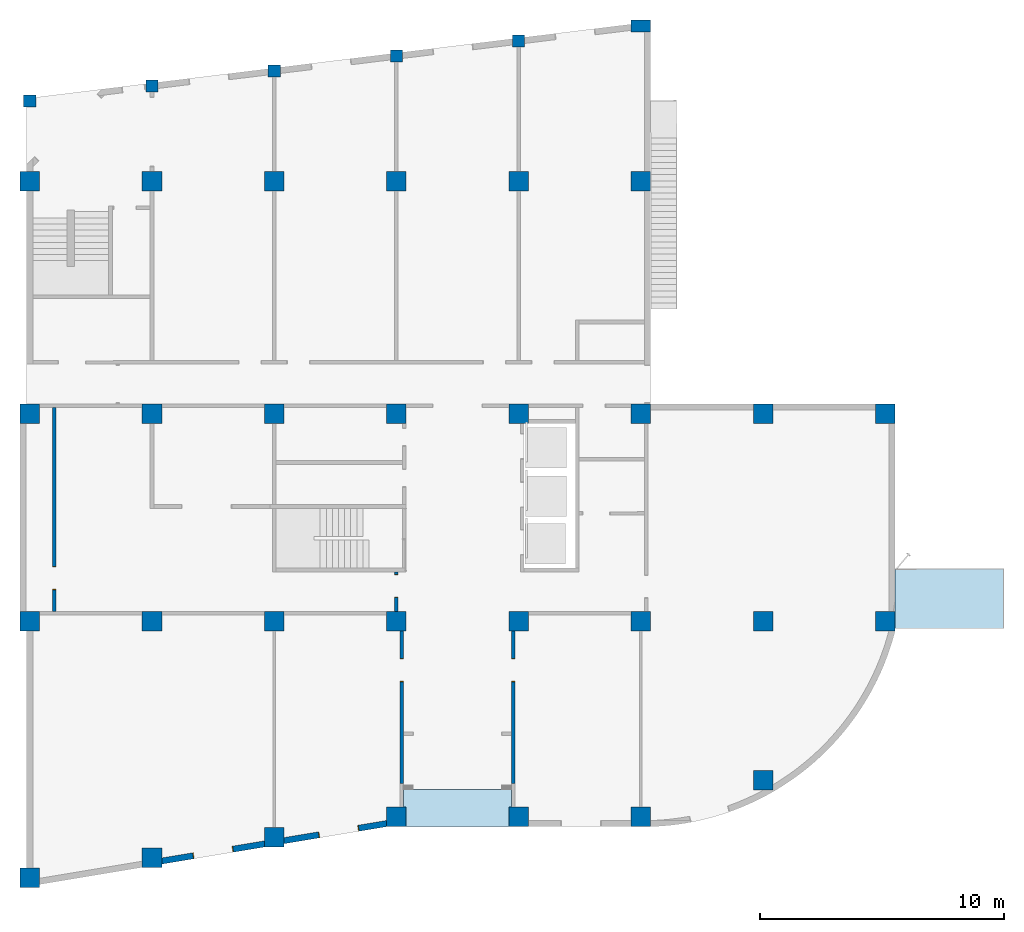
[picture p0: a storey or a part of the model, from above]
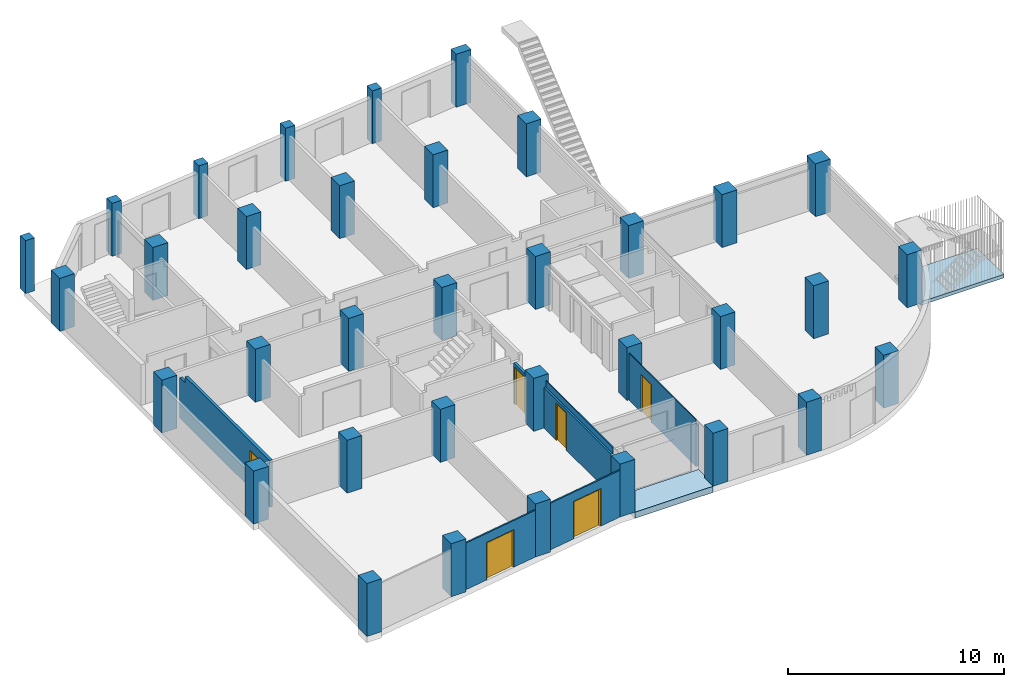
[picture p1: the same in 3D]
Properties of the parts of a building model (IFC2X3), part 1 of 10

# File
Description: ViewDefinition [CoordinationView_V2.0, SurfaceGeometryAddOnView, QuantityTakeOffAddOnView, SpaceBoundary2ndLevelAddOnView], Option [Drawing Scale: 100.000000], Option [Elements to export: Visible elements (on all stories)], Option [Partial Structure Display: Entire Model], Option [IFC Domain: All], Option [Structural Function: All Elements], Option [Convert Grid elements: On], Option [Convert IFC Annotations and ARCHICAD 2D elements: Off], Option [Convert 2D symbols of Doors and Windows: Off], Option [Export geometries that Participates in Collision Detection only: On], Option [Split complex elements: Off], Option [Material Preservation: Explode where necessary], Option [IFC Site Location: At Project Origin], Option [Curtain Wall export mode: Single Element], Option [Railing export mode: Single Element], Option [Stair export mode: Single Element], Option [Properties To Export: All properties], Option [Space containment: On], Option [IFC Domain For Space Containment: Custom], Option [Bounding Box: Off], Option [Geometry to type objects: Off], Option [Element Properties: All], Option [Building Material Properties: Off], Option [Element Parameters: All], Option [Component Parameters: Off], Option [IFC Base Quantities: On], Option [Door Window Parameters: On], Option [IFC Space boundaries: On], Option [ARCHICAD Zone Categories as IFC Space classification data: On], Option [Element Classifications: On]
File name: C:\Users\meije\OneDrive - Graphisoft SE\Desktop\From Home\Solibri Samples\Escape Route\Escape Route.ifc
Time: 2020-05-21T14:10:56
Author: Architect
Organization: Building Designer Office
Written by: The EXPRESS Data Manager Version 5.02.0100.09 : 26 Sep 2013
Made in: IFC file generated by GRAPHISOFT ARCHICAD 23.0.0 JPN FULL Windows version (IFC add-on version: 3003 JPN FULL).
Authorization: The authorising person

# IfcSite, サイト
RefLatitude: 35, 42, 0, 0; RefLongitude: 139, 46, 0, 0; RefElevation: 0 mm
BaseQuantities - GrossPerimeter: 0 mm; GrossArea: 0 m2

# IfcBuilding, 建築
BaseQuantities - GrossFloorArea: 8628.15 m2

# IfcBuildingStorey (10)
In: 建築
Name | Elevation (mm) | NetHeight (mm) = GrossHeight (mm) = Height (mm) | GrossFloorArea (m2)
1FL | 0 | 3000 | 956.464
2FL | 3000 | 3000 | 971.87
3FL | 6000 | 3000 | 957.103
4FL | 9000 | 3000 | 957.119
5FL | 12000 | 3000 | 957.119
6FL | 15000 | 3000 | 957.119
7FL | 18000 | 3000 | 957.119
8FL | 21000 | 3000 | 957.119
9FL | 24000 | 3000 | 957.119
RFL | 27000 | 700 | 0

# IfcSpace: その他-1 (10)
InteriorOrExteriorSpace: INTERNAL; Classification: スペース (ARCHICAD 分類); その他-1 その他-1
Pset_SpaceCommon - Category: その他-1
ArchiCADProperties - レイヤー: ゾーン; ライブラリ部品名: ゾーン_仕上用; 関連ゾーン番号: ＜ゾーン番号＞; 要素タイプ: ゾーン; 材質 (全て): ゾーン - 05; 表面塗りつぶし: 背景; リノベーションフィルタで表示: 全ての関連フィルタ; リノベーションステータス: 既存; 材質: ゾーン - 05; 同一材質: yes; ゾーン番号: ＜ゾーン番号＞; ゾーンカテゴリ: 0; ゾーンカテゴリコード: その他-1; ARCHICAD 分類 - v 2.0: スペース
AC_Pset_ゾーン_仕上用 - マーカーテキスト1サイズ(デフォルト): 2; マーカーテキスト1スタイル(デフォルト): 0; マーカーテキスト1 整列(デフォルト): 1; マーカーテキスト1 改行幅(デフォルト): 0; マーカーテキスト1 文字幅(デフォルト): 1; マーカーテキスト1 テキスト文字間隔(デフォルト): 1; テキストフォント1: Meiryo Japanese; ゾーン番号 (ROOM_NUMBER): ＜ゾーン番号＞; 全コーナー数: 4; 凹型コーナー数: 0; 抽出壁面積: 0; 抽出カーテンウォール面積: 0; 抽出柱面積: 0; 抽出塗りつぶし面積: 0; 抽出床面積: 0; 抽出総面積: 0; ゾーン面積係数: 1; 上部屋根表面積: 0; 下部屋根表面積: 0; 上部スラブ表面積: 0; 下部スラブ表面積: 0; 下部梁表面積: 0; 下部梁表面: 0; 上部壁インセット表面積: 0; 壁インセット背面: 0; 側面壁インセット表面積: 0; 詳細: 1; 固定スタンプ表示 (stChangebyScale): 1：50まで; 固定スタンプ表示 (iChangebyScale): 1; ゾーンスタンプタイプ: 1; 面積値表示: 1; 一行で表示するスケール: 400; 室名: yes; ソーン名文字揃え: 2; 枠線 (bFrameRoomName): no; ゾーン番号 (bZoneNum): no; ゾーン番号タイプ: 1; IDを表示...: 1; 枠線 (bFrameZoneNum): no; 床タイプ: no; 床タイプ名称: ＜フロア タイプ＞; 枠線 (bFrameFloor): no; 面積表示: yes; 平米丸め（小数点）: ２桁; 平米単位表示: 1; 坪表示: no; 坪小数点以下表示: なし; 坪単位表示: 1; 畳表示: no; 帖、Ｊ表示: 帖; 畳単位表示: 1; 帖数小数点: ２桁; 畳係数: 1.62; 枠線 (bFrameArea): no; 外周: no; 枠線 (bFramePeri): no; CH=表示: no; CH=: 2400; 枠線 (bFrameCeil): no; FL又はSL表示: no; FL/SL値: ＋50; FL/SL文字: SL; 枠線 (bFrameFloorlabel): no; スラブ厚: 160; コンクリート天端レベル: ±0; 排煙記号: no; 排煙種類: 未定; 枠線 (bFrameSmokesign): no; 内装制限記号: no; 内装制限種類: 未定; 枠線 (bFrameInterior): no; カテゴリとプロパティを表示: no; 枠線 (bFrameTnC): yes; 枠幅設定: 余白あり; 枠幅桁数: 14; 表示精度: 1; 坪、畳は丸めた平米値で計算する: yes; ------------------: -------------; 角度: 0 deg; 表面塗りつぶし: no; 背景塗つぶしタイプ: 50 %; 表面塗りつぶしペン背景: 透過; 空調タイプ: 日当り空調室; 編集する床の下地を選択: 1; 床＿仕上: 磁器タイル; 床＿下地: RC; 床＿下地2: RC; 床＿下地3: RC; 床＿下地4: RC; 床＿下地5: RC; 巾木: ソフト巾木; 壁仕上げ: 磁器タイル; 編集する壁の下地を選択: 4; 壁＿下地: RC; 壁＿下地2: RC; 壁＿下地3: RC; 壁＿下地4: RC; 壁＿下地5: RC; 天井＿仕上: クロス貼; 編集する天井の下地を選択: 1; 天井＿下地: 軽鉄野縁; 天井＿下地2: 軽鉄野縁; 天井＿下地3: 軽鉄野縁; 天井＿下地4: 軽鉄野縁; 天井＿下地5: 軽鉄野縁; 廻り縁: 廻縁 塩ビ; 面積区分: 1; 面積対象: 1; 換気タイプ: タイプ1; 給気量（A）m3/h: 300; 排気量（B）m3/h: 300; カテゴリ名称: その他-1; 天井高テキスト: 3,000; 床＿下地テキスト: RC/RC/RC/RC/RC; 壁＿下地テキスト: RC/RC/RC/RC/RC; 天井＿下地テキスト: 軽鉄野縁/軽鉄野縁/軽鉄野縁/軽鉄野縁/軽鉄野縁; 巾木高さ値（mm）: 75; パラメータを選択: 1; データを表示: 1; 1. 列 パラメータ名を次のように表示: 1; 2. 列 パラメータ名を次のように表示: 1; 3. 列 パラメータ名を次のように表示: 1; 4. 列 パラメータ名を次のように表示: 1; 5. 列 パラメータ名を次のように表示: 1; 6. 列 パラメータ名を次のように表示: 1; 7. 列 パラメータ名を次のように表示: 1; 8. 列 パラメータ名を次のように表示: 1; 9. 列 パラメータ名を次のように表示: 1; 10. 列 パラメータ名を次のように表示: 1; 11. 列 パラメータ名を次のように表示: 1; 12. 列 パラメータ名を次のように表示: 1; 13. 列 パラメータ名を次のように表示: 1; 14. 列 パラメータ名を次のように表示: 1; 15. 列 パラメータ名を次のように表示: 1; 16. 列 パラメータ名を次のように表示: 1; 17. 列 パラメータ名を次のように表示: 1; 18. 列 パラメータ名を次のように表示: 1; 19. 列 パラメータ名を次のように表示: 1; 20. 列 パラメータ名を次のように表示: 1
室情報 - 利用者数: 0; 一人あたりの必要面積: 0 m2
AC_Pset_RenovationAndPhasing - Renovation Status: Existing
BaseQuantities - Height: 3000 mm; FinishCeilingHeight: 3000 mm; FinishFloorHeight: 0 mm; ClearHeight: 3000 mm
ArchiCADQuantities - 高さ: 3000 mm; リンク/配置フロアまでの高度: 0 mm; 下部オフセット: 0 mm; 上部オフセット: 0 mm; 平面図穴外周: 0 mm; 上端高度から配置フロア: 3000 mm; 下端高度から配置フロア: 0 mm; 基準レベル: 0 mm; 柱数: 0; ランプ数: 0; オブジェクト数: 0; フロア厚さ: 0 mm; 面積縮小: 1 m2; 抜き取られる柱面積: 0 m2; 抜き取られる塗りつぶし面積: 0 m2; 抜き取られる底面積: 0 m2; 抜き取られる壁面積: 0 m2; 全てのへこみ角数: 0; 角数: 4; 抜き取られる総面積: 0 m2; 壁のインセット背面表面積: 0 m2; 壁インセット側面表面積: 0 m2; 壁インセット上部表面積: 0 m2
AC_Equantity_ゾーン_仕上用 - 穴外周: 0 mm; フロアレベル: 0 mm; サブフロア厚さ: 0 mm; 高さ: 3000 mm; 巾木高さ: 75 mm; 腰高: 1000 mm; 平均天井高: 3000 mm
Name | In | LongName = 関連ゾーン名 = ゾーン名 = ゾーン名 (ROOM_NAME) = ゾーン名 (stZoneName) | 要素ID = 親ID | ホットリンクおよび要素ID | ロック状態 | ホームフロア名 | ホームフロア数 | 絶対上部リンクフロア | 相対上部リンクフロア | 上部リンクフロア | 縮小された面積 = AC_Pset_ゾーン_仕上用, 測定正味面積 = 縮小面積 = 計算面積 (ROOM_CALC_AREA) = 上部表面積 = 下部材質面積 = NetFloorArea (m2) = SpaceNetFloorAreaBOMA (m2) = SpaceUsableFloorAreaBOMA (m2) = NetCeilingArea (m2) = 計算した面積 (m2) = ArchiCADQuantities, 測定正味面積 (m2) | AC_Pset_ゾーン_仕上用, 測定面積 = GrossFloorArea (m2) = GrossCeilingArea (m2) = 面積 (m2) = ArchiCADQuantities, 測定面積 (m2) | 外壁表面積 | AC_Pset_ゾーン_仕上用, ドア表面積 = ArchiCADQuantities, ドア表面積 (m2) | AC_Pset_ゾーン_仕上用, 窓表面積 = ArchiCADQuantities, 窓表面積 (m2) | 体積 = 気積 | 境界表面積 | 計算面積 (stAreaDisp) = 面積値 | 換気回数 | 坪 | 畳 | 面積テキスト | 坪テキスト | 畳テキスト | GrossWallArea (m2) | NetWallArea (m2) = 壁表面積 (m2) | GrossPerimeter (mm) = ゾーン総外周 (mm) = 外周 (mm) | NetPerimeter (mm) = ゾーン正味外周 (mm) = 正味外周 (mm) | GrossVolume (m3) | NetVolume (m3) = 正味体積 (m3) | GLからの高度 (mm) = 高度 1 (mm) = 高度 2 (mm) = 海抜までの高度 (mm) = 下端高度から第1基準レベル (mm) = 下端高度から基準レベル (mm) = 下端高度から海抜 (mm) = 下端高度から第2基準レベル (mm) | 上端高度から第1基準レベル (mm) = 上端高度から基準レベル (mm) = 上端高度から海抜 (mm) = 上端高度から第2基準レベル (mm) | 梁数 | ドア数 | 窓数 | 壁部品数 | ドア幅 (mm) = ドア組み合わせ幅 (mm) | 窓幅 (mm) = 窓組み合わせ幅 (mm) | 壁外周 (mm) = 外壁長さ (mm) | 居室に必要な採光面積 (m2) = 病院福祉施設等に必要な採光面積 (m2) | 教育施設に必要な採光面積 (m2) | その他に必要な採光面積 (m2) | 自然排煙必要面積(ゾーン) (m2) | 必要換気量（ゾーン） (m2) | ホットリンク マスタID
＜ゾーン番号＞ | 1FL | 階段室 | Z6 | Z6 | no | 1FL | 1 | 2FL | 配置フロア + 1 | 配置フロア + 1 (2FL) | 12.6788 | 13.845 | 36.371 | 2.52 | 0 | 38.0363 | 45.75 | 13.84 | 7.88721 | 4 | 8.54 | 13.84 ㎡ | 4 坪 | 8.54 帖 | 38.891 | 36.371 | 15850 | 15250 | 41.535 | 38.0363 | 0 | 3000 | 2 | 1 | 0 | 4 | 1200 | 0 | 15250 | 1.97786 | 2.769 | 1.3845 | 0.2769 | 0.69225
＜ゾーン番号＞ | 2FL | 階段室 | Z6 | Z6 | no | 2FL | 2 | 3FL | 配置フロア + 1 | 配置フロア + 1 (3FL) | 12.6788 | 13.845 | 36.6117 | 2.31 | 0 | 38.0363 | 45.75 | 13.84 | 7.88721 | 4 | 8.54 | 13.84 ㎡ | 4 坪 | 8.54 帖 | 38.9217 | 36.6117 | 15850 | 15250 | 41.535 | 38.0362 | 3000 | 6000 | 4 | 1 | 0 | 4 | 1100 | 0 | 15250 | 1.97786 | 2.769 | 1.3845 | 0.2769 | 0.69225
＜ゾーン番号＞ | 2FL | 吹き抜け | Z9 | Z9 | no | 2FL | 2 | 3FL | 配置フロア + 1 | 配置フロア + 1 (3FL) | 25.74 | 26.9588 | 33.809 | 0 | 8.496 | 77.22 | 61.5 | 26.95 | 3.885 | 8 | 16.63 | 26.95 ㎡ | 8 坪 | 16.63 帖 | 42.305 | 33.809 | 20950 | 20500 | 80.8763 | 77.22 | 3000 | 6000 | 0 | 0 | 1 | 3 | 0 | 3540 | 16100 | 3.85125 | 5.39175 | 2.69588 | 0.539175 | 1.34794
＜ゾーン番号＞ | 3FL | 階段室 | Z6 | Z6 | no | 3FL | 3 | 4FL | 配置フロア + 1 | 配置フロア + 1 (4FL) | 12.6788 | 13.845 | 40.6192 | 2.31 | 0 | 38.0363 | 45.75 | 13.84 | 7.88721 | 4 | 8.54 | 13.84 ㎡ | 4 坪 | 8.54 帖 | 38.9217 | 36.6117 | 15850 | 15250 | 41.535 | 38.0362 | 6000 | 9000 | 2 | 1 | 0 | 4 | 1100 | 0 | 15250 | 1.97786 | 2.769 | 1.3845 | 0.2769 | 0.69225
＜ゾーン番号＞ | 4FL | 階段室 | Z6 | 4FLZ6 | yes | 4FL | 4 | リンクなし | リンクなし | リンクなし | 12.6788 | 13.845 | 40.6192 | 2.31 | 0 | 38.0363 | 45.75 | 13.84 | 7.88721 | 4 | 8.54 | 13.84 ㎡ | 4 坪 | 8.54 帖 | 38.9217 | 36.6117 | 15850 | 15250 | 41.535 | 38.0362 | 9000 | 12000 | 2 | 1 | 0 | 4 | 1100 | 0 | 15250 | 1.97786 | 2.769 | 1.3845 | 0.2769 | 0.69225 | 4FL
＜ゾーン番号＞ | 5FL | 階段室 | Z6 | 5FLZ6 | yes | 5FL | 5 | リンクなし | リンクなし | リンクなし | 12.6788 | 13.845 | 40.6192 | 2.31 | 0 | 38.0363 | 45.75 | 13.84 | 7.88721 | 4 | 8.54 | 13.84 ㎡ | 4 坪 | 8.54 帖 | 38.9217 | 36.6117 | 15850 | 15250 | 41.535 | 38.0362 | 12000 | 15000 | 2 | 1 | 0 | 4 | 1100 | 0 | 15250 | 1.97786 | 2.769 | 1.3845 | 0.2769 | 0.69225 | 5FL
＜ゾーン番号＞ | 6FL | 階段室 | Z6 | 6FLZ6 | yes | 6FL | 6 | リンクなし | リンクなし | リンクなし | 12.6788 | 13.845 | 40.6192 | 2.31 | 0 | 38.0363 | 45.75 | 13.84 | 7.88721 | 4 | 8.54 | 13.84 ㎡ | 4 坪 | 8.54 帖 | 38.9217 | 36.6117 | 15850 | 15250 | 41.535 | 38.0362 | 15000 | 18000 | 2 | 1 | 0 | 4 | 1100 | 0 | 15250 | 1.97786 | 2.769 | 1.3845 | 0.2769 | 0.69225 | 6FL
＜ゾーン番号＞ | 7FL | 階段室 | Z6 | 7FLZ6 | yes | 7FL | 7 | リンクなし | リンクなし | リンクなし | 12.6788 | 13.845 | 40.6192 | 2.31 | 0 | 38.0363 | 45.75 | 13.84 | 7.88721 | 4 | 8.54 | 13.84 ㎡ | 4 坪 | 8.54 帖 | 38.9217 | 36.6117 | 15850 | 15250 | 41.535 | 38.0362 | 18000 | 21000 | 2 | 1 | 0 | 4 | 1100 | 0 | 15250 | 1.97786 | 2.769 | 1.3845 | 0.2769 | 0.69225 | 7FL
＜ゾーン番号＞ | 8FL | 階段室 | Z6 | 8FLZ6 | yes | 8FL | 8 | リンクなし | リンクなし | リンクなし | 12.6788 | 13.845 | 40.6192 | 2.31 | 0 | 38.0363 | 45.75 | 13.84 | 7.88721 | 4 | 8.54 | 13.84 ㎡ | 4 坪 | 8.54 帖 | 38.9217 | 36.6117 | 15850 | 15250 | 41.535 | 38.0362 | 21000 | 24000 | 2 | 1 | 0 | 4 | 1100 | 0 | 15250 | 1.97786 | 2.769 | 1.3845 | 0.2769 | 0.69225 | 8FL
＜ゾーン番号＞ | 9FL | 階段室 | Z6 | 9FLZ6 | yes | 9FL | 9 | リンクなし | リンクなし | リンクなし | 12.6788 | 13.845 | 40.6192 | 2.31 | 0 | 38.0363 | 45.75 | 13.84 | 7.88721 | 4 | 8.54 | 13.84 ㎡ | 4 坪 | 8.54 帖 | 38.9217 | 36.6117 | 15850 | 15250 | 41.535 | 38.0362 | 24000 | 27000 | 2 | 1 | 0 | 4 | 1100 | 0 | 15250 | 1.97786 | 2.769 | 1.3845 | 0.2769 | 0.69225 | 9FL

# IfcSpace: その他-2 (31)
InteriorOrExteriorSpace: INTERNAL; Classification: スペース (ARCHICAD 分類); その他-2 その他-2
Pset_SpaceCommon - Category: その他-2
ArchiCADProperties - レイヤー: ゾーン; ライブラリ部品名: ゾーン_仕上用; 関連ゾーン番号: ＜ゾーン番号＞; 要素タイプ: ゾーン; 材質 (全て): ゾーン - 05; 表面塗りつぶし: 背景; リノベーションフィルタで表示: 全ての関連フィルタ; リノベーションステータス: 既存; 材質: ゾーン - 05; 同一材質: yes; ゾーン番号: ＜ゾーン番号＞; ゾーンカテゴリ: 0; ゾーンカテゴリコード: その他-2; ARCHICAD 分類 - v 2.0: スペース
AC_Pset_ゾーン_仕上用 - マーカーテキスト1サイズ(デフォルト): 2; マーカーテキスト1スタイル(デフォルト): 0; マーカーテキスト1 整列(デフォルト): 1; マーカーテキスト1 改行幅(デフォルト): 0; マーカーテキスト1 文字幅(デフォルト): 1; マーカーテキスト1 テキスト文字間隔(デフォルト): 1; テキストフォント1: Meiryo Japanese; ゾーン番号 (ROOM_NUMBER): ＜ゾーン番号＞; 窓表面積: 0; 抽出壁面積: 0; 抽出カーテンウォール面積: 0; 抽出柱面積: 0; 抽出塗りつぶし面積: 0; 抽出床面積: 0; 抽出総面積: 0; ゾーン面積係数: 1; 上部屋根表面積: 0; 下部屋根表面積: 0; 上部スラブ表面積: 0; 下部スラブ表面積: 0; 下部梁表面積: 0; 下部梁表面: 0; 上部壁インセット表面積: 0; 壁インセット背面: 0; 側面壁インセット表面積: 0; 詳細: 1; 固定スタンプ表示 (stChangebyScale): 1：50まで; 固定スタンプ表示 (iChangebyScale): 1; ゾーンスタンプタイプ: 1; 面積値表示: 1; 一行で表示するスケール: 400; 室名: yes; ソーン名文字揃え: 2; 枠線 (bFrameRoomName): no; ゾーン番号 (bZoneNum): no; ゾーン番号タイプ: 1; IDを表示...: 1; 枠線 (bFrameZoneNum): no; 床タイプ: no; 床タイプ名称: ＜フロア タイプ＞; 枠線 (bFrameFloor): no; 面積表示: yes; 平米丸め（小数点）: ２桁; 平米単位表示: 1; 坪表示: no; 坪小数点以下表示: なし; 坪単位表示: 1; 畳表示: no; 帖、Ｊ表示: 帖; 畳単位表示: 1; 帖数小数点: ２桁; 畳係数: 1.62; 枠線 (bFrameArea): no; 外周: no; 枠線 (bFramePeri): no; CH=表示: no; CH=: 2400; 枠線 (bFrameCeil): no; FL又はSL表示: no; FL/SL値: ＋50; FL/SL文字: SL; 枠線 (bFrameFloorlabel): no; スラブ厚: 160; コンクリート天端レベル: ±0; 排煙記号: no; 排煙種類: 未定; 枠線 (bFrameSmokesign): no; 内装制限記号: no; 内装制限種類: 未定; 枠線 (bFrameInterior): no; カテゴリとプロパティを表示: no; 枠線 (bFrameTnC): yes; 枠幅設定: 余白あり; 枠幅桁数: 14; 表示精度: 1; 坪、畳は丸めた平米値で計算する: yes; ------------------: -------------; 角度: 0 deg; 表面塗りつぶし: no; 背景塗つぶしタイプ: 50 %; 表面塗りつぶしペン背景: 透過; 空調タイプ: 日当り空調室; 編集する床の下地を選択: 1; 床＿仕上: 磁器タイル; 床＿下地: RC; 床＿下地2: RC; 床＿下地3: RC; 床＿下地4: RC; 床＿下地5: RC; 巾木: ソフト巾木; 壁仕上げ: 磁器タイル; 編集する壁の下地を選択: 4; 壁＿下地: RC; 壁＿下地2: RC; 壁＿下地3: RC; 壁＿下地4: RC; 壁＿下地5: RC; 天井＿仕上: クロス貼; 編集する天井の下地を選択: 1; 天井＿下地: 軽鉄野縁; 天井＿下地2: 軽鉄野縁; 天井＿下地3: 軽鉄野縁; 天井＿下地4: 軽鉄野縁; 天井＿下地5: 軽鉄野縁; 廻り縁: 廻縁 塩ビ; 面積区分: 1; 面積対象: 1; 換気タイプ: タイプ1; 給気量（A）m3/h: 300; 排気量（B）m3/h: 300; 天井高テキスト: 3,000; 床＿下地テキスト: RC/RC/RC/RC/RC; 壁＿下地テキスト: RC/RC/RC/RC/RC; 天井＿下地テキスト: 軽鉄野縁/軽鉄野縁/軽鉄野縁/軽鉄野縁/軽鉄野縁; 巾木高さ値（mm）: 75; パラメータを選択: 1; データを表示: 1; 1. 列 パラメータ名を次のように表示: 1; 2. 列 パラメータ名を次のように表示: 1; 3. 列 パラメータ名を次のように表示: 1; 4. 列 パラメータ名を次のように表示: 1; 5. 列 パラメータ名を次のように表示: 1; 6. 列 パラメータ名を次のように表示: 1; 7. 列 パラメータ名を次のように表示: 1; 8. 列 パラメータ名を次のように表示: 1; 9. 列 パラメータ名を次のように表示: 1; 10. 列 パラメータ名を次のように表示: 1; 11. 列 パラメータ名を次のように表示: 1; 12. 列 パラメータ名を次のように表示: 1; 13. 列 パラメータ名を次のように表示: 1; 14. 列 パラメータ名を次のように表示: 1; 15. 列 パラメータ名を次のように表示: 1; 16. 列 パラメータ名を次のように表示: 1; 17. 列 パラメータ名を次のように表示: 1; 18. 列 パラメータ名を次のように表示: 1; 19. 列 パラメータ名を次のように表示: 1; 20. 列 パラメータ名を次のように表示: 1
室情報 - 利用者数: 0; 一人あたりの必要面積: 0 m2
AC_Pset_RenovationAndPhasing - Renovation Status: Existing
BaseQuantities - Height: 3000 mm; FinishCeilingHeight: 3000 mm; FinishFloorHeight: 0 mm; ClearHeight: 3000 mm
ArchiCADQuantities - 高さ: 3000 mm; リンク/配置フロアまでの高度: 0 mm; 下部オフセット: 0 mm; 上部オフセット: 0 mm; 平面図穴外周: 0 mm; 上端高度から配置フロア: 3000 mm; 下端高度から配置フロア: 0 mm; 基準レベル: 0 mm; ランプ数: 0; 窓数: 0; 窓表面積: 0 m2; 窓幅: 0 mm; フロア厚さ: 0 mm; 面積縮小: 1 m2; 抜き取られる柱面積: 0 m2; 抜き取られる塗りつぶし面積: 0 m2; 抜き取られる底面積: 0 m2; 抜き取られる壁面積: 0 m2; 抜き取られる総面積: 0 m2; 壁のインセット背面表面積: 0 m2; 壁インセット側面表面積: 0 m2; 壁インセット上部表面積: 0 m2
AC_Equantity_ゾーン_仕上用 - 穴外周: 0 mm; 窓組み合わせ幅: 0 mm; フロアレベル: 0 mm; サブフロア厚さ: 0 mm; 高さ: 3000 mm; 巾木高さ: 75 mm; 腰高: 1000 mm; 平均天井高: 3000 mm
Name | In | LongName = 関連ゾーン名 = ゾーン名 = ゾーン名 (ROOM_NAME) = ゾーン名 (stZoneName) | 要素ID = 親ID | ホットリンクおよび要素ID | ロック状態 | ホームフロア名 | ホームフロア数 | 絶対上部リンクフロア | 相対上部リンクフロア | 上部リンクフロア | 縮小された面積 = AC_Pset_ゾーン_仕上用, 測定正味面積 = 縮小面積 = 計算面積 (ROOM_CALC_AREA) = 上部表面積 = 下部材質面積 = NetFloorArea (m2) = SpaceNetFloorAreaBOMA (m2) = SpaceUsableFloorAreaBOMA (m2) = NetCeilingArea (m2) = 計算した面積 (m2) = ArchiCADQuantities, 測定正味面積 (m2) | AC_Pset_ゾーン_仕上用, 測定面積 = GrossFloorArea (m2) = GrossCeilingArea (m2) = 面積 (m2) = ArchiCADQuantities, 測定面積 (m2) | 全コーナー数 = 角数 | 凹型コーナー数 = 全てのへこみ角数 | 外壁表面積 | AC_Pset_ゾーン_仕上用, ドア表面積 | 体積 = 気積 = NetVolume (m3) = 正味体積 (m3) | 境界表面積 | 計算面積 (stAreaDisp) | 換気回数 | カテゴリ名称 | 面積値 | 坪 | 畳 | 面積テキスト | 坪テキスト | 畳テキスト | GrossWallArea (m2) | NetWallArea (m2) = 壁表面積 (m2) | GrossPerimeter (mm) = ゾーン総外周 (mm) = 外周 (mm) | NetPerimeter (mm) = ゾーン正味外周 (mm) = 正味外周 (mm) | GrossVolume (m3) | GLからの高度 (mm) = 高度 1 (mm) = 高度 2 (mm) = 海抜までの高度 (mm) = 下端高度から第1基準レベル (mm) = 下端高度から基準レベル (mm) = 下端高度から海抜 (mm) = 下端高度から第2基準レベル (mm) | 上端高度から第1基準レベル (mm) = 上端高度から基準レベル (mm) = 上端高度から海抜 (mm) = 上端高度から第2基準レベル (mm) | 梁数 | 柱数 | ドア数 | オブジェクト数 | 壁部品数 | ArchiCADQuantities, ドア表面積 (m2) | ドア幅 (mm) | 壁外周 (mm) = 外壁長さ (mm) | ドア組み合わせ幅 (mm) | 居室に必要な採光面積 (m2) = 病院福祉施設等に必要な採光面積 (m2) | 教育施設に必要な採光面積 (m2) | その他に必要な採光面積 (m2) | 自然排煙必要面積(ゾーン) (m2) | 必要換気量（ゾーン） (m2) | ホットリンク マスタID
＜ゾーン番号＞ | 1FL | PS | Z5 | Z5 | no | 1FL | 1 | 2FL | 配置フロア + 1 | 配置フロア + 1 (2FL) | 5.48375 | 6.215 | 4 | 0 | 21.0575 | 0 | 16.4513 | 28.35 | 6.21 | 18.2357 | その他-2 | 6.21 | 1 | 3.83 | 6.21 ㎡ | 1 坪 | 3.83 帖 | 20.9027 | 19.0127 | 10050 | 9450 | 18.645 | 0 | 3000 | 4 | 1 | 1 | 0 | 4 | 1.89 | 900 | 9450 | 0 | 0.887857 | 1.243 | 0.6215 | 0.1243 | 0.31075
＜ゾーン番号＞ | 1FL | 管理室 | Z5 | Z5 | no | 1FL | 1 | 2FL | 配置フロア + 1 | 配置フロア + 1 (2FL) | 18.8563 | 20.625 | 8 | 2 | 34.7672 | 4.2 | 56.5688 | 52.95 | 20.62 | 5.30328 | その他-2 | 20.62 | 6 | 12.72 | 20.62 ㎡ | 6 坪 | 12.72 帖 | 38.9672 | 34.7672 | 18250 | 17650 | 61.875 | 0 | 3000 | 3 | 2 | 1 | 0 | 4 | 4.2 | 2000 | 15700 | 2000 | 2.94643 | 4.125 | 2.0625 | 0.4125 | 1.03125
＜ゾーン番号＞ | 1FL | DS | Z5 | Z5 | no | 1FL | 1 | 2FL | 配置フロア + 1 | 配置フロア + 1 (2FL) | 1.05 | 1.4625 | 4 | 0 | 11.3525 | 0 | 3.15 | 15.6 | 1.46 | 95.2381 | その他-2 | 1.46 | 0 | 0.9 | 1.46 ㎡ | 0 坪 | 0.90 帖 | 11.3525 | 11.3525 | 5800 | 5200 | 4.3875 | 0 | 3000 | 3 | 0 | 0 | 0 | 4 | 0 | 0 | 5200 | 0 | 0.208929 | 0.2925 | 0.14625 | 0.02925 | 0.073125
＜ゾーン番号＞ | 1FL | PS | Z3 | Z3 | no | 1FL | 1 | 2FL | 配置フロア + 1 | 配置フロア + 1 (2FL) | 8.61875 | 10.8375 | 6 | 1 | 40.4002 | 1.89 | 25.8562 | 56.55 | 10.83 | 11.6026 | その他-2 | 10.83 | 3 | 6.68 | 10.83 ㎡ | 3 坪 | 6.68 帖 | 42.2902 | 40.4002 | 19550 | 18850 | 32.5125 | 0 | 3000 | 2 | 2 | 1 | 1 | 4 | 1.89 | 900 | 17650 | 900 | 1.54821 | 2.1675 | 1.08375 | 0.21675 | 0.541875
＜ゾーン番号＞ | 1FL | DS | Z5 | Z5 | no | 1FL | 1 | 2FL | 配置フロア + 1 | 配置フロア + 1 (2FL) | 4.0125 | 4.74375 | 4 | 0 | 21.3225 | 0 | 12.0375 | 25.05 | 4.74 | 24.9221 | その他-2 | 4.74 | 1 | 2.92 | 4.74 ㎡ | 1 坪 | 2.92 帖 | 21.3225 | 21.3225 | 9050 | 8350 | 14.2313 | 0 | 3000 | 1 | 0 | 0 | 0 | 4 | 0 | 0 | 8350 | 0 | 0.677679 | 0.94875 | 0.474375 | 0.094875 | 0.237188
＜ゾーン番号＞ | 1FL | ゴミ置き場 | Z3 | Z3 | no | 1FL | 1 | 2FL | 配置フロア + 1 | 配置フロア + 1 (2FL) | 12.1561 | 13.4126 | 4 | 0 | 32.0126 | 2.31 | 36.4683 | 43.9951 | 13.41 | 8.22631 | その他-2 | 13.41 | 4 | 8.27 | 13.41 ㎡ | 4 坪 | 8.27 帖 | 34.3226 | 32.0126 | 15365 | 14665 | 40.2379 | 0 | 3000 | 2 | 0 | 1 | 0 | 4 | 2.31 | 1100 | 14665 | 1100 | 1.91609 | 2.68252 | 1.34126 | 0.268252 | 0.670631
＜ゾーン番号＞ | 1FL | 収納 | Z5 | Z5 | no | 1FL | 1 | 2FL | 配置フロア + 1 | 配置フロア + 1 (2FL) | 5.41334 | 6.19221 | 4 | 0 | 23.3355 | 1.89 | 16.24 | 30.2549 | 6.19 | 18.4729 | その他-2 | 6.19 | 1 | 3.82 | 6.19 ㎡ | 1 坪 | 3.82 帖 | 25.2255 | 23.3355 | 10685 | 10085 | 18.5766 | 0 | 3000 | 1 | 0 | 1 | 0 | 4 | 1.89 | 900 | 10085 | 900 | 0.884601 | 1.23844 | 0.619221 | 0.123844 | 0.30961
＜ゾーン番号＞ | 2FL | DS | Z5 | Z5 | no | 2FL | 2 | 3FL | 配置フロア + 1 | 配置フロア + 1 (3FL) | 4.34687 | 5.10312 | 4 | 0 | 20.6237 | 0 | 13.0406 | 25.8 | 5.10 | 23.005 | その他-2 | 5.1 | 1 | 3.14 | 5.10 ㎡ | 1 坪 | 3.14 帖 | 20.6237 | 20.6237 | 9300 | 8600 | 15.3094 | 3000 | 6000 | 2 | 1 | 0 | 0 | 4 | 0 | 0 | 8600 | 0 | 0.729018 | 1.02062 | 0.510312 | 0.102062 | 0.255156
＜ゾーン番号＞ | 2FL | DS | Z5 | Z5 | no | 2FL | 2 | 3FL | 配置フロア + 1 | 配置フロア + 1 (3FL) | 1.05 | 1.4625 | 4 | 0 | 11.3525 | 0 | 3.15 | 15.6 | 1.46 | 95.2381 | その他-2 | 1.46 | 0 | 0.9 | 1.46 ㎡ | 0 坪 | 0.90 帖 | 11.3525 | 11.3525 | 5800 | 5200 | 4.3875 | 3000 | 6000 | 6 | 0 | 0 | 0 | 4 | 0 | 0 | 5200 | 0 | 0.208929 | 0.2925 | 0.14625 | 0.02925 | 0.073125
＜ゾーン番号＞ | 2FL | PS | Z5 | Z5 | no | 2FL | 2 | 3FL | 配置フロア + 1 | 配置フロア + 1 (3FL) | 5.12625 | 6.215 | 6 | 1 | 21.0575 | 0 | 15.3788 | 28.35 | 6.21 | 19.5074 |  | 6.21 | 1 | 3.83 | 6.21 ㎡ | 1 坪 | 3.83 帖 | 21.0575 | 21.0575 | 10050 | 9450 | 18.645 | 3000 | 6000 | 4 | 1 | 0 | 0 | 4 | 0 | 0 | 8250 | 0 | 0.887857 | 1.243 | 0.6215 | 0.1243 | 0.31075
＜ゾーン番号＞ | 3FL | DS | Z5 | Z5 | no | 3FL | 3 | 4FL | 配置フロア + 1 | 配置フロア + 1 (4FL) | 4.34687 | 5.10312 | 4 | 0 | 22.7325 | 0 | 13.0406 | 25.8 | 5.10 | 23.005 | その他-2 | 5.1 | 1 | 3.14 | 5.10 ㎡ | 1 坪 | 3.14 帖 | 20.6237 | 20.6237 | 9300 | 8600 | 15.3094 | 6000 | 9000 | 1 | 1 | 0 | 0 | 4 | 0 | 0 | 8600 | 0 | 0.729018 | 1.02062 | 0.510312 | 0.102062 | 0.255156
＜ゾーン番号＞ | 3FL | PS | Z5 | Z5 | no | 3FL | 3 | 4FL | 配置フロア + 1 | 配置フロア + 1 (4FL) | 5.12625 | 6.215 | 6 | 1 | 23.14 | 0 | 15.3788 | 28.35 | 6.21 | 19.5074 | その他-2 | 6.21 | 1 | 3.83 | 6.21 ㎡ | 1 坪 | 3.83 帖 | 21.0575 | 21.0575 | 10050 | 9450 | 18.645 | 6000 | 9000 | 2 | 1 | 0 | 0 | 4 | 0 | 0 | 8250 | 0 | 0.887857 | 1.243 | 0.6215 | 0.1243 | 0.31075
＜ゾーン番号＞ | 3FL | DS | Z5 | Z5 | no | 3FL | 3 | 4FL | 配置フロア + 1 | 配置フロア + 1 (4FL) | 0.9625 | 1.4625 | 4 | 0 | 12.7 | 0 | 2.8875 | 14.55 | 1.46 | 103.896 | その他-2 | 1.46 | 0 | 0.9 | 1.46 ㎡ | 0 坪 | 0.90 帖 | 11.3525 | 11.3525 | 5800 | 4850 | 4.3875 | 6000 | 9000 | 1 | 0 | 0 | 0 | 3 | 0 | 0 | 4350 | 0 | 0.208929 | 0.2925 | 0.14625 | 0.02925 | 0.073125
＜ゾーン番号＞ | 4FL | DS | Z5 | 4FLZ5 | yes | 4FL | 4 | リンクなし | リンクなし | リンクなし | 0.9625 | 1.4625 | 4 | 0 | 12.7 | 0 | 2.8875 | 14.55 | 1.46 | 103.896 | その他-2 | 1.46 | 0 | 0.9 | 1.46 ㎡ | 0 坪 | 0.90 帖 | 11.3525 | 11.3525 | 5800 | 4850 | 4.3875 | 9000 | 12000 | 1 | 0 | 0 | 0 | 3 | 0 | 0 | 4350 | 0 | 0.208929 | 0.2925 | 0.14625 | 0.02925 | 0.073125 | 4FL
＜ゾーン番号＞ | 4FL | PS | Z5 | 4FLZ5 | yes | 4FL | 4 | リンクなし | リンクなし | リンクなし | 5.12625 | 6.215 | 6 | 1 | 23.14 | 0 | 15.3788 | 28.35 | 6.21 | 19.5074 | その他-2 | 6.21 | 1 | 3.83 | 6.21 ㎡ | 1 坪 | 3.83 帖 | 21.0575 | 21.0575 | 10050 | 9450 | 18.645 | 9000 | 12000 | 2 | 1 | 0 | 0 | 4 | 0 | 0 | 8250 | 0 | 0.887857 | 1.243 | 0.6215 | 0.1243 | 0.31075 | 4FL
＜ゾーン番号＞ | 4FL | DS | Z5 | 4FLZ5 | yes | 4FL | 4 | リンクなし | リンクなし | リンクなし | 4.34687 | 5.10312 | 4 | 0 | 22.7325 | 0 | 13.0406 | 25.8 | 5.10 | 23.005 | その他-2 | 5.1 | 1 | 3.14 | 5.10 ㎡ | 1 坪 | 3.14 帖 | 20.6237 | 20.6237 | 9300 | 8600 | 15.3094 | 9000 | 12000 | 1 | 1 | 0 | 0 | 4 | 0 | 0 | 8600 | 0 | 0.729018 | 1.02062 | 0.510312 | 0.102062 | 0.255156 | 4FL
＜ゾーン番号＞ | 5FL | DS | Z5 | 5FLZ5 | yes | 5FL | 5 | リンクなし | リンクなし | リンクなし | 0.9625 | 1.4625 | 4 | 0 | 12.7 | 0 | 2.8875 | 14.55 | 1.46 | 103.896 | その他-2 | 1.46 | 0 | 0.9 | 1.46 ㎡ | 0 坪 | 0.90 帖 | 11.3525 | 11.3525 | 5800 | 4850 | 4.3875 | 12000 | 15000 | 1 | 0 | 0 | 0 | 3 | 0 | 0 | 4350 | 0 | 0.208929 | 0.2925 | 0.14625 | 0.02925 | 0.073125 | 5FL
＜ゾーン番号＞ | 5FL | PS | Z5 | 5FLZ5 | yes | 5FL | 5 | リンクなし | リンクなし | リンクなし | 5.12625 | 6.215 | 6 | 1 | 23.14 | 0 | 15.3788 | 28.35 | 6.21 | 19.5074 | その他-2 | 6.21 | 1 | 3.83 | 6.21 ㎡ | 1 坪 | 3.83 帖 | 21.0575 | 21.0575 | 10050 | 9450 | 18.645 | 12000 | 15000 | 2 | 1 | 0 | 0 | 4 | 0 | 0 | 8250 | 0 | 0.887857 | 1.243 | 0.6215 | 0.1243 | 0.31075 | 5FL
＜ゾーン番号＞ | 5FL | DS | Z5 | 5FLZ5 | yes | 5FL | 5 | リンクなし | リンクなし | リンクなし | 4.34687 | 5.10312 | 4 | 0 | 22.7325 | 0 | 13.0406 | 25.8 | 5.10 | 23.005 | その他-2 | 5.1 | 1 | 3.14 | 5.10 ㎡ | 1 坪 | 3.14 帖 | 20.6237 | 20.6237 | 9300 | 8600 | 15.3094 | 12000 | 15000 | 1 | 1 | 0 | 0 | 4 | 0 | 0 | 8600 | 0 | 0.729018 | 1.02062 | 0.510312 | 0.102062 | 0.255156 | 5FL
＜ゾーン番号＞ | 6FL | DS | Z5 | 6FLZ5 | yes | 6FL | 6 | リンクなし | リンクなし | リンクなし | 0.9625 | 1.4625 | 4 | 0 | 12.7 | 0 | 2.8875 | 14.55 | 1.46 | 103.896 | その他-2 | 1.46 | 0 | 0.9 | 1.46 ㎡ | 0 坪 | 0.90 帖 | 11.3525 | 11.3525 | 5800 | 4850 | 4.3875 | 15000 | 18000 | 1 | 0 | 0 | 0 | 3 | 0 | 0 | 4350 | 0 | 0.208929 | 0.2925 | 0.14625 | 0.02925 | 0.073125 | 6FL
＜ゾーン番号＞ | 6FL | PS | Z5 | 6FLZ5 | yes | 6FL | 6 | リンクなし | リンクなし | リンクなし | 5.12625 | 6.215 | 6 | 1 | 23.14 | 0 | 15.3788 | 28.35 | 6.21 | 19.5074 | その他-2 | 6.21 | 1 | 3.83 | 6.21 ㎡ | 1 坪 | 3.83 帖 | 21.0575 | 21.0575 | 10050 | 9450 | 18.645 | 15000 | 18000 | 2 | 1 | 0 | 0 | 4 | 0 | 0 | 8250 | 0 | 0.887857 | 1.243 | 0.6215 | 0.1243 | 0.31075 | 6FL
＜ゾーン番号＞ | 6FL | DS | Z5 | 6FLZ5 | yes | 6FL | 6 | リンクなし | リンクなし | リンクなし | 4.34687 | 5.10312 | 4 | 0 | 22.7325 | 0 | 13.0406 | 25.8 | 5.10 | 23.005 | その他-2 | 5.1 | 1 | 3.14 | 5.10 ㎡ | 1 坪 | 3.14 帖 | 20.6237 | 20.6237 | 9300 | 8600 | 15.3094 | 15000 | 18000 | 1 | 1 | 0 | 0 | 4 | 0 | 0 | 8600 | 0 | 0.729018 | 1.02062 | 0.510312 | 0.102062 | 0.255156 | 6FL
＜ゾーン番号＞ | 7FL | DS | Z5 | 7FLZ5 | yes | 7FL | 7 | リンクなし | リンクなし | リンクなし | 0.9625 | 1.4625 | 4 | 0 | 12.7 | 0 | 2.8875 | 14.55 | 1.46 | 103.896 | その他-2 | 1.46 | 0 | 0.9 | 1.46 ㎡ | 0 坪 | 0.90 帖 | 11.3525 | 11.3525 | 5800 | 4850 | 4.3875 | 18000 | 21000 | 1 | 0 | 0 | 0 | 3 | 0 | 0 | 4350 | 0 | 0.208929 | 0.2925 | 0.14625 | 0.02925 | 0.073125 | 7FL
＜ゾーン番号＞ | 7FL | PS | Z5 | 7FLZ5 | yes | 7FL | 7 | リンクなし | リンクなし | リンクなし | 5.12625 | 6.215 | 6 | 1 | 23.14 | 0 | 15.3788 | 28.35 | 6.21 | 19.5074 | その他-2 | 6.21 | 1 | 3.83 | 6.21 ㎡ | 1 坪 | 3.83 帖 | 21.0575 | 21.0575 | 10050 | 9450 | 18.645 | 18000 | 21000 | 2 | 1 | 0 | 0 | 4 | 0 | 0 | 8250 | 0 | 0.887857 | 1.243 | 0.6215 | 0.1243 | 0.31075 | 7FL
＜ゾーン番号＞ | 7FL | DS | Z5 | 7FLZ5 | yes | 7FL | 7 | リンクなし | リンクなし | リンクなし | 4.34687 | 5.10312 | 4 | 0 | 22.7325 | 0 | 13.0406 | 25.8 | 5.10 | 23.005 | その他-2 | 5.1 | 1 | 3.14 | 5.10 ㎡ | 1 坪 | 3.14 帖 | 20.6237 | 20.6237 | 9300 | 8600 | 15.3094 | 18000 | 21000 | 1 | 1 | 0 | 0 | 4 | 0 | 0 | 8600 | 0 | 0.729018 | 1.02062 | 0.510312 | 0.102062 | 0.255156 | 7FL
＜ゾーン番号＞ | 8FL | DS | Z5 | 8FLZ5 | yes | 8FL | 8 | リンクなし | リンクなし | リンクなし | 0.9625 | 1.4625 | 4 | 0 | 12.7 | 0 | 2.8875 | 14.55 | 1.46 | 103.896 | その他-2 | 1.46 | 0 | 0.9 | 1.46 ㎡ | 0 坪 | 0.90 帖 | 11.3525 | 11.3525 | 5800 | 4850 | 4.3875 | 21000 | 24000 | 1 | 0 | 0 | 0 | 3 | 0 | 0 | 4350 | 0 | 0.208929 | 0.2925 | 0.14625 | 0.02925 | 0.073125 | 8FL
＜ゾーン番号＞ | 8FL | PS | Z5 | 8FLZ5 | yes | 8FL | 8 | リンクなし | リンクなし | リンクなし | 5.12625 | 6.215 | 6 | 1 | 23.14 | 0 | 15.3788 | 28.35 | 6.21 | 19.5074 | その他-2 | 6.21 | 1 | 3.83 | 6.21 ㎡ | 1 坪 | 3.83 帖 | 21.0575 | 21.0575 | 10050 | 9450 | 18.645 | 21000 | 24000 | 2 | 1 | 0 | 0 | 4 | 0 | 0 | 8250 | 0 | 0.887857 | 1.243 | 0.6215 | 0.1243 | 0.31075 | 8FL
＜ゾーン番号＞ | 8FL | DS | Z5 | 8FLZ5 | yes | 8FL | 8 | リンクなし | リンクなし | リンクなし | 4.34687 | 5.10312 | 4 | 0 | 22.7325 | 0 | 13.0406 | 25.8 | 5.10 | 23.005 | その他-2 | 5.1 | 1 | 3.14 | 5.10 ㎡ | 1 坪 | 3.14 帖 | 20.6237 | 20.6237 | 9300 | 8600 | 15.3094 | 21000 | 24000 | 1 | 1 | 0 | 0 | 4 | 0 | 0 | 8600 | 0 | 0.729018 | 1.02062 | 0.510312 | 0.102062 | 0.255156 | 8FL
＜ゾーン番号＞ | 9FL | DS | Z5 | 9FLZ5 | yes | 9FL | 9 | リンクなし | リンクなし | リンクなし | 0.9625 | 1.4625 | 4 | 0 | 12.7 | 0 | 2.8875 | 14.55 | 1.46 | 103.896 | その他-2 | 1.46 | 0 | 0.9 | 1.46 ㎡ | 0 坪 | 0.90 帖 | 11.3525 | 11.3525 | 5800 | 4850 | 4.3875 | 24000 | 27000 | 1 | 0 | 0 | 0 | 3 | 0 | 0 | 4350 | 0 | 0.208929 | 0.2925 | 0.14625 | 0.02925 | 0.073125 | 9FL
＜ゾーン番号＞ | 9FL | PS | Z5 | 9FLZ5 | yes | 9FL | 9 | リンクなし | リンクなし | リンクなし | 5.12625 | 6.215 | 6 | 1 | 23.14 | 0 | 15.3788 | 28.35 | 6.21 | 19.5074 | その他-2 | 6.21 | 1 | 3.83 | 6.21 ㎡ | 1 坪 | 3.83 帖 | 21.0575 | 21.0575 | 10050 | 9450 | 18.645 | 24000 | 27000 | 2 | 1 | 0 | 0 | 4 | 0 | 0 | 8250 | 0 | 0.887857 | 1.243 | 0.6215 | 0.1243 | 0.31075 | 9FL
＜ゾーン番号＞ | 9FL | DS | Z5 | 9FLZ5 | yes | 9FL | 9 | リンクなし | リンクなし | リンクなし | 4.34687 | 5.10312 | 4 | 0 | 22.7325 | 0 | 13.0406 | 25.8 | 5.10 | 23.005 | その他-2 | 5.1 | 1 | 3.14 | 5.10 ㎡ | 1 坪 | 3.14 帖 | 20.6237 | 20.6237 | 9300 | 8600 | 15.3094 | 24000 | 27000 | 1 | 1 | 0 | 0 | 4 | 0 | 0 | 8600 | 0 | 0.729018 | 1.02062 | 0.510312 | 0.102062 | 0.255156 | 9FL

# IfcSpace: その他-3 (11)
InteriorOrExteriorSpace: INTERNAL; Classification: スペース (ARCHICAD 分類); その他-3 その他-3
Pset_SpaceCommon - Category: その他-3
ArchiCADProperties - レイヤー: ゾーン; ライブラリ部品名: ゾーン_仕上用; 関連ゾーン番号: ＜ゾーン番号＞; 要素タイプ: ゾーン; 材質 (全て): ゾーン - 05; 表面塗りつぶし: 背景; リノベーションフィルタで表示: 全ての関連フィルタ; リノベーションステータス: 既存; 材質: ゾーン - 05; 同一材質: yes; ゾーン番号: ＜ゾーン番号＞; ゾーンカテゴリ: 0; ゾーンカテゴリコード: その他-3; ARCHICAD 分類 - v 2.0: スペース
AC_Pset_ゾーン_仕上用 - マーカーテキスト1サイズ(デフォルト): 2; マーカーテキスト1スタイル(デフォルト): 0; マーカーテキスト1 整列(デフォルト): 1; マーカーテキスト1 改行幅(デフォルト): 0; マーカーテキスト1 文字幅(デフォルト): 1; マーカーテキスト1 テキスト文字間隔(デフォルト): 1; テキストフォント1: Meiryo Japanese; ゾーン番号 (ROOM_NUMBER): ＜ゾーン番号＞; 全コーナー数: 4; 凹型コーナー数: 0; 窓表面積: 0; 抽出壁面積: 0; 抽出カーテンウォール面積: 0; 抽出柱面積: 0; 抽出塗りつぶし面積: 0; 抽出床面積: 0; 抽出総面積: 0; ゾーン面積係数: 1; 上部屋根表面積: 0; 下部屋根表面積: 0; 上部スラブ表面積: 0; 下部スラブ表面積: 0; 下部梁表面積: 0; 下部梁表面: 0; 上部壁インセット表面積: 0; 壁インセット背面: 0; 側面壁インセット表面積: 0; 詳細: 1; 固定スタンプ表示 (stChangebyScale): 1：50まで; 固定スタンプ表示 (iChangebyScale): 1; ゾーンスタンプタイプ: 1; 面積値表示: 1; 一行で表示するスケール: 400; 室名: yes; ソーン名文字揃え: 2; 枠線 (bFrameRoomName): no; ゾーン番号 (bZoneNum): no; ゾーン番号タイプ: 1; IDを表示...: 1; 枠線 (bFrameZoneNum): no; 床タイプ: no; 床タイプ名称: ＜フロア タイプ＞; 枠線 (bFrameFloor): no; 面積表示: yes; 平米丸め（小数点）: ２桁; 平米単位表示: 1; 坪表示: no; 坪小数点以下表示: なし; 坪単位表示: 1; 畳表示: no; 帖、Ｊ表示: 帖; 畳単位表示: 1; 帖数小数点: ２桁; 畳係数: 1.62; 枠線 (bFrameArea): no; 外周: no; 枠線 (bFramePeri): no; CH=表示: no; CH=: 2400; 枠線 (bFrameCeil): no; FL又はSL表示: no; FL/SL値: ＋50; FL/SL文字: SL; 枠線 (bFrameFloorlabel): no; スラブ厚: 160; コンクリート天端レベル: ±0; 排煙記号: no; 排煙種類: 未定; 枠線 (bFrameSmokesign): no; 内装制限記号: no; 内装制限種類: 未定; 枠線 (bFrameInterior): no; カテゴリとプロパティを表示: no; 枠線 (bFrameTnC): yes; 枠幅設定: 余白あり; 枠幅桁数: 14; 表示精度: 1; 坪、畳は丸めた平米値で計算する: yes; ------------------: -------------; 角度: 0 deg; 表面塗りつぶし: no; 背景塗つぶしタイプ: 50 %; 表面塗りつぶしペン背景: 透過; 空調タイプ: 日当り空調室; 編集する床の下地を選択: 1; 床＿仕上: 磁器タイル; 床＿下地: RC; 床＿下地2: RC; 床＿下地3: RC; 床＿下地4: RC; 床＿下地5: RC; 巾木: ソフト巾木; 壁仕上げ: 磁器タイル; 編集する壁の下地を選択: 4; 壁＿下地: RC; 壁＿下地2: RC; 壁＿下地3: RC; 壁＿下地4: RC; 壁＿下地5: RC; 天井＿仕上: クロス貼; 編集する天井の下地を選択: 1; 天井＿下地: 軽鉄野縁; 天井＿下地2: 軽鉄野縁; 天井＿下地3: 軽鉄野縁; 天井＿下地4: 軽鉄野縁; 天井＿下地5: 軽鉄野縁; 廻り縁: 廻縁 塩ビ; 面積区分: 1; 面積対象: 1; 換気タイプ: タイプ1; 給気量（A）m3/h: 300; 排気量（B）m3/h: 300; カテゴリ名称: その他-3; 天井高テキスト: 3,000; 床＿下地テキスト: RC/RC/RC/RC/RC; 壁＿下地テキスト: RC/RC/RC/RC/RC; 天井＿下地テキスト: 軽鉄野縁/軽鉄野縁/軽鉄野縁/軽鉄野縁/軽鉄野縁; 巾木高さ値（mm）: 75; パラメータを選択: 1; データを表示: 1; 1. 列 パラメータ名を次のように表示: 1; 2. 列 パラメータ名を次のように表示: 1; 3. 列 パラメータ名を次のように表示: 1; 4. 列 パラメータ名を次のように表示: 1; 5. 列 パラメータ名を次のように表示: 1; 6. 列 パラメータ名を次のように表示: 1; 7. 列 パラメータ名を次のように表示: 1; 8. 列 パラメータ名を次のように表示: 1; 9. 列 パラメータ名を次のように表示: 1; 10. 列 パラメータ名を次のように表示: 1; 11. 列 パラメータ名を次のように表示: 1; 12. 列 パラメータ名を次のように表示: 1; 13. 列 パラメータ名を次のように表示: 1; 14. 列 パラメータ名を次のように表示: 1; 15. 列 パラメータ名を次のように表示: 1; 16. 列 パラメータ名を次のように表示: 1; 17. 列 パラメータ名を次のように表示: 1; 18. 列 パラメータ名を次のように表示: 1; 19. 列 パラメータ名を次のように表示: 1; 20. 列 パラメータ名を次のように表示: 1
室情報 - 利用者数: 0; 一人あたりの必要面積: 0 m2
AC_Pset_RenovationAndPhasing - Renovation Status: Existing
BaseQuantities - Height: 3000 mm; FinishCeilingHeight: 3000 mm; FinishFloorHeight: 0 mm; ClearHeight: 3000 mm
ArchiCADQuantities - 高さ: 3000 mm; リンク/配置フロアまでの高度: 0 mm; 下部オフセット: 0 mm; 上部オフセット: 0 mm; 平面図穴外周: 0 mm; 上端高度から配置フロア: 3000 mm; 下端高度から配置フロア: 0 mm; 基準レベル: 0 mm; ランプ数: 0; 窓数: 0; 壁部品数: 4; 窓表面積: 0 m2; 窓幅: 0 mm; フロア厚さ: 0 mm; 面積縮小: 1 m2; 抜き取られる柱面積: 0 m2; 抜き取られる塗りつぶし面積: 0 m2; 抜き取られる底面積: 0 m2; 抜き取られる壁面積: 0 m2; 全てのへこみ角数: 0; 角数: 4; 抜き取られる総面積: 0 m2; 壁のインセット背面表面積: 0 m2; 壁インセット側面表面積: 0 m2; 壁インセット上部表面積: 0 m2
AC_Equantity_ゾーン_仕上用 - 穴外周: 0 mm; 窓組み合わせ幅: 0 mm; フロアレベル: 0 mm; サブフロア厚さ: 0 mm; 高さ: 3000 mm; 巾木高さ: 75 mm; 腰高: 1000 mm; 平均天井高: 3000 mm
Name | In | LongName = 関連ゾーン名 = ゾーン名 = ゾーン名 (ROOM_NAME) = ゾーン名 (stZoneName) | 要素ID = 親ID | ホットリンクおよび要素ID | ロック状態 | ホームフロア名 | ホームフロア数 | 絶対上部リンクフロア | 相対上部リンクフロア | 上部リンクフロア | 縮小された面積 = AC_Pset_ゾーン_仕上用, 測定正味面積 = 縮小面積 = 計算面積 (ROOM_CALC_AREA) = 上部表面積 = 下部材質面積 = NetFloorArea (m2) = SpaceNetFloorAreaBOMA (m2) = SpaceUsableFloorAreaBOMA (m2) = NetCeilingArea (m2) = 計算した面積 (m2) = ArchiCADQuantities, 測定正味面積 (m2) | AC_Pset_ゾーン_仕上用, 測定面積 = GrossFloorArea (m2) = GrossCeilingArea (m2) = 面積 (m2) = ArchiCADQuantities, 測定面積 (m2) | 外壁表面積 | AC_Pset_ゾーン_仕上用, ドア表面積 = ArchiCADQuantities, ドア表面積 (m2) | 体積 = 気積 = NetVolume (m3) = 正味体積 (m3) | 境界表面積 | 計算面積 (stAreaDisp) | 換気回数 | 面積値 | 坪 | 畳 | 面積テキスト | 坪テキスト | 畳テキスト | GrossWallArea (m2) | NetWallArea (m2) = 壁表面積 (m2) | GrossPerimeter (mm) = ゾーン総外周 (mm) = 外周 (mm) | NetPerimeter (mm) = 壁外周 (mm) = ゾーン正味外周 (mm) = 外壁長さ (mm) = 正味外周 (mm) | GrossVolume (m3) | GLからの高度 (mm) = 高度 1 (mm) = 高度 2 (mm) = 海抜までの高度 (mm) = 下端高度から第1基準レベル (mm) = 下端高度から基準レベル (mm) = 下端高度から海抜 (mm) = 下端高度から第2基準レベル (mm) | 上端高度から第1基準レベル (mm) = 上端高度から基準レベル (mm) = 上端高度から海抜 (mm) = 上端高度から第2基準レベル (mm) | 梁数 | 柱数 | ドア数 | オブジェクト数 | ドア幅 (mm) = ドア組み合わせ幅 (mm) | 居室に必要な採光面積 (m2) = 病院福祉施設等に必要な採光面積 (m2) | 教育施設に必要な採光面積 (m2) | その他に必要な採光面積 (m2) | 自然排煙必要面積(ゾーン) (m2) | 必要換気量（ゾーン） (m2) | ホットリンク マスタID
＜ゾーン番号＞ | 1FL | EVシャフト | Z7 | Z7 | no | 1FL | 1 | 2FL | 配置フロア + 1 | 配置フロア + 1 (2FL) | 12.4425 | 13.6687 | 33.2128 | 6.3 | 37.3275 | 48.15 | 13.66 | 8.03697 | 13.66 | 4 | 8.43 | 13.66 ㎡ | 4 坪 | 8.43 帖 | 39.5128 | 33.2128 | 16650 | 16050 | 41.0062 | 0 | 3000 | 1 | 1 | 3 | 3 | 3000 | 1.95268 | 2.73375 | 1.36687 | 0.273375 | 0.683437
＜ゾーン番号＞ | 1FL | 風除室 | Z7 | Z7 | no | 1FL | 1 | 2FL | 配置フロア + 1 | 配置フロア + 1 (2FL) | 9.02 | 10.01 | 16.6902 | 17.28 | 27.06 | 38.7 | 10.01 | 11.0865 | 10.01 | 3 | 6.17 | 10.01 ㎡ | 3 坪 | 6.17 帖 | 33.9702 | 16.6902 | 13500 | 12900 | 30.03 | 0 | 3000 | 0 | 0 | 2 | 0 | 7200 | 1.43 | 2.002 | 1.001 | 0.2002 | 0.5005
＜ゾーン番号＞ | 2FL | 機械室 | Z4 | Z4 | no | 2FL | 2 | 3FL | 配置フロア + 1 | 配置フロア + 1 (3FL) | 13.3533 | 14.7098 | 33.8699 | 2.94 | 40.06 | 44.4451 | 14.70 | 7.48877 | 14.7 | 4 | 9.07 | 14.70 ㎡ | 4 坪 | 9.07 帖 | 36.8099 | 33.8699 | 15515 | 14815 | 44.1295 | 3000 | 6000 | 2 | 1 | 1 | 0 | 1400 | 2.1014 | 2.94197 | 1.47098 | 0.294197 | 0.735491
＜ゾーン番号＞ | 2FL | EVシャフト | Z7 | Z7 | no | 2FL | 2 | 3FL | 配置フロア + 1 | 配置フロア + 1 (3FL) | 12.4425 | 13.6687 | 33.2128 | 6.3 | 37.3275 | 48.15 | 13.66 | 8.03697 | 13.66 | 4 | 8.43 | 13.66 ㎡ | 4 坪 | 8.43 帖 | 39.5128 | 33.2128 | 16650 | 16050 | 41.0062 | 3000 | 6000 | 2 | 1 | 3 | 0 | 3000 | 1.95268 | 2.73375 | 1.36687 | 0.273375 | 0.683437
＜ゾーン番号＞ | 3FL | EVシャフト | Z7 | Z7 | no | 3FL | 3 | 4FL | 配置フロア + 1 | 配置フロア + 1 (4FL) | 12.4425 | 13.6687 | 36.6866 | 6.3 | 37.3275 | 48.15 | 13.66 | 8.03697 | 13.66 | 4 | 8.43 | 13.66 ㎡ | 4 坪 | 8.43 帖 | 39.5128 | 33.2128 | 16650 | 16050 | 41.0062 | 6000 | 9000 | 1 | 1 | 3 | 0 | 3000 | 1.95268 | 2.73375 | 1.36687 | 0.273375 | 0.683437
＜ゾーン番号＞ | 4FL | EVシャフト | Z7 | 4FLZ7 | yes | 4FL | 4 | リンクなし | リンクなし | リンクなし | 12.4425 | 13.6687 | 36.6866 | 6.3 | 37.3275 | 48.15 | 13.66 | 8.03697 | 13.66 | 4 | 8.43 | 13.66 ㎡ | 4 坪 | 8.43 帖 | 39.5128 | 33.2128 | 16650 | 16050 | 41.0062 | 9000 | 12000 | 1 | 1 | 3 | 0 | 3000 | 1.95268 | 2.73375 | 1.36687 | 0.273375 | 0.683437 | 4FL
＜ゾーン番号＞ | 5FL | EVシャフト | Z7 | 5FLZ7 | yes | 5FL | 5 | リンクなし | リンクなし | リンクなし | 12.4425 | 13.6687 | 36.6866 | 6.3 | 37.3275 | 48.15 | 13.66 | 8.03697 | 13.66 | 4 | 8.43 | 13.66 ㎡ | 4 坪 | 8.43 帖 | 39.5128 | 33.2128 | 16650 | 16050 | 41.0062 | 12000 | 15000 | 1 | 1 | 3 | 0 | 3000 | 1.95268 | 2.73375 | 1.36687 | 0.273375 | 0.683437 | 5FL
＜ゾーン番号＞ | 6FL | EVシャフト | Z7 | 6FLZ7 | yes | 6FL | 6 | リンクなし | リンクなし | リンクなし | 12.4425 | 13.6687 | 36.6866 | 6.3 | 37.3275 | 48.15 | 13.66 | 8.03697 | 13.66 | 4 | 8.43 | 13.66 ㎡ | 4 坪 | 8.43 帖 | 39.5128 | 33.2128 | 16650 | 16050 | 41.0062 | 15000 | 18000 | 1 | 1 | 3 | 0 | 3000 | 1.95268 | 2.73375 | 1.36687 | 0.273375 | 0.683437 | 6FL
＜ゾーン番号＞ | 7FL | EVシャフト | Z7 | 7FLZ7 | yes | 7FL | 7 | リンクなし | リンクなし | リンクなし | 12.4425 | 13.6687 | 36.6866 | 6.3 | 37.3275 | 48.15 | 13.66 | 8.03697 | 13.66 | 4 | 8.43 | 13.66 ㎡ | 4 坪 | 8.43 帖 | 39.5128 | 33.2128 | 16650 | 16050 | 41.0062 | 18000 | 21000 | 1 | 1 | 3 | 0 | 3000 | 1.95268 | 2.73375 | 1.36687 | 0.273375 | 0.683437 | 7FL
＜ゾーン番号＞ | 8FL | EVシャフト | Z7 | 8FLZ7 | yes | 8FL | 8 | リンクなし | リンクなし | リンクなし | 12.4425 | 13.6687 | 36.6866 | 6.3 | 37.3275 | 48.15 | 13.66 | 8.03697 | 13.66 | 4 | 8.43 | 13.66 ㎡ | 4 坪 | 8.43 帖 | 39.5128 | 33.2128 | 16650 | 16050 | 41.0062 | 21000 | 24000 | 1 | 1 | 3 | 0 | 3000 | 1.95268 | 2.73375 | 1.36687 | 0.273375 | 0.683437 | 8FL
＜ゾーン番号＞ | 9FL | EVシャフト | Z7 | 9FLZ7 | yes | 9FL | 9 | リンクなし | リンクなし | リンクなし | 12.4425 | 13.6687 | 36.6866 | 6.3 | 37.3275 | 48.15 | 13.66 | 8.03697 | 13.66 | 4 | 8.43 | 13.66 ㎡ | 4 坪 | 8.43 帖 | 39.5128 | 33.2128 | 16650 | 16050 | 41.0062 | 24000 | 27000 | 1 | 1 | 3 | 0 | 3000 | 1.95268 | 2.73375 | 1.36687 | 0.273375 | 0.683437 | 9FL

# IfcSpace: 事務所-1 (112)
LongName: 事務室; InteriorOrExteriorSpace: INTERNAL; Classification: スペース (ARCHICAD 分類); 事務所-1 事務所-1
Pset_SpaceCommon - Category: 事務所-1
ArchiCADProperties - レイヤー: ゾーン; ライブラリ部品名: ゾーン_仕上用; 関連ゾーン名: 事務室; 要素タイプ: ゾーン; 材質 (全て): ゾーン - 05; 表面塗りつぶし: 背景; リノベーションフィルタで表示: 全ての関連フィルタ; リノベーションステータス: 既存; 材質: ゾーン - 05; 同一材質: yes; ゾーン名: 事務室; ゾーンカテゴリ: 0; ゾーンカテゴリコード: 事務所-1; ARCHICAD 分類 - v 2.0: スペース
AC_Pset_ゾーン_仕上用 - マーカーテキスト1サイズ(デフォルト): 2; マーカーテキスト1スタイル(デフォルト): 0; マーカーテキスト1 整列(デフォルト): 1; マーカーテキスト1 改行幅(デフォルト): 0; マーカーテキスト1 文字幅(デフォルト): 1; マーカーテキスト1 テキスト文字間隔(デフォルト): 1; テキストフォント1: Meiryo Japanese; ゾーン名 (ROOM_NAME): 事務室; 窓表面積: 0; 抽出壁面積: 0; 抽出カーテンウォール面積: 0; 抽出柱面積: 0; 抽出塗りつぶし面積: 0; 抽出床面積: 0; 抽出総面積: 0; ゾーン面積係数: 1; 上部屋根表面積: 0; 下部屋根表面積: 0; 上部スラブ表面積: 0; 下部スラブ表面積: 0; 下部梁表面積: 0; 下部梁表面: 0; 上部壁インセット表面積: 0; 壁インセット背面: 0; 側面壁インセット表面積: 0; 詳細: 1; 固定スタンプ表示 (stChangebyScale): 1：50まで; 固定スタンプ表示 (iChangebyScale): 1; ゾーンスタンプタイプ: 1; 面積値表示: 1; 一行で表示するスケール: 400; 室名: yes; ソーン名文字揃え: 2; 枠線 (bFrameRoomName): no; ゾーン番号 (bZoneNum): no; ゾーン番号タイプ: 1; IDを表示...: 1; 枠線 (bFrameZoneNum): no; 床タイプ: no; 床タイプ名称: ＜フロア タイプ＞; 枠線 (bFrameFloor): no; 面積表示: yes; 平米丸め（小数点）: ２桁; 平米単位表示: 1; 坪表示: no; 坪小数点以下表示: なし; 坪単位表示: 1; 畳表示: no; 帖、Ｊ表示: 帖; 畳単位表示: 1; 帖数小数点: ２桁; 畳係数: 1.62; 枠線 (bFrameArea): no; 外周: no; 枠線 (bFramePeri): no; CH=表示: no; CH=: 2400; 枠線 (bFrameCeil): no; FL又はSL表示: no; FL/SL値: ＋50; FL/SL文字: SL; 枠線 (bFrameFloorlabel): no; スラブ厚: 160; コンクリート天端レベル: ±0; 排煙記号: no; 排煙種類: 未定; 枠線 (bFrameSmokesign): no; 内装制限記号: no; 内装制限種類: 未定; 枠線 (bFrameInterior): no; カテゴリとプロパティを表示: no; 枠線 (bFrameTnC): yes; 枠幅設定: 余白あり; 枠幅桁数: 14; 表示精度: 1; 坪、畳は丸めた平米値で計算する: yes; ------------------: -------------; 角度: 0 deg; 表面塗りつぶし: no; 背景塗つぶしタイプ: 50 %; 表面塗りつぶしペン背景: 透過; 空調タイプ: 日当り空調室; 編集する床の下地を選択: 1; 床＿仕上: 磁器タイル; 床＿下地: RC; 床＿下地2: RC; 床＿下地3: RC; 床＿下地4: RC; 床＿下地5: RC; 巾木: ソフト巾木; 壁仕上げ: 磁器タイル; 編集する壁の下地を選択: 4; 壁＿下地: RC; 壁＿下地2: RC; 壁＿下地3: RC; 壁＿下地4: RC; 壁＿下地5: RC; 天井＿仕上: クロス貼; 編集する天井の下地を選択: 1; 天井＿下地: 軽鉄野縁; 天井＿下地2: 軽鉄野縁; 天井＿下地3: 軽鉄野縁; 天井＿下地4: 軽鉄野縁; 天井＿下地5: 軽鉄野縁; 廻り縁: 廻縁 塩ビ; 面積区分: 1; 面積対象: 1; 換気タイプ: タイプ1; 給気量（A）m3/h: 300; 排気量（B）m3/h: 300; カテゴリ名称: 事務所-1; ゾーン名 (stZoneName): 事務室; 天井高テキスト: 3,000; 床＿下地テキスト: RC/RC/RC/RC/RC; 壁＿下地テキスト: RC/RC/RC/RC/RC; 天井＿下地テキスト: 軽鉄野縁/軽鉄野縁/軽鉄野縁/軽鉄野縁/軽鉄野縁; 巾木高さ値（mm）: 75; パラメータを選択: 1; データを表示: 1; 1. 列 パラメータ名を次のように表示: 1; 2. 列 パラメータ名を次のように表示: 1; 3. 列 パラメータ名を次のように表示: 1; 4. 列 パラメータ名を次のように表示: 1; 5. 列 パラメータ名を次のように表示: 1; 6. 列 パラメータ名を次のように表示: 1; 7. 列 パラメータ名を次のように表示: 1; 8. 列 パラメータ名を次のように表示: 1; 9. 列 パラメータ名を次のように表示: 1; 10. 列 パラメータ名を次のように表示: 1; 11. 列 パラメータ名を次のように表示: 1; 12. 列 パラメータ名を次のように表示: 1; 13. 列 パラメータ名を次のように表示: 1; 14. 列 パラメータ名を次のように表示: 1; 15. 列 パラメータ名を次のように表示: 1; 16. 列 パラメータ名を次のように表示: 1; 17. 列 パラメータ名を次のように表示: 1; 18. 列 パラメータ名を次のように表示: 1; 19. 列 パラメータ名を次のように表示: 1; 20. 列 パラメータ名を次のように表示: 1
室情報 - 利用者数: 0; 一人あたりの必要面積: 0 m2
AC_Pset_RenovationAndPhasing - Renovation Status: Existing
BaseQuantities - Height: 3000 mm; FinishCeilingHeight: 3000 mm; FinishFloorHeight: 0 mm; ClearHeight: 3000 mm
ArchiCADQuantities - 高さ: 3000 mm; リンク/配置フロアまでの高度: 0 mm; 下部オフセット: 0 mm; 上部オフセット: 0 mm; 上端高度から配置フロア: 3000 mm; 下端高度から配置フロア: 0 mm; 基準レベル: 0 mm; ドア数: 1; ランプ数: 0; オブジェクト数: 0; 窓数: 0; 窓表面積: 0 m2; 窓幅: 0 mm; フロア厚さ: 0 mm; 面積縮小: 1 m2; 抜き取られる柱面積: 0 m2; 抜き取られる塗りつぶし面積: 0 m2; 抜き取られる底面積: 0 m2; 抜き取られる壁面積: 0 m2; 抜き取られる総面積: 0 m2; 壁のインセット背面表面積: 0 m2; 壁インセット側面表面積: 0 m2; 壁インセット上部表面積: 0 m2
AC_Equantity_ゾーン_仕上用 - 窓組み合わせ幅: 0 mm; フロアレベル: 0 mm; サブフロア厚さ: 0 mm; 高さ: 3000 mm; 巾木高さ: 75 mm; 腰高: 1000 mm; 平均天井高: 3000 mm
Name | In | 要素ID = 親ID | ホットリンクおよび要素ID | 関連ゾーン番号 = ゾーン番号 = ゾーン番号 (ROOM_NUMBER) | ロック状態 | ホームフロア名 | ホームフロア数 | 絶対上部リンクフロア | 相対上部リンクフロア | 上部リンクフロア | 縮小された面積 = AC_Pset_ゾーン_仕上用, 測定正味面積 = 縮小面積 = 計算面積 (ROOM_CALC_AREA) = 上部表面積 = 下部材質面積 = NetFloorArea (m2) = SpaceNetFloorAreaBOMA (m2) = SpaceUsableFloorAreaBOMA (m2) = NetCeilingArea (m2) = 計算した面積 (m2) = ArchiCADQuantities, 測定正味面積 (m2) | AC_Pset_ゾーン_仕上用, 測定面積 = GrossFloorArea (m2) = GrossCeilingArea (m2) = 面積 (m2) = ArchiCADQuantities, 測定面積 (m2) | 全コーナー数 = 角数 | 凹型コーナー数 = 全てのへこみ角数 | 外壁表面積 | AC_Pset_ゾーン_仕上用, ドア表面積 = ArchiCADQuantities, ドア表面積 (m2) | 体積 = 気積 = NetVolume (m3) = 正味体積 (m3) | 境界表面積 | 計算面積 (stAreaDisp) | 換気回数 | 面積値 | 坪 | 畳 | 面積テキスト | 坪テキスト | 畳テキスト | GrossWallArea (m2) | NetWallArea (m2) = 壁表面積 (m2) | GrossPerimeter (mm) = ゾーン総外周 (mm) = 外周 (mm) | NetPerimeter (mm) = ゾーン正味外周 (mm) = 正味外周 (mm) | GrossVolume (m3) | GLからの高度 (mm) = 高度 1 (mm) = 高度 2 (mm) = 海抜までの高度 (mm) = 下端高度から第1基準レベル (mm) = 下端高度から基準レベル (mm) = 下端高度から海抜 (mm) = 下端高度から第2基準レベル (mm) | 平面図穴外周 (mm) = 穴外周 (mm) | 上端高度から第1基準レベル (mm) = 上端高度から基準レベル (mm) = 上端高度から海抜 (mm) = 上端高度から第2基準レベル (mm) | 梁数 | 柱数 | 壁部品数 | ドア幅 (mm) = ドア組み合わせ幅 (mm) | 壁外周 (mm) = 外壁長さ (mm) | 居室に必要な採光面積 (m2) = 病院福祉施設等に必要な採光面積 (m2) | 教育施設に必要な採光面積 (m2) | その他に必要な採光面積 (m2) | 自然排煙必要面積(ゾーン) (m2) | 必要換気量（ゾーン） (m2) | ホットリンク マスタID
301 | 3FL | Z7 | Z7 | 301 | no | 3FL | 3 | 4FL | 配置フロア + 1 | 配置フロア + 1 (4FL) | 72.8869 | 75.4638 | 21 | 9 | 35.8465 | 1.89 | 218.661 | 120.589 | 75.46 | 1.37199 | 75.46 | 22 | 46.58 | 75.46 ㎡ | 22 坪 | 46.58 帖 | 35.7126 | 33.8226 | 36446.5 | 40196.5 | 226.391 | 6000 | 3200 | 9000 | 4 | 4 | 6 | 900 | 14949.3 | 10.7805 | 15.0928 | 7.54638 | 1.50928 | 3.77319
302 | 3FL | Z8 | Z8 | 302 | no | 3FL | 3 | 4FL | 配置フロア + 1 | 配置フロア + 1 (4FL) | 55.0265 | 57.5599 | 17 | 7 | 58.7694 | 1.89 | 165.079 | 102.746 | 57.55 | 1.81731 | 57.55 | 17 | 35.52 | 57.55 ㎡ | 17 坪 | 35.52 帖 | 58.1167 | 56.2267 | 33108.8 | 34248.7 | 172.68 | 6000 | 0 | 9000 | 4 | 4 | 6 | 900 | 24214.7 | 8.22285 | 11.512 | 5.75599 | 1.1512 | 2.878
303 | 3FL | Z9 | Z9 | 303 | no | 3FL | 3 | 4FL | 配置フロア + 1 | 配置フロア + 1 (4FL) | 50.4956 | 52.9366 | 17 | 7 | 54.3881 | 1.89 | 151.487 | 97.198 | 52.93 | 1.98037 | 52.93 | 16 | 32.67 | 52.93 ㎡ | 16 坪 | 32.67 帖 | 53.7994 | 51.9094 | 31259.4 | 32399.3 | 158.81 | 6000 | 0 | 9000 | 4 | 4 | 6 | 900 | 22365.4 | 7.56238 | 10.5873 | 5.29366 | 1.05873 | 2.64683
304 | 3FL | Z0 | Z0 | 304 | no | 3FL | 3 | 4FL | 配置フロア + 1 | 配置フロア + 1 (4FL) | 48.23 | 50.625 | 16 | 6 | 52.0752 | 1.89 | 144.69 | 93.9 | 50.62 | 2.0734 | 50.62 | 15 | 31.24 | 50.62 ㎡ | 15 坪 | 31.24 帖 | 51.5152 | 49.6252 | 30250 | 31300 | 151.875 | 6000 | 0 | 9000 | 4 | 4 | 5 | 900 | 21400 | 7.23214 | 10.125 | 5.0625 | 1.0125 | 2.53125
305 | 3FL | Z1 | Z1 | 305 | no | 3FL | 3 | 4FL | 配置フロア + 1 | 配置フロア + 1 (4FL) | 48.23 | 50.625 | 16 | 6 | 52.0752 | 1.89 | 144.69 | 93.9 | 50.62 | 2.0734 | 50.62 | 15 | 31.24 | 50.62 ㎡ | 15 坪 | 31.24 帖 | 51.5152 | 49.6252 | 30249.9 | 31300 | 151.875 | 6000 | 0 | 9000 | 4 | 4 | 5 | 900 | 21400 | 7.23214 | 10.125 | 5.0625 | 1.0125 | 2.53125
306 | 3FL | Z2 | Z2 | 306 | no | 3FL | 3 | 4FL | 配置フロア + 1 | 配置フロア + 1 (4FL) | 46.5147 | 48.8562 | 22 | 7 | 49.9183 | 1.89 | 139.544 | 91.3613 | 48.85 | 2.14986 | 48.85 | 14 | 30.15 | 48.85 ㎡ | 14 坪 | 30.15 帖 | 49.2074 | 47.3174 | 29329 | 30453.8 | 146.569 | 6000 | 0 | 9000 | 4 | 4 | 6 | 900 | 20366.8 | 6.97946 | 9.77125 | 4.88562 | 0.977125 | 2.44281
307 | 3FL | Z3 | Z3 | 307 | no | 3FL | 3 | 4FL | 配置フロア + 1 | 配置フロア + 1 (4FL) | 39.5698 | 41.3599 | 26 | 5 | 29.0713 | 1.89 | 118.709 | 84.5199 | 41.35 | 2.52718 | 41.35 | 12 | 25.52 | 41.35 ㎡ | 12 坪 | 25.52 帖 | 28.8606 | 26.9706 | 27752.9 | 28173.3 | 124.08 | 6000 | 0 | 9000 | 2 | 3 | 5 | 900 | 11952 | 5.90855 | 8.27197 | 4.13599 | 0.827197 | 2.06799
308 | 3FL | Z4 | Z4 | 308 | no | 3FL | 3 | 4FL | 配置フロア + 1 | 配置フロア + 1 (4FL) | 32.5275 | 35.2106 | 8 | 2 | 49.7502 | 1.89 | 97.5825 | 69.45 | 35.21 | 3.07432 | 35.21 | 10 | 21.73 | 35.21 ㎡ | 10 坪 | 21.73 帖 | 50.0652 | 48.1752 | 23900 | 23150 | 105.632 | 6000 | 0 | 9000 | 3 | 2 | 4 | 900 | 21150 | 5.03009 | 7.04212 | 3.52106 | 0.704212 | 1.76053
309 | 3FL | Z5 | Z5 | 309 | no | 3FL | 3 | 4FL | 配置フロア + 1 | 配置フロア + 1 (4FL) | 29.8613 | 31.8756 | 8 | 2 | 52.8277 | 1.89 | 89.5838 | 66.75 | 31.87 | 3.34882 | 31.87 | 9 | 19.67 | 31.87 ㎡ | 9 坪 | 19.67 帖 | 51.0865 | 49.1965 | 23000 | 22250 | 95.6269 | 6000 | 0 | 9000 | 2 | 2 | 4 | 900 | 20700 | 4.55366 | 6.37513 | 3.18756 | 0.637513 | 1.59378
310 | 3FL | Z6 | Z6 | 310 | no | 3FL | 3 | 4FL | 配置フロア + 1 | 配置フロア + 1 (4FL) | 31.6144 | 33.625 | 9 | 2 | 52.1727 | 1.89 | 94.8431 | 68.7 | 33.62 | 3.16312 | 33.62 | 10 | 20.75 | 33.62 ㎡ | 10 坪 | 20.75 帖 | 51.0177 | 49.1277 | 23450 | 22900 | 100.875 | 6000 | 0 | 9000 | 3 | 2 | 5 | 900 | 20925 | 4.80357 | 6.725 | 3.3625 | 0.6725 | 1.68125
311 | 3FL | Z7 | Z7 | 311 | no | 3FL | 3 | 4FL | 配置フロア + 1 | 配置フロア + 1 (4FL) | 32.9475 | 35.4744 | 8 | 2 | 52.6902 | 1.89 | 98.8425 | 70.05 | 35.47 | 3.03513 | 35.47 | 10 | 21.89 | 35.47 ㎡ | 10 坪 | 21.89 帖 | 51.5352 | 49.6452 | 24000 | 23350 | 106.423 | 6000 | 0 | 9000 | 3 | 2 | 4 | 900 | 21150 | 5.06777 | 7.09488 | 3.54744 | 0.709488 | 1.77372
313 | 3FL | Z8 | Z8 | 313 | no | 3FL | 3 | 4FL | 配置フロア + 1 | 配置フロア + 1 (4FL) | 40.9675 | 42.75 | 12 | 4 | 48.7302 | 1.89 | 122.903 | 84.45 | 42.75 | 2.44096 | 42.75 | 12 | 26.38 | 42.75 ㎡ | 12 坪 | 26.38 帖 | 48.5202 | 46.6302 | 27100 | 28150 | 128.25 | 6000 | 0 | 9000 | 3 | 2 | 5 | 900 | 20250 | 6.10714 | 8.55 | 4.275 | 0.855 | 2.1375
314 | 3FL | Z9 | Z9 | 314 | no | 3FL | 3 | 4FL | 配置フロア + 1 | 配置フロア + 1 (4FL) | 40.9675 | 42.75 | 12 | 4 | 48.7302 | 1.89 | 122.903 | 84.45 | 42.75 | 2.44096 | 42.75 | 12 | 26.38 | 42.75 ㎡ | 12 坪 | 26.38 帖 | 48.5202 | 46.6302 | 27100 | 28150 | 128.25 | 6000 | 0 | 9000 | 3 | 2 | 5 | 900 | 20250 | 6.10714 | 8.55 | 4.275 | 0.855 | 2.1375
315 | 3FL | Z0 | Z0 | 315 | no | 3FL | 3 | 4FL | 配置フロア + 1 | 配置フロア + 1 (4FL) | 40.9675 | 42.75 | 12 | 4 | 48.7302 | 1.89 | 122.903 | 84.45 | 42.75 | 2.44096 | 42.75 | 12 | 26.38 | 42.75 ㎡ | 12 坪 | 26.38 帖 | 48.5202 | 46.6302 | 27100 | 28150 | 128.25 | 6000 | 0 | 9000 | 3 | 2 | 5 | 900 | 20250 | 6.10714 | 8.55 | 4.275 | 0.855 | 2.1375
316 | 3FL | Z1 | Z1 | 316 | no | 3FL | 3 | 4FL | 配置フロア + 1 | 配置フロア + 1 (4FL) | 42.5963 | 45.1013 | 13 | 4 | 47.3152 | 1.89 | 127.789 | 87.6 | 45.10 | 2.34762 | 45.1 | 13 | 27.83 | 45.10 ㎡ | 13 坪 | 27.83 帖 | 47.3239 | 45.4339 | 27650 | 29200 | 135.304 | 6000 | 0 | 9000 | 3 | 2 | 5 | 900 | 19825 | 6.44304 | 9.02025 | 4.51013 | 0.902025 | 2.25506
312 | 3FL | Z8 | Z8 | 312 | no | 3FL | 3 | 4FL | 配置フロア + 1 | 配置フロア + 1 (4FL) | 60.9556 | 62.8375 | 17 | 8 | 31.7622 | 3.15 | 182.867 | 108.229 | 62.83 | 1.64054 | 62.83 | 19 | 38.78 | 62.83 ㎡ | 19 坪 | 38.78 帖 | 33.1797 | 30.0297 | 32276.3 | 36076.3 | 188.512 | 6000 | 3200 | 9000 | 3 | 4 | 5 | 1500 | 14850 | 8.97679 | 12.5675 | 6.28375 | 1.25675 | 3.14187
312 | 4FL | Z8 | 4FLZ8 | 312 | yes | 4FL | 4 | リンクなし | リンクなし | リンクなし | 60.9556 | 62.8375 | 17 | 8 | 31.7622 | 3.15 | 182.867 | 108.229 | 62.83 | 1.64054 | 62.83 | 19 | 38.78 | 62.83 ㎡ | 19 坪 | 38.78 帖 | 33.1797 | 30.0297 | 32276.3 | 36076.3 | 188.512 | 9000 | 3200 | 12000 | 3 | 4 | 5 | 1500 | 14850 | 8.97679 | 12.5675 | 6.28375 | 1.25675 | 3.14187 | 4FL
316 | 4FL | Z1 | 4FLZ1 | 316 | yes | 4FL | 4 | リンクなし | リンクなし | リンクなし | 42.5963 | 45.1013 | 13 | 4 | 47.3152 | 1.89 | 127.789 | 87.6 | 45.10 | 2.34762 | 45.1 | 13 | 27.83 | 45.10 ㎡ | 13 坪 | 27.83 帖 | 47.3239 | 45.4339 | 27650 | 29200 | 135.304 | 9000 | 0 | 12000 | 3 | 2 | 5 | 900 | 19825 | 6.44304 | 9.02025 | 4.51013 | 0.902025 | 2.25506 | 4FL
315 | 4FL | Z0 | 4FLZ0 | 315 | yes | 4FL | 4 | リンクなし | リンクなし | リンクなし | 40.9675 | 42.75 | 12 | 4 | 48.7302 | 1.89 | 122.903 | 84.45 | 42.75 | 2.44096 | 42.75 | 12 | 26.38 | 42.75 ㎡ | 12 坪 | 26.38 帖 | 48.5202 | 46.6302 | 27100 | 28150 | 128.25 | 9000 | 0 | 12000 | 3 | 2 | 5 | 900 | 20250 | 6.10714 | 8.55 | 4.275 | 0.855 | 2.1375 | 4FL
310 | 4FL | Z6 | 4FLZ6 | 310 | yes | 4FL | 4 | リンクなし | リンクなし | リンクなし | 31.6144 | 33.625 | 9 | 2 | 52.1727 | 1.89 | 94.8431 | 68.7 | 33.62 | 3.16312 | 33.62 | 10 | 20.75 | 33.62 ㎡ | 10 坪 | 20.75 帖 | 51.0177 | 49.1277 | 23450 | 22900 | 100.875 | 9000 | 0 | 12000 | 3 | 2 | 5 | 900 | 20925 | 4.80357 | 6.725 | 3.3625 | 0.6725 | 1.68125 | 4FL
314 | 4FL | Z9 | 4FLZ9 | 314 | yes | 4FL | 4 | リンクなし | リンクなし | リンクなし | 40.9675 | 42.75 | 12 | 4 | 48.7302 | 1.89 | 122.903 | 84.45 | 42.75 | 2.44096 | 42.75 | 12 | 26.38 | 42.75 ㎡ | 12 坪 | 26.38 帖 | 48.5202 | 46.6302 | 27100 | 28150 | 128.25 | 9000 | 0 | 12000 | 3 | 2 | 5 | 900 | 20250 | 6.10714 | 8.55 | 4.275 | 0.855 | 2.1375 | 4FL
313 | 4FL | Z8 | 4FLZ8 | 313 | yes | 4FL | 4 | リンクなし | リンクなし | リンクなし | 40.9675 | 42.75 | 12 | 4 | 48.7302 | 1.89 | 122.903 | 84.45 | 42.75 | 2.44096 | 42.75 | 12 | 26.38 | 42.75 ㎡ | 12 坪 | 26.38 帖 | 48.5202 | 46.6302 | 27100 | 28150 | 128.25 | 9000 | 0 | 12000 | 3 | 2 | 5 | 900 | 20250 | 6.10714 | 8.55 | 4.275 | 0.855 | 2.1375 | 4FL
311 | 4FL | Z7 | 4FLZ7 | 311 | yes | 4FL | 4 | リンクなし | リンクなし | リンクなし | 32.9475 | 35.4744 | 8 | 2 | 52.6902 | 1.89 | 98.8425 | 70.05 | 35.47 | 3.03513 | 35.47 | 10 | 21.89 | 35.47 ㎡ | 10 坪 | 21.89 帖 | 51.5352 | 49.6452 | 24000 | 23350 | 106.423 | 9000 | 0 | 12000 | 3 | 2 | 4 | 900 | 21150 | 5.06777 | 7.09488 | 3.54744 | 0.709488 | 1.77372 | 4FL
308 | 4FL | Z4 | 4FLZ4 | 308 | yes | 4FL | 4 | リンクなし | リンクなし | リンクなし | 32.5275 | 35.2106 | 8 | 2 | 49.7502 | 1.89 | 97.5825 | 69.45 | 35.21 | 3.07432 | 35.21 | 10 | 21.73 | 35.21 ㎡ | 10 坪 | 21.73 帖 | 50.0652 | 48.1752 | 23900 | 23150 | 105.632 | 9000 | 0 | 12000 | 3 | 2 | 4 | 900 | 21150 | 5.03009 | 7.04212 | 3.52106 | 0.704212 | 1.76053 | 4FL
307 | 4FL | Z3 | 4FLZ3 | 307 | yes | 4FL | 4 | リンクなし | リンクなし | リンクなし | 39.5698 | 41.3599 | 26 | 5 | 29.0713 | 1.89 | 118.709 | 84.5199 | 41.35 | 2.52718 | 41.35 | 12 | 25.52 | 41.35 ㎡ | 12 坪 | 25.52 帖 | 28.8606 | 26.9706 | 27752.9 | 28173.3 | 124.08 | 9000 | 0 | 12000 | 2 | 3 | 5 | 900 | 11952 | 5.90855 | 8.27197 | 4.13599 | 0.827197 | 2.06799 | 4FL
306 | 4FL | Z2 | 4FLZ2 | 306 | yes | 4FL | 4 | リンクなし | リンクなし | リンクなし | 46.5147 | 48.8562 | 22 | 7 | 49.9183 | 1.89 | 139.544 | 91.3613 | 48.85 | 2.14986 | 48.85 | 14 | 30.15 | 48.85 ㎡ | 14 坪 | 30.15 帖 | 49.2074 | 47.3174 | 29329 | 30453.8 | 146.569 | 9000 | 0 | 12000 | 4 | 4 | 6 | 900 | 20366.8 | 6.97946 | 9.77125 | 4.88562 | 0.977125 | 2.44281 | 4FL
305 | 4FL | Z1 | 4FLZ1 | 305 | yes | 4FL | 4 | リンクなし | リンクなし | リンクなし | 48.23 | 50.625 | 16 | 6 | 52.0752 | 1.89 | 144.69 | 93.9 | 50.62 | 2.0734 | 50.62 | 15 | 31.24 | 50.62 ㎡ | 15 坪 | 31.24 帖 | 51.5152 | 49.6252 | 30249.9 | 31300 | 151.875 | 9000 | 0 | 12000 | 4 | 4 | 5 | 900 | 21400 | 7.23214 | 10.125 | 5.0625 | 1.0125 | 2.53125 | 4FL
304 | 4FL | Z0 | 4FLZ0 | 304 | yes | 4FL | 4 | リンクなし | リンクなし | リンクなし | 48.23 | 50.625 | 16 | 6 | 52.0752 | 1.89 | 144.69 | 93.9 | 50.62 | 2.0734 | 50.62 | 15 | 31.24 | 50.62 ㎡ | 15 坪 | 31.24 帖 | 51.5152 | 49.6252 | 30250 | 31300 | 151.875 | 9000 | 0 | 12000 | 4 | 4 | 5 | 900 | 21400 | 7.23214 | 10.125 | 5.0625 | 1.0125 | 2.53125 | 4FL
303 | 4FL | Z9 | 4FLZ9 | 303 | yes | 4FL | 4 | リンクなし | リンクなし | リンクなし | 50.4956 | 52.9366 | 17 | 7 | 54.3881 | 1.89 | 151.487 | 97.198 | 52.93 | 1.98037 | 52.93 | 16 | 32.67 | 52.93 ㎡ | 16 坪 | 32.67 帖 | 53.7994 | 51.9094 | 31259.4 | 32399.3 | 158.81 | 9000 | 0 | 12000 | 4 | 4 | 6 | 900 | 22365.4 | 7.56238 | 10.5873 | 5.29366 | 1.05873 | 2.64683 | 4FL
302 | 4FL | Z8 | 4FLZ8 | 302 | yes | 4FL | 4 | リンクなし | リンクなし | リンクなし | 55.0265 | 57.5599 | 17 | 7 | 58.7694 | 1.89 | 165.079 | 102.746 | 57.55 | 1.81731 | 57.55 | 17 | 35.52 | 57.55 ㎡ | 17 坪 | 35.52 帖 | 58.1167 | 56.2267 | 33108.8 | 34248.7 | 172.68 | 9000 | 0 | 12000 | 4 | 4 | 6 | 900 | 24214.7 | 8.22285 | 11.512 | 5.75599 | 1.1512 | 2.878 | 4FL
301 | 4FL | Z7 | 4FLZ7 | 301 | yes | 4FL | 4 | リンクなし | リンクなし | リンクなし | 72.8869 | 75.4638 | 21 | 9 | 35.8465 | 1.89 | 218.661 | 120.589 | 75.46 | 1.37199 | 75.46 | 22 | 46.58 | 75.46 ㎡ | 22 坪 | 46.58 帖 | 35.7126 | 33.8226 | 36446.5 | 40196.5 | 226.391 | 9000 | 3200 | 12000 | 4 | 4 | 6 | 900 | 14949.3 | 10.7805 | 15.0928 | 7.54638 | 1.50928 | 3.77319 | 4FL
309 | 4FL | Z5 | 4FLZ5 | 309 | yes | 4FL | 4 | リンクなし | リンクなし | リンクなし | 29.8613 | 31.8756 | 8 | 2 | 52.8277 | 1.89 | 89.5838 | 66.75 | 31.87 | 3.34882 | 31.87 | 9 | 19.67 | 31.87 ㎡ | 9 坪 | 19.67 帖 | 51.0865 | 49.1965 | 23000 | 22250 | 95.6269 | 9000 | 0 | 12000 | 2 | 2 | 4 | 900 | 20700 | 4.55366 | 6.37513 | 3.18756 | 0.637513 | 1.59378 | 4FL
312 | 5FL | Z8 | 5FLZ8 | 312 | yes | 5FL | 5 | リンクなし | リンクなし | リンクなし | 60.9556 | 62.8375 | 17 | 8 | 31.7622 | 3.15 | 182.867 | 108.229 | 62.83 | 1.64054 | 62.83 | 19 | 38.78 | 62.83 ㎡ | 19 坪 | 38.78 帖 | 33.1797 | 30.0297 | 32276.3 | 36076.3 | 188.512 | 12000 | 3200 | 15000 | 3 | 4 | 5 | 1500 | 14850 | 8.97679 | 12.5675 | 6.28375 | 1.25675 | 3.14187 | 5FL
316 | 5FL | Z1 | 5FLZ1 | 316 | yes | 5FL | 5 | リンクなし | リンクなし | リンクなし | 42.5963 | 45.1013 | 13 | 4 | 47.3152 | 1.89 | 127.789 | 87.6 | 45.10 | 2.34762 | 45.1 | 13 | 27.83 | 45.10 ㎡ | 13 坪 | 27.83 帖 | 47.3239 | 45.4339 | 27650 | 29200 | 135.304 | 12000 | 0 | 15000 | 3 | 2 | 5 | 900 | 19825 | 6.44304 | 9.02025 | 4.51013 | 0.902025 | 2.25506 | 5FL
315 | 5FL | Z0 | 5FLZ0 | 315 | yes | 5FL | 5 | リンクなし | リンクなし | リンクなし | 40.9675 | 42.75 | 12 | 4 | 48.7302 | 1.89 | 122.903 | 84.45 | 42.75 | 2.44096 | 42.75 | 12 | 26.38 | 42.75 ㎡ | 12 坪 | 26.38 帖 | 48.5202 | 46.6302 | 27100 | 28150 | 128.25 | 12000 | 0 | 15000 | 3 | 2 | 5 | 900 | 20250 | 6.10714 | 8.55 | 4.275 | 0.855 | 2.1375 | 5FL
310 | 5FL | Z6 | 5FLZ6 | 310 | yes | 5FL | 5 | リンクなし | リンクなし | リンクなし | 31.6144 | 33.625 | 9 | 2 | 52.1727 | 1.89 | 94.8431 | 68.7 | 33.62 | 3.16312 | 33.62 | 10 | 20.75 | 33.62 ㎡ | 10 坪 | 20.75 帖 | 51.0177 | 49.1277 | 23450 | 22900 | 100.875 | 12000 | 0 | 15000 | 3 | 2 | 5 | 900 | 20925 | 4.80357 | 6.725 | 3.3625 | 0.6725 | 1.68125 | 5FL
314 | 5FL | Z9 | 5FLZ9 | 314 | yes | 5FL | 5 | リンクなし | リンクなし | リンクなし | 40.9675 | 42.75 | 12 | 4 | 48.7302 | 1.89 | 122.903 | 84.45 | 42.75 | 2.44096 | 42.75 | 12 | 26.38 | 42.75 ㎡ | 12 坪 | 26.38 帖 | 48.5202 | 46.6302 | 27100 | 28150 | 128.25 | 12000 | 0 | 15000 | 3 | 2 | 5 | 900 | 20250 | 6.10714 | 8.55 | 4.275 | 0.855 | 2.1375 | 5FL
313 | 5FL | Z8 | 5FLZ8 | 313 | yes | 5FL | 5 | リンクなし | リンクなし | リンクなし | 40.9675 | 42.75 | 12 | 4 | 48.7302 | 1.89 | 122.903 | 84.45 | 42.75 | 2.44096 | 42.75 | 12 | 26.38 | 42.75 ㎡ | 12 坪 | 26.38 帖 | 48.5202 | 46.6302 | 27100 | 28150 | 128.25 | 12000 | 0 | 15000 | 3 | 2 | 5 | 900 | 20250 | 6.10714 | 8.55 | 4.275 | 0.855 | 2.1375 | 5FL
311 | 5FL | Z7 | 5FLZ7 | 311 | yes | 5FL | 5 | リンクなし | リンクなし | リンクなし | 32.9475 | 35.4744 | 8 | 2 | 52.6902 | 1.89 | 98.8425 | 70.05 | 35.47 | 3.03513 | 35.47 | 10 | 21.89 | 35.47 ㎡ | 10 坪 | 21.89 帖 | 51.5352 | 49.6452 | 24000 | 23350 | 106.423 | 12000 | 0 | 15000 | 3 | 2 | 4 | 900 | 21150 | 5.06777 | 7.09488 | 3.54744 | 0.709488 | 1.77372 | 5FL
308 | 5FL | Z4 | 5FLZ4 | 308 | yes | 5FL | 5 | リンクなし | リンクなし | リンクなし | 32.5275 | 35.2106 | 8 | 2 | 49.7502 | 1.89 | 97.5825 | 69.45 | 35.21 | 3.07432 | 35.21 | 10 | 21.73 | 35.21 ㎡ | 10 坪 | 21.73 帖 | 50.0652 | 48.1752 | 23900 | 23150 | 105.632 | 12000 | 0 | 15000 | 3 | 2 | 4 | 900 | 21150 | 5.03009 | 7.04212 | 3.52106 | 0.704212 | 1.76053 | 5FL
307 | 5FL | Z3 | 5FLZ3 | 307 | yes | 5FL | 5 | リンクなし | リンクなし | リンクなし | 39.5698 | 41.3599 | 26 | 5 | 29.0713 | 1.89 | 118.709 | 84.5199 | 41.35 | 2.52718 | 41.35 | 12 | 25.52 | 41.35 ㎡ | 12 坪 | 25.52 帖 | 28.8606 | 26.9706 | 27752.9 | 28173.3 | 124.08 | 12000 | 0 | 15000 | 2 | 3 | 5 | 900 | 11952 | 5.90855 | 8.27197 | 4.13599 | 0.827197 | 2.06799 | 5FL
306 | 5FL | Z2 | 5FLZ2 | 306 | yes | 5FL | 5 | リンクなし | リンクなし | リンクなし | 46.5147 | 48.8562 | 22 | 7 | 49.9183 | 1.89 | 139.544 | 91.3613 | 48.85 | 2.14986 | 48.85 | 14 | 30.15 | 48.85 ㎡ | 14 坪 | 30.15 帖 | 49.2074 | 47.3174 | 29329 | 30453.8 | 146.569 | 12000 | 0 | 15000 | 4 | 4 | 6 | 900 | 20366.8 | 6.97946 | 9.77125 | 4.88562 | 0.977125 | 2.44281 | 5FL
305 | 5FL | Z1 | 5FLZ1 | 305 | yes | 5FL | 5 | リンクなし | リンクなし | リンクなし | 48.23 | 50.625 | 16 | 6 | 52.0752 | 1.89 | 144.69 | 93.9 | 50.62 | 2.0734 | 50.62 | 15 | 31.24 | 50.62 ㎡ | 15 坪 | 31.24 帖 | 51.5152 | 49.6252 | 30249.9 | 31300 | 151.875 | 12000 | 0 | 15000 | 4 | 4 | 5 | 900 | 21400 | 7.23214 | 10.125 | 5.0625 | 1.0125 | 2.53125 | 5FL
304 | 5FL | Z0 | 5FLZ0 | 304 | yes | 5FL | 5 | リンクなし | リンクなし | リンクなし | 48.23 | 50.625 | 16 | 6 | 52.0752 | 1.89 | 144.69 | 93.9 | 50.62 | 2.0734 | 50.62 | 15 | 31.24 | 50.62 ㎡ | 15 坪 | 31.24 帖 | 51.5152 | 49.6252 | 30250 | 31300 | 151.875 | 12000 | 0 | 15000 | 4 | 4 | 5 | 900 | 21400 | 7.23214 | 10.125 | 5.0625 | 1.0125 | 2.53125 | 5FL
303 | 5FL | Z9 | 5FLZ9 | 303 | yes | 5FL | 5 | リンクなし | リンクなし | リンクなし | 50.4956 | 52.9366 | 17 | 7 | 54.3881 | 1.89 | 151.487 | 97.198 | 52.93 | 1.98037 | 52.93 | 16 | 32.67 | 52.93 ㎡ | 16 坪 | 32.67 帖 | 53.7994 | 51.9094 | 31259.4 | 32399.3 | 158.81 | 12000 | 0 | 15000 | 4 | 4 | 6 | 900 | 22365.4 | 7.56238 | 10.5873 | 5.29366 | 1.05873 | 2.64683 | 5FL
302 | 5FL | Z8 | 5FLZ8 | 302 | yes | 5FL | 5 | リンクなし | リンクなし | リンクなし | 55.0265 | 57.5599 | 17 | 7 | 58.7694 | 1.89 | 165.079 | 102.746 | 57.55 | 1.81731 | 57.55 | 17 | 35.52 | 57.55 ㎡ | 17 坪 | 35.52 帖 | 58.1167 | 56.2267 | 33108.8 | 34248.7 | 172.68 | 12000 | 0 | 15000 | 4 | 4 | 6 | 900 | 24214.7 | 8.22285 | 11.512 | 5.75599 | 1.1512 | 2.878 | 5FL
301 | 5FL | Z7 | 5FLZ7 | 301 | yes | 5FL | 5 | リンクなし | リンクなし | リンクなし | 72.8869 | 75.4638 | 21 | 9 | 35.8465 | 1.89 | 218.661 | 120.589 | 75.46 | 1.37199 | 75.46 | 22 | 46.58 | 75.46 ㎡ | 22 坪 | 46.58 帖 | 35.7126 | 33.8226 | 36446.5 | 40196.5 | 226.391 | 12000 | 3200 | 15000 | 4 | 4 | 6 | 900 | 14949.3 | 10.7805 | 15.0928 | 7.54638 | 1.50928 | 3.77319 | 5FL
309 | 5FL | Z5 | 5FLZ5 | 309 | yes | 5FL | 5 | リンクなし | リンクなし | リンクなし | 29.8613 | 31.8756 | 8 | 2 | 52.8277 | 1.89 | 89.5838 | 66.75 | 31.87 | 3.34882 | 31.87 | 9 | 19.67 | 31.87 ㎡ | 9 坪 | 19.67 帖 | 51.0865 | 49.1965 | 23000 | 22250 | 95.6269 | 12000 | 0 | 15000 | 2 | 2 | 4 | 900 | 20700 | 4.55366 | 6.37513 | 3.18756 | 0.637513 | 1.59378 | 5FL
312 | 6FL | Z8 | 6FLZ8 | 312 | yes | 6FL | 6 | リンクなし | リンクなし | リンクなし | 60.9556 | 62.8375 | 17 | 8 | 31.7622 | 3.15 | 182.867 | 108.229 | 62.83 | 1.64054 | 62.83 | 19 | 38.78 | 62.83 ㎡ | 19 坪 | 38.78 帖 | 33.1797 | 30.0297 | 32276.3 | 36076.3 | 188.512 | 15000 | 3200 | 18000 | 3 | 4 | 5 | 1500 | 14850 | 8.97679 | 12.5675 | 6.28375 | 1.25675 | 3.14187 | 6FL
316 | 6FL | Z1 | 6FLZ1 | 316 | yes | 6FL | 6 | リンクなし | リンクなし | リンクなし | 42.5963 | 45.1013 | 13 | 4 | 47.3152 | 1.89 | 127.789 | 87.6 | 45.10 | 2.34762 | 45.1 | 13 | 27.83 | 45.10 ㎡ | 13 坪 | 27.83 帖 | 47.3239 | 45.4339 | 27650 | 29200 | 135.304 | 15000 | 0 | 18000 | 3 | 2 | 5 | 900 | 19825 | 6.44304 | 9.02025 | 4.51013 | 0.902025 | 2.25506 | 6FL
315 | 6FL | Z0 | 6FLZ0 | 315 | yes | 6FL | 6 | リンクなし | リンクなし | リンクなし | 40.9675 | 42.75 | 12 | 4 | 48.7302 | 1.89 | 122.903 | 84.45 | 42.75 | 2.44096 | 42.75 | 12 | 26.38 | 42.75 ㎡ | 12 坪 | 26.38 帖 | 48.5202 | 46.6302 | 27100 | 28150 | 128.25 | 15000 | 0 | 18000 | 3 | 2 | 5 | 900 | 20250 | 6.10714 | 8.55 | 4.275 | 0.855 | 2.1375 | 6FL
310 | 6FL | Z6 | 6FLZ6 | 310 | yes | 6FL | 6 | リンクなし | リンクなし | リンクなし | 31.6144 | 33.625 | 9 | 2 | 52.1727 | 1.89 | 94.8431 | 68.7 | 33.62 | 3.16312 | 33.62 | 10 | 20.75 | 33.62 ㎡ | 10 坪 | 20.75 帖 | 51.0177 | 49.1277 | 23450 | 22900 | 100.875 | 15000 | 0 | 18000 | 3 | 2 | 5 | 900 | 20925 | 4.80357 | 6.725 | 3.3625 | 0.6725 | 1.68125 | 6FL
314 | 6FL | Z9 | 6FLZ9 | 314 | yes | 6FL | 6 | リンクなし | リンクなし | リンクなし | 40.9675 | 42.75 | 12 | 4 | 48.7302 | 1.89 | 122.903 | 84.45 | 42.75 | 2.44096 | 42.75 | 12 | 26.38 | 42.75 ㎡ | 12 坪 | 26.38 帖 | 48.5202 | 46.6302 | 27100 | 28150 | 128.25 | 15000 | 0 | 18000 | 3 | 2 | 5 | 900 | 20250 | 6.10714 | 8.55 | 4.275 | 0.855 | 2.1375 | 6FL
313 | 6FL | Z8 | 6FLZ8 | 313 | yes | 6FL | 6 | リンクなし | リンクなし | リンクなし | 40.9675 | 42.75 | 12 | 4 | 48.7302 | 1.89 | 122.903 | 84.45 | 42.75 | 2.44096 | 42.75 | 12 | 26.38 | 42.75 ㎡ | 12 坪 | 26.38 帖 | 48.5202 | 46.6302 | 27100 | 28150 | 128.25 | 15000 | 0 | 18000 | 3 | 2 | 5 | 900 | 20250 | 6.10714 | 8.55 | 4.275 | 0.855 | 2.1375 | 6FL
311 | 6FL | Z7 | 6FLZ7 | 311 | yes | 6FL | 6 | リンクなし | リンクなし | リンクなし | 32.9475 | 35.4744 | 8 | 2 | 52.6902 | 1.89 | 98.8425 | 70.05 | 35.47 | 3.03513 | 35.47 | 10 | 21.89 | 35.47 ㎡ | 10 坪 | 21.89 帖 | 51.5352 | 49.6452 | 24000 | 23350 | 106.423 | 15000 | 0 | 18000 | 3 | 2 | 4 | 900 | 21150 | 5.06777 | 7.09488 | 3.54744 | 0.709488 | 1.77372 | 6FL
308 | 6FL | Z4 | 6FLZ4 | 308 | yes | 6FL | 6 | リンクなし | リンクなし | リンクなし | 32.5275 | 35.2106 | 8 | 2 | 49.7502 | 1.89 | 97.5825 | 69.45 | 35.21 | 3.07432 | 35.21 | 10 | 21.73 | 35.21 ㎡ | 10 坪 | 21.73 帖 | 50.0652 | 48.1752 | 23900 | 23150 | 105.632 | 15000 | 0 | 18000 | 3 | 2 | 4 | 900 | 21150 | 5.03009 | 7.04212 | 3.52106 | 0.704212 | 1.76053 | 6FL
307 | 6FL | Z3 | 6FLZ3 | 307 | yes | 6FL | 6 | リンクなし | リンクなし | リンクなし | 39.5698 | 41.3599 | 26 | 5 | 29.0713 | 1.89 | 118.709 | 84.5199 | 41.35 | 2.52718 | 41.35 | 12 | 25.52 | 41.35 ㎡ | 12 坪 | 25.52 帖 | 28.8606 | 26.9706 | 27752.9 | 28173.3 | 124.08 | 15000 | 0 | 18000 | 2 | 3 | 5 | 900 | 11952 | 5.90855 | 8.27197 | 4.13599 | 0.827197 | 2.06799 | 6FL
306 | 6FL | Z2 | 6FLZ2 | 306 | yes | 6FL | 6 | リンクなし | リンクなし | リンクなし | 46.5147 | 48.8562 | 22 | 7 | 49.9183 | 1.89 | 139.544 | 91.3613 | 48.85 | 2.14986 | 48.85 | 14 | 30.15 | 48.85 ㎡ | 14 坪 | 30.15 帖 | 49.2074 | 47.3174 | 29329 | 30453.8 | 146.569 | 15000 | 0 | 18000 | 4 | 4 | 6 | 900 | 20366.8 | 6.97946 | 9.77125 | 4.88562 | 0.977125 | 2.44281 | 6FL
305 | 6FL | Z1 | 6FLZ1 | 305 | yes | 6FL | 6 | リンクなし | リンクなし | リンクなし | 48.23 | 50.625 | 16 | 6 | 52.0752 | 1.89 | 144.69 | 93.9 | 50.62 | 2.0734 | 50.62 | 15 | 31.24 | 50.62 ㎡ | 15 坪 | 31.24 帖 | 51.5152 | 49.6252 | 30249.9 | 31300 | 151.875 | 15000 | 0 | 18000 | 4 | 4 | 5 | 900 | 21400 | 7.23214 | 10.125 | 5.0625 | 1.0125 | 2.53125 | 6FL
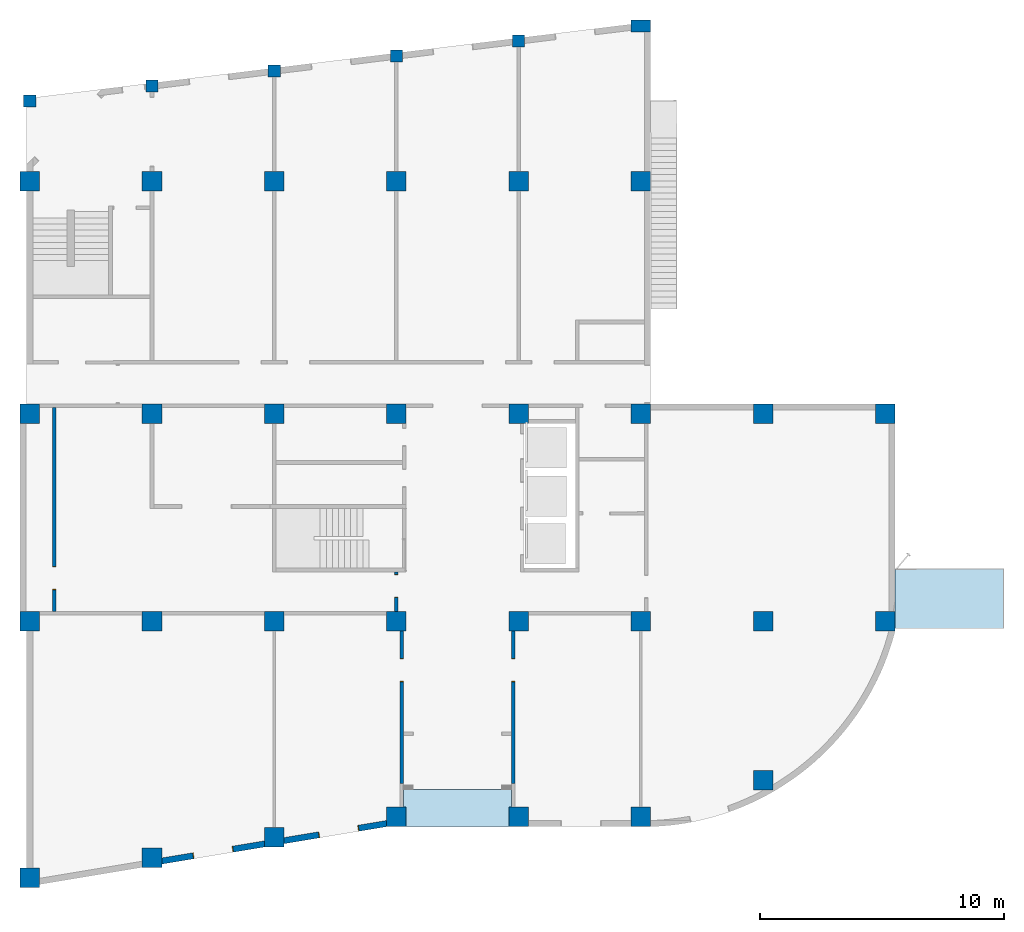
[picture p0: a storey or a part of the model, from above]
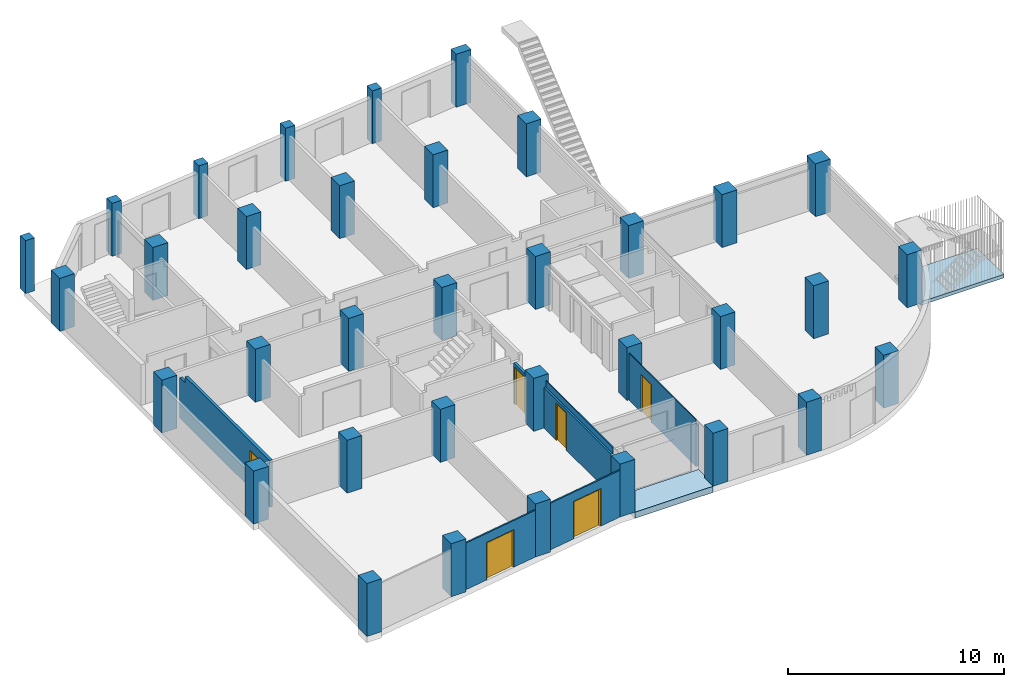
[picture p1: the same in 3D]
Properties of the parts of a building model (IFC2X3), part 2 of 10

# IfcSpace: 事務所-1 (112)
Name | In | 要素ID = 親ID | ホットリンクおよび要素ID | 関連ゾーン番号 = ゾーン番号 = ゾーン番号 (ROOM_NUMBER) | ロック状態 | ホームフロア名 | ホームフロア数 | 絶対上部リンクフロア | 相対上部リンクフロア | 上部リンクフロア | 縮小された面積 = AC_Pset_ゾーン_仕上用, 測定正味面積 = 縮小面積 = 計算面積 (ROOM_CALC_AREA) = 上部表面積 = 下部材質面積 = NetFloorArea (m2) = SpaceNetFloorAreaBOMA (m2) = SpaceUsableFloorAreaBOMA (m2) = NetCeilingArea (m2) = 計算した面積 (m2) = ArchiCADQuantities, 測定正味面積 (m2) | AC_Pset_ゾーン_仕上用, 測定面積 = GrossFloorArea (m2) = GrossCeilingArea (m2) = 面積 (m2) = ArchiCADQuantities, 測定面積 (m2) | 全コーナー数 = 角数 | 凹型コーナー数 = 全てのへこみ角数 | 外壁表面積 | AC_Pset_ゾーン_仕上用, ドア表面積 = ArchiCADQuantities, ドア表面積 (m2) | 体積 = 気積 = NetVolume (m3) = 正味体積 (m3) | 境界表面積 | 計算面積 (stAreaDisp) | 換気回数 | 面積値 | 坪 | 畳 | 面積テキスト | 坪テキスト | 畳テキスト | GrossWallArea (m2) | NetWallArea (m2) = 壁表面積 (m2) | GrossPerimeter (mm) = ゾーン総外周 (mm) = 外周 (mm) | NetPerimeter (mm) = ゾーン正味外周 (mm) = 正味外周 (mm) | GrossVolume (m3) | GLからの高度 (mm) = 高度 1 (mm) = 高度 2 (mm) = 海抜までの高度 (mm) = 下端高度から第1基準レベル (mm) = 下端高度から基準レベル (mm) = 下端高度から海抜 (mm) = 下端高度から第2基準レベル (mm) | 平面図穴外周 (mm) = 穴外周 (mm) | 上端高度から第1基準レベル (mm) = 上端高度から基準レベル (mm) = 上端高度から海抜 (mm) = 上端高度から第2基準レベル (mm) | 梁数 | 柱数 | 壁部品数 | ドア幅 (mm) = ドア組み合わせ幅 (mm) | 壁外周 (mm) = 外壁長さ (mm) | 居室に必要な採光面積 (m2) = 病院福祉施設等に必要な採光面積 (m2) | 教育施設に必要な採光面積 (m2) | その他に必要な採光面積 (m2) | 自然排煙必要面積(ゾーン) (m2) | 必要換気量（ゾーン） (m2) | ホットリンク マスタID
304 | 6FL | Z0 | 6FLZ0 | 304 | yes | 6FL | 6 | リンクなし | リンクなし | リンクなし | 48.23 | 50.625 | 16 | 6 | 52.0752 | 1.89 | 144.69 | 93.9 | 50.62 | 2.0734 | 50.62 | 15 | 31.24 | 50.62 ㎡ | 15 坪 | 31.24 帖 | 51.5152 | 49.6252 | 30250 | 31300 | 151.875 | 15000 | 0 | 18000 | 4 | 4 | 5 | 900 | 21400 | 7.23214 | 10.125 | 5.0625 | 1.0125 | 2.53125 | 6FL
303 | 6FL | Z9 | 6FLZ9 | 303 | yes | 6FL | 6 | リンクなし | リンクなし | リンクなし | 50.4956 | 52.9366 | 17 | 7 | 54.3881 | 1.89 | 151.487 | 97.198 | 52.93 | 1.98037 | 52.93 | 16 | 32.67 | 52.93 ㎡ | 16 坪 | 32.67 帖 | 53.7994 | 51.9094 | 31259.4 | 32399.3 | 158.81 | 15000 | 0 | 18000 | 4 | 4 | 6 | 900 | 22365.4 | 7.56238 | 10.5873 | 5.29366 | 1.05873 | 2.64683 | 6FL
302 | 6FL | Z8 | 6FLZ8 | 302 | yes | 6FL | 6 | リンクなし | リンクなし | リンクなし | 55.0265 | 57.5599 | 17 | 7 | 58.7694 | 1.89 | 165.079 | 102.746 | 57.55 | 1.81731 | 57.55 | 17 | 35.52 | 57.55 ㎡ | 17 坪 | 35.52 帖 | 58.1167 | 56.2267 | 33108.8 | 34248.7 | 172.68 | 15000 | 0 | 18000 | 4 | 4 | 6 | 900 | 24214.7 | 8.22285 | 11.512 | 5.75599 | 1.1512 | 2.878 | 6FL
301 | 6FL | Z7 | 6FLZ7 | 301 | yes | 6FL | 6 | リンクなし | リンクなし | リンクなし | 72.8869 | 75.4638 | 21 | 9 | 35.8465 | 1.89 | 218.661 | 120.589 | 75.46 | 1.37199 | 75.46 | 22 | 46.58 | 75.46 ㎡ | 22 坪 | 46.58 帖 | 35.7126 | 33.8226 | 36446.5 | 40196.5 | 226.391 | 15000 | 3200 | 18000 | 4 | 4 | 6 | 900 | 14949.3 | 10.7805 | 15.0928 | 7.54638 | 1.50928 | 3.77319 | 6FL
309 | 6FL | Z5 | 6FLZ5 | 309 | yes | 6FL | 6 | リンクなし | リンクなし | リンクなし | 29.8613 | 31.8756 | 8 | 2 | 52.8277 | 1.89 | 89.5838 | 66.75 | 31.87 | 3.34882 | 31.87 | 9 | 19.67 | 31.87 ㎡ | 9 坪 | 19.67 帖 | 51.0865 | 49.1965 | 23000 | 22250 | 95.6269 | 15000 | 0 | 18000 | 2 | 2 | 4 | 900 | 20700 | 4.55366 | 6.37513 | 3.18756 | 0.637513 | 1.59378 | 6FL
312 | 7FL | Z8 | 7FLZ8 | 312 | yes | 7FL | 7 | リンクなし | リンクなし | リンクなし | 60.9556 | 62.8375 | 17 | 8 | 31.7622 | 3.15 | 182.867 | 108.229 | 62.83 | 1.64054 | 62.83 | 19 | 38.78 | 62.83 ㎡ | 19 坪 | 38.78 帖 | 33.1797 | 30.0297 | 32276.3 | 36076.3 | 188.512 | 18000 | 3200 | 21000 | 3 | 4 | 5 | 1500 | 14850 | 8.97679 | 12.5675 | 6.28375 | 1.25675 | 3.14187 | 7FL
316 | 7FL | Z1 | 7FLZ1 | 316 | yes | 7FL | 7 | リンクなし | リンクなし | リンクなし | 42.5963 | 45.1013 | 13 | 4 | 47.3152 | 1.89 | 127.789 | 87.6 | 45.10 | 2.34762 | 45.1 | 13 | 27.83 | 45.10 ㎡ | 13 坪 | 27.83 帖 | 47.3239 | 45.4339 | 27650 | 29200 | 135.304 | 18000 | 0 | 21000 | 3 | 2 | 5 | 900 | 19825 | 6.44304 | 9.02025 | 4.51013 | 0.902025 | 2.25506 | 7FL
315 | 7FL | Z0 | 7FLZ0 | 315 | yes | 7FL | 7 | リンクなし | リンクなし | リンクなし | 40.9675 | 42.75 | 12 | 4 | 48.7302 | 1.89 | 122.903 | 84.45 | 42.75 | 2.44096 | 42.75 | 12 | 26.38 | 42.75 ㎡ | 12 坪 | 26.38 帖 | 48.5202 | 46.6302 | 27100 | 28150 | 128.25 | 18000 | 0 | 21000 | 3 | 2 | 5 | 900 | 20250 | 6.10714 | 8.55 | 4.275 | 0.855 | 2.1375 | 7FL
310 | 7FL | Z6 | 7FLZ6 | 310 | yes | 7FL | 7 | リンクなし | リンクなし | リンクなし | 31.6144 | 33.625 | 9 | 2 | 52.1727 | 1.89 | 94.8431 | 68.7 | 33.62 | 3.16312 | 33.62 | 10 | 20.75 | 33.62 ㎡ | 10 坪 | 20.75 帖 | 51.0177 | 49.1277 | 23450 | 22900 | 100.875 | 18000 | 0 | 21000 | 3 | 2 | 5 | 900 | 20925 | 4.80357 | 6.725 | 3.3625 | 0.6725 | 1.68125 | 7FL
314 | 7FL | Z9 | 7FLZ9 | 314 | yes | 7FL | 7 | リンクなし | リンクなし | リンクなし | 40.9675 | 42.75 | 12 | 4 | 48.7302 | 1.89 | 122.903 | 84.45 | 42.75 | 2.44096 | 42.75 | 12 | 26.38 | 42.75 ㎡ | 12 坪 | 26.38 帖 | 48.5202 | 46.6302 | 27100 | 28150 | 128.25 | 18000 | 0 | 21000 | 3 | 2 | 5 | 900 | 20250 | 6.10714 | 8.55 | 4.275 | 0.855 | 2.1375 | 7FL
313 | 7FL | Z8 | 7FLZ8 | 313 | yes | 7FL | 7 | リンクなし | リンクなし | リンクなし | 40.9675 | 42.75 | 12 | 4 | 48.7302 | 1.89 | 122.903 | 84.45 | 42.75 | 2.44096 | 42.75 | 12 | 26.38 | 42.75 ㎡ | 12 坪 | 26.38 帖 | 48.5202 | 46.6302 | 27100 | 28150 | 128.25 | 18000 | 0 | 21000 | 3 | 2 | 5 | 900 | 20250 | 6.10714 | 8.55 | 4.275 | 0.855 | 2.1375 | 7FL
311 | 7FL | Z7 | 7FLZ7 | 311 | yes | 7FL | 7 | リンクなし | リンクなし | リンクなし | 32.9475 | 35.4744 | 8 | 2 | 52.6902 | 1.89 | 98.8425 | 70.05 | 35.47 | 3.03513 | 35.47 | 10 | 21.89 | 35.47 ㎡ | 10 坪 | 21.89 帖 | 51.5352 | 49.6452 | 24000 | 23350 | 106.423 | 18000 | 0 | 21000 | 3 | 2 | 4 | 900 | 21150 | 5.06777 | 7.09488 | 3.54744 | 0.709488 | 1.77372 | 7FL
308 | 7FL | Z4 | 7FLZ4 | 308 | yes | 7FL | 7 | リンクなし | リンクなし | リンクなし | 32.5275 | 35.2106 | 8 | 2 | 49.7502 | 1.89 | 97.5825 | 69.45 | 35.21 | 3.07432 | 35.21 | 10 | 21.73 | 35.21 ㎡ | 10 坪 | 21.73 帖 | 50.0652 | 48.1752 | 23900 | 23150 | 105.632 | 18000 | 0 | 21000 | 3 | 2 | 4 | 900 | 21150 | 5.03009 | 7.04212 | 3.52106 | 0.704212 | 1.76053 | 7FL
307 | 7FL | Z3 | 7FLZ3 | 307 | yes | 7FL | 7 | リンクなし | リンクなし | リンクなし | 39.5698 | 41.3599 | 26 | 5 | 29.0713 | 1.89 | 118.709 | 84.5199 | 41.35 | 2.52718 | 41.35 | 12 | 25.52 | 41.35 ㎡ | 12 坪 | 25.52 帖 | 28.8606 | 26.9706 | 27752.9 | 28173.3 | 124.08 | 18000 | 0 | 21000 | 2 | 3 | 5 | 900 | 11952 | 5.90855 | 8.27197 | 4.13599 | 0.827197 | 2.06799 | 7FL
306 | 7FL | Z2 | 7FLZ2 | 306 | yes | 7FL | 7 | リンクなし | リンクなし | リンクなし | 46.5147 | 48.8562 | 22 | 7 | 49.9183 | 1.89 | 139.544 | 91.3613 | 48.85 | 2.14986 | 48.85 | 14 | 30.15 | 48.85 ㎡ | 14 坪 | 30.15 帖 | 49.2074 | 47.3174 | 29329 | 30453.8 | 146.569 | 18000 | 0 | 21000 | 4 | 4 | 6 | 900 | 20366.8 | 6.97946 | 9.77125 | 4.88562 | 0.977125 | 2.44281 | 7FL
305 | 7FL | Z1 | 7FLZ1 | 305 | yes | 7FL | 7 | リンクなし | リンクなし | リンクなし | 48.23 | 50.625 | 16 | 6 | 52.0752 | 1.89 | 144.69 | 93.9 | 50.62 | 2.0734 | 50.62 | 15 | 31.24 | 50.62 ㎡ | 15 坪 | 31.24 帖 | 51.5152 | 49.6252 | 30249.9 | 31300 | 151.875 | 18000 | 0 | 21000 | 4 | 4 | 5 | 900 | 21400 | 7.23214 | 10.125 | 5.0625 | 1.0125 | 2.53125 | 7FL
304 | 7FL | Z0 | 7FLZ0 | 304 | yes | 7FL | 7 | リンクなし | リンクなし | リンクなし | 48.23 | 50.625 | 16 | 6 | 52.0752 | 1.89 | 144.69 | 93.9 | 50.62 | 2.0734 | 50.62 | 15 | 31.24 | 50.62 ㎡ | 15 坪 | 31.24 帖 | 51.5152 | 49.6252 | 30250 | 31300 | 151.875 | 18000 | 0 | 21000 | 4 | 4 | 5 | 900 | 21400 | 7.23214 | 10.125 | 5.0625 | 1.0125 | 2.53125 | 7FL
303 | 7FL | Z9 | 7FLZ9 | 303 | yes | 7FL | 7 | リンクなし | リンクなし | リンクなし | 50.4956 | 52.9366 | 17 | 7 | 54.3881 | 1.89 | 151.487 | 97.198 | 52.93 | 1.98037 | 52.93 | 16 | 32.67 | 52.93 ㎡ | 16 坪 | 32.67 帖 | 53.7994 | 51.9094 | 31259.4 | 32399.3 | 158.81 | 18000 | 0 | 21000 | 4 | 4 | 6 | 900 | 22365.4 | 7.56238 | 10.5873 | 5.29366 | 1.05873 | 2.64683 | 7FL
302 | 7FL | Z8 | 7FLZ8 | 302 | yes | 7FL | 7 | リンクなし | リンクなし | リンクなし | 55.0265 | 57.5599 | 17 | 7 | 58.7694 | 1.89 | 165.079 | 102.746 | 57.55 | 1.81731 | 57.55 | 17 | 35.52 | 57.55 ㎡ | 17 坪 | 35.52 帖 | 58.1167 | 56.2267 | 33108.8 | 34248.7 | 172.68 | 18000 | 0 | 21000 | 4 | 4 | 6 | 900 | 24214.7 | 8.22285 | 11.512 | 5.75599 | 1.1512 | 2.878 | 7FL
301 | 7FL | Z7 | 7FLZ7 | 301 | yes | 7FL | 7 | リンクなし | リンクなし | リンクなし | 72.8869 | 75.4638 | 21 | 9 | 35.8465 | 1.89 | 218.661 | 120.589 | 75.46 | 1.37199 | 75.46 | 22 | 46.58 | 75.46 ㎡ | 22 坪 | 46.58 帖 | 35.7126 | 33.8226 | 36446.5 | 40196.5 | 226.391 | 18000 | 3200 | 21000 | 4 | 4 | 6 | 900 | 14949.3 | 10.7805 | 15.0928 | 7.54638 | 1.50928 | 3.77319 | 7FL
309 | 7FL | Z5 | 7FLZ5 | 309 | yes | 7FL | 7 | リンクなし | リンクなし | リンクなし | 29.8613 | 31.8756 | 8 | 2 | 52.8277 | 1.89 | 89.5838 | 66.75 | 31.87 | 3.34882 | 31.87 | 9 | 19.67 | 31.87 ㎡ | 9 坪 | 19.67 帖 | 51.0865 | 49.1965 | 23000 | 22250 | 95.6269 | 18000 | 0 | 21000 | 2 | 2 | 4 | 900 | 20700 | 4.55366 | 6.37513 | 3.18756 | 0.637513 | 1.59378 | 7FL
312 | 8FL | Z8 | 8FLZ8 | 312 | yes | 8FL | 8 | リンクなし | リンクなし | リンクなし | 60.9556 | 62.8375 | 17 | 8 | 31.7622 | 3.15 | 182.867 | 108.229 | 62.83 | 1.64054 | 62.83 | 19 | 38.78 | 62.83 ㎡ | 19 坪 | 38.78 帖 | 33.1797 | 30.0297 | 32276.3 | 36076.3 | 188.512 | 21000 | 3200 | 24000 | 3 | 4 | 5 | 1500 | 14850 | 8.97679 | 12.5675 | 6.28375 | 1.25675 | 3.14187 | 8FL
316 | 8FL | Z1 | 8FLZ1 | 316 | yes | 8FL | 8 | リンクなし | リンクなし | リンクなし | 42.5963 | 45.1013 | 13 | 4 | 47.3152 | 1.89 | 127.789 | 87.6 | 45.10 | 2.34762 | 45.1 | 13 | 27.83 | 45.10 ㎡ | 13 坪 | 27.83 帖 | 47.3239 | 45.4339 | 27650 | 29200 | 135.304 | 21000 | 0 | 24000 | 3 | 2 | 5 | 900 | 19825 | 6.44304 | 9.02025 | 4.51013 | 0.902025 | 2.25506 | 8FL
315 | 8FL | Z0 | 8FLZ0 | 315 | yes | 8FL | 8 | リンクなし | リンクなし | リンクなし | 40.9675 | 42.75 | 12 | 4 | 48.7302 | 1.89 | 122.903 | 84.45 | 42.75 | 2.44096 | 42.75 | 12 | 26.38 | 42.75 ㎡ | 12 坪 | 26.38 帖 | 48.5202 | 46.6302 | 27100 | 28150 | 128.25 | 21000 | 0 | 24000 | 3 | 2 | 5 | 900 | 20250 | 6.10714 | 8.55 | 4.275 | 0.855 | 2.1375 | 8FL
310 | 8FL | Z6 | 8FLZ6 | 310 | yes | 8FL | 8 | リンクなし | リンクなし | リンクなし | 31.6144 | 33.625 | 9 | 2 | 52.1727 | 1.89 | 94.8431 | 68.7 | 33.62 | 3.16312 | 33.62 | 10 | 20.75 | 33.62 ㎡ | 10 坪 | 20.75 帖 | 51.0177 | 49.1277 | 23450 | 22900 | 100.875 | 21000 | 0 | 24000 | 3 | 2 | 5 | 900 | 20925 | 4.80357 | 6.725 | 3.3625 | 0.6725 | 1.68125 | 8FL
314 | 8FL | Z9 | 8FLZ9 | 314 | yes | 8FL | 8 | リンクなし | リンクなし | リンクなし | 40.9675 | 42.75 | 12 | 4 | 48.7302 | 1.89 | 122.903 | 84.45 | 42.75 | 2.44096 | 42.75 | 12 | 26.38 | 42.75 ㎡ | 12 坪 | 26.38 帖 | 48.5202 | 46.6302 | 27100 | 28150 | 128.25 | 21000 | 0 | 24000 | 3 | 2 | 5 | 900 | 20250 | 6.10714 | 8.55 | 4.275 | 0.855 | 2.1375 | 8FL
313 | 8FL | Z8 | 8FLZ8 | 313 | yes | 8FL | 8 | リンクなし | リンクなし | リンクなし | 40.9675 | 42.75 | 12 | 4 | 48.7302 | 1.89 | 122.903 | 84.45 | 42.75 | 2.44096 | 42.75 | 12 | 26.38 | 42.75 ㎡ | 12 坪 | 26.38 帖 | 48.5202 | 46.6302 | 27100 | 28150 | 128.25 | 21000 | 0 | 24000 | 3 | 2 | 5 | 900 | 20250 | 6.10714 | 8.55 | 4.275 | 0.855 | 2.1375 | 8FL
311 | 8FL | Z7 | 8FLZ7 | 311 | yes | 8FL | 8 | リンクなし | リンクなし | リンクなし | 32.9475 | 35.4744 | 8 | 2 | 52.6902 | 1.89 | 98.8425 | 70.05 | 35.47 | 3.03513 | 35.47 | 10 | 21.89 | 35.47 ㎡ | 10 坪 | 21.89 帖 | 51.5352 | 49.6452 | 24000 | 23350 | 106.423 | 21000 | 0 | 24000 | 3 | 2 | 4 | 900 | 21150 | 5.06777 | 7.09488 | 3.54744 | 0.709488 | 1.77372 | 8FL
308 | 8FL | Z4 | 8FLZ4 | 308 | yes | 8FL | 8 | リンクなし | リンクなし | リンクなし | 32.5275 | 35.2106 | 8 | 2 | 49.7502 | 1.89 | 97.5825 | 69.45 | 35.21 | 3.07432 | 35.21 | 10 | 21.73 | 35.21 ㎡ | 10 坪 | 21.73 帖 | 50.0652 | 48.1752 | 23900 | 23150 | 105.632 | 21000 | 0 | 24000 | 3 | 2 | 4 | 900 | 21150 | 5.03009 | 7.04212 | 3.52106 | 0.704212 | 1.76053 | 8FL
307 | 8FL | Z3 | 8FLZ3 | 307 | yes | 8FL | 8 | リンクなし | リンクなし | リンクなし | 39.5698 | 41.3599 | 26 | 5 | 29.0713 | 1.89 | 118.709 | 84.5199 | 41.35 | 2.52718 | 41.35 | 12 | 25.52 | 41.35 ㎡ | 12 坪 | 25.52 帖 | 28.8606 | 26.9706 | 27752.9 | 28173.3 | 124.08 | 21000 | 0 | 24000 | 2 | 3 | 5 | 900 | 11952 | 5.90855 | 8.27197 | 4.13599 | 0.827197 | 2.06799 | 8FL
306 | 8FL | Z2 | 8FLZ2 | 306 | yes | 8FL | 8 | リンクなし | リンクなし | リンクなし | 46.5147 | 48.8562 | 22 | 7 | 49.9183 | 1.89 | 139.544 | 91.3613 | 48.85 | 2.14986 | 48.85 | 14 | 30.15 | 48.85 ㎡ | 14 坪 | 30.15 帖 | 49.2074 | 47.3174 | 29329 | 30453.8 | 146.569 | 21000 | 0 | 24000 | 4 | 4 | 6 | 900 | 20366.8 | 6.97946 | 9.77125 | 4.88562 | 0.977125 | 2.44281 | 8FL
305 | 8FL | Z1 | 8FLZ1 | 305 | yes | 8FL | 8 | リンクなし | リンクなし | リンクなし | 48.23 | 50.625 | 16 | 6 | 52.0752 | 1.89 | 144.69 | 93.9 | 50.62 | 2.0734 | 50.62 | 15 | 31.24 | 50.62 ㎡ | 15 坪 | 31.24 帖 | 51.5152 | 49.6252 | 30249.9 | 31300 | 151.875 | 21000 | 0 | 24000 | 4 | 4 | 5 | 900 | 21400 | 7.23214 | 10.125 | 5.0625 | 1.0125 | 2.53125 | 8FL
304 | 8FL | Z0 | 8FLZ0 | 304 | yes | 8FL | 8 | リンクなし | リンクなし | リンクなし | 48.23 | 50.625 | 16 | 6 | 52.0752 | 1.89 | 144.69 | 93.9 | 50.62 | 2.0734 | 50.62 | 15 | 31.24 | 50.62 ㎡ | 15 坪 | 31.24 帖 | 51.5152 | 49.6252 | 30250 | 31300 | 151.875 | 21000 | 0 | 24000 | 4 | 4 | 5 | 900 | 21400 | 7.23214 | 10.125 | 5.0625 | 1.0125 | 2.53125 | 8FL
303 | 8FL | Z9 | 8FLZ9 | 303 | yes | 8FL | 8 | リンクなし | リンクなし | リンクなし | 50.4956 | 52.9366 | 17 | 7 | 54.3881 | 1.89 | 151.487 | 97.198 | 52.93 | 1.98037 | 52.93 | 16 | 32.67 | 52.93 ㎡ | 16 坪 | 32.67 帖 | 53.7994 | 51.9094 | 31259.4 | 32399.3 | 158.81 | 21000 | 0 | 24000 | 4 | 4 | 6 | 900 | 22365.4 | 7.56238 | 10.5873 | 5.29366 | 1.05873 | 2.64683 | 8FL
302 | 8FL | Z8 | 8FLZ8 | 302 | yes | 8FL | 8 | リンクなし | リンクなし | リンクなし | 55.0265 | 57.5599 | 17 | 7 | 58.7694 | 1.89 | 165.079 | 102.746 | 57.55 | 1.81731 | 57.55 | 17 | 35.52 | 57.55 ㎡ | 17 坪 | 35.52 帖 | 58.1167 | 56.2267 | 33108.8 | 34248.7 | 172.68 | 21000 | 0 | 24000 | 4 | 4 | 6 | 900 | 24214.7 | 8.22285 | 11.512 | 5.75599 | 1.1512 | 2.878 | 8FL
301 | 8FL | Z7 | 8FLZ7 | 301 | yes | 8FL | 8 | リンクなし | リンクなし | リンクなし | 72.8869 | 75.4638 | 21 | 9 | 35.8465 | 1.89 | 218.661 | 120.589 | 75.46 | 1.37199 | 75.46 | 22 | 46.58 | 75.46 ㎡ | 22 坪 | 46.58 帖 | 35.7126 | 33.8226 | 36446.5 | 40196.5 | 226.391 | 21000 | 3200 | 24000 | 4 | 4 | 6 | 900 | 14949.3 | 10.7805 | 15.0928 | 7.54638 | 1.50928 | 3.77319 | 8FL
309 | 8FL | Z5 | 8FLZ5 | 309 | yes | 8FL | 8 | リンクなし | リンクなし | リンクなし | 29.8613 | 31.8756 | 8 | 2 | 52.8277 | 1.89 | 89.5838 | 66.75 | 31.87 | 3.34882 | 31.87 | 9 | 19.67 | 31.87 ㎡ | 9 坪 | 19.67 帖 | 51.0865 | 49.1965 | 23000 | 22250 | 95.6269 | 21000 | 0 | 24000 | 2 | 2 | 4 | 900 | 20700 | 4.55366 | 6.37513 | 3.18756 | 0.637513 | 1.59378 | 8FL
312 | 9FL | Z8 | 9FLZ8 | 312 | yes | 9FL | 9 | リンクなし | リンクなし | リンクなし | 60.9556 | 62.8375 | 17 | 8 | 31.7622 | 3.15 | 182.867 | 108.229 | 62.83 | 1.64054 | 62.83 | 19 | 38.78 | 62.83 ㎡ | 19 坪 | 38.78 帖 | 33.1797 | 30.0297 | 32276.3 | 36076.3 | 188.512 | 24000 | 3200 | 27000 | 3 | 4 | 5 | 1500 | 14850 | 8.97679 | 12.5675 | 6.28375 | 1.25675 | 3.14187 | 9FL
316 | 9FL | Z1 | 9FLZ1 | 316 | yes | 9FL | 9 | リンクなし | リンクなし | リンクなし | 42.5963 | 45.1013 | 13 | 4 | 47.3152 | 1.89 | 127.789 | 87.6 | 45.10 | 2.34762 | 45.1 | 13 | 27.83 | 45.10 ㎡ | 13 坪 | 27.83 帖 | 47.3239 | 45.4339 | 27650 | 29200 | 135.304 | 24000 | 0 | 27000 | 3 | 2 | 5 | 900 | 19825 | 6.44304 | 9.02025 | 4.51013 | 0.902025 | 2.25506 | 9FL
315 | 9FL | Z0 | 9FLZ0 | 315 | yes | 9FL | 9 | リンクなし | リンクなし | リンクなし | 40.9675 | 42.75 | 12 | 4 | 48.7302 | 1.89 | 122.903 | 84.45 | 42.75 | 2.44096 | 42.75 | 12 | 26.38 | 42.75 ㎡ | 12 坪 | 26.38 帖 | 48.5202 | 46.6302 | 27100 | 28150 | 128.25 | 24000 | 0 | 27000 | 3 | 2 | 5 | 900 | 20250 | 6.10714 | 8.55 | 4.275 | 0.855 | 2.1375 | 9FL
310 | 9FL | Z6 | 9FLZ6 | 310 | yes | 9FL | 9 | リンクなし | リンクなし | リンクなし | 31.6144 | 33.625 | 9 | 2 | 52.1727 | 1.89 | 94.8431 | 68.7 | 33.62 | 3.16312 | 33.62 | 10 | 20.75 | 33.62 ㎡ | 10 坪 | 20.75 帖 | 51.0177 | 49.1277 | 23450 | 22900 | 100.875 | 24000 | 0 | 27000 | 3 | 2 | 5 | 900 | 20925 | 4.80357 | 6.725 | 3.3625 | 0.6725 | 1.68125 | 9FL
314 | 9FL | Z9 | 9FLZ9 | 314 | yes | 9FL | 9 | リンクなし | リンクなし | リンクなし | 40.9675 | 42.75 | 12 | 4 | 48.7302 | 1.89 | 122.903 | 84.45 | 42.75 | 2.44096 | 42.75 | 12 | 26.38 | 42.75 ㎡ | 12 坪 | 26.38 帖 | 48.5202 | 46.6302 | 27100 | 28150 | 128.25 | 24000 | 0 | 27000 | 3 | 2 | 5 | 900 | 20250 | 6.10714 | 8.55 | 4.275 | 0.855 | 2.1375 | 9FL
313 | 9FL | Z8 | 9FLZ8 | 313 | yes | 9FL | 9 | リンクなし | リンクなし | リンクなし | 40.9675 | 42.75 | 12 | 4 | 48.7302 | 1.89 | 122.903 | 84.45 | 42.75 | 2.44096 | 42.75 | 12 | 26.38 | 42.75 ㎡ | 12 坪 | 26.38 帖 | 48.5202 | 46.6302 | 27100 | 28150 | 128.25 | 24000 | 0 | 27000 | 3 | 2 | 5 | 900 | 20250 | 6.10714 | 8.55 | 4.275 | 0.855 | 2.1375 | 9FL
311 | 9FL | Z7 | 9FLZ7 | 311 | yes | 9FL | 9 | リンクなし | リンクなし | リンクなし | 32.9475 | 35.4744 | 8 | 2 | 52.6902 | 1.89 | 98.8425 | 70.05 | 35.47 | 3.03513 | 35.47 | 10 | 21.89 | 35.47 ㎡ | 10 坪 | 21.89 帖 | 51.5352 | 49.6452 | 24000 | 23350 | 106.423 | 24000 | 0 | 27000 | 3 | 2 | 4 | 900 | 21150 | 5.06777 | 7.09488 | 3.54744 | 0.709488 | 1.77372 | 9FL
308 | 9FL | Z4 | 9FLZ4 | 308 | yes | 9FL | 9 | リンクなし | リンクなし | リンクなし | 32.5275 | 35.2106 | 8 | 2 | 49.7502 | 1.89 | 97.5825 | 69.45 | 35.21 | 3.07432 | 35.21 | 10 | 21.73 | 35.21 ㎡ | 10 坪 | 21.73 帖 | 50.0652 | 48.1752 | 23900 | 23150 | 105.632 | 24000 | 0 | 27000 | 3 | 2 | 4 | 900 | 21150 | 5.03009 | 7.04212 | 3.52106 | 0.704212 | 1.76053 | 9FL
307 | 9FL | Z3 | 9FLZ3 | 307 | yes | 9FL | 9 | リンクなし | リンクなし | リンクなし | 39.5698 | 41.3599 | 26 | 5 | 29.0713 | 1.89 | 118.709 | 84.5199 | 41.35 | 2.52718 | 41.35 | 12 | 25.52 | 41.35 ㎡ | 12 坪 | 25.52 帖 | 28.8606 | 26.9706 | 27752.9 | 28173.3 | 124.08 | 24000 | 0 | 27000 | 2 | 3 | 5 | 900 | 11952 | 5.90855 | 8.27197 | 4.13599 | 0.827197 | 2.06799 | 9FL
306 | 9FL | Z2 | 9FLZ2 | 306 | yes | 9FL | 9 | リンクなし | リンクなし | リンクなし | 46.5147 | 48.8562 | 22 | 7 | 49.9183 | 1.89 | 139.544 | 91.3613 | 48.85 | 2.14986 | 48.85 | 14 | 30.15 | 48.85 ㎡ | 14 坪 | 30.15 帖 | 49.2074 | 47.3174 | 29329 | 30453.8 | 146.569 | 24000 | 0 | 27000 | 4 | 4 | 6 | 900 | 20366.8 | 6.97946 | 9.77125 | 4.88562 | 0.977125 | 2.44281 | 9FL
305 | 9FL | Z1 | 9FLZ1 | 305 | yes | 9FL | 9 | リンクなし | リンクなし | リンクなし | 48.23 | 50.625 | 16 | 6 | 52.0752 | 1.89 | 144.69 | 93.9 | 50.62 | 2.0734 | 50.62 | 15 | 31.24 | 50.62 ㎡ | 15 坪 | 31.24 帖 | 51.5152 | 49.6252 | 30249.9 | 31300 | 151.875 | 24000 | 0 | 27000 | 4 | 4 | 5 | 900 | 21400 | 7.23214 | 10.125 | 5.0625 | 1.0125 | 2.53125 | 9FL
304 | 9FL | Z0 | 9FLZ0 | 304 | yes | 9FL | 9 | リンクなし | リンクなし | リンクなし | 48.23 | 50.625 | 16 | 6 | 52.0752 | 1.89 | 144.69 | 93.9 | 50.62 | 2.0734 | 50.62 | 15 | 31.24 | 50.62 ㎡ | 15 坪 | 31.24 帖 | 51.5152 | 49.6252 | 30250 | 31300 | 151.875 | 24000 | 0 | 27000 | 4 | 4 | 5 | 900 | 21400 | 7.23214 | 10.125 | 5.0625 | 1.0125 | 2.53125 | 9FL
303 | 9FL | Z9 | 9FLZ9 | 303 | yes | 9FL | 9 | リンクなし | リンクなし | リンクなし | 50.4956 | 52.9366 | 17 | 7 | 54.3881 | 1.89 | 151.487 | 97.198 | 52.93 | 1.98037 | 52.93 | 16 | 32.67 | 52.93 ㎡ | 16 坪 | 32.67 帖 | 53.7994 | 51.9094 | 31259.4 | 32399.3 | 158.81 | 24000 | 0 | 27000 | 4 | 4 | 6 | 900 | 22365.4 | 7.56238 | 10.5873 | 5.29366 | 1.05873 | 2.64683 | 9FL
302 | 9FL | Z8 | 9FLZ8 | 302 | yes | 9FL | 9 | リンクなし | リンクなし | リンクなし | 55.0265 | 57.5599 | 17 | 7 | 58.7694 | 1.89 | 165.079 | 102.746 | 57.55 | 1.81731 | 57.55 | 17 | 35.52 | 57.55 ㎡ | 17 坪 | 35.52 帖 | 58.1167 | 56.2267 | 33108.8 | 34248.7 | 172.68 | 24000 | 0 | 27000 | 4 | 4 | 6 | 900 | 24214.7 | 8.22285 | 11.512 | 5.75599 | 1.1512 | 2.878 | 9FL
301 | 9FL | Z7 | 9FLZ7 | 301 | yes | 9FL | 9 | リンクなし | リンクなし | リンクなし | 72.8869 | 75.4638 | 21 | 9 | 35.8465 | 1.89 | 218.661 | 120.589 | 75.46 | 1.37199 | 75.46 | 22 | 46.58 | 75.46 ㎡ | 22 坪 | 46.58 帖 | 35.7126 | 33.8226 | 36446.5 | 40196.5 | 226.391 | 24000 | 3200 | 27000 | 4 | 4 | 6 | 900 | 14949.3 | 10.7805 | 15.0928 | 7.54638 | 1.50928 | 3.77319 | 9FL
309 | 9FL | Z5 | 9FLZ5 | 309 | yes | 9FL | 9 | リンクなし | リンクなし | リンクなし | 29.8613 | 31.8756 | 8 | 2 | 52.8277 | 1.89 | 89.5838 | 66.75 | 31.87 | 3.34882 | 31.87 | 9 | 19.67 | 31.87 ㎡ | 9 坪 | 19.67 帖 | 51.0865 | 49.1965 | 23000 | 22250 | 95.6269 | 24000 | 0 | 27000 | 2 | 2 | 4 | 900 | 20700 | 4.55366 | 6.37513 | 3.18756 | 0.637513 | 1.59378 | 9FL

# IfcSpace: 共用-1 (52)
InteriorOrExteriorSpace: INTERNAL; Classification: スペース (ARCHICAD 分類); 共用-1 共用-1
Pset_SpaceCommon - Category: 共用-1
ArchiCADProperties - レイヤー: ゾーン; ライブラリ部品名: ゾーン_仕上用; 関連ゾーン番号: ＜ゾーン番号＞; 要素タイプ: ゾーン; 材質 (全て): ゾーン - 05; 表面塗りつぶし: 背景; リノベーションフィルタで表示: 全ての関連フィルタ; リノベーションステータス: 既存; 材質: ゾーン - 05; 同一材質: yes; ゾーン番号: ＜ゾーン番号＞; ゾーンカテゴリ: 0; ゾーンカテゴリコード: 共用-1; ARCHICAD 分類 - v 2.0: スペース
AC_Pset_ゾーン_仕上用 - マーカーテキスト1サイズ(デフォルト): 2; マーカーテキスト1スタイル(デフォルト): 0; マーカーテキスト1 整列(デフォルト): 1; マーカーテキスト1 改行幅(デフォルト): 0; マーカーテキスト1 文字幅(デフォルト): 1; マーカーテキスト1 テキスト文字間隔(デフォルト): 1; テキストフォント1: Meiryo Japanese; ゾーン番号 (ROOM_NUMBER): ＜ゾーン番号＞; 窓表面積: 0; 抽出壁面積: 0; 抽出カーテンウォール面積: 0; 抽出柱面積: 0; 抽出塗りつぶし面積: 0; 抽出床面積: 0; 抽出総面積: 0; ゾーン面積係数: 1; 上部屋根表面積: 0; 下部屋根表面積: 0; 上部スラブ表面積: 0; 下部スラブ表面積: 0; 下部梁表面積: 0; 下部梁表面: 0; 上部壁インセット表面積: 0; 壁インセット背面: 0; 側面壁インセット表面積: 0; 詳細: 1; 固定スタンプ表示 (stChangebyScale): 1：50まで; 固定スタンプ表示 (iChangebyScale): 1; ゾーンスタンプタイプ: 1; 面積値表示: 1; 一行で表示するスケール: 400; 室名: yes; ソーン名文字揃え: 2; 枠線 (bFrameRoomName): no; ゾーン番号 (bZoneNum): no; ゾーン番号タイプ: 1; IDを表示...: 1; 枠線 (bFrameZoneNum): no; 床タイプ: no; 床タイプ名称: ＜フロア タイプ＞; 枠線 (bFrameFloor): no; 面積表示: yes; 平米丸め（小数点）: ２桁; 平米単位表示: 1; 坪表示: no; 坪小数点以下表示: なし; 坪単位表示: 1; 畳表示: no; 帖、Ｊ表示: 帖; 畳単位表示: 1; 帖数小数点: ２桁; 畳係数: 1.62; 枠線 (bFrameArea): no; 外周: no; 枠線 (bFramePeri): no; CH=表示: no; CH=: 2400; 枠線 (bFrameCeil): no; FL又はSL表示: no; FL/SL値: ＋50; FL/SL文字: SL; 枠線 (bFrameFloorlabel): no; スラブ厚: 160; コンクリート天端レベル: ±0; 排煙記号: no; 排煙種類: 未定; 枠線 (bFrameSmokesign): no; 内装制限記号: no; 内装制限種類: 未定; 枠線 (bFrameInterior): no; カテゴリとプロパティを表示: no; 枠線 (bFrameTnC): yes; 枠幅設定: 余白あり; 枠幅桁数: 14; 表示精度: 1; 坪、畳は丸めた平米値で計算する: yes; ------------------: -------------; 角度: 0 deg; 表面塗りつぶし: no; 背景塗つぶしタイプ: 50 %; 表面塗りつぶしペン背景: 透過; 空調タイプ: 日当り空調室; 編集する床の下地を選択: 1; 床＿仕上: 磁器タイル; 床＿下地: RC; 床＿下地2: RC; 床＿下地3: RC; 床＿下地4: RC; 床＿下地5: RC; 巾木: ソフト巾木; 壁仕上げ: 磁器タイル; 編集する壁の下地を選択: 4; 壁＿下地: RC; 壁＿下地2: RC; 壁＿下地3: RC; 壁＿下地4: RC; 壁＿下地5: RC; 天井＿仕上: クロス貼; 編集する天井の下地を選択: 1; 天井＿下地: 軽鉄野縁; 天井＿下地2: 軽鉄野縁; 天井＿下地3: 軽鉄野縁; 天井＿下地4: 軽鉄野縁; 天井＿下地5: 軽鉄野縁; 廻り縁: 廻縁 塩ビ; 面積区分: 1; 面積対象: 1; 換気タイプ: タイプ1; 給気量（A）m3/h: 300; 排気量（B）m3/h: 300; 天井高テキスト: 3,000; 床＿下地テキスト: RC/RC/RC/RC/RC; 壁＿下地テキスト: RC/RC/RC/RC/RC; 天井＿下地テキスト: 軽鉄野縁/軽鉄野縁/軽鉄野縁/軽鉄野縁/軽鉄野縁; 巾木高さ値（mm）: 75; パラメータを選択: 1; データを表示: 1; 1. 列 パラメータ名を次のように表示: 1; 2. 列 パラメータ名を次のように表示: 1; 3. 列 パラメータ名を次のように表示: 1; 4. 列 パラメータ名を次のように表示: 1; 5. 列 パラメータ名を次のように表示: 1; 6. 列 パラメータ名を次のように表示: 1; 7. 列 パラメータ名を次のように表示: 1; 8. 列 パラメータ名を次のように表示: 1; 9. 列 パラメータ名を次のように表示: 1; 10. 列 パラメータ名を次のように表示: 1; 11. 列 パラメータ名を次のように表示: 1; 12. 列 パラメータ名を次のように表示: 1; 13. 列 パラメータ名を次のように表示: 1; 14. 列 パラメータ名を次のように表示: 1; 15. 列 パラメータ名を次のように表示: 1; 16. 列 パラメータ名を次のように表示: 1; 17. 列 パラメータ名を次のように表示: 1; 18. 列 パラメータ名を次のように表示: 1; 19. 列 パラメータ名を次のように表示: 1; 20. 列 パラメータ名を次のように表示: 1
室情報 - 利用者数: 0; 一人あたりの必要面積: 0 m2
AC_Pset_RenovationAndPhasing - Renovation Status: Existing
BaseQuantities - Height: 3000 mm; FinishCeilingHeight: 3000 mm; FinishFloorHeight: 0 mm; ClearHeight: 3000 mm
ArchiCADQuantities - 高さ: 3000 mm; リンク/配置フロアまでの高度: 0 mm; 下部オフセット: 0 mm; 上部オフセット: 0 mm; 上端高度から配置フロア: 3000 mm; 下端高度から配置フロア: 0 mm; 基準レベル: 0 mm; ランプ数: 0; 窓数: 0; 窓表面積: 0 m2; 窓幅: 0 mm; フロア厚さ: 0 mm; 面積縮小: 1 m2; 抜き取られる柱面積: 0 m2; 抜き取られる塗りつぶし面積: 0 m2; 抜き取られる底面積: 0 m2; 抜き取られる壁面積: 0 m2; 抜き取られる総面積: 0 m2; 壁のインセット背面表面積: 0 m2; 壁インセット側面表面積: 0 m2; 壁インセット上部表面積: 0 m2
AC_Equantity_ゾーン_仕上用 - 窓組み合わせ幅: 0 mm; フロアレベル: 0 mm; サブフロア厚さ: 0 mm; 高さ: 3000 mm; 巾木高さ: 75 mm; 腰高: 1000 mm; 平均天井高: 3000 mm
Name | In | LongName = 関連ゾーン名 = ゾーン名 = ゾーン名 (ROOM_NAME) = ゾーン名 (stZoneName) | 要素ID = 親ID | ホットリンクおよび要素ID | ロック状態 | ホームフロア名 | ホームフロア数 | 絶対上部リンクフロア | 相対上部リンクフロア | 上部リンクフロア | 縮小された面積 = AC_Pset_ゾーン_仕上用, 測定正味面積 = 縮小面積 = 計算面積 (ROOM_CALC_AREA) = 上部表面積 = 下部材質面積 = NetFloorArea (m2) = SpaceNetFloorAreaBOMA (m2) = SpaceUsableFloorAreaBOMA (m2) = NetCeilingArea (m2) = 計算した面積 (m2) = ArchiCADQuantities, 測定正味面積 (m2) | AC_Pset_ゾーン_仕上用, 測定面積 = GrossFloorArea (m2) = GrossCeilingArea (m2) = 面積 (m2) = ArchiCADQuantities, 測定面積 (m2) | 全コーナー数 = 角数 | 凹型コーナー数 = 全てのへこみ角数 | 外壁表面積 | AC_Pset_ゾーン_仕上用, ドア表面積 | 体積 = 気積 | 境界表面積 | 計算面積 (stAreaDisp) | 換気回数 | カテゴリ名称 | 面積値 | 坪 | 畳 | 面積テキスト | 坪テキスト | 畳テキスト | GrossWallArea (m2) | NetWallArea (m2) = 壁表面積 (m2) | GrossPerimeter (mm) = ゾーン総外周 (mm) = 外周 (mm) | NetPerimeter (mm) = ゾーン正味外周 (mm) = 正味外周 (mm) | GrossVolume (m3) | NetVolume (m3) = 正味体積 (m3) | GLからの高度 (mm) = 高度 1 (mm) = 高度 2 (mm) = 海抜までの高度 (mm) = 下端高度から第1基準レベル (mm) = 下端高度から基準レベル (mm) = 下端高度から海抜 (mm) = 下端高度から第2基準レベル (mm) | 平面図穴外周 (mm) = 穴外周 (mm) | 上端高度から第1基準レベル (mm) = 上端高度から基準レベル (mm) = 上端高度から海抜 (mm) = 上端高度から第2基準レベル (mm) | 梁数 | 柱数 | ドア数 | オブジェクト数 | 壁部品数 | ArchiCADQuantities, ドア表面積 (m2) | ドア幅 (mm) | 壁外周 (mm) = 外壁長さ (mm) | ドア組み合わせ幅 (mm) | 居室に必要な採光面積 (m2) = 病院福祉施設等に必要な採光面積 (m2) | 教育施設に必要な採光面積 (m2) | その他に必要な採光面積 (m2) | 自然排煙必要面積(ゾーン) (m2) | 必要換気量（ゾーン） (m2) | ホットリンク マスタID
＜ゾーン番号＞ | 1FL | 共用スペー | Z4 | Z4 | no | 1FL | 1 | 2FL | 配置フロア + 1 | 配置フロア + 1 (2FL) | 61.1862 | 64.75 | 10 | 3 | 98.2776 | 7.98 | 183.559 | 133.2 | 64.75 | 1.63435 | 共用-1 | 64.75 | 19 | 39.96 | 64.75 ㎡ | 19 坪 | 39.96 帖 | 106.258 | 98.2776 | 45000 | 44400 | 194.25 | 183.559 | 0 | 0 | 3000 | 4 | 4 | 3 | 0 | 8 | 7.98 | 3800 | 43425 | 3800 | 9.25 | 12.95 | 6.475 | 1.295 | 3.2375
＜ゾーン番号＞ | 1FL | 女性用トイレ | Z6 | Z6 | no | 1FL | 1 | 2FL | 配置フロア + 1 | 配置フロア + 1 (2FL) | 8.53875 | 9.585 | 4 | 0 | 33.5037 | 1.47 | 25.6163 | 40.95 | 9.58 | 11.7113 | 共用-1 | 9.58 | 2 | 5.91 | 9.58 ㎡ | 2 坪 | 5.91 帖 | 34.9737 | 33.5037 | 14250 | 13650 | 28.755 | 25.6163 | 0 | 0 | 3000 | 2 | 0 | 1 | 1 | 4 | 1.47 | 700 | 13650 | 700 | 1.36929 | 1.917 | 0.9585 | 0.1917 | 0.47925
＜ゾーン番号＞ | 1FL | 男性用トイレ | Z6 | Z6 | no | 1FL | 1 | 2FL | 配置フロア + 1 | 配置フロア + 1 (2FL) | 10.6219 | 12.3806 | 8 | 2 | 30.5375 | 1.47 | 31.8656 | 44.1 | 12.38 | 9.41453 | 共用-1 | 12.38 | 3 | 7.64 | 12.38 ㎡ | 3 坪 | 7.64 帖 | 32.0075 | 30.5375 | 15300 | 14700 | 37.1419 | 31.8656 | 0 | 0 | 3000 | 3 | 2 | 1 | 0 | 4 | 1.47 | 700 | 12425 | 700 | 1.76866 | 2.47613 | 1.23806 | 0.247613 | 0.619031
＜ゾーン番号＞ | 1FL | 多目的トイレ | Z6 | Z6 | no | 1FL | 1 | 2FL | 配置フロア + 1 | 配置フロア + 1 (2FL) | 5.48375 | 6.215 | 4 | 0 | 22.0002 | 1.89 | 16.4513 | 28.35 | 6.21 | 18.2357 | 共用-1 | 6.21 | 1 | 3.83 | 6.21 ㎡ | 1 坪 | 3.83 帖 | 21.488 | 19.178 | 10050 | 9450 | 18.645 | 16.4513 | 0 | 0 | 3000 | 1 | 0 | 1 | 1 | 4 | 2.31 | 1100 | 9450 | 900 | 0.887857 | 1.243 | 0.6215 | 0.1243 | 0.31075
＜ゾーン番号＞ | 1FL | EVホール | Z4 | Z4 | no | 1FL | 1 | 2FL | 配置フロア + 1 | 配置フロア + 1 (2FL) | 54.0369 | 57.1656 | 20 | 6 | 59.321 | 21.63 | 162.111 | 124.95 | 57.16 | 1.85059 | 共用-1 | 57.16 | 17 | 35.28 | 57.16 ㎡ | 17 坪 | 35.28 帖 | 80.945 | 58.895 | 42100 | 41650 | 171.497 | 162.111 | 0 | 0 | 3000 | 4 | 5 | 10 | 2 | 13 | 22.05 | 10500 | 35975 | 10300 | 8.16652 | 11.4331 | 5.71656 | 1.14331 | 2.85828
＜ゾーン番号＞ | 1FL | 玄関ホール | Z5 | Z5 | no | 1FL | 1 | 2FL | 配置フロア + 1 | 配置フロア + 1 (2FL) | 21.195 | 22.4088 | 8 | 2 | 21.6371 | 11.34 | 63.585 | 55.5 | 22.40 | 4.71809 | 共用-1 | 22.4 | 6 | 13.82 | 22.40 ㎡ | 6 坪 | 13.82 帖 | 32.9771 | 21.6371 | 18950 | 18500 | 67.2263 | 63.585 | 0 | 0 | 3000 | 1 | 2 | 3 | 1 | 3 | 11.34 | 5400 | 12650 | 5400 | 3.20125 | 4.48175 | 2.24088 | 0.448175 | 1.12044
＜ゾーン番号＞ | 1FL | 廊下 | Z4 | Z4 | no | 1FL | 1 | 2FL | 配置フロア + 1 | 配置フロア + 1 (2FL) | 34.8969 | 38.4731 | 8 | 1 | 89.8263 | 19.95 | 104.691 | 138.6 | 38.47 | 2.86559 | 共用-1 | 38.47 | 11 | 23.74 | 38.47 ㎡ | 11 坪 | 23.74 帖 | 109.776 | 89.8263 | 46900 | 46200 | 115.419 | 104.691 | 0 | 0 | 3000 | 5 | 5 | 8 | 0 | 8 | 19.95 | 9500 | 46200 | 9500 | 5.49616 | 7.69462 | 3.84731 | 0.769462 | 1.92366
＜ゾーン番号＞ | 1FL | ホール | Z4 | Z4 | no | 1FL | 1 | 2FL | 配置フロア + 1 | 配置フロア + 1 (2FL) | 27.7267 | 31.3583 | 21 | 10 | 54.8945 | 17.22 | 83.1801 | 92.6863 | 31.35 | 3.60663 | 共用-1 | 31.35 | 9 | 19.35 | 31.35 ㎡ | 9 坪 | 19.35 帖 | 72.1145 | 54.8945 | 25233.9 | 30895.4 | 94.075 | 83.1801 | 0 | 5250 | 3000 | 6 | 3 | 4 | 0 | 13 | 17.22 | 8200 | 27827.1 | 8200 | 4.47976 | 6.27167 | 3.13583 | 0.627167 | 1.56792
＜ゾーン番号＞ | 2FL | 廊下 | Z5 | Z5 | no | 2FL | 2 | 3FL | 配置フロア + 1 | 配置フロア + 1 (3FL) | 16.3719 | 18.2381 | 4 | 0 | 44.5555 | 10.71 | 49.1156 | 70.2 | 18.23 | 6.10804 | 共用-1 | 18.23 | 5 | 11.25 | 18.23 ㎡ | 5 坪 | 11.25 帖 | 55.2655 | 44.5555 | 24100 | 23400 | 54.7144 | 49.1156 | 3000 | 0 | 6000 | 6 | 3 | 5 | 0 | 4 | 10.71 | 5100 | 23400 | 5100 | 2.60545 | 3.64762 | 1.82381 | 0.364762 | 0.911906
＜ゾーン番号＞ | 2FL | ホール | Z4 | Z4 | no | 2FL | 2 | 3FL | 配置フロア + 1 | 配置フロア + 1 (3FL) | 26.0968 | 30.1327 | 20 | 8 | 89.2744 | 8.19 | 78.2904 | 123.3 | 30.13 | 3.83189 |  | 30.13 | 9 | 18.59 | 30.13 ㎡ | 9 坪 | 18.59 帖 | 97.4644 | 89.2744 | 26150 | 41100 | 90.398 | 78.2904 | 3000 | 0 | 6000 | 8 | 2 | 4 | 0 | 15 | 8.19 | 3900 | 38875 | 3900 | 4.30467 | 6.02653 | 3.01327 | 0.602653 | 1.50663
＜ゾーン番号＞ | 2FL | 廊下 | Z5 | Z5 | no | 2FL | 2 | 3FL | 配置フロア + 1 | 配置フロア + 1 (3FL) | 32.0337 | 35.2625 | 10 | 2 | 85.0409 | 17.64 | 96.1012 | 128.25 | 35.26 | 3.12171 | 共用-1 | 35.26 | 10 | 21.76 | 35.26 ㎡ | 10 坪 | 21.76 帖 | 102.681 | 85.0409 | 43350 | 42750 | 105.788 | 96.1012 | 3000 | 0 | 6000 | 8 | 4 | 7 | 0 | 10 | 17.64 | 8400 | 42750 | 8400 | 5.0375 | 7.0525 | 3.52625 | 0.70525 | 1.76313
＜ゾーン番号＞ | 2FL | EVホール | Z4 | Z4 | no | 2FL | 2 | 3FL | 配置フロア + 1 | 配置フロア + 1 (3FL) | 83.5469 | 89.3394 | 27 | 12 | 123.092 | 34.86 | 250.641 | 223.35 | 89.33 | 1.19693 |  | 89.33 | 27 | 55.14 | 89.33 ㎡ | 27 坪 | 55.14 帖 | 157.952 | 123.092 | 74600 | 74450 | 268.018 | 250.641 | 3000 | 0 | 6000 | 16 | 8 | 16 | 0 | 18 | 34.86 | 16600 | 66925 | 16600 | 12.7628 | 17.8679 | 8.93394 | 1.78679 | 4.46697
＜ゾーン番号＞ | 2FL | 男性用トイレ | Z6 | Z6 | no | 2FL | 2 | 3FL | 配置フロア + 1 | 配置フロア + 1 (3FL) | 11.2556 | 12.3806 | 5 | 0 | 30.5375 | 1.47 | 33.7669 | 44.1 | 12.38 | 8.88445 | 共用-1 | 12.38 | 3 | 7.64 | 12.38 ㎡ | 3 坪 | 7.64 帖 | 32.0075 | 30.5375 | 15300 | 14700 | 37.1419 | 33.7669 | 3000 | 0 | 6000 | 12 | 2 | 1 | 0 | 5 | 1.47 | 700 | 14700 | 700 | 1.76866 | 2.47613 | 1.23806 | 0.247613 | 0.619031
＜ゾーン番号＞ | 2FL | 女性用トイレ | Z6 | Z6 | no | 2FL | 2 | 3FL | 配置フロア + 1 | 配置フロア + 1 (3FL) | 8.53875 | 9.585 | 4 | 0 | 33.5037 | 1.47 | 25.6163 | 40.95 | 9.58 | 11.7113 | 共用-1 | 9.58 | 2 | 5.91 | 9.58 ㎡ | 2 坪 | 5.91 帖 | 34.9737 | 33.5037 | 14250 | 13650 | 28.755 | 25.6162 | 3000 | 0 | 6000 | 4 | 0 | 1 | 0 | 4 | 1.47 | 700 | 13650 | 700 | 1.36929 | 1.917 | 0.9585 | 0.1917 | 0.47925
＜ゾーン番号＞ | 2FL | 男性用トイレ | Z6 | Z6 | no | 2FL | 2 | 3FL | 配置フロア + 1 | 配置フロア + 1 (3FL) | 3.6487 | 4.46118 | 6 | 1 | 20.183 | 1.68 | 10.9461 | 26.5581 | 4.46 | 27.407 | 共用-1 | 4.46 | 1 | 2.75 | 4.46 ㎡ | 1 坪 | 2.75 帖 | 21.863 | 20.183 | 9555.72 | 8852.71 | 13.3835 | 10.9461 | 3000 | 0 | 6000 | 4 | 1 | 1 | 0 | 6 | 1.68 | 800 | 8852.71 | 800 | 0.637311 | 0.892236 | 0.446118 | 0.0892236 | 0.223059
＜ゾーン番号＞ | 2FL | 女性用トイレ | Z6 | Z6 | no | 2FL | 2 | 3FL | 配置フロア + 1 | 配置フロア + 1 (3FL) | 8.87138 | 10.1438 | 8 | 2 | 28.9881 | 1.68 | 26.6141 | 38.8337 | 10.14 | 11.2722 | 共用-1 | 10.14 | 3 | 6.25 | 10.14 ㎡ | 3 坪 | 6.25 帖 | 30.6681 | 28.9881 | 13741.8 | 12944.6 | 30.4313 | 26.6141 | 3000 | 0 | 6000 | 6 | 2 | 1 | 0 | 8 | 1.68 | 800 | 12944.6 | 800 | 1.44911 | 2.02876 | 1.01438 | 0.202876 | 0.507189
＜ゾーン番号＞ | 2FL | 多目的トイレ | Z6 | Z6 | no | 2FL | 2 | 3FL | 配置フロア + 1 | 配置フロア + 1 (3FL) | 5.48375 | 6.215 | 4 | 0 | 19.1779 | 2.31 | 16.4513 | 28.35 | 6.21 | 18.2357 | 共用-1 | 6.21 | 1 | 3.83 | 6.21 ㎡ | 1 坪 | 3.83 帖 | 21.4879 | 19.1779 | 10050 | 9450 | 18.645 | 16.4512 | 3000 | 0 | 6000 | 2 | 0 | 1 | 0 | 4 | 2.31 | 1100 | 9450 | 1100 | 0.887857 | 1.243 | 0.6215 | 0.1243 | 0.31075
＜ゾーン番号＞ | 3FL | 廊下 | Z5 | Z5 | no | 3FL | 3 | 4FL | 配置フロア + 1 | 配置フロア + 1 (4FL) | 16.3719 | 18.2381 | 4 | 0 | 50.6455 | 10.71 | 49.1156 | 70.2 | 18.23 | 6.10804 | 共用-1 | 18.23 | 5 | 11.25 | 18.23 ㎡ | 5 坪 | 11.25 帖 | 55.2655 | 44.5555 | 24100 | 23400 | 54.7144 | 49.1156 | 6000 | 0 | 9000 | 3 | 3 | 5 | 0 | 4 | 10.71 | 5100 | 23400 | 5100 | 2.60545 | 3.64762 | 1.82381 | 0.364762 | 0.911906
＜ゾーン番号＞ | 3FL | 多目的トイレ | Z6 | Z6 | no | 3FL | 3 | 4FL | 配置フロア + 1 | 配置フロア + 1 (4FL) | 5.48375 | 6.215 | 4 | 0 | 21.4879 | 2.31 | 16.4513 | 28.35 | 6.21 | 18.2357 | 共用-1 | 6.21 | 1 | 3.83 | 6.21 ㎡ | 1 坪 | 3.83 帖 | 21.4879 | 19.1779 | 10050 | 9450 | 18.645 | 16.4512 | 6000 | 0 | 9000 | 1 | 0 | 1 | 0 | 4 | 2.31 | 1100 | 9450 | 1100 | 0.887857 | 1.243 | 0.6215 | 0.1243 | 0.31075
＜ゾーン番号＞ | 3FL | EVホール | Z4 | Z4 | no | 3FL | 3 | 4FL | 配置フロア + 1 | 配置フロア + 1 (4FL) | 106.758 | 114.764 | 23 | 9 | 218.649 | 42.84 | 320.274 | 303.45 | 114.76 | 0.936697 | 共用-1 | 114.76 | 34 | 70.83 | 114.76 ㎡ | 34 坪 | 70.83 帖 | 235.207 | 191.947 | 100900 | 101150 | 344.293 | 320.274 | 6000 | 0 | 9000 | 11 | 10 | 21 | 0 | 20 | 43.26 | 20600 | 99400 | 20400 | 16.3949 | 22.9529 | 11.4764 | 2.29529 | 5.73822
＜ゾーン番号＞ | 3FL | 男性用トイレ | Z6 | Z6 | no | 3FL | 3 | 4FL | 配置フロア + 1 | 配置フロア + 1 (4FL) | 10.6219 | 12.3806 | 8 | 2 | 34.1162 | 1.47 | 31.8656 | 44.1 | 12.38 | 9.41453 | 共用-1 | 12.38 | 3 | 7.64 | 12.38 ㎡ | 3 坪 | 7.64 帖 | 32.0074 | 30.5374 | 15300 | 14700 | 37.1419 | 31.8656 | 6000 | 0 | 9000 | 3 | 2 | 1 | 0 | 4 | 1.47 | 700 | 12425 | 700 | 1.76866 | 2.47613 | 1.23806 | 0.247613 | 0.619031
＜ゾーン番号＞ | 3FL | 女性用トイレ | Z6 | Z6 | no | 3FL | 3 | 4FL | 配置フロア + 1 | 配置フロア + 1 (4FL) | 8.53875 | 9.585 | 4 | 0 | 37.2312 | 1.47 | 25.6163 | 40.95 | 9.58 | 11.7113 | 共用-1 | 9.58 | 2 | 5.91 | 9.58 ㎡ | 2 坪 | 5.91 帖 | 34.9737 | 33.5037 | 14250 | 13650 | 28.755 | 25.6162 | 6000 | 0 | 9000 | 2 | 0 | 1 | 0 | 4 | 1.47 | 700 | 13650 | 700 | 1.36929 | 1.917 | 0.9585 | 0.1917 | 0.47925
＜ゾーン番号＞ | 4FL | 女性用トイレ | Z6 | 4FLZ6 | yes | 4FL | 4 | リンクなし | リンクなし | リンクなし | 8.53875 | 9.585 | 4 | 0 | 37.2312 | 1.47 | 25.6163 | 40.95 | 9.58 | 11.7113 | 共用-1 | 9.58 | 2 | 5.91 | 9.58 ㎡ | 2 坪 | 5.91 帖 | 34.9737 | 33.5037 | 14250 | 13650 | 28.755 | 25.6162 | 9000 | 0 | 12000 | 2 | 0 | 1 | 0 | 4 | 1.47 | 700 | 13650 | 700 | 1.36929 | 1.917 | 0.9585 | 0.1917 | 0.47925 | 4FL
＜ゾーン番号＞ | 4FL | 男性用トイレ | Z6 | 4FLZ6 | yes | 4FL | 4 | リンクなし | リンクなし | リンクなし | 10.6219 | 12.3806 | 8 | 2 | 34.1162 | 1.47 | 31.8656 | 44.1 | 12.38 | 9.41453 | 共用-1 | 12.38 | 3 | 7.64 | 12.38 ㎡ | 3 坪 | 7.64 帖 | 32.0074 | 30.5374 | 15300 | 14700 | 37.1419 | 31.8656 | 9000 | 0 | 12000 | 3 | 2 | 1 | 0 | 4 | 1.47 | 700 | 12425 | 700 | 1.76866 | 2.47613 | 1.23806 | 0.247613 | 0.619031 | 4FL
＜ゾーン番号＞ | 4FL | EVホール | Z4 | 4FLZ4 | yes | 4FL | 4 | リンクなし | リンクなし | リンクなし | 106.758 | 114.764 | 23 | 9 | 218.649 | 42.84 | 320.274 | 303.45 | 114.76 | 0.936697 | 共用-1 | 114.76 | 34 | 70.83 | 114.76 ㎡ | 34 坪 | 70.83 帖 | 235.207 | 191.947 | 100900 | 101150 | 344.293 | 320.274 | 9000 | 0 | 12000 | 11 | 10 | 21 | 0 | 20 | 43.26 | 20600 | 99400 | 20400 | 16.3949 | 22.9529 | 11.4764 | 2.29529 | 5.73822 | 4FL
＜ゾーン番号＞ | 4FL | 廊下 | Z5 | 4FLZ5 | yes | 4FL | 4 | リンクなし | リンクなし | リンクなし | 16.3719 | 18.2381 | 4 | 0 | 50.6455 | 10.71 | 49.1156 | 70.2 | 18.23 | 6.10804 | 共用-1 | 18.23 | 5 | 11.25 | 18.23 ㎡ | 5 坪 | 11.25 帖 | 55.2655 | 44.5555 | 24100 | 23400 | 54.7144 | 49.1156 | 9000 | 0 | 12000 | 3 | 3 | 5 | 0 | 4 | 10.71 | 5100 | 23400 | 5100 | 2.60545 | 3.64762 | 1.82381 | 0.364762 | 0.911906 | 4FL
＜ゾーン番号＞ | 4FL | 多目的トイレ | Z6 | 4FLZ6 | yes | 4FL | 4 | リンクなし | リンクなし | リンクなし | 5.48375 | 6.215 | 4 | 0 | 21.4879 | 2.31 | 16.4513 | 28.35 | 6.21 | 18.2357 | 共用-1 | 6.21 | 1 | 3.83 | 6.21 ㎡ | 1 坪 | 3.83 帖 | 21.4879 | 19.1779 | 10050 | 9450 | 18.645 | 16.4512 | 9000 | 0 | 12000 | 1 | 0 | 1 | 0 | 4 | 2.31 | 1100 | 9450 | 1100 | 0.887857 | 1.243 | 0.6215 | 0.1243 | 0.31075 | 4FL
＜ゾーン番号＞ | 5FL | 女性用トイレ | Z6 | 5FLZ6 | yes | 5FL | 5 | リンクなし | リンクなし | リンクなし | 8.53875 | 9.585 | 4 | 0 | 37.2312 | 1.47 | 25.6163 | 40.95 | 9.58 | 11.7113 | 共用-1 | 9.58 | 2 | 5.91 | 9.58 ㎡ | 2 坪 | 5.91 帖 | 34.9737 | 33.5037 | 14250 | 13650 | 28.755 | 25.6162 | 12000 | 0 | 15000 | 2 | 0 | 1 | 0 | 4 | 1.47 | 700 | 13650 | 700 | 1.36929 | 1.917 | 0.9585 | 0.1917 | 0.47925 | 5FL
＜ゾーン番号＞ | 5FL | 男性用トイレ | Z6 | 5FLZ6 | yes | 5FL | 5 | リンクなし | リンクなし | リンクなし | 10.6219 | 12.3806 | 8 | 2 | 34.1162 | 1.47 | 31.8656 | 44.1 | 12.38 | 9.41453 | 共用-1 | 12.38 | 3 | 7.64 | 12.38 ㎡ | 3 坪 | 7.64 帖 | 32.0074 | 30.5374 | 15300 | 14700 | 37.1419 | 31.8656 | 12000 | 0 | 15000 | 3 | 2 | 1 | 0 | 4 | 1.47 | 700 | 12425 | 700 | 1.76866 | 2.47613 | 1.23806 | 0.247613 | 0.619031 | 5FL
＜ゾーン番号＞ | 5FL | EVホール | Z4 | 5FLZ4 | yes | 5FL | 5 | リンクなし | リンクなし | リンクなし | 106.758 | 114.764 | 23 | 9 | 218.649 | 42.84 | 320.274 | 303.45 | 114.76 | 0.936697 | 共用-1 | 114.76 | 34 | 70.83 | 114.76 ㎡ | 34 坪 | 70.83 帖 | 235.207 | 191.947 | 100900 | 101150 | 344.293 | 320.274 | 12000 | 0 | 15000 | 11 | 10 | 21 | 0 | 20 | 43.26 | 20600 | 99400 | 20400 | 16.3949 | 22.9529 | 11.4764 | 2.29529 | 5.73822 | 5FL
＜ゾーン番号＞ | 5FL | 廊下 | Z5 | 5FLZ5 | yes | 5FL | 5 | リンクなし | リンクなし | リンクなし | 16.3719 | 18.2381 | 4 | 0 | 50.6455 | 10.71 | 49.1156 | 70.2 | 18.23 | 6.10804 | 共用-1 | 18.23 | 5 | 11.25 | 18.23 ㎡ | 5 坪 | 11.25 帖 | 55.2655 | 44.5555 | 24100 | 23400 | 54.7144 | 49.1156 | 12000 | 0 | 15000 | 3 | 3 | 5 | 0 | 4 | 10.71 | 5100 | 23400 | 5100 | 2.60545 | 3.64762 | 1.82381 | 0.364762 | 0.911906 | 5FL
＜ゾーン番号＞ | 5FL | 多目的トイレ | Z6 | 5FLZ6 | yes | 5FL | 5 | リンクなし | リンクなし | リンクなし | 5.48375 | 6.215 | 4 | 0 | 21.4879 | 2.31 | 16.4513 | 28.35 | 6.21 | 18.2357 | 共用-1 | 6.21 | 1 | 3.83 | 6.21 ㎡ | 1 坪 | 3.83 帖 | 21.4879 | 19.1779 | 10050 | 9450 | 18.645 | 16.4512 | 12000 | 0 | 15000 | 1 | 0 | 1 | 0 | 4 | 2.31 | 1100 | 9450 | 1100 | 0.887857 | 1.243 | 0.6215 | 0.1243 | 0.31075 | 5FL
＜ゾーン番号＞ | 6FL | 女性用トイレ | Z6 | 6FLZ6 | yes | 6FL | 6 | リンクなし | リンクなし | リンクなし | 8.53875 | 9.585 | 4 | 0 | 37.2312 | 1.47 | 25.6163 | 40.95 | 9.58 | 11.7113 | 共用-1 | 9.58 | 2 | 5.91 | 9.58 ㎡ | 2 坪 | 5.91 帖 | 34.9737 | 33.5037 | 14250 | 13650 | 28.755 | 25.6162 | 15000 | 0 | 18000 | 2 | 0 | 1 | 0 | 4 | 1.47 | 700 | 13650 | 700 | 1.36929 | 1.917 | 0.9585 | 0.1917 | 0.47925 | 6FL
＜ゾーン番号＞ | 6FL | 男性用トイレ | Z6 | 6FLZ6 | yes | 6FL | 6 | リンクなし | リンクなし | リンクなし | 10.6219 | 12.3806 | 8 | 2 | 34.1162 | 1.47 | 31.8656 | 44.1 | 12.38 | 9.41453 | 共用-1 | 12.38 | 3 | 7.64 | 12.38 ㎡ | 3 坪 | 7.64 帖 | 32.0074 | 30.5374 | 15300 | 14700 | 37.1419 | 31.8656 | 15000 | 0 | 18000 | 3 | 2 | 1 | 0 | 4 | 1.47 | 700 | 12425 | 700 | 1.76866 | 2.47613 | 1.23806 | 0.247613 | 0.619031 | 6FL
＜ゾーン番号＞ | 6FL | EVホール | Z4 | 6FLZ4 | yes | 6FL | 6 | リンクなし | リンクなし | リンクなし | 106.758 | 114.764 | 23 | 9 | 218.649 | 42.84 | 320.274 | 303.45 | 114.76 | 0.936697 | 共用-1 | 114.76 | 34 | 70.83 | 114.76 ㎡ | 34 坪 | 70.83 帖 | 235.207 | 191.947 | 100900 | 101150 | 344.293 | 320.274 | 15000 | 0 | 18000 | 11 | 10 | 21 | 0 | 20 | 43.26 | 20600 | 99400 | 20400 | 16.3949 | 22.9529 | 11.4764 | 2.29529 | 5.73822 | 6FL
＜ゾーン番号＞ | 6FL | 廊下 | Z5 | 6FLZ5 | yes | 6FL | 6 | リンクなし | リンクなし | リンクなし | 16.3719 | 18.2381 | 4 | 0 | 50.6455 | 10.71 | 49.1156 | 70.2 | 18.23 | 6.10804 | 共用-1 | 18.23 | 5 | 11.25 | 18.23 ㎡ | 5 坪 | 11.25 帖 | 55.2655 | 44.5555 | 24100 | 23400 | 54.7144 | 49.1156 | 15000 | 0 | 18000 | 3 | 3 | 5 | 0 | 4 | 10.71 | 5100 | 23400 | 5100 | 2.60545 | 3.64762 | 1.82381 | 0.364762 | 0.911906 | 6FL
＜ゾーン番号＞ | 6FL | 多目的トイレ | Z6 | 6FLZ6 | yes | 6FL | 6 | リンクなし | リンクなし | リンクなし | 5.48375 | 6.215 | 4 | 0 | 21.4879 | 2.31 | 16.4513 | 28.35 | 6.21 | 18.2357 | 共用-1 | 6.21 | 1 | 3.83 | 6.21 ㎡ | 1 坪 | 3.83 帖 | 21.4879 | 19.1779 | 10050 | 9450 | 18.645 | 16.4512 | 15000 | 0 | 18000 | 1 | 0 | 1 | 0 | 4 | 2.31 | 1100 | 9450 | 1100 | 0.887857 | 1.243 | 0.6215 | 0.1243 | 0.31075 | 6FL
＜ゾーン番号＞ | 7FL | 女性用トイレ | Z6 | 7FLZ6 | yes | 7FL | 7 | リンクなし | リンクなし | リンクなし | 8.53875 | 9.585 | 4 | 0 | 37.2312 | 1.47 | 25.6163 | 40.95 | 9.58 | 11.7113 | 共用-1 | 9.58 | 2 | 5.91 | 9.58 ㎡ | 2 坪 | 5.91 帖 | 34.9737 | 33.5037 | 14250 | 13650 | 28.755 | 25.6162 | 18000 | 0 | 21000 | 2 | 0 | 1 | 0 | 4 | 1.47 | 700 | 13650 | 700 | 1.36929 | 1.917 | 0.9585 | 0.1917 | 0.47925 | 7FL
＜ゾーン番号＞ | 7FL | 男性用トイレ | Z6 | 7FLZ6 | yes | 7FL | 7 | リンクなし | リンクなし | リンクなし | 10.6219 | 12.3806 | 8 | 2 | 34.1162 | 1.47 | 31.8656 | 44.1 | 12.38 | 9.41453 | 共用-1 | 12.38 | 3 | 7.64 | 12.38 ㎡ | 3 坪 | 7.64 帖 | 32.0074 | 30.5374 | 15300 | 14700 | 37.1419 | 31.8656 | 18000 | 0 | 21000 | 3 | 2 | 1 | 0 | 4 | 1.47 | 700 | 12425 | 700 | 1.76866 | 2.47613 | 1.23806 | 0.247613 | 0.619031 | 7FL
＜ゾーン番号＞ | 7FL | EVホール | Z4 | 7FLZ4 | yes | 7FL | 7 | リンクなし | リンクなし | リンクなし | 106.758 | 114.764 | 23 | 9 | 218.649 | 42.84 | 320.274 | 303.45 | 114.76 | 0.936697 | 共用-1 | 114.76 | 34 | 70.83 | 114.76 ㎡ | 34 坪 | 70.83 帖 | 235.207 | 191.947 | 100900 | 101150 | 344.293 | 320.274 | 18000 | 0 | 21000 | 11 | 10 | 21 | 0 | 20 | 43.26 | 20600 | 99400 | 20400 | 16.3949 | 22.9529 | 11.4764 | 2.29529 | 5.73822 | 7FL
＜ゾーン番号＞ | 7FL | 廊下 | Z5 | 7FLZ5 | yes | 7FL | 7 | リンクなし | リンクなし | リンクなし | 16.3719 | 18.2381 | 4 | 0 | 50.6455 | 10.71 | 49.1156 | 70.2 | 18.23 | 6.10804 | 共用-1 | 18.23 | 5 | 11.25 | 18.23 ㎡ | 5 坪 | 11.25 帖 | 55.2655 | 44.5555 | 24100 | 23400 | 54.7144 | 49.1156 | 18000 | 0 | 21000 | 3 | 3 | 5 | 0 | 4 | 10.71 | 5100 | 23400 | 5100 | 2.60545 | 3.64762 | 1.82381 | 0.364762 | 0.911906 | 7FL
＜ゾーン番号＞ | 7FL | 多目的トイレ | Z6 | 7FLZ6 | yes | 7FL | 7 | リンクなし | リンクなし | リンクなし | 5.48375 | 6.215 | 4 | 0 | 21.4879 | 2.31 | 16.4513 | 28.35 | 6.21 | 18.2357 | 共用-1 | 6.21 | 1 | 3.83 | 6.21 ㎡ | 1 坪 | 3.83 帖 | 21.4879 | 19.1779 | 10050 | 9450 | 18.645 | 16.4512 | 18000 | 0 | 21000 | 1 | 0 | 1 | 0 | 4 | 2.31 | 1100 | 9450 | 1100 | 0.887857 | 1.243 | 0.6215 | 0.1243 | 0.31075 | 7FL
＜ゾーン番号＞ | 8FL | 女性用トイレ | Z6 | 8FLZ6 | yes | 8FL | 8 | リンクなし | リンクなし | リンクなし | 8.53875 | 9.585 | 4 | 0 | 37.2312 | 1.47 | 25.6163 | 40.95 | 9.58 | 11.7113 | 共用-1 | 9.58 | 2 | 5.91 | 9.58 ㎡ | 2 坪 | 5.91 帖 | 34.9737 | 33.5037 | 14250 | 13650 | 28.755 | 25.6162 | 21000 | 0 | 24000 | 2 | 0 | 1 | 0 | 4 | 1.47 | 700 | 13650 | 700 | 1.36929 | 1.917 | 0.9585 | 0.1917 | 0.47925 | 8FL
＜ゾーン番号＞ | 8FL | 男性用トイレ | Z6 | 8FLZ6 | yes | 8FL | 8 | リンクなし | リンクなし | リンクなし | 10.6219 | 12.3806 | 8 | 2 | 34.1162 | 1.47 | 31.8656 | 44.1 | 12.38 | 9.41453 | 共用-1 | 12.38 | 3 | 7.64 | 12.38 ㎡ | 3 坪 | 7.64 帖 | 32.0074 | 30.5374 | 15300 | 14700 | 37.1419 | 31.8656 | 21000 | 0 | 24000 | 3 | 2 | 1 | 0 | 4 | 1.47 | 700 | 12425 | 700 | 1.76866 | 2.47613 | 1.23806 | 0.247613 | 0.619031 | 8FL
＜ゾーン番号＞ | 8FL | EVホール | Z4 | 8FLZ4 | yes | 8FL | 8 | リンクなし | リンクなし | リンクなし | 106.758 | 114.764 | 23 | 9 | 218.649 | 42.84 | 320.274 | 303.45 | 114.76 | 0.936697 | 共用-1 | 114.76 | 34 | 70.83 | 114.76 ㎡ | 34 坪 | 70.83 帖 | 235.207 | 191.947 | 100900 | 101150 | 344.293 | 320.274 | 21000 | 0 | 24000 | 11 | 10 | 21 | 0 | 20 | 43.26 | 20600 | 99400 | 20400 | 16.3949 | 22.9529 | 11.4764 | 2.29529 | 5.73822 | 8FL
＜ゾーン番号＞ | 8FL | 廊下 | Z5 | 8FLZ5 | yes | 8FL | 8 | リンクなし | リンクなし | リンクなし | 16.3719 | 18.2381 | 4 | 0 | 50.6455 | 10.71 | 49.1156 | 70.2 | 18.23 | 6.10804 | 共用-1 | 18.23 | 5 | 11.25 | 18.23 ㎡ | 5 坪 | 11.25 帖 | 55.2655 | 44.5555 | 24100 | 23400 | 54.7144 | 49.1156 | 21000 | 0 | 24000 | 3 | 3 | 5 | 0 | 4 | 10.71 | 5100 | 23400 | 5100 | 2.60545 | 3.64762 | 1.82381 | 0.364762 | 0.911906 | 8FL
＜ゾーン番号＞ | 8FL | 多目的トイレ | Z6 | 8FLZ6 | yes | 8FL | 8 | リンクなし | リンクなし | リンクなし | 5.48375 | 6.215 | 4 | 0 | 21.4879 | 2.31 | 16.4513 | 28.35 | 6.21 | 18.2357 | 共用-1 | 6.21 | 1 | 3.83 | 6.21 ㎡ | 1 坪 | 3.83 帖 | 21.4879 | 19.1779 | 10050 | 9450 | 18.645 | 16.4512 | 21000 | 0 | 24000 | 1 | 0 | 1 | 0 | 4 | 2.31 | 1100 | 9450 | 1100 | 0.887857 | 1.243 | 0.6215 | 0.1243 | 0.31075 | 8FL
＜ゾーン番号＞ | 9FL | 女性用トイレ | Z6 | 9FLZ6 | yes | 9FL | 9 | リンクなし | リンクなし | リンクなし | 8.53875 | 9.585 | 4 | 0 | 37.2312 | 1.47 | 25.6163 | 40.95 | 9.58 | 11.7113 | 共用-1 | 9.58 | 2 | 5.91 | 9.58 ㎡ | 2 坪 | 5.91 帖 | 34.9737 | 33.5037 | 14250 | 13650 | 28.755 | 25.6162 | 24000 | 0 | 27000 | 2 | 0 | 1 | 0 | 4 | 1.47 | 700 | 13650 | 700 | 1.36929 | 1.917 | 0.9585 | 0.1917 | 0.47925 | 9FL
＜ゾーン番号＞ | 9FL | 男性用トイレ | Z6 | 9FLZ6 | yes | 9FL | 9 | リンクなし | リンクなし | リンクなし | 10.6219 | 12.3806 | 8 | 2 | 34.1162 | 1.47 | 31.8656 | 44.1 | 12.38 | 9.41453 | 共用-1 | 12.38 | 3 | 7.64 | 12.38 ㎡ | 3 坪 | 7.64 帖 | 32.0074 | 30.5374 | 15300 | 14700 | 37.1419 | 31.8656 | 24000 | 0 | 27000 | 3 | 2 | 1 | 0 | 4 | 1.47 | 700 | 12425 | 700 | 1.76866 | 2.47613 | 1.23806 | 0.247613 | 0.619031 | 9FL
＜ゾーン番号＞ | 9FL | EVホール | Z4 | 9FLZ4 | yes | 9FL | 9 | リンクなし | リンクなし | リンクなし | 106.758 | 114.764 | 23 | 9 | 218.649 | 42.84 | 320.274 | 303.45 | 114.76 | 0.936697 | 共用-1 | 114.76 | 34 | 70.83 | 114.76 ㎡ | 34 坪 | 70.83 帖 | 235.207 | 191.947 | 100900 | 101150 | 344.293 | 320.274 | 24000 | 0 | 27000 | 11 | 10 | 21 | 0 | 20 | 43.26 | 20600 | 99400 | 20400 | 16.3949 | 22.9529 | 11.4764 | 2.29529 | 5.73822 | 9FL
＜ゾーン番号＞ | 9FL | 廊下 | Z5 | 9FLZ5 | yes | 9FL | 9 | リンクなし | リンクなし | リンクなし | 16.3719 | 18.2381 | 4 | 0 | 50.6455 | 10.71 | 49.1156 | 70.2 | 18.23 | 6.10804 | 共用-1 | 18.23 | 5 | 11.25 | 18.23 ㎡ | 5 坪 | 11.25 帖 | 55.2655 | 44.5555 | 24100 | 23400 | 54.7144 | 49.1156 | 24000 | 0 | 27000 | 3 | 3 | 5 | 0 | 4 | 10.71 | 5100 | 23400 | 5100 | 2.60545 | 3.64762 | 1.82381 | 0.364762 | 0.911906 | 9FL
＜ゾーン番号＞ | 9FL | 多目的トイレ | Z6 | 9FLZ6 | yes | 9FL | 9 | リンクなし | リンクなし | リンクなし | 5.48375 | 6.215 | 4 | 0 | 21.4879 | 2.31 | 16.4513 | 28.35 | 6.21 | 18.2357 | 共用-1 | 6.21 | 1 | 3.83 | 6.21 ㎡ | 1 坪 | 3.83 帖 | 21.4879 | 19.1779 | 10050 | 9450 | 18.645 | 16.4512 | 24000 | 0 | 27000 | 1 | 0 | 1 | 0 | 4 | 2.31 | 1100 | 9450 | 1100 | 0.887857 | 1.243 | 0.6215 | 0.1243 | 0.31075 | 9FL

# IfcSpace: 共用-2 (9)
LongName: 避難階段; InteriorOrExteriorSpace: INTERNAL; Classification: スペース (ARCHICAD 分類); 共用-2 共用-2
Pset_SpaceCommon - Category: 共用-2
ArchiCADProperties - 要素ID: Z8; レイヤー: ゾーン; ライブラリ部品名: ゾーン_仕上用; 関連ゾーン名: 避難階段; 関連ゾーン番号: ＜ゾーン番号＞; 要素タイプ: ゾーン; 親ID: Z8; 材質 (全て): ゾーン - 05; 表面塗りつぶし: 背景; リノベーションフィルタで表示: 全ての関連フィルタ; リノベーションステータス: 既存; 材質: ゾーン - 05; 同一材質: yes; ゾーン名: 避難階段; ゾーン番号: ＜ゾーン番号＞; ゾーンカテゴリ: 0; ゾーンカテゴリコード: 共用-2; ARCHICAD 分類 - v 2.0: スペース
AC_Pset_ゾーン_仕上用 - マーカーテキスト1サイズ(デフォルト): 2; マーカーテキスト1スタイル(デフォルト): 0; マーカーテキスト1 整列(デフォルト): 1; マーカーテキスト1 改行幅(デフォルト): 0; マーカーテキスト1 文字幅(デフォルト): 1; マーカーテキスト1 テキスト文字間隔(デフォルト): 1; テキストフォント1: Meiryo Japanese; ゾーン名 (ROOM_NAME): 避難階段; ゾーン番号 (ROOM_NUMBER): ＜ゾーン番号＞; 窓表面積: 0; 抽出壁面積: 0; 抽出カーテンウォール面積: 0; 抽出柱面積: 0; 抽出塗りつぶし面積: 0; 抽出床面積: 0; 抽出総面積: 0; ゾーン面積係数: 1; 上部屋根表面積: 0; 下部屋根表面積: 0; 上部スラブ表面積: 0; 下部スラブ表面積: 0; 下部梁表面積: 0; 下部梁表面: 0; 上部壁インセット表面積: 0; 壁インセット背面: 0; 側面壁インセット表面積: 0; 詳細: 1; 固定スタンプ表示 (stChangebyScale): 1：50まで; 固定スタンプ表示 (iChangebyScale): 1; ゾーンスタンプタイプ: 1; 面積値表示: 1; 一行で表示するスケール: 400; 室名: yes; ソーン名文字揃え: 2; 枠線 (bFrameRoomName): no; ゾーン番号 (bZoneNum): no; ゾーン番号タイプ: 1; IDを表示...: 1; 枠線 (bFrameZoneNum): no; 床タイプ: no; 床タイプ名称: ＜フロア タイプ＞; 枠線 (bFrameFloor): no; 面積表示: yes; 平米丸め（小数点）: ２桁; 平米単位表示: 1; 坪表示: no; 坪小数点以下表示: なし; 坪単位表示: 1; 畳表示: no; 帖、Ｊ表示: 帖; 畳単位表示: 1; 帖数小数点: ２桁; 畳係数: 1.62; 枠線 (bFrameArea): no; 外周: no; 枠線 (bFramePeri): no; CH=表示: no; CH=: 2400; 枠線 (bFrameCeil): no; FL又はSL表示: no; FL/SL値: ＋50; FL/SL文字: SL; 枠線 (bFrameFloorlabel): no; スラブ厚: 160; コンクリート天端レベル: ±0; 排煙記号: no; 排煙種類: 未定; 枠線 (bFrameSmokesign): no; 内装制限記号: no; 内装制限種類: 未定; 枠線 (bFrameInterior): no; カテゴリとプロパティを表示: no; 枠線 (bFrameTnC): yes; 枠幅設定: 余白あり; 枠幅桁数: 14; 表示精度: 1; 坪、畳は丸めた平米値で計算する: yes; ------------------: -------------; 角度: 0 deg; 表面塗りつぶし: no; 背景塗つぶしタイプ: 50 %; 表面塗りつぶしペン背景: 透過; 空調タイプ: 日当り空調室; 編集する床の下地を選択: 1; 床＿仕上: 磁器タイル; 床＿下地: RC; 床＿下地2: RC; 床＿下地3: RC; 床＿下地4: RC; 床＿下地5: RC; 巾木: ソフト巾木; 壁仕上げ: 磁器タイル; 編集する壁の下地を選択: 4; 壁＿下地: RC; 壁＿下地2: RC; 壁＿下地3: RC; 壁＿下地4: RC; 壁＿下地5: RC; 天井＿仕上: クロス貼; 編集する天井の下地を選択: 1; 天井＿下地: 軽鉄野縁; 天井＿下地2: 軽鉄野縁; 天井＿下地3: 軽鉄野縁; 天井＿下地4: 軽鉄野縁; 天井＿下地5: 軽鉄野縁; 廻り縁: 廻縁 塩ビ; 面積区分: 1; 面積対象: 1; 換気タイプ: タイプ1; 給気量（A）m3/h: 300; 排気量（B）m3/h: 300; カテゴリ名称: 共用-2; ゾーン名 (stZoneName): 避難階段; 天井高テキスト: 3,000; 坪: 3; 坪テキスト: 3 坪; 床＿下地テキスト: RC/RC/RC/RC/RC; 壁＿下地テキスト: RC/RC/RC/RC/RC; 天井＿下地テキスト: 軽鉄野縁/軽鉄野縁/軽鉄野縁/軽鉄野縁/軽鉄野縁; 巾木高さ値（mm）: 75; パラメータを選択: 1; データを表示: 1; 1. 列 パラメータ名を次のように表示: 1; 2. 列 パラメータ名を次のように表示: 1; 3. 列 パラメータ名を次のように表示: 1; 4. 列 パラメータ名を次のように表示: 1; 5. 列 パラメータ名を次のように表示: 1; 6. 列 パラメータ名を次のように表示: 1; 7. 列 パラメータ名を次のように表示: 1; 8. 列 パラメータ名を次のように表示: 1; 9. 列 パラメータ名を次のように表示: 1; 10. 列 パラメータ名を次のように表示: 1; 11. 列 パラメータ名を次のように表示: 1; 12. 列 パラメータ名を次のように表示: 1; 13. 列 パラメータ名を次のように表示: 1; 14. 列 パラメータ名を次のように表示: 1; 15. 列 パラメータ名を次のように表示: 1; 16. 列 パラメータ名を次のように表示: 1; 17. 列 パラメータ名を次のように表示: 1; 18. 列 パラメータ名を次のように表示: 1; 19. 列 パラメータ名を次のように表示: 1; 20. 列 パラメータ名を次のように表示: 1
室情報 - 利用者数: 0; 一人あたりの必要面積: 0 m2
AC_Pset_RenovationAndPhasing - Renovation Status: Existing
BaseQuantities - Height: 3000 mm; FinishCeilingHeight: 3000 mm; FinishFloorHeight: 0 mm; ClearHeight: 3000 mm
ArchiCADQuantities - 高さ: 3000 mm; リンク/配置フロアまでの高度: 0 mm; 下部オフセット: 0 mm; 上部オフセット: 0 mm; 平面図穴外周: 0 mm; 上端高度から配置フロア: 3000 mm; 下端高度から配置フロア: 0 mm; 基準レベル: 0 mm; 梁数: 0; 柱数: 1; ランプ数: 0; オブジェクト数: 0; 窓数: 0; 壁部品数: 1; 窓表面積: 0 m2; 窓幅: 0 mm; 壁外周: 2453.67 mm; フロア厚さ: 0 mm; 面積縮小: 1 m2; 抜き取られる柱面積: 0 m2; 抜き取られる塗りつぶし面積: 0 m2; 抜き取られる底面積: 0 m2; 抜き取られる壁面積: 0 m2; 抜き取られる総面積: 0 m2; 壁のインセット背面表面積: 0 m2; 壁インセット側面表面積: 0 m2; 壁インセット上部表面積: 0 m2
AC_Equantity_ゾーン_仕上用 - 穴外周: 0 mm; 外壁長さ: 2453.67 mm; 窓組み合わせ幅: 0 mm; フロアレベル: 0 mm; サブフロア厚さ: 0 mm; 高さ: 3000 mm; 巾木高さ: 75 mm; 腰高: 1000 mm; 平均天井高: 3000 mm
Name | In | ホットリンクおよび要素ID | ロック状態 | ホームフロア名 | ホームフロア数 | 絶対上部リンクフロア | 相対上部リンクフロア | 上部リンクフロア | 縮小された面積 = AC_Pset_ゾーン_仕上用, 測定正味面積 = 縮小面積 = 計算面積 (ROOM_CALC_AREA) = 上部表面積 = 下部材質面積 = NetFloorArea (m2) = SpaceNetFloorAreaBOMA (m2) = SpaceUsableFloorAreaBOMA (m2) = NetCeilingArea (m2) = 計算した面積 (m2) = ArchiCADQuantities, 測定正味面積 (m2) | AC_Pset_ゾーン_仕上用, 測定面積 = GrossFloorArea (m2) = GrossCeilingArea (m2) = 面積 (m2) = ArchiCADQuantities, 測定面積 (m2) | 全コーナー数 = 角数 | 凹型コーナー数 = 全てのへこみ角数 | 外壁表面積 | AC_Pset_ゾーン_仕上用, ドア表面積 = ArchiCADQuantities, ドア表面積 (m2) | 体積 = 気積 = NetVolume (m3) = 正味体積 (m3) | 境界表面積 | 計算面積 (stAreaDisp) = 面積値 | 換気回数 | 畳 | 面積テキスト | 畳テキスト | GrossWallArea (m2) | NetWallArea (m2) = 壁表面積 (m2) | GrossPerimeter (mm) = ゾーン総外周 (mm) = 外周 (mm) | NetPerimeter (mm) = ゾーン正味外周 (mm) = 正味外周 (mm) | GrossVolume (m3) | GLからの高度 (mm) = 高度 1 (mm) = 高度 2 (mm) = 海抜までの高度 (mm) = 下端高度から第1基準レベル (mm) = 下端高度から基準レベル (mm) = 下端高度から海抜 (mm) = 下端高度から第2基準レベル (mm) | 上端高度から第1基準レベル (mm) = 上端高度から基準レベル (mm) = 上端高度から海抜 (mm) = 上端高度から第2基準レベル (mm) | ドア数 | ドア幅 (mm) = ドア組み合わせ幅 (mm) | 居室に必要な採光面積 (m2) = 病院福祉施設等に必要な採光面積 (m2) | 教育施設に必要な採光面積 (m2) | その他に必要な採光面積 (m2) | 自然排煙必要面積(ゾーン) (m2) | 必要換気量（ゾーン） (m2) | ホットリンク マスタID
＜ゾーン番号＞ | 1FL | Z8 | no | 1FL | 1 | 2FL | 配置フロア + 1 | 配置フロア + 1 (2FL) | 10.9188 | 11.2255 | 4 | 0 | 4.64722 | 12.1061 | 32.7565 | 41.422 | 11.22 | 9.15849 | 6.92 | 11.22 ㎡ | 6.92 帖 | 16.7533 | 4.64722 | 14057.3 | 13807.3 | 33.6766 | 0 | 3000 | 0 | 5340 | 1.60365 | 2.24511 | 1.12255 | 0.224511 | 0.561277
＜ゾーン番号＞ | 2FL | Z8 | no | 2FL | 2 | 3FL | 配置フロア + 1 | 配置フロア + 1 (3FL) | 10.9188 | 11.2255 | 4 | 0 | 2.17642 | 2.31 | 32.7565 | 41.422 | 11.22 | 9.15849 | 6.92 | 11.22 ㎡ | 6.92 帖 | 4.48642 | 2.17642 | 14057.3 | 13807.3 | 33.6766 | 3000 | 6000 | 1 | 1100 | 1.60365 | 2.24511 | 1.12255 | 0.224511 | 0.561277
＜ゾーン番号＞ | 3FL | Z8 | no | 3FL | 3 | 4FL | 配置フロア + 1 | 配置フロア + 1 (4FL) | 10.839 | 11.1457 | 11 | 4 | 2.79021 | 2.31 | 32.517 | 41.7743 | 11.14 | 9.22595 | 6.87 | 11.14 ㎡ | 6.87 帖 | 4.48642 | 2.17642 | 14174.8 | 13924.8 | 33.4371 | 6000 | 9000 | 1 | 1100 | 1.59224 | 2.22914 | 1.11457 | 0.222914 | 0.557285
＜ゾーン番号＞ | 4FL | 4FLZ8 | yes | 4FL | 4 | リンクなし | リンクなし | リンクなし | 10.839 | 11.1457 | 11 | 4 | 2.79021 | 2.31 | 32.517 | 41.7743 | 11.14 | 9.22595 | 6.87 | 11.14 ㎡ | 6.87 帖 | 4.48642 | 2.17642 | 14174.8 | 13924.8 | 33.4371 | 9000 | 12000 | 1 | 1100 | 1.59224 | 2.22914 | 1.11457 | 0.222914 | 0.557285 | 4FL
＜ゾーン番号＞ | 5FL | 5FLZ8 | yes | 5FL | 5 | リンクなし | リンクなし | リンクなし | 10.839 | 11.1457 | 11 | 4 | 2.79021 | 2.31 | 32.517 | 41.7743 | 11.14 | 9.22595 | 6.87 | 11.14 ㎡ | 6.87 帖 | 4.48642 | 2.17642 | 14174.8 | 13924.8 | 33.4371 | 12000 | 15000 | 1 | 1100 | 1.59224 | 2.22914 | 1.11457 | 0.222914 | 0.557285 | 5FL
＜ゾーン番号＞ | 6FL | 6FLZ8 | yes | 6FL | 6 | リンクなし | リンクなし | リンクなし | 10.839 | 11.1457 | 11 | 4 | 2.79021 | 2.31 | 32.517 | 41.7743 | 11.14 | 9.22595 | 6.87 | 11.14 ㎡ | 6.87 帖 | 4.48642 | 2.17642 | 14174.8 | 13924.8 | 33.4371 | 15000 | 18000 | 1 | 1100 | 1.59224 | 2.22914 | 1.11457 | 0.222914 | 0.557285 | 6FL
＜ゾーン番号＞ | 7FL | 7FLZ8 | yes | 7FL | 7 | リンクなし | リンクなし | リンクなし | 10.839 | 11.1457 | 11 | 4 | 2.79021 | 2.31 | 32.517 | 41.7743 | 11.14 | 9.22595 | 6.87 | 11.14 ㎡ | 6.87 帖 | 4.48642 | 2.17642 | 14174.8 | 13924.8 | 33.4371 | 18000 | 21000 | 1 | 1100 | 1.59224 | 2.22914 | 1.11457 | 0.222914 | 0.557285 | 7FL
＜ゾーン番号＞ | 8FL | 8FLZ8 | yes | 8FL | 8 | リンクなし | リンクなし | リンクなし | 10.839 | 11.1457 | 11 | 4 | 2.79021 | 2.31 | 32.517 | 41.7743 | 11.14 | 9.22595 | 6.87 | 11.14 ㎡ | 6.87 帖 | 4.48642 | 2.17642 | 14174.8 | 13924.8 | 33.4371 | 21000 | 24000 | 1 | 1100 | 1.59224 | 2.22914 | 1.11457 | 0.222914 | 0.557285 | 8FL
＜ゾーン番号＞ | 9FL | 9FLZ8 | yes | 9FL | 9 | リンクなし | リンクなし | リンクなし | 10.839 | 11.1457 | 11 | 4 | 2.79021 | 2.31 | 32.517 | 41.7743 | 11.14 | 9.22595 | 6.87 | 11.14 ㎡ | 6.87 帖 | 4.48642 | 2.17642 | 14174.8 | 13924.8 | 33.4371 | 24000 | 27000 | 1 | 1100 | 1.59224 | 2.22914 | 1.11457 | 0.222914 | 0.557285 | 9FL

# IfcSpace: 店舗 (22)
LongName: 店舗; InteriorOrExteriorSpace: INTERNAL; Classification: スペース (ARCHICAD 分類); 店舗 店舗
Pset_SpaceCommon - Category: 店舗
ArchiCADProperties - レイヤー: ゾーン; ライブラリ部品名: ゾーン_仕上用; 関連ゾーン名: 店舗; ロック状態: no; 要素タイプ: ゾーン; 相対上部リンクフロア: 配置フロア + 1; 材質 (全て): ゾーン - 05; 表面塗りつぶし: 背景; リノベーションフィルタで表示: 全ての関連フィルタ; リノベーションステータス: 既存; 材質: ゾーン - 05; 同一材質: yes; ゾーン名: 店舗; ゾーンカテゴリ: 0; ゾーンカテゴリコード: 店舗; ARCHICAD 分類 - v 2.0: スペース
AC_Pset_ゾーン_仕上用 - マーカーテキスト1サイズ(デフォルト): 2; マーカーテキスト1スタイル(デフォルト): 0; マーカーテキスト1 整列(デフォルト): 1; マーカーテキスト1 改行幅(デフォルト): 0; マーカーテキスト1 文字幅(デフォルト): 1; マーカーテキスト1 テキスト文字間隔(デフォルト): 1; テキストフォント1: Meiryo Japanese; ゾーン名 (ROOM_NAME): 店舗; 窓表面積: 0; 抽出壁面積: 0; 抽出カーテンウォール面積: 0; 抽出柱面積: 0; 抽出塗りつぶし面積: 0; 抽出床面積: 0; 抽出総面積: 0; ゾーン面積係数: 1; 上部屋根表面積: 0; 下部屋根表面積: 0; 上部スラブ表面積: 0; 下部スラブ表面積: 0; 下部梁表面積: 0; 下部梁表面: 0; 上部壁インセット表面積: 0; 壁インセット背面: 0; 側面壁インセット表面積: 0; 詳細: 1; 固定スタンプ表示 (stChangebyScale): 1：50まで; 固定スタンプ表示 (iChangebyScale): 1; ゾーンスタンプタイプ: 1; 面積値表示: 1; 一行で表示するスケール: 400; 室名: yes; ソーン名文字揃え: 2; 枠線 (bFrameRoomName): no; ゾーン番号 (bZoneNum): no; ゾーン番号タイプ: 1; IDを表示...: 1; 枠線 (bFrameZoneNum): no; 床タイプ: no; 床タイプ名称: ＜フロア タイプ＞; 枠線 (bFrameFloor): no; 面積表示: yes; 平米丸め（小数点）: ２桁; 平米単位表示: 1; 坪表示: no; 坪小数点以下表示: なし; 坪単位表示: 1; 畳表示: no; 帖、Ｊ表示: 帖; 畳単位表示: 1; 帖数小数点: ２桁; 畳係数: 1.62; 枠線 (bFrameArea): no; 外周: no; 枠線 (bFramePeri): no; CH=表示: no; CH=: 2400; 枠線 (bFrameCeil): no; FL又はSL表示: no; FL/SL値: ＋50; FL/SL文字: SL; 枠線 (bFrameFloorlabel): no; スラブ厚: 160; コンクリート天端レベル: ±0; 排煙記号: no; 排煙種類: 未定; 枠線 (bFrameSmokesign): no; 内装制限記号: no; 内装制限種類: 未定; 枠線 (bFrameInterior): no; カテゴリとプロパティを表示: no; 枠線 (bFrameTnC): yes; 枠幅設定: 余白あり; 枠幅桁数: 14; 表示精度: 1; 坪、畳は丸めた平米値で計算する: yes; ------------------: -------------; 角度: 0 deg; 表面塗りつぶし: no; 背景塗つぶしタイプ: 50 %; 表面塗りつぶしペン背景: 透過; 空調タイプ: 日当り空調室; 編集する床の下地を選択: 1; 床＿仕上: 磁器タイル; 床＿下地: RC; 床＿下地2: RC; 床＿下地3: RC; 床＿下地4: RC; 床＿下地5: RC; 巾木: ソフト巾木; 壁仕上げ: 磁器タイル; 編集する壁の下地を選択: 4; 壁＿下地: RC; 壁＿下地2: RC; 壁＿下地3: RC; 壁＿下地4: RC; 壁＿下地5: RC; 天井＿仕上: クロス貼; 編集する天井の下地を選択: 1; 天井＿下地: 軽鉄野縁; 天井＿下地2: 軽鉄野縁; 天井＿下地3: 軽鉄野縁; 天井＿下地4: 軽鉄野縁; 天井＿下地5: 軽鉄野縁; 廻り縁: 廻縁 塩ビ; 面積区分: 1; 面積対象: 1; 換気タイプ: タイプ1; 給気量（A）m3/h: 300; 排気量（B）m3/h: 300; ゾーン名 (stZoneName): 店舗; 天井高テキスト: 3,000; 床＿下地テキスト: RC/RC/RC/RC/RC; 壁＿下地テキスト: RC/RC/RC/RC/RC; 天井＿下地テキスト: 軽鉄野縁/軽鉄野縁/軽鉄野縁/軽鉄野縁/軽鉄野縁; 巾木高さ値（mm）: 75; パラメータを選択: 1; データを表示: 1; 1. 列 パラメータ名を次のように表示: 1; 2. 列 パラメータ名を次のように表示: 1; 3. 列 パラメータ名を次のように表示: 1; 4. 列 パラメータ名を次のように表示: 1; 5. 列 パラメータ名を次のように表示: 1; 6. 列 パラメータ名を次のように表示: 1; 7. 列 パラメータ名を次のように表示: 1; 8. 列 パラメータ名を次のように表示: 1; 9. 列 パラメータ名を次のように表示: 1; 10. 列 パラメータ名を次のように表示: 1; 11. 列 パラメータ名を次のように表示: 1; 12. 列 パラメータ名を次のように表示: 1; 13. 列 パラメータ名を次のように表示: 1; 14. 列 パラメータ名を次のように表示: 1; 15. 列 パラメータ名を次のように表示: 1; 16. 列 パラメータ名を次のように表示: 1; 17. 列 パラメータ名を次のように表示: 1; 18. 列 パラメータ名を次のように表示: 1; 19. 列 パラメータ名を次のように表示: 1; 20. 列 パラメータ名を次のように表示: 1
室情報 - 利用者数: 0; 一人あたりの必要面積: 0 m2
AC_Pset_RenovationAndPhasing - Renovation Status: Existing
BaseQuantities - Height: 3000 mm; FinishCeilingHeight: 3000 mm; FinishFloorHeight: 0 mm; ClearHeight: 3000 mm
ArchiCADQuantities - 高さ: 3000 mm; リンク/配置フロアまでの高度: 0 mm; 下部オフセット: 0 mm; 上部オフセット: 0 mm; 上端高度から配置フロア: 3000 mm; 下端高度から配置フロア: 0 mm; 基準レベル: 0 mm; ランプ数: 0; 窓数: 0; 窓表面積: 0 m2; 窓幅: 0 mm; フロア厚さ: 0 mm; 面積縮小: 1 m2; 抜き取られる柱面積: 0 m2; 抜き取られる塗りつぶし面積: 0 m2; 抜き取られる底面積: 0 m2; 抜き取られる壁面積: 0 m2; 抜き取られる総面積: 0 m2; 壁のインセット背面表面積: 0 m2; 壁インセット側面表面積: 0 m2; 壁インセット上部表面積: 0 m2
AC_Equantity_ゾーン_仕上用 - 窓組み合わせ幅: 0 mm; フロアレベル: 0 mm; サブフロア厚さ: 0 mm; 高さ: 3000 mm; 巾木高さ: 75 mm; 腰高: 1000 mm; 平均天井高: 3000 mm
Name | In | 要素ID = ホットリンクおよび要素ID = 親ID | 関連ゾーン番号 = ゾーン番号 = ゾーン番号 (ROOM_NUMBER) | ホームフロア名 | ホームフロア数 | 絶対上部リンクフロア | 上部リンクフロア | 縮小された面積 = AC_Pset_ゾーン_仕上用, 測定正味面積 = 縮小面積 = 計算面積 (ROOM_CALC_AREA) = 上部表面積 = 下部材質面積 = NetFloorArea (m2) = SpaceNetFloorAreaBOMA (m2) = SpaceUsableFloorAreaBOMA (m2) = NetCeilingArea (m2) = 計算した面積 (m2) = ArchiCADQuantities, 測定正味面積 (m2) | AC_Pset_ゾーン_仕上用, 測定面積 = GrossFloorArea (m2) = GrossCeilingArea (m2) = 面積 (m2) = ArchiCADQuantities, 測定面積 (m2) | 全コーナー数 = 角数 | 凹型コーナー数 = 全てのへこみ角数 | 外壁表面積 | AC_Pset_ゾーン_仕上用, ドア表面積 | 体積 = 気積 = NetVolume (m3) = 正味体積 (m3) | 境界表面積 | 計算面積 (stAreaDisp) | 換気回数 | カテゴリ名称 | 面積値 | 坪 | 畳 | 面積テキスト | 坪テキスト | 畳テキスト | GrossWallArea (m2) | NetWallArea (m2) = 壁表面積 (m2) | GrossPerimeter (mm) = ゾーン総外周 (mm) = 外周 (mm) | NetPerimeter (mm) = ゾーン正味外周 (mm) = 正味外周 (mm) | GrossVolume (m3) | GLからの高度 (mm) = 高度 1 (mm) = 高度 2 (mm) = 海抜までの高度 (mm) = 下端高度から第1基準レベル (mm) = 下端高度から基準レベル (mm) = 下端高度から海抜 (mm) = 下端高度から第2基準レベル (mm) | 平面図穴外周 (mm) = 穴外周 (mm) | 上端高度から第1基準レベル (mm) = 上端高度から基準レベル (mm) = 上端高度から海抜 (mm) = 上端高度から第2基準レベル (mm) | 梁数 | 柱数 | ドア数 | オブジェクト数 | 壁部品数 | ArchiCADQuantities, ドア表面積 (m2) | ドア幅 (mm) | 壁外周 (mm) = 外壁長さ (mm) | ドア組み合わせ幅 (mm) | 居室に必要な採光面積 (m2) = 病院福祉施設等に必要な採光面積 (m2) | 教育施設に必要な採光面積 (m2) | その他に必要な採光面積 (m2) | 自然排煙必要面積(ゾーン) (m2) | 必要換気量（ゾーン） (m2)
101 | 1FL | Z7 | 101 | 1FL | 1 | 2FL | 配置フロア + 1 (2FL) | 96.5435 | 101.983 | 20 | 8 | 79.0974 | 3.36 | 289.631 | 126.056 | 101.98 | 1.0358 | 店舗 | 101.98 | 30 | 62.95 | 101.98 ㎡ | 30 坪 | 62.95 帖 | 82.4574 | 79.0974 | 40534.5 | 42018.7 | 305.948 | 0 | 0 | 3000 | 7 | 6 | 1 | 0 | 6 | 3.36 | 1600 | 34649.2 | 1600 | 14.569 | 20.3966 | 10.1983 | 2.03966 | 5.09914
102 | 1FL | Z8 | 102 | 1FL | 1 | 2FL | 配置フロア + 1 (2FL) | 43.5072 | 46.6568 | 13 | 4 | 50.3793 | 5.25 | 130.522 | 83.2531 | 46.65 | 2.29847 | 店舗 | 46.65 | 14 | 28.79 | 46.65 ㎡ | 14 坪 | 28.79 帖 | 55.6293 | 50.3793 | 28381.1 | 27751 | 139.97 | 0 | 0 | 3000 | 4 | 4 | 2 | 0 | 5 | 5.25 | 2500 | 23691.3 | 2500 | 6.66525 | 9.33135 | 4.66568 | 0.933135 | 2.33284
103 | 1FL | Z8 | 103 | 1FL | 1 | 2FL | 配置フロア + 1 (2FL) | 41.76 | 44.935 | 13 | 4 | 48.3294 | 5.25 | 125.28 | 81 | 44.93 | 2.39464 | 店舗 | 44.93 | 13 | 27.73 | 44.93 ㎡ | 13 坪 | 27.73 帖 | 53.5794 | 48.3294 | 27650 | 27000 | 134.805 | 0 | 0 | 3000 | 4 | 4 | 2 | 0 | 5 | 5.25 | 2500 | 22800 | 2500 | 6.41929 | 8.987 | 4.4935 | 0.8987 | 2.24675
104 | 1FL | Z8 | 104 | 1FL | 1 | 2FL | 配置フロア + 1 (2FL) | 144.361 | 152.454 | 30 | 16 | 107.152 | 5.21021 | 433.084 | 172.268 | 152.45 | 0.692706 | 店舗 | 152.45 | 46 | 94.1 | 152.45 ㎡ | 46 坪 | 94.10 帖 | 112.362 | 107.152 | 50440.2 | 57422.7 | 457.362 | 0 | 3200 | 3000 | 9 | 8 | 2 | 2 | 7 | 5.21021 | 2481.05 | 43912.7 | 2481.05 | 21.7791 | 30.4908 | 15.2454 | 3.04908 | 7.6227
105 | 1FL | Z8 | 105 | 1FL | 1 | 2FL | 配置フロア + 1 (2FL) | 61.8409 | 66.2713 | 18 | 7 | 80.4298 | 1.89 | 185.523 | 115.211 | 66.27 | 1.61705 | 店舗 | 66.27 | 20 | 40.9 | 66.27 ㎡ | 20 坪 | 40.90 帖 | 82.144 | 76.894 | 37514.7 | 38403.7 | 198.814 | 0 | 0 | 3000 | 6 | 4 | 2 | 0 | 8 | 5.25 | 2500 | 34099 | 900 | 9.46733 | 13.2543 | 6.62713 | 1.32543 | 3.31356
106 | 1FL | Z9 | 106 | 1FL | 1 | 2FL | 配置フロア + 1 (2FL) | 60.6961 | 64.1588 | 16 | 6 | 77.7835 | 1.89 | 182.088 | 108.886 | 64.15 | 1.64755 | 店舗 | 64.15 | 19 | 39.59 | 64.15 ㎡ | 19 坪 | 39.59 帖 | 79.4977 | 74.2477 | 35701.1 | 36295.4 | 192.476 | 0 | 0 | 3000 | 6 | 4 | 2 | 1 | 6 | 5.25 | 2500 | 32797.3 | 900 | 9.16554 | 12.8318 | 6.41588 | 1.28318 | 3.20794
107 | 1FL | Z0 | 107 | 1FL | 1 | 2FL | 配置フロア + 1 (2FL) | 57.7185 | 61.0892 | 16 | 6 | 74.7139 | 1.89 | 173.156 | 105.203 | 61.08 | 1.73255 | 店舗 | 61.08 | 18 | 37.7 | 61.08 ㎡ | 18 坪 | 37.70 帖 | 76.4281 | 71.1781 | 34473.2 | 35067.6 | 183.268 | 0 | 0 | 3000 | 6 | 4 | 2 | 0 | 6 | 5.25 | 2500 | 31569.5 | 900 | 8.72703 | 12.2178 | 6.10892 | 1.22178 | 3.05446
108 | 1FL | Z1 | 108 | 1FL | 1 | 2FL | 配置フロア + 1 (2FL) | 54.741 | 58.0196 | 16 | 6 | 71.6443 | 1.89 | 164.223 | 101.519 | 58.01 | 1.82678 | 店舗 | 58.01 | 17 | 35.8 | 58.01 ㎡ | 17 坪 | 35.80 帖 | 73.1467 | 62.0167 | 33245.4 | 33839.7 | 174.059 | 0 | 0 | 3000 | 6 | 4 | 3 | 0 | 6 | 11.13 | 5300 | 30341.6 | 900 | 8.28851 | 11.6039 | 5.80196 | 1.16039 | 2.90098
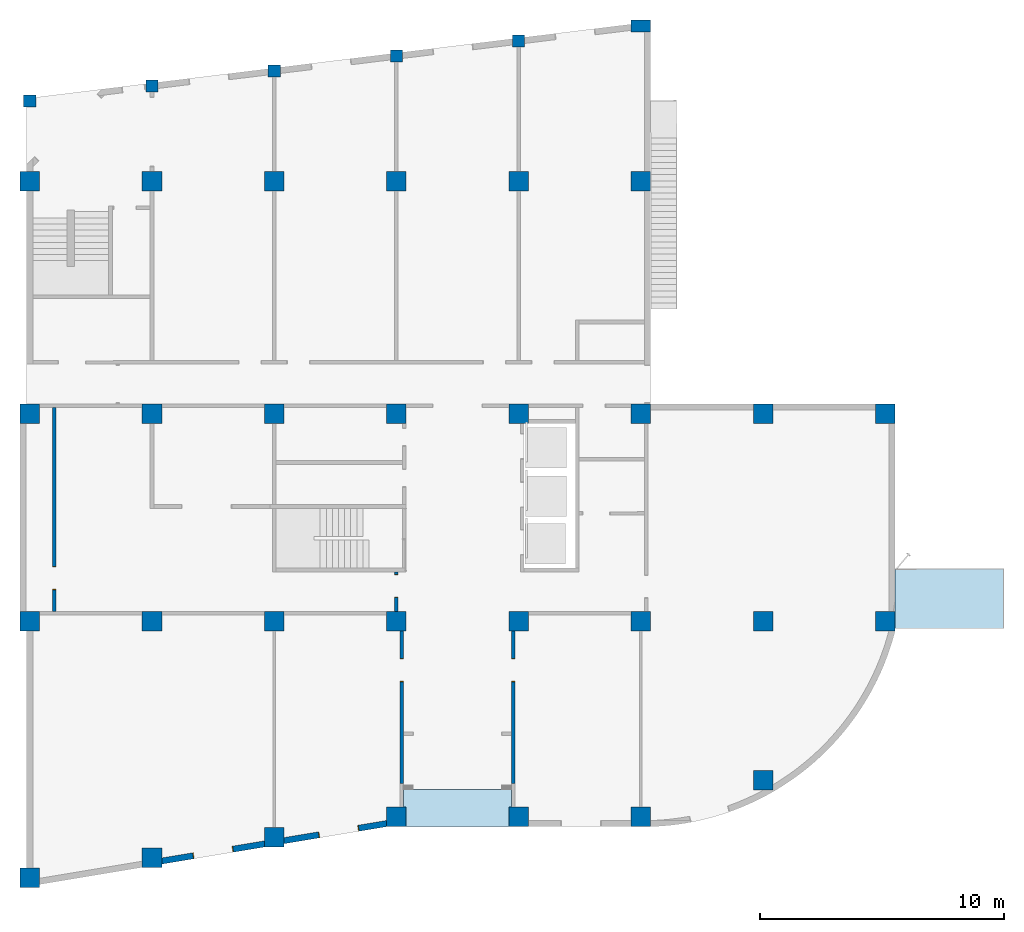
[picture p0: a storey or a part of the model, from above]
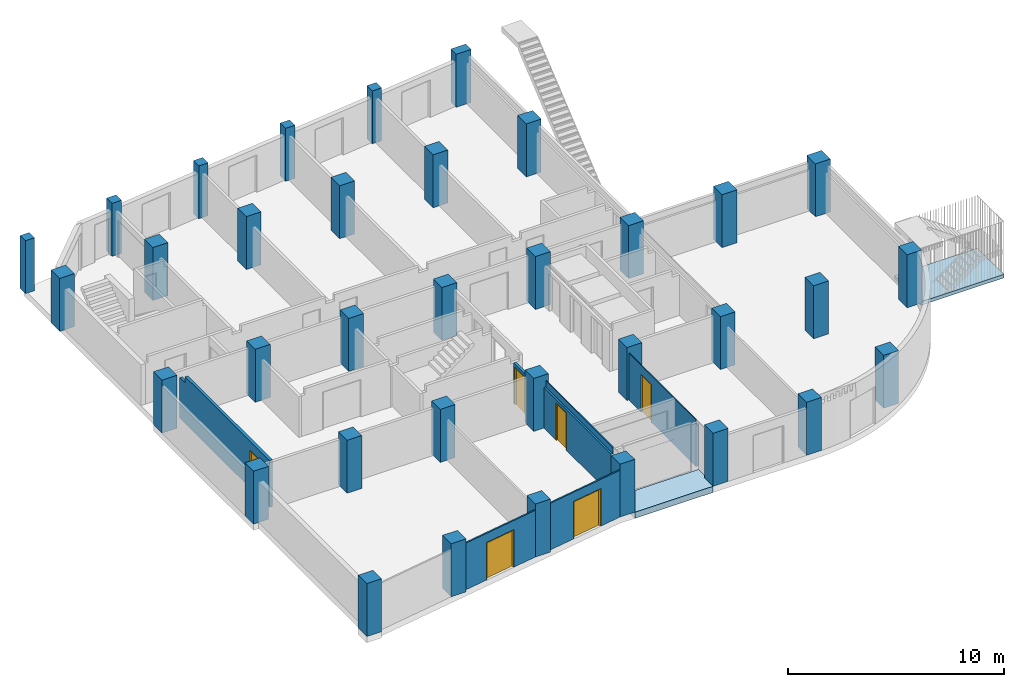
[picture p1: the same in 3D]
Properties of the parts of a building model (IFC2X3), part 3 of 10

# IfcSpace: 店舗 (22)
Name | In | 要素ID = ホットリンクおよび要素ID = 親ID | 関連ゾーン番号 = ゾーン番号 = ゾーン番号 (ROOM_NUMBER) | ホームフロア名 | ホームフロア数 | 絶対上部リンクフロア | 上部リンクフロア | 縮小された面積 = AC_Pset_ゾーン_仕上用, 測定正味面積 = 縮小面積 = 計算面積 (ROOM_CALC_AREA) = 上部表面積 = 下部材質面積 = NetFloorArea (m2) = SpaceNetFloorAreaBOMA (m2) = SpaceUsableFloorAreaBOMA (m2) = NetCeilingArea (m2) = 計算した面積 (m2) = ArchiCADQuantities, 測定正味面積 (m2) | AC_Pset_ゾーン_仕上用, 測定面積 = GrossFloorArea (m2) = GrossCeilingArea (m2) = 面積 (m2) = ArchiCADQuantities, 測定面積 (m2) | 全コーナー数 = 角数 | 凹型コーナー数 = 全てのへこみ角数 | 外壁表面積 | AC_Pset_ゾーン_仕上用, ドア表面積 | 体積 = 気積 = NetVolume (m3) = 正味体積 (m3) | 境界表面積 | 計算面積 (stAreaDisp) | 換気回数 | カテゴリ名称 | 面積値 | 坪 | 畳 | 面積テキスト | 坪テキスト | 畳テキスト | GrossWallArea (m2) | NetWallArea (m2) = 壁表面積 (m2) | GrossPerimeter (mm) = ゾーン総外周 (mm) = 外周 (mm) | NetPerimeter (mm) = ゾーン正味外周 (mm) = 正味外周 (mm) | GrossVolume (m3) | GLからの高度 (mm) = 高度 1 (mm) = 高度 2 (mm) = 海抜までの高度 (mm) = 下端高度から第1基準レベル (mm) = 下端高度から基準レベル (mm) = 下端高度から海抜 (mm) = 下端高度から第2基準レベル (mm) | 平面図穴外周 (mm) = 穴外周 (mm) | 上端高度から第1基準レベル (mm) = 上端高度から基準レベル (mm) = 上端高度から海抜 (mm) = 上端高度から第2基準レベル (mm) | 梁数 | 柱数 | ドア数 | オブジェクト数 | 壁部品数 | ArchiCADQuantities, ドア表面積 (m2) | ドア幅 (mm) | 壁外周 (mm) = 外壁長さ (mm) | ドア組み合わせ幅 (mm) | 居室に必要な採光面積 (m2) = 病院福祉施設等に必要な採光面積 (m2) | 教育施設に必要な採光面積 (m2) | その他に必要な採光面積 (m2) | 自然排煙必要面積(ゾーン) (m2) | 必要換気量（ゾーン） (m2)
201 | 2FL | Z7 | 201 | 2FL | 2 | 3FL | 配置フロア + 1 (3FL) | 49.5064 | 53.0747 | 12 | 4 | 61.5818 | 1.89 | 148.519 | 91.6031 | 53.07 | 2.01994 |  | 53.07 | 16 | 32.75 | 53.07 ㎡ | 16 坪 | 32.75 帖 | 63.4718 | 61.5818 | 31298.9 | 30534.4 | 159.224 | 3000 | 0 | 6000 | 8 | 4 | 1 | 0 | 4 | 1.89 | 900 | 27024.6 | 900 | 7.5821 | 10.6149 | 5.30747 | 1.06149 | 2.65374
202 | 2FL | Z8 | 202 | 2FL | 2 | 3FL | 配置フロア + 1 (3FL) | 46.9414 | 48.908 | 4 | 0 | 57.7484 | 1.89 | 140.824 | 87.0821 | 48.90 | 2.13031 | 店舗 | 48.9 | 14 | 30.18 | 48.90 ㎡ | 14 坪 | 30.18 帖 | 59.6384 | 57.7484 | 29632.2 | 29027.4 | 146.724 | 3000 | 0 | 6000 | 12 | 4 | 1 | 0 | 4 | 1.89 | 900 | 29027.4 | 900 | 6.98686 | 9.78161 | 4.8908 | 0.978161 | 2.4454
203 | 2FL | Z9 | 203 | 2FL | 2 | 3FL | 配置フロア + 1 (3FL) | 44.5224 | 46.6568 | 6 | 0 | 53.9151 | 1.89 | 133.567 | 83.1904 | 46.65 | 2.24606 | 店舗 | 46.65 | 14 | 28.79 | 46.65 ㎡ | 14 坪 | 28.79 帖 | 55.8051 | 53.9151 | 28381.1 | 27730.1 | 139.97 | 3000 | 0 | 6000 | 14 | 4 | 1 | 0 | 5 | 1.89 | 900 | 27705.1 | 900 | 6.66525 | 9.33135 | 4.66568 | 0.933135 | 2.33284
204 | 2FL | Z0 | 204 | 2FL | 2 | 3FL | 配置フロア + 1 (3FL) | 33.5325 | 35.4744 | 4 | 0 | 49.6452 | 1.89 | 100.598 | 70.05 | 35.47 | 2.98218 | 店舗 | 35.47 | 10 | 21.89 | 35.47 ㎡ | 10 坪 | 21.89 帖 | 51.5352 | 49.6452 | 24000 | 23350 | 106.423 | 3000 | 0 | 6000 | 10 | 2 | 1 | 0 | 4 | 1.89 | 900 | 23350 | 900 | 5.06777 | 7.09488 | 3.54744 | 0.709488 | 1.77372
205 | 2FL | Z1 | 205 | 2FL | 2 | 3FL | 配置フロア + 1 (3FL) | 32.0531 | 33.625 | 5 | 0 | 49.1277 | 1.89 | 96.1594 | 68.7 | 33.62 | 3.11982 | 店舗 | 33.62 | 10 | 20.75 | 33.62 ㎡ | 10 坪 | 20.75 帖 | 51.0177 | 49.1277 | 23450 | 22900 | 100.875 | 3000 | 0 | 6000 | 10 | 2 | 1 | 0 | 5 | 1.89 | 900 | 22900 | 900 | 4.80357 | 6.725 | 3.3625 | 0.6725 | 1.68125
206 | 2FL | Z2 | 206 | 2FL | 2 | 3FL | 配置フロア + 1 (3FL) | 42.84 | 44.935 | 5 | 0 | 51.8652 | 1.89 | 128.52 | 81 | 44.93 | 2.33427 | 店舗 | 44.93 | 13 | 27.73 | 44.93 ㎡ | 13 坪 | 27.73 帖 | 53.7552 | 51.8652 | 27650 | 27000 | 134.805 | 3000 | 0 | 6000 | 15 | 4 | 1 | 0 | 5 | 1.89 | 900 | 27000 | 900 | 6.41929 | 8.987 | 4.4935 | 0.8987 | 2.24675
207 | 2FL | Z3 | 207 | 2FL | 2 | 3FL | 配置フロア + 1 (3FL) | 39.2573 | 41.0595 | 5 | 0 | 51.4483 | 1.89 | 117.772 | 76.7696 | 41.05 | 2.5473 | 店舗 | 41.05 | 12 | 25.33 | 41.05 ㎡ | 12 坪 | 25.33 帖 | 53.3383 | 51.4483 | 26180.7 | 25589.9 | 123.179 | 3000 | 0 | 6000 | 9 | 4 | 1 | 0 | 5 | 1.89 | 900 | 25589.5 | 900 | 5.86564 | 8.2119 | 4.10595 | 0.82119 | 2.05298
208 | 2FL | Z4 | 208 | 2FL | 2 | 3FL | 配置フロア + 1 (3FL) | 24.5612 | 26.4719 | 4 | 0 | 43.6052 | 1.89 | 73.6836 | 64.1063 | 26.47 | 4.07146 | 店舗 | 26.47 | 8 | 16.33 | 26.47 ㎡ | 8 坪 | 16.33 帖 | 45.4952 | 43.6052 | 22337.2 | 21368.8 | 79.4158 | 3000 | 0 | 6000 | 8 | 3 | 1 | 0 | 4 | 1.89 | 900 | 21368.1 | 900 | 3.78171 | 5.29439 | 2.64719 | 0.529439 | 1.3236
209 | 2FL | Z5 | 209 | 2FL | 2 | 3FL | 配置フロア + 1 (3FL) | 30.1088 | 31.8756 | 4 | 0 | 49.1965 | 1.89 | 90.3263 | 66.75 | 31.87 | 3.32129 | 店舗 | 31.87 | 9 | 19.67 | 31.87 ㎡ | 9 坪 | 19.67 帖 | 51.0865 | 49.1965 | 23000 | 22250 | 95.6269 | 3000 | 0 | 6000 | 4 | 2 | 1 | 0 | 4 | 1.89 | 900 | 22250 | 900 | 4.55366 | 6.37513 | 3.18756 | 0.637513 | 1.59378
210 | 2FL | Z6 | 210 | 2FL | 2 | 3FL | 配置フロア + 1 (3FL) | 33.0225 | 35.2106 | 4 | 0 | 48.1752 | 1.89 | 99.0675 | 69.45 | 35.21 | 3.02824 | 店舗 | 35.21 | 10 | 21.73 | 35.21 ㎡ | 10 坪 | 21.73 帖 | 50.0652 | 48.1752 | 23900 | 23150 | 105.632 | 3000 | 0 | 6000 | 6 | 2 | 1 | 0 | 4 | 1.89 | 900 | 23150 | 900 | 5.03009 | 7.04212 | 3.52106 | 0.704212 | 1.76053
211 | 2FL | Z7 | 211 | 2FL | 2 | 3FL | 配置フロア + 1 (3FL) | 55.597 | 58.0196 | 6 | 0 | 69.657 | 3.78 | 166.791 | 97.7869 | 58.01 | 1.79866 | 店舗 | 58.01 | 17 | 35.8 | 58.01 ㎡ | 17 坪 | 35.80 帖 | 73.437 | 69.657 | 33245.4 | 32595.6 | 174.059 | 3000 | 0 | 6000 | 12 | 4 | 2 | 0 | 6 | 3.78 | 1800 | 32595.6 | 1800 | 8.28851 | 11.6039 | 5.80196 | 1.16039 | 2.90098
212 | 2FL | Z8 | 212 | 2FL | 2 | 3FL | 配置フロア + 1 (3FL) | 58.8828 | 61.0892 | 6 | 0 | 74.8289 | 1.89 | 176.648 | 101.612 | 61.08 | 1.69829 | 店舗 | 61.08 | 18 | 37.7 | 61.08 ㎡ | 18 坪 | 37.70 帖 | 76.7189 | 74.8289 | 34473.2 | 33870.6 | 183.268 | 3000 | 0 | 6000 | 12 | 4 | 1 | 0 | 6 | 1.89 | 900 | 33870.6 | 900 | 8.72703 | 12.2178 | 6.10892 | 1.22178 | 3.05446
214 | 2FL | Z0 | 214 | 2FL | 2 | 3FL | 配置フロア + 1 (3FL) | 66.8025 | 71.015 | 16 | 6 | 79.9098 | 1.89 | 200.408 | 115.511 | 71.01 | 1.49695 | 店舗 | 71.01 | 21 | 43.83 | 71.01 ㎡ | 21 坪 | 43.83 帖 | 81.7998 | 79.9098 | 37514.7 | 38503.7 | 213.045 | 3000 | 0 | 6000 | 12 | 4 | 1 | 0 | 6 | 1.89 | 900 | 34124 | 900 | 10.145 | 14.203 | 7.1015 | 1.4203 | 3.55075
214 | 2FL | Z0 | 214 | 2FL | 2 | 3FL | 配置フロア + 1 (3FL) | 61.2814 | 64.1588 | 16 | 6 | 77.8985 | 1.89 | 183.844 | 109.486 | 64.15 | 1.63182 | 店舗 | 64.15 | 19 | 39.59 | 64.15 ㎡ | 19 坪 | 39.59 帖 | 79.7885 | 77.8985 | 35701.1 | 36495.4 | 192.476 | 3000 | 0 | 6000 | 12 | 4 | 1 | 0 | 6 | 1.89 | 900 | 32847.3 | 900 | 9.16554 | 12.8318 | 6.41588 | 1.28318 | 3.20794

# IfcBeam: コンクリート 400 x 500 (20)
Classification: 梁 (ARCHICAD 分類); Material: コンクリート
ArchiCADProperties - レイヤー: 梁; ビルディングマテリアル/複合構造/断面形状/塗りつぶし: コンクリート; ビルディングマテリアル: コンクリート; ロック状態: no; 要素タイプ: 梁; 構造タイプ: 基本; ビルディングマテリアル (全て): コンクリート; 材質 (全て): コンクリート - 04; 表面塗りつぶし: 背景; 傾斜角度: 0 deg; 開口部の数: 0; リノベーションフィルタで表示: 全ての関連フィルタ; 構造機能: 構造耐力要素; 位置: インテリア; リノベーションステータス: 既存; 下面材質: コンクリート - 04; 梁断面: 矩形; 終端材質: コンクリート - 04; 左側材質: コンクリート - 04; 右側材質: コンクリート - 04; 梁傾斜角度: 0 deg; 上面材質: コンクリート - 04; 押し出し表面: コンクリート - 04; ARCHICAD 分類 - v 2.0: 梁
仕上情報 - WEBサイト: www.graphisoft.co.jp
AC_Pset_RenovationAndPhasing - Renovation Status: Existing
Pset_BeamCommon - LoadBearing: yes; IsExternal: no; Reference: コンクリート 400 x 500
BaseQuantities - Width: 400 mm; Depth: 500 mm; CrossSectionArea: 0.2 m2
ArchiCADQuantities - 高さ: 500 mm; 幅: 400 mm; リンク/配置フロアまでの高度: 0 mm; 下部オフセット: 0 mm; 上端高度から配置フロア: 0 mm; 下端高度から配置フロア: -500 mm; 上部/終了の断面高さ(垂直): 500 mm; 下部/開始の断面高さ(垂直): 500 mm; 上部/終了の断面幅(垂直): 400 mm; 下部/開始の断面幅(垂直): 400 mm; 上部/終了の断面高さ(切断): 500 mm; 下部/開始の断面高さ(切断): 500 mm; 上部/終了の断面幅(切断): 400 mm; 下部/開始の断面幅(切断): 400 mm; 下部/開始の断面の面積: 0 m2; 上部/終了の断面の面積: 0 m2; セグメント数: 1; 終端表面積: 0 m2; 穴番号: 0; 穴の辺の表面積: 0 m2; 穴表面積: 0 m2; 穴体積: 0 m3; オフセット: 0 mm
Name | In | 要素ID = ホットリンクおよび要素ID = 親ID | 関連ゾーン名 | 関連ゾーン番号 | ホームフロア名 | ホームフロア数 | NetSurfaceAreaExtrudedSides (m2) = OuterSurfaceArea (m2) | Length (mm) = 3D長さ (mm) | TotalSurfaceArea (m2) = GrossSurfaceArea (m2) = NetSurfaceArea (m2) | GrossVolume (m3) = NetVolume (m3) = 正味体積 (m3) = 条件付き体積 (m3) | 面積 (m2) = 下部表面積 (m2) = 上部表面積 (m2) | GLからの高度 (mm) = 高度 1 (mm) = 高度 2 (mm) = 海抜までの高度 (mm) = 上端高度から第1基準レベル (mm) = 上端高度から基準レベル (mm) = 上端高度から海抜 (mm) = 上端高度から第2基準レベル (mm) | 表面積 (m2) | 下端高度から第1基準レベル (mm) = 下端高度から基準レベル (mm) = 下端高度から海抜 (mm) = 下端高度から第2基準レベル (mm) | 左側表面積 (m2) | 左長さ (mm) | 右長さ (mm) | 右側表面積 (m2)
G7 | 2FL | G7 | ホール | ＜ゾーン番号＞ | 2FL | 2 | 4.73945 | 2633.03 | 5.13945 | 0.526606 | 1.05321 | 3000 | 5.13945 | 2500 | 1.31651 | 2856.08 | 3209.97 | 1.31651
G3 | 2FL | G3 | 店舗 | 105 | 2FL | 2 | 9.1597 | 5088.72 | 9.5597 | 1.01774 | 2.03549 | 3000 | 9.5597 | 2500 | 2.54436 | 5665.67 | 5311.78 | 2.54436
G4 | 2FL | G4 | 店舗 | 106 | 2FL | 2 | 8.05464 | 4474.8 | 8.45464 | 0.89496 | 1.78992 | 3000 | 8.45464 | 2500 | 2.2374 | 4697.85 | 5051.74 | 2.2374
G5 | 2FL | G5 | 店舗 | 107 | 2FL | 2 | 6.94958 | 3860.88 | 7.34958 | 0.772175 | 1.54435 | 3000 | 7.34958 | 2500 | 1.93044 | 4083.93 | 4437.82 | 1.93044
G6 | 2FL | G6 | 店舗 | 108 | 2FL | 2 | 5.84451 | 3246.95 | 6.24451 | 0.64939 | 1.29878 | 3000 | 6.24451 | 2500 | 1.62348 | 3470.01 | 3823.9 | 1.62348
G3 | 2FL | G3 | 店舗 | 105 | 2FL | 2 | 7.89133 | 4431.78 | 8.29133 | 0.876534 | 1.75307 | 3000 | 8.29654 | 2500 | 2.19133 | 5490.93 | 4584.17 | 2.19386
G4 | 2FL | G4 | 店舗 | 106 | 2FL | 2 | 8.16083 | 4582.91 | 8.56083 | 0.906759 | 1.81352 | 3000 | 8.56383 | 2500 | 2.2669 | 4634.55 | 5037.55 | 2.2669
G5 | 2FL | G5 | 店舗 | 107 | 2FL | 2 | 8.16083 | 4582.91 | 8.56083 | 0.906759 | 1.81352 | 3000 | 8.56383 | 2500 | 2.2669 | 4634.55 | 5037.55 | 2.2669
G6 | 2FL | G6 | 店舗 | 108 | 2FL | 2 | 8.16083 | 4582.91 | 8.56083 | 0.906759 | 1.81352 | 3000 | 8.56383 | 2500 | 2.2669 | 4634.55 | 5037.55 | 2.2669
G7 | 2FL | G7 | ホール | ＜ゾーン番号＞ | 2FL | 2 | 8.16083 | 4582.91 | 8.56083 | 0.906759 | 1.81352 | 3000 | 8.56383 | 2500 | 2.2669 | 4634.55 | 5037.55 | 2.2669
G7 | 3FL | G7 | 女性用トイレ | ＜ゾーン番号＞ | 3FL | 3 | 4.73945 | 2633.03 | 5.13945 | 0.526606 | 1.05321 | 6000 | 5.13945 | 5500 | 1.31651 | 3033.03 | 3033.03 | 1.31651
G3 | 3FL | G3 | 店舗 | 214 | 3FL | 3 | 9.1597 | 5088.72 | 9.5597 | 1.01774 | 2.03549 | 6000 | 9.5597 | 5500 | 2.54436 | 5488.72 | 5488.72 | 2.54436
G4 | 3FL | G4 | 店舗 | 212 | 3FL | 3 | 8.05464 | 4474.8 | 8.45464 | 0.89496 | 1.78992 | 6000 | 8.45464 | 5500 | 2.2374 | 4874.8 | 4874.8 | 2.2374
G5 | 3FL | G5 | 店舗 | 211 | 3FL | 3 | 6.94958 | 3860.88 | 7.34958 | 0.772175 | 1.54435 | 6000 | 7.34958 | 5500 | 1.93044 | 4260.88 | 4260.88 | 1.93044
G6 | 3FL | G6 | ホール | ＜ゾーン番号＞ | 3FL | 3 | 5.84451 | 3246.95 | 6.24451 | 0.64939 | 1.29878 | 6000 | 6.24451 | 5500 | 1.62348 | 3646.95 | 3646.95 | 1.62348
G3 | 3FL | G3 | 店舗 | 214 | 3FL | 3 | 7.89133 | 4431.78 | 8.29133 | 0.876534 | 1.75307 | 6000 | 8.29654 | 5500 | 2.19133 | 4810.23 | 4761.11 | 2.19386
G4 | 3FL | G4 | 店舗 | 214 | 3FL | 3 | 8.16083 | 4582.91 | 8.56083 | 0.906759 | 1.81352 | 6000 | 8.56383 | 5500 | 2.2669 | 4811.49 | 4860.6 | 2.2669
G5 | 3FL | G5 | 店舗 | 212 | 3FL | 3 | 8.16083 | 4582.91 | 8.56083 | 0.906759 | 1.81352 | 6000 | 8.56383 | 5500 | 2.2669 | 4811.49 | 4860.6 | 2.2669
G6 | 3FL | G6 | 店舗 | 211 | 3FL | 3 | 8.16083 | 4582.91 | 8.56083 | 0.906759 | 1.81352 | 6000 | 8.56383 | 5500 | 2.2669 | 4811.49 | 4860.6 | 2.2669
G7 | 3FL | G7 | 男性用トイレ | ＜ゾーン番号＞ | 3FL | 3 | 8.16083 | 4582.91 | 8.56083 | 0.906759 | 1.81352 | 6000 | 8.56383 | 5500 | 2.2669 | 4811.49 | 4860.6 | 2.2669

# IfcBeam: コンクリート 500 x 700 (414)
Classification: 梁 (ARCHICAD 分類); Material: コンクリート
ArchiCADProperties - レイヤー: 梁; ビルディングマテリアル/複合構造/断面形状/塗りつぶし: コンクリート; ビルディングマテリアル: コンクリート; 要素タイプ: 梁; 構造タイプ: 基本; ビルディングマテリアル (全て): コンクリート; 材質 (全て): コンクリート - 04; 表面塗りつぶし: 背景; 傾斜角度: 0 deg; 開口部の数: 0; リノベーションフィルタで表示: 全ての関連フィルタ; 構造機能: 構造耐力要素; 位置: インテリア; リノベーションステータス: 既存; 下面材質: コンクリート - 04; 梁断面: 矩形; 終端材質: コンクリート - 04; 左側材質: コンクリート - 04; 右側材質: コンクリート - 04; 梁傾斜角度: 0 deg; 上面材質: コンクリート - 04; 押し出し表面: コンクリート - 04; ARCHICAD 分類 - v 2.0: 梁
仕上情報 - WEBサイト: www.graphisoft.co.jp
AC_Pset_RenovationAndPhasing - Renovation Status: Existing
Pset_BeamCommon - LoadBearing: yes; IsExternal: no; Reference: コンクリート 500 x 700
BaseQuantities - Width: 500 mm; Depth: 700 mm; CrossSectionArea: 0.35 m2
ArchiCADQuantities - 高さ: 700 mm; 幅: 500 mm; 上部/終了の断面高さ(垂直): 700 mm; 下部/開始の断面高さ(垂直): 700 mm; 上部/終了の断面幅(垂直): 500 mm; 下部/開始の断面幅(垂直): 500 mm; 上部/終了の断面高さ(切断): 700 mm; 下部/開始の断面高さ(切断): 700 mm; 上部/終了の断面幅(切断): 500 mm; 下部/開始の断面幅(切断): 500 mm; 下部/開始の断面の面積: 0 m2; 上部/終了の断面の面積: 0 m2; セグメント数: 1; 終端表面積: 0 m2; 穴番号: 0; 穴の辺の表面積: 0 m2; 穴表面積: 0 m2; 穴体積: 0 m3; オフセット: 0 mm
Name | In | 要素ID = 親ID | ホットリンクおよび要素ID | 関連ゾーン名 | 関連ゾーン番号 | ロック状態 | ホームフロア名 | ホームフロア数 | NetSurfaceAreaExtrudedSides (m2) = OuterSurfaceArea (m2) | Length (mm) = 3D長さ (mm) | TotalSurfaceArea (m2) = GrossSurfaceArea (m2) = NetSurfaceArea (m2) | GrossVolume (m3) = NetVolume (m3) = 正味体積 (m3) = 条件付き体積 (m3) | 面積 (m2) = 下部表面積 (m2) = 上部表面積 (m2) | GLからの高度 (mm) = 高度 1 (mm) = 高度 2 (mm) = 海抜までの高度 (mm) = 上端高度から第1基準レベル (mm) = 上端高度から基準レベル (mm) = 上端高度から海抜 (mm) = 上端高度から第2基準レベル (mm) | リンク/配置フロアまでの高度 (mm) = 下部オフセット (mm) = 上端高度から配置フロア (mm) | 表面積 (m2) | 下端高度から第1基準レベル (mm) = 下端高度から基準レベル (mm) = 下端高度から海抜 (mm) = 下端高度から第2基準レベル (mm) | 下端高度から配置フロア (mm) | 左側表面積 (m2) = 右側表面積 (m2) | 左長さ (mm) | 右長さ (mm) | ホットリンク マスタID
G1 | 2FL | G1 | G1 | 店舗 | 104 | no | 2FL | 2 | 13.68 | 5700 | 14.38 | 1.995 | 2.85 | 3000 | 0 | 14.38 | 2300 | -700 | 3.99 | 6436.01 | 6063.99
G2 | 2FL | G2 | G2 | 店舗 | 104 | no | 2FL | 2 | 10.5238 | 4534.93 | 11.2238 | 1.53473 | 2.19246 | 3000 | 0 | 11.2547 | 2300 | -700 | 3.06945 | 5220.15 | 4698.14
G1 | 2FL | G1 | G1 | 店舗 | 101 | no | 2FL | 2 | 10.08 | 4200 | 10.78 | 1.47 | 2.1 | 3000 | 0 | 10.78 | 2300 | -700 | 2.94 | 4750 | 5250
G1 | 2FL | G1 | G1 | 店舗 | 101 | no | 2FL | 2 | 10.08 | 4200 | 10.78 | 1.47 | 2.1 | 3000 | 0 | 10.78 | 2300 | -700 | 2.94 | 5000 | 5000
G1 | 2FL | G1 | G1 | 店舗 | 102 | no | 2FL | 2 | 10.08 | 4200 | 10.78 | 1.47 | 2.1 | 3000 | 0 | 10.78 | 2300 | -700 | 2.94 | 5000 | 5000
G1 | 2FL | G1 | G1 | 玄関ホール | ＜ゾーン番号＞ | no | 2FL | 2 | 10.08 | 4200 | 10.78 | 1.47 | 2.1 | 3000 | 0 | 10.78 | 2300 | -700 | 2.94 | 5000 | 5000
G1 | 2FL | G1 | G1 | 店舗 | 103 | no | 2FL | 2 | 10.08 | 4200 | 10.78 | 1.47 | 2.1 | 3000 | 0 | 10.78 | 2300 | -700 | 2.94 | 5000 | 5000
G1 | 2FL | G1 | G1 | 店舗 | 104 | no | 2FL | 2 | 10.08 | 4200 | 10.78 | 1.47 | 2.1 | 3000 | 0 | 10.78 | 2300 | -700 | 2.94 | 5000 | 5000
G1 | 2FL | G1 | G1 | 店舗 | 104 | no | 2FL | 2 | 10.08 | 4200 | 10.78 | 1.47 | 2.1 | 3000 | 0 | 10.78 | 2300 | -700 | 2.94 | 4750 | 5250
G1 | 2FL | G1 | G1 | 共用スペー | ＜ゾーン番号＞ | no | 2FL | 2 | 10.08 | 4200 | 10.78 | 1.47 | 2.1 | 3000 | 0 | 10.78 | 2300 | -700 | 2.94 | 5250 | 4750
G1 | 2FL | G1 | G1 | 管理室 | ＜ゾーン番号＞ | no | 2FL | 2 | 10.08 | 4200 | 10.78 | 1.47 | 2.1 | 3000 | 0 | 10.78 | 2300 | -700 | 2.94 | 5000 | 5000
G1 | 2FL | G1 | G1 | 男性用トイレ | ＜ゾーン番号＞ | no | 2FL | 2 | 10.08 | 4200 | 10.78 | 1.47 | 2.1 | 3000 | 0 | 10.78 | 2300 | -700 | 2.94 | 5000 | 5000
G1 | 2FL | G1 | G1 | EVホール | ＜ゾーン番号＞ | no | 2FL | 2 | 10.08 | 4200 | 10.78 | 1.47 | 2.1 | 3000 | 0 | 10.78 | 2300 | -700 | 2.94 | 5000 | 5000
2 x G1 | 2FL | G1 | G1 | PS | ＜ゾーン番号＞ | no | 2FL | 2 | 10.08 | 4200 | 10.78 | 1.47 | 2.1 | 3000 | 0 | 10.78 | 2300 | -700 | 2.94 | 5000 | 5000
G1 | 2FL | G1 | G1 | 店舗 | 104 | no | 2FL | 2 | 10.08 | 4200 | 10.78 | 1.47 | 2.1 | 3000 | 0 | 10.78 | 2300 | -700 | 2.94 | 5250 | 4750
G1 | 2FL | G1 | G1 | 店舗 | 104 | no | 2FL | 2 | 18.48 | 7700 | 19.18 | 2.695 | 3.85 | 3000 | 0 | 19.18 | 2300 | -700 | 5.39 | 9000 | 8000
G1 | 2FL | G1 | G1 | PS | ＜ゾーン番号＞ | no | 2FL | 2 | 18.48 | 7700 | 19.18 | 2.695 | 3.85 | 3000 | 0 | 19.18 | 2300 | -700 | 5.39 | 9000 | 8000
G1 | 2FL | G1 | G1 | ゴミ置き場 | ＜ゾーン番号＞ | no | 2FL | 2 | 20.88 | 8700 | 21.58 | 3.045 | 4.35 | 3000 | 0 | 21.58 | 2300 | -700 | 6.09 | 9000 | 9500
G1 | 2FL | G1 | G1 | ホール | ＜ゾーン番号＞ | no | 2FL | 2 | 10.08 | 4200 | 10.78 | 1.47 | 2.1 | 3000 | 0 | 10.78 | 2300 | -700 | 2.94 | 5250 | 4750
G1 | 2FL | G1 | G1 | 店舗 | 108 | no | 2FL | 2 | 10.08 | 4200 | 10.78 | 1.47 | 2.1 | 3000 | 0 | 10.78 | 2300 | -700 | 2.94 | 5000 | 5000
G1 | 2FL | G1 | G1 | 店舗 | 107 | no | 2FL | 2 | 10.08 | 4200 | 10.78 | 1.47 | 2.1 | 3000 | 0 | 10.78 | 2300 | -700 | 2.94 | 5000 | 5000
G1 | 2FL | G1 | G1 | 店舗 | 106 | no | 2FL | 2 | 10.08 | 4200 | 10.78 | 1.47 | 2.1 | 3000 | 0 | 10.78 | 2300 | -700 | 2.94 | 5000 | 5000
G1 | 2FL | G1 | G1 | 店舗 | 105 | no | 2FL | 2 | 10.08 | 4200 | 10.78 | 1.47 | 2.1 | 3000 | 0 | 10.78 | 2300 | -700 | 2.94 | 5250 | 4750
G1 | 2FL | G1 | G1 | PS | ＜ゾーン番号＞ | no | 2FL | 2 | 20.88 | 8700 | 21.58 | 3.045 | 4.35 | 3000 | 0 | 21.58 | 2300 | -700 | 6.09 | 9500 | 9000
3 x G1 | 2FL | G1 | G1 | 共用スペー | ＜ゾーン番号＞ | no | 2FL | 2 | 18.48 | 7700 | 19.18 | 2.695 | 3.85 | 3000 | 0 | 19.18 | 2300 | -700 | 5.39 | 8000 | 8000
G1 | 2FL | G1 | G1 | DS | ＜ゾーン番号＞ | no | 2FL | 2 | 18.48 | 7700 | 19.18 | 2.695 | 3.85 | 3000 | 0 | 19.18 | 2300 | -700 | 5.39 | 8000 | 8000
G1 | 2FL | G1 | G1 | PS | ＜ゾーン番号＞ | no | 2FL | 2 | 18.48 | 7700 | 19.18 | 2.695 | 3.85 | 3000 | 0 | 19.18 | 2300 | -700 | 5.39 | 8000 | 8000
G1 | 2FL | G1 | G1 | 店舗 | 104 | no | 2FL | 2 | 18.48 | 7700 | 19.18 | 2.695 | 3.85 | 3000 | 0 | 19.18 | 2300 | -700 | 5.39 | 8000 | 8000
G1 | 2FL | G1 | G1 | 店舗 | 104 | no | 2FL | 2 | 17.28 | 7200 | 17.98 | 2.52 | 3.6 | 3000 | 0 | 17.98 | 2300 | -700 | 5.04 | 8000 | 7500
G1 | 2FL | G1 | G1 | 店舗 | 103 | no | 2FL | 2 | 10.08 | 4200 | 10.78 | 1.47 | 2.1 | 3000 | 0 | 10.78 | 2300 | -700 | 2.94 | 5500 | 4500
G1 | 2FL | G1 | G1 | 店舗 | 103 | no | 2FL | 2 | 17.28 | 7200 | 17.98 | 2.52 | 3.6 | 3000 | 0 | 17.98 | 2300 | -700 | 5.04 | 8000 | 7500
G1 | 2FL | G1 | G1 | 店舗 | 102 | no | 2FL | 2 | 17.28 | 7200 | 17.98 | 2.52 | 3.6 | 3000 | 0 | 17.98 | 2300 | -700 | 5.04 | 7961.78 | 7538.22
G1 | 2FL | G1 | G1 | 店舗 | 102 | no | 2FL | 2 | 10.219 | 4341.27 | 10.919 | 1.49028 | 2.12897 | 3000 | 0 | 10.9287 | 2300 | -700 | 2.98055 | 5280.75 | 4857.19
G1 | 2FL | G1 | G1 | 店舗 | 101 | no | 2FL | 2 | 10.219 | 4341.27 | 10.919 | 1.49028 | 2.12897 | 3000 | 0 | 10.9287 | 2300 | -700 | 2.98055 | 5068.97 | 5068.97
G1 | 2FL | G1 | G1 | 店舗 | 101 | no | 2FL | 2 | 10.219 | 4341.27 | 10.919 | 1.49028 | 2.12897 | 3000 | 0 | 10.9287 | 2300 | -700 | 2.98055 | 5364.08 | 4773.85
G1 | 2FL | G1 | G1 | 店舗 | 101 | no | 2FL | 2 | 23.28 | 9700 | 23.98 | 3.395 | 4.85 | 3000 | 0 | 23.98 | 2300 | -700 | 6.79 | 10545.1 | 9954.88
G1 | 2FL | G1 | G1 | 店舗 | 101 | no | 2FL | 2 | 21.28 | 8866.67 | 21.98 | 3.10333 | 4.43333 | 3000 | 0 | 21.98 | 2300 | -700 | 6.20667 | 9121.55 | 9204.88
G1 | 2FL | G1 | G1 | 店舗 | 102 | no | 2FL | 2 | 19.28 | 8033.33 | 19.98 | 2.81167 | 4.01667 | 3000 | 0 | 19.98 | 2300 | -700 | 5.62333 | 8288.22 | 8371.55
3 x G1 | 2FL | G1 | G1 | 廊下 | ＜ゾーン番号＞ | no | 2FL | 2 | 20.88 | 8700 | 21.58 | 3.045 | 4.35 | 3000 | 0 | 21.58 | 2300 | -700 | 6.09 | 9000 | 9000
G1 | 2FL | G1 | G1 | DS | ＜ゾーン番号＞ | no | 2FL | 2 | 20.88 | 8700 | 21.58 | 3.045 | 4.35 | 3000 | 0 | 21.58 | 2300 | -700 | 6.09 | 9000 | 9000
G1 | 2FL | G1 | G1 | 店舗 | 105 | no | 2FL | 2 | 13.6863 | 5702.64 | 14.3863 | 1.99593 | 2.85132 | 3000 | 0 | 14.3863 | 2300 | -700 | 3.99185 | 5870.45 | 6334.84
G1 | 3FL | G1 | G1 | 事務室 | 305 | no | 3FL | 3 | 17.28 | 7200 | 17.98 | 2.52 | 3.6 | 9000 | 3000 | 17.98 | 8300 | 2300 | 5.04 | 8000 | 7500
G1 | 3FL | G1 | G1 | 事務室 | 313 | no | 3FL | 3 | 10.08 | 4200 | 10.78 | 1.47 | 2.1 | 9000 | 3000 | 10.78 | 8300 | 2300 | 2.94 | 5000 | 5000
G1 | 3FL | G1 | G1 | 事務室 | 314 | no | 3FL | 3 | 10.08 | 4200 | 10.78 | 1.47 | 2.1 | 9000 | 3000 | 10.78 | 8300 | 2300 | 2.94 | 5000 | 5000
G1 | 3FL | G1 | G1 | 事務室 | 312 | no | 3FL | 3 | 20.88 | 8700 | 21.58 | 3.045 | 4.35 | 9000 | 3000 | 21.58 | 8300 | 2300 | 6.09 | 9000 | 9500
G1 | 3FL | G1 | G1 | 事務室 | 309 | no | 3FL | 3 | 10.08 | 4200 | 10.78 | 1.47 | 2.1 | 9000 | 3000 | 10.78 | 8300 | 2300 | 2.94 | 5000 | 5000
G1 | 3FL | G1 | G1 | 事務室 | 312 | no | 3FL | 3 | 10.08 | 4200 | 10.78 | 1.47 | 2.1 | 9000 | 3000 | 10.78 | 8300 | 2300 | 2.94 | 5250 | 4750
G1 | 3FL | G1 | G1 | 事務室 | 308 | no | 3FL | 3 | 18.48 | 7700 | 19.18 | 2.695 | 3.85 | 9000 | 3000 | 19.18 | 8300 | 2300 | 5.39 | 8000 | 8000
G1 | 3FL | G1 | G1 | 事務室 | 316 | no | 3FL | 3 | 20.88 | 8700 | 21.58 | 3.045 | 4.35 | 9000 | 3000 | 21.58 | 8300 | 2300 | 6.09 | 9500 | 9000
G1 | 3FL | G1 | G1 | 事務室 | 308 | no | 3FL | 3 | 18.48 | 7700 | 19.18 | 2.695 | 3.85 | 9000 | 3000 | 19.18 | 8300 | 2300 | 5.39 | 9000 | 8000
G1 | 3FL | G1 | G1 | 事務室 | 311 | no | 3FL | 3 | 18.48 | 7700 | 19.18 | 2.695 | 3.85 | 9000 | 3000 | 19.18 | 8300 | 2300 | 5.39 | 9000 | 8000
G1 | 3FL | G1 | G1 | 事務室 | 301 | no | 3FL | 3 | 23.28 | 9700 | 23.98 | 3.395 | 4.85 | 9000 | 3000 | 23.98 | 8300 | 2300 | 6.79 | 10545.1 | 9954.88
G1 | 3FL | G1 | G1 | 事務室 | 315 | no | 3FL | 3 | 20.88 | 8700 | 21.58 | 3.045 | 4.35 | 9000 | 3000 | 21.58 | 8300 | 2300 | 6.09 | 9000 | 9000
G1 | 3FL | G1 | G1 | 事務室 | 314 | no | 3FL | 3 | 20.88 | 8700 | 21.58 | 3.045 | 4.35 | 9000 | 3000 | 21.58 | 8300 | 2300 | 6.09 | 9000 | 9000
2 x G1 | 3FL | G1 | G1 | 事務室 | 313 | no | 3FL | 3 | 20.88 | 8700 | 21.58 | 3.045 | 4.35 | 9000 | 3000 | 21.58 | 8300 | 2300 | 6.09 | 9000 | 9000
G1 | 3FL | G1 | G1 | 事務室 | 302 | no | 3FL | 3 | 19.28 | 8033.33 | 19.98 | 2.81167 | 4.01667 | 9000 | 3000 | 19.98 | 8300 | 2300 | 5.62333 | 8288.22 | 8371.55
G1 | 3FL | G1 | G1 | EVホール | ＜ゾーン番号＞ | no | 3FL | 3 | 18.48 | 7700 | 19.18 | 2.695 | 3.85 | 9000 | 3000 | 19.18 | 8300 | 2300 | 5.39 | 8000 | 8000
2 x G1 | 3FL | G1 | G1 | 事務室 | 310 | no | 3FL | 3 | 18.48 | 7700 | 19.18 | 2.695 | 3.85 | 9000 | 3000 | 19.18 | 8300 | 2300 | 5.39 | 8000 | 8000
G1 | 3FL | G1 | G1 | 事務室 | 316 | no | 3FL | 3 | 10.08 | 4200 | 10.78 | 1.47 | 2.1 | 9000 | 3000 | 10.78 | 8300 | 2300 | 2.94 | 5250 | 4750
G1 | 3FL | G1 | G1 | 事務室 | 315 | no | 3FL | 3 | 10.08 | 4200 | 10.78 | 1.47 | 2.1 | 9000 | 3000 | 10.78 | 8300 | 2300 | 2.94 | 5000 | 5000
G1 | 3FL | G1 | G1 | PS | ＜ゾーン番号＞ | no | 3FL | 3 | 18.48 | 7700 | 19.18 | 2.695 | 3.85 | 9000 | 3000 | 19.18 | 8300 | 2300 | 5.39 | 8000 | 8000
G1 | 3FL | G1 | G1 | 事務室 | 305 | no | 3FL | 3 | 10.08 | 4200 | 10.78 | 1.47 | 2.1 | 9000 | 3000 | 10.78 | 8300 | 2300 | 2.94 | 5500 | 4500
G1 | 3FL | G1 | G1 | 事務室 | 303 | no | 3FL | 3 | 17.28 | 7200 | 17.98 | 2.52 | 3.6 | 9000 | 3000 | 17.98 | 8300 | 2300 | 5.04 | 7961.78 | 7538.22
G1 | 3FL | G1 | G1 | 事務室 | 301 | no | 3FL | 3 | 10.219 | 4341.27 | 10.919 | 1.49028 | 2.12897 | 9000 | 3000 | 10.9287 | 8300 | 2300 | 2.98055 | 5364.08 | 4773.85
G1 | 3FL | G1 | G1 | EVシャフト | ＜ゾーン番号＞ | no | 3FL | 3 | 18.48 | 7700 | 19.18 | 2.695 | 3.85 | 9000 | 3000 | 19.18 | 8300 | 2300 | 5.39 | 8000 | 8000
G1 | 3FL | G1 | G1 | 事務室 | 301 | no | 3FL | 3 | 21.28 | 8866.67 | 21.98 | 3.10333 | 4.43333 | 9000 | 3000 | 21.98 | 8300 | 2300 | 6.20667 | 9121.55 | 9204.88
G1 | 3FL | G1 | G1 | 事務室 | 302 | no | 3FL | 3 | 10.219 | 4341.27 | 10.919 | 1.49028 | 2.12897 | 9000 | 3000 | 10.9287 | 8300 | 2300 | 2.98055 | 5068.97 | 5068.97
G1 | 3FL | G1 | G1 | 事務室 | 308 | no | 3FL | 3 | 10.08 | 4200 | 10.78 | 1.47 | 2.1 | 9000 | 3000 | 10.78 | 8300 | 2300 | 2.94 | 5250 | 4750
G1 | 3FL | G1 | G1 | 事務室 | 304 | no | 3FL | 3 | 17.28 | 7200 | 17.98 | 2.52 | 3.6 | 9000 | 3000 | 17.98 | 8300 | 2300 | 5.04 | 8000 | 7500
G1 | 3FL | G1 | G1 | 事務室 | 303 | no | 3FL | 3 | 10.219 | 4341.27 | 10.919 | 1.49028 | 2.12897 | 9000 | 3000 | 10.9287 | 8300 | 2300 | 2.98055 | 5280.75 | 4857.19
G1 | 3FL | G1 | G1 | 店舗 | 201 | no | 3FL | 3 | 10.08 | 4200 | 10.78 | 1.47 | 2.1 | 6000 | 0 | 10.78 | 5300 | -700 | 2.94 | 5000 | 5000
G1 | 3FL | G1 | G1 | 店舗 | 202 | no | 3FL | 3 | 10.08 | 4200 | 10.78 | 1.47 | 2.1 | 6000 | 0 | 10.78 | 5300 | -700 | 2.94 | 5000 | 5000
G1 | 3FL | G1 | G1 | 店舗 | 203 | no | 3FL | 3 | 10.08 | 4200 | 10.78 | 1.47 | 2.1 | 6000 | 0 | 10.78 | 5300 | -700 | 2.94 | 5000 | 5000
2 x G1 | 3FL | G1 | G1 | EVホール | ＜ゾーン番号＞ | no | 3FL | 3 | 10.08 | 4200 | 10.78 | 1.47 | 2.1 | 6000 | 0 | 10.78 | 5300 | -700 | 2.94 | 5000 | 5000
2 x G1 | 3FL | G1 | G1 | 店舗 | 206 | no | 3FL | 3 | 10.08 | 4200 | 10.78 | 1.47 | 2.1 | 6000 | 0 | 10.78 | 5300 | -700 | 2.94 | 5000 | 5000
G1 | 3FL | G1 | G1 | 店舗 | 207 | no | 3FL | 3 | 10.08 | 4200 | 10.78 | 1.47 | 2.1 | 6000 | 0 | 10.78 | 5300 | -700 | 2.94 | 5000 | 5000
G1 | 3FL | G1 | G1 | 店舗 | 208 | no | 3FL | 3 | 10.08 | 4200 | 10.78 | 1.47 | 2.1 | 6000 | 0 | 10.78 | 5300 | -700 | 2.94 | 5000 | 5000
G1 | 3FL | G1 | G1 | 店舗 | 204 | no | 3FL | 3 | 10.08 | 4200 | 10.78 | 1.47 | 2.1 | 6000 | 0 | 10.78 | 5300 | -700 | 2.94 | 5000 | 5000
G1 | 3FL | G1 | G1 | 店舗 | 205 | no | 3FL | 3 | 10.08 | 4200 | 10.78 | 1.47 | 2.1 | 6000 | 0 | 10.78 | 5300 | -700 | 2.94 | 5000 | 5000
G1 | 3FL | G1 | G1 | 男性用トイレ | ＜ゾーン番号＞ | no | 3FL | 3 | 10.08 | 4200 | 10.78 | 1.47 | 2.1 | 6000 | 0 | 10.78 | 5300 | -700 | 2.94 | 5000 | 5000
G1 | 3FL | G1 | G1 | DS | ＜ゾーン番号＞ | no | 3FL | 3 | 10.08 | 4200 | 10.78 | 1.47 | 2.1 | 6000 | 0 | 10.78 | 5300 | -700 | 2.94 | 5000 | 5000
G1 | 3FL | G1 | G1 | 店舗 | 209 | no | 3FL | 3 | 10.08 | 4200 | 10.78 | 1.47 | 2.1 | 6000 | 0 | 10.78 | 5300 | -700 | 2.94 | 5000 | 5000
G1 | 3FL | G1 | G1 | 店舗 | 210 | no | 3FL | 3 | 10.08 | 4200 | 10.78 | 1.47 | 2.1 | 6000 | 0 | 10.78 | 5300 | -700 | 2.94 | 5000 | 5000
G1 | 3FL | G1 | G1 | EVホール | ＜ゾーン番号＞ | no | 3FL | 3 | 18.48 | 7700 | 19.18 | 2.695 | 3.85 | 6000 | 0 | 19.18 | 5300 | -700 | 5.39 | 8500 | 8500
G1 | 3FL | G1 | G1 | 廊下 | ＜ゾーン番号＞ | no | 3FL | 3 | 18.48 | 7700 | 19.18 | 2.695 | 3.85 | 6000 | 0 | 19.18 | 5300 | -700 | 5.39 | 8500 | 8500
G1 | 3FL | G1 | G1 | 機械室 | ＜ゾーン番号＞ | no | 3FL | 3 | 20.88 | 8700 | 21.58 | 3.045 | 4.35 | 6000 | 0 | 21.58 | 5300 | -700 | 6.09 | 9250 | 9250
G1 | 3FL | G1 | G1 | ホール | ＜ゾーン番号＞ | no | 3FL | 3 | 10.08 | 4200 | 10.78 | 1.47 | 2.1 | 6000 | 0 | 10.78 | 5300 | -700 | 2.94 | 5000 | 5000
G1 | 3FL | G1 | G1 | 店舗 | 211 | no | 3FL | 3 | 10.08 | 4200 | 10.78 | 1.47 | 2.1 | 6000 | 0 | 10.78 | 5300 | -700 | 2.94 | 5000 | 5000
G1 | 3FL | G1 | G1 | 店舗 | 212 | no | 3FL | 3 | 10.08 | 4200 | 10.78 | 1.47 | 2.1 | 6000 | 0 | 10.78 | 5300 | -700 | 2.94 | 5000 | 5000
2 x G1 | 3FL | G1 | G1 | 店舗 | 214 | no | 3FL | 3 | 10.08 | 4200 | 10.78 | 1.47 | 2.1 | 6000 | 0 | 10.78 | 5300 | -700 | 2.94 | 5000 | 5000
G1 | 3FL | G1 | G1 | DS | ＜ゾーン番号＞ | no | 3FL | 3 | 20.88 | 8700 | 21.58 | 3.045 | 4.35 | 6000 | 0 | 21.58 | 5300 | -700 | 6.09 | 9250 | 9250
G1 | 3FL | G1 | G1 | 廊下 | ＜ゾーン番号＞ | no | 3FL | 3 | 18.48 | 7700 | 19.18 | 2.695 | 3.85 | 6000 | 0 | 19.18 | 5300 | -700 | 5.39 | 8000 | 8000
5 x G1 | 3FL | G1 | G1 | EVホール | ＜ゾーン番号＞ | no | 3FL | 3 | 18.48 | 7700 | 19.18 | 2.695 | 3.85 | 6000 | 0 | 19.18 | 5300 | -700 | 5.39 | 8000 | 8000
2 x G1 | 3FL | G1 | G1 | 店舗 | 206 | no | 3FL | 3 | 17.28 | 7200 | 17.98 | 2.52 | 3.6 | 6000 | 0 | 17.98 | 5300 | -700 | 5.04 | 7750 | 7750
G1 | 3FL | G1 | G1 | 店舗 | 203 | no | 3FL | 3 | 17.28 | 7200 | 17.98 | 2.52 | 3.6 | 6000 | 0 | 17.98 | 5300 | -700 | 5.04 | 7750 | 7750
G1 | 3FL | G1 | G1 | 店舗 | 203 | no | 3FL | 3 | 10.219 | 4341.27 | 10.919 | 1.49028 | 2.12897 | 6000 | 0 | 10.9287 | 5300 | -700 | 2.98055 | 5068.97 | 5068.97
G1 | 3FL | G1 | G1 | 店舗 | 202 | no | 3FL | 3 | 10.219 | 4341.27 | 10.919 | 1.49028 | 2.12897 | 6000 | 0 | 10.9287 | 5300 | -700 | 2.98055 | 5068.97 | 5068.97
G1 | 3FL | G1 | G1 | 店舗 | 201 | no | 3FL | 3 | 10.219 | 4341.27 | 10.919 | 1.49028 | 2.12897 | 6000 | 0 | 10.9287 | 5300 | -700 | 2.98055 | 5068.97 | 5068.97
G1 | 3FL | G1 | G1 | 店舗 | 201 | no | 3FL | 3 | 23.28 | 9700 | 23.98 | 3.395 | 4.85 | 6000 | 0 | 23.98 | 5300 | -700 | 6.79 | 10250 | 10250
G1 | 3FL | G1 | G1 | 店舗 | 201 | no | 3FL | 3 | 21.28 | 8866.67 | 21.98 | 3.10333 | 4.43333 | 6000 | 0 | 21.98 | 5300 | -700 | 6.20667 | 9121.55 | 9204.88
G1 | 3FL | G1 | G1 | 店舗 | 202 | no | 3FL | 3 | 19.28 | 8033.33 | 19.98 | 2.81167 | 4.01667 | 6000 | 0 | 19.98 | 5300 | -700 | 5.62333 | 8288.22 | 8371.55
G1 | 3FL | G1 | G1 | ホール | ＜ゾーン番号＞ | no | 3FL | 3 | 20.88 | 8700 | 21.58 | 3.045 | 4.35 | 6000 | 0 | 21.58 | 5300 | -700 | 6.09 | 9000 | 9000
3 x G1 | 3FL | G1 | G1 | 廊下 | ＜ゾーン番号＞ | no | 3FL | 3 | 20.88 | 8700 | 21.58 | 3.045 | 4.35 | 6000 | 0 | 21.58 | 5300 | -700 | 6.09 | 9000 | 9000
G1 | 3FL | G1 | G1 | 店舗 | 214 | no | 3FL | 3 | 13.6863 | 5702.64 | 14.3863 | 1.99593 | 2.85132 | 6000 | 0 | 14.3863 | 5300 | -700 | 3.99185 | 6102.64 | 6102.64
G1 | 3FL | G1 | G1 | 事務室 | 301 | no | 3FL | 3 | 10.08 | 4200 | 10.78 | 1.47 | 2.1 | 9000 | 3000 | 10.78 | 8300 | 2300 | 2.94 | 4750 | 5250
G1 | 3FL | G1 | G1 | 事務室 | 302 | no | 3FL | 3 | 10.08 | 4200 | 10.78 | 1.47 | 2.1 | 9000 | 3000 | 10.78 | 8300 | 2300 | 2.94 | 5000 | 5000
G1 | 3FL | G1 | G1 | 事務室 | 303 | no | 3FL | 3 | 10.08 | 4200 | 10.78 | 1.47 | 2.1 | 9000 | 3000 | 10.78 | 8300 | 2300 | 2.94 | 5000 | 5000
G1 | 3FL | G1 | G1 | 事務室 | 304 | no | 3FL | 3 | 10.08 | 4200 | 10.78 | 1.47 | 2.1 | 9000 | 3000 | 10.78 | 8300 | 2300 | 2.94 | 5000 | 5000
G1 | 3FL | G1 | G1 | 事務室 | 305 | no | 3FL | 3 | 10.08 | 4200 | 10.78 | 1.47 | 2.1 | 9000 | 3000 | 10.78 | 8300 | 2300 | 2.94 | 5000 | 5000
G1 | 3FL | G1 | G1 | 事務室 | 306 | no | 3FL | 3 | 10.08 | 4200 | 10.78 | 1.47 | 2.1 | 9000 | 3000 | 10.78 | 8300 | 2300 | 2.94 | 5000 | 5000
G1 | 3FL | G1 | G1 | 事務室 | 307 | no | 3FL | 3 | 10.08 | 4200 | 10.78 | 1.47 | 2.1 | 9000 | 3000 | 10.78 | 8300 | 2300 | 2.94 | 4750 | 5250
G1 | 3FL | G1 | G1 | 事務室 | 311 | no | 3FL | 3 | 10.08 | 4200 | 10.78 | 1.47 | 2.1 | 9000 | 3000 | 10.78 | 8300 | 2300 | 2.94 | 5250 | 4750
G1 | 3FL | G1 | G1 | 事務室 | 310 | no | 3FL | 3 | 10.08 | 4200 | 10.78 | 1.47 | 2.1 | 9000 | 3000 | 10.78 | 8300 | 2300 | 2.94 | 5000 | 5000
G1 | 3FL | G1 | G1 | 男性用トイレ | ＜ゾーン番号＞ | no | 3FL | 3 | 10.08 | 4200 | 10.78 | 1.47 | 2.1 | 9000 | 3000 | 10.78 | 8300 | 2300 | 2.94 | 5000 | 5000
G1 | 3FL | G1 | G1 | EVホール | ＜ゾーン番号＞ | no | 3FL | 3 | 10.08 | 4200 | 10.78 | 1.47 | 2.1 | 9000 | 3000 | 10.78 | 8300 | 2300 | 2.94 | 5000 | 5000
G1 | 3FL | G1 | G1 | PS | ＜ゾーン番号＞ | no | 3FL | 3 | 10.08 | 4200 | 10.78 | 1.47 | 2.1 | 9000 | 3000 | 10.78 | 8300 | 2300 | 2.94 | 5000 | 5000
G1 | 3FL | G1 | G1 | 事務室 | 304 | no | 3FL | 3 | 10.08 | 4200 | 10.78 | 1.47 | 2.1 | 9000 | 3000 | 10.78 | 8300 | 2300 | 2.94 | 4729.31 | 4500
G1 | 3FL | G1 | G1 | 事務室 | 306 | no | 3FL | 3 | 13.68 | 5700 | 14.38 | 1.995 | 2.85 | 9000 | 3000 | 14.38 | 8300 | 2300 | 3.99 | 6436.01 | 6063.99
G2 | 3FL | G2 | G2 | 事務室 | 306 | no | 3FL | 3 | 10.5238 | 4534.93 | 11.2238 | 1.53473 | 2.19246 | 9000 | 3000 | 11.2547 | 8300 | 2300 | 3.06945 | 5220.15 | 4698.14
G1 | 3FL | G1 | G1 | 店舗 | 207 | no | 3FL | 3 | 13.68 | 5700 | 14.38 | 1.995 | 2.85 | 6000 | 0 | 14.38 | 5300 | -700 | 3.99 | 6436.01 | 6063.99
G2 | 3FL | G2 | G2 | 店舗 | 206 | no | 3FL | 3 | 10.5238 | 4534.93 | 11.2238 | 1.53473 | 2.19246 | 6000 | 0 | 11.2547 | 5300 | -700 | 3.06945 | 5220.15 | 4698.14
4FLG1 | 4FL | G1 | 4FLG1 | 事務室 | 304 | yes | 4FL | 4 | 10.08 | 4200 | 10.78 | 1.47 | 2.1 | 12000 | 3000 | 10.78 | 11300 | 2300 | 2.94 | 4729.31 | 4500 | 4FL
4FLG1 | 4FL | G1 | 4FLG1 | 事務室 | 305 | yes | 4FL | 4 | 17.28 | 7200 | 17.98 | 2.52 | 3.6 | 12000 | 3000 | 17.98 | 11300 | 2300 | 5.04 | 8000 | 7500 | 4FL
4FLG1 | 4FL | G1 | 4FLG1 | PS | ＜ゾーン番号＞ | yes | 4FL | 4 | 10.08 | 4200 | 10.78 | 1.47 | 2.1 | 12000 | 3000 | 10.78 | 11300 | 2300 | 2.94 | 5000 | 5000 | 4FL
4FLG1 | 4FL | G1 | 4FLG1 | EVホール | ＜ゾーン番号＞ | yes | 4FL | 4 | 10.08 | 4200 | 10.78 | 1.47 | 2.1 | 12000 | 3000 | 10.78 | 11300 | 2300 | 2.94 | 5000 | 5000 | 4FL
4FLG1 | 4FL | G1 | 4FLG1 | 男性用トイレ | ＜ゾーン番号＞ | yes | 4FL | 4 | 10.08 | 4200 | 10.78 | 1.47 | 2.1 | 12000 | 3000 | 10.78 | 11300 | 2300 | 2.94 | 5000 | 5000 | 4FL
4FLG1 | 4FL | G1 | 4FLG1 | 事務室 | 310 | yes | 4FL | 4 | 10.08 | 4200 | 10.78 | 1.47 | 2.1 | 12000 | 3000 | 10.78 | 11300 | 2300 | 2.94 | 5000 | 5000 | 4FL
4FLG1 | 4FL | G1 | 4FLG1 | 事務室 | 313 | yes | 4FL | 4 | 10.08 | 4200 | 10.78 | 1.47 | 2.1 | 12000 | 3000 | 10.78 | 11300 | 2300 | 2.94 | 5000 | 5000 | 4FL
4FLG1 | 4FL | G1 | 4FLG1 | 事務室 | 305 | yes | 4FL | 4 | 10.08 | 4200 | 10.78 | 1.47 | 2.1 | 12000 | 3000 | 10.78 | 11300 | 2300 | 2.94 | 5000 | 5000 | 4FL
4FLG1 | 4FL | G1 | 4FLG1 | 事務室 | 304 | yes | 4FL | 4 | 10.08 | 4200 | 10.78 | 1.47 | 2.1 | 12000 | 3000 | 10.78 | 11300 | 2300 | 2.94 | 5000 | 5000 | 4FL
4FLG1 | 4FL | G1 | 4FLG1 | 事務室 | 303 | yes | 4FL | 4 | 10.08 | 4200 | 10.78 | 1.47 | 2.1 | 12000 | 3000 | 10.78 | 11300 | 2300 | 2.94 | 5000 | 5000 | 4FL
4FLG1 | 4FL | G1 | 4FLG1 | 事務室 | 314 | yes | 4FL | 4 | 10.08 | 4200 | 10.78 | 1.47 | 2.1 | 12000 | 3000 | 10.78 | 11300 | 2300 | 2.94 | 5000 | 5000 | 4FL
4FLG1 | 4FL | G1 | 4FLG1 | 事務室 | 311 | yes | 4FL | 4 | 10.08 | 4200 | 10.78 | 1.47 | 2.1 | 12000 | 3000 | 10.78 | 11300 | 2300 | 2.94 | 5250 | 4750 | 4FL
4FLG1 | 4FL | G1 | 4FLG1 | 事務室 | 307 | yes | 4FL | 4 | 10.08 | 4200 | 10.78 | 1.47 | 2.1 | 12000 | 3000 | 10.78 | 11300 | 2300 | 2.94 | 4750 | 5250 | 4FL
4FLG1 | 4FL | G1 | 4FLG1 | 事務室 | 312 | yes | 4FL | 4 | 20.88 | 8700 | 21.58 | 3.045 | 4.35 | 12000 | 3000 | 21.58 | 11300 | 2300 | 6.09 | 9000 | 9500 | 4FL
4FLG1 | 4FL | G1 | 4FLG1 | 事務室 | 309 | yes | 4FL | 4 | 10.08 | 4200 | 10.78 | 1.47 | 2.1 | 12000 | 3000 | 10.78 | 11300 | 2300 | 2.94 | 5000 | 5000 | 4FL
4FLG1 | 4FL | G1 | 4FLG1 | 事務室 | 312 | yes | 4FL | 4 | 10.08 | 4200 | 10.78 | 1.47 | 2.1 | 12000 | 3000 | 10.78 | 11300 | 2300 | 2.94 | 5250 | 4750 | 4FL
4FLG1 | 4FL | G1 | 4FLG1 | 事務室 | 308 | yes | 4FL | 4 | 18.48 | 7700 | 19.18 | 2.695 | 3.85 | 12000 | 3000 | 19.18 | 11300 | 2300 | 5.39 | 8000 | 8000 | 4FL
4FLG1 | 4FL | G1 | 4FLG1 | 事務室 | 316 | yes | 4FL | 4 | 20.88 | 8700 | 21.58 | 3.045 | 4.35 | 12000 | 3000 | 21.58 | 11300 | 2300 | 6.09 | 9500 | 9000 | 4FL
4FLG1 | 4FL | G1 | 4FLG1 | 事務室 | 308 | yes | 4FL | 4 | 18.48 | 7700 | 19.18 | 2.695 | 3.85 | 12000 | 3000 | 19.18 | 11300 | 2300 | 5.39 | 9000 | 8000 | 4FL
4FLG1 | 4FL | G1 | 4FLG1 | 事務室 | 302 | yes | 4FL | 4 | 10.08 | 4200 | 10.78 | 1.47 | 2.1 | 12000 | 3000 | 10.78 | 11300 | 2300 | 2.94 | 5000 | 5000 | 4FL
4FLG1 | 4FL | G1 | 4FLG1 | 事務室 | 301 | yes | 4FL | 4 | 10.08 | 4200 | 10.78 | 1.47 | 2.1 | 12000 | 3000 | 10.78 | 11300 | 2300 | 2.94 | 4750 | 5250 | 4FL
4FLG1 | 4FL | G1 | 4FLG1 | 事務室 | 311 | yes | 4FL | 4 | 18.48 | 7700 | 19.18 | 2.695 | 3.85 | 12000 | 3000 | 19.18 | 11300 | 2300 | 5.39 | 9000 | 8000 | 4FL
4FLG1 | 4FL | G1 | 4FLG1 | 事務室 | 303 | yes | 4FL | 4 | 10.219 | 4341.27 | 10.919 | 1.49028 | 2.12897 | 12000 | 3000 | 10.9287 | 11300 | 2300 | 2.98055 | 5280.75 | 4857.19 | 4FL
4FLG1 | 4FL | G1 | 4FLG1 | 事務室 | 301 | yes | 4FL | 4 | 23.28 | 9700 | 23.98 | 3.395 | 4.85 | 12000 | 3000 | 23.98 | 11300 | 2300 | 6.79 | 10545.1 | 9954.88 | 4FL
4FLG1 | 4FL | G1 | 4FLG1 | 事務室 | 315 | yes | 4FL | 4 | 20.88 | 8700 | 21.58 | 3.045 | 4.35 | 12000 | 3000 | 21.58 | 11300 | 2300 | 6.09 | 9000 | 9000 | 4FL
4FLG1 | 4FL | G1 | 4FLG1 | 事務室 | 314 | yes | 4FL | 4 | 20.88 | 8700 | 21.58 | 3.045 | 4.35 | 12000 | 3000 | 21.58 | 11300 | 2300 | 6.09 | 9000 | 9000 | 4FL
2 x 4FLG1 | 4FL | G1 | 4FLG1 | 事務室 | 313 | yes | 4FL | 4 | 20.88 | 8700 | 21.58 | 3.045 | 4.35 | 12000 | 3000 | 21.58 | 11300 | 2300 | 6.09 | 9000 | 9000 | 4FL
4FLG1 | 4FL | G1 | 4FLG1 | 事務室 | 302 | yes | 4FL | 4 | 19.28 | 8033.33 | 19.98 | 2.81167 | 4.01667 | 12000 | 3000 | 19.98 | 11300 | 2300 | 5.62333 | 8288.22 | 8371.55 | 4FL
4FLG1 | 4FL | G1 | 4FLG1 | EVホール | ＜ゾーン番号＞ | yes | 4FL | 4 | 18.48 | 7700 | 19.18 | 2.695 | 3.85 | 12000 | 3000 | 19.18 | 11300 | 2300 | 5.39 | 8000 | 8000 | 4FL
2 x 4FLG1 | 4FL | G1 | 4FLG1 | 事務室 | 310 | yes | 4FL | 4 | 18.48 | 7700 | 19.18 | 2.695 | 3.85 | 12000 | 3000 | 19.18 | 11300 | 2300 | 5.39 | 8000 | 8000 | 4FL
4FLG1 | 4FL | G1 | 4FLG1 | 事務室 | 316 | yes | 4FL | 4 | 10.08 | 4200 | 10.78 | 1.47 | 2.1 | 12000 | 3000 | 10.78 | 11300 | 2300 | 2.94 | 5250 | 4750 | 4FL
4FLG1 | 4FL | G1 | 4FLG1 | 事務室 | 315 | yes | 4FL | 4 | 10.08 | 4200 | 10.78 | 1.47 | 2.1 | 12000 | 3000 | 10.78 | 11300 | 2300 | 2.94 | 5000 | 5000 | 4FL
4FLG1 | 4FL | G1 | 4FLG1 | PS | ＜ゾーン番号＞ | yes | 4FL | 4 | 18.48 | 7700 | 19.18 | 2.695 | 3.85 | 12000 | 3000 | 19.18 | 11300 | 2300 | 5.39 | 8000 | 8000 | 4FL
4FLG1 | 4FL | G1 | 4FLG1 | 事務室 | 306 | yes | 4FL | 4 | 10.08 | 4200 | 10.78 | 1.47 | 2.1 | 12000 | 3000 | 10.78 | 11300 | 2300 | 2.94 | 5000 | 5000 | 4FL
4FLG1 | 4FL | G1 | 4FLG1 | 事務室 | 305 | yes | 4FL | 4 | 10.08 | 4200 | 10.78 | 1.47 | 2.1 | 12000 | 3000 | 10.78 | 11300 | 2300 | 2.94 | 5500 | 4500 | 4FL
4FLG1 | 4FL | G1 | 4FLG1 | 事務室 | 303 | yes | 4FL | 4 | 17.28 | 7200 | 17.98 | 2.52 | 3.6 | 12000 | 3000 | 17.98 | 11300 | 2300 | 5.04 | 7961.78 | 7538.22 | 4FL
4FLG1 | 4FL | G1 | 4FLG1 | 事務室 | 301 | yes | 4FL | 4 | 10.219 | 4341.27 | 10.919 | 1.49028 | 2.12897 | 12000 | 3000 | 10.9287 | 11300 | 2300 | 2.98055 | 5364.08 | 4773.85 | 4FL
4FLG1 | 4FL | G1 | 4FLG1 | EVシャフト | ＜ゾーン番号＞ | yes | 4FL | 4 | 18.48 | 7700 | 19.18 | 2.695 | 3.85 | 12000 | 3000 | 19.18 | 11300 | 2300 | 5.39 | 8000 | 8000 | 4FL
4FLG1 | 4FL | G1 | 4FLG1 | 事務室 | 301 | yes | 4FL | 4 | 21.28 | 8866.67 | 21.98 | 3.10333 | 4.43333 | 12000 | 3000 | 21.98 | 11300 | 2300 | 6.20667 | 9121.55 | 9204.88 | 4FL
4FLG1 | 4FL | G1 | 4FLG1 | 事務室 | 304 | yes | 4FL | 4 | 17.28 | 7200 | 17.98 | 2.52 | 3.6 | 12000 | 3000 | 17.98 | 11300 | 2300 | 5.04 | 8000 | 7500 | 4FL
4FLG1 | 4FL | G1 | 4FLG1 | 事務室 | 302 | yes | 4FL | 4 | 10.219 | 4341.27 | 10.919 | 1.49028 | 2.12897 | 12000 | 3000 | 10.9287 | 11300 | 2300 | 2.98055 | 5068.97 | 5068.97 | 4FL
4FLG1 | 4FL | G1 | 4FLG1 | 事務室 | 308 | yes | 4FL | 4 | 10.08 | 4200 | 10.78 | 1.47 | 2.1 | 12000 | 3000 | 10.78 | 11300 | 2300 | 2.94 | 5250 | 4750 | 4FL
4FLG2 | 4FL | G2 | 4FLG2 | 事務室 | 306 | yes | 4FL | 4 | 10.5238 | 4534.93 | 11.2238 | 1.53473 | 2.19246 | 12000 | 3000 | 11.2547 | 11300 | 2300 | 3.06945 | 5220.15 | 4698.14 | 4FL
4FLG1 | 4FL | G1 | 4FLG1 | 事務室 | 306 | yes | 4FL | 4 | 13.68 | 5700 | 14.38 | 1.995 | 2.85 | 12000 | 3000 | 14.38 | 11300 | 2300 | 3.99 | 6436.01 | 6063.99 | 4FL
5FLG1 | 5FL | G1 | 5FLG1 | 事務室 | 304 | yes | 5FL | 5 | 10.08 | 4200 | 10.78 | 1.47 | 2.1 | 15000 | 3000 | 10.78 | 14300 | 2300 | 2.94 | 4729.31 | 4500 | 5FL
5FLG1 | 5FL | G1 | 5FLG1 | 事務室 | 305 | yes | 5FL | 5 | 17.28 | 7200 | 17.98 | 2.52 | 3.6 | 15000 | 3000 | 17.98 | 14300 | 2300 | 5.04 | 8000 | 7500 | 5FL
5FLG1 | 5FL | G1 | 5FLG1 | PS | ＜ゾーン番号＞ | yes | 5FL | 5 | 10.08 | 4200 | 10.78 | 1.47 | 2.1 | 15000 | 3000 | 10.78 | 14300 | 2300 | 2.94 | 5000 | 5000 | 5FL
5FLG1 | 5FL | G1 | 5FLG1 | EVホール | ＜ゾーン番号＞ | yes | 5FL | 5 | 10.08 | 4200 | 10.78 | 1.47 | 2.1 | 15000 | 3000 | 10.78 | 14300 | 2300 | 2.94 | 5000 | 5000 | 5FL
5FLG1 | 5FL | G1 | 5FLG1 | 男性用トイレ | ＜ゾーン番号＞ | yes | 5FL | 5 | 10.08 | 4200 | 10.78 | 1.47 | 2.1 | 15000 | 3000 | 10.78 | 14300 | 2300 | 2.94 | 5000 | 5000 | 5FL
5FLG1 | 5FL | G1 | 5FLG1 | 事務室 | 310 | yes | 5FL | 5 | 10.08 | 4200 | 10.78 | 1.47 | 2.1 | 15000 | 3000 | 10.78 | 14300 | 2300 | 2.94 | 5000 | 5000 | 5FL
5FLG1 | 5FL | G1 | 5FLG1 | 事務室 | 313 | yes | 5FL | 5 | 10.08 | 4200 | 10.78 | 1.47 | 2.1 | 15000 | 3000 | 10.78 | 14300 | 2300 | 2.94 | 5000 | 5000 | 5FL
5FLG1 | 5FL | G1 | 5FLG1 | 事務室 | 305 | yes | 5FL | 5 | 10.08 | 4200 | 10.78 | 1.47 | 2.1 | 15000 | 3000 | 10.78 | 14300 | 2300 | 2.94 | 5000 | 5000 | 5FL
5FLG1 | 5FL | G1 | 5FLG1 | 事務室 | 304 | yes | 5FL | 5 | 10.08 | 4200 | 10.78 | 1.47 | 2.1 | 15000 | 3000 | 10.78 | 14300 | 2300 | 2.94 | 5000 | 5000 | 5FL
5FLG1 | 5FL | G1 | 5FLG1 | 事務室 | 303 | yes | 5FL | 5 | 10.08 | 4200 | 10.78 | 1.47 | 2.1 | 15000 | 3000 | 10.78 | 14300 | 2300 | 2.94 | 5000 | 5000 | 5FL
5FLG1 | 5FL | G1 | 5FLG1 | 事務室 | 314 | yes | 5FL | 5 | 10.08 | 4200 | 10.78 | 1.47 | 2.1 | 15000 | 3000 | 10.78 | 14300 | 2300 | 2.94 | 5000 | 5000 | 5FL
5FLG1 | 5FL | G1 | 5FLG1 | 事務室 | 311 | yes | 5FL | 5 | 10.08 | 4200 | 10.78 | 1.47 | 2.1 | 15000 | 3000 | 10.78 | 14300 | 2300 | 2.94 | 5250 | 4750 | 5FL
5FLG1 | 5FL | G1 | 5FLG1 | 事務室 | 307 | yes | 5FL | 5 | 10.08 | 4200 | 10.78 | 1.47 | 2.1 | 15000 | 3000 | 10.78 | 14300 | 2300 | 2.94 | 4750 | 5250 | 5FL
5FLG1 | 5FL | G1 | 5FLG1 | 事務室 | 312 | yes | 5FL | 5 | 20.88 | 8700 | 21.58 | 3.045 | 4.35 | 15000 | 3000 | 21.58 | 14300 | 2300 | 6.09 | 9000 | 9500 | 5FL
5FLG1 | 5FL | G1 | 5FLG1 | 事務室 | 309 | yes | 5FL | 5 | 10.08 | 4200 | 10.78 | 1.47 | 2.1 | 15000 | 3000 | 10.78 | 14300 | 2300 | 2.94 | 5000 | 5000 | 5FL
5FLG1 | 5FL | G1 | 5FLG1 | 事務室 | 312 | yes | 5FL | 5 | 10.08 | 4200 | 10.78 | 1.47 | 2.1 | 15000 | 3000 | 10.78 | 14300 | 2300 | 2.94 | 5250 | 4750 | 5FL
5FLG1 | 5FL | G1 | 5FLG1 | 事務室 | 308 | yes | 5FL | 5 | 18.48 | 7700 | 19.18 | 2.695 | 3.85 | 15000 | 3000 | 19.18 | 14300 | 2300 | 5.39 | 8000 | 8000 | 5FL
5FLG1 | 5FL | G1 | 5FLG1 | 事務室 | 316 | yes | 5FL | 5 | 20.88 | 8700 | 21.58 | 3.045 | 4.35 | 15000 | 3000 | 21.58 | 14300 | 2300 | 6.09 | 9500 | 9000 | 5FL
5FLG1 | 5FL | G1 | 5FLG1 | 事務室 | 308 | yes | 5FL | 5 | 18.48 | 7700 | 19.18 | 2.695 | 3.85 | 15000 | 3000 | 19.18 | 14300 | 2300 | 5.39 | 9000 | 8000 | 5FL
5FLG1 | 5FL | G1 | 5FLG1 | 事務室 | 302 | yes | 5FL | 5 | 10.08 | 4200 | 10.78 | 1.47 | 2.1 | 15000 | 3000 | 10.78 | 14300 | 2300 | 2.94 | 5000 | 5000 | 5FL
5FLG1 | 5FL | G1 | 5FLG1 | 事務室 | 301 | yes | 5FL | 5 | 10.08 | 4200 | 10.78 | 1.47 | 2.1 | 15000 | 3000 | 10.78 | 14300 | 2300 | 2.94 | 4750 | 5250 | 5FL
5FLG1 | 5FL | G1 | 5FLG1 | 事務室 | 311 | yes | 5FL | 5 | 18.48 | 7700 | 19.18 | 2.695 | 3.85 | 15000 | 3000 | 19.18 | 14300 | 2300 | 5.39 | 9000 | 8000 | 5FL
5FLG1 | 5FL | G1 | 5FLG1 | 事務室 | 303 | yes | 5FL | 5 | 10.219 | 4341.27 | 10.919 | 1.49028 | 2.12897 | 15000 | 3000 | 10.9287 | 14300 | 2300 | 2.98055 | 5280.75 | 4857.19 | 5FL
5FLG1 | 5FL | G1 | 5FLG1 | 事務室 | 301 | yes | 5FL | 5 | 23.28 | 9700 | 23.98 | 3.395 | 4.85 | 15000 | 3000 | 23.98 | 14300 | 2300 | 6.79 | 10545.1 | 9954.88 | 5FL
5FLG1 | 5FL | G1 | 5FLG1 | 事務室 | 315 | yes | 5FL | 5 | 20.88 | 8700 | 21.58 | 3.045 | 4.35 | 15000 | 3000 | 21.58 | 14300 | 2300 | 6.09 | 9000 | 9000 | 5FL
5FLG1 | 5FL | G1 | 5FLG1 | 事務室 | 314 | yes | 5FL | 5 | 20.88 | 8700 | 21.58 | 3.045 | 4.35 | 15000 | 3000 | 21.58 | 14300 | 2300 | 6.09 | 9000 | 9000 | 5FL
2 x 5FLG1 | 5FL | G1 | 5FLG1 | 事務室 | 313 | yes | 5FL | 5 | 20.88 | 8700 | 21.58 | 3.045 | 4.35 | 15000 | 3000 | 21.58 | 14300 | 2300 | 6.09 | 9000 | 9000 | 5FL
5FLG1 | 5FL | G1 | 5FLG1 | 事務室 | 302 | yes | 5FL | 5 | 19.28 | 8033.33 | 19.98 | 2.81167 | 4.01667 | 15000 | 3000 | 19.98 | 14300 | 2300 | 5.62333 | 8288.22 | 8371.55 | 5FL
5FLG1 | 5FL | G1 | 5FLG1 | EVホール | ＜ゾーン番号＞ | yes | 5FL | 5 | 18.48 | 7700 | 19.18 | 2.695 | 3.85 | 15000 | 3000 | 19.18 | 14300 | 2300 | 5.39 | 8000 | 8000 | 5FL
2 x 5FLG1 | 5FL | G1 | 5FLG1 | 事務室 | 310 | yes | 5FL | 5 | 18.48 | 7700 | 19.18 | 2.695 | 3.85 | 15000 | 3000 | 19.18 | 14300 | 2300 | 5.39 | 8000 | 8000 | 5FL
5FLG1 | 5FL | G1 | 5FLG1 | 事務室 | 316 | yes | 5FL | 5 | 10.08 | 4200 | 10.78 | 1.47 | 2.1 | 15000 | 3000 | 10.78 | 14300 | 2300 | 2.94 | 5250 | 4750 | 5FL
5FLG1 | 5FL | G1 | 5FLG1 | 事務室 | 315 | yes | 5FL | 5 | 10.08 | 4200 | 10.78 | 1.47 | 2.1 | 15000 | 3000 | 10.78 | 14300 | 2300 | 2.94 | 5000 | 5000 | 5FL
5FLG1 | 5FL | G1 | 5FLG1 | PS | ＜ゾーン番号＞ | yes | 5FL | 5 | 18.48 | 7700 | 19.18 | 2.695 | 3.85 | 15000 | 3000 | 19.18 | 14300 | 2300 | 5.39 | 8000 | 8000 | 5FL
5FLG1 | 5FL | G1 | 5FLG1 | 事務室 | 306 | yes | 5FL | 5 | 10.08 | 4200 | 10.78 | 1.47 | 2.1 | 15000 | 3000 | 10.78 | 14300 | 2300 | 2.94 | 5000 | 5000 | 5FL
5FLG1 | 5FL | G1 | 5FLG1 | 事務室 | 305 | yes | 5FL | 5 | 10.08 | 4200 | 10.78 | 1.47 | 2.1 | 15000 | 3000 | 10.78 | 14300 | 2300 | 2.94 | 5500 | 4500 | 5FL
5FLG1 | 5FL | G1 | 5FLG1 | 事務室 | 303 | yes | 5FL | 5 | 17.28 | 7200 | 17.98 | 2.52 | 3.6 | 15000 | 3000 | 17.98 | 14300 | 2300 | 5.04 | 7961.78 | 7538.22 | 5FL
5FLG1 | 5FL | G1 | 5FLG1 | 事務室 | 301 | yes | 5FL | 5 | 10.219 | 4341.27 | 10.919 | 1.49028 | 2.12897 | 15000 | 3000 | 10.9287 | 14300 | 2300 | 2.98055 | 5364.08 | 4773.85 | 5FL
5FLG1 | 5FL | G1 | 5FLG1 | EVシャフト | ＜ゾーン番号＞ | yes | 5FL | 5 | 18.48 | 7700 | 19.18 | 2.695 | 3.85 | 15000 | 3000 | 19.18 | 14300 | 2300 | 5.39 | 8000 | 8000 | 5FL
5FLG1 | 5FL | G1 | 5FLG1 | 事務室 | 301 | yes | 5FL | 5 | 21.28 | 8866.67 | 21.98 | 3.10333 | 4.43333 | 15000 | 3000 | 21.98 | 14300 | 2300 | 6.20667 | 9121.55 | 9204.88 | 5FL
5FLG1 | 5FL | G1 | 5FLG1 | 事務室 | 304 | yes | 5FL | 5 | 17.28 | 7200 | 17.98 | 2.52 | 3.6 | 15000 | 3000 | 17.98 | 14300 | 2300 | 5.04 | 8000 | 7500 | 5FL
5FLG1 | 5FL | G1 | 5FLG1 | 事務室 | 302 | yes | 5FL | 5 | 10.219 | 4341.27 | 10.919 | 1.49028 | 2.12897 | 15000 | 3000 | 10.9287 | 14300 | 2300 | 2.98055 | 5068.97 | 5068.97 | 5FL
5FLG1 | 5FL | G1 | 5FLG1 | 事務室 | 308 | yes | 5FL | 5 | 10.08 | 4200 | 10.78 | 1.47 | 2.1 | 15000 | 3000 | 10.78 | 14300 | 2300 | 2.94 | 5250 | 4750 | 5FL
5FLG2 | 5FL | G2 | 5FLG2 | 事務室 | 306 | yes | 5FL | 5 | 10.5238 | 4534.93 | 11.2238 | 1.53473 | 2.19246 | 15000 | 3000 | 11.2547 | 14300 | 2300 | 3.06945 | 5220.15 | 4698.14 | 5FL
5FLG1 | 5FL | G1 | 5FLG1 | 事務室 | 306 | yes | 5FL | 5 | 13.68 | 5700 | 14.38 | 1.995 | 2.85 | 15000 | 3000 | 14.38 | 14300 | 2300 | 3.99 | 6436.01 | 6063.99 | 5FL
6FLG1 | 6FL | G1 | 6FLG1 | 事務室 | 304 | yes | 6FL | 6 | 10.08 | 4200 | 10.78 | 1.47 | 2.1 | 18000 | 3000 | 10.78 | 17300 | 2300 | 2.94 | 4729.31 | 4500 | 6FL
6FLG1 | 6FL | G1 | 6FLG1 | 事務室 | 305 | yes | 6FL | 6 | 17.28 | 7200 | 17.98 | 2.52 | 3.6 | 18000 | 3000 | 17.98 | 17300 | 2300 | 5.04 | 8000 | 7500 | 6FL
6FLG1 | 6FL | G1 | 6FLG1 | PS | ＜ゾーン番号＞ | yes | 6FL | 6 | 10.08 | 4200 | 10.78 | 1.47 | 2.1 | 18000 | 3000 | 10.78 | 17300 | 2300 | 2.94 | 5000 | 5000 | 6FL
6FLG1 | 6FL | G1 | 6FLG1 | EVホール | ＜ゾーン番号＞ | yes | 6FL | 6 | 10.08 | 4200 | 10.78 | 1.47 | 2.1 | 18000 | 3000 | 10.78 | 17300 | 2300 | 2.94 | 5000 | 5000 | 6FL
6FLG1 | 6FL | G1 | 6FLG1 | 男性用トイレ | ＜ゾーン番号＞ | yes | 6FL | 6 | 10.08 | 4200 | 10.78 | 1.47 | 2.1 | 18000 | 3000 | 10.78 | 17300 | 2300 | 2.94 | 5000 | 5000 | 6FL
6FLG1 | 6FL | G1 | 6FLG1 | 事務室 | 310 | yes | 6FL | 6 | 10.08 | 4200 | 10.78 | 1.47 | 2.1 | 18000 | 3000 | 10.78 | 17300 | 2300 | 2.94 | 5000 | 5000 | 6FL
6FLG1 | 6FL | G1 | 6FLG1 | 事務室 | 313 | yes | 6FL | 6 | 10.08 | 4200 | 10.78 | 1.47 | 2.1 | 18000 | 3000 | 10.78 | 17300 | 2300 | 2.94 | 5000 | 5000 | 6FL
6FLG1 | 6FL | G1 | 6FLG1 | 事務室 | 305 | yes | 6FL | 6 | 10.08 | 4200 | 10.78 | 1.47 | 2.1 | 18000 | 3000 | 10.78 | 17300 | 2300 | 2.94 | 5000 | 5000 | 6FL
6FLG1 | 6FL | G1 | 6FLG1 | 事務室 | 304 | yes | 6FL | 6 | 10.08 | 4200 | 10.78 | 1.47 | 2.1 | 18000 | 3000 | 10.78 | 17300 | 2300 | 2.94 | 5000 | 5000 | 6FL
6FLG1 | 6FL | G1 | 6FLG1 | 事務室 | 303 | yes | 6FL | 6 | 10.08 | 4200 | 10.78 | 1.47 | 2.1 | 18000 | 3000 | 10.78 | 17300 | 2300 | 2.94 | 5000 | 5000 | 6FL
6FLG1 | 6FL | G1 | 6FLG1 | 事務室 | 314 | yes | 6FL | 6 | 10.08 | 4200 | 10.78 | 1.47 | 2.1 | 18000 | 3000 | 10.78 | 17300 | 2300 | 2.94 | 5000 | 5000 | 6FL
6FLG1 | 6FL | G1 | 6FLG1 | 事務室 | 311 | yes | 6FL | 6 | 10.08 | 4200 | 10.78 | 1.47 | 2.1 | 18000 | 3000 | 10.78 | 17300 | 2300 | 2.94 | 5250 | 4750 | 6FL
6FLG1 | 6FL | G1 | 6FLG1 | 事務室 | 307 | yes | 6FL | 6 | 10.08 | 4200 | 10.78 | 1.47 | 2.1 | 18000 | 3000 | 10.78 | 17300 | 2300 | 2.94 | 4750 | 5250 | 6FL
6FLG1 | 6FL | G1 | 6FLG1 | 事務室 | 312 | yes | 6FL | 6 | 20.88 | 8700 | 21.58 | 3.045 | 4.35 | 18000 | 3000 | 21.58 | 17300 | 2300 | 6.09 | 9000 | 9500 | 6FL
6FLG1 | 6FL | G1 | 6FLG1 | 事務室 | 309 | yes | 6FL | 6 | 10.08 | 4200 | 10.78 | 1.47 | 2.1 | 18000 | 3000 | 10.78 | 17300 | 2300 | 2.94 | 5000 | 5000 | 6FL
6FLG1 | 6FL | G1 | 6FLG1 | 事務室 | 312 | yes | 6FL | 6 | 10.08 | 4200 | 10.78 | 1.47 | 2.1 | 18000 | 3000 | 10.78 | 17300 | 2300 | 2.94 | 5250 | 4750 | 6FL
6FLG1 | 6FL | G1 | 6FLG1 | 事務室 | 308 | yes | 6FL | 6 | 18.48 | 7700 | 19.18 | 2.695 | 3.85 | 18000 | 3000 | 19.18 | 17300 | 2300 | 5.39 | 8000 | 8000 | 6FL
6FLG1 | 6FL | G1 | 6FLG1 | 事務室 | 316 | yes | 6FL | 6 | 20.88 | 8700 | 21.58 | 3.045 | 4.35 | 18000 | 3000 | 21.58 | 17300 | 2300 | 6.09 | 9500 | 9000 | 6FL
6FLG1 | 6FL | G1 | 6FLG1 | 事務室 | 308 | yes | 6FL | 6 | 18.48 | 7700 | 19.18 | 2.695 | 3.85 | 18000 | 3000 | 19.18 | 17300 | 2300 | 5.39 | 9000 | 8000 | 6FL
6FLG1 | 6FL | G1 | 6FLG1 | 事務室 | 302 | yes | 6FL | 6 | 10.08 | 4200 | 10.78 | 1.47 | 2.1 | 18000 | 3000 | 10.78 | 17300 | 2300 | 2.94 | 5000 | 5000 | 6FL
6FLG1 | 6FL | G1 | 6FLG1 | 事務室 | 301 | yes | 6FL | 6 | 10.08 | 4200 | 10.78 | 1.47 | 2.1 | 18000 | 3000 | 10.78 | 17300 | 2300 | 2.94 | 4750 | 5250 | 6FL
6FLG1 | 6FL | G1 | 6FLG1 | 事務室 | 311 | yes | 6FL | 6 | 18.48 | 7700 | 19.18 | 2.695 | 3.85 | 18000 | 3000 | 19.18 | 17300 | 2300 | 5.39 | 9000 | 8000 | 6FL
6FLG1 | 6FL | G1 | 6FLG1 | 事務室 | 303 | yes | 6FL | 6 | 10.219 | 4341.27 | 10.919 | 1.49028 | 2.12897 | 18000 | 3000 | 10.9287 | 17300 | 2300 | 2.98055 | 5280.75 | 4857.19 | 6FL
6FLG1 | 6FL | G1 | 6FLG1 | 事務室 | 301 | yes | 6FL | 6 | 23.28 | 9700 | 23.98 | 3.395 | 4.85 | 18000 | 3000 | 23.98 | 17300 | 2300 | 6.79 | 10545.1 | 9954.88 | 6FL
6FLG1 | 6FL | G1 | 6FLG1 | 事務室 | 315 | yes | 6FL | 6 | 20.88 | 8700 | 21.58 | 3.045 | 4.35 | 18000 | 3000 | 21.58 | 17300 | 2300 | 6.09 | 9000 | 9000 | 6FL
6FLG1 | 6FL | G1 | 6FLG1 | 事務室 | 314 | yes | 6FL | 6 | 20.88 | 8700 | 21.58 | 3.045 | 4.35 | 18000 | 3000 | 21.58 | 17300 | 2300 | 6.09 | 9000 | 9000 | 6FL
2 x 6FLG1 | 6FL | G1 | 6FLG1 | 事務室 | 313 | yes | 6FL | 6 | 20.88 | 8700 | 21.58 | 3.045 | 4.35 | 18000 | 3000 | 21.58 | 17300 | 2300 | 6.09 | 9000 | 9000 | 6FL
6FLG1 | 6FL | G1 | 6FLG1 | 事務室 | 302 | yes | 6FL | 6 | 19.28 | 8033.33 | 19.98 | 2.81167 | 4.01667 | 18000 | 3000 | 19.98 | 17300 | 2300 | 5.62333 | 8288.22 | 8371.55 | 6FL
6FLG1 | 6FL | G1 | 6FLG1 | EVホール | ＜ゾーン番号＞ | yes | 6FL | 6 | 18.48 | 7700 | 19.18 | 2.695 | 3.85 | 18000 | 3000 | 19.18 | 17300 | 2300 | 5.39 | 8000 | 8000 | 6FL
2 x 6FLG1 | 6FL | G1 | 6FLG1 | 事務室 | 310 | yes | 6FL | 6 | 18.48 | 7700 | 19.18 | 2.695 | 3.85 | 18000 | 3000 | 19.18 | 17300 | 2300 | 5.39 | 8000 | 8000 | 6FL
6FLG1 | 6FL | G1 | 6FLG1 | 事務室 | 316 | yes | 6FL | 6 | 10.08 | 4200 | 10.78 | 1.47 | 2.1 | 18000 | 3000 | 10.78 | 17300 | 2300 | 2.94 | 5250 | 4750 | 6FL
6FLG1 | 6FL | G1 | 6FLG1 | 事務室 | 315 | yes | 6FL | 6 | 10.08 | 4200 | 10.78 | 1.47 | 2.1 | 18000 | 3000 | 10.78 | 17300 | 2300 | 2.94 | 5000 | 5000 | 6FL
6FLG1 | 6FL | G1 | 6FLG1 | PS | ＜ゾーン番号＞ | yes | 6FL | 6 | 18.48 | 7700 | 19.18 | 2.695 | 3.85 | 18000 | 3000 | 19.18 | 17300 | 2300 | 5.39 | 8000 | 8000 | 6FL
6FLG1 | 6FL | G1 | 6FLG1 | 事務室 | 306 | yes | 6FL | 6 | 10.08 | 4200 | 10.78 | 1.47 | 2.1 | 18000 | 3000 | 10.78 | 17300 | 2300 | 2.94 | 5000 | 5000 | 6FL
6FLG1 | 6FL | G1 | 6FLG1 | 事務室 | 305 | yes | 6FL | 6 | 10.08 | 4200 | 10.78 | 1.47 | 2.1 | 18000 | 3000 | 10.78 | 17300 | 2300 | 2.94 | 5500 | 4500 | 6FL
6FLG1 | 6FL | G1 | 6FLG1 | 事務室 | 303 | yes | 6FL | 6 | 17.28 | 7200 | 17.98 | 2.52 | 3.6 | 18000 | 3000 | 17.98 | 17300 | 2300 | 5.04 | 7961.78 | 7538.22 | 6FL
6FLG1 | 6FL | G1 | 6FLG1 | 事務室 | 301 | yes | 6FL | 6 | 10.219 | 4341.27 | 10.919 | 1.49028 | 2.12897 | 18000 | 3000 | 10.9287 | 17300 | 2300 | 2.98055 | 5364.08 | 4773.85 | 6FL
6FLG1 | 6FL | G1 | 6FLG1 | EVシャフト | ＜ゾーン番号＞ | yes | 6FL | 6 | 18.48 | 7700 | 19.18 | 2.695 | 3.85 | 18000 | 3000 | 19.18 | 17300 | 2300 | 5.39 | 8000 | 8000 | 6FL
6FLG1 | 6FL | G1 | 6FLG1 | 事務室 | 301 | yes | 6FL | 6 | 21.28 | 8866.67 | 21.98 | 3.10333 | 4.43333 | 18000 | 3000 | 21.98 | 17300 | 2300 | 6.20667 | 9121.55 | 9204.88 | 6FL
6FLG1 | 6FL | G1 | 6FLG1 | 事務室 | 304 | yes | 6FL | 6 | 17.28 | 7200 | 17.98 | 2.52 | 3.6 | 18000 | 3000 | 17.98 | 17300 | 2300 | 5.04 | 8000 | 7500 | 6FL
6FLG1 | 6FL | G1 | 6FLG1 | 事務室 | 302 | yes | 6FL | 6 | 10.219 | 4341.27 | 10.919 | 1.49028 | 2.12897 | 18000 | 3000 | 10.9287 | 17300 | 2300 | 2.98055 | 5068.97 | 5068.97 | 6FL
6FLG1 | 6FL | G1 | 6FLG1 | 事務室 | 308 | yes | 6FL | 6 | 10.08 | 4200 | 10.78 | 1.47 | 2.1 | 18000 | 3000 | 10.78 | 17300 | 2300 | 2.94 | 5250 | 4750 | 6FL
6FLG2 | 6FL | G2 | 6FLG2 | 事務室 | 306 | yes | 6FL | 6 | 10.5238 | 4534.93 | 11.2238 | 1.53473 | 2.19246 | 18000 | 3000 | 11.2547 | 17300 | 2300 | 3.06945 | 5220.15 | 4698.14 | 6FL
6FLG1 | 6FL | G1 | 6FLG1 | 事務室 | 306 | yes | 6FL | 6 | 13.68 | 5700 | 14.38 | 1.995 | 2.85 | 18000 | 3000 | 14.38 | 17300 | 2300 | 3.99 | 6436.01 | 6063.99 | 6FL
7FLG1 | 7FL | G1 | 7FLG1 | 事務室 | 304 | yes | 7FL | 7 | 10.08 | 4200 | 10.78 | 1.47 | 2.1 | 21000 | 3000 | 10.78 | 20300 | 2300 | 2.94 | 4729.31 | 4500 | 7FL
7FLG1 | 7FL | G1 | 7FLG1 | 事務室 | 305 | yes | 7FL | 7 | 17.28 | 7200 | 17.98 | 2.52 | 3.6 | 21000 | 3000 | 17.98 | 20300 | 2300 | 5.04 | 8000 | 7500 | 7FL
7FLG1 | 7FL | G1 | 7FLG1 | PS | ＜ゾーン番号＞ | yes | 7FL | 7 | 10.08 | 4200 | 10.78 | 1.47 | 2.1 | 21000 | 3000 | 10.78 | 20300 | 2300 | 2.94 | 5000 | 5000 | 7FL
7FLG1 | 7FL | G1 | 7FLG1 | EVホール | ＜ゾーン番号＞ | yes | 7FL | 7 | 10.08 | 4200 | 10.78 | 1.47 | 2.1 | 21000 | 3000 | 10.78 | 20300 | 2300 | 2.94 | 5000 | 5000 | 7FL
7FLG1 | 7FL | G1 | 7FLG1 | 男性用トイレ | ＜ゾーン番号＞ | yes | 7FL | 7 | 10.08 | 4200 | 10.78 | 1.47 | 2.1 | 21000 | 3000 | 10.78 | 20300 | 2300 | 2.94 | 5000 | 5000 | 7FL
7FLG1 | 7FL | G1 | 7FLG1 | 事務室 | 310 | yes | 7FL | 7 | 10.08 | 4200 | 10.78 | 1.47 | 2.1 | 21000 | 3000 | 10.78 | 20300 | 2300 | 2.94 | 5000 | 5000 | 7FL
7FLG1 | 7FL | G1 | 7FLG1 | 事務室 | 313 | yes | 7FL | 7 | 10.08 | 4200 | 10.78 | 1.47 | 2.1 | 21000 | 3000 | 10.78 | 20300 | 2300 | 2.94 | 5000 | 5000 | 7FL
7FLG1 | 7FL | G1 | 7FLG1 | 事務室 | 305 | yes | 7FL | 7 | 10.08 | 4200 | 10.78 | 1.47 | 2.1 | 21000 | 3000 | 10.78 | 20300 | 2300 | 2.94 | 5000 | 5000 | 7FL
7FLG1 | 7FL | G1 | 7FLG1 | 事務室 | 304 | yes | 7FL | 7 | 10.08 | 4200 | 10.78 | 1.47 | 2.1 | 21000 | 3000 | 10.78 | 20300 | 2300 | 2.94 | 5000 | 5000 | 7FL
7FLG1 | 7FL | G1 | 7FLG1 | 事務室 | 303 | yes | 7FL | 7 | 10.08 | 4200 | 10.78 | 1.47 | 2.1 | 21000 | 3000 | 10.78 | 20300 | 2300 | 2.94 | 5000 | 5000 | 7FL
7FLG1 | 7FL | G1 | 7FLG1 | 事務室 | 314 | yes | 7FL | 7 | 10.08 | 4200 | 10.78 | 1.47 | 2.1 | 21000 | 3000 | 10.78 | 20300 | 2300 | 2.94 | 5000 | 5000 | 7FL
7FLG1 | 7FL | G1 | 7FLG1 | 事務室 | 311 | yes | 7FL | 7 | 10.08 | 4200 | 10.78 | 1.47 | 2.1 | 21000 | 3000 | 10.78 | 20300 | 2300 | 2.94 | 5250 | 4750 | 7FL
7FLG1 | 7FL | G1 | 7FLG1 | 事務室 | 307 | yes | 7FL | 7 | 10.08 | 4200 | 10.78 | 1.47 | 2.1 | 21000 | 3000 | 10.78 | 20300 | 2300 | 2.94 | 4750 | 5250 | 7FL
7FLG1 | 7FL | G1 | 7FLG1 | 事務室 | 312 | yes | 7FL | 7 | 20.88 | 8700 | 21.58 | 3.045 | 4.35 | 21000 | 3000 | 21.58 | 20300 | 2300 | 6.09 | 9000 | 9500 | 7FL
7FLG1 | 7FL | G1 | 7FLG1 | 事務室 | 309 | yes | 7FL | 7 | 10.08 | 4200 | 10.78 | 1.47 | 2.1 | 21000 | 3000 | 10.78 | 20300 | 2300 | 2.94 | 5000 | 5000 | 7FL
7FLG1 | 7FL | G1 | 7FLG1 | 事務室 | 312 | yes | 7FL | 7 | 10.08 | 4200 | 10.78 | 1.47 | 2.1 | 21000 | 3000 | 10.78 | 20300 | 2300 | 2.94 | 5250 | 4750 | 7FL
7FLG1 | 7FL | G1 | 7FLG1 | 事務室 | 308 | yes | 7FL | 7 | 18.48 | 7700 | 19.18 | 2.695 | 3.85 | 21000 | 3000 | 19.18 | 20300 | 2300 | 5.39 | 8000 | 8000 | 7FL
7FLG1 | 7FL | G1 | 7FLG1 | 事務室 | 316 | yes | 7FL | 7 | 20.88 | 8700 | 21.58 | 3.045 | 4.35 | 21000 | 3000 | 21.58 | 20300 | 2300 | 6.09 | 9500 | 9000 | 7FL
7FLG1 | 7FL | G1 | 7FLG1 | 事務室 | 308 | yes | 7FL | 7 | 18.48 | 7700 | 19.18 | 2.695 | 3.85 | 21000 | 3000 | 19.18 | 20300 | 2300 | 5.39 | 9000 | 8000 | 7FL
7FLG1 | 7FL | G1 | 7FLG1 | 事務室 | 302 | yes | 7FL | 7 | 10.08 | 4200 | 10.78 | 1.47 | 2.1 | 21000 | 3000 | 10.78 | 20300 | 2300 | 2.94 | 5000 | 5000 | 7FL
7FLG1 | 7FL | G1 | 7FLG1 | 事務室 | 301 | yes | 7FL | 7 | 10.08 | 4200 | 10.78 | 1.47 | 2.1 | 21000 | 3000 | 10.78 | 20300 | 2300 | 2.94 | 4750 | 5250 | 7FL
7FLG1 | 7FL | G1 | 7FLG1 | 事務室 | 311 | yes | 7FL | 7 | 18.48 | 7700 | 19.18 | 2.695 | 3.85 | 21000 | 3000 | 19.18 | 20300 | 2300 | 5.39 | 9000 | 8000 | 7FL
7FLG1 | 7FL | G1 | 7FLG1 | 事務室 | 303 | yes | 7FL | 7 | 10.219 | 4341.27 | 10.919 | 1.49028 | 2.12897 | 21000 | 3000 | 10.9287 | 20300 | 2300 | 2.98055 | 5280.75 | 4857.19 | 7FL
7FLG1 | 7FL | G1 | 7FLG1 | 事務室 | 301 | yes | 7FL | 7 | 23.28 | 9700 | 23.98 | 3.395 | 4.85 | 21000 | 3000 | 23.98 | 20300 | 2300 | 6.79 | 10545.1 | 9954.88 | 7FL
7FLG1 | 7FL | G1 | 7FLG1 | 事務室 | 315 | yes | 7FL | 7 | 20.88 | 8700 | 21.58 | 3.045 | 4.35 | 21000 | 3000 | 21.58 | 20300 | 2300 | 6.09 | 9000 | 9000 | 7FL
7FLG1 | 7FL | G1 | 7FLG1 | 事務室 | 314 | yes | 7FL | 7 | 20.88 | 8700 | 21.58 | 3.045 | 4.35 | 21000 | 3000 | 21.58 | 20300 | 2300 | 6.09 | 9000 | 9000 | 7FL
2 x 7FLG1 | 7FL | G1 | 7FLG1 | 事務室 | 313 | yes | 7FL | 7 | 20.88 | 8700 | 21.58 | 3.045 | 4.35 | 21000 | 3000 | 21.58 | 20300 | 2300 | 6.09 | 9000 | 9000 | 7FL
7FLG1 | 7FL | G1 | 7FLG1 | 事務室 | 302 | yes | 7FL | 7 | 19.28 | 8033.33 | 19.98 | 2.81167 | 4.01667 | 21000 | 3000 | 19.98 | 20300 | 2300 | 5.62333 | 8288.22 | 8371.55 | 7FL
7FLG1 | 7FL | G1 | 7FLG1 | EVホール | ＜ゾーン番号＞ | yes | 7FL | 7 | 18.48 | 7700 | 19.18 | 2.695 | 3.85 | 21000 | 3000 | 19.18 | 20300 | 2300 | 5.39 | 8000 | 8000 | 7FL
2 x 7FLG1 | 7FL | G1 | 7FLG1 | 事務室 | 310 | yes | 7FL | 7 | 18.48 | 7700 | 19.18 | 2.695 | 3.85 | 21000 | 3000 | 19.18 | 20300 | 2300 | 5.39 | 8000 | 8000 | 7FL
7FLG1 | 7FL | G1 | 7FLG1 | 事務室 | 316 | yes | 7FL | 7 | 10.08 | 4200 | 10.78 | 1.47 | 2.1 | 21000 | 3000 | 10.78 | 20300 | 2300 | 2.94 | 5250 | 4750 | 7FL
7FLG1 | 7FL | G1 | 7FLG1 | 事務室 | 315 | yes | 7FL | 7 | 10.08 | 4200 | 10.78 | 1.47 | 2.1 | 21000 | 3000 | 10.78 | 20300 | 2300 | 2.94 | 5000 | 5000 | 7FL
7FLG1 | 7FL | G1 | 7FLG1 | PS | ＜ゾーン番号＞ | yes | 7FL | 7 | 18.48 | 7700 | 19.18 | 2.695 | 3.85 | 21000 | 3000 | 19.18 | 20300 | 2300 | 5.39 | 8000 | 8000 | 7FL
7FLG1 | 7FL | G1 | 7FLG1 | 事務室 | 306 | yes | 7FL | 7 | 10.08 | 4200 | 10.78 | 1.47 | 2.1 | 21000 | 3000 | 10.78 | 20300 | 2300 | 2.94 | 5000 | 5000 | 7FL
7FLG1 | 7FL | G1 | 7FLG1 | 事務室 | 305 | yes | 7FL | 7 | 10.08 | 4200 | 10.78 | 1.47 | 2.1 | 21000 | 3000 | 10.78 | 20300 | 2300 | 2.94 | 5500 | 4500 | 7FL
7FLG1 | 7FL | G1 | 7FLG1 | 事務室 | 303 | yes | 7FL | 7 | 17.28 | 7200 | 17.98 | 2.52 | 3.6 | 21000 | 3000 | 17.98 | 20300 | 2300 | 5.04 | 7961.78 | 7538.22 | 7FL
7FLG1 | 7FL | G1 | 7FLG1 | 事務室 | 301 | yes | 7FL | 7 | 10.219 | 4341.27 | 10.919 | 1.49028 | 2.12897 | 21000 | 3000 | 10.9287 | 20300 | 2300 | 2.98055 | 5364.08 | 4773.85 | 7FL
7FLG1 | 7FL | G1 | 7FLG1 | EVシャフト | ＜ゾーン番号＞ | yes | 7FL | 7 | 18.48 | 7700 | 19.18 | 2.695 | 3.85 | 21000 | 3000 | 19.18 | 20300 | 2300 | 5.39 | 8000 | 8000 | 7FL
7FLG1 | 7FL | G1 | 7FLG1 | 事務室 | 301 | yes | 7FL | 7 | 21.28 | 8866.67 | 21.98 | 3.10333 | 4.43333 | 21000 | 3000 | 21.98 | 20300 | 2300 | 6.20667 | 9121.55 | 9204.88 | 7FL
7FLG1 | 7FL | G1 | 7FLG1 | 事務室 | 304 | yes | 7FL | 7 | 17.28 | 7200 | 17.98 | 2.52 | 3.6 | 21000 | 3000 | 17.98 | 20300 | 2300 | 5.04 | 8000 | 7500 | 7FL
7FLG1 | 7FL | G1 | 7FLG1 | 事務室 | 302 | yes | 7FL | 7 | 10.219 | 4341.27 | 10.919 | 1.49028 | 2.12897 | 21000 | 3000 | 10.9287 | 20300 | 2300 | 2.98055 | 5068.97 | 5068.97 | 7FL
7FLG1 | 7FL | G1 | 7FLG1 | 事務室 | 308 | yes | 7FL | 7 | 10.08 | 4200 | 10.78 | 1.47 | 2.1 | 21000 | 3000 | 10.78 | 20300 | 2300 | 2.94 | 5250 | 4750 | 7FL
7FLG2 | 7FL | G2 | 7FLG2 | 事務室 | 306 | yes | 7FL | 7 | 10.5238 | 4534.93 | 11.2238 | 1.53473 | 2.19246 | 21000 | 3000 | 11.2547 | 20300 | 2300 | 3.06945 | 5220.15 | 4698.14 | 7FL
7FLG1 | 7FL | G1 | 7FLG1 | 事務室 | 306 | yes | 7FL | 7 | 13.68 | 5700 | 14.38 | 1.995 | 2.85 | 21000 | 3000 | 14.38 | 20300 | 2300 | 3.99 | 6436.01 | 6063.99 | 7FL
8FLG1 | 8FL | G1 | 8FLG1 | 事務室 | 304 | yes | 8FL | 8 | 10.08 | 4200 | 10.78 | 1.47 | 2.1 | 24000 | 3000 | 10.78 | 23300 | 2300 | 2.94 | 4729.31 | 4500 | 8FL
8FLG1 | 8FL | G1 | 8FLG1 | 事務室 | 305 | yes | 8FL | 8 | 17.28 | 7200 | 17.98 | 2.52 | 3.6 | 24000 | 3000 | 17.98 | 23300 | 2300 | 5.04 | 8000 | 7500 | 8FL
8FLG1 | 8FL | G1 | 8FLG1 | PS | ＜ゾーン番号＞ | yes | 8FL | 8 | 10.08 | 4200 | 10.78 | 1.47 | 2.1 | 24000 | 3000 | 10.78 | 23300 | 2300 | 2.94 | 5000 | 5000 | 8FL
8FLG1 | 8FL | G1 | 8FLG1 | EVホール | ＜ゾーン番号＞ | yes | 8FL | 8 | 10.08 | 4200 | 10.78 | 1.47 | 2.1 | 24000 | 3000 | 10.78 | 23300 | 2300 | 2.94 | 5000 | 5000 | 8FL
8FLG1 | 8FL | G1 | 8FLG1 | 男性用トイレ | ＜ゾーン番号＞ | yes | 8FL | 8 | 10.08 | 4200 | 10.78 | 1.47 | 2.1 | 24000 | 3000 | 10.78 | 23300 | 2300 | 2.94 | 5000 | 5000 | 8FL
8FLG1 | 8FL | G1 | 8FLG1 | 事務室 | 310 | yes | 8FL | 8 | 10.08 | 4200 | 10.78 | 1.47 | 2.1 | 24000 | 3000 | 10.78 | 23300 | 2300 | 2.94 | 5000 | 5000 | 8FL
8FLG1 | 8FL | G1 | 8FLG1 | 事務室 | 313 | yes | 8FL | 8 | 10.08 | 4200 | 10.78 | 1.47 | 2.1 | 24000 | 3000 | 10.78 | 23300 | 2300 | 2.94 | 5000 | 5000 | 8FL
8FLG1 | 8FL | G1 | 8FLG1 | 事務室 | 305 | yes | 8FL | 8 | 10.08 | 4200 | 10.78 | 1.47 | 2.1 | 24000 | 3000 | 10.78 | 23300 | 2300 | 2.94 | 5000 | 5000 | 8FL
8FLG1 | 8FL | G1 | 8FLG1 | 事務室 | 304 | yes | 8FL | 8 | 10.08 | 4200 | 10.78 | 1.47 | 2.1 | 24000 | 3000 | 10.78 | 23300 | 2300 | 2.94 | 5000 | 5000 | 8FL
8FLG1 | 8FL | G1 | 8FLG1 | 事務室 | 303 | yes | 8FL | 8 | 10.08 | 4200 | 10.78 | 1.47 | 2.1 | 24000 | 3000 | 10.78 | 23300 | 2300 | 2.94 | 5000 | 5000 | 8FL
8FLG1 | 8FL | G1 | 8FLG1 | 事務室 | 314 | yes | 8FL | 8 | 10.08 | 4200 | 10.78 | 1.47 | 2.1 | 24000 | 3000 | 10.78 | 23300 | 2300 | 2.94 | 5000 | 5000 | 8FL
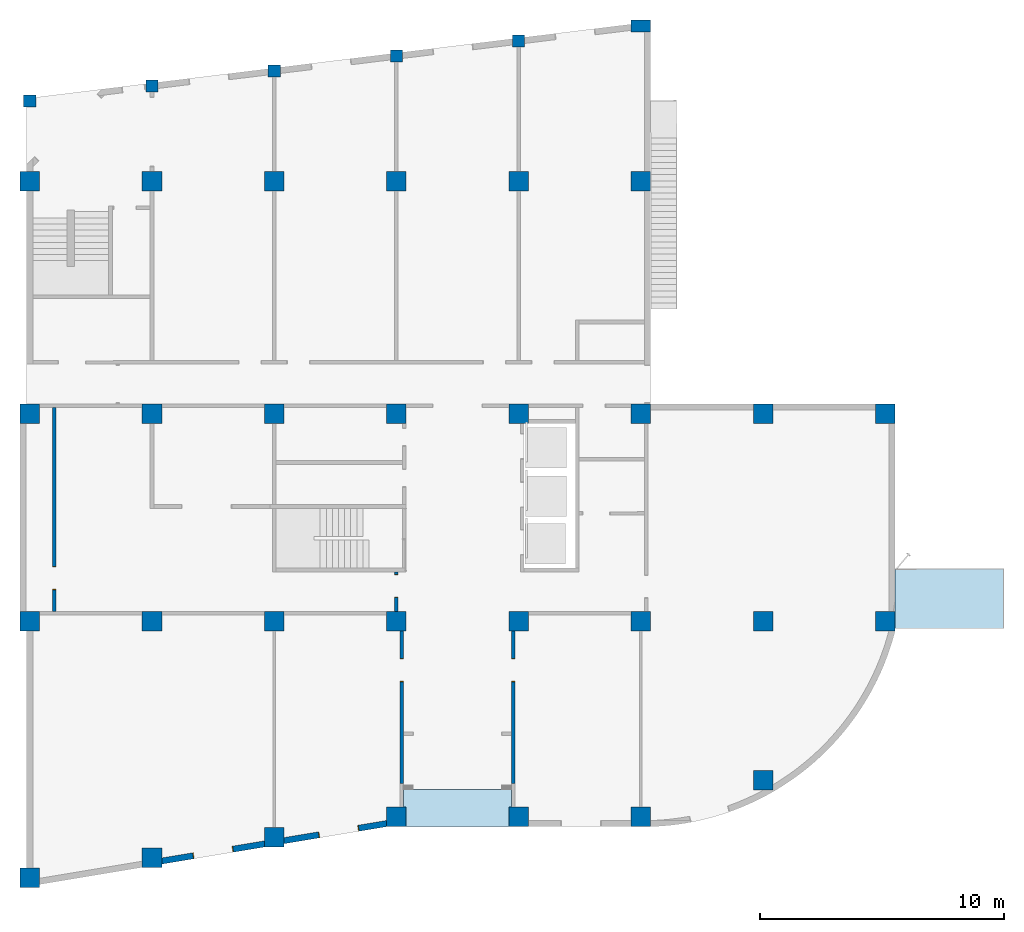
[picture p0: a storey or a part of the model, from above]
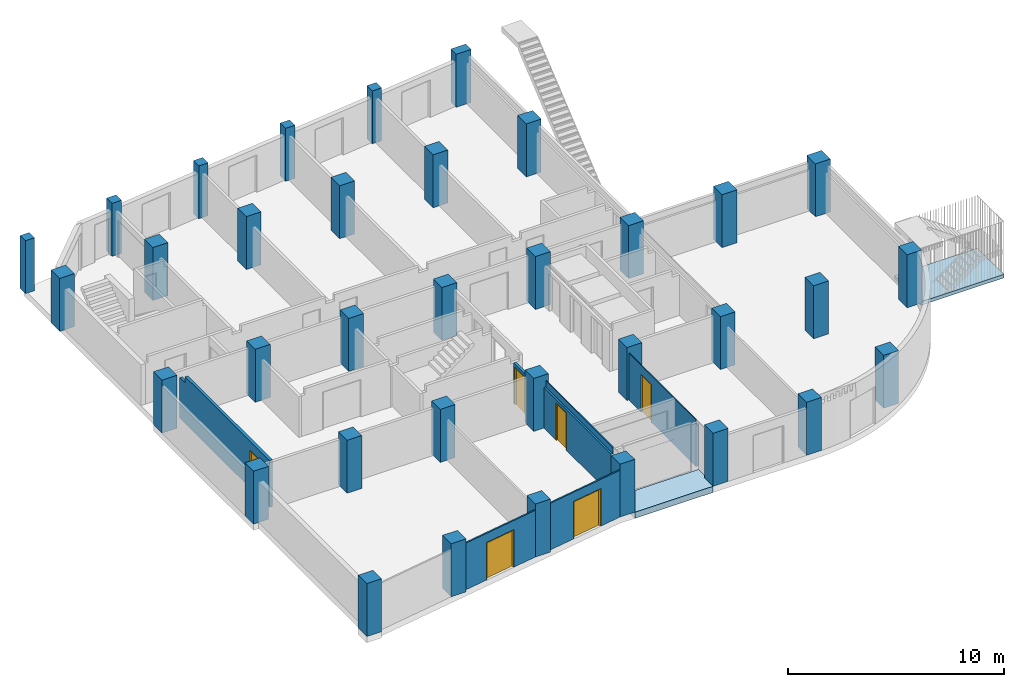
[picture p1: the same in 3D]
Properties of the parts of a building model (IFC2X3), part 4 of 10

# IfcBeam: コンクリート 500 x 700 (414)
Name | In | 要素ID = 親ID | ホットリンクおよび要素ID | 関連ゾーン名 | 関連ゾーン番号 | ロック状態 | ホームフロア名 | ホームフロア数 | NetSurfaceAreaExtrudedSides (m2) = OuterSurfaceArea (m2) | Length (mm) = 3D長さ (mm) | TotalSurfaceArea (m2) = GrossSurfaceArea (m2) = NetSurfaceArea (m2) | GrossVolume (m3) = NetVolume (m3) = 正味体積 (m3) = 条件付き体積 (m3) | 面積 (m2) = 下部表面積 (m2) = 上部表面積 (m2) | GLからの高度 (mm) = 高度 1 (mm) = 高度 2 (mm) = 海抜までの高度 (mm) = 上端高度から第1基準レベル (mm) = 上端高度から基準レベル (mm) = 上端高度から海抜 (mm) = 上端高度から第2基準レベル (mm) | リンク/配置フロアまでの高度 (mm) = 下部オフセット (mm) = 上端高度から配置フロア (mm) | 表面積 (m2) | 下端高度から第1基準レベル (mm) = 下端高度から基準レベル (mm) = 下端高度から海抜 (mm) = 下端高度から第2基準レベル (mm) | 下端高度から配置フロア (mm) | 左側表面積 (m2) = 右側表面積 (m2) | 左長さ (mm) | 右長さ (mm) | ホットリンク マスタID
8FLG1 | 8FL | G1 | 8FLG1 | 事務室 | 311 | yes | 8FL | 8 | 10.08 | 4200 | 10.78 | 1.47 | 2.1 | 24000 | 3000 | 10.78 | 23300 | 2300 | 2.94 | 5250 | 4750 | 8FL
8FLG1 | 8FL | G1 | 8FLG1 | 事務室 | 307 | yes | 8FL | 8 | 10.08 | 4200 | 10.78 | 1.47 | 2.1 | 24000 | 3000 | 10.78 | 23300 | 2300 | 2.94 | 4750 | 5250 | 8FL
8FLG1 | 8FL | G1 | 8FLG1 | 事務室 | 312 | yes | 8FL | 8 | 20.88 | 8700 | 21.58 | 3.045 | 4.35 | 24000 | 3000 | 21.58 | 23300 | 2300 | 6.09 | 9000 | 9500 | 8FL
8FLG1 | 8FL | G1 | 8FLG1 | 事務室 | 309 | yes | 8FL | 8 | 10.08 | 4200 | 10.78 | 1.47 | 2.1 | 24000 | 3000 | 10.78 | 23300 | 2300 | 2.94 | 5000 | 5000 | 8FL
8FLG1 | 8FL | G1 | 8FLG1 | 事務室 | 312 | yes | 8FL | 8 | 10.08 | 4200 | 10.78 | 1.47 | 2.1 | 24000 | 3000 | 10.78 | 23300 | 2300 | 2.94 | 5250 | 4750 | 8FL
8FLG1 | 8FL | G1 | 8FLG1 | 事務室 | 308 | yes | 8FL | 8 | 18.48 | 7700 | 19.18 | 2.695 | 3.85 | 24000 | 3000 | 19.18 | 23300 | 2300 | 5.39 | 8000 | 8000 | 8FL
8FLG1 | 8FL | G1 | 8FLG1 | 事務室 | 316 | yes | 8FL | 8 | 20.88 | 8700 | 21.58 | 3.045 | 4.35 | 24000 | 3000 | 21.58 | 23300 | 2300 | 6.09 | 9500 | 9000 | 8FL
8FLG1 | 8FL | G1 | 8FLG1 | 事務室 | 308 | yes | 8FL | 8 | 18.48 | 7700 | 19.18 | 2.695 | 3.85 | 24000 | 3000 | 19.18 | 23300 | 2300 | 5.39 | 9000 | 8000 | 8FL
8FLG1 | 8FL | G1 | 8FLG1 | 事務室 | 302 | yes | 8FL | 8 | 10.08 | 4200 | 10.78 | 1.47 | 2.1 | 24000 | 3000 | 10.78 | 23300 | 2300 | 2.94 | 5000 | 5000 | 8FL
8FLG1 | 8FL | G1 | 8FLG1 | 事務室 | 301 | yes | 8FL | 8 | 10.08 | 4200 | 10.78 | 1.47 | 2.1 | 24000 | 3000 | 10.78 | 23300 | 2300 | 2.94 | 4750 | 5250 | 8FL
8FLG1 | 8FL | G1 | 8FLG1 | 事務室 | 311 | yes | 8FL | 8 | 18.48 | 7700 | 19.18 | 2.695 | 3.85 | 24000 | 3000 | 19.18 | 23300 | 2300 | 5.39 | 9000 | 8000 | 8FL
8FLG1 | 8FL | G1 | 8FLG1 | 事務室 | 303 | yes | 8FL | 8 | 10.219 | 4341.27 | 10.919 | 1.49028 | 2.12897 | 24000 | 3000 | 10.9287 | 23300 | 2300 | 2.98055 | 5280.75 | 4857.19 | 8FL
8FLG1 | 8FL | G1 | 8FLG1 | 事務室 | 301 | yes | 8FL | 8 | 23.28 | 9700 | 23.98 | 3.395 | 4.85 | 24000 | 3000 | 23.98 | 23300 | 2300 | 6.79 | 10545.1 | 9954.88 | 8FL
8FLG1 | 8FL | G1 | 8FLG1 | 事務室 | 315 | yes | 8FL | 8 | 20.88 | 8700 | 21.58 | 3.045 | 4.35 | 24000 | 3000 | 21.58 | 23300 | 2300 | 6.09 | 9000 | 9000 | 8FL
8FLG1 | 8FL | G1 | 8FLG1 | 事務室 | 314 | yes | 8FL | 8 | 20.88 | 8700 | 21.58 | 3.045 | 4.35 | 24000 | 3000 | 21.58 | 23300 | 2300 | 6.09 | 9000 | 9000 | 8FL
2 x 8FLG1 | 8FL | G1 | 8FLG1 | 事務室 | 313 | yes | 8FL | 8 | 20.88 | 8700 | 21.58 | 3.045 | 4.35 | 24000 | 3000 | 21.58 | 23300 | 2300 | 6.09 | 9000 | 9000 | 8FL
8FLG1 | 8FL | G1 | 8FLG1 | 事務室 | 302 | yes | 8FL | 8 | 19.28 | 8033.33 | 19.98 | 2.81167 | 4.01667 | 24000 | 3000 | 19.98 | 23300 | 2300 | 5.62333 | 8288.22 | 8371.55 | 8FL
8FLG1 | 8FL | G1 | 8FLG1 | EVホール | ＜ゾーン番号＞ | yes | 8FL | 8 | 18.48 | 7700 | 19.18 | 2.695 | 3.85 | 24000 | 3000 | 19.18 | 23300 | 2300 | 5.39 | 8000 | 8000 | 8FL
2 x 8FLG1 | 8FL | G1 | 8FLG1 | 事務室 | 310 | yes | 8FL | 8 | 18.48 | 7700 | 19.18 | 2.695 | 3.85 | 24000 | 3000 | 19.18 | 23300 | 2300 | 5.39 | 8000 | 8000 | 8FL
8FLG1 | 8FL | G1 | 8FLG1 | 事務室 | 316 | yes | 8FL | 8 | 10.08 | 4200 | 10.78 | 1.47 | 2.1 | 24000 | 3000 | 10.78 | 23300 | 2300 | 2.94 | 5250 | 4750 | 8FL
8FLG1 | 8FL | G1 | 8FLG1 | 事務室 | 315 | yes | 8FL | 8 | 10.08 | 4200 | 10.78 | 1.47 | 2.1 | 24000 | 3000 | 10.78 | 23300 | 2300 | 2.94 | 5000 | 5000 | 8FL
8FLG1 | 8FL | G1 | 8FLG1 | PS | ＜ゾーン番号＞ | yes | 8FL | 8 | 18.48 | 7700 | 19.18 | 2.695 | 3.85 | 24000 | 3000 | 19.18 | 23300 | 2300 | 5.39 | 8000 | 8000 | 8FL
8FLG1 | 8FL | G1 | 8FLG1 | 事務室 | 306 | yes | 8FL | 8 | 10.08 | 4200 | 10.78 | 1.47 | 2.1 | 24000 | 3000 | 10.78 | 23300 | 2300 | 2.94 | 5000 | 5000 | 8FL
8FLG1 | 8FL | G1 | 8FLG1 | 事務室 | 305 | yes | 8FL | 8 | 10.08 | 4200 | 10.78 | 1.47 | 2.1 | 24000 | 3000 | 10.78 | 23300 | 2300 | 2.94 | 5500 | 4500 | 8FL
8FLG1 | 8FL | G1 | 8FLG1 | 事務室 | 303 | yes | 8FL | 8 | 17.28 | 7200 | 17.98 | 2.52 | 3.6 | 24000 | 3000 | 17.98 | 23300 | 2300 | 5.04 | 7961.78 | 7538.22 | 8FL
8FLG1 | 8FL | G1 | 8FLG1 | 事務室 | 301 | yes | 8FL | 8 | 10.219 | 4341.27 | 10.919 | 1.49028 | 2.12897 | 24000 | 3000 | 10.9287 | 23300 | 2300 | 2.98055 | 5364.08 | 4773.85 | 8FL
8FLG1 | 8FL | G1 | 8FLG1 | EVシャフト | ＜ゾーン番号＞ | yes | 8FL | 8 | 18.48 | 7700 | 19.18 | 2.695 | 3.85 | 24000 | 3000 | 19.18 | 23300 | 2300 | 5.39 | 8000 | 8000 | 8FL
8FLG1 | 8FL | G1 | 8FLG1 | 事務室 | 301 | yes | 8FL | 8 | 21.28 | 8866.67 | 21.98 | 3.10333 | 4.43333 | 24000 | 3000 | 21.98 | 23300 | 2300 | 6.20667 | 9121.55 | 9204.88 | 8FL
8FLG1 | 8FL | G1 | 8FLG1 | 事務室 | 304 | yes | 8FL | 8 | 17.28 | 7200 | 17.98 | 2.52 | 3.6 | 24000 | 3000 | 17.98 | 23300 | 2300 | 5.04 | 8000 | 7500 | 8FL
8FLG1 | 8FL | G1 | 8FLG1 | 事務室 | 302 | yes | 8FL | 8 | 10.219 | 4341.27 | 10.919 | 1.49028 | 2.12897 | 24000 | 3000 | 10.9287 | 23300 | 2300 | 2.98055 | 5068.97 | 5068.97 | 8FL
8FLG1 | 8FL | G1 | 8FLG1 | 事務室 | 308 | yes | 8FL | 8 | 10.08 | 4200 | 10.78 | 1.47 | 2.1 | 24000 | 3000 | 10.78 | 23300 | 2300 | 2.94 | 5250 | 4750 | 8FL
8FLG2 | 8FL | G2 | 8FLG2 | 事務室 | 306 | yes | 8FL | 8 | 10.5238 | 4534.93 | 11.2238 | 1.53473 | 2.19246 | 24000 | 3000 | 11.2547 | 23300 | 2300 | 3.06945 | 5220.15 | 4698.14 | 8FL
8FLG1 | 8FL | G1 | 8FLG1 | 事務室 | 306 | yes | 8FL | 8 | 13.68 | 5700 | 14.38 | 1.995 | 2.85 | 24000 | 3000 | 14.38 | 23300 | 2300 | 3.99 | 6436.01 | 6063.99 | 8FL
9FLG1 | 9FL | G1 | 9FLG1 | 事務室 | 304 | yes | 9FL | 9 | 10.08 | 4200 | 10.78 | 1.47 | 2.1 | 27000 | 3000 | 10.78 | 26300 | 2300 | 2.94 | 4729.31 | 4500 | 9FL
9FLG1 | 9FL | G1 | 9FLG1 | 事務室 | 305 | yes | 9FL | 9 | 17.28 | 7200 | 17.98 | 2.52 | 3.6 | 27000 | 3000 | 17.98 | 26300 | 2300 | 5.04 | 8000 | 7500 | 9FL
9FLG1 | 9FL | G1 | 9FLG1 | PS | ＜ゾーン番号＞ | yes | 9FL | 9 | 10.08 | 4200 | 10.78 | 1.47 | 2.1 | 27000 | 3000 | 10.78 | 26300 | 2300 | 2.94 | 5000 | 5000 | 9FL
9FLG1 | 9FL | G1 | 9FLG1 | EVホール | ＜ゾーン番号＞ | yes | 9FL | 9 | 10.08 | 4200 | 10.78 | 1.47 | 2.1 | 27000 | 3000 | 10.78 | 26300 | 2300 | 2.94 | 5000 | 5000 | 9FL
9FLG1 | 9FL | G1 | 9FLG1 | 男性用トイレ | ＜ゾーン番号＞ | yes | 9FL | 9 | 10.08 | 4200 | 10.78 | 1.47 | 2.1 | 27000 | 3000 | 10.78 | 26300 | 2300 | 2.94 | 5000 | 5000 | 9FL
9FLG1 | 9FL | G1 | 9FLG1 | 事務室 | 310 | yes | 9FL | 9 | 10.08 | 4200 | 10.78 | 1.47 | 2.1 | 27000 | 3000 | 10.78 | 26300 | 2300 | 2.94 | 5000 | 5000 | 9FL
9FLG1 | 9FL | G1 | 9FLG1 | 事務室 | 313 | yes | 9FL | 9 | 10.08 | 4200 | 10.78 | 1.47 | 2.1 | 27000 | 3000 | 10.78 | 26300 | 2300 | 2.94 | 5000 | 5000 | 9FL
9FLG1 | 9FL | G1 | 9FLG1 | 事務室 | 305 | yes | 9FL | 9 | 10.08 | 4200 | 10.78 | 1.47 | 2.1 | 27000 | 3000 | 10.78 | 26300 | 2300 | 2.94 | 5000 | 5000 | 9FL
9FLG1 | 9FL | G1 | 9FLG1 | 事務室 | 304 | yes | 9FL | 9 | 10.08 | 4200 | 10.78 | 1.47 | 2.1 | 27000 | 3000 | 10.78 | 26300 | 2300 | 2.94 | 5000 | 5000 | 9FL
9FLG1 | 9FL | G1 | 9FLG1 | 事務室 | 303 | yes | 9FL | 9 | 10.08 | 4200 | 10.78 | 1.47 | 2.1 | 27000 | 3000 | 10.78 | 26300 | 2300 | 2.94 | 5000 | 5000 | 9FL
9FLG1 | 9FL | G1 | 9FLG1 | 事務室 | 314 | yes | 9FL | 9 | 10.08 | 4200 | 10.78 | 1.47 | 2.1 | 27000 | 3000 | 10.78 | 26300 | 2300 | 2.94 | 5000 | 5000 | 9FL
9FLG1 | 9FL | G1 | 9FLG1 | 事務室 | 311 | yes | 9FL | 9 | 10.08 | 4200 | 10.78 | 1.47 | 2.1 | 27000 | 3000 | 10.78 | 26300 | 2300 | 2.94 | 5250 | 4750 | 9FL
9FLG1 | 9FL | G1 | 9FLG1 | 事務室 | 307 | yes | 9FL | 9 | 10.08 | 4200 | 10.78 | 1.47 | 2.1 | 27000 | 3000 | 10.78 | 26300 | 2300 | 2.94 | 4750 | 5250 | 9FL
9FLG1 | 9FL | G1 | 9FLG1 | 事務室 | 312 | yes | 9FL | 9 | 20.88 | 8700 | 21.58 | 3.045 | 4.35 | 27000 | 3000 | 21.58 | 26300 | 2300 | 6.09 | 9000 | 9500 | 9FL
9FLG1 | 9FL | G1 | 9FLG1 | 事務室 | 309 | yes | 9FL | 9 | 10.08 | 4200 | 10.78 | 1.47 | 2.1 | 27000 | 3000 | 10.78 | 26300 | 2300 | 2.94 | 5000 | 5000 | 9FL
9FLG1 | 9FL | G1 | 9FLG1 | 事務室 | 312 | yes | 9FL | 9 | 10.08 | 4200 | 10.78 | 1.47 | 2.1 | 27000 | 3000 | 10.78 | 26300 | 2300 | 2.94 | 5250 | 4750 | 9FL
9FLG1 | 9FL | G1 | 9FLG1 | 事務室 | 308 | yes | 9FL | 9 | 18.48 | 7700 | 19.18 | 2.695 | 3.85 | 27000 | 3000 | 19.18 | 26300 | 2300 | 5.39 | 8000 | 8000 | 9FL
9FLG1 | 9FL | G1 | 9FLG1 | 事務室 | 316 | yes | 9FL | 9 | 20.88 | 8700 | 21.58 | 3.045 | 4.35 | 27000 | 3000 | 21.58 | 26300 | 2300 | 6.09 | 9500 | 9000 | 9FL
9FLG1 | 9FL | G1 | 9FLG1 | 事務室 | 308 | yes | 9FL | 9 | 18.48 | 7700 | 19.18 | 2.695 | 3.85 | 27000 | 3000 | 19.18 | 26300 | 2300 | 5.39 | 9000 | 8000 | 9FL
9FLG1 | 9FL | G1 | 9FLG1 | 事務室 | 302 | yes | 9FL | 9 | 10.08 | 4200 | 10.78 | 1.47 | 2.1 | 27000 | 3000 | 10.78 | 26300 | 2300 | 2.94 | 5000 | 5000 | 9FL
9FLG1 | 9FL | G1 | 9FLG1 | 事務室 | 301 | yes | 9FL | 9 | 10.08 | 4200 | 10.78 | 1.47 | 2.1 | 27000 | 3000 | 10.78 | 26300 | 2300 | 2.94 | 4750 | 5250 | 9FL
9FLG1 | 9FL | G1 | 9FLG1 | 事務室 | 311 | yes | 9FL | 9 | 18.48 | 7700 | 19.18 | 2.695 | 3.85 | 27000 | 3000 | 19.18 | 26300 | 2300 | 5.39 | 9000 | 8000 | 9FL
9FLG1 | 9FL | G1 | 9FLG1 | 事務室 | 303 | yes | 9FL | 9 | 10.219 | 4341.27 | 10.919 | 1.49028 | 2.12897 | 27000 | 3000 | 10.9287 | 26300 | 2300 | 2.98055 | 5280.75 | 4857.19 | 9FL
9FLG1 | 9FL | G1 | 9FLG1 | 事務室 | 301 | yes | 9FL | 9 | 23.28 | 9700 | 23.98 | 3.395 | 4.85 | 27000 | 3000 | 23.98 | 26300 | 2300 | 6.79 | 10545.1 | 9954.88 | 9FL
9FLG1 | 9FL | G1 | 9FLG1 | 事務室 | 315 | yes | 9FL | 9 | 20.88 | 8700 | 21.58 | 3.045 | 4.35 | 27000 | 3000 | 21.58 | 26300 | 2300 | 6.09 | 9000 | 9000 | 9FL
9FLG1 | 9FL | G1 | 9FLG1 | 事務室 | 314 | yes | 9FL | 9 | 20.88 | 8700 | 21.58 | 3.045 | 4.35 | 27000 | 3000 | 21.58 | 26300 | 2300 | 6.09 | 9000 | 9000 | 9FL
2 x 9FLG1 | 9FL | G1 | 9FLG1 | 事務室 | 313 | yes | 9FL | 9 | 20.88 | 8700 | 21.58 | 3.045 | 4.35 | 27000 | 3000 | 21.58 | 26300 | 2300 | 6.09 | 9000 | 9000 | 9FL
9FLG1 | 9FL | G1 | 9FLG1 | 事務室 | 302 | yes | 9FL | 9 | 19.28 | 8033.33 | 19.98 | 2.81167 | 4.01667 | 27000 | 3000 | 19.98 | 26300 | 2300 | 5.62333 | 8288.22 | 8371.55 | 9FL
9FLG1 | 9FL | G1 | 9FLG1 | EVホール | ＜ゾーン番号＞ | yes | 9FL | 9 | 18.48 | 7700 | 19.18 | 2.695 | 3.85 | 27000 | 3000 | 19.18 | 26300 | 2300 | 5.39 | 8000 | 8000 | 9FL
2 x 9FLG1 | 9FL | G1 | 9FLG1 | 事務室 | 310 | yes | 9FL | 9 | 18.48 | 7700 | 19.18 | 2.695 | 3.85 | 27000 | 3000 | 19.18 | 26300 | 2300 | 5.39 | 8000 | 8000 | 9FL
9FLG1 | 9FL | G1 | 9FLG1 | 事務室 | 316 | yes | 9FL | 9 | 10.08 | 4200 | 10.78 | 1.47 | 2.1 | 27000 | 3000 | 10.78 | 26300 | 2300 | 2.94 | 5250 | 4750 | 9FL
9FLG1 | 9FL | G1 | 9FLG1 | 事務室 | 315 | yes | 9FL | 9 | 10.08 | 4200 | 10.78 | 1.47 | 2.1 | 27000 | 3000 | 10.78 | 26300 | 2300 | 2.94 | 5000 | 5000 | 9FL
9FLG1 | 9FL | G1 | 9FLG1 | PS | ＜ゾーン番号＞ | yes | 9FL | 9 | 18.48 | 7700 | 19.18 | 2.695 | 3.85 | 27000 | 3000 | 19.18 | 26300 | 2300 | 5.39 | 8000 | 8000 | 9FL
9FLG1 | 9FL | G1 | 9FLG1 | 事務室 | 306 | yes | 9FL | 9 | 10.08 | 4200 | 10.78 | 1.47 | 2.1 | 27000 | 3000 | 10.78 | 26300 | 2300 | 2.94 | 5000 | 5000 | 9FL
9FLG1 | 9FL | G1 | 9FLG1 | 事務室 | 305 | yes | 9FL | 9 | 10.08 | 4200 | 10.78 | 1.47 | 2.1 | 27000 | 3000 | 10.78 | 26300 | 2300 | 2.94 | 5500 | 4500 | 9FL
9FLG1 | 9FL | G1 | 9FLG1 | 事務室 | 303 | yes | 9FL | 9 | 17.28 | 7200 | 17.98 | 2.52 | 3.6 | 27000 | 3000 | 17.98 | 26300 | 2300 | 5.04 | 7961.78 | 7538.22 | 9FL
9FLG1 | 9FL | G1 | 9FLG1 | 事務室 | 301 | yes | 9FL | 9 | 10.219 | 4341.27 | 10.919 | 1.49028 | 2.12897 | 27000 | 3000 | 10.9287 | 26300 | 2300 | 2.98055 | 5364.08 | 4773.85 | 9FL
9FLG1 | 9FL | G1 | 9FLG1 | EVシャフト | ＜ゾーン番号＞ | yes | 9FL | 9 | 18.48 | 7700 | 19.18 | 2.695 | 3.85 | 27000 | 3000 | 19.18 | 26300 | 2300 | 5.39 | 8000 | 8000 | 9FL
9FLG1 | 9FL | G1 | 9FLG1 | 事務室 | 301 | yes | 9FL | 9 | 21.28 | 8866.67 | 21.98 | 3.10333 | 4.43333 | 27000 | 3000 | 21.98 | 26300 | 2300 | 6.20667 | 9121.55 | 9204.88 | 9FL
9FLG1 | 9FL | G1 | 9FLG1 | 事務室 | 304 | yes | 9FL | 9 | 17.28 | 7200 | 17.98 | 2.52 | 3.6 | 27000 | 3000 | 17.98 | 26300 | 2300 | 5.04 | 8000 | 7500 | 9FL
9FLG1 | 9FL | G1 | 9FLG1 | 事務室 | 302 | yes | 9FL | 9 | 10.219 | 4341.27 | 10.919 | 1.49028 | 2.12897 | 27000 | 3000 | 10.9287 | 26300 | 2300 | 2.98055 | 5068.97 | 5068.97 | 9FL
9FLG1 | 9FL | G1 | 9FLG1 | 事務室 | 308 | yes | 9FL | 9 | 10.08 | 4200 | 10.78 | 1.47 | 2.1 | 27000 | 3000 | 10.78 | 26300 | 2300 | 2.94 | 5250 | 4750 | 9FL
9FLG2 | 9FL | G2 | 9FLG2 | 事務室 | 306 | yes | 9FL | 9 | 10.5238 | 4534.93 | 11.2238 | 1.53473 | 2.19246 | 27000 | 3000 | 11.2547 | 26300 | 2300 | 3.06945 | 5220.15 | 4698.14 | 9FL
9FLG1 | 9FL | G1 | 9FLG1 | 事務室 | 306 | yes | 9FL | 9 | 13.68 | 5700 | 14.38 | 1.995 | 2.85 | 27000 | 3000 | 14.38 | 26300 | 2300 | 3.99 | 6436.01 | 6063.99 | 9FL

# IfcColumn: コンクリート 500 x 500 (10)
Classification: 柱 (ARCHICAD 分類); Material: コンクリート
ArchiCADProperties - 要素ID: C2; ホットリンクおよび要素ID: C2; レイヤー: 柱; ビルディングマテリアル/複合構造/断面形状/塗りつぶし: コンクリート; ビルディングマテリアル: コンクリート; ロック状態: no; 要素タイプ: 柱; 相対上部リンクフロア: 配置フロア + 1; 構造タイプ: 基本; 親ID: C2; ビルディングマテリアル (全て): コンクリート; 材質 (全て): コンクリート - 04; 表面塗りつぶし: 背景; 傾斜角度: 90 deg; リノベーションフィルタで表示: 全ての関連フィルタ; 構造機能: 構造耐力要素; 位置: エクステリア; リノベーションステータス: 既存; 柱横断面: 矩形; 柱傾斜角度: 90 deg; 押し出し表面: コンクリート - 04; 終端材質: コンクリート - 04; ARCHICAD 分類 - v 2.0: 柱
仕上情報 - WEBサイト: www.graphisoft.co.jp
AC_Pset_RenovationAndPhasing - Renovation Status: Existing
Pset_ColumnCommon - LoadBearing: yes; IsExternal: yes; Reference: コンクリート 500 x 500
BaseQuantities - Length: 3000 mm; Width: 500 mm; Depth: 500 mm; CrossSectionArea: 0.25 m2; OuterSurfaceArea: 6 m2; TotalSurfaceArea: 6.5 m2; GrossSurfaceArea: 6.5 m2; GrossVolume: 0.75 m3; NetVolume: 0.75 m3
ArchiCADQuantities - 面積: 0.25 m2; 高さ: 3000 mm; 正味体積: 0.75 m3; 幅: 500 mm; リンク/配置フロアまでの高度: 0 mm; 下部オフセット: 0 mm; 上部オフセット: 0 mm; 表面積: 6 m2; 3D長さ: 3000 mm; 総体積: 0.75 m3; 上端高度から配置フロア: 3000 mm; 下端高度から配置フロア: 0 mm; 上部/終了の断面高さ(垂直): 500 mm; 下部/開始の断面高さ(垂直): 500 mm; 上部/終了の断面幅(垂直): 500 mm; 下部/開始の断面幅(垂直): 500 mm; 上部/終了の断面高さ(切断): 500 mm; 下部/開始の断面高さ(切断): 500 mm; 上部/終了の断面幅(切断): 500 mm; 下部/開始の断面幅(切断): 500 mm; 下部/開始の断面の面積: 0.25 m2; 上部/終了の断面の面積: 0.25 m2; セグメント数: 1; 躯体高さ / 直径: 500 mm; 躯体の正味体積: 0.75 m3; 躯体幅: 500 mm; 躯体総表面積(上部/下部以外): 6 m2; 躯体上部の総表面積: 0.25 m2; 躯体下部の総表面積: 0.25 m2; 躯体総体積: 0.75 m3; 仕上げ総表面積(上部/下部以外): 0 m2; 仕上げ上部の総表面積: 0 m2; 仕上げ下部の総表面積: 0 m2; 仕上げ総体積: 0 m3; 柱最大高さ: 3000 mm; 柱最小高さ: 3000 mm; 躯体下部正味表面積: 0.25 m2; 躯体の正味表面積 (上部/下部以外): 6 m2; 躯体上部正味表面積: 0.25 m2; 仕上げ下部正味表面積: 0 m2; 仕上げ表面積: 0 m2; 仕上げ上部正味表面積: 0 m2; 柱断面形状の外周(下部): 2000 mm; 仕上げの正味体積: 0 m3
Name | In | 関連ゾーン名 | 関連ゾーン番号 | ホームフロア名 | ホームフロア数 | 絶対上部リンクフロア | 上部リンクフロア | GLからの高度 (mm) = 高度 1 (mm) = 高度 2 (mm) = 海抜までの高度 (mm) = 下端高度から第1基準レベル (mm) = 下端高度から基準レベル (mm) = 下端高度から海抜 (mm) = 下端高度から第2基準レベル (mm) | 上端高度から第1基準レベル (mm) = 上端高度から基準レベル (mm) = 上端高度から海抜 (mm) = 上端高度から第2基準レベル (mm)
C2 | 1FL | 店舗 | 105 | 1FL | 1 | 2FL | 配置フロア + 1 (2FL) | 0 | 3000
C2 | 1FL | 店舗 | 106 | 1FL | 1 | 2FL | 配置フロア + 1 (2FL) | 0 | 3000
C2 | 1FL | 店舗 | 107 | 1FL | 1 | 2FL | 配置フロア + 1 (2FL) | 0 | 3000
C2 | 1FL | 店舗 | 108 | 1FL | 1 | 2FL | 配置フロア + 1 (2FL) | 0 | 3000
C2 | 1FL |  |  | 1FL | 1 | 2FL | 配置フロア + 1 (2FL) | 0 | 3000
C2 | 2FL | 店舗 | 214 | 2FL | 2 | 3FL | 配置フロア + 1 (3FL) | 3000 | 6000
C2 | 2FL | 店舗 | 212 | 2FL | 2 | 3FL | 配置フロア + 1 (3FL) | 3000 | 6000
2 x C2 | 2FL | 店舗 | 211 | 2FL | 2 | 3FL | 配置フロア + 1 (3FL) | 3000 | 6000
C2 | 2FL | 女性用トイレ | ＜ゾーン番号＞ | 2FL | 2 | 3FL | 配置フロア + 1 (3FL) | 3000 | 6000

# IfcColumn: コンクリート 800 x 500 (2)
Classification: 柱 (ARCHICAD 分類); Material: コンクリート
ArchiCADProperties - 要素ID: C3; ホットリンクおよび要素ID: C3; レイヤー: 柱; ビルディングマテリアル/複合構造/断面形状/塗りつぶし: コンクリート; ビルディングマテリアル: コンクリート; 関連ゾーン名: 店舗; ロック状態: no; 要素タイプ: 柱; 相対上部リンクフロア: 配置フロア + 1; 構造タイプ: 基本; 親ID: C3; ビルディングマテリアル (全て): コンクリート; 材質 (全て): コンクリート - 04; 表面塗りつぶし: 背景; 傾斜角度: 90 deg; リノベーションフィルタで表示: 全ての関連フィルタ; 構造機能: 構造耐力要素; 位置: エクステリア; リノベーションステータス: 既存; 柱横断面: 矩形; 柱傾斜角度: 90 deg; 押し出し表面: コンクリート - 04; 終端材質: コンクリート - 04; ARCHICAD 分類 - v 2.0: 柱
仕上情報 - WEBサイト: www.graphisoft.co.jp
AC_Pset_RenovationAndPhasing - Renovation Status: Existing
Pset_ColumnCommon - LoadBearing: yes; IsExternal: yes; Reference: コンクリート 800 x 500
BaseQuantities - Length: 3000 mm; Width: 800 mm; Depth: 500 mm; CrossSectionArea: 0.4 m2; OuterSurfaceArea: 7.8 m2; TotalSurfaceArea: 8.6 m2; GrossSurfaceArea: 8.6 m2; GrossVolume: 1.2 m3; NetVolume: 1.2 m3
ArchiCADQuantities - 面積: 0.4 m2; 高さ: 3000 mm; 正味体積: 1.2 m3; 幅: 800 mm; リンク/配置フロアまでの高度: 0 mm; 下部オフセット: 0 mm; 上部オフセット: 0 mm; 表面積: 7.8 m2; 3D長さ: 3000 mm; 総体積: 1.2 m3; 上端高度から配置フロア: 3000 mm; 下端高度から配置フロア: 0 mm; 上部/終了の断面高さ(垂直): 500 mm; 下部/開始の断面高さ(垂直): 500 mm; 上部/終了の断面幅(垂直): 800 mm; 下部/開始の断面幅(垂直): 800 mm; 上部/終了の断面高さ(切断): 500 mm; 下部/開始の断面高さ(切断): 500 mm; 上部/終了の断面幅(切断): 800 mm; 下部/開始の断面幅(切断): 800 mm; 下部/開始の断面の面積: 0.4 m2; 上部/終了の断面の面積: 0.4 m2; セグメント数: 1; 躯体高さ / 直径: 500 mm; 躯体の正味体積: 1.2 m3; 躯体幅: 800 mm; 躯体総表面積(上部/下部以外): 7.8 m2; 躯体上部の総表面積: 0.4 m2; 躯体下部の総表面積: 0.4 m2; 躯体総体積: 1.2 m3; 仕上げ総表面積(上部/下部以外): 0 m2; 仕上げ上部の総表面積: 0 m2; 仕上げ下部の総表面積: 0 m2; 仕上げ総体積: 0 m3; 柱最大高さ: 3000 mm; 柱最小高さ: 3000 mm; 躯体下部正味表面積: 0.4 m2; 躯体の正味表面積 (上部/下部以外): 7.8 m2; 躯体上部正味表面積: 0.4 m2; 仕上げ下部正味表面積: 0 m2; 仕上げ表面積: 0 m2; 仕上げ上部正味表面積: 0 m2; 柱断面形状の外周(下部): 2600 mm; 仕上げの正味体積: 0 m3
Name | In | 関連ゾーン番号 | ホームフロア名 | ホームフロア数 | 絶対上部リンクフロア | 上部リンクフロア | GLからの高度 (mm) = 高度 1 (mm) = 高度 2 (mm) = 海抜までの高度 (mm) = 下端高度から第1基準レベル (mm) = 下端高度から基準レベル (mm) = 下端高度から海抜 (mm) = 下端高度から第2基準レベル (mm) | 上端高度から第1基準レベル (mm) = 上端高度から基準レベル (mm) = 上端高度から海抜 (mm) = 上端高度から第2基準レベル (mm)
C3 | 1FL | 105 | 1FL | 1 | 2FL | 配置フロア + 1 (2FL) | 0 | 3000
C3 | 2FL | 214 | 2FL | 2 | 3FL | 配置フロア + 1 (3FL) | 3000 | 6000

# IfcColumn: コンクリート 800 x 800 (261)
Classification: 柱 (ARCHICAD 分類); Material: コンクリート
ArchiCADProperties - 要素ID: C1; レイヤー: 柱; ビルディングマテリアル/複合構造/断面形状/塗りつぶし: コンクリート; ビルディングマテリアル: コンクリート; 要素タイプ: 柱; 構造タイプ: 基本; 親ID: C1; ビルディングマテリアル (全て): コンクリート; 材質 (全て): コンクリート - 04; 表面塗りつぶし: 背景; 傾斜角度: 90 deg; リノベーションフィルタで表示: 全ての関連フィルタ; 構造機能: 構造耐力要素; リノベーションステータス: 既存; 柱横断面: 矩形; 柱傾斜角度: 90 deg; 押し出し表面: コンクリート - 04; 終端材質: コンクリート - 04; ARCHICAD 分類 - v 2.0: 柱
仕上情報 - WEBサイト: www.graphisoft.co.jp
AC_Pset_RenovationAndPhasing - Renovation Status: Existing
Pset_ColumnCommon - LoadBearing: yes; Reference: コンクリート 800 x 800
BaseQuantities - Length: 3000 mm; Width: 800 mm; Depth: 800 mm; CrossSectionArea: 0.64 m2; OuterSurfaceArea: 9.6 m2; TotalSurfaceArea: 10.88 m2; GrossSurfaceArea: 10.88 m2; GrossVolume: 1.92 m3; NetVolume: 1.92 m3
ArchiCADQuantities - 面積: 0.64 m2; 高さ: 3000 mm; 正味体積: 1.92 m3; 幅: 800 mm; リンク/配置フロアまでの高度: 0 mm; 下部オフセット: 0 mm; 上部オフセット: 0 mm; 表面積: 9.6 m2; 3D長さ: 3000 mm; 総体積: 1.92 m3; 上端高度から配置フロア: 3000 mm; 下端高度から配置フロア: 0 mm; 上部/終了の断面高さ(垂直): 800 mm; 下部/開始の断面高さ(垂直): 800 mm; 上部/終了の断面幅(垂直): 800 mm; 下部/開始の断面幅(垂直): 800 mm; 上部/終了の断面高さ(切断): 800 mm; 下部/開始の断面高さ(切断): 800 mm; 上部/終了の断面幅(切断): 800 mm; 下部/開始の断面幅(切断): 800 mm; 下部/開始の断面の面積: 0.64 m2; 上部/終了の断面の面積: 0.64 m2; セグメント数: 1; 躯体高さ / 直径: 800 mm; 躯体の正味体積: 1.92 m3; 躯体幅: 800 mm; 躯体総表面積(上部/下部以外): 9.6 m2; 躯体上部の総表面積: 0.64 m2; 躯体下部の総表面積: 0.64 m2; 躯体総体積: 1.92 m3; 仕上げ総表面積(上部/下部以外): 0 m2; 仕上げ上部の総表面積: 0 m2; 仕上げ下部の総表面積: 0 m2; 仕上げ総体積: 0 m3; 柱最大高さ: 3000 mm; 柱最小高さ: 3000 mm; 躯体下部正味表面積: 0.64 m2; 躯体の正味表面積 (上部/下部以外): 9.6 m2; 躯体上部正味表面積: 0.64 m2; 仕上げ下部正味表面積: 0 m2; 仕上げ表面積: 0 m2; 仕上げ上部正味表面積: 0 m2; 柱断面形状の外周(下部): 3200 mm; 仕上げの正味体積: 0 m3
Name | In | ホットリンクおよび要素ID | 関連ゾーン名 | 関連ゾーン番号 | ロック状態 | ホームフロア名 | ホームフロア数 | 絶対上部リンクフロア | 相対上部リンクフロア | 上部リンクフロア | 位置 | IsExternal | GLからの高度 (mm) = 高度 1 (mm) = 高度 2 (mm) = 海抜までの高度 (mm) = 下端高度から第1基準レベル (mm) = 下端高度から基準レベル (mm) = 下端高度から海抜 (mm) = 下端高度から第2基準レベル (mm) | 上端高度から第1基準レベル (mm) = 上端高度から基準レベル (mm) = 上端高度から海抜 (mm) = 上端高度から第2基準レベル (mm) | ホットリンク マスタID
3 x C1 | 1FL | C1 | 店舗 | 101 | no | 1FL | 1 | 2FL | 配置フロア + 1 | 配置フロア + 1 (2FL) | エクステリア | yes | 0 | 3000
C1 | 1FL | C1 | 店舗 | 101 | no | 1FL | 1 | 2FL | 配置フロア + 1 | 配置フロア + 1 (2FL) | インテリア | no | 0 | 3000
2 x C1 | 1FL | C1 | 店舗 | 102 | no | 1FL | 1 | 2FL | 配置フロア + 1 | 配置フロア + 1 (2FL) | インテリア | no | 0 | 3000
C1 | 1FL | C1 | 店舗 | 103 | no | 1FL | 1 | 2FL | 配置フロア + 1 | 配置フロア + 1 (2FL) | インテリア | no | 0 | 3000
3 x C1 | 1FL | C1 | 店舗 | 104 | no | 1FL | 1 | 2FL | 配置フロア + 1 | 配置フロア + 1 (2FL) | インテリア | no | 0 | 3000
4 x C1 | 1FL | C1 | 店舗 | 104 | no | 1FL | 1 | 2FL | 配置フロア + 1 | 配置フロア + 1 (2FL) | エクステリア | yes | 0 | 3000
C1 | 1FL | C1 | PS | ＜ゾーン番号＞ | no | 1FL | 1 | 2FL | 配置フロア + 1 | 配置フロア + 1 (2FL) | インテリア | no | 0 | 3000
C1 | 1FL | C1 | EVシャフト | ＜ゾーン番号＞ | no | 1FL | 1 | 2FL | 配置フロア + 1 | 配置フロア + 1 (2FL) | インテリア | no | 0 | 3000
C1 | 1FL | C1 | 男性用トイレ | ＜ゾーン番号＞ | no | 1FL | 1 | 2FL | 配置フロア + 1 | 配置フロア + 1 (2FL) | インテリア | no | 0 | 3000
C1 | 1FL | C1 | 管理室 | ＜ゾーン番号＞ | no | 1FL | 1 | 2FL | 配置フロア + 1 | 配置フロア + 1 (2FL) | インテリア | no | 0 | 3000
C1 | 1FL | C1 | 共用スペー | ＜ゾーン番号＞ | no | 1FL | 1 | 2FL | 配置フロア + 1 | 配置フロア + 1 (2FL) | インテリア | no | 0 | 3000
C1 | 1FL | C1 | PS | ＜ゾーン番号＞ | no | 1FL | 1 | 2FL | 配置フロア + 1 | 配置フロア + 1 (2FL) | エクステリア | yes | 0 | 3000
2 x C1 | 1FL | C1 | 店舗 | 102 | no | 1FL | 1 | 2FL | 配置フロア + 1 | 配置フロア + 1 (2FL) | エクステリア | yes | 0 | 3000
C1 | 1FL | C1 | 店舗 | 103 | no | 1FL | 1 | 2FL | 配置フロア + 1 | 配置フロア + 1 (2FL) | エクステリア | yes | 0 | 3000
2 x C1 | 1FL | C1 | 店舗 | 105 | no | 1FL | 1 | 2FL | 配置フロア + 1 | 配置フロア + 1 (2FL) | インテリア | no | 0 | 3000
C1 | 1FL | C1 | 店舗 | 106 | no | 1FL | 1 | 2FL | 配置フロア + 1 | 配置フロア + 1 (2FL) | インテリア | no | 0 | 3000
C1 | 1FL | C1 | 店舗 | 107 | no | 1FL | 1 | 2FL | 配置フロア + 1 | 配置フロア + 1 (2FL) | インテリア | no | 0 | 3000
C1 | 1FL | C1 | 店舗 | 108 | no | 1FL | 1 | 2FL | 配置フロア + 1 | 配置フロア + 1 (2FL) | インテリア | no | 0 | 3000
C1 | 1FL | C1 | ホール | ＜ゾーン番号＞ | no | 1FL | 1 | 2FL | 配置フロア + 1 | 配置フロア + 1 (2FL) | エクステリア | yes | 0 | 3000
C1 | 2FL | C1 | 廊下 | ＜ゾーン番号＞ | no | 2FL | 2 | 3FL | 配置フロア + 1 | 配置フロア + 1 (3FL) | エクステリア | yes | 3000 | 6000
5 x C1 | 2FL | C1 | 廊下 | ＜ゾーン番号＞ | no | 2FL | 2 | 3FL | 配置フロア + 1 | 配置フロア + 1 (3FL) | インテリア | no | 3000 | 6000
5 x C1 | 2FL | C1 | EVホール | ＜ゾーン番号＞ | no | 2FL | 2 | 3FL | 配置フロア + 1 | 配置フロア + 1 (3FL) | インテリア | no | 3000 | 6000
C1 | 2FL | C1 | EVホール | ＜ゾーン番号＞ | no | 2FL | 2 | 3FL | 配置フロア + 1 | 配置フロア + 1 (3FL) | エクステリア | yes | 3000 | 6000
C1 | 2FL | C1 | 店舗 | 210 | no | 2FL | 2 | 3FL | 配置フロア + 1 | 配置フロア + 1 (3FL) | エクステリア | yes | 3000 | 6000
2 x C1 | 2FL | C1 | 店舗 | 209 | no | 2FL | 2 | 3FL | 配置フロア + 1 | 配置フロア + 1 (3FL) | インテリア | no | 3000 | 6000
C1 | 2FL | C1 | 機械室 | ＜ゾーン番号＞ | no | 2FL | 2 | 3FL | 配置フロア + 1 | 配置フロア + 1 (3FL) | エクステリア | yes | 3000 | 6000
2 x C1 | 2FL | C1 | 店舗 | 201 | no | 2FL | 2 | 3FL | 配置フロア + 1 | 配置フロア + 1 (3FL) | エクステリア | yes | 3000 | 6000
C1 | 2FL | C1 | 店舗 | 202 | no | 2FL | 2 | 3FL | 配置フロア + 1 | 配置フロア + 1 (3FL) | エクステリア | yes | 3000 | 6000
C1 | 2FL | C1 | 店舗 | 203 | no | 2FL | 2 | 3FL | 配置フロア + 1 | 配置フロア + 1 (3FL) | エクステリア | yes | 3000 | 6000
2 x C1 | 2FL | C1 | 店舗 | 206 | no | 2FL | 2 | 3FL | 配置フロア + 1 | 配置フロア + 1 (3FL) | エクステリア | yes | 3000 | 6000
2 x C1 | 2FL | C1 | 店舗 | 214 | no | 2FL | 2 | 3FL | 配置フロア + 1 | 配置フロア + 1 (3FL) | インテリア | no | 3000 | 6000
C1 | 2FL | C1 | 店舗 | 212 | no | 2FL | 2 | 3FL | 配置フロア + 1 | 配置フロア + 1 (3FL) | インテリア | no | 3000 | 6000
C1 | 2FL | C1 | 店舗 | 211 | no | 2FL | 2 | 3FL | 配置フロア + 1 | 配置フロア + 1 (3FL) | インテリア | no | 3000 | 6000
C1 | 2FL | C1 | ホール | ＜ゾーン番号＞ | no | 2FL | 2 | 3FL | 配置フロア + 1 | 配置フロア + 1 (3FL) | インテリア | no | 3000 | 6000
C1 | 2FL | C1 | ホール | ＜ゾーン番号＞ | no | 2FL | 2 | 3FL | 配置フロア + 1 | 配置フロア + 1 (3FL) | エクステリア | yes | 3000 | 6000
C1 | 2FL | C1 | 店舗 | 207 | no | 2FL | 2 | 3FL | 配置フロア + 1 | 配置フロア + 1 (3FL) | エクステリア | yes | 3000 | 6000
3 x C1 | 3FL | C1 | 事務室 | 301 | no | 3FL | 3 | 4FL | 配置フロア + 1 | 配置フロア + 1 (4FL) | エクステリア | yes | 6000 | 9000
C1 | 3FL | C1 | 事務室 | 301 | no | 3FL | 3 | 4FL | 配置フロア + 1 | 配置フロア + 1 (4FL) | インテリア | no | 6000 | 9000
C1 | 3FL | C1 | 事務室 | 302 | no | 3FL | 3 | 4FL | 配置フロア + 1 | 配置フロア + 1 (4FL) | インテリア | no | 6000 | 9000
C1 | 3FL | C1 | 事務室 | 303 | no | 3FL | 3 | 4FL | 配置フロア + 1 | 配置フロア + 1 (4FL) | インテリア | no | 6000 | 9000
C1 | 3FL | C1 | 事務室 | 304 | no | 3FL | 3 | 4FL | 配置フロア + 1 | 配置フロア + 1 (4FL) | インテリア | no | 6000 | 9000
C1 | 3FL | C1 | 事務室 | 305 | no | 3FL | 3 | 4FL | 配置フロア + 1 | 配置フロア + 1 (4FL) | インテリア | no | 6000 | 9000
C1 | 3FL | C1 | 事務室 | 306 | no | 3FL | 3 | 4FL | 配置フロア + 1 | 配置フロア + 1 (4FL) | インテリア | no | 6000 | 9000
C1 | 3FL | C1 | 事務室 | 307 | no | 3FL | 3 | 4FL | 配置フロア + 1 | 配置フロア + 1 (4FL) | エクステリア | yes | 6000 | 9000
C1 | 3FL | C1 | 事務室 | 308 | no | 3FL | 3 | 4FL | 配置フロア + 1 | 配置フロア + 1 (4FL) | エクステリア | yes | 6000 | 9000
C1 | 3FL | C1 | 事務室 | 308 | no | 3FL | 3 | 4FL | 配置フロア + 1 | 配置フロア + 1 (4FL) | インテリア | no | 6000 | 9000
C1 | 3FL | C1 | 事務室 | 309 | no | 3FL | 3 | 4FL | 配置フロア + 1 | 配置フロア + 1 (4FL) | インテリア | no | 6000 | 9000
C1 | 3FL | C1 | EVシャフト | ＜ゾーン番号＞ | no | 3FL | 3 | 4FL | 配置フロア + 1 | 配置フロア + 1 (4FL) | インテリア | no | 6000 | 9000
C1 | 3FL | C1 | EVホール | ＜ゾーン番号＞ | no | 3FL | 3 | 4FL | 配置フロア + 1 | 配置フロア + 1 (4FL) | インテリア | no | 6000 | 9000
2 x C1 | 3FL | C1 | 事務室 | 310 | no | 3FL | 3 | 4FL | 配置フロア + 1 | 配置フロア + 1 (4FL) | インテリア | no | 6000 | 9000
C1 | 3FL | C1 | 事務室 | 311 | no | 3FL | 3 | 4FL | 配置フロア + 1 | 配置フロア + 1 (4FL) | インテリア | no | 6000 | 9000
C1 | 3FL | C1 | 事務室 | 302 | no | 3FL | 3 | 4FL | 配置フロア + 1 | 配置フロア + 1 (4FL) | エクステリア | yes | 6000 | 9000
C1 | 3FL | C1 | 事務室 | 303 | no | 3FL | 3 | 4FL | 配置フロア + 1 | 配置フロア + 1 (4FL) | エクステリア | yes | 6000 | 9000
C1 | 3FL | C1 | 事務室 | 304 | no | 3FL | 3 | 4FL | 配置フロア + 1 | 配置フロア + 1 (4FL) | エクステリア | yes | 6000 | 9000
C1 | 3FL | C1 | 事務室 | 305 | no | 3FL | 3 | 4FL | 配置フロア + 1 | 配置フロア + 1 (4FL) | エクステリア | yes | 6000 | 9000
C1 | 3FL | C1 | 事務室 | 316 | no | 3FL | 3 | 4FL | 配置フロア + 1 | 配置フロア + 1 (4FL) | インテリア | no | 6000 | 9000
C1 | 3FL | C1 | 事務室 | 315 | no | 3FL | 3 | 4FL | 配置フロア + 1 | 配置フロア + 1 (4FL) | インテリア | no | 6000 | 9000
C1 | 3FL | C1 | 事務室 | 314 | no | 3FL | 3 | 4FL | 配置フロア + 1 | 配置フロア + 1 (4FL) | インテリア | no | 6000 | 9000
2 x C1 | 3FL | C1 | 事務室 | 313 | no | 3FL | 3 | 4FL | 配置フロア + 1 | 配置フロア + 1 (4FL) | インテリア | no | 6000 | 9000
C1 | 3FL | C1 | 事務室 | 312 | no | 3FL | 3 | 4FL | 配置フロア + 1 | 配置フロア + 1 (4FL) | エクステリア | yes | 6000 | 9000
C1 | 3FL | C1 | 事務室 | 306 | no | 3FL | 3 | 4FL | 配置フロア + 1 | 配置フロア + 1 (4FL) | エクステリア | yes | 6000 | 9000
3 x 4FLC1 | 4FL | 4FLC1 | 事務室 | 301 | yes | 4FL | 4 | リンクなし | リンクなし | リンクなし | エクステリア | yes | 9000 | 12000 | 4FL
4FLC1 | 4FL | 4FLC1 | 事務室 | 301 | yes | 4FL | 4 | リンクなし | リンクなし | リンクなし | インテリア | no | 9000 | 12000 | 4FL
4FLC1 | 4FL | 4FLC1 | 事務室 | 302 | yes | 4FL | 4 | リンクなし | リンクなし | リンクなし | インテリア | no | 9000 | 12000 | 4FL
4FLC1 | 4FL | 4FLC1 | 事務室 | 303 | yes | 4FL | 4 | リンクなし | リンクなし | リンクなし | インテリア | no | 9000 | 12000 | 4FL
4FLC1 | 4FL | 4FLC1 | 事務室 | 304 | yes | 4FL | 4 | リンクなし | リンクなし | リンクなし | インテリア | no | 9000 | 12000 | 4FL
4FLC1 | 4FL | 4FLC1 | 事務室 | 305 | yes | 4FL | 4 | リンクなし | リンクなし | リンクなし | インテリア | no | 9000 | 12000 | 4FL
4FLC1 | 4FL | 4FLC1 | 事務室 | 306 | yes | 4FL | 4 | リンクなし | リンクなし | リンクなし | インテリア | no | 9000 | 12000 | 4FL
4FLC1 | 4FL | 4FLC1 | 事務室 | 307 | yes | 4FL | 4 | リンクなし | リンクなし | リンクなし | エクステリア | yes | 9000 | 12000 | 4FL
4FLC1 | 4FL | 4FLC1 | 事務室 | 308 | yes | 4FL | 4 | リンクなし | リンクなし | リンクなし | エクステリア | yes | 9000 | 12000 | 4FL
4FLC1 | 4FL | 4FLC1 | 事務室 | 308 | yes | 4FL | 4 | リンクなし | リンクなし | リンクなし | インテリア | no | 9000 | 12000 | 4FL
4FLC1 | 4FL | 4FLC1 | 事務室 | 309 | yes | 4FL | 4 | リンクなし | リンクなし | リンクなし | インテリア | no | 9000 | 12000 | 4FL
4FLC1 | 4FL | 4FLC1 | EVシャフト | ＜ゾーン番号＞ | yes | 4FL | 4 | リンクなし | リンクなし | リンクなし | インテリア | no | 9000 | 12000 | 4FL
4FLC1 | 4FL | 4FLC1 | EVホール | ＜ゾーン番号＞ | yes | 4FL | 4 | リンクなし | リンクなし | リンクなし | インテリア | no | 9000 | 12000 | 4FL
2 x 4FLC1 | 4FL | 4FLC1 | 事務室 | 310 | yes | 4FL | 4 | リンクなし | リンクなし | リンクなし | インテリア | no | 9000 | 12000 | 4FL
4FLC1 | 4FL | 4FLC1 | 事務室 | 302 | yes | 4FL | 4 | リンクなし | リンクなし | リンクなし | エクステリア | yes | 9000 | 12000 | 4FL
4FLC1 | 4FL | 4FLC1 | 事務室 | 303 | yes | 4FL | 4 | リンクなし | リンクなし | リンクなし | エクステリア | yes | 9000 | 12000 | 4FL
4FLC1 | 4FL | 4FLC1 | 事務室 | 304 | yes | 4FL | 4 | リンクなし | リンクなし | リンクなし | エクステリア | yes | 9000 | 12000 | 4FL
4FLC1 | 4FL | 4FLC1 | 事務室 | 305 | yes | 4FL | 4 | リンクなし | リンクなし | リンクなし | エクステリア | yes | 9000 | 12000 | 4FL
4FLC1 | 4FL | 4FLC1 | 事務室 | 316 | yes | 4FL | 4 | リンクなし | リンクなし | リンクなし | インテリア | no | 9000 | 12000 | 4FL
4FLC1 | 4FL | 4FLC1 | 事務室 | 315 | yes | 4FL | 4 | リンクなし | リンクなし | リンクなし | インテリア | no | 9000 | 12000 | 4FL
4FLC1 | 4FL | 4FLC1 | 事務室 | 314 | yes | 4FL | 4 | リンクなし | リンクなし | リンクなし | インテリア | no | 9000 | 12000 | 4FL
2 x 4FLC1 | 4FL | 4FLC1 | 事務室 | 313 | yes | 4FL | 4 | リンクなし | リンクなし | リンクなし | インテリア | no | 9000 | 12000 | 4FL
4FLC1 | 4FL | 4FLC1 | 事務室 | 312 | yes | 4FL | 4 | リンクなし | リンクなし | リンクなし | エクステリア | yes | 9000 | 12000 | 4FL
4FLC1 | 4FL | 4FLC1 | 事務室 | 311 | yes | 4FL | 4 | リンクなし | リンクなし | リンクなし | インテリア | no | 9000 | 12000 | 4FL
4FLC1 | 4FL | 4FLC1 | 事務室 | 306 | yes | 4FL | 4 | リンクなし | リンクなし | リンクなし | エクステリア | yes | 9000 | 12000 | 4FL
3 x 5FLC1 | 5FL | 5FLC1 | 事務室 | 301 | yes | 5FL | 5 | リンクなし | リンクなし | リンクなし | エクステリア | yes | 12000 | 15000 | 5FL
5FLC1 | 5FL | 5FLC1 | 事務室 | 301 | yes | 5FL | 5 | リンクなし | リンクなし | リンクなし | インテリア | no | 12000 | 15000 | 5FL
5FLC1 | 5FL | 5FLC1 | 事務室 | 302 | yes | 5FL | 5 | リンクなし | リンクなし | リンクなし | インテリア | no | 12000 | 15000 | 5FL
5FLC1 | 5FL | 5FLC1 | 事務室 | 303 | yes | 5FL | 5 | リンクなし | リンクなし | リンクなし | インテリア | no | 12000 | 15000 | 5FL
5FLC1 | 5FL | 5FLC1 | 事務室 | 304 | yes | 5FL | 5 | リンクなし | リンクなし | リンクなし | インテリア | no | 12000 | 15000 | 5FL
5FLC1 | 5FL | 5FLC1 | 事務室 | 305 | yes | 5FL | 5 | リンクなし | リンクなし | リンクなし | インテリア | no | 12000 | 15000 | 5FL
5FLC1 | 5FL | 5FLC1 | 事務室 | 306 | yes | 5FL | 5 | リンクなし | リンクなし | リンクなし | インテリア | no | 12000 | 15000 | 5FL
5FLC1 | 5FL | 5FLC1 | 事務室 | 307 | yes | 5FL | 5 | リンクなし | リンクなし | リンクなし | エクステリア | yes | 12000 | 15000 | 5FL
5FLC1 | 5FL | 5FLC1 | 事務室 | 308 | yes | 5FL | 5 | リンクなし | リンクなし | リンクなし | エクステリア | yes | 12000 | 15000 | 5FL
5FLC1 | 5FL | 5FLC1 | 事務室 | 308 | yes | 5FL | 5 | リンクなし | リンクなし | リンクなし | インテリア | no | 12000 | 15000 | 5FL
5FLC1 | 5FL | 5FLC1 | 事務室 | 309 | yes | 5FL | 5 | リンクなし | リンクなし | リンクなし | インテリア | no | 12000 | 15000 | 5FL
5FLC1 | 5FL | 5FLC1 | EVシャフト | ＜ゾーン番号＞ | yes | 5FL | 5 | リンクなし | リンクなし | リンクなし | インテリア | no | 12000 | 15000 | 5FL
5FLC1 | 5FL | 5FLC1 | EVホール | ＜ゾーン番号＞ | yes | 5FL | 5 | リンクなし | リンクなし | リンクなし | インテリア | no | 12000 | 15000 | 5FL
2 x 5FLC1 | 5FL | 5FLC1 | 事務室 | 310 | yes | 5FL | 5 | リンクなし | リンクなし | リンクなし | インテリア | no | 12000 | 15000 | 5FL
5FLC1 | 5FL | 5FLC1 | 事務室 | 302 | yes | 5FL | 5 | リンクなし | リンクなし | リンクなし | エクステリア | yes | 12000 | 15000 | 5FL
5FLC1 | 5FL | 5FLC1 | 事務室 | 303 | yes | 5FL | 5 | リンクなし | リンクなし | リンクなし | エクステリア | yes | 12000 | 15000 | 5FL
5FLC1 | 5FL | 5FLC1 | 事務室 | 304 | yes | 5FL | 5 | リンクなし | リンクなし | リンクなし | エクステリア | yes | 12000 | 15000 | 5FL
5FLC1 | 5FL | 5FLC1 | 事務室 | 305 | yes | 5FL | 5 | リンクなし | リンクなし | リンクなし | エクステリア | yes | 12000 | 15000 | 5FL
5FLC1 | 5FL | 5FLC1 | 事務室 | 316 | yes | 5FL | 5 | リンクなし | リンクなし | リンクなし | インテリア | no | 12000 | 15000 | 5FL
5FLC1 | 5FL | 5FLC1 | 事務室 | 315 | yes | 5FL | 5 | リンクなし | リンクなし | リンクなし | インテリア | no | 12000 | 15000 | 5FL
5FLC1 | 5FL | 5FLC1 | 事務室 | 314 | yes | 5FL | 5 | リンクなし | リンクなし | リンクなし | インテリア | no | 12000 | 15000 | 5FL
2 x 5FLC1 | 5FL | 5FLC1 | 事務室 | 313 | yes | 5FL | 5 | リンクなし | リンクなし | リンクなし | インテリア | no | 12000 | 15000 | 5FL
5FLC1 | 5FL | 5FLC1 | 事務室 | 312 | yes | 5FL | 5 | リンクなし | リンクなし | リンクなし | エクステリア | yes | 12000 | 15000 | 5FL
5FLC1 | 5FL | 5FLC1 | 事務室 | 311 | yes | 5FL | 5 | リンクなし | リンクなし | リンクなし | インテリア | no | 12000 | 15000 | 5FL
5FLC1 | 5FL | 5FLC1 | 事務室 | 306 | yes | 5FL | 5 | リンクなし | リンクなし | リンクなし | エクステリア | yes | 12000 | 15000 | 5FL
3 x 6FLC1 | 6FL | 6FLC1 | 事務室 | 301 | yes | 6FL | 6 | リンクなし | リンクなし | リンクなし | エクステリア | yes | 15000 | 18000 | 6FL
6FLC1 | 6FL | 6FLC1 | 事務室 | 301 | yes | 6FL | 6 | リンクなし | リンクなし | リンクなし | インテリア | no | 15000 | 18000 | 6FL
6FLC1 | 6FL | 6FLC1 | 事務室 | 302 | yes | 6FL | 6 | リンクなし | リンクなし | リンクなし | インテリア | no | 15000 | 18000 | 6FL
6FLC1 | 6FL | 6FLC1 | 事務室 | 303 | yes | 6FL | 6 | リンクなし | リンクなし | リンクなし | インテリア | no | 15000 | 18000 | 6FL
6FLC1 | 6FL | 6FLC1 | 事務室 | 304 | yes | 6FL | 6 | リンクなし | リンクなし | リンクなし | インテリア | no | 15000 | 18000 | 6FL
6FLC1 | 6FL | 6FLC1 | 事務室 | 305 | yes | 6FL | 6 | リンクなし | リンクなし | リンクなし | インテリア | no | 15000 | 18000 | 6FL
6FLC1 | 6FL | 6FLC1 | 事務室 | 306 | yes | 6FL | 6 | リンクなし | リンクなし | リンクなし | インテリア | no | 15000 | 18000 | 6FL
6FLC1 | 6FL | 6FLC1 | 事務室 | 307 | yes | 6FL | 6 | リンクなし | リンクなし | リンクなし | エクステリア | yes | 15000 | 18000 | 6FL
6FLC1 | 6FL | 6FLC1 | 事務室 | 308 | yes | 6FL | 6 | リンクなし | リンクなし | リンクなし | エクステリア | yes | 15000 | 18000 | 6FL
6FLC1 | 6FL | 6FLC1 | 事務室 | 308 | yes | 6FL | 6 | リンクなし | リンクなし | リンクなし | インテリア | no | 15000 | 18000 | 6FL
6FLC1 | 6FL | 6FLC1 | 事務室 | 309 | yes | 6FL | 6 | リンクなし | リンクなし | リンクなし | インテリア | no | 15000 | 18000 | 6FL
6FLC1 | 6FL | 6FLC1 | EVシャフト | ＜ゾーン番号＞ | yes | 6FL | 6 | リンクなし | リンクなし | リンクなし | インテリア | no | 15000 | 18000 | 6FL
6FLC1 | 6FL | 6FLC1 | EVホール | ＜ゾーン番号＞ | yes | 6FL | 6 | リンクなし | リンクなし | リンクなし | インテリア | no | 15000 | 18000 | 6FL
2 x 6FLC1 | 6FL | 6FLC1 | 事務室 | 310 | yes | 6FL | 6 | リンクなし | リンクなし | リンクなし | インテリア | no | 15000 | 18000 | 6FL
6FLC1 | 6FL | 6FLC1 | 事務室 | 302 | yes | 6FL | 6 | リンクなし | リンクなし | リンクなし | エクステリア | yes | 15000 | 18000 | 6FL
6FLC1 | 6FL | 6FLC1 | 事務室 | 303 | yes | 6FL | 6 | リンクなし | リンクなし | リンクなし | エクステリア | yes | 15000 | 18000 | 6FL
6FLC1 | 6FL | 6FLC1 | 事務室 | 304 | yes | 6FL | 6 | リンクなし | リンクなし | リンクなし | エクステリア | yes | 15000 | 18000 | 6FL
6FLC1 | 6FL | 6FLC1 | 事務室 | 305 | yes | 6FL | 6 | リンクなし | リンクなし | リンクなし | エクステリア | yes | 15000 | 18000 | 6FL
6FLC1 | 6FL | 6FLC1 | 事務室 | 316 | yes | 6FL | 6 | リンクなし | リンクなし | リンクなし | インテリア | no | 15000 | 18000 | 6FL
6FLC1 | 6FL | 6FLC1 | 事務室 | 315 | yes | 6FL | 6 | リンクなし | リンクなし | リンクなし | インテリア | no | 15000 | 18000 | 6FL
6FLC1 | 6FL | 6FLC1 | 事務室 | 314 | yes | 6FL | 6 | リンクなし | リンクなし | リンクなし | インテリア | no | 15000 | 18000 | 6FL
2 x 6FLC1 | 6FL | 6FLC1 | 事務室 | 313 | yes | 6FL | 6 | リンクなし | リンクなし | リンクなし | インテリア | no | 15000 | 18000 | 6FL
6FLC1 | 6FL | 6FLC1 | 事務室 | 312 | yes | 6FL | 6 | リンクなし | リンクなし | リンクなし | エクステリア | yes | 15000 | 18000 | 6FL
6FLC1 | 6FL | 6FLC1 | 事務室 | 311 | yes | 6FL | 6 | リンクなし | リンクなし | リンクなし | インテリア | no | 15000 | 18000 | 6FL
6FLC1 | 6FL | 6FLC1 | 事務室 | 306 | yes | 6FL | 6 | リンクなし | リンクなし | リンクなし | エクステリア | yes | 15000 | 18000 | 6FL
3 x 7FLC1 | 7FL | 7FLC1 | 事務室 | 301 | yes | 7FL | 7 | リンクなし | リンクなし | リンクなし | エクステリア | yes | 18000 | 21000 | 7FL
7FLC1 | 7FL | 7FLC1 | 事務室 | 301 | yes | 7FL | 7 | リンクなし | リンクなし | リンクなし | インテリア | no | 18000 | 21000 | 7FL
7FLC1 | 7FL | 7FLC1 | 事務室 | 302 | yes | 7FL | 7 | リンクなし | リンクなし | リンクなし | インテリア | no | 18000 | 21000 | 7FL
7FLC1 | 7FL | 7FLC1 | 事務室 | 303 | yes | 7FL | 7 | リンクなし | リンクなし | リンクなし | インテリア | no | 18000 | 21000 | 7FL
7FLC1 | 7FL | 7FLC1 | 事務室 | 304 | yes | 7FL | 7 | リンクなし | リンクなし | リンクなし | インテリア | no | 18000 | 21000 | 7FL
7FLC1 | 7FL | 7FLC1 | 事務室 | 305 | yes | 7FL | 7 | リンクなし | リンクなし | リンクなし | インテリア | no | 18000 | 21000 | 7FL
7FLC1 | 7FL | 7FLC1 | 事務室 | 306 | yes | 7FL | 7 | リンクなし | リンクなし | リンクなし | インテリア | no | 18000 | 21000 | 7FL
7FLC1 | 7FL | 7FLC1 | 事務室 | 307 | yes | 7FL | 7 | リンクなし | リンクなし | リンクなし | エクステリア | yes | 18000 | 21000 | 7FL
7FLC1 | 7FL | 7FLC1 | 事務室 | 308 | yes | 7FL | 7 | リンクなし | リンクなし | リンクなし | エクステリア | yes | 18000 | 21000 | 7FL
7FLC1 | 7FL | 7FLC1 | 事務室 | 308 | yes | 7FL | 7 | リンクなし | リンクなし | リンクなし | インテリア | no | 18000 | 21000 | 7FL
7FLC1 | 7FL | 7FLC1 | 事務室 | 309 | yes | 7FL | 7 | リンクなし | リンクなし | リンクなし | インテリア | no | 18000 | 21000 | 7FL
7FLC1 | 7FL | 7FLC1 | EVシャフト | ＜ゾーン番号＞ | yes | 7FL | 7 | リンクなし | リンクなし | リンクなし | インテリア | no | 18000 | 21000 | 7FL
7FLC1 | 7FL | 7FLC1 | EVホール | ＜ゾーン番号＞ | yes | 7FL | 7 | リンクなし | リンクなし | リンクなし | インテリア | no | 18000 | 21000 | 7FL
2 x 7FLC1 | 7FL | 7FLC1 | 事務室 | 310 | yes | 7FL | 7 | リンクなし | リンクなし | リンクなし | インテリア | no | 18000 | 21000 | 7FL
7FLC1 | 7FL | 7FLC1 | 事務室 | 302 | yes | 7FL | 7 | リンクなし | リンクなし | リンクなし | エクステリア | yes | 18000 | 21000 | 7FL
7FLC1 | 7FL | 7FLC1 | 事務室 | 303 | yes | 7FL | 7 | リンクなし | リンクなし | リンクなし | エクステリア | yes | 18000 | 21000 | 7FL
7FLC1 | 7FL | 7FLC1 | 事務室 | 304 | yes | 7FL | 7 | リンクなし | リンクなし | リンクなし | エクステリア | yes | 18000 | 21000 | 7FL
7FLC1 | 7FL | 7FLC1 | 事務室 | 305 | yes | 7FL | 7 | リンクなし | リンクなし | リンクなし | エクステリア | yes | 18000 | 21000 | 7FL
7FLC1 | 7FL | 7FLC1 | 事務室 | 316 | yes | 7FL | 7 | リンクなし | リンクなし | リンクなし | インテリア | no | 18000 | 21000 | 7FL
7FLC1 | 7FL | 7FLC1 | 事務室 | 315 | yes | 7FL | 7 | リンクなし | リンクなし | リンクなし | インテリア | no | 18000 | 21000 | 7FL
7FLC1 | 7FL | 7FLC1 | 事務室 | 314 | yes | 7FL | 7 | リンクなし | リンクなし | リンクなし | インテリア | no | 18000 | 21000 | 7FL
2 x 7FLC1 | 7FL | 7FLC1 | 事務室 | 313 | yes | 7FL | 7 | リンクなし | リンクなし | リンクなし | インテリア | no | 18000 | 21000 | 7FL
7FLC1 | 7FL | 7FLC1 | 事務室 | 312 | yes | 7FL | 7 | リンクなし | リンクなし | リンクなし | エクステリア | yes | 18000 | 21000 | 7FL
7FLC1 | 7FL | 7FLC1 | 事務室 | 311 | yes | 7FL | 7 | リンクなし | リンクなし | リンクなし | インテリア | no | 18000 | 21000 | 7FL
7FLC1 | 7FL | 7FLC1 | 事務室 | 306 | yes | 7FL | 7 | リンクなし | リンクなし | リンクなし | エクステリア | yes | 18000 | 21000 | 7FL
3 x 8FLC1 | 8FL | 8FLC1 | 事務室 | 301 | yes | 8FL | 8 | リンクなし | リンクなし | リンクなし | エクステリア | yes | 21000 | 24000 | 8FL
8FLC1 | 8FL | 8FLC1 | 事務室 | 301 | yes | 8FL | 8 | リンクなし | リンクなし | リンクなし | インテリア | no | 21000 | 24000 | 8FL
8FLC1 | 8FL | 8FLC1 | 事務室 | 302 | yes | 8FL | 8 | リンクなし | リンクなし | リンクなし | インテリア | no | 21000 | 24000 | 8FL
8FLC1 | 8FL | 8FLC1 | 事務室 | 303 | yes | 8FL | 8 | リンクなし | リンクなし | リンクなし | インテリア | no | 21000 | 24000 | 8FL
8FLC1 | 8FL | 8FLC1 | 事務室 | 304 | yes | 8FL | 8 | リンクなし | リンクなし | リンクなし | インテリア | no | 21000 | 24000 | 8FL
8FLC1 | 8FL | 8FLC1 | 事務室 | 305 | yes | 8FL | 8 | リンクなし | リンクなし | リンクなし | インテリア | no | 21000 | 24000 | 8FL
8FLC1 | 8FL | 8FLC1 | 事務室 | 306 | yes | 8FL | 8 | リンクなし | リンクなし | リンクなし | インテリア | no | 21000 | 24000 | 8FL
8FLC1 | 8FL | 8FLC1 | 事務室 | 307 | yes | 8FL | 8 | リンクなし | リンクなし | リンクなし | エクステリア | yes | 21000 | 24000 | 8FL
8FLC1 | 8FL | 8FLC1 | 事務室 | 308 | yes | 8FL | 8 | リンクなし | リンクなし | リンクなし | エクステリア | yes | 21000 | 24000 | 8FL
8FLC1 | 8FL | 8FLC1 | 事務室 | 308 | yes | 8FL | 8 | リンクなし | リンクなし | リンクなし | インテリア | no | 21000 | 24000 | 8FL
8FLC1 | 8FL | 8FLC1 | 事務室 | 309 | yes | 8FL | 8 | リンクなし | リンクなし | リンクなし | インテリア | no | 21000 | 24000 | 8FL
8FLC1 | 8FL | 8FLC1 | EVシャフト | ＜ゾーン番号＞ | yes | 8FL | 8 | リンクなし | リンクなし | リンクなし | インテリア | no | 21000 | 24000 | 8FL
8FLC1 | 8FL | 8FLC1 | EVホール | ＜ゾーン番号＞ | yes | 8FL | 8 | リンクなし | リンクなし | リンクなし | インテリア | no | 21000 | 24000 | 8FL
2 x 8FLC1 | 8FL | 8FLC1 | 事務室 | 310 | yes | 8FL | 8 | リンクなし | リンクなし | リンクなし | インテリア | no | 21000 | 24000 | 8FL
8FLC1 | 8FL | 8FLC1 | 事務室 | 302 | yes | 8FL | 8 | リンクなし | リンクなし | リンクなし | エクステリア | yes | 21000 | 24000 | 8FL
8FLC1 | 8FL | 8FLC1 | 事務室 | 303 | yes | 8FL | 8 | リンクなし | リンクなし | リンクなし | エクステリア | yes | 21000 | 24000 | 8FL
8FLC1 | 8FL | 8FLC1 | 事務室 | 304 | yes | 8FL | 8 | リンクなし | リンクなし | リンクなし | エクステリア | yes | 21000 | 24000 | 8FL
8FLC1 | 8FL | 8FLC1 | 事務室 | 305 | yes | 8FL | 8 | リンクなし | リンクなし | リンクなし | エクステリア | yes | 21000 | 24000 | 8FL
8FLC1 | 8FL | 8FLC1 | 事務室 | 316 | yes | 8FL | 8 | リンクなし | リンクなし | リンクなし | インテリア | no | 21000 | 24000 | 8FL
8FLC1 | 8FL | 8FLC1 | 事務室 | 315 | yes | 8FL | 8 | リンクなし | リンクなし | リンクなし | インテリア | no | 21000 | 24000 | 8FL
8FLC1 | 8FL | 8FLC1 | 事務室 | 314 | yes | 8FL | 8 | リンクなし | リンクなし | リンクなし | インテリア | no | 21000 | 24000 | 8FL
2 x 8FLC1 | 8FL | 8FLC1 | 事務室 | 313 | yes | 8FL | 8 | リンクなし | リンクなし | リンクなし | インテリア | no | 21000 | 24000 | 8FL
8FLC1 | 8FL | 8FLC1 | 事務室 | 312 | yes | 8FL | 8 | リンクなし | リンクなし | リンクなし | エクステリア | yes | 21000 | 24000 | 8FL
8FLC1 | 8FL | 8FLC1 | 事務室 | 311 | yes | 8FL | 8 | リンクなし | リンクなし | リンクなし | インテリア | no | 21000 | 24000 | 8FL
8FLC1 | 8FL | 8FLC1 | 事務室 | 306 | yes | 8FL | 8 | リンクなし | リンクなし | リンクなし | エクステリア | yes | 21000 | 24000 | 8FL
3 x 9FLC1 | 9FL | 9FLC1 | 事務室 | 301 | yes | 9FL | 9 | リンクなし | リンクなし | リンクなし | エクステリア | yes | 24000 | 27000 | 9FL
9FLC1 | 9FL | 9FLC1 | 事務室 | 301 | yes | 9FL | 9 | リンクなし | リンクなし | リンクなし | インテリア | no | 24000 | 27000 | 9FL
9FLC1 | 9FL | 9FLC1 | 事務室 | 302 | yes | 9FL | 9 | リンクなし | リンクなし | リンクなし | インテリア | no | 24000 | 27000 | 9FL
9FLC1 | 9FL | 9FLC1 | 事務室 | 303 | yes | 9FL | 9 | リンクなし | リンクなし | リンクなし | インテリア | no | 24000 | 27000 | 9FL
9FLC1 | 9FL | 9FLC1 | 事務室 | 304 | yes | 9FL | 9 | リンクなし | リンクなし | リンクなし | インテリア | no | 24000 | 27000 | 9FL
9FLC1 | 9FL | 9FLC1 | 事務室 | 305 | yes | 9FL | 9 | リンクなし | リンクなし | リンクなし | インテリア | no | 24000 | 27000 | 9FL
9FLC1 | 9FL | 9FLC1 | 事務室 | 306 | yes | 9FL | 9 | リンクなし | リンクなし | リンクなし | インテリア | no | 24000 | 27000 | 9FL
9FLC1 | 9FL | 9FLC1 | 事務室 | 307 | yes | 9FL | 9 | リンクなし | リンクなし | リンクなし | エクステリア | yes | 24000 | 27000 | 9FL
9FLC1 | 9FL | 9FLC1 | 事務室 | 308 | yes | 9FL | 9 | リンクなし | リンクなし | リンクなし | エクステリア | yes | 24000 | 27000 | 9FL
9FLC1 | 9FL | 9FLC1 | 事務室 | 308 | yes | 9FL | 9 | リンクなし | リンクなし | リンクなし | インテリア | no | 24000 | 27000 | 9FL
9FLC1 | 9FL | 9FLC1 | 事務室 | 309 | yes | 9FL | 9 | リンクなし | リンクなし | リンクなし | インテリア | no | 24000 | 27000 | 9FL
9FLC1 | 9FL | 9FLC1 | EVシャフト | ＜ゾーン番号＞ | yes | 9FL | 9 | リンクなし | リンクなし | リンクなし | インテリア | no | 24000 | 27000 | 9FL
9FLC1 | 9FL | 9FLC1 | EVホール | ＜ゾーン番号＞ | yes | 9FL | 9 | リンクなし | リンクなし | リンクなし | インテリア | no | 24000 | 27000 | 9FL
2 x 9FLC1 | 9FL | 9FLC1 | 事務室 | 310 | yes | 9FL | 9 | リンクなし | リンクなし | リンクなし | インテリア | no | 24000 | 27000 | 9FL
9FLC1 | 9FL | 9FLC1 | 事務室 | 302 | yes | 9FL | 9 | リンクなし | リンクなし | リンクなし | エクステリア | yes | 24000 | 27000 | 9FL
9FLC1 | 9FL | 9FLC1 | 事務室 | 303 | yes | 9FL | 9 | リンクなし | リンクなし | リンクなし | エクステリア | yes | 24000 | 27000 | 9FL
9FLC1 | 9FL | 9FLC1 | 事務室 | 304 | yes | 9FL | 9 | リンクなし | リンクなし | リンクなし | エクステリア | yes | 24000 | 27000 | 9FL
9FLC1 | 9FL | 9FLC1 | 事務室 | 305 | yes | 9FL | 9 | リンクなし | リンクなし | リンクなし | エクステリア | yes | 24000 | 27000 | 9FL
9FLC1 | 9FL | 9FLC1 | 事務室 | 316 | yes | 9FL | 9 | リンクなし | リンクなし | リンクなし | インテリア | no | 24000 | 27000 | 9FL
9FLC1 | 9FL | 9FLC1 | 事務室 | 315 | yes | 9FL | 9 | リンクなし | リンクなし | リンクなし | インテリア | no | 24000 | 27000 | 9FL
9FLC1 | 9FL | 9FLC1 | 事務室 | 314 | yes | 9FL | 9 | リンクなし | リンクなし | リンクなし | インテリア | no | 24000 | 27000 | 9FL
2 x 9FLC1 | 9FL | 9FLC1 | 事務室 | 313 | yes | 9FL | 9 | リンクなし | リンクなし | リンクなし | インテリア | no | 24000 | 27000 | 9FL
9FLC1 | 9FL | 9FLC1 | 事務室 | 312 | yes | 9FL | 9 | リンクなし | リンクなし | リンクなし | エクステリア | yes | 24000 | 27000 | 9FL
9FLC1 | 9FL | 9FLC1 | 事務室 | 311 | yes | 9FL | 9 | リンクなし | リンクなし | リンクなし | インテリア | no | 24000 | 27000 | 9FL
9FLC1 | 9FL | 9FLC1 | 事務室 | 306 | yes | 9FL | 9 | リンクなし | リンクなし | リンクなし | エクステリア | yes | 24000 | 27000 | 9FL

# IfcCurtainWall: カーテンウォールタイプ (23)
Classification: カーテンウォール (ARCHICAD 分類)
ArchiCADProperties - レイヤー: カーテンウォール; 要素タイプ: カーテンウォール; 傾斜角度: 90 deg; リノベーションフィルタで表示: 全ての関連フィルタ; 位置: エクステリア; リノベーションステータス: 既存; パターン角度: 90 deg; カーテンウォール傾斜角度: 90 deg; ARCHICAD 分類 - v 2.0: カーテンウォール
AC_Pset_RenovationAndPhasing - Renovation Status: Existing
Pset_CurtainWallCommon - IsExternal: yes
BaseQuantities - Height: 3000 mm
ArchiCADQuantities - 高さ: 3000 mm; 上端高度から配置フロア: 3000 mm; 副軸に属するフレーム全長: 0 mm; 北東向きパネルの全表面積: 0 m2
Name | In | Material | 関連ゾーン名 | 関連ゾーン番号 | ロック状態 | ホームフロア名 | ホームフロア数 | ビルディングマテリアル (全て) | 材質 (全て) | 構造機能 | Width (mm) = 厚さ (mm) | Length (mm) = 長さ (mm) | GrossSideArea (m2) = NetSideArea (m2) = 表面積 (m2) = 境界を含んだ表面積 (m2) | GLからの高度 (mm) = 高度 1 (mm) = 高度 2 (mm) = 海抜までの高度 (mm) = 下端高度から第1基準レベル (mm) = 下端高度から基準レベル (mm) = 下端高度から海抜 (mm) = 下端高度から第2基準レベル (mm) | リンク/配置フロアまでの高度 (mm) = 下部オフセット (mm) = 下端高度から配置フロア (mm) | 上端高度から第1基準レベル (mm) = 上端高度から基準レベル (mm) = 上端高度から海抜 (mm) = 上端高度から第2基準レベル (mm) | パネル数 | フレーム合計長さ (mm) | 合計パネル表面積 (m2) | 輪郭フレーム全長 (mm) | 主軸に属するフレーム全長 (mm) | カスタムフレーム全長 (mm) | 北向きパネルの全表面積 (m2) | 南向きパネルの全表面積 (m2) | 東向きパネルの全表面積 (m2) | 西向きパネルの全表面積 (m2) | 北西向きパネルの全表面積 (m2) | 南東向きパネルの全表面積 (m2) | 南西向きパネルの全表面積 (m2) | 要素ID = 親ID | ホットリンクおよび要素ID | ホットリンク マスタID
 | 1FL | 金属-アルミニウム (201), ガラス-青, 金属-ステンレス | 避難階段 | ＜ゾーン番号＞ | no | 1FL | 1 | 金属-アルミニウム | 金属 - ステンレス; ガラス - シンプル 青 ライト; 金属 - アルミニウム | 非構造耐力要素 | 0 | 11353.7 | 34.061 | -0.0000219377 | -0.0000219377 | 3000 | 2 | 229203 | 2.51488 | 30091.7 | 198225 | 885.833 | 2.51488 | 0 | 0 | 0 | 0 | 0 | 0
 | 2FL | 金属-アルミニウム (228) | 避難階段 | ＜ゾーン番号＞ | no | 2FL | 2 | 金属-アルミニウム | 金属 - アルミニウム | 非構造耐力要素 | 0 | 11353.7 | 34.061 | 3000 | -0.0000106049 | 6000 | 0 | 246907 | 0 | 34507.3 | 212400 | 0 | 0 | 0 | 0 | 0 | 0 | 0 | 0
CW1 | 3FL | ガラス-青 (59), 金属-アルミニウム (178) | 事務室 | 301 | no | 3FL | 3 | 金属-アルミニウム; ガラス-青 | ガラス - シンプル 青 ライト; 金属 - アルミニウム | 未定義 | 150 | 56852.3 | 170.557 | 6000 | 0 | 9000 | 59 | 287705 | 155.989 | 136905 | 150800 | 0 | 6.1687 | 82.2535 | 6.81907 | 30.6003 | 0 | 24.7939 | 5.35313 | CW1 | CW1
 | 3FL | 金属-アルミニウム (228) | 避難階段 | ＜ゾーン番号＞ | no | 3FL | 3 | 金属-アルミニウム | 金属 - アルミニウム | 非構造耐力要素 | 0 | 11353.7 | 34.061 | 6000 | -0.0000106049 | 9000 | 0 | 246907 | 0 | 34507.3 | 212400 | 0 | 0 | 0 | 0 | 0 | 0 | 0 | 0
CW1 | 3FL | ガラス-青 (41), 金属-アルミニウム (124) | 事務室 | 313 | no | 3FL | 3 | 金属-アルミニウム; ガラス-青 | ガラス - シンプル 青 ライト; 金属 - アルミニウム | 未定義 | 150 | 38153.9 | 114.462 | 6000 | 0 | 9000 | 41 | 198108 | 104.412 | 93707.8 | 104400 | 0 | 70.0371 | 2.01447 | 2.15947 | 25.5946 | 4.60665 | 0 | 0 | CW1 | CW1
4FLCW1 | 4FL | ガラス-青 (59), 金属-アルミニウム (178) | 事務室 | 301 | yes | 4FL | 4 | 金属-アルミニウム; ガラス-青 | ガラス - シンプル 青 ライト; 金属 - アルミニウム | 未定義 | 150 | 56852.3 | 170.557 | 9000 | 0 | 12000 | 59 | 287705 | 155.989 | 136905 | 150800 | 0 | 6.1687 | 82.2535 | 6.81907 | 30.6003 | 0 | 24.7939 | 5.35313 | CW1 | 4FLCW1 | 4FL
4FL | 4FL | 金属-アルミニウム (228) | 避難階段 | ＜ゾーン番号＞ | yes | 4FL | 4 | 金属-アルミニウム | 金属 - アルミニウム | 非構造耐力要素 | 0 | 11353.7 | 34.061 | 9000 | -0.0000106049 | 12000 | 0 | 246907 | 0 | 34507.3 | 212400 | 0 | 0 | 0 | 0 | 0 | 0 | 0 | 0 |  | 4FL | 4FL
4FLCW1 | 4FL | ガラス-青 (41), 金属-アルミニウム (124) | 事務室 | 313 | yes | 4FL | 4 | 金属-アルミニウム; ガラス-青 | ガラス - シンプル 青 ライト; 金属 - アルミニウム | 未定義 | 150 | 38153.9 | 114.462 | 9000 | 0 | 12000 | 41 | 198108 | 104.412 | 93707.8 | 104400 | 0 | 70.0371 | 2.01447 | 2.15947 | 25.5946 | 4.60665 | 0 | 0 | CW1 | 4FLCW1 | 4FL
5FLCW1 | 5FL | ガラス-青 (59), 金属-アルミニウム (178) | 事務室 | 301 | yes | 5FL | 5 | 金属-アルミニウム; ガラス-青 | ガラス - シンプル 青 ライト; 金属 - アルミニウム | 未定義 | 150 | 56852.3 | 170.557 | 12000 | 0 | 15000 | 59 | 287705 | 155.989 | 136905 | 150800 | 0 | 6.1687 | 82.2535 | 6.81907 | 30.6003 | 0 | 24.7939 | 5.35313 | CW1 | 5FLCW1 | 5FL
5FL | 5FL | 金属-アルミニウム (228) | 避難階段 | ＜ゾーン番号＞ | yes | 5FL | 5 | 金属-アルミニウム | 金属 - アルミニウム | 非構造耐力要素 | 0 | 11353.7 | 34.061 | 12000 | -0.0000106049 | 15000 | 0 | 246907 | 0 | 34507.3 | 212400 | 0 | 0 | 0 | 0 | 0 | 0 | 0 | 0 |  | 5FL | 5FL
5FLCW1 | 5FL | ガラス-青 (41), 金属-アルミニウム (124) | 事務室 | 313 | yes | 5FL | 5 | 金属-アルミニウム; ガラス-青 | ガラス - シンプル 青 ライト; 金属 - アルミニウム | 未定義 | 150 | 38153.9 | 114.462 | 12000 | 0 | 15000 | 41 | 198108 | 104.412 | 93707.8 | 104400 | 0 | 70.0371 | 2.01447 | 2.15947 | 25.5946 | 4.60665 | 0 | 0 | CW1 | 5FLCW1 | 5FL
6FLCW1 | 6FL | ガラス-青 (59), 金属-アルミニウム (178) | 事務室 | 301 | yes | 6FL | 6 | 金属-アルミニウム; ガラス-青 | ガラス - シンプル 青 ライト; 金属 - アルミニウム | 未定義 | 150 | 56852.3 | 170.557 | 15000 | 0 | 18000 | 59 | 287705 | 155.989 | 136905 | 150800 | 0 | 6.1687 | 82.2535 | 6.81907 | 30.6003 | 0 | 24.7939 | 5.35313 | CW1 | 6FLCW1 | 6FL
6FL | 6FL | 金属-アルミニウム (228) | 避難階段 | ＜ゾーン番号＞ | yes | 6FL | 6 | 金属-アルミニウム | 金属 - アルミニウム | 非構造耐力要素 | 0 | 11353.7 | 34.061 | 15000 | -0.0000106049 | 18000 | 0 | 246907 | 0 | 34507.3 | 212400 | 0 | 0 | 0 | 0 | 0 | 0 | 0 | 0 |  | 6FL | 6FL
6FLCW1 | 6FL | ガラス-青 (41), 金属-アルミニウム (124) | 事務室 | 313 | yes | 6FL | 6 | 金属-アルミニウム; ガラス-青 | ガラス - シンプル 青 ライト; 金属 - アルミニウム | 未定義 | 150 | 38153.9 | 114.462 | 15000 | 0 | 18000 | 41 | 198108 | 104.412 | 93707.8 | 104400 | 0 | 70.0371 | 2.01447 | 2.15947 | 25.5946 | 4.60665 | 0 | 0 | CW1 | 6FLCW1 | 6FL
7FLCW1 | 7FL | ガラス-青 (59), 金属-アルミニウム (178) | 事務室 | 301 | yes | 7FL | 7 | 金属-アルミニウム; ガラス-青 | ガラス - シンプル 青 ライト; 金属 - アルミニウム | 未定義 | 150 | 56852.3 | 170.557 | 18000 | 0 | 21000 | 59 | 287705 | 155.989 | 136905 | 150800 | 0 | 6.1687 | 82.2535 | 6.81907 | 30.6003 | 0 | 24.7939 | 5.35313 | CW1 | 7FLCW1 | 7FL
7FL | 7FL | 金属-アルミニウム (228) | 避難階段 | ＜ゾーン番号＞ | yes | 7FL | 7 | 金属-アルミニウム | 金属 - アルミニウム | 非構造耐力要素 | 0 | 11353.7 | 34.061 | 18000 | -0.0000106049 | 21000 | 0 | 246907 | 0 | 34507.3 | 212400 | 0 | 0 | 0 | 0 | 0 | 0 | 0 | 0 |  | 7FL | 7FL
7FLCW1 | 7FL | ガラス-青 (41), 金属-アルミニウム (124) | 事務室 | 313 | yes | 7FL | 7 | 金属-アルミニウム; ガラス-青 | ガラス - シンプル 青 ライト; 金属 - アルミニウム | 未定義 | 150 | 38153.9 | 114.462 | 18000 | 0 | 21000 | 41 | 198108 | 104.412 | 93707.8 | 104400 | 0 | 70.0371 | 2.01447 | 2.15947 | 25.5946 | 4.60665 | 0 | 0 | CW1 | 7FLCW1 | 7FL
8FLCW1 | 8FL | ガラス-青 (59), 金属-アルミニウム (178) | 事務室 | 301 | yes | 8FL | 8 | 金属-アルミニウム; ガラス-青 | ガラス - シンプル 青 ライト; 金属 - アルミニウム | 未定義 | 150 | 56852.3 | 170.557 | 21000 | 0 | 24000 | 59 | 287705 | 155.989 | 136905 | 150800 | 0 | 6.1687 | 82.2535 | 6.81907 | 30.6003 | 0 | 24.7939 | 5.35313 | CW1 | 8FLCW1 | 8FL
8FL | 8FL | 金属-アルミニウム (228) | 避難階段 | ＜ゾーン番号＞ | yes | 8FL | 8 | 金属-アルミニウム | 金属 - アルミニウム | 非構造耐力要素 | 0 | 11353.7 | 34.061 | 21000 | -0.0000106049 | 24000 | 0 | 246907 | 0 | 34507.3 | 212400 | 0 | 0 | 0 | 0 | 0 | 0 | 0 | 0 |  | 8FL | 8FL
8FLCW1 | 8FL | ガラス-青 (41), 金属-アルミニウム (124) | 事務室 | 313 | yes | 8FL | 8 | 金属-アルミニウム; ガラス-青 | ガラス - シンプル 青 ライト; 金属 - アルミニウム | 未定義 | 150 | 38153.9 | 114.462 | 21000 | 0 | 24000 | 41 | 198108 | 104.412 | 93707.8 | 104400 | 0 | 70.0371 | 2.01447 | 2.15947 | 25.5946 | 4.60665 | 0 | 0 | CW1 | 8FLCW1 | 8FL
9FLCW1 | 9FL | ガラス-青 (59), 金属-アルミニウム (178) | 事務室 | 301 | yes | 9FL | 9 | 金属-アルミニウム; ガラス-青 | ガラス - シンプル 青 ライト; 金属 - アルミニウム | 未定義 | 150 | 56852.3 | 170.557 | 24000 | 0 | 27000 | 59 | 287705 | 155.989 | 136905 | 150800 | 0 | 6.1687 | 82.2535 | 6.81907 | 30.6003 | 0 | 24.7939 | 5.35313 | CW1 | 9FLCW1 | 9FL
9FL | 9FL | 金属-アルミニウム (228) | 避難階段 | ＜ゾーン番号＞ | yes | 9FL | 9 | 金属-アルミニウム | 金属 - アルミニウム | 非構造耐力要素 | 0 | 11353.7 | 34.061 | 24000 | -0.0000106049 | 27000 | 0 | 246907 | 0 | 34507.3 | 212400 | 0 | 0 | 0 | 0 | 0 | 0 | 0 | 0 |  | 9FL | 9FL
9FLCW1 | 9FL | ガラス-青 (41), 金属-アルミニウム (124) | 事務室 | 313 | yes | 9FL | 9 | 金属-アルミニウム; ガラス-青 | ガラス - シンプル 青 ライト; 金属 - アルミニウム | 未定義 | 150 | 38153.9 | 114.462 | 24000 | 0 | 27000 | 41 | 198108 | 104.412 | 93707.8 | 104400 | 0 | 70.0371 | 2.01447 | 2.15947 | 25.5946 | 4.60665 | 0 | 0 | CW1 | 9FLCW1 | 9FL

# IfcDoor: EVドア_小枠タイプ (27)
Type - ParameterTakesPrecedence: no; Sizeable: no
OverallHeight: 2225 mm; OverallWidth: 1340 mm; Classification: ドア (ARCHICAD 分類)
ArchiCADProperties - 要素ID: SD5; レイヤー: 壁-躯体; ライブラリ部品名: EVドア_小枠タイプ; ビルディングマテリアル/複合構造/断面形状/塗りつぶし: 背景; 塗りつぶし種類: 背景; 関連ゾーン名: EVホール; 関連ゾーン番号: ＜ゾーン番号＞; 要素タイプ: ドア; 親ID: W6; 材質 (全て): 金属 - ステンレス; ガラス - シンプル; ゾーンから: EVシャフト; ゾーン番号から: ＜ゾーン番号＞; ゾーンへ: EVホール; ゾーン番号へ: ＜ゾーン番号＞; リノベーションフィルタで表示: 全ての関連フィルタ; 構造機能: 非構造耐力要素; 位置: インテリア; リノベーションステータス: 既存; 抱き寸法: 1,000.0×2,100.0; 壁開口寸法: 1,340.0×2,225.0; ユニット寸法: 1,000.0×2,100.0; 間口寸法: 1,000.0×2,100.0; 扉寸法: 1,000.0×2,100.0; 公称幅x高さ: 1,000.0×2,100.0; 公称幅x高さx厚さ: 1,000.0×2,100.0×150.0; 壁構造: コンクリート; 方向: 左; 開口部 ライブラリ部品名: EVドア_小枠タイプ; 開口部 側面塗りつぶし索引: 背景; ARCHICAD 分類 - v 2.0: ドア
AC_Pset_EVドア_小枠タイプ - 壁輪郭(0-なし,1-全て,2-側面,3-長さ): 0; ホットスポット(0-なし,1-2D,2-3D,3-全て): 3; 2Dホットスポットを3Dで表示: yes; 開口に壁側の材質を使用: no; 開口の側面を曲線壁に沿う: no; 抱き配置位置: 1; 下枠非表示オプション: 2; 開口角度2D: 90 deg; 開口角度3D: 0 deg; 窓枠材質: 木材 - マツ 木目 横; パネル材質: 木材 - マツ 木目 横; 公称サイズ: 2; 内寸を公称サイズに設定: yes; 壁開口を公称サイズに設定: no; 現在の公称サイズを選択に切り替え: no; 詳細レベル: 1; 詳細: 1; 詳細表現スケールn (1/1 - 1/n): 50; 中間表現スケールm （1/n～1/m): 100; 2D 表示 (iViewtype_2D): 1; 断面表示: 1; 2D建具背面の無地塗つぶし: no; 額縁表現: 1; 2D額縁塗りつぶし: 砂利; 曲線壁の開口部でホットスポットを表示: no; 建具種類: ED; 建具番号: 1; 法規制: 未定; 内外区分: 外; 形式: EVドア_小枠タイプ; 建具識別コード（0=窓,1=ドア,2=シャッター,3=エレベーター): 3; 壁ID: W6; 接続されたゾーンを値として使用: no; IFC操作 (ifc_optypestr): 未定義; IFC操作 (ifc_optype): 0; キープラン表示: yes; マーカータイプをスケールに連動: yes; マーカータイプ: タイプ1; 枝番(0=なし): 0; 建具サイズ表示: no; 建具符号方向: 任意角度; 建具符号任意角度: 0 deg; 用紙スケール: no; マーカーサイズ (用紙) (k_dia_paper): 4.2; マーカーサイズ (用紙) (k_dia_M): 0.0042; 引き出し線角度: 0 deg; 建具下端レベルは壁を基準とする: yes; 離れX (用紙) (k_lenb_paper): 0; 離れX (用紙) (k_lenb_M): 0; 離れY (用紙) (k_lena_paper): 10; 離れY (用紙) (k_lena_M): 0.01; 離れオフセット (用紙) (k_lenc_paper): 0; 離れオフセット (用紙) (k_lenc_M): 0; 引出し線: no; ID表示: no; 線種: 1; 建具記号で塗りつぶしを使用: no; 建具記号塗りつぶし種類: 背景; フォント: Meiryo UI 日本語; 字サイズユーザー設定: no; 字サイズ: 1.4; 追記文字サイズ (mm): 1.43; 建具文字サイズ (mm): 1.43; 建具番号-枝番: 1; 追記位置X1 (用紙) (n_offx1_paper): -11; 追記位置X1 (用紙) (n_offx1_M): -0.011; 追記位置Y1 (用紙) (n_offy1_paper): 2.5; 追記位置Y1 (用紙) (n_offy1_M): 0.0025; 追記位置X2 (用紙) (n_offx2_paper): -11; 追記位置X2 (用紙) (n_offx2_M): -0.011; 追記位置Y2 (用紙) (n_offy2_paper): -2.5; 追記位置Y2 (用紙) (n_offy2_M): -0.0025; 追記位置X3 (用紙) (n_offx3_paper): 11; 追記位置X3 (用紙) (n_offx3_M): 0.011; 追記位置Y3 (用紙) (n_offy3_paper): 2.5; 追記位置Y3 (用紙) (n_offy3_M): 0.0025; 追記位置X4 (用紙) (n_offx4_paper): 11; 追記位置X4 (用紙) (n_offx4_M): 0.011; 追記位置Y4 (用紙) (n_offy4_paper): -2.5; 追記位置Y4 (用紙) (n_offy4_M): -0.0025; サイズ表示位置X (用紙) (size_anno_x_paper): 5; サイズ表示位置X (用紙) (size_anno_x_M): 0.005; サイズ表示位置Y (用紙) (size_anno_y_paper): 0; サイズ表示位置Y (用紙) (size_anno_y_M): 0; 法規制マーカー: yes; マーカーサイズ (用紙) (r_dia_paper): 2; マーカーサイズ (用紙) (r_dia_M): 0.002; マーカー塗りつぶしあり/なし: no; マーカー塗りつぶし背景ペン: 透過; マーカー塗りつぶし: 25 %; 建具表平面表示: no; 離れX (用紙) (r_lenb_paper): 0; 離れX (用紙) (r_lenb_M): 0; 離れY (用紙) (r_lena_paper): -5; 離れX (用紙) (r_lena_M): -0.005; 壁断面形状: 1; 傾斜壁角度１: 90 deg; 傾斜壁角度２: 90 deg; ドアタイプ (stDp_Style): 窓付き; ガラス表現: yes; 平面図開口線: no; 平面図中心線: no; 枠材質: 金属 - ステンレス; ドア材質: 金属 - ステンレス; ガラス材質: ガラス - シンプル; 気密: 未定; 遮音: 未定; 枠 材質: 未定; 枠 仕上: 未定; 沓摺 材質: 未定; 沓摺 仕上: 未定; ドアタイプ (stPanel_Type): 未定; 扉 材質: 未定; 扉 仕上: 未定; 無目 種類: スチールパネル; ガラス 種類: 未定; ガラス 厚: 未定; ガラリ 形状: 未定; ガラリ 機構: 未定; ガラリ 材質: 未定; ガラリ 仕上: 未定; ロックセット: 未定; 握り玉/取手: 未定; ヒンジ: 未定; クローザー: 未定; 戸当り: 未定; フランス落し: 未定; 順位調整器: 未定; チェーンロック: 未定; ドアアイ: 未定; ポスト: 未定; 価格: 0; 2Dシンボル表示のMVOを上書き: no; ドア3D投影のMVOを上書き: no; 平面図中心線種: 1; 並べ替え用通し番号: 0
採光計算 - 窓から隣地境界線までの距離: 4
排煙・換気計算 - 天井面の高さ: 0; 有効開口幅: 0; 開き角度: 0; 天井面より80cm以内の距離: 0.8; 窓の上端高さから天井面までの距離: -1.975; 排煙有効開口面積(引違い・片引き等): 0; 有効排煙開口率: 0; 排煙有効開口面積(横軸・外倒し・内倒し等): 0
AC_Pset_RenovationAndPhasing - Renovation Status: Existing
Pset_DoorCommon - IsExternal: no
BaseQuantities - Height: 2130 mm; Width: 1060 mm; Perimeter: 6380 mm; Area: 2.2578 m2; Volume: 0.02961 m3; Depth: 150 mm; NetVolume: 0.02961 m3
ArchiCADQuantities - 高さ: 2100 mm; 正味体積: 0.02961 m3; 幅: 1000 mm; リンク/配置フロアまでの高度: 0 mm; 下部オフセット: 0 mm; 表面積: 5.4148 m2; 上端高度から配置フロア: 2300 mm; 下端高度から配置フロア: -50 mm; 窓/ドア開口 開口部体積: 0.33867 m3; 窓/ドア開口部公称体積: 0.315 m3; 窓/ドア開口 表面積: 5.4148 m2; 窓/ドア開口面積: 2.1 m2; 窓/ドア外壁側開口部幅: 1060 mm; 窓/ドア外壁側開口部高さ: 2130 mm; 窓/ドア外壁反対側開口部幅: 1060 mm; 窓/ドア外壁反対側開口部高さ: 2130 mm; 窓/ドア外壁側開口部面積: 2.2578 m2; 窓/ドア外壁反対側開口部面積: 2.2578 m2; 窓/ドア外壁側公称開口部幅: 1340 mm; 窓/ドア外壁側公称開口部高さ: 2225 mm; 窓/ドア外壁反対側公称開口部幅: 1340 mm; 窓/ドア外壁反対側公称開口部高さ: 2225 mm; 窓/ドア抱き側開口面積: 2.9815 m2; 窓/ドア抱き反対側開口面積: 2.9815 m2; 下端/上端値: 0 mm; 窓/ドア公称下端高さ: 0 mm; 窓/ドア外壁側下端高さ: 0 mm; 窓/ドア外壁反対側下端高さ: 0 mm; 窓/ドア公称上端高さ: 2100 mm; 窓/ドア外壁側上端高さ: 1975 mm; 窓/ドア外壁反対側上端高さ: 1975 mm; 壁厚さ: 150 mm; 枠厚さ: 100 mm
AC_Equantity_EVドア_小枠タイプ - 下部レベル: 1000 mm; 上部レベル: 0 mm; 壁躯体に抱き: 0 mm; 窓枠の厚さ: 100 mm; 窓枠の幅: 50 mm; パネルの厚さ: 40 mm; AC 左開口部オーバーサイズ: 230 mm; AC 右開口部オーバーサイズ: 110 mm; AC 上開口部オーバーサイズ: 125 mm; AC 下開口部オーバーサイズ: 0 mm; 壁開口幅: 1340 mm; 壁開口高さ: 2225 mm; 抱き幅: 1000 mm; 抱き高さ: 2100 mm; ユニット幅: 1000 mm; ユニット高さ: 2100 mm; 有効開口幅: 1000 mm; 有効開口高さ: 2100 mm; 開口幅 (gs_opening_width): 1000 mm; 開口部高さ: 2100 mm; 枠内幅: 1000 mm; 枠内高さ: 2100 mm; 開口幅 (ac_egress_width): 1000 mm; 開口高さ: 2100 mm; 可動部の幅: 1000 mm; パネル高さ: 2100 mm; マーカーサイズ (k_dia): 420 mm; 壁下端レベル: 0 mm; 離れX (k_lenb): 0 mm; 離れY (k_lena): 1000 mm; 離れオフセット: 0 mm; 追記位置X1: -700 mm; 追記位置Y1: 250 mm; 追記位置X2: -700 mm; 追記位置Y2: -250 mm; 追記位置X3: 700 mm; 追記位置Y3: 250 mm; 追記位置X4: 700 mm; 追記位置Y4: -250 mm; サイズ表示位置X: 500 mm; サイズ表示位置Y: 0 mm; マーカーサイズ (r_dia): 200 mm; 床とFLのレベル差: 0 mm; 離れX (r_lenb): 0 mm; 離れY (r_lena): -500 mm; フロアレベルから建具下端までの高さ: 0 mm; 欠込深さ: 150 mm; 欠込傾斜幅: 40 mm; 枠-見付(左): 10 mm; 枠-見付(右): 130 mm; 枠-見付(上): 25 mm; 枠見付（中間表示）: 30 mm; 枠-傾斜幅(左): 0 mm; 枠-傾斜幅(右): 0 mm; 枠-見込: 50 mm; 枠-ちり(内側): 10 mm; 枠-ちり(カゴ側): 20 mm; 逃げ-左: 100 mm; 逃げ-右: 100 mm; 逃げ-上: 100 mm; ドア厚: 40 mm; 窓幅: 200 mm; 窓高さ: 700 mm; 窓下端位置: 1100 mm; 幕板高さ(0=なし): 0 mm; 膳板段鼻: 10 mm; ドアレール幅: 90 mm; ドアレール厚さ-上: 150 mm; ドアレール厚さ-下: 50 mm; ドアレール長さ-右: 1000 mm; ドアレール長さ-左: 1000 mm; 開口側面幅1: 100 mm; 開口側面幅2: 0 mm; 開口側面奥行き: 1200 mm; 反対側側面幅1: 100 mm; 反対側側面幅2: 0 mm; 反対側側面奥行き: 50 mm; 反対側側面幅: 1100 mm; 外側仕上げ厚 (ex_finish_thickness): 0 mm; 外側仕上げ厚 (ex_cover_thickness): 0 mm; 内側仕上げ厚: 0 mm; 錠位置X: -500 mm; 錠位置Y: 0 mm; 中心からの距離: 100 mm; 抱き奥行き: 0 mm
Name | In | ホットリンクおよび要素ID | ロック状態 | ホームフロア名 | ホームフロア数 | GLからの高度 (mm) = 高度 1 (mm) = 高度 2 (mm) = 海抜までの高度 (mm) | 上端高度から第1基準レベル (mm) = 上端高度から基準レベル (mm) = 上端高度から海抜 (mm) = 上端高度から第2基準レベル (mm) | 下端高度から第1基準レベル (mm) = 下端高度から基準レベル (mm) = 下端高度から海抜 (mm) = 下端高度から第2基準レベル (mm) | 窓の中心高さ (mm) | ホットリンク マスタID
3 x SD5 | 1FL | SD5 | no | 1FL | 1 | 0 | 2300 | -50 | 1.05
3 x SD5 | 2FL | SD5 | no | 2FL | 2 | 3000 | 5300 | 2950 | 4.05
3 x SD5 | 3FL | SD5 | no | 3FL | 3 | 6000 | 8300 | 5950 | 7.05
3 x 4FLSD5 | 4FL | 4FLSD5 | yes | 4FL | 4 | 9000 | 11300 | 8950 | 10.05 | 4FL
3 x 5FLSD5 | 5FL | 5FLSD5 | yes | 5FL | 5 | 12000 | 14300 | 11950 | 13.05 | 5FL
3 x 6FLSD5 | 6FL | 6FLSD5 | yes | 6FL | 6 | 15000 | 17300 | 14950 | 16.05 | 6FL
3 x 7FLSD5 | 7FL | 7FLSD5 | yes | 7FL | 7 | 18000 | 20300 | 17950 | 19.05 | 7FL
3 x 8FLSD5 | 8FL | 8FLSD5 | yes | 8FL | 8 | 21000 | 23300 | 20950 | 22.05 | 8FL
3 x 9FLSD5 | 9FL | 9FLSD5 | yes | 9FL | 9 | 24000 | 26300 | 23950 | 25.05 | 9FL

# IfcDoor: 両引き分戸2 (4)
In: 1FL
Type - ParameterTakesPrecedence: no; Sizeable: no
Classification: ドア (ARCHICAD 分類)
ArchiCADProperties - レイヤー: 壁-躯体; ライブラリ部品名: 両引き分戸2; ビルディングマテリアル/複合構造/断面形状/塗りつぶし: 背景; 塗りつぶし種類: 背景; 関連ゾーン番号: ＜ゾーン番号＞; ロック状態: no; ホームフロア名: 1FL; ホームフロア数: 1; 要素タイプ: ドア; 材質 (全て): ガラス - シンプル; ペイント - サンドベージュ; リノベーションフィルタで表示: 全ての関連フィルタ; 構造機能: 非構造耐力要素; リノベーションステータス: 既存; 壁構造: コンクリート; 開口部 ライブラリ部品名: 両引き分戸2; 開口部 側面塗りつぶし索引: 背景; ARCHICAD 分類 - v 2.0: ドア
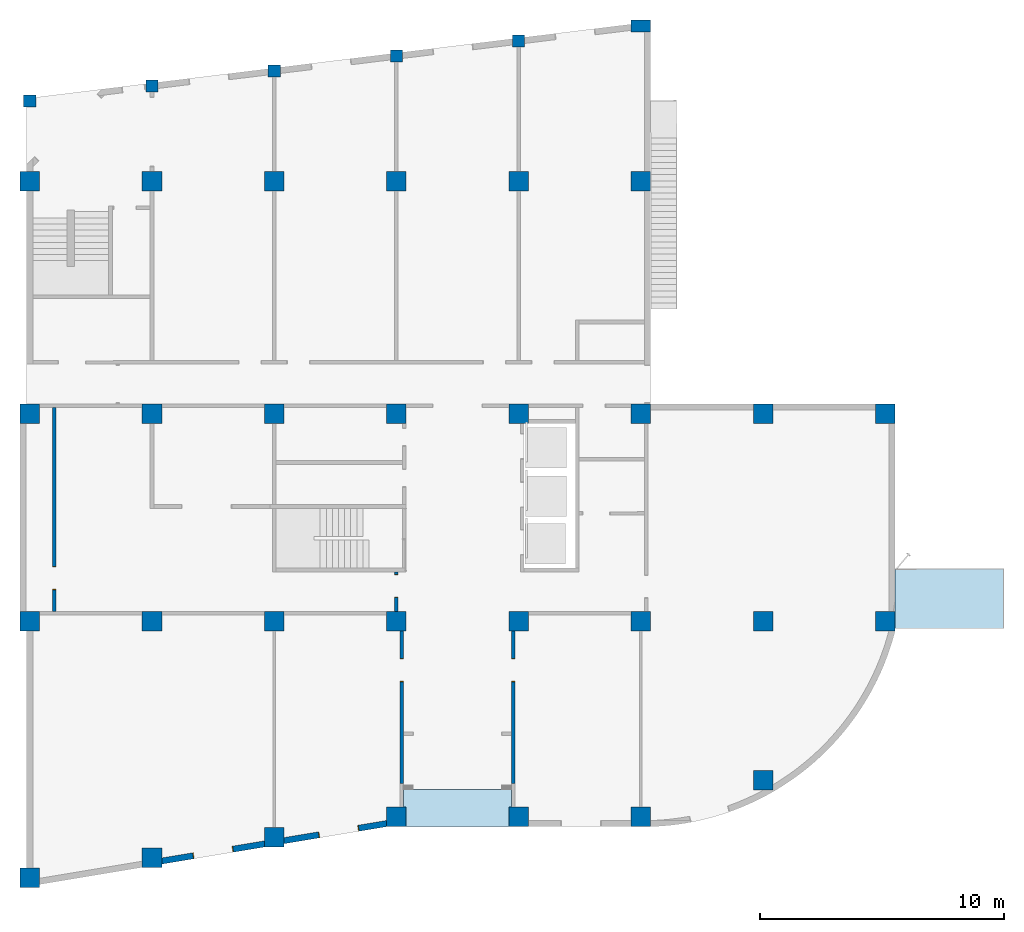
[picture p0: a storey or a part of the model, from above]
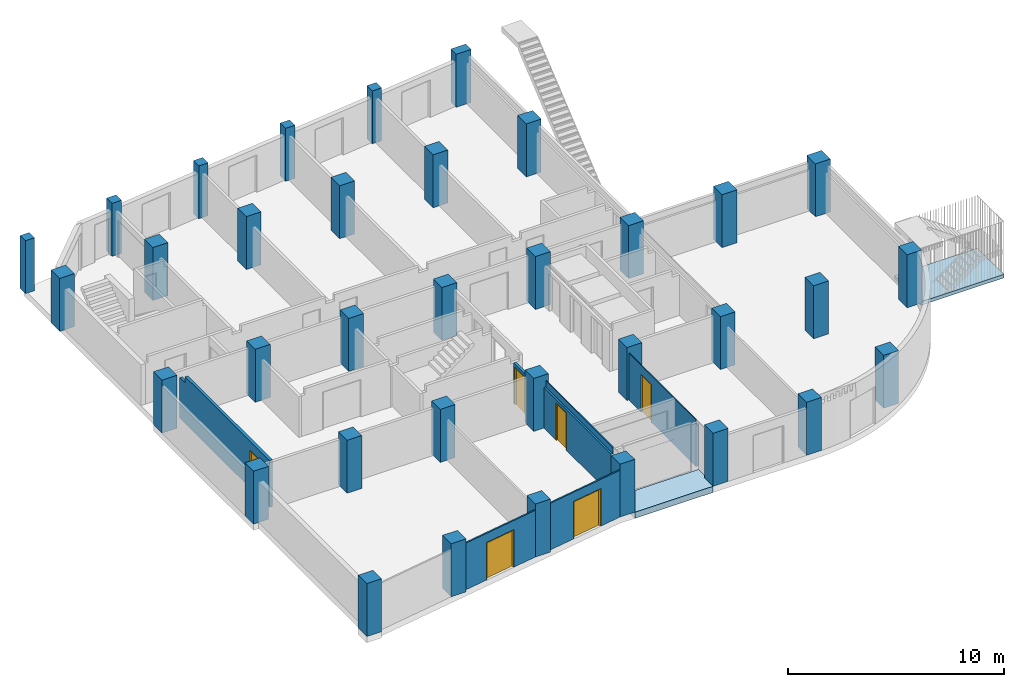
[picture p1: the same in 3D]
Properties of the parts of a building model (IFC2X3), part 5 of 10

# IfcDoor: 両引き分戸2 (4)
AC_Pset_両引き分戸2 - 壁輪郭(0-なし,1-全て,2-側面,3-長さ): 0; ホットスポット(0-なし,1-2D,2-3D,3-全て): 3; 2Dホットスポットを3Dで表示: yes; 開口部は壁側面の材質: no; 開口の側面を曲線壁に沿う: no; 抱き配置位置: 1; 開口角度2D: 90 deg; 開口角度3D: 0 deg; 枠材質 (gs_frame_mat): 木材 - マツ 木目 横; パネル材質: 木材 - マツ 木目 横; 公称サイズ: 2; 有効開口を公称サイズに設定: no; 枠内を公称サイズに設定: no; 壁開口を公称サイズに設定: no; 内寸を公称サイズに設定: yes; 現在の公称サイズを選択に切り替え: no; 詳細レベル: 1; 詳細: 1; 詳細表現スケールn (1/1 - 1/n): 50; 中間表現スケールm （1/n～1/m): 100; 2D 表示 (iViewtype_2D): 1; 断面表示: 1; 2D建具背面の無地塗つぶし: no; 額縁表現: 2; 2D額縁塗りつぶし: 木材1; 曲線壁の開口部でホットスポットを表示: no; ドア沓摺線 2D: no; 建具種類: SD; 建具番号: 1; 法規制: 未定; 内外区分: 内; 形式: 引分け戸; 建具識別コード（0=窓,1=ドア,2=シャッター,3=エレベーター): 1; 接続されたゾーンを値として使用: no; IFC操作 (ifc_optypestr): 未定義; IFC操作 (ifc_optype): 0; キープラン表示: yes; マーカータイプをスケールに連動: yes; マーカータイプ: タイプ1; 枝番(0=なし): 0; 建具サイズ表示: no; 建具符号方向: 任意角度; 建具符号任意角度: 0 deg; 用紙スケール: no; マーカーサイズ (用紙) (k_dia_paper): 4.2; マーカーサイズ (用紙) (k_dia_M): 0.0042; 離れX (用紙) (k_lenb_paper): 0; 離れX (用紙) (k_lenb_M): 0; 離れY (用紙) (k_lena_paper): 10; 離れY (用紙) (k_lena_M): 0.01; 離れオフセット (用紙) (k_lenc_paper): 0; 離れオフセット (用紙) (k_lenc_M): 0; 引き出し線角度: 0 deg; 引き出し線: no; ID表示: no; 線種: 1; 建具記号で塗りつぶしを使用: no; 建具記号塗りつぶし種類: 背景; フォント: Meiryo UI 日本語; 字サイズユーザー設定: no; 字サイズ: 1.4; 追記文字サイズ (mm): 1.43; 建具文字サイズ (mm): 1.43; 建具番号-枝番: 1; 追記位置X1 (用紙) (n_offx1_paper): -11; 追記位置X1 (用紙) (n_offx1_M): -0.011; 追記位置Y1 (用紙) (n_offy1_paper): 2.5; 追記位置Y1 (用紙) (n_offy1_M): 0.0025; 追記位置X2 (用紙) (n_offx2_paper): -11; 追記位置X2 (用紙) (n_offx2_M): -0.011; 追記位置Y2 (用紙) (n_offy2_paper): -2.5; 追記位置Y2 (用紙) (n_offy2_M): -0.0025; 追記位置X3 (用紙) (n_offx3_paper): 11; 追記位置X3 (用紙) (n_offx3_M): 0.011; 追記位置Y3 (用紙) (n_offy3_paper): 2.5; 追記位置Y3 (用紙) (n_offy3_M): 0.0025; 追記位置X4 (用紙) (n_offx4_paper): 11; 追記位置X4 (用紙) (n_offx4_M): 0.011; 追記位置Y4 (用紙) (n_offy4_paper): -2.5; 追記位置Y4 (用紙) (n_offy4_M): -0.0025; サイズ表示位置X (用紙) (size_anno_x_paper): 5; サイズ表示位置X (用紙) (size_anno_x_M): 0.005; サイズ表示位置Y (用紙) (size_anno_y_paper): 0; サイズ表示位置Y (用紙) (size_anno_y_M): 0; 法規制マーカー: yes; マーカーサイズ (用紙) (r_dia_paper): 2; マーカーサイズ (用紙) (r_dia_M): 0.002; マーカー塗りつぶしあり/なし: no; マーカー塗りつぶし背景ペン: 透過; マーカー塗りつぶし: 25 %; 建具下端レベルは壁を基準とする: no; 建具表平面表示: no; 離れX (用紙) (r_lenb_paper): 0; 離れX (用紙) (r_lenb_M): 0; 離れY (用紙) (r_lena_paper): -5; 離れY (用紙) (r_lena_M): -0.005; MO API ドアコード: 5; 抱き形状: 1; 横枠形状 (ui_shape2D): 3; 下枠非表示オプション: 2; 横枠形状 (d_s_s): 3; 上枠形状: 3; 壁断面形状: 1; 傾斜壁角度１: 90 deg; 傾斜壁角度２: 90 deg; 扉スタイル (stPanel_Style): 強化ガラスＡ; 扉スタイル (iPanel_Style): 14; ハンドル表記: なし; ガラスの水平分割数: 7; ガラスの垂直分割数: 4; 欄間ガラスの水平分割数: 3; FIX幅設定: no; 自動ドアエンジン: no; 欄間スタイル1: サイドパネル; 欄間スタイル2: サイドパネル; 欄間スタイル3: サイドパネル; 欄間スタイル4: サイドパネル; 無目 種類 (middle_bar_type): 3; 沓摺 形状: 4; 3Dでの扉の開口率(%): 0; 3Dでの開口線: no; 3D開口テキスト: no; 平面図開口線: no; 3Dでのガラス表現: no; 2Dでの開口線の線種: 28; 平面図中心線: no; 枠材質 (matframe): ペイント - サンドベージュ; 沓摺材質: ペイント - サンドベージュ; ドア材質: ペイント - サンドベージュ; ドア内部材質にリンク: yes; 内部ドア材質: ペイント - サンドベージュ; ルーバー材質: 金属 - アルミニウム; ガラス材質: ガラス - シンプル; 取っ手材質: 金属 - ステンレス; 紙材質: 木材 - マツ 木目 横; 幕板材質: ペイント - サンドベージュ; 気密: 未定; 遮音: 未定; 枠 材質: 未定; 枠 仕上: 未定; 沓摺 材質: 未定; 沓摺 仕上: 未定; ドアタイプ: 未定; 扉 材質: 未定; 扉 仕上: 未定; 無目 種類 (stTransom_Glasstype): 未定; ガラス 種類: 未定; ガラス 厚: 未定; ガラリ 形状: 未定; ガラリ 機構: 未定; ガラリ 材質: 未定; ガラリ 仕上: 未定; ロックセット: 未定; 握玉: 未定; ヒンジ: 未定; クローザー: 未定; 戸当り: 未定; フランス落し: 未定; 順位調整器: 未定; チェーンロック: 未定; ドアアイ: 未定; ポスト: 未定; 価格: 0; 平面図中心線種: 1; 外側層の延長: no; 内側層の延長: no; 延長線種: 1; 延長する内側層の数: 0; 延長する外側層の数: 0; 2Dシンボル表示のMVOを上書き: no; ドア3D投影のMVOを上書き: no; 3D開口線 側面: 3; 3Dガラスシンボル 側面: 3; 並べ替え用通し番号: 0
採光計算 - 窓から隣地境界線までの距離: 4
排煙・換気計算 - 天井面の高さ: 0; 有効開口幅: 0; 開き角度: 0; 天井面より80cm以内の距離: 0.8; 排煙有効開口面積(引違い・片引き等): 0; 有効排煙開口率: 0; 排煙有効開口面積(横軸・外倒し・内倒し等): 0
AC_Pset_RenovationAndPhasing - Renovation Status: Existing
ArchiCADQuantities - GLからの高度: 0 mm; 高度 1: 0 mm; 高度 2: 0 mm; 海抜までの高度: 0 mm; リンク/配置フロアまでの高度: 0 mm; 下部オフセット: 0 mm; 下端/上端値: 0 mm; 窓/ドア公称下端高さ: 0 mm; 窓/ドア外壁側下端高さ: 0 mm; 窓/ドア外壁反対側下端高さ: 0 mm; 枠厚さ: 100 mm
AC_Equantity_両引き分戸2 - 下部レベル: 1000 mm; 上部レベル: 0 mm; 壁躯体に抱き: -10 mm; 枠見込 (gs_frame_thk): 100 mm; 枠見付: 50 mm; 扉厚さ (gs_leaf_thk): 40 mm; AC左開口部拡張サイズ: 50 mm; AC右開口部拡張サイズ: 50 mm; AC上開口部拡張サイズ: 50 mm; 有効開口高さ: 2100 mm; 下部オフセット: 0 mm; AC下開口部拡張サイズ: 0 mm; マーカーサイズ (k_dia): 420 mm; 離れX (k_lenb): 0 mm; 離れY (k_lena): 1000 mm; 離れオフセット: 0 mm; 追記位置X1: -700 mm; 追記位置Y1: 250 mm; 追記位置X2: -700 mm; 追記位置Y2: -250 mm; 追記位置X3: 700 mm; 追記位置Y3: 250 mm; 追記位置X4: 700 mm; 追記位置Y4: -250 mm; サイズ表示位置X: 500 mm; サイズ表示位置Y: 0 mm; マーカーサイズ (r_dia): 200 mm; 床とFLのレベル差: 0 mm; 壁下端レベル: 0 mm; 離れX (r_lenb): 0 mm; 離れY (r_lena): -500 mm; フロアレベルから建具下端までの高さ: 0 mm; 中間壁までの距離: 0 mm; 外壁までの距離: 0 mm; 開口側面奥行き: 800 mm; 反対側側面奥行き: 800 mm; 反対側側面幅: 3800 mm; 枠見付（縦）: 25 mm; 上枠見付: 25 mm; 枠見付（中間表示）: 30 mm; 扉厚さ (p2): 20 mm; ちり１: 10 mm; ちり２: 10 mm; 逃げ（横）: 50 mm; 逃げ-上: 50 mm; ハンドル取付位置（端から）: 70 mm; ハンドル取付位置（高さ）: 1000 mm; パネル内開口幅: 150 mm; パネル内開口高さ（上）: 800 mm; パネル内開口高さ（下）: 500 mm; パネル端との距離: 150 mm; パネル下端との距離: 150 mm; パネル上端との距離: 150 mm; スリット窓ガラリ間隔: 200 mm; 枠幅(左右): 50 mm; 枠見付（上）: 50 mm; 枠見付（下）: 150 mm; 枠見込 (fix_dt): 20 mm; エンジンボックス高さ: 300 mm; エンジンボックス奥行き: 220 mm; 欄間方立見付: 50 mm; 欄間方立見込: 100 mm; 外側仕上げ厚: 0 mm; 内側仕上げ厚: 0 mm; 内部１層目仕上げ厚: 0 mm; 錠位置X: -500 mm; 錠位置Y: 0 mm; 中心からの距離: 100 mm; 抱き奥行き: -10 mm; 扉カバー幅: 50 mm; 引き残し: 0 mm
Name | OverallHeight (mm) = 窓/ドア外壁側公称開口部高さ (mm) = 窓/ドア外壁反対側公称開口部高さ (mm) = 壁開口高さ (mm) | OverallWidth (mm) = 窓/ドア外壁側公称開口部幅 (mm) = 窓/ドア外壁反対側公称開口部幅 (mm) = 壁開口幅 (mm) | 要素ID = ホットリンクおよび要素ID | 関連ゾーン名 | 親ID = 壁ID | ゾーンから | ゾーン番号から | ゾーンへ | ゾーン番号へ | 位置 | 抱き寸法 = ユニット寸法 = 間口寸法 = 扉寸法 = 公称幅x高さ | 壁開口寸法 | 公称幅x高さx厚さ | 方向 | 欄間分割数 | 窓の上端高さから天井面までの距離 | IsExternal | Height (mm) = 上端高度から第1基準レベル (mm) = 上端高度から配置フロア (mm) = 上端高度から基準レベル (mm) = 上端高度から海抜 (mm) = 上端高度から第2基準レベル (mm) = 窓/ドア外壁側開口部高さ (mm) = 窓/ドア外壁反対側開口部高さ (mm) | Width (mm) = 窓/ドア外壁側開口部幅 (mm) = 窓/ドア外壁反対側開口部幅 (mm) | Perimeter (mm) | Area (m2) = 窓/ドア外壁側開口部面積 (m2) = 窓/ドア外壁反対側開口部面積 (m2) | Volume (m3) = NetVolume (m3) = 正味体積 (m3) | Depth (mm) = 壁厚さ (mm) | 高さ (mm) = 窓/ドア公称上端高さ (mm) = 枠内高さ (mm) = 抱き高さ (mm) = ユニット高さ (mm) = 開口高さ (ac_egress_height) (mm) = 開口高さ (gs_opening_height) (mm) = パネル高さ (mm) | 幅 (mm) = 枠内幅 (mm) = 抱き幅 (mm) = ユニット幅 (mm) = 開口幅 (ac_egress_width) (mm) = 開口幅 (gs_opening_width) (mm) = 可動部の幅 (mm) | 表面積 (m2) = 窓/ドア開口 表面積 (m2) | 下端高度から第1基準レベル (mm) = 下端高度から配置フロア (mm) = 下端高度から基準レベル (mm) = 下端高度から海抜 (mm) = 下端高度から第2基準レベル (mm) | 窓/ドア開口 開口部体積 (m3) | 窓/ドア開口部公称体積 (m3) | 窓/ドア開口面積 (m2) | 窓/ドア抱き側開口面積 (m2) = 窓/ドア抱き反対側開口面積 (m2) | 窓/ドア外壁側上端高さ (mm) = 窓/ドア外壁反対側上端高さ (mm) | 有効開口幅 (mm) | 開口側面幅1 (mm) = 開口側面幅2 (mm) = 反対側側面幅1 (mm) = 反対側側面幅2 (mm) | 枠見込 (p3) (mm) | FIX部左幅 (mm) = FIX部右幅 (mm) | 無目見付（0＝欄間なし） (mm) | 欄間幅1 (mm) | 欄間幅2 (mm) | 欄間幅3 (mm) | 欄間幅4 (mm) | 無目見込 (mm) | 無目見付 (mm) | 窓の中心高さ (mm)
SD2 | 2150 | 3700 | SD2 | 玄関ホール | W6 | 風除室 | ＜ゾーン番号＞ | 玄関ホール | ＜ゾーン番号＞ | インテリア | 3,600.0×2,100.0 | 3,700.0×2,150.0 | 3,600.0×2,100.0×150.0 | 右 | 1 | -2.05 | no | 2130 | 3660 | 11580 | 7.7958 | 0 | 150 | 2100 | 3600 | 10.6086 | -9.18485e-15 | 1.16937 | 1.134 | 7.56 | 7.955 | 2050 | 1750 | 100 | 170 | 925 | 0 | 992.5 | 732.5 | 732.5 | 992.5 | 0 | 0 | 1.05
SD1 | 2750 | 3700 | SD1 | 風除室 | W6 |  |  | 風除室 | ＜ゾーン番号＞ | エクステリア | 3,600.0×2,700.0 | 3,700.0×2,750.0 | 3,600.0×2,700.0×150.0 | 右 | 2 | -2.65 | yes | 2730 | 3660 | 12780 | 9.9918 | 0.0000025 | 150 | 2700 | 3600 | 13.2257 | -9.18485e-15 | 1.49877 | 1.458 | 9.72 | 10.175 | 2650 | 1750 | 100 | 170 | 925 | 500 | 1775 | 1775 | 0 | 0 | 170 | 100 | 1.35
SD1 | 2150 | 3700 | SD1 | ホール | W8 | ホール | ＜ゾーン番号＞ |  |  | エクステリア | 3,600.0×2,100.0 | 3,700.0×2,150.0 | 3,600.0×2,100.0×250.0 | 右 | 2 | -2.05 | yes | 2130 | 3660 | 11580 | 7.7958 | 0 | 250 | 2100 | 3600 | 12.1866 | -1.53081e-14 | 1.94895 | 1.89 | 7.56 | 7.955 | 2050 | 1750 | 100 | 270 | 925 | 0 | 1775 | 1775 | 0 | 0 | 170 | 100 | 1.05
SD2 | 2150 | 2900 | SD2 | ホール | W1 | 店舗 | 108 | ホール | ＜ゾーン番号＞ | インテリア | 2,800.0×2,100.0 | 2,900.0×2,150.0 | 2,800.0×2,100.0×150.0 | 左 | 1 | -2.05 | no | 2130 | 2860 | 9980 | 6.0918 | 0 | 150 | 2100 | 2800 | 8.6406 | -9.18485e-15 | 0.91377 | 0.882 | 5.88 | 6.235 | 2050 | 1350 | 500 | 170 | 725 | 0 | 2800 | 0 | 0 | 0 | 0 | 0 | 1.05

# IfcDoor: 両開き戸 (3)
Type - ParameterTakesPrecedence: no; Sizeable: no
OverallHeight: 2165 mm; Classification: ドア (ARCHICAD 分類)
ArchiCADProperties - 要素ID: SD4; ホットリンクおよび要素ID: SD4; レイヤー: 壁-躯体; ライブラリ部品名: 両開き戸; ビルディングマテリアル/複合構造/断面形状/塗りつぶし: 背景; 塗りつぶし種類: 背景; 関連ゾーン番号: ＜ゾーン番号＞; ロック状態: no; 要素タイプ: ドア; 材質 (全て): ペイント - サンドベージュ; ゾーンから: 廊下; ゾーン番号から: ＜ゾーン番号＞; ゾーン番号へ: ＜ゾーン番号＞; リノベーションフィルタで表示: 全ての関連フィルタ; 構造機能: 非構造耐力要素; 位置: インテリア; リノベーションステータス: 既存; 壁構造: コンクリート; 方向: 左; 開口部 ライブラリ部品名: 両開き戸; 開口部 側面塗りつぶし索引: 背景; ARCHICAD 分類 - v 2.0: ドア
AC_Pset_両開き戸 - 壁輪郭(0-なし,1-全て,2-側面,3-長さ): 0; ホットスポット(0-なし,1-2D,2-3D,3-全て): 3; 2Dホットスポットを3Dで表示: yes; 開口部は壁側面の材質: no; 開口の側面を曲線壁に沿う: no; 抱き配置位置: 1; 開口角度2D: 90 deg; 開口角度3D: 0 deg; 枠材質 (gs_frame_mat): 木材 - マツ 木目 横; パネル材質: 木材 - マツ 木目 横; 公称サイズ: 2; 有効開口を公称サイズに設定: no; 枠内を公称サイズに設定: no; 壁開口を公称サイズに設定: no; 内寸を公称サイズに設定: yes; 現在の公称サイズを選択に切り替え: no; 詳細レベル: 1; 詳細: 1; 詳細表現スケールn (1/1 - 1/n): 50; 中間表現スケールm （1/n～1/m): 100; 2D 表示 (iViewtype_2D): 1; 断面表示: 1; 2D建具背面の無地塗つぶし: no; 額縁表現: 2; 2D額縁塗りつぶし: 木材1; 曲線壁の開口部でホットスポットを表示: no; ドア沓摺線 2D: no; 建具種類: SD; 建具番号: 12; 法規制: 未定; 内外区分: 内; 形式: 両開き戸; 建具識別コード（0=窓,1=ドア,2=シャッター,3=エレベーター): 1; 接続されたゾーンを値として使用: no; IFC操作 (ifc_optypestr): 未定義; IFC操作 (ifc_optype): 0; キープラン表示: yes; マーカータイプをスケールに連動: yes; マーカータイプ: タイプ1; 枝番(0=なし): 0; 建具サイズ表示: no; 建具符号方向: 任意角度; 建具符号任意角度: 0 deg; 用紙スケール: no; マーカーサイズ (用紙) (k_dia_paper): 4.2; マーカーサイズ (用紙) (k_dia_M): 0.0042; 離れX (用紙) (k_lenb_paper): 0; 離れX (用紙) (k_lenb_M): 0; 離れY (用紙) (k_lena_paper): 10; 離れY (用紙) (k_lena_M): 0.01; 離れオフセット (用紙) (k_lenc_paper): 0; 離れオフセット (用紙) (k_lenc_M): 0; 引き出し線角度: 0 deg; 引き出し線: no; ID表示: no; 線種: 1; 建具記号で塗りつぶしを使用: no; 建具記号塗りつぶし種類: 背景; フォント: Meiryo UI 日本語; 字サイズユーザー設定: no; 字サイズ: 1.4; 追記文字サイズ (mm): 1.43; 建具文字サイズ (mm): 1.43; 建具番号-枝番: 12; 追記位置X1 (用紙) (n_offx1_paper): -11; 追記位置X1 (用紙) (n_offx1_M): -0.011; 追記位置Y1 (用紙) (n_offy1_paper): 2.5; 追記位置Y1 (用紙) (n_offy1_M): 0.0025; 追記位置X2 (用紙) (n_offx2_paper): -11; 追記位置X2 (用紙) (n_offx2_M): -0.011; 追記位置Y2 (用紙) (n_offy2_paper): -2.5; 追記位置Y2 (用紙) (n_offy2_M): -0.0025; 追記位置X3 (用紙) (n_offx3_paper): 11; 追記位置X3 (用紙) (n_offx3_M): 0.011; 追記位置Y3 (用紙) (n_offy3_paper): 2.5; 追記位置Y3 (用紙) (n_offy3_M): 0.0025; 追記位置X4 (用紙) (n_offx4_paper): 11; 追記位置X4 (用紙) (n_offx4_M): 0.011; 追記位置Y4 (用紙) (n_offy4_paper): -2.5; 追記位置Y4 (用紙) (n_offy4_M): -0.0025; サイズ表示位置X (用紙) (size_anno_x_paper): 5; サイズ表示位置X (用紙) (size_anno_x_M): 0.005; サイズ表示位置Y (用紙) (size_anno_y_paper): 0; サイズ表示位置Y (用紙) (size_anno_y_M): 0; 法規制マーカー: yes; マーカーサイズ (用紙) (r_dia_paper): 2; マーカーサイズ (用紙) (r_dia_M): 0.002; マーカー塗りつぶしあり/なし: no; マーカー塗りつぶし背景ペン: 透過; マーカー塗りつぶし: 25 %; 建具下端レベルは壁を基準とする: no; 建具表平面表示: no; 離れX (用紙) (r_lenb_paper): 0; 離れX (用紙) (r_lenb_M): 0; 離れY (用紙) (r_lena_paper): -5; 離れY (用紙) (r_lena_M): -0.005; MO API ドアコード: 17; 抱き形状: 1; 横枠形状 (ui_shape2D): 1; 下枠非表示オプション: 2; 横枠形状 (d_s_s): 1; 上枠形状: 1; 壁断面形状: 1; 傾斜壁角度１: 90 deg; 傾斜壁角度２: 90 deg; 飾り袖: yes; ネームプレート ((詳細時): yes; 連続個数: 1; 扉スタイル (stPanel_Style): フラッシュ; 扉スタイル (iPanel_Style): 4; サブ扉スタイル: フラッシュ; ハンドル表記: なし; ガラスの水平分割数: 4; ガラスの垂直分割数: 2; 欄間スタイル (stTransom_Style): サイドパネル; 欄間スタイル (iTransom_Style): 2; 無目 種類 (middle_bar_type): 1; 沓摺 形状: 1; 水切り有無: no; 開き角度: 0 deg; 3Dでの開口線: no; 平面図開口線: no; 3Dでのガラス表現: no; 2Dでの開口線の線種: 1; 平面図中心線: no; 2D開き角度-左: 90 deg; 2D開き角度-右: 90 deg; 枠材質 (matframe): ペイント - サンドベージュ; 沓摺材質: ペイント - サンドベージュ; ドア材質: ペイント - サンドベージュ; ドア内部材質にリンク: yes; 内部ドア材質: ペイント - サンドベージュ; 枠カバー材質: 木材 - 木01; ルーバー材質: 金属 - アルミニウム; ガラス材質: ガラス - シンプル; 取っ手材質: 金属 - ステンレス; 紙材質: プラスチック - 光沢 白; 幕板材質: ペイント - サンドベージュ; ネームプレートユニット材質: ペイント - サンドベージュ; 新聞ポスト材質: 金属 - ステンレス; ネームプレート材質: 金属 - ステンレス; インターコムパネル材質: ペイント - アントラシート; 気密: 未定; 遮音: 未定; 枠 材質: 未定; 枠 仕上: 未定; 沓摺 材質: 未定; 沓摺 仕上: 未定; ドアタイプ: 未定; 扉 材質: 未定; 扉 仕上: 未定; 無目 種類 (stTransom_Glasstype): スチールパネル; ガラス 種類: 未定; ガラス 厚: 未定; ガラリ 形状: 未定; ガラリ 機構: 未定; ガラリ 材質: 未定; ガラリ 仕上: 未定; ロックセット: 未定; 握玉: 未定; ヒンジ: 未定; クローザー: 未定; 戸当り: 未定; フランス落し: 未定; 順位調整器: 未定; チェーンロック: 未定; ドアアイ: 未定; ポスト: 未定; 価格: 0; 自動マーカーのドア名: ドア16; 平面図中心線種: 1; 壁開口寸法タイプ: 1; 外側層の延長: no; 内側層の延長: no; 延長線種: 1; 延長する内側層の数: 0; 延長する外側層の数: 0; 2Dシンボル表示のMVOを上書き: no; ドア3D投影のMVOを上書き: no; 簡易開いた扉線: no; ドア扉線の表示: no; 3D開口線 側面: 3; 3Dガラスシンボル 側面: 3; 並べ替え用通し番号: 0
採光計算 - 窓から隣地境界線までの距離: 4
排煙・換気計算 - 天井面の高さ: 0; 有効開口幅: 0; 開き角度: 0; 天井面より80cm以内の距離: 0.8; 窓の上端高さから天井面までの距離: -2.035; 排煙有効開口面積(引違い・片引き等): 0; 有効排煙開口率: 0; 排煙有効開口面積(横軸・外倒し・内倒し等): 0
AC_Pset_RenovationAndPhasing - Renovation Status: Existing
Pset_DoorCommon - IsExternal: no
BaseQuantities - Height: 2130 mm; Volume: 0 m3; Depth: 150 mm; NetVolume: 0 m3
ArchiCADQuantities - 高さ: 2100 mm; 正味体積: 0 m3; リンク/配置フロアまでの高度: 0 mm; 下部オフセット: 0 mm; 上端高度から配置フロア: 2130 mm; 窓/ドア外壁側開口部高さ: 2130 mm; 窓/ドア外壁反対側開口部高さ: 2130 mm; 窓/ドア外壁側公称開口部高さ: 2165 mm; 窓/ドア外壁反対側公称開口部高さ: 2165 mm; 下端/上端値: 0 mm; 窓/ドア公称下端高さ: 0 mm; 窓/ドア外壁側下端高さ: 0 mm; 窓/ドア外壁反対側下端高さ: 0 mm; 窓/ドア公称上端高さ: 2100 mm; 窓/ドア外壁側上端高さ: 2035 mm; 窓/ドア外壁反対側上端高さ: 2035 mm; 壁厚さ: 150 mm; 枠厚さ: 100 mm
AC_Equantity_両開き戸 - 下部レベル: 1000 mm; 上部レベル: 0 mm; 壁躯体に抱き: -10 mm; 枠見込 (gs_frame_thk): 100 mm; 枠見付: 50 mm; 扉厚さ (gs_leaf_thk): 40 mm; AC左開口部拡張サイズ: 65 mm; AC右開口部拡張サイズ: 65 mm; AC上開口部拡張サイズ: 65 mm; AC下開口部拡張サイズ: 0 mm; 有効開口高さ: 2100 mm; 枠内高さ: 2115 mm; 下部オフセット: 0 mm; 壁開口高さ: 2165 mm; 抱き高さ: 2100 mm; ユニット高さ: 2100 mm; 開口高さ (ac_egress_height): 2100 mm; 開口高さ (gs_opening_height): 2100 mm; パネル高さ: 2115 mm; マーカーサイズ (k_dia): 420 mm; 離れX (k_lenb): 0 mm; 離れY (k_lena): 1300 mm; 離れオフセット: 0 mm; 追記位置X1: -700 mm; 追記位置Y1: 250 mm; 追記位置X2: -700 mm; 追記位置Y2: -250 mm; 追記位置X3: 700 mm; 追記位置Y3: 250 mm; 追記位置X4: 700 mm; 追記位置Y4: -250 mm; サイズ表示位置X: 500 mm; サイズ表示位置Y: 0 mm; マーカーサイズ (r_dia): 200 mm; 床とFLのレベル差: 0 mm; 壁下端レベル: 0 mm; 離れX (r_lenb): 0 mm; 離れY (r_lena): -500 mm; フロアレベルから建具下端までの高さ: 0 mm; 中間壁までの距離: 0 mm; 外壁までの距離: 0 mm; 開口側面幅1: 300 mm; 開口側面幅2: 100 mm; 開口側面奥行き: 1800 mm; 反対側側面幅1: 300 mm; 反対側側面幅2: 100 mm; 反対側側面奥行き: 1200 mm; 反対側側面幅: 1100 mm; 枠見付（縦）: 25 mm; 上枠見付: 25 mm; 枠見付（中間表示）: 30 mm; 枠見込 (p3): 170 mm; 扉厚さ (p2): 45 mm; 枠見付２（縦）: 40 mm; 上枠見付２: 40 mm; 戸当たり見付: 15 mm; 戸当たり見込: 50 mm; ちり１: 10 mm; ちり２: 10 mm; 抱き寸法: 65 mm; 逃げ（横）: 65 mm; 逃げ-上: 65 mm; 抱き逃げ: 15 mm; 床レベル差（沓摺）: 100 mm; 飾り袖幅: 300 mm; ハンドル取付位置（端から）: 70 mm; ハンドル取付位置（高さ）: 1000 mm; パネル内開口幅: 150 mm; パネル内開口高さ（上）: 800 mm; パネル内開口高さ（下）: 500 mm; パネル端との距離: 150 mm; パネル下端との距離: 150 mm; パネル上端との距離: 150 mm; スリット窓ガラリ間隔: 200 mm; 無目見付（0＝欄間なし）: 0 mm; 無目見付: 100 mm; 無目見込: 95 mm; 水切りの出: 60 mm; 外側仕上げ厚: 0 mm; 内側仕上げ厚: 0 mm; 内部１層目仕上げ厚: 0 mm; 錠位置X: -500 mm; 錠位置Y: 0 mm; 中心からの距離: 100 mm; 抱き奥行き: -10 mm; 扉出幅: 30 mm; 戸当り 上部: 15 mm; 額縁幅: 10 mm; 抱き仕上厚: 0 mm; 転び: 0 mm; 欠込寸法 （横）: 25 mm; 欠込寸法 （上）: 25 mm
Name | In | OverallWidth (mm) = 窓/ドア外壁側公称開口部幅 (mm) = 窓/ドア外壁反対側公称開口部幅 (mm) = 壁開口幅 (mm) | 関連ゾーン名 = ゾーンへ | ホームフロア名 | ホームフロア数 | 親ID = 壁ID | 抱き寸法 = ユニット寸法 = 間口寸法 = 公称幅x高さ | 壁開口寸法 | 扉寸法 | 公称幅x高さx厚さ | Width (mm) = 窓/ドア外壁側開口部幅 (mm) = 窓/ドア外壁反対側開口部幅 (mm) | Perimeter (mm) | Area (m2) = 窓/ドア外壁側開口部面積 (m2) = 窓/ドア外壁反対側開口部面積 (m2) | 幅 (mm) = 抱き幅 (mm) = ユニット幅 (mm) = 開口幅 (ac_egress_width) (mm) = 開口幅 (gs_opening_width) (mm) | GLからの高度 (mm) = 高度 1 (mm) = 高度 2 (mm) = 海抜までの高度 (mm) | 表面積 (m2) = 窓/ドア開口 表面積 (m2) | 上端高度から第1基準レベル (mm) = 上端高度から基準レベル (mm) = 上端高度から海抜 (mm) = 上端高度から第2基準レベル (mm) | 下端高度から第1基準レベル (mm) = 下端高度から基準レベル (mm) = 下端高度から海抜 (mm) = 下端高度から第2基準レベル (mm) | 下端高度から配置フロア (mm) | 窓/ドア開口 開口部体積 (m3) | 窓/ドア開口部公称体積 (m3) | 窓/ドア開口面積 (m2) | 窓/ドア抱き側開口面積 (m2) = 窓/ドア抱き反対側開口面積 (m2) | 有効開口幅 (mm) | 枠内幅 (mm) = 可動部の幅 (mm) | 窓の中心高さ (mm)
SD4 | 1FL | 2130 | EVホール | 1FL | 1 | W7 | 2,000.0×2,100.0 | 2,130.0×2,165.0 | 2,030.0×2,115.0 | 2,000.0×2,100.0×150.0 | 2060 | 8380 | 4.3878 | 2000 | 0 | 6.4626 | 2130 | -9.18485e-15 | -9.18485e-15 | 0.65817 | 0.63 | 4.2 | 4.61145 | 1940 | 2030 | 1.05
SD4 | 2FL | 1530 | 機械室 | 2FL | 2 | W9 | 1,400.0×2,100.0 | 1,530.0×2,165.0 | 1,430.0×2,115.0 | 1,400.0×2,100.0×150.0 | 1460 | 7180 | 3.1098 | 1400 | 3000 | 4.9866 | 5130 | 3000 | 0 | 0.46647 | 0.441 | 2.94 | 3.31245 | 1340 | 1430 | 4.05
SD4 | 2FL | 2130 | EVホール | 2FL | 2 | W7 | 2,000.0×2,100.0 | 2,130.0×2,165.0 | 2,030.0×2,115.0 | 2,000.0×2,100.0×150.0 | 2060 | 8380 | 4.3878 | 2000 | 3000 | 6.4626 | 5130 | 3000 | 0 | 0.65817 | 0.63 | 4.2 | 4.61145 | 1940 | 2030 | 4.05

# IfcDoor: 片引き戸 (10)
Type - ParameterTakesPrecedence: no; Sizeable: no
OverallHeight: 2150 mm; OverallWidth: 1200 mm; Classification: ドア (ARCHICAD 分類)
ArchiCADProperties - 要素ID: SD4; レイヤー: 壁-躯体; ライブラリ部品名: 片引き戸; ビルディングマテリアル/複合構造/断面形状/塗りつぶし: 背景; 塗りつぶし種類: 背景; 関連ゾーン番号: ＜ゾーン番号＞; 要素タイプ: ドア; 材質 (全て): ペイント - サンドベージュ; ゾーン番号へ: ＜ゾーン番号＞; リノベーションフィルタで表示: 全ての関連フィルタ; 構造機能: 非構造耐力要素; リノベーションステータス: 既存; 抱き寸法: 1,100.0×2,100.0; 壁開口寸法: 1,200.0×2,150.0; ユニット寸法: 1,100.0×2,100.0; 間口寸法: 1,100.0×2,100.0; 扉寸法: 1,100.0×2,100.0; 公称幅x高さ: 1,100.0×2,100.0; 公称幅x高さx厚さ: 1,100.0×2,100.0×150.0; 壁構造: コンクリート; 方向: 左; 開口部 ライブラリ部品名: 片引き戸; 開口部 側面塗りつぶし索引: 背景; ARCHICAD 分類 - v 2.0: ドア
AC_Pset_片引き戸 - 壁輪郭(0-なし,1-全て,2-側面,3-長さ): 0; ホットスポット(0-なし,1-2D,2-3D,3-全て): 3; 2Dホットスポットを3Dで表示: yes; 開口部は壁側面の材質: no; 開口の側面を曲線壁に沿う: no; 抱き配置位置: 1; 開口角度2D: 90 deg; 開口角度3D: 0 deg; 枠材質 (gs_frame_mat): 木材 - マツ 木目 横; パネル材質: 木材 - マツ 木目 横; 公称サイズ: 2; 有効開口を公称サイズに設定: no; 枠内を公称サイズに設定: no; 壁開口を公称サイズに設定: no; 内寸を公称サイズに設定: yes; 現在の公称サイズを選択に切り替え: no; 詳細レベル: 1; 詳細: 1; 詳細表現スケールn (1/1 - 1/n): 50; 中間表現スケールm （1/n～1/m): 100; 2D 表示 (iViewtype_2D): 1; 断面表示: 1; 2D建具背面の無地塗つぶし: no; 額縁表現: 2; 2D額縁塗りつぶし: 木材1; 曲線壁の開口部でホットスポットを表示: no; ドア沓摺線 2D: no; 建具種類: SD; 建具番号: 9; 法規制: 未定; 内外区分: 内; 形式: 片引き戸; 建具識別コード（0=窓,1=ドア,2=シャッター,3=エレベーター): 1; 接続されたゾーンを値として使用: no; IFC操作 (ifc_optypestr): 未定義; IFC操作 (ifc_optype): 0; キープラン表示: yes; マーカータイプをスケールに連動: yes; マーカータイプ: タイプ1; 枝番(0=なし): 0; 建具サイズ表示: no; 建具符号方向: 任意角度; 建具符号任意角度: 0 deg; 用紙スケール: no; マーカーサイズ (用紙) (k_dia_paper): 4.2; マーカーサイズ (用紙) (k_dia_M): 0.0042; 離れX (用紙) (k_lenb_paper): 0; 離れX (用紙) (k_lenb_M): 0; 離れY (用紙) (k_lena_paper): 10; 離れY (用紙) (k_lena_M): 0.01; 離れオフセット (用紙) (k_lenc_paper): 0; 離れオフセット (用紙) (k_lenc_M): 0; 引き出し線角度: 0 deg; 引き出し線: no; ID表示: no; 線種: 1; 建具記号で塗りつぶしを使用: no; 建具記号塗りつぶし種類: 背景; フォント: Meiryo UI 日本語; 字サイズユーザー設定: no; 字サイズ: 1.4; 追記文字サイズ (mm): 1.43; 建具文字サイズ (mm): 1.43; 建具番号-枝番: 9; 追記位置X1 (用紙) (n_offx1_paper): -11; 追記位置X1 (用紙) (n_offx1_M): -0.011; 追記位置Y1 (用紙) (n_offy1_paper): 2.5; 追記位置Y1 (用紙) (n_offy1_M): 0.0025; 追記位置X2 (用紙) (n_offx2_paper): -11; 追記位置X2 (用紙) (n_offx2_M): -0.011; 追記位置Y2 (用紙) (n_offy2_paper): -2.5; 追記位置Y2 (用紙) (n_offy2_M): -0.0025; 追記位置X3 (用紙) (n_offx3_paper): 11; 追記位置X3 (用紙) (n_offx3_M): 0.011; 追記位置Y3 (用紙) (n_offy3_paper): 2.5; 追記位置Y3 (用紙) (n_offy3_M): 0.0025; 追記位置X4 (用紙) (n_offx4_paper): 11; 追記位置X4 (用紙) (n_offx4_M): 0.011; 追記位置Y4 (用紙) (n_offy4_paper): -2.5; 追記位置Y4 (用紙) (n_offy4_M): -0.0025; サイズ表示位置X (用紙) (size_anno_x_paper): 5; サイズ表示位置X (用紙) (size_anno_x_M): 0.005; サイズ表示位置Y (用紙) (size_anno_y_paper): 0; サイズ表示位置Y (用紙) (size_anno_y_M): 0; 法規制マーカー: yes; マーカーサイズ (用紙) (r_dia_paper): 2; マーカーサイズ (用紙) (r_dia_M): 0.002; マーカー塗りつぶしあり/なし: no; マーカー塗りつぶし背景ペン: 透過; マーカー塗りつぶし: 25 %; 建具下端レベルは壁を基準とする: no; 建具表平面表示: no; 離れX (用紙) (r_lenb_paper): 0; 離れX (用紙) (r_lenb_M): 0; 離れY (用紙) (r_lena_paper): -5; 離れY (用紙) (r_lena_M): -0.005; MO API ドアコード: 23; 抱き形状: 1; 横枠形状 (ui_shape2D): 3; 下枠非表示オプション: 2; 横枠形状 (d_s_s): 3; 上枠形状: 3; 壁断面形状: 1; 傾斜壁角度１: 90 deg; 傾斜壁角度２: 90 deg; 枚数: 1; 扉スタイル (stPanel_Style): フラッシュ; 扉スタイル (iPanel_Style): 4; ハンドル表記: なし; ガラスの水平分割数: 7; ガラスの垂直分割数: 4; 欄間ガラスの水平分割数: 3; 欄間スタイル (stTransom_Style): サイドパネル; 欄間スタイル (iTransom_Style): 2; 無目 種類 (middle_bar_type): 3; 沓摺 形状: 4; 3Dでの扉の開口率(%): 0; 3Dでの開口線: no; 平面図開口線: no; 3Dでのガラス表現: no; 2Dでの開口線の線種: 28; 平面図中心線: no; 枠材質 (matframe): ペイント - サンドベージュ; 沓摺材質: ペイント - サンドベージュ; ドア材質: ペイント - サンドベージュ; ドア内部材質にリンク: yes; 内部ドア材質: ペイント - サンドベージュ; ルーバー材質: 金属 - アルミニウム; ガラス材質: ガラス - シンプル; 取っ手材質: 金属 - ステンレス; 紙材質: 木材 - マツ 木目 横; 幕板材質: ペイント - サンドベージュ; 気密: 未定; 遮音: 未定; 枠 材質: 未定; 枠 仕上: 未定; 沓摺 材質: 未定; 沓摺 仕上: 未定; ドアタイプ: 未定; 扉 材質: 未定; 扉 仕上: 未定; 無目 種類 (stTransom_Glasstype): 未定; ガラス 種類: 未定; ガラス 厚: 未定; ガラリ 形状: 未定; ガラリ 機構: 未定; ガラリ 材質: 未定; ガラリ 仕上: 未定; ロックセット: 未定; 握玉: 未定; ヒンジ: 未定; クローザー: 未定; 戸当り: 未定; フランス落し: 未定; 順位調整器: 未定; チェーンロック: 未定; ドアアイ: 未定; ポスト: 未定; 価格: 0; 自動マーカーのドア名: ドア13; 平面図中心線種: 1; 延長する内側層の数: 0; 延長する外側層の数: 0; 外側層の延長: no; 内側層の延長: no; 延長線種: 1; 2Dシンボル表示のMVOを上書き: no; ドア3D投影のMVOを上書き: no; 3D開口線 側面: 3; 3Dガラスシンボル 側面: 3; 並べ替え用通し番号: 0
採光計算 - 窓から隣地境界線までの距離: 4
排煙・換気計算 - 天井面の高さ: 0; 有効開口幅: 0; 開き角度: 0; 天井面より80cm以内の距離: 0.8; 窓の上端高さから天井面までの距離: -2.05; 排煙有効開口面積(引違い・片引き等): 0; 有効排煙開口率: 0; 排煙有効開口面積(横軸・外倒し・内倒し等): 0
AC_Pset_RenovationAndPhasing - Renovation Status: Existing
BaseQuantities - Height: 2130 mm; Width: 2285 mm; Perimeter: 8830 mm; Area: 4.86705 m2; Volume: 0 m3; Depth: 150 mm; NetVolume: 0 m3
ArchiCADQuantities - 高さ: 2100 mm; 正味体積: 0 m3; 幅: 1100 mm; リンク/配置フロアまでの高度: 0 mm; 下部オフセット: 0 mm; 表面積: 4.5849 m2; 上端高度から配置フロア: 2130 mm; 窓/ドア開口 開口部体積: 0.418545 m3; 窓/ドア開口部公称体積: 0.3465 m3; 窓/ドア開口 表面積: 4.5849 m2; 窓/ドア開口面積: 2.31 m2; 窓/ドア外壁側開口部幅: 2285 mm; 窓/ドア外壁側開口部高さ: 2130 mm; 窓/ドア外壁反対側開口部幅: 1160 mm; 窓/ドア外壁反対側開口部高さ: 2130 mm; 窓/ドア外壁側開口部面積: 4.86705 m2; 窓/ドア外壁反対側開口部面積: 2.4708 m2; 窓/ドア外壁側公称開口部幅: 1200 mm; 窓/ドア外壁側公称開口部高さ: 2150 mm; 窓/ドア外壁反対側公称開口部幅: 1200 mm; 窓/ドア外壁反対側公称開口部高さ: 2150 mm; 窓/ドア抱き側開口面積: 2.58 m2; 窓/ドア抱き反対側開口面積: 2.58 m2; 下端/上端値: 0 mm; 窓/ドア公称下端高さ: 0 mm; 窓/ドア外壁側下端高さ: 0 mm; 窓/ドア外壁反対側下端高さ: 0 mm; 窓/ドア公称上端高さ: 2100 mm; 窓/ドア外壁側上端高さ: 2050 mm; 窓/ドア外壁反対側上端高さ: 2050 mm; 壁厚さ: 150 mm; 枠厚さ: 100 mm
AC_Equantity_片引き戸 - 下部レベル: 1000 mm; 上部レベル: 0 mm; 壁躯体に抱き: -10 mm; 枠見込 (gs_frame_thk): 100 mm; 枠見付: 50 mm; 扉厚さ (gs_leaf_thk): 40 mm; AC左開口部拡張サイズ: 50 mm; AC右開口部拡張サイズ: 50 mm; AC上開口部拡張サイズ: 50 mm; AC下開口部拡張サイズ: 0 mm; 有効開口幅: 1100 mm; 有効開口高さ: 2100 mm; 枠内幅: 1100 mm; 枠内高さ: 2100 mm; 下部オフセット: 0 mm; 壁開口幅: 1200 mm; 壁開口高さ: 2150 mm; 抱き幅: 1100 mm; 抱き高さ: 2100 mm; ユニット幅: 1100 mm; ユニット高さ: 2100 mm; 開口幅 (ac_egress_width): 1100 mm; 開口高さ (ac_egress_height): 2100 mm; 開口幅 (gs_opening_width): 1100 mm; 開口高さ (gs_opening_height): 2100 mm; 可動部の幅: 1100 mm; パネル高さ: 2100 mm; マーカーサイズ (k_dia): 420 mm; 離れX (k_lenb): 0 mm; 離れY (k_lena): 1000 mm; 離れオフセット: 0 mm; 追記位置X1: -700 mm; 追記位置Y1: 250 mm; 追記位置X2: -700 mm; 追記位置Y2: -250 mm; 追記位置X3: 700 mm; 追記位置Y3: 250 mm; 追記位置X4: 700 mm; 追記位置Y4: -250 mm; サイズ表示位置X: 500 mm; サイズ表示位置Y: 0 mm; マーカーサイズ (r_dia): 200 mm; 床とFLのレベル差: 0 mm; 壁下端レベル: 0 mm; 離れX (r_lenb): 0 mm; 離れY (r_lena): -500 mm; フロアレベルから建具下端までの高さ: 0 mm; 中間壁までの距離: 0 mm; 外壁までの距離: 0 mm; 開口側面幅1: 300 mm; 開口側面幅2: -100 mm; 開口側面奥行き: 800 mm; 反対側側面幅1: 300 mm; 反対側側面幅2: -100 mm; 反対側側面奥行き: 800 mm; 反対側側面幅: 1300 mm; 枠見付（縦）: 25 mm; 上枠見付: 25 mm; 枠見付（中間表示）: 30 mm; 枠見込 (p3): 170 mm; 扉厚さ (p2): 45 mm; ちり１: 10 mm; ちり２: 10 mm; 引き部分の隙間: 14 mm; 逃げ（横）: 50 mm; 逃げ-上: 50 mm; 引き残し: 0 mm; オフセット: 25 mm; パネルかぶり幅: 50 mm; ハンドル取付位置（端から）: 70 mm; ハンドル取付位置（高さ）: 1000 mm; パネル内開口幅: 150 mm; パネル内開口高さ（上）: 800 mm; パネル内開口高さ（下）: 500 mm; パネル端との距離: 150 mm; パネル下端との距離: 150 mm; パネル上端との距離: 150 mm; スリット窓ガラリ間隔: 200 mm; 無目見付（0＝欄間なし）: 0 mm; 無目見付: 100 mm; 無目見込: 0 mm; 外側仕上げ厚: 0 mm; 内側仕上げ厚: 0 mm; 内部１層目仕上げ厚: 0 mm; 錠位置X: -500 mm; 錠位置Y: 0 mm; 中心からの距離: 100 mm; 抱き奥行き: -10 mm
Name | In | ホットリンクおよび要素ID | 関連ゾーン名 = ゾーンへ | ロック状態 | ホームフロア名 | ホームフロア数 | 親ID = 壁ID | 位置 | IsExternal | GLからの高度 (mm) = 高度 1 (mm) = 高度 2 (mm) = 海抜までの高度 (mm) | 上端高度から第1基準レベル (mm) = 上端高度から基準レベル (mm) = 上端高度から海抜 (mm) = 上端高度から第2基準レベル (mm) | 下端高度から第1基準レベル (mm) = 下端高度から基準レベル (mm) = 下端高度から海抜 (mm) = 下端高度から第2基準レベル (mm) | 下端高度から配置フロア (mm) | 窓の中心高さ (mm) | ゾーンから | ゾーン番号から | ホットリンク マスタID
SD4 | 1FL | SD4 | ゴミ置き場 | no | 1FL | 1 | W9 | エクステリア | yes | 0 | 2130 | -9.18485e-15 | -9.18485e-15 | 1.05
SD4 | 1FL | SD4 | 多目的トイレ | no | 1FL | 1 | W8 | インテリア | no | 0 | 2130 | -9.18485e-15 | -9.18485e-15 | 1.05 | EVホール | ＜ゾーン番号＞
SD4 | 2FL | SD4 | 多目的トイレ | no | 2FL | 2 | W8 | インテリア | no | 3000 | 5130 | 3000 | 0 | 4.05 | EVホール | ＜ゾーン番号＞
SD4 | 3FL | SD4 | 多目的トイレ | no | 3FL | 3 | W8 | インテリア | no | 6000 | 8130 | 6000 | 0 | 7.05 | EVホール | ＜ゾーン番号＞
4FLSD4 | 4FL | 4FLSD4 | 多目的トイレ | yes | 4FL | 4 | W8 | インテリア | no | 9000 | 11130 | 9000 | 0 | 10.05 | EVホール | ＜ゾーン番号＞ | 4FL
5FLSD4 | 5FL | 5FLSD4 | 多目的トイレ | yes | 5FL | 5 | W8 | インテリア | no | 12000 | 14130 | 12000 | 0 | 13.05 | EVホール | ＜ゾーン番号＞ | 5FL
6FLSD4 | 6FL | 6FLSD4 | 多目的トイレ | yes | 6FL | 6 | W8 | インテリア | no | 15000 | 17130 | 15000 | 0 | 16.05 | EVホール | ＜ゾーン番号＞ | 6FL
7FLSD4 | 7FL | 7FLSD4 | 多目的トイレ | yes | 7FL | 7 | W8 | インテリア | no | 18000 | 20130 | 18000 | 0 | 19.05 | EVホール | ＜ゾーン番号＞ | 7FL
8FLSD4 | 8FL | 8FLSD4 | 多目的トイレ | yes | 8FL | 8 | W8 | インテリア | no | 21000 | 23130 | 21000 | 0 | 22.05 | EVホール | ＜ゾーン番号＞ | 8FL
9FLSD4 | 9FL | 9FLSD4 | 多目的トイレ | yes | 9FL | 9 | W8 | インテリア | no | 24000 | 26130 | 24000 | 0 | 25.05 | EVホール | ＜ゾーン番号＞ | 9FL

# IfcDoor: 片開き戸 (169)
Type - ParameterTakesPrecedence: no; Sizeable: no
OverallHeight: 2165 mm; Classification: ドア (ARCHICAD 分類)
ArchiCADProperties - レイヤー: 壁-躯体; ライブラリ部品名: 片開き戸; ビルディングマテリアル/複合構造/断面形状/塗りつぶし: 背景; 塗りつぶし種類: 背景; 要素タイプ: ドア; 材質 (全て): ペイント - サンドベージュ; リノベーションフィルタで表示: 全ての関連フィルタ; 構造機能: 非構造耐力要素; リノベーションステータス: 既存; 壁構造: コンクリート; 開口部 ライブラリ部品名: 片開き戸; 開口部 側面塗りつぶし索引: 背景; ARCHICAD 分類 - v 2.0: ドア
AC_Pset_片開き戸 - 壁輪郭(0-なし,1-全て,2-側面,3-長さ): 0; ホットスポット(0-なし,1-2D,2-3D,3-全て): 3; 2Dホットスポットを3Dで表示: yes; 開口部は壁側面の材質: no; 開口の側面を曲線壁に沿う: no; 抱き配置位置: 1; 開口角度2D (gs_open_2D): 90 deg; 開口角度3D: 0 deg; 枠材質 (gs_frame_mat): 木材 - マツ 木目 横; パネル材質: 木材 - マツ 木目 横; 公称サイズ: 2; 有効開口を公称サイズに設定: no; 枠内を公称サイズに設定: no; 壁開口を公称サイズに設定: no; 内寸を公称サイズに設定: yes; 現在の公称サイズを選択に切り替え: no; 詳細レベル: 1; 詳細: 1; 詳細表現スケールn (1/1 - 1/n): 50; 中間表現スケールm （1/n～1/m): 100; 2D 表示 (iViewtype_2D): 1; 断面表示: 1; 2D建具背面の無地塗つぶし: no; 額縁表現: 2; 2D額縁塗りつぶし: 木材1; 曲線壁の開口部でホットスポットを表示: no; ドア沓摺線 2D: no; 建具種類: SD; 建具番号: 10; 法規制: 未定; 内外区分: 内; 形式: 片開き戸; 建具識別コード（0=窓,1=ドア,2=シャッター,3=エレベーター): 1; 接続されたゾーンを値として使用: no; IFC操作 (ifc_optypestr): 未定義; IFC操作 (ifc_optype): 0; キープラン表示: yes; マーカータイプをスケールに連動: yes; マーカータイプ: タイプ1; 枝番(0=なし): 0; 建具サイズ表示: no; 建具符号方向: 任意角度; 建具符号任意角度: 0 deg; 用紙スケール: no; マーカーサイズ (用紙) (k_dia_paper): 4.2; マーカーサイズ (用紙) (k_dia_M): 0.0042; 離れX (用紙) (k_lenb_paper): 0; 離れX (用紙) (k_lenb_M): 0; 離れY (用紙) (k_lena_paper): 10; 離れY (用紙) (k_lena_M): 0.01; 離れオフセット (用紙) (k_lenc_paper): 0; 離れオフセット (用紙) (k_lenc_M): 0; 引き出し線角度: 0 deg; 引き出し線: no; ID表示: no; 線種: 1; 建具記号で塗りつぶしを使用: no; 建具記号塗りつぶし種類: 背景; フォント: Meiryo UI 日本語; 字サイズユーザー設定: no; 字サイズ: 1.4; 追記文字サイズ (mm): 1.43; 建具文字サイズ (mm): 1.43; 建具番号-枝番: 10; 追記位置X1 (用紙) (n_offx1_paper): -11; 追記位置X1 (用紙) (n_offx1_M): -0.011; 追記位置Y1 (用紙) (n_offy1_paper): 2.5; 追記位置Y1 (用紙) (n_offy1_M): 0.0025; 追記位置X2 (用紙) (n_offx2_paper): -11; 追記位置X2 (用紙) (n_offx2_M): -0.011; 追記位置Y2 (用紙) (n_offy2_paper): -2.5; 追記位置Y2 (用紙) (n_offy2_M): -0.0025; 追記位置X3 (用紙) (n_offx3_paper): 11; 追記位置X3 (用紙) (n_offx3_M): 0.011; 追記位置Y3 (用紙) (n_offy3_paper): 2.5; 追記位置Y3 (用紙) (n_offy3_M): 0.0025; 追記位置X4 (用紙) (n_offx4_paper): 11; 追記位置X4 (用紙) (n_offx4_M): 0.011; 追記位置Y4 (用紙) (n_offy4_paper): -2.5; 追記位置Y4 (用紙) (n_offy4_M): -0.0025; サイズ表示位置X (用紙) (size_anno_x_paper): 5; サイズ表示位置X (用紙) (size_anno_x_M): 0.005; サイズ表示位置Y (用紙) (size_anno_y_paper): 0; サイズ表示位置Y (用紙) (size_anno_y_M): 0; 法規制マーカー: yes; マーカーサイズ (用紙) (r_dia_paper): 2; マーカーサイズ (用紙) (r_dia_M): 0.002; マーカー塗りつぶしあり/なし: no; マーカー塗りつぶし背景ペン: 透過; マーカー塗りつぶし: 25 %; 建具下端レベルは壁を基準とする: no; 建具表平面表示: no; 離れX (用紙) (r_lenb_paper): 0; 離れX (用紙) (r_lenb_M): 0; 離れY (用紙) (r_lena_paper): -5; 離れY (用紙) (r_lena_M): -0.005; MO API ドアコード: 8; 抱き形状: 1; 横枠形状 (ui_shape2D): 1; 下枠非表示オプション: 2; 横枠形状 (d_s_s): 1; 上枠形状: 1; 枠 材質2: 未定; 壁断面形状: 1; 傾斜壁角度１: 90 deg; 傾斜壁角度２: 90 deg; 飾り袖: yes; ネームプレート ((詳細時): yes; 連続個数: 1; 扉スタイル (stPanel_Style): フラッシュ; 扉スタイル (iPanel_Style): 4; ハンドル表記: なし; ガラスの水平分割数: 4; ガラスの垂直分割数: 2; 欄間スタイル (stTransom_Style): サイドパネル; 欄間スタイル (iTransom_Style): 2; 無目 種類 (middle_bar_type): 1; 沓摺 形状: 1; 水切り有無: no; 開き角度: 0 deg; 3Dでの開口線: no; 平面図開口線: no; 3Dでのガラス表現: no; 2Dでの開口線の線種: 1; 開口角度2D (opening_angle_2d): 90 deg; 平面図中心線: no; 枠材質 (matframe): ペイント - サンドベージュ; 沓摺材質: ペイント - サンドベージュ; ドア材質: ペイント - サンドベージュ; ドア内部材質にリンク: yes; 内部ドア材質: ペイント - サンドベージュ; 枠カバー材質: 木材 - 木01; ルーバー材質: 金属 - アルミニウム; ガラス材質: ガラス - シンプル; 取っ手材質: 金属 - ステンレス; 紙材質: プラスチック - 光沢 白; 幕板材質: ペイント - サンドベージュ; ネームプレートユニット材質: ペイント - サンドベージュ; 新聞ポスト材質: 金属 - ステンレス; ネームプレート材質: 金属 - ステンレス; インターコムパネル材質: ペイント - アントラシート; 気密: 未定; 遮音: 未定; 枠 材質: 未定; 枠 仕上: 未定; 沓摺 材質: 未定; 沓摺 仕上: 未定; 水切り 材質: スチール; ドアタイプ: 未定; 扉 材質: 未定; 扉 仕上: 未定; 無目 種類 (stTransom_Glasstype): 未定; ガラス 種類: 未定; ガラス 厚: 未定; ガラリ 形状: 未定; ガラリ 機構: 未定; ガラリ 材質: 未定; ガラリ 仕上: 未定; ロックセット: 未定; 握玉: 未定; ヒンジ: 未定; クローザー: 未定; 戸当り: 未定; フランス落し: 未定; 順位調整器: 未定; チェーンロック: 未定; ドアアイ: 未定; ポスト: 未定; 価格: 0; 自動マーカーのドア名: ドア14; 平面図中心線種: 1; 壁開口寸法タイプ: 1; 外側層の延長: no; 内側層の延長: no; 延長線種: 1; 延長する内側層の数: 0; 延長する外側層の数: 0; 2Dシンボル表示のMVOを上書き: no; ドア3D投影のMVOを上書き: no; 簡易開いた扉線: no; ドア扉線の表示: no; 3D開口線 側面: 3; 3Dガラスシンボル 側面: 3; 並べ替え用通し番号: 0
採光計算 - 窓から隣地境界線までの距離: 4
排煙・換気計算 - 天井面の高さ: 0; 有効開口幅: 0; 開き角度: 0; 天井面より80cm以内の距離: 0.8; 窓の上端高さから天井面までの距離: -2.035; 排煙有効開口面積(引違い・片引き等): 0; 有効排煙開口率: 0; 排煙有効開口面積(横軸・外倒し・内倒し等): 0
AC_Pset_RenovationAndPhasing - Renovation Status: Existing
BaseQuantities - Height: 2130 mm; Volume: 0 m3; NetVolume: 0 m3
ArchiCADQuantities - 高さ: 2100 mm; 正味体積: 0 m3; リンク/配置フロアまでの高度: 0 mm; 下部オフセット: 0 mm; 上端高度から配置フロア: 2130 mm; 窓/ドア外壁側開口部高さ: 2130 mm; 窓/ドア外壁反対側開口部高さ: 2130 mm; 窓/ドア外壁側公称開口部高さ: 2165 mm; 窓/ドア外壁反対側公称開口部高さ: 2165 mm; 下端/上端値: 0 mm; 窓/ドア公称下端高さ: 0 mm; 窓/ドア外壁側下端高さ: 0 mm; 窓/ドア外壁反対側下端高さ: 0 mm; 窓/ドア公称上端高さ: 2100 mm; 窓/ドア外壁側上端高さ: 2035 mm; 窓/ドア外壁反対側上端高さ: 2035 mm; 枠厚さ: 100 mm
AC_Equantity_片開き戸 - 下部レベル: 1000 mm; 上部レベル: 0 mm; 壁躯体に抱き: -10 mm; 枠見込 (gs_frame_thk): 100 mm; 枠見付: 50 mm; 扉厚さ (gs_leaf_thk): 40 mm; AC左開口部拡張サイズ: 65 mm; AC右開口部拡張サイズ: 65 mm; AC上開口部拡張サイズ: 65 mm; AC下開口部拡張サイズ: 0 mm; 有効開口高さ: 2100 mm; 枠内高さ: 2115 mm; 壁開口高さ: 2165 mm; 抱き高さ: 2100 mm; ユニット高さ: 2100 mm; 開口高さ (ac_egress_height): 2100 mm; 開口高さ (gs_opening_height): 2100 mm; パネル高さ: 2115 mm; マーカーサイズ (k_dia): 420 mm; 離れX (k_lenb): 0 mm; 離れY (k_lena): 1500 mm; 離れオフセット: 0 mm; 追記位置X1: -700 mm; 追記位置Y1: 250 mm; 追記位置X2: -700 mm; 追記位置Y2: -250 mm; 追記位置X3: 700 mm; 追記位置Y3: 250 mm; 追記位置X4: 700 mm; 追記位置Y4: -250 mm; サイズ表示位置X: 250 mm; サイズ表示位置Y: 0 mm; マーカーサイズ (r_dia): 200 mm; 床とFLのレベル差: 0 mm; 壁下端レベル: 0 mm; 離れX (r_lenb): 0 mm; 離れY (r_lena): -500 mm; フロアレベルから建具下端までの高さ: 0 mm; 中間壁までの距離: 0 mm; 外壁までの距離: 0 mm; 開口側面幅1: 300 mm; 開口側面幅2: 100 mm; 開口側面奥行き: 1200 mm; 反対側側面幅1: 300 mm; 反対側側面幅2: 100 mm; 反対側側面奥行き: 1200 mm; 反対側側面幅: 1100 mm; 枠見付（縦）: 25 mm; 上枠見付: 25 mm; 枠見付（中間表示）: 30 mm; 扉厚さ (p2): 45 mm; 枠見付２（縦）: 40 mm; 上枠見付２: 40 mm; 戸当たり見付: 15 mm; 戸当たり見込: 50 mm; ちり１: 10 mm; ちり２: 10 mm; 抱き寸法: 65 mm; 逃げ（横）: 65 mm; 逃げ-上: 65 mm; 抱き逃げ: 15 mm; 床レベル差（沓摺）: 100 mm; 飾り袖幅: 300 mm; ハンドル取付位置（端から）: 70 mm; ハンドル取付位置（高さ）: 1000 mm; パネル内開口幅: 150 mm; パネル内開口高さ（上）: 800 mm; パネル内開口高さ（下）: 500 mm; パネル端との距離: 150 mm; パネル下端との距離: 150 mm; パネル上端との距離: 150 mm; スリット窓ガラリ間隔: 200 mm; 無目見付（0＝欄間なし）: 0 mm; 無目見付: 100 mm; 無目見込: 95 mm; 水切りの出: 60 mm; 外側仕上げ厚: 0 mm; 内側仕上げ厚: 0 mm; 内部１層目仕上げ厚: 0 mm; 錠位置X: -500 mm; 錠位置Y: 0 mm; 中心からの距離: 100 mm; 抱き奥行き: -10 mm; 扉出幅: 30 mm; 戸当り 上部: 15 mm; 額縁幅: 10 mm; 抱き仕上厚: 0 mm; 転び: 0 mm; 欠込寸法 （横）: 25 mm; 欠込寸法 （上）: 25 mm
Name | In | OverallWidth (mm) = 窓/ドア外壁側公称開口部幅 (mm) = 窓/ドア外壁反対側公称開口部幅 (mm) = 壁開口幅 (mm) | 要素ID | ホットリンクおよび要素ID | 関連ゾーン名 | 関連ゾーン番号 | ロック状態 | ホームフロア名 | ホームフロア数 | 親ID = 壁ID | ゾーンから | ゾーン番号から | 位置 | 抱き寸法 = ユニット寸法 = 間口寸法 = 公称幅x高さ | 壁開口寸法 | 扉寸法 | 公称幅x高さx厚さ | 方向 | IsExternal | Width (mm) = 窓/ドア外壁側開口部幅 (mm) = 窓/ドア外壁反対側開口部幅 (mm) | Perimeter (mm) | Area (m2) = 窓/ドア外壁側開口部面積 (m2) = 窓/ドア外壁反対側開口部面積 (m2) | Depth (mm) = 壁厚さ (mm) | 幅 (mm) = 抱き幅 (mm) = ユニット幅 (mm) = 開口幅 (ac_egress_width) (mm) = 開口幅 (gs_opening_width) (mm) | GLからの高度 (mm) = 高度 1 (mm) = 高度 2 (mm) = 海抜までの高度 (mm) | 表面積 (m2) = 窓/ドア開口 表面積 (m2) | 上端高度から第1基準レベル (mm) = 上端高度から基準レベル (mm) = 上端高度から海抜 (mm) = 上端高度から第2基準レベル (mm) | 下端高度から第1基準レベル (mm) = 下端高度から基準レベル (mm) = 下端高度から海抜 (mm) = 下端高度から第2基準レベル (mm) | 下端高度から配置フロア (mm) | 窓/ドア開口 開口部体積 (m3) | 窓/ドア開口部公称体積 (m3) | 窓/ドア開口面積 (m2) | 窓/ドア抱き側開口面積 (m2) = 窓/ドア抱き反対側開口面積 (m2) | 有効開口幅 (mm) | 枠内幅 (mm) = 可動部の幅 (mm) | 枠見込 (p3) (mm) | 窓の中心高さ (mm) | ゾーンへ | ゾーン番号へ | ホットリンク マスタID
SD3 | 1FL | 1030 | SD3 | SD3 | ホール | ＜ゾーン番号＞ | no | 1FL | 1 | W8 | ホール | ＜ゾーン番号＞ | インテリア | 900.0×2,100.0 | 1,030.0×2,165.0 | 930.0×2,115.0 | 900.0×2,100.0×250.0 | 左 | no | 960 | 6180 | 2.0448 | 250 | 900 | 0 | 4.7946 | 2130 | -1.53081e-14 | -1.53081e-14 | 0.5112 | 0.4725 | 1.89 | 2.22995 | 870 | 930 | 270 | 1.05
SD3 | 1FL | 1030 | SD3 | SD3 | PS | ＜ゾーン番号＞ | no | 1FL | 1 | W6 | 廊下 | ＜ゾーン番号＞ | インテリア | 900.0×2,100.0 | 1,030.0×2,165.0 | 930.0×2,115.0 | 900.0×2,100.0×150.0 | 左 | no | 960 | 6180 | 2.0448 | 150 | 900 | 0 | 3.7566 | 2130 | -9.18485e-15 | -9.18485e-15 | 0.30672 | 0.2835 | 1.89 | 2.22995 | 870 | 930 | 170 | 1.05 | PS | ＜ゾーン番号＞
SD3 | 1FL | 1030 | SD3 | SD3 | 店舗 | 108 | no | 1FL | 1 | W9 | 廊下 | ＜ゾーン番号＞ | インテリア | 900.0×2,100.0 | 1,030.0×2,165.0 | 930.0×2,115.0 | 900.0×2,100.0×150.0 | 左 | no | 960 | 6180 | 2.0448 | 150 | 900 | 0 | 3.7566 | 2130 | -9.18485e-15 | -9.18485e-15 | 0.30672 | 0.2835 | 1.89 | 2.22995 | 870 | 930 | 170 | 1.05 | 店舗 | 108
SD3 | 1FL | 1030 | SD3 | SD3 | 店舗 | 107 | no | 1FL | 1 | W9 | 廊下 | ＜ゾーン番号＞ | インテリア | 900.0×2,100.0 | 1,030.0×2,165.0 | 930.0×2,115.0 | 900.0×2,100.0×150.0 | 右 | no | 960 | 6180 | 2.0448 | 150 | 900 | 0 | 3.7566 | 2130 | -9.18485e-15 | -9.18485e-15 | 0.30672 | 0.2835 | 1.89 | 2.22995 | 870 | 930 | 170 | 1.05 | 店舗 | 107
SD3 | 1FL | 1030 | SD3 | SD3 | 店舗 | 105 | no | 1FL | 1 | W9 | 廊下 | ＜ゾーン番号＞ | インテリア | 900.0×2,100.0 | 1,030.0×2,165.0 | 930.0×2,115.0 | 900.0×2,100.0×150.0 | 右 | no | 960 | 6180 | 2.0448 | 150 | 900 | 0 | 3.7566 | 2130 | -9.18485e-15 | -9.18485e-15 | 0.30672 | 0.2835 | 1.89 | 2.22995 | 870 | 930 | 170 | 1.05 | 店舗 | 105
SD3 | 1FL | 1030 | SD3 | SD3 | 店舗 | 106 | no | 1FL | 1 | W9 | 廊下 | ＜ゾーン番号＞ | インテリア | 900.0×2,100.0 | 1,030.0×2,165.0 | 930.0×2,115.0 | 900.0×2,100.0×150.0 | 左 | no | 960 | 6180 | 2.0448 | 150 | 900 | 0 | 3.7566 | 2130 | -9.18485e-15 | -9.18485e-15 | 0.30672 | 0.2835 | 1.89 | 2.22995 | 870 | 930 | 170 | 1.05 | 店舗 | 106
SD3 | 1FL | 1030 | SD3 | SD3 | 玄関ホール | ＜ゾーン番号＞ | no | 1FL | 1 | W4 | 店舗 | 102 | インテリア | 900.0×2,100.0 | 1,030.0×2,165.0 | 930.0×2,115.0 | 900.0×2,100.0×150.0 | 右 | no | 960 | 6180 | 2.0448 | 150 | 900 | 0 | 3.7566 | 2130 | -9.18485e-15 | -9.18485e-15 | 0.30672 | 0.2835 | 1.89 | 2.22995 | 870 | 930 | 170 | 1.05 | 玄関ホール | ＜ゾーン番号＞
SD3 | 1FL | 1030 | SD3 | SD3 | 玄関ホール | ＜ゾーン番号＞ | no | 1FL | 1 | W5 | 店舗 | 103 | インテリア | 900.0×2,100.0 | 1,030.0×2,165.0 | 930.0×2,115.0 | 900.0×2,100.0×150.0 | 左 | no | 960 | 6180 | 2.0448 | 150 | 900 | 0 | 3.7566 | 2130 | -9.18485e-15 | -9.18485e-15 | 0.30672 | 0.2835 | 1.89 | 2.22995 | 870 | 930 | 170 | 1.05 | 玄関ホール | ＜ゾーン番号＞
SD3 | 1FL | 1030 | SD3 | SD3 | 共用スペー | ＜ゾーン番号＞ | no | 1FL | 1 | W4 | EVホール | ＜ゾーン番号＞ | インテリア | 900.0×2,100.0 | 1,030.0×2,165.0 | 930.0×2,115.0 | 900.0×2,100.0×150.0 | 左 | no | 960 | 6180 | 2.0448 | 150 | 900 | 0 | 3.7566 | 2130 | -9.18485e-15 | -9.18485e-15 | 0.30672 | 0.2835 | 1.89 | 2.22995 | 870 | 930 | 170 | 1.05 | 共用スペー | ＜ゾーン番号＞
SD3 | 1FL | 1030 | SD3 | SD3 | 店舗 | 104 | no | 1FL | 1 | W5 | EVホール | ＜ゾーン番号＞ | インテリア | 900.0×2,100.0 | 1,030.0×2,165.0 | 930.0×2,115.0 | 900.0×2,100.0×150.0 | 左 | no | 960 | 6180 | 2.0448 | 150 | 900 | 0 | 3.7566 | 2130 | -9.18485e-15 | -9.18485e-15 | 0.30672 | 0.2835 | 1.89 | 2.22995 | 870 | 930 | 170 | 1.05 | 店舗 | 104
SD3 | 1FL | 1030 | SD3 | SD3 | 共用スペー | ＜ゾーン番号＞ | no | 1FL | 1 | W0 | PS | ＜ゾーン番号＞ | インテリア | 900.0×2,100.0 | 1,030.0×2,165.0 | 930.0×2,115.0 | 900.0×2,100.0×150.0 | 左 | no | 960 | 6180 | 2.0448 | 150 | 900 | 0 | 3.7566 | 2130 | -9.18485e-15 | -9.18485e-15 | 0.30672 | 0.2835 | 1.89 | 2.22995 | 870 | 930 | 170 | 1.05 | 共用スペー | ＜ゾーン番号＞
SD3 | 1FL | 830 | SD3 | SD3 | 女性用トイレ | ＜ゾーン番号＞ | no | 1FL | 1 | W4 | EVホール | ＜ゾーン番号＞ | インテリア | 700.0×2,100.0 | 830.0×2,165.0 | 730.0×2,115.0 | 700.0×2,100.0×150.0 | 左 | no | 760 | 5780 | 1.6188 | 150 | 700 | 0 | 3.2646 | 2130 | -9.18485e-15 | -9.18485e-15 | 0.24282 | 0.2205 | 1.47 | 1.79695 | 670 | 730 | 170 | 1.05 | 女性用トイレ | ＜ゾーン番号＞
SD3 | 1FL | 830 | SD3 | SD3 | 男性用トイレ | ＜ゾーン番号＞ | no | 1FL | 1 | W4 | EVホール | ＜ゾーン番号＞ | インテリア | 700.0×2,100.0 | 830.0×2,165.0 | 730.0×2,115.0 | 700.0×2,100.0×150.0 | 左 | no | 760 | 5780 | 1.6188 | 150 | 700 | 0 | 3.2646 | 2130 | -9.18485e-15 | -9.18485e-15 | 0.24282 | 0.2205 | 1.47 | 1.79695 | 670 | 730 | 170 | 1.05 | 男性用トイレ | ＜ゾーン番号＞
SD3 | 1FL | 1030 | SD3 | SD3 | ホール | ＜ゾーン番号＞ | no | 1FL | 1 | W9 | 収納 | ＜ゾーン番号＞ | インテリア | 900.0×2,100.0 | 1,030.0×2,165.0 | 930.0×2,115.0 | 900.0×2,100.0×150.0 | 左 | no | 960 | 6180 | 2.0448 | 150 | 900 | 0 | 3.7566 | 2130 | -9.18485e-15 | -9.18485e-15 | 0.30672 | 0.2835 | 1.89 | 2.22995 | 870 | 930 | 170 | 1.05 | ホール | ＜ゾーン番号＞
FSD2 | 2FL | 1230 | FSD2 | FSD2 | 階段室 | ＜ゾーン番号＞ | no | 2FL | 2 | W4 | EVホール | ＜ゾーン番号＞ | インテリア | 1,100.0×2,100.0 | 1,230.0×2,165.0 | 1,130.0×2,115.0 | 1,100.0×2,100.0×150.0 | 左 | no | 1160 | 6580 | 2.4708 | 150 | 1100 | 3000 | 4.2486 | 5130 | 3000 | 0 | 0.37062 | 0.3465 | 2.31 | 2.66295 | 1070 | 1130 | 170 | 4.05 | 階段室 | ＜ゾーン番号＞
SD3 | 2FL | 1030 | SD3 | SD3 | 廊下 | ＜ゾーン番号＞ | no | 2FL | 2 | W9 | 店舗 | 211 | インテリア | 900.0×2,100.0 | 1,030.0×2,165.0 | 930.0×2,115.0 | 900.0×2,100.0×150.0 | 右 | no | 960 | 6180 | 2.0448 | 150 | 900 | 3000 | 3.7566 | 5130 | 3000 | 0 | 0.30672 | 0.2835 | 1.89 | 2.22995 | 870 | 930 | 170 | 4.05 | 廊下 | ＜ゾーン番号＞
SD3 | 2FL | 1030 | SD3 | SD3 | 廊下 | ＜ゾーン番号＞ | no | 2FL | 2 | W9 | 店舗 | 212 | インテリア | 900.0×2,100.0 | 1,030.0×2,165.0 | 930.0×2,115.0 | 900.0×2,100.0×150.0 | 右 | no | 960 | 6180 | 2.0448 | 150 | 900 | 3000 | 3.7566 | 5130 | 3000 | 0 | 0.30672 | 0.2835 | 1.89 | 2.22995 | 870 | 930 | 170 | 4.05 | 廊下 | ＜ゾーン番号＞
SD3 | 2FL | 1030 | SD3 | SD3 | 廊下 | ＜ゾーン番号＞ | no | 2FL | 2 | W9 | 店舗 | 214 | インテリア | 900.0×2,100.0 | 1,030.0×2,165.0 | 930.0×2,115.0 | 900.0×2,100.0×150.0 | 右 | no | 960 | 6180 | 2.0448 | 150 | 900 | 3000 | 3.7566 | 5130 | 3000 | 0 | 0.30672 | 0.2835 | 1.89 | 2.22995 | 870 | 930 | 170 | 4.05 | 廊下 | ＜ゾーン番号＞
SD4 | 2FL | 1030 | SD4 | SD4 | 廊下 | ＜ゾーン番号＞ | no | 2FL | 2 | W9 | 店舗 | 214 | インテリア | 900.0×2,100.0 | 1,030.0×2,165.0 | 930.0×2,115.0 | 900.0×2,100.0×150.0 | 右 | no | 960 | 6180 | 2.0448 | 150 | 900 | 3000 | 3.7566 | 5130 | 3000 | 0 | 0.30672 | 0.2835 | 1.89 | 2.22995 | 870 | 930 | 170 | 4.05 | 廊下 | ＜ゾーン番号＞
SD4 | 2FL | 1030 | SD4 | SD4 | 店舗 | 202 | no | 2FL | 2 | W4 | 廊下 | ＜ゾーン番号＞ | インテリア | 900.0×2,100.0 | 1,030.0×2,165.0 | 930.0×2,115.0 | 900.0×2,100.0×150.0 | 左 | no | 960 | 6180 | 2.0448 | 150 | 900 | 3000 | 3.7566 | 5130 | 3000 | 0 | 0.30672 | 0.2835 | 1.89 | 2.22995 | 870 | 930 | 170 | 4.05 | 店舗 | 202
SD5 | 2FL | 1030 | SD5 | SD5 | 店舗 | 201 | no | 2FL | 2 | W4 | 廊下 | ＜ゾーン番号＞ | インテリア | 900.0×2,100.0 | 1,030.0×2,165.0 | 930.0×2,115.0 | 900.0×2,100.0×150.0 | 右 | no | 960 | 6180 | 2.0448 | 150 | 900 | 3000 | 3.7566 | 5130 | 3000 | 0 | 0.30672 | 0.2835 | 1.89 | 2.22995 | 870 | 930 | 170 | 4.05 | 店舗 | 201
SD3 | 2FL | 1530 | SD3 | SD3 | ホール | ＜ゾーン番号＞ | no | 2FL | 2 | W9 | 廊下 | ＜ゾーン番号＞ | インテリア | 1,400.0×2,100.0 | 1,530.0×2,165.0 | 1,430.0×2,115.0 | 1,400.0×2,100.0×150.0 | 右 | no | 1460 | 7180 | 3.1098 | 150 | 1400 | 3000 | 4.9866 | 5130 | 3000 | 0 | 0.46647 | 0.441 | 2.94 | 3.31245 | 1370 | 1430 | 170 | 4.05 | ホール | ＜ゾーン番号＞
SD3 | 2FL | 830 | SD3 | SD3 | 女性用トイレ | ＜ゾーン番号＞ | no | 2FL | 2 | W4 | EVホール | ＜ゾーン番号＞ | インテリア | 700.0×2,100.0 | 830.0×2,165.0 | 730.0×2,115.0 | 700.0×2,100.0×150.0 | 左 | no | 760 | 5780 | 1.6188 | 150 | 700 | 3000 | 3.2646 | 5130 | 3000 | 0 | 0.24282 | 0.2205 | 1.47 | 1.79695 | 670 | 730 | 170 | 4.05 | 女性用トイレ | ＜ゾーン番号＞
SD3 | 2FL | 830 | SD3 | SD3 | 男性用トイレ | ＜ゾーン番号＞ | no | 2FL | 2 | W4 | EVホール | ＜ゾーン番号＞ | インテリア | 700.0×2,100.0 | 830.0×2,165.0 | 730.0×2,115.0 | 700.0×2,100.0×150.0 | 左 | no | 760 | 5780 | 1.6188 | 150 | 700 | 3000 | 3.2646 | 5130 | 3000 | 0 | 0.24282 | 0.2205 | 1.47 | 1.79695 | 670 | 730 | 170 | 4.05 | 男性用トイレ | ＜ゾーン番号＞
SD4 | 2FL | 1030 | SD4 | SD4 | 店舗 | 209 | no | 2FL | 2 | W7 | EVホール | ＜ゾーン番号＞ | インテリア | 900.0×2,100.0 | 1,030.0×2,165.0 | 930.0×2,115.0 | 900.0×2,100.0×150.0 | 左 | no | 960 | 6180 | 2.0448 | 150 | 900 | 3000 | 3.7566 | 5130 | 3000 | 0 | 0.30672 | 0.2835 | 1.89 | 2.22995 | 870 | 930 | 170 | 4.05 | 店舗 | 209
SD5 | 2FL | 1030 | SD5 | SD5 | 店舗 | 210 | no | 2FL | 2 | W7 | EVホール | ＜ゾーン番号＞ | インテリア | 900.0×2,100.0 | 1,030.0×2,165.0 | 930.0×2,115.0 | 900.0×2,100.0×150.0 | 右 | no | 960 | 6180 | 2.0448 | 150 | 900 | 3000 | 3.7566 | 5130 | 3000 | 0 | 0.30672 | 0.2835 | 1.89 | 2.22995 | 870 | 930 | 170 | 4.05 | 店舗 | 210
SD4 | 2FL | 1030 | SD4 | SD4 | 店舗 | 205 | no | 2FL | 2 | W3 | 廊下 | ＜ゾーン番号＞ | インテリア | 900.0×2,100.0 | 1,030.0×2,165.0 | 930.0×2,115.0 | 900.0×2,100.0×150.0 | 右 | no | 960 | 6180 | 2.0448 | 150 | 900 | 3000 | 3.7566 | 5130 | 3000 | 0 | 0.30672 | 0.2835 | 1.89 | 2.22995 | 870 | 930 | 170 | 4.05 | 店舗 | 205
SD5 | 2FL | 1030 | SD5 | SD5 | 店舗 | 204 | no | 2FL | 2 | W3 | 廊下 | ＜ゾーン番号＞ | インテリア | 900.0×2,100.0 | 1,030.0×2,165.0 | 930.0×2,115.0 | 900.0×2,100.0×150.0 | 左 | no | 960 | 6180 | 2.0448 | 150 | 900 | 3000 | 3.7566 | 5130 | 3000 | 0 | 0.30672 | 0.2835 | 1.89 | 2.22995 | 870 | 930 | 170 | 4.05 | 店舗 | 204
FSD2 | 2FL | 1230 | FSD2 | FSD2 | 避難階段 | ＜ゾーン番号＞ | no | 2FL | 2 | W0 | EVホール | ＜ゾーン番号＞ | エクステリア | 1,100.0×2,100.0 | 1,230.0×2,165.0 | 1,130.0×2,115.0 | 1,100.0×2,100.0×250.0 | 右 | yes | 1160 | 6580 | 2.4708 | 250 | 1100 | 3000 | 5.3266 | 5130 | 3000 | 0 | 0.6177 | 0.5775 | 2.31 | 2.66295 | 1070 | 1130 | 270 | 4.05 | 避難階段 | ＜ゾーン番号＞
SD4 | 2FL | 1030 | SD4 | SD4 | 店舗 | 203 | no | 2FL | 2 | W4 | EVホール | ＜ゾーン番号＞ | インテリア | 900.0×2,100.0 | 1,030.0×2,165.0 | 930.0×2,115.0 | 900.0×2,100.0×150.0 | 左 | no | 960 | 6180 | 2.0448 | 150 | 900 | 3000 | 3.7566 | 5130 | 3000 | 0 | 0.30672 | 0.2835 | 1.89 | 2.22995 | 870 | 930 | 170 | 4.05 | 店舗 | 203
SD5 | 2FL | 1030 | SD5 | SD5 | 店舗 | 208 | no | 2FL | 2 | W5 | EVホール | ＜ゾーン番号＞ | インテリア | 900.0×2,100.0 | 1,030.0×2,165.0 | 930.0×2,115.0 | 900.0×2,100.0×150.0 | 左 | no | 960 | 6180 | 2.0448 | 150 | 900 | 3000 | 3.7566 | 5130 | 3000 | 0 | 0.30672 | 0.2835 | 1.89 | 2.22995 | 870 | 930 | 170 | 4.05 | 店舗 | 208
SD4 | 2FL | 1030 | SD4 | SD4 | 店舗 | 207 | no | 2FL | 2 | W5 | EVホール | ＜ゾーン番号＞ | インテリア | 900.0×2,100.0 | 1,030.0×2,165.0 | 930.0×2,115.0 | 900.0×2,100.0×150.0 | 右 | no | 960 | 6180 | 2.0448 | 150 | 900 | 3000 | 3.7566 | 5130 | 3000 | 0 | 0.30672 | 0.2835 | 1.89 | 2.22995 | 870 | 930 | 170 | 4.05 | 店舗 | 207
SD4 | 2FL | 1030 | SD4 | SD4 | 店舗 | 206 | no | 2FL | 2 | W5 | EVホール | ＜ゾーン番号＞ | インテリア | 900.0×2,100.0 | 1,030.0×2,165.0 | 930.0×2,115.0 | 900.0×2,100.0×150.0 | 右 | no | 960 | 6180 | 2.0448 | 150 | 900 | 3000 | 3.7566 | 5130 | 3000 | 0 | 0.30672 | 0.2835 | 1.89 | 2.22995 | 870 | 930 | 170 | 4.05 | 店舗 | 206
SD3 | 2FL | 1030 | SD3 | SD3 | ホール | ＜ゾーン番号＞ | no | 2FL | 2 | W2 | 店舗 | 211 | インテリア | 900.0×2,100.0 | 1,030.0×2,165.0 | 930.0×2,115.0 | 900.0×2,100.0×150.0 | 左 | no | 960 | 6180 | 2.0448 | 150 | 900 | 3000 | 3.7566 | 5130 | 3000 | 0 | 0.30672 | 0.2835 | 1.89 | 2.22995 | 870 | 930 | 170 | 4.05 | ホール | ＜ゾーン番号＞
SD4 | 2FL | 930 | SD4 | SD4 | 女性用トイレ | ＜ゾーン番号＞ | no | 2FL | 2 | W1 | ホール | ＜ゾーン番号＞ | インテリア | 800.0×2,100.0 | 930.0×2,165.0 | 830.0×2,115.0 | 800.0×2,100.0×150.0 | 左 | no | 860 | 5980 | 1.8318 | 150 | 800 | 3000 | 3.5106 | 5130 | 3000 | 0 | 0.27477 | 0.252 | 1.68 | 2.01345 | 770 | 830 | 170 | 4.05 | 女性用トイレ | ＜ゾーン番号＞
SD3 | 2FL | 930 | SD3 | SD3 | 男性用トイレ | ＜ゾーン番号＞ | no | 2FL | 2 | W2 | ホール | ＜ゾーン番号＞ | インテリア | 800.0×2,100.0 | 930.0×2,165.0 | 830.0×2,115.0 | 800.0×2,100.0×150.0 | 右 | no | 860 | 5980 | 1.8318 | 150 | 800 | 3000 | 3.5106 | 5130 | 3000 | 0 | 0.27477 | 0.252 | 1.68 | 2.01345 | 770 | 830 | 170 | 4.05 | 男性用トイレ | ＜ゾーン番号＞
FSD2 | 3FL | 1230 | FSD2 | FSD2 | 階段室 | ＜ゾーン番号＞ | no | 3FL | 3 | W4 | EVホール | ＜ゾーン番号＞ | インテリア | 1,100.0×2,100.0 | 1,230.0×2,165.0 | 1,130.0×2,115.0 | 1,100.0×2,100.0×150.0 | 左 | no | 1160 | 6580 | 2.4708 | 150 | 1100 | 6000 | 4.2486 | 8130 | 6000 | 0 | 0.37062 | 0.3465 | 2.31 | 2.66295 | 1070 | 1130 | 170 | 7.05 | 階段室 | ＜ゾーン番号＞
SD7 | 3FL | 1030 | SD7 | SD7 | 事務室 | 303 | no | 3FL | 3 | W4 | EVホール | ＜ゾーン番号＞ | インテリア | 900.0×2,100.0 | 1,030.0×2,165.0 | 930.0×2,115.0 | 900.0×2,100.0×150.0 | 左 | no | 960 | 6180 | 2.0448 | 150 | 900 | 6000 | 3.7566 | 8130 | 6000 | 0 | 0.30672 | 0.2835 | 1.89 | 2.22995 | 870 | 930 | 170 | 7.05 | 事務室 | 303
SD8 | 3FL | 1030 | SD8 | SD8 | 事務室 | 308 | no | 3FL | 3 | W7 | EVホール | ＜ゾーン番号＞ | インテリア | 900.0×2,100.0 | 1,030.0×2,165.0 | 930.0×2,115.0 | 900.0×2,100.0×150.0 | 右 | no | 960 | 6180 | 2.0448 | 150 | 900 | 6000 | 3.7566 | 8130 | 6000 | 0 | 0.30672 | 0.2835 | 1.89 | 2.22995 | 870 | 930 | 170 | 7.05 | 事務室 | 308
SD9 | 3FL | 1030 | SD9 | SD9 | 事務室 | 309 | no | 3FL | 3 | W7 | EVホール | ＜ゾーン番号＞ | インテリア | 900.0×2,100.0 | 1,030.0×2,165.0 | 930.0×2,115.0 | 900.0×2,100.0×150.0 | 左 | no | 960 | 6180 | 2.0448 | 150 | 900 | 6000 | 3.7566 | 8130 | 6000 | 0 | 0.30672 | 0.2835 | 1.89 | 2.22995 | 870 | 930 | 170 | 7.05 | 事務室 | 309
SD0 | 3FL | 1030 | SD0 | SD0 | 事務室 | 311 | no | 3FL | 3 | W3 | 廊下 | ＜ゾーン番号＞ | インテリア | 900.0×2,100.0 | 1,030.0×2,165.0 | 930.0×2,115.0 | 900.0×2,100.0×150.0 | 左 | no | 960 | 6180 | 2.0448 | 150 | 900 | 6000 | 3.7566 | 8130 | 6000 | 0 | 0.30672 | 0.2835 | 1.89 | 2.22995 | 870 | 930 | 170 | 7.05 | 事務室 | 311
SD1 | 3FL | 1030 | SD1 | SD1 | 事務室 | 310 | no | 3FL | 3 | W3 | 廊下 | ＜ゾーン番号＞ | インテリア | 900.0×2,100.0 | 1,030.0×2,165.0 | 930.0×2,115.0 | 900.0×2,100.0×150.0 | 右 | no | 960 | 6180 | 2.0448 | 150 | 900 | 6000 | 3.7566 | 8130 | 6000 | 0 | 0.30672 | 0.2835 | 1.89 | 2.22995 | 870 | 930 | 170 | 7.05 | 事務室 | 310
FSD2 | 3FL | 1230 | FSD2 | FSD2 | 避難階段 | ＜ゾーン番号＞ | no | 3FL | 3 | W0 | EVホール | ＜ゾーン番号＞ | エクステリア | 1,100.0×2,100.0 | 1,230.0×2,165.0 | 1,130.0×2,115.0 | 1,100.0×2,100.0×250.0 | 右 | yes | 1160 | 6580 | 2.4708 | 250 | 1100 | 6000 | 5.3266 | 8130 | 6000 | 0 | 0.6177 | 0.5775 | 2.31 | 2.66295 | 1070 | 1130 | 270 | 7.05 | 避難階段 | ＜ゾーン番号＞
SD9 | 3FL | 1030 | SD9 | SD9 | 事務室 | 301 | no | 3FL | 3 | W4 | 廊下 | ＜ゾーン番号＞ | インテリア | 900.0×2,100.0 | 1,030.0×2,165.0 | 930.0×2,115.0 | 900.0×2,100.0×150.0 | 右 | no | 960 | 6180 | 2.0448 | 150 | 900 | 6000 | 3.7566 | 8130 | 6000 | 0 | 0.30672 | 0.2835 | 1.89 | 2.22995 | 870 | 930 | 170 | 7.05 | 事務室 | 301
SD9 | 3FL | 1030 | SD9 | SD9 | 事務室 | 302 | no | 3FL | 3 | W4 | 廊下 | ＜ゾーン番号＞ | インテリア | 900.0×2,100.0 | 1,030.0×2,165.0 | 930.0×2,115.0 | 900.0×2,100.0×150.0 | 左 | no | 960 | 6180 | 2.0448 | 150 | 900 | 6000 | 3.7566 | 8130 | 6000 | 0 | 0.30672 | 0.2835 | 1.89 | 2.22995 | 870 | 930 | 170 | 7.05 | 事務室 | 302
SD5 | 3FL | 1030 | SD5 | SD5 | 事務室 | 304 | no | 3FL | 3 | W5 | EVホール | ＜ゾーン番号＞ | インテリア | 900.0×2,100.0 | 1,030.0×2,165.0 | 930.0×2,115.0 | 900.0×2,100.0×150.0 | 右 | no | 960 | 6180 | 2.0448 | 150 | 900 | 6000 | 3.7566 | 8130 | 6000 | 0 | 0.30672 | 0.2835 | 1.89 | 2.22995 | 870 | 930 | 170 | 7.05 | 事務室 | 304
SD6 | 3FL | 1030 | SD6 | SD6 | 事務室 | 305 | no | 3FL | 3 | W5 | EVホール | ＜ゾーン番号＞ | インテリア | 900.0×2,100.0 | 1,030.0×2,165.0 | 930.0×2,115.0 | 900.0×2,100.0×150.0 | 右 | no | 960 | 6180 | 2.0448 | 150 | 900 | 6000 | 3.7566 | 8130 | 6000 | 0 | 0.30672 | 0.2835 | 1.89 | 2.22995 | 870 | 930 | 170 | 7.05 | 事務室 | 305
SD6 | 3FL | 1030 | SD6 | SD6 | 事務室 | 306 | no | 3FL | 3 | W5 | EVホール | ＜ゾーン番号＞ | インテリア | 900.0×2,100.0 | 1,030.0×2,165.0 | 930.0×2,115.0 | 900.0×2,100.0×150.0 | 右 | no | 960 | 6180 | 2.0448 | 150 | 900 | 6000 | 3.7566 | 8130 | 6000 | 0 | 0.30672 | 0.2835 | 1.89 | 2.22995 | 870 | 930 | 170 | 7.05 | 事務室 | 306
SD7 | 3FL | 1030 | SD7 | SD7 | 事務室 | 307 | no | 3FL | 3 | W5 | EVホール | ＜ゾーン番号＞ | インテリア | 900.0×2,100.0 | 1,030.0×2,165.0 | 930.0×2,115.0 | 900.0×2,100.0×150.0 | 左 | no | 960 | 6180 | 2.0448 | 150 | 900 | 6000 | 3.7566 | 8130 | 6000 | 0 | 0.30672 | 0.2835 | 1.89 | 2.22995 | 870 | 930 | 170 | 7.05 | 事務室 | 307
SD3 | 3FL | 1030 | SD3 | SD3 | 事務室 | 315 | no | 3FL | 3 | W9 | EVホール | ＜ゾーン番号＞ | インテリア | 900.0×2,100.0 | 1,030.0×2,165.0 | 930.0×2,115.0 | 900.0×2,100.0×150.0 | 左 | no | 960 | 6180 | 2.0448 | 150 | 900 | 6000 | 3.7566 | 8130 | 6000 | 0 | 0.30672 | 0.2835 | 1.89 | 2.22995 | 870 | 930 | 170 | 7.05 | 事務室 | 315
SD4 | 3FL | 1030 | SD4 | SD4 | 事務室 | 316 | no | 3FL | 3 | W9 | EVホール | ＜ゾーン番号＞ | インテリア | 900.0×2,100.0 | 1,030.0×2,165.0 | 930.0×2,115.0 | 900.0×2,100.0×150.0 | 右 | no | 960 | 6180 | 2.0448 | 150 | 900 | 6000 | 3.7566 | 8130 | 6000 | 0 | 0.30672 | 0.2835 | 1.89 | 2.22995 | 870 | 930 | 170 | 7.05 | 事務室 | 316
SD5 | 3FL | 1030 | SD5 | SD5 | 事務室 | 314 | no | 3FL | 3 | W9 | EVホール | ＜ゾーン番号＞ | インテリア | 900.0×2,100.0 | 1,030.0×2,165.0 | 930.0×2,115.0 | 900.0×2,100.0×150.0 | 右 | no | 960 | 6180 | 2.0448 | 150 | 900 | 6000 | 3.7566 | 8130 | 6000 | 0 | 0.30672 | 0.2835 | 1.89 | 2.22995 | 870 | 930 | 170 | 7.05 | 事務室 | 314
SD6 | 3FL | 1030 | SD6 | SD6 | 事務室 | 313 | no | 3FL | 3 | W9 | EVホール | ＜ゾーン番号＞ | インテリア | 900.0×2,100.0 | 1,030.0×2,165.0 | 930.0×2,115.0 | 900.0×2,100.0×150.0 | 左 | no | 960 | 6180 | 2.0448 | 150 | 900 | 6000 | 3.7566 | 8130 | 6000 | 0 | 0.30672 | 0.2835 | 1.89 | 2.22995 | 870 | 930 | 170 | 7.05 | 事務室 | 313
SD3 | 3FL | 830 | SD3 | SD3 | 女性用トイレ | ＜ゾーン番号＞ | no | 3FL | 3 | W4 | EVホール | ＜ゾーン番号＞ | インテリア | 700.0×2,100.0 | 830.0×2,165.0 | 730.0×2,115.0 | 700.0×2,100.0×150.0 | 左 | no | 760 | 5780 | 1.6188 | 150 | 700 | 6000 | 3.2646 | 8130 | 6000 | 0 | 0.24282 | 0.2205 | 1.47 | 1.79695 | 670 | 730 | 170 | 7.05 | 女性用トイレ | ＜ゾーン番号＞
SD3 | 3FL | 830 | SD3 | SD3 | 男性用トイレ | ＜ゾーン番号＞ | no | 3FL | 3 | W4 | EVホール | ＜ゾーン番号＞ | インテリア | 700.0×2,100.0 | 830.0×2,165.0 | 730.0×2,115.0 | 700.0×2,100.0×150.0 | 左 | no | 760 | 5780 | 1.6188 | 150 | 700 | 6000 | 3.2646 | 8130 | 6000 | 0 | 0.24282 | 0.2205 | 1.47 | 1.79695 | 670 | 730 | 170 | 7.05 | 男性用トイレ | ＜ゾーン番号＞
4FLSD3 | 4FL | 1030 | SD3 | 4FLSD3 | 事務室 | 315 | yes | 4FL | 4 | W9 | EVホール | ＜ゾーン番号＞ | インテリア | 900.0×2,100.0 | 1,030.0×2,165.0 | 930.0×2,115.0 | 900.0×2,100.0×150.0 | 左 | no | 960 | 6180 | 2.0448 | 150 | 900 | 9000 | 3.7566 | 11130 | 9000 | 0 | 0.30672 | 0.2835 | 1.89 | 2.22995 | 870 | 930 | 170 | 10.05 | 事務室 | 315 | 4FL
4FLSD4 | 4FL | 1030 | SD4 | 4FLSD4 | 事務室 | 316 | yes | 4FL | 4 | W9 | EVホール | ＜ゾーン番号＞ | インテリア | 900.0×2,100.0 | 1,030.0×2,165.0 | 930.0×2,115.0 | 900.0×2,100.0×150.0 | 右 | no | 960 | 6180 | 2.0448 | 150 | 900 | 9000 | 3.7566 | 11130 | 9000 | 0 | 0.30672 | 0.2835 | 1.89 | 2.22995 | 870 | 930 | 170 | 10.05 | 事務室 | 316 | 4FL
4FLSD5 | 4FL | 1030 | SD5 | 4FLSD5 | 事務室 | 314 | yes | 4FL | 4 | W9 | EVホール | ＜ゾーン番号＞ | インテリア | 900.0×2,100.0 | 1,030.0×2,165.0 | 930.0×2,115.0 | 900.0×2,100.0×150.0 | 右 | no | 960 | 6180 | 2.0448 | 150 | 900 | 9000 | 3.7566 | 11130 | 9000 | 0 | 0.30672 | 0.2835 | 1.89 | 2.22995 | 870 | 930 | 170 | 10.05 | 事務室 | 314 | 4FL
4FLSD6 | 4FL | 1030 | SD6 | 4FLSD6 | 事務室 | 313 | yes | 4FL | 4 | W9 | EVホール | ＜ゾーン番号＞ | インテリア | 900.0×2,100.0 | 1,030.0×2,165.0 | 930.0×2,115.0 | 900.0×2,100.0×150.0 | 左 | no | 960 | 6180 | 2.0448 | 150 | 900 | 9000 | 3.7566 | 11130 | 9000 | 0 | 0.30672 | 0.2835 | 1.89 | 2.22995 | 870 | 930 | 170 | 10.05 | 事務室 | 313 | 4FL
4FLFSD2 | 4FL | 1230 | FSD2 | 4FLFSD2 | 階段室 | ＜ゾーン番号＞ | yes | 4FL | 4 | W4 | EVホール | ＜ゾーン番号＞ | インテリア | 1,100.0×2,100.0 | 1,230.0×2,165.0 | 1,130.0×2,115.0 | 1,100.0×2,100.0×150.0 | 左 | no | 1160 | 6580 | 2.4708 | 150 | 1100 | 9000 | 4.2486 | 11130 | 9000 | 0 | 0.37062 | 0.3465 | 2.31 | 2.66295 | 1070 | 1130 | 170 | 10.05 | 階段室 | ＜ゾーン番号＞ | 4FL
4FLSD7 | 4FL | 1030 | SD7 | 4FLSD7 | 事務室 | 303 | yes | 4FL | 4 | W4 | EVホール | ＜ゾーン番号＞ | インテリア | 900.0×2,100.0 | 1,030.0×2,165.0 | 930.0×2,115.0 | 900.0×2,100.0×150.0 | 左 | no | 960 | 6180 | 2.0448 | 150 | 900 | 9000 | 3.7566 | 11130 | 9000 | 0 | 0.30672 | 0.2835 | 1.89 | 2.22995 | 870 | 930 | 170 | 10.05 | 事務室 | 303 | 4FL
4FLSD8 | 4FL | 1030 | SD8 | 4FLSD8 | 事務室 | 308 | yes | 4FL | 4 | W7 | EVホール | ＜ゾーン番号＞ | インテリア | 900.0×2,100.0 | 1,030.0×2,165.0 | 930.0×2,115.0 | 900.0×2,100.0×150.0 | 右 | no | 960 | 6180 | 2.0448 | 150 | 900 | 9000 | 3.7566 | 11130 | 9000 | 0 | 0.30672 | 0.2835 | 1.89 | 2.22995 | 870 | 930 | 170 | 10.05 | 事務室 | 308 | 4FL
4FLSD9 | 4FL | 1030 | SD9 | 4FLSD9 | 事務室 | 309 | yes | 4FL | 4 | W7 | EVホール | ＜ゾーン番号＞ | インテリア | 900.0×2,100.0 | 1,030.0×2,165.0 | 930.0×2,115.0 | 900.0×2,100.0×150.0 | 左 | no | 960 | 6180 | 2.0448 | 150 | 900 | 9000 | 3.7566 | 11130 | 9000 | 0 | 0.30672 | 0.2835 | 1.89 | 2.22995 | 870 | 930 | 170 | 10.05 | 事務室 | 309 | 4FL
4FLSD0 | 4FL | 1030 | SD0 | 4FLSD0 | 事務室 | 311 | yes | 4FL | 4 | W3 | 廊下 | ＜ゾーン番号＞ | インテリア | 900.0×2,100.0 | 1,030.0×2,165.0 | 930.0×2,115.0 | 900.0×2,100.0×150.0 | 左 | no | 960 | 6180 | 2.0448 | 150 | 900 | 9000 | 3.7566 | 11130 | 9000 | 0 | 0.30672 | 0.2835 | 1.89 | 2.22995 | 870 | 930 | 170 | 10.05 | 事務室 | 311 | 4FL
4FLSD1 | 4FL | 1030 | SD1 | 4FLSD1 | 事務室 | 310 | yes | 4FL | 4 | W3 | 廊下 | ＜ゾーン番号＞ | インテリア | 900.0×2,100.0 | 1,030.0×2,165.0 | 930.0×2,115.0 | 900.0×2,100.0×150.0 | 右 | no | 960 | 6180 | 2.0448 | 150 | 900 | 9000 | 3.7566 | 11130 | 9000 | 0 | 0.30672 | 0.2835 | 1.89 | 2.22995 | 870 | 930 | 170 | 10.05 | 事務室 | 310 | 4FL
4FLFSD2 | 4FL | 1230 | FSD2 | 4FLFSD2 | 避難階段 | ＜ゾーン番号＞ | yes | 4FL | 4 | W0 | EVホール | ＜ゾーン番号＞ | エクステリア | 1,100.0×2,100.0 | 1,230.0×2,165.0 | 1,130.0×2,115.0 | 1,100.0×2,100.0×250.0 | 右 | yes | 1160 | 6580 | 2.4708 | 250 | 1100 | 9000 | 5.3266 | 11130 | 9000 | 0 | 0.6177 | 0.5775 | 2.31 | 2.66295 | 1070 | 1130 | 270 | 10.05 | 避難階段 | ＜ゾーン番号＞ | 4FL
4FLSD9 | 4FL | 1030 | SD9 | 4FLSD9 | 事務室 | 301 | yes | 4FL | 4 | W4 | 廊下 | ＜ゾーン番号＞ | インテリア | 900.0×2,100.0 | 1,030.0×2,165.0 | 930.0×2,115.0 | 900.0×2,100.0×150.0 | 右 | no | 960 | 6180 | 2.0448 | 150 | 900 | 9000 | 3.7566 | 11130 | 9000 | 0 | 0.30672 | 0.2835 | 1.89 | 2.22995 | 870 | 930 | 170 | 10.05 | 事務室 | 301 | 4FL
4FLSD9 | 4FL | 1030 | SD9 | 4FLSD9 | 事務室 | 302 | yes | 4FL | 4 | W4 | 廊下 | ＜ゾーン番号＞ | インテリア | 900.0×2,100.0 | 1,030.0×2,165.0 | 930.0×2,115.0 | 900.0×2,100.0×150.0 | 左 | no | 960 | 6180 | 2.0448 | 150 | 900 | 9000 | 3.7566 | 11130 | 9000 | 0 | 0.30672 | 0.2835 | 1.89 | 2.22995 | 870 | 930 | 170 | 10.05 | 事務室 | 302 | 4FL
4FLSD5 | 4FL | 1030 | SD5 | 4FLSD5 | 事務室 | 304 | yes | 4FL | 4 | W5 | EVホール | ＜ゾーン番号＞ | インテリア | 900.0×2,100.0 | 1,030.0×2,165.0 | 930.0×2,115.0 | 900.0×2,100.0×150.0 | 右 | no | 960 | 6180 | 2.0448 | 150 | 900 | 9000 | 3.7566 | 11130 | 9000 | 0 | 0.30672 | 0.2835 | 1.89 | 2.22995 | 870 | 930 | 170 | 10.05 | 事務室 | 304 | 4FL
4FLSD6 | 4FL | 1030 | SD6 | 4FLSD6 | 事務室 | 305 | yes | 4FL | 4 | W5 | EVホール | ＜ゾーン番号＞ | インテリア | 900.0×2,100.0 | 1,030.0×2,165.0 | 930.0×2,115.0 | 900.0×2,100.0×150.0 | 右 | no | 960 | 6180 | 2.0448 | 150 | 900 | 9000 | 3.7566 | 11130 | 9000 | 0 | 0.30672 | 0.2835 | 1.89 | 2.22995 | 870 | 930 | 170 | 10.05 | 事務室 | 305 | 4FL
4FLSD6 | 4FL | 1030 | SD6 | 4FLSD6 | 事務室 | 306 | yes | 4FL | 4 | W5 | EVホール | ＜ゾーン番号＞ | インテリア | 900.0×2,100.0 | 1,030.0×2,165.0 | 930.0×2,115.0 | 900.0×2,100.0×150.0 | 右 | no | 960 | 6180 | 2.0448 | 150 | 900 | 9000 | 3.7566 | 11130 | 9000 | 0 | 0.30672 | 0.2835 | 1.89 | 2.22995 | 870 | 930 | 170 | 10.05 | 事務室 | 306 | 4FL
4FLSD7 | 4FL | 1030 | SD7 | 4FLSD7 | 事務室 | 307 | yes | 4FL | 4 | W5 | EVホール | ＜ゾーン番号＞ | インテリア | 900.0×2,100.0 | 1,030.0×2,165.0 | 930.0×2,115.0 | 900.0×2,100.0×150.0 | 左 | no | 960 | 6180 | 2.0448 | 150 | 900 | 9000 | 3.7566 | 11130 | 9000 | 0 | 0.30672 | 0.2835 | 1.89 | 2.22995 | 870 | 930 | 170 | 10.05 | 事務室 | 307 | 4FL
4FLSD3 | 4FL | 830 | SD3 | 4FLSD3 | 女性用トイレ | ＜ゾーン番号＞ | yes | 4FL | 4 | W4 | EVホール | ＜ゾーン番号＞ | インテリア | 700.0×2,100.0 | 830.0×2,165.0 | 730.0×2,115.0 | 700.0×2,100.0×150.0 | 左 | no | 760 | 5780 | 1.6188 | 150 | 700 | 9000 | 3.2646 | 11130 | 9000 | 0 | 0.24282 | 0.2205 | 1.47 | 1.79695 | 670 | 730 | 170 | 10.05 | 女性用トイレ | ＜ゾーン番号＞ | 4FL
4FLSD3 | 4FL | 830 | SD3 | 4FLSD3 | 男性用トイレ | ＜ゾーン番号＞ | yes | 4FL | 4 | W4 | EVホール | ＜ゾーン番号＞ | インテリア | 700.0×2,100.0 | 830.0×2,165.0 | 730.0×2,115.0 | 700.0×2,100.0×150.0 | 左 | no | 760 | 5780 | 1.6188 | 150 | 700 | 9000 | 3.2646 | 11130 | 9000 | 0 | 0.24282 | 0.2205 | 1.47 | 1.79695 | 670 | 730 | 170 | 10.05 | 男性用トイレ | ＜ゾーン番号＞ | 4FL
5FLSD3 | 5FL | 1030 | SD3 | 5FLSD3 | 事務室 | 315 | yes | 5FL | 5 | W9 | EVホール | ＜ゾーン番号＞ | インテリア | 900.0×2,100.0 | 1,030.0×2,165.0 | 930.0×2,115.0 | 900.0×2,100.0×150.0 | 左 | no | 960 | 6180 | 2.0448 | 150 | 900 | 12000 | 3.7566 | 14130 | 12000 | 0 | 0.30672 | 0.2835 | 1.89 | 2.22995 | 870 | 930 | 170 | 13.05 | 事務室 | 315 | 5FL
5FLSD4 | 5FL | 1030 | SD4 | 5FLSD4 | 事務室 | 316 | yes | 5FL | 5 | W9 | EVホール | ＜ゾーン番号＞ | インテリア | 900.0×2,100.0 | 1,030.0×2,165.0 | 930.0×2,115.0 | 900.0×2,100.0×150.0 | 右 | no | 960 | 6180 | 2.0448 | 150 | 900 | 12000 | 3.7566 | 14130 | 12000 | 0 | 0.30672 | 0.2835 | 1.89 | 2.22995 | 870 | 930 | 170 | 13.05 | 事務室 | 316 | 5FL
5FLSD5 | 5FL | 1030 | SD5 | 5FLSD5 | 事務室 | 314 | yes | 5FL | 5 | W9 | EVホール | ＜ゾーン番号＞ | インテリア | 900.0×2,100.0 | 1,030.0×2,165.0 | 930.0×2,115.0 | 900.0×2,100.0×150.0 | 右 | no | 960 | 6180 | 2.0448 | 150 | 900 | 12000 | 3.7566 | 14130 | 12000 | 0 | 0.30672 | 0.2835 | 1.89 | 2.22995 | 870 | 930 | 170 | 13.05 | 事務室 | 314 | 5FL
5FLSD6 | 5FL | 1030 | SD6 | 5FLSD6 | 事務室 | 313 | yes | 5FL | 5 | W9 | EVホール | ＜ゾーン番号＞ | インテリア | 900.0×2,100.0 | 1,030.0×2,165.0 | 930.0×2,115.0 | 900.0×2,100.0×150.0 | 左 | no | 960 | 6180 | 2.0448 | 150 | 900 | 12000 | 3.7566 | 14130 | 12000 | 0 | 0.30672 | 0.2835 | 1.89 | 2.22995 | 870 | 930 | 170 | 13.05 | 事務室 | 313 | 5FL
5FLFSD2 | 5FL | 1230 | FSD2 | 5FLFSD2 | 階段室 | ＜ゾーン番号＞ | yes | 5FL | 5 | W4 | EVホール | ＜ゾーン番号＞ | インテリア | 1,100.0×2,100.0 | 1,230.0×2,165.0 | 1,130.0×2,115.0 | 1,100.0×2,100.0×150.0 | 左 | no | 1160 | 6580 | 2.4708 | 150 | 1100 | 12000 | 4.2486 | 14130 | 12000 | 0 | 0.37062 | 0.3465 | 2.31 | 2.66295 | 1070 | 1130 | 170 | 13.05 | 階段室 | ＜ゾーン番号＞ | 5FL
5FLSD7 | 5FL | 1030 | SD7 | 5FLSD7 | 事務室 | 303 | yes | 5FL | 5 | W4 | EVホール | ＜ゾーン番号＞ | インテリア | 900.0×2,100.0 | 1,030.0×2,165.0 | 930.0×2,115.0 | 900.0×2,100.0×150.0 | 左 | no | 960 | 6180 | 2.0448 | 150 | 900 | 12000 | 3.7566 | 14130 | 12000 | 0 | 0.30672 | 0.2835 | 1.89 | 2.22995 | 870 | 930 | 170 | 13.05 | 事務室 | 303 | 5FL
5FLSD8 | 5FL | 1030 | SD8 | 5FLSD8 | 事務室 | 308 | yes | 5FL | 5 | W7 | EVホール | ＜ゾーン番号＞ | インテリア | 900.0×2,100.0 | 1,030.0×2,165.0 | 930.0×2,115.0 | 900.0×2,100.0×150.0 | 右 | no | 960 | 6180 | 2.0448 | 150 | 900 | 12000 | 3.7566 | 14130 | 12000 | 0 | 0.30672 | 0.2835 | 1.89 | 2.22995 | 870 | 930 | 170 | 13.05 | 事務室 | 308 | 5FL
5FLSD9 | 5FL | 1030 | SD9 | 5FLSD9 | 事務室 | 309 | yes | 5FL | 5 | W7 | EVホール | ＜ゾーン番号＞ | インテリア | 900.0×2,100.0 | 1,030.0×2,165.0 | 930.0×2,115.0 | 900.0×2,100.0×150.0 | 左 | no | 960 | 6180 | 2.0448 | 150 | 900 | 12000 | 3.7566 | 14130 | 12000 | 0 | 0.30672 | 0.2835 | 1.89 | 2.22995 | 870 | 930 | 170 | 13.05 | 事務室 | 309 | 5FL
5FLSD0 | 5FL | 1030 | SD0 | 5FLSD0 | 事務室 | 311 | yes | 5FL | 5 | W3 | 廊下 | ＜ゾーン番号＞ | インテリア | 900.0×2,100.0 | 1,030.0×2,165.0 | 930.0×2,115.0 | 900.0×2,100.0×150.0 | 左 | no | 960 | 6180 | 2.0448 | 150 | 900 | 12000 | 3.7566 | 14130 | 12000 | 0 | 0.30672 | 0.2835 | 1.89 | 2.22995 | 870 | 930 | 170 | 13.05 | 事務室 | 311 | 5FL
5FLSD1 | 5FL | 1030 | SD1 | 5FLSD1 | 事務室 | 310 | yes | 5FL | 5 | W3 | 廊下 | ＜ゾーン番号＞ | インテリア | 900.0×2,100.0 | 1,030.0×2,165.0 | 930.0×2,115.0 | 900.0×2,100.0×150.0 | 右 | no | 960 | 6180 | 2.0448 | 150 | 900 | 12000 | 3.7566 | 14130 | 12000 | 0 | 0.30672 | 0.2835 | 1.89 | 2.22995 | 870 | 930 | 170 | 13.05 | 事務室 | 310 | 5FL
5FLFSD2 | 5FL | 1230 | FSD2 | 5FLFSD2 | 避難階段 | ＜ゾーン番号＞ | yes | 5FL | 5 | W0 | EVホール | ＜ゾーン番号＞ | エクステリア | 1,100.0×2,100.0 | 1,230.0×2,165.0 | 1,130.0×2,115.0 | 1,100.0×2,100.0×250.0 | 右 | yes | 1160 | 6580 | 2.4708 | 250 | 1100 | 12000 | 5.3266 | 14130 | 12000 | 0 | 0.6177 | 0.5775 | 2.31 | 2.66295 | 1070 | 1130 | 270 | 13.05 | 避難階段 | ＜ゾーン番号＞ | 5FL
5FLSD9 | 5FL | 1030 | SD9 | 5FLSD9 | 事務室 | 301 | yes | 5FL | 5 | W4 | 廊下 | ＜ゾーン番号＞ | インテリア | 900.0×2,100.0 | 1,030.0×2,165.0 | 930.0×2,115.0 | 900.0×2,100.0×150.0 | 右 | no | 960 | 6180 | 2.0448 | 150 | 900 | 12000 | 3.7566 | 14130 | 12000 | 0 | 0.30672 | 0.2835 | 1.89 | 2.22995 | 870 | 930 | 170 | 13.05 | 事務室 | 301 | 5FL
5FLSD9 | 5FL | 1030 | SD9 | 5FLSD9 | 事務室 | 302 | yes | 5FL | 5 | W4 | 廊下 | ＜ゾーン番号＞ | インテリア | 900.0×2,100.0 | 1,030.0×2,165.0 | 930.0×2,115.0 | 900.0×2,100.0×150.0 | 左 | no | 960 | 6180 | 2.0448 | 150 | 900 | 12000 | 3.7566 | 14130 | 12000 | 0 | 0.30672 | 0.2835 | 1.89 | 2.22995 | 870 | 930 | 170 | 13.05 | 事務室 | 302 | 5FL
5FLSD5 | 5FL | 1030 | SD5 | 5FLSD5 | 事務室 | 304 | yes | 5FL | 5 | W5 | EVホール | ＜ゾーン番号＞ | インテリア | 900.0×2,100.0 | 1,030.0×2,165.0 | 930.0×2,115.0 | 900.0×2,100.0×150.0 | 右 | no | 960 | 6180 | 2.0448 | 150 | 900 | 12000 | 3.7566 | 14130 | 12000 | 0 | 0.30672 | 0.2835 | 1.89 | 2.22995 | 870 | 930 | 170 | 13.05 | 事務室 | 304 | 5FL
5FLSD6 | 5FL | 1030 | SD6 | 5FLSD6 | 事務室 | 305 | yes | 5FL | 5 | W5 | EVホール | ＜ゾーン番号＞ | インテリア | 900.0×2,100.0 | 1,030.0×2,165.0 | 930.0×2,115.0 | 900.0×2,100.0×150.0 | 右 | no | 960 | 6180 | 2.0448 | 150 | 900 | 12000 | 3.7566 | 14130 | 12000 | 0 | 0.30672 | 0.2835 | 1.89 | 2.22995 | 870 | 930 | 170 | 13.05 | 事務室 | 305 | 5FL
5FLSD6 | 5FL | 1030 | SD6 | 5FLSD6 | 事務室 | 306 | yes | 5FL | 5 | W5 | EVホール | ＜ゾーン番号＞ | インテリア | 900.0×2,100.0 | 1,030.0×2,165.0 | 930.0×2,115.0 | 900.0×2,100.0×150.0 | 右 | no | 960 | 6180 | 2.0448 | 150 | 900 | 12000 | 3.7566 | 14130 | 12000 | 0 | 0.30672 | 0.2835 | 1.89 | 2.22995 | 870 | 930 | 170 | 13.05 | 事務室 | 306 | 5FL
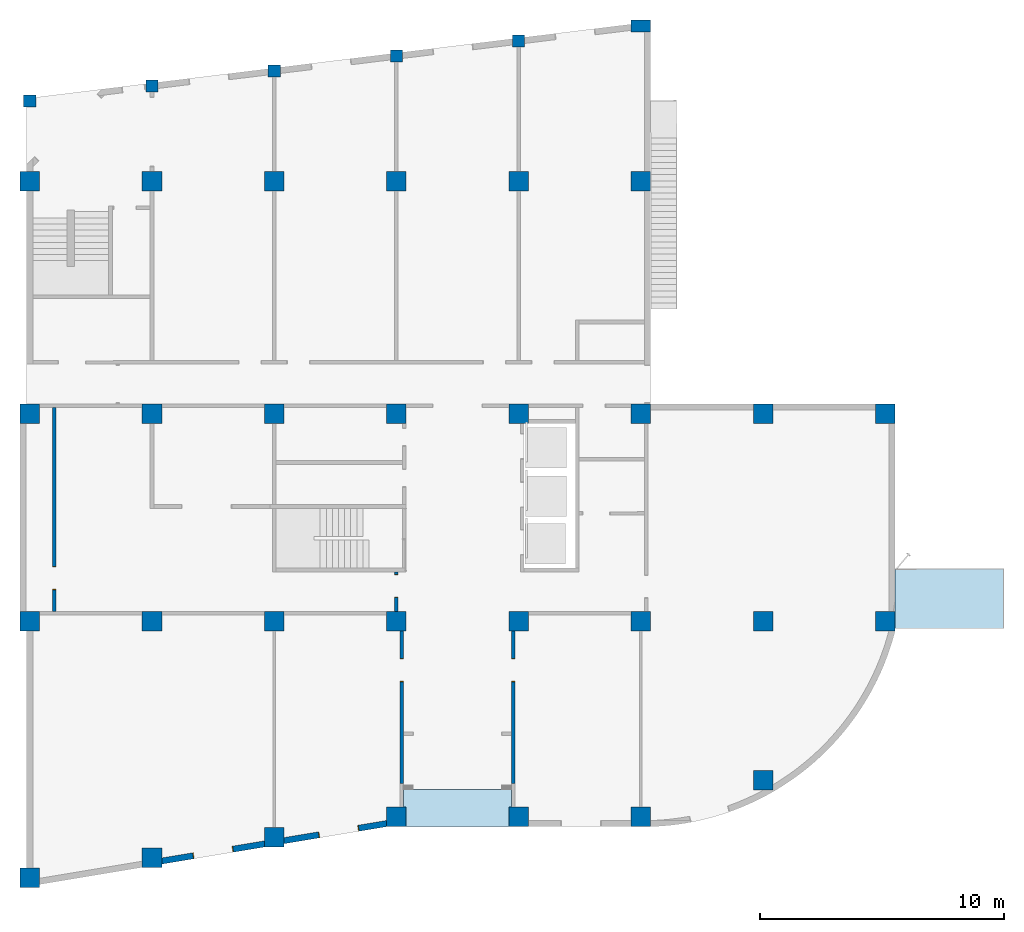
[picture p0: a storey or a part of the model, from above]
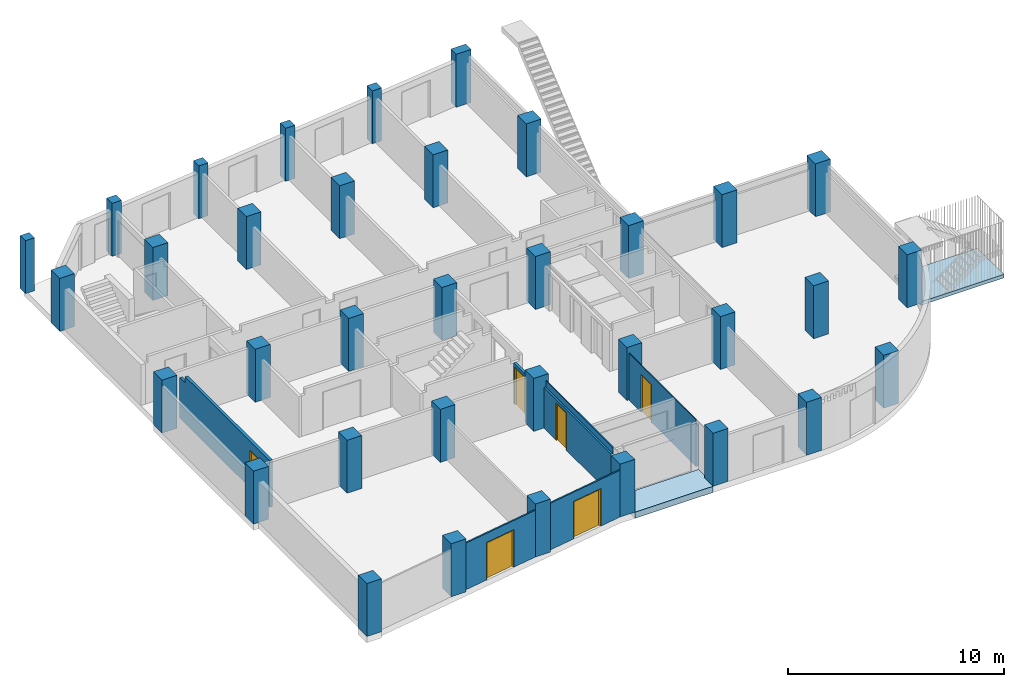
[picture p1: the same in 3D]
Properties of the parts of a building model (IFC2X3), part 6 of 10

# IfcDoor: 片開き戸 (169)
Name | In | OverallWidth (mm) = 窓/ドア外壁側公称開口部幅 (mm) = 窓/ドア外壁反対側公称開口部幅 (mm) = 壁開口幅 (mm) | 要素ID | ホットリンクおよび要素ID | 関連ゾーン名 | 関連ゾーン番号 | ロック状態 | ホームフロア名 | ホームフロア数 | 親ID = 壁ID | ゾーンから | ゾーン番号から | 位置 | 抱き寸法 = ユニット寸法 = 間口寸法 = 公称幅x高さ | 壁開口寸法 | 扉寸法 | 公称幅x高さx厚さ | 方向 | IsExternal | Width (mm) = 窓/ドア外壁側開口部幅 (mm) = 窓/ドア外壁反対側開口部幅 (mm) | Perimeter (mm) | Area (m2) = 窓/ドア外壁側開口部面積 (m2) = 窓/ドア外壁反対側開口部面積 (m2) | Depth (mm) = 壁厚さ (mm) | 幅 (mm) = 抱き幅 (mm) = ユニット幅 (mm) = 開口幅 (ac_egress_width) (mm) = 開口幅 (gs_opening_width) (mm) | GLからの高度 (mm) = 高度 1 (mm) = 高度 2 (mm) = 海抜までの高度 (mm) | 表面積 (m2) = 窓/ドア開口 表面積 (m2) | 上端高度から第1基準レベル (mm) = 上端高度から基準レベル (mm) = 上端高度から海抜 (mm) = 上端高度から第2基準レベル (mm) | 下端高度から第1基準レベル (mm) = 下端高度から基準レベル (mm) = 下端高度から海抜 (mm) = 下端高度から第2基準レベル (mm) | 下端高度から配置フロア (mm) | 窓/ドア開口 開口部体積 (m3) | 窓/ドア開口部公称体積 (m3) | 窓/ドア開口面積 (m2) | 窓/ドア抱き側開口面積 (m2) = 窓/ドア抱き反対側開口面積 (m2) | 有効開口幅 (mm) | 枠内幅 (mm) = 可動部の幅 (mm) | 枠見込 (p3) (mm) | 窓の中心高さ (mm) | ゾーンへ | ゾーン番号へ | ホットリンク マスタID
5FLSD7 | 5FL | 1030 | SD7 | 5FLSD7 | 事務室 | 307 | yes | 5FL | 5 | W5 | EVホール | ＜ゾーン番号＞ | インテリア | 900.0×2,100.0 | 1,030.0×2,165.0 | 930.0×2,115.0 | 900.0×2,100.0×150.0 | 左 | no | 960 | 6180 | 2.0448 | 150 | 900 | 12000 | 3.7566 | 14130 | 12000 | 0 | 0.30672 | 0.2835 | 1.89 | 2.22995 | 870 | 930 | 170 | 13.05 | 事務室 | 307 | 5FL
5FLSD3 | 5FL | 830 | SD3 | 5FLSD3 | 女性用トイレ | ＜ゾーン番号＞ | yes | 5FL | 5 | W4 | EVホール | ＜ゾーン番号＞ | インテリア | 700.0×2,100.0 | 830.0×2,165.0 | 730.0×2,115.0 | 700.0×2,100.0×150.0 | 左 | no | 760 | 5780 | 1.6188 | 150 | 700 | 12000 | 3.2646 | 14130 | 12000 | 0 | 0.24282 | 0.2205 | 1.47 | 1.79695 | 670 | 730 | 170 | 13.05 | 女性用トイレ | ＜ゾーン番号＞ | 5FL
5FLSD3 | 5FL | 830 | SD3 | 5FLSD3 | 男性用トイレ | ＜ゾーン番号＞ | yes | 5FL | 5 | W4 | EVホール | ＜ゾーン番号＞ | インテリア | 700.0×2,100.0 | 830.0×2,165.0 | 730.0×2,115.0 | 700.0×2,100.0×150.0 | 左 | no | 760 | 5780 | 1.6188 | 150 | 700 | 12000 | 3.2646 | 14130 | 12000 | 0 | 0.24282 | 0.2205 | 1.47 | 1.79695 | 670 | 730 | 170 | 13.05 | 男性用トイレ | ＜ゾーン番号＞ | 5FL
6FLSD3 | 6FL | 1030 | SD3 | 6FLSD3 | 事務室 | 315 | yes | 6FL | 6 | W9 | EVホール | ＜ゾーン番号＞ | インテリア | 900.0×2,100.0 | 1,030.0×2,165.0 | 930.0×2,115.0 | 900.0×2,100.0×150.0 | 左 | no | 960 | 6180 | 2.0448 | 150 | 900 | 15000 | 3.7566 | 17130 | 15000 | 0 | 0.30672 | 0.2835 | 1.89 | 2.22995 | 870 | 930 | 170 | 16.05 | 事務室 | 315 | 6FL
6FLSD4 | 6FL | 1030 | SD4 | 6FLSD4 | 事務室 | 316 | yes | 6FL | 6 | W9 | EVホール | ＜ゾーン番号＞ | インテリア | 900.0×2,100.0 | 1,030.0×2,165.0 | 930.0×2,115.0 | 900.0×2,100.0×150.0 | 右 | no | 960 | 6180 | 2.0448 | 150 | 900 | 15000 | 3.7566 | 17130 | 15000 | 0 | 0.30672 | 0.2835 | 1.89 | 2.22995 | 870 | 930 | 170 | 16.05 | 事務室 | 316 | 6FL
6FLSD5 | 6FL | 1030 | SD5 | 6FLSD5 | 事務室 | 314 | yes | 6FL | 6 | W9 | EVホール | ＜ゾーン番号＞ | インテリア | 900.0×2,100.0 | 1,030.0×2,165.0 | 930.0×2,115.0 | 900.0×2,100.0×150.0 | 右 | no | 960 | 6180 | 2.0448 | 150 | 900 | 15000 | 3.7566 | 17130 | 15000 | 0 | 0.30672 | 0.2835 | 1.89 | 2.22995 | 870 | 930 | 170 | 16.05 | 事務室 | 314 | 6FL
6FLSD6 | 6FL | 1030 | SD6 | 6FLSD6 | 事務室 | 313 | yes | 6FL | 6 | W9 | EVホール | ＜ゾーン番号＞ | インテリア | 900.0×2,100.0 | 1,030.0×2,165.0 | 930.0×2,115.0 | 900.0×2,100.0×150.0 | 左 | no | 960 | 6180 | 2.0448 | 150 | 900 | 15000 | 3.7566 | 17130 | 15000 | 0 | 0.30672 | 0.2835 | 1.89 | 2.22995 | 870 | 930 | 170 | 16.05 | 事務室 | 313 | 6FL
6FLFSD2 | 6FL | 1230 | FSD2 | 6FLFSD2 | 階段室 | ＜ゾーン番号＞ | yes | 6FL | 6 | W4 | EVホール | ＜ゾーン番号＞ | インテリア | 1,100.0×2,100.0 | 1,230.0×2,165.0 | 1,130.0×2,115.0 | 1,100.0×2,100.0×150.0 | 左 | no | 1160 | 6580 | 2.4708 | 150 | 1100 | 15000 | 4.2486 | 17130 | 15000 | 0 | 0.37062 | 0.3465 | 2.31 | 2.66295 | 1070 | 1130 | 170 | 16.05 | 階段室 | ＜ゾーン番号＞ | 6FL
6FLSD7 | 6FL | 1030 | SD7 | 6FLSD7 | 事務室 | 303 | yes | 6FL | 6 | W4 | EVホール | ＜ゾーン番号＞ | インテリア | 900.0×2,100.0 | 1,030.0×2,165.0 | 930.0×2,115.0 | 900.0×2,100.0×150.0 | 左 | no | 960 | 6180 | 2.0448 | 150 | 900 | 15000 | 3.7566 | 17130 | 15000 | 0 | 0.30672 | 0.2835 | 1.89 | 2.22995 | 870 | 930 | 170 | 16.05 | 事務室 | 303 | 6FL
6FLSD8 | 6FL | 1030 | SD8 | 6FLSD8 | 事務室 | 308 | yes | 6FL | 6 | W7 | EVホール | ＜ゾーン番号＞ | インテリア | 900.0×2,100.0 | 1,030.0×2,165.0 | 930.0×2,115.0 | 900.0×2,100.0×150.0 | 右 | no | 960 | 6180 | 2.0448 | 150 | 900 | 15000 | 3.7566 | 17130 | 15000 | 0 | 0.30672 | 0.2835 | 1.89 | 2.22995 | 870 | 930 | 170 | 16.05 | 事務室 | 308 | 6FL
6FLSD9 | 6FL | 1030 | SD9 | 6FLSD9 | 事務室 | 309 | yes | 6FL | 6 | W7 | EVホール | ＜ゾーン番号＞ | インテリア | 900.0×2,100.0 | 1,030.0×2,165.0 | 930.0×2,115.0 | 900.0×2,100.0×150.0 | 左 | no | 960 | 6180 | 2.0448 | 150 | 900 | 15000 | 3.7566 | 17130 | 15000 | 0 | 0.30672 | 0.2835 | 1.89 | 2.22995 | 870 | 930 | 170 | 16.05 | 事務室 | 309 | 6FL
6FLSD0 | 6FL | 1030 | SD0 | 6FLSD0 | 事務室 | 311 | yes | 6FL | 6 | W3 | 廊下 | ＜ゾーン番号＞ | インテリア | 900.0×2,100.0 | 1,030.0×2,165.0 | 930.0×2,115.0 | 900.0×2,100.0×150.0 | 左 | no | 960 | 6180 | 2.0448 | 150 | 900 | 15000 | 3.7566 | 17130 | 15000 | 0 | 0.30672 | 0.2835 | 1.89 | 2.22995 | 870 | 930 | 170 | 16.05 | 事務室 | 311 | 6FL
6FLSD1 | 6FL | 1030 | SD1 | 6FLSD1 | 事務室 | 310 | yes | 6FL | 6 | W3 | 廊下 | ＜ゾーン番号＞ | インテリア | 900.0×2,100.0 | 1,030.0×2,165.0 | 930.0×2,115.0 | 900.0×2,100.0×150.0 | 右 | no | 960 | 6180 | 2.0448 | 150 | 900 | 15000 | 3.7566 | 17130 | 15000 | 0 | 0.30672 | 0.2835 | 1.89 | 2.22995 | 870 | 930 | 170 | 16.05 | 事務室 | 310 | 6FL
6FLFSD2 | 6FL | 1230 | FSD2 | 6FLFSD2 | 避難階段 | ＜ゾーン番号＞ | yes | 6FL | 6 | W0 | EVホール | ＜ゾーン番号＞ | エクステリア | 1,100.0×2,100.0 | 1,230.0×2,165.0 | 1,130.0×2,115.0 | 1,100.0×2,100.0×250.0 | 右 | yes | 1160 | 6580 | 2.4708 | 250 | 1100 | 15000 | 5.3266 | 17130 | 15000 | 0 | 0.6177 | 0.5775 | 2.31 | 2.66295 | 1070 | 1130 | 270 | 16.05 | 避難階段 | ＜ゾーン番号＞ | 6FL
6FLSD9 | 6FL | 1030 | SD9 | 6FLSD9 | 事務室 | 301 | yes | 6FL | 6 | W4 | 廊下 | ＜ゾーン番号＞ | インテリア | 900.0×2,100.0 | 1,030.0×2,165.0 | 930.0×2,115.0 | 900.0×2,100.0×150.0 | 右 | no | 960 | 6180 | 2.0448 | 150 | 900 | 15000 | 3.7566 | 17130 | 15000 | 0 | 0.30672 | 0.2835 | 1.89 | 2.22995 | 870 | 930 | 170 | 16.05 | 事務室 | 301 | 6FL
6FLSD9 | 6FL | 1030 | SD9 | 6FLSD9 | 事務室 | 302 | yes | 6FL | 6 | W4 | 廊下 | ＜ゾーン番号＞ | インテリア | 900.0×2,100.0 | 1,030.0×2,165.0 | 930.0×2,115.0 | 900.0×2,100.0×150.0 | 左 | no | 960 | 6180 | 2.0448 | 150 | 900 | 15000 | 3.7566 | 17130 | 15000 | 0 | 0.30672 | 0.2835 | 1.89 | 2.22995 | 870 | 930 | 170 | 16.05 | 事務室 | 302 | 6FL
6FLSD5 | 6FL | 1030 | SD5 | 6FLSD5 | 事務室 | 304 | yes | 6FL | 6 | W5 | EVホール | ＜ゾーン番号＞ | インテリア | 900.0×2,100.0 | 1,030.0×2,165.0 | 930.0×2,115.0 | 900.0×2,100.0×150.0 | 右 | no | 960 | 6180 | 2.0448 | 150 | 900 | 15000 | 3.7566 | 17130 | 15000 | 0 | 0.30672 | 0.2835 | 1.89 | 2.22995 | 870 | 930 | 170 | 16.05 | 事務室 | 304 | 6FL
6FLSD6 | 6FL | 1030 | SD6 | 6FLSD6 | 事務室 | 305 | yes | 6FL | 6 | W5 | EVホール | ＜ゾーン番号＞ | インテリア | 900.0×2,100.0 | 1,030.0×2,165.0 | 930.0×2,115.0 | 900.0×2,100.0×150.0 | 右 | no | 960 | 6180 | 2.0448 | 150 | 900 | 15000 | 3.7566 | 17130 | 15000 | 0 | 0.30672 | 0.2835 | 1.89 | 2.22995 | 870 | 930 | 170 | 16.05 | 事務室 | 305 | 6FL
6FLSD6 | 6FL | 1030 | SD6 | 6FLSD6 | 事務室 | 306 | yes | 6FL | 6 | W5 | EVホール | ＜ゾーン番号＞ | インテリア | 900.0×2,100.0 | 1,030.0×2,165.0 | 930.0×2,115.0 | 900.0×2,100.0×150.0 | 右 | no | 960 | 6180 | 2.0448 | 150 | 900 | 15000 | 3.7566 | 17130 | 15000 | 0 | 0.30672 | 0.2835 | 1.89 | 2.22995 | 870 | 930 | 170 | 16.05 | 事務室 | 306 | 6FL
6FLSD7 | 6FL | 1030 | SD7 | 6FLSD7 | 事務室 | 307 | yes | 6FL | 6 | W5 | EVホール | ＜ゾーン番号＞ | インテリア | 900.0×2,100.0 | 1,030.0×2,165.0 | 930.0×2,115.0 | 900.0×2,100.0×150.0 | 左 | no | 960 | 6180 | 2.0448 | 150 | 900 | 15000 | 3.7566 | 17130 | 15000 | 0 | 0.30672 | 0.2835 | 1.89 | 2.22995 | 870 | 930 | 170 | 16.05 | 事務室 | 307 | 6FL
6FLSD3 | 6FL | 830 | SD3 | 6FLSD3 | 女性用トイレ | ＜ゾーン番号＞ | yes | 6FL | 6 | W4 | EVホール | ＜ゾーン番号＞ | インテリア | 700.0×2,100.0 | 830.0×2,165.0 | 730.0×2,115.0 | 700.0×2,100.0×150.0 | 左 | no | 760 | 5780 | 1.6188 | 150 | 700 | 15000 | 3.2646 | 17130 | 15000 | 0 | 0.24282 | 0.2205 | 1.47 | 1.79695 | 670 | 730 | 170 | 16.05 | 女性用トイレ | ＜ゾーン番号＞ | 6FL
6FLSD3 | 6FL | 830 | SD3 | 6FLSD3 | 男性用トイレ | ＜ゾーン番号＞ | yes | 6FL | 6 | W4 | EVホール | ＜ゾーン番号＞ | インテリア | 700.0×2,100.0 | 830.0×2,165.0 | 730.0×2,115.0 | 700.0×2,100.0×150.0 | 左 | no | 760 | 5780 | 1.6188 | 150 | 700 | 15000 | 3.2646 | 17130 | 15000 | 0 | 0.24282 | 0.2205 | 1.47 | 1.79695 | 670 | 730 | 170 | 16.05 | 男性用トイレ | ＜ゾーン番号＞ | 6FL
7FLSD3 | 7FL | 1030 | SD3 | 7FLSD3 | 事務室 | 315 | yes | 7FL | 7 | W9 | EVホール | ＜ゾーン番号＞ | インテリア | 900.0×2,100.0 | 1,030.0×2,165.0 | 930.0×2,115.0 | 900.0×2,100.0×150.0 | 左 | no | 960 | 6180 | 2.0448 | 150 | 900 | 18000 | 3.7566 | 20130 | 18000 | 0 | 0.30672 | 0.2835 | 1.89 | 2.22995 | 870 | 930 | 170 | 19.05 | 事務室 | 315 | 7FL
7FLSD4 | 7FL | 1030 | SD4 | 7FLSD4 | 事務室 | 316 | yes | 7FL | 7 | W9 | EVホール | ＜ゾーン番号＞ | インテリア | 900.0×2,100.0 | 1,030.0×2,165.0 | 930.0×2,115.0 | 900.0×2,100.0×150.0 | 右 | no | 960 | 6180 | 2.0448 | 150 | 900 | 18000 | 3.7566 | 20130 | 18000 | 0 | 0.30672 | 0.2835 | 1.89 | 2.22995 | 870 | 930 | 170 | 19.05 | 事務室 | 316 | 7FL
7FLSD5 | 7FL | 1030 | SD5 | 7FLSD5 | 事務室 | 314 | yes | 7FL | 7 | W9 | EVホール | ＜ゾーン番号＞ | インテリア | 900.0×2,100.0 | 1,030.0×2,165.0 | 930.0×2,115.0 | 900.0×2,100.0×150.0 | 右 | no | 960 | 6180 | 2.0448 | 150 | 900 | 18000 | 3.7566 | 20130 | 18000 | 0 | 0.30672 | 0.2835 | 1.89 | 2.22995 | 870 | 930 | 170 | 19.05 | 事務室 | 314 | 7FL
7FLSD6 | 7FL | 1030 | SD6 | 7FLSD6 | 事務室 | 313 | yes | 7FL | 7 | W9 | EVホール | ＜ゾーン番号＞ | インテリア | 900.0×2,100.0 | 1,030.0×2,165.0 | 930.0×2,115.0 | 900.0×2,100.0×150.0 | 左 | no | 960 | 6180 | 2.0448 | 150 | 900 | 18000 | 3.7566 | 20130 | 18000 | 0 | 0.30672 | 0.2835 | 1.89 | 2.22995 | 870 | 930 | 170 | 19.05 | 事務室 | 313 | 7FL
7FLFSD2 | 7FL | 1230 | FSD2 | 7FLFSD2 | 階段室 | ＜ゾーン番号＞ | yes | 7FL | 7 | W4 | EVホール | ＜ゾーン番号＞ | インテリア | 1,100.0×2,100.0 | 1,230.0×2,165.0 | 1,130.0×2,115.0 | 1,100.0×2,100.0×150.0 | 左 | no | 1160 | 6580 | 2.4708 | 150 | 1100 | 18000 | 4.2486 | 20130 | 18000 | 0 | 0.37062 | 0.3465 | 2.31 | 2.66295 | 1070 | 1130 | 170 | 19.05 | 階段室 | ＜ゾーン番号＞ | 7FL
7FLSD7 | 7FL | 1030 | SD7 | 7FLSD7 | 事務室 | 303 | yes | 7FL | 7 | W4 | EVホール | ＜ゾーン番号＞ | インテリア | 900.0×2,100.0 | 1,030.0×2,165.0 | 930.0×2,115.0 | 900.0×2,100.0×150.0 | 左 | no | 960 | 6180 | 2.0448 | 150 | 900 | 18000 | 3.7566 | 20130 | 18000 | 0 | 0.30672 | 0.2835 | 1.89 | 2.22995 | 870 | 930 | 170 | 19.05 | 事務室 | 303 | 7FL
7FLSD8 | 7FL | 1030 | SD8 | 7FLSD8 | 事務室 | 308 | yes | 7FL | 7 | W7 | EVホール | ＜ゾーン番号＞ | インテリア | 900.0×2,100.0 | 1,030.0×2,165.0 | 930.0×2,115.0 | 900.0×2,100.0×150.0 | 右 | no | 960 | 6180 | 2.0448 | 150 | 900 | 18000 | 3.7566 | 20130 | 18000 | 0 | 0.30672 | 0.2835 | 1.89 | 2.22995 | 870 | 930 | 170 | 19.05 | 事務室 | 308 | 7FL
7FLSD9 | 7FL | 1030 | SD9 | 7FLSD9 | 事務室 | 309 | yes | 7FL | 7 | W7 | EVホール | ＜ゾーン番号＞ | インテリア | 900.0×2,100.0 | 1,030.0×2,165.0 | 930.0×2,115.0 | 900.0×2,100.0×150.0 | 左 | no | 960 | 6180 | 2.0448 | 150 | 900 | 18000 | 3.7566 | 20130 | 18000 | 0 | 0.30672 | 0.2835 | 1.89 | 2.22995 | 870 | 930 | 170 | 19.05 | 事務室 | 309 | 7FL
7FLSD0 | 7FL | 1030 | SD0 | 7FLSD0 | 事務室 | 311 | yes | 7FL | 7 | W3 | 廊下 | ＜ゾーン番号＞ | インテリア | 900.0×2,100.0 | 1,030.0×2,165.0 | 930.0×2,115.0 | 900.0×2,100.0×150.0 | 左 | no | 960 | 6180 | 2.0448 | 150 | 900 | 18000 | 3.7566 | 20130 | 18000 | 0 | 0.30672 | 0.2835 | 1.89 | 2.22995 | 870 | 930 | 170 | 19.05 | 事務室 | 311 | 7FL
7FLSD1 | 7FL | 1030 | SD1 | 7FLSD1 | 事務室 | 310 | yes | 7FL | 7 | W3 | 廊下 | ＜ゾーン番号＞ | インテリア | 900.0×2,100.0 | 1,030.0×2,165.0 | 930.0×2,115.0 | 900.0×2,100.0×150.0 | 右 | no | 960 | 6180 | 2.0448 | 150 | 900 | 18000 | 3.7566 | 20130 | 18000 | 0 | 0.30672 | 0.2835 | 1.89 | 2.22995 | 870 | 930 | 170 | 19.05 | 事務室 | 310 | 7FL
7FLFSD2 | 7FL | 1230 | FSD2 | 7FLFSD2 | 避難階段 | ＜ゾーン番号＞ | yes | 7FL | 7 | W0 | EVホール | ＜ゾーン番号＞ | エクステリア | 1,100.0×2,100.0 | 1,230.0×2,165.0 | 1,130.0×2,115.0 | 1,100.0×2,100.0×250.0 | 右 | yes | 1160 | 6580 | 2.4708 | 250 | 1100 | 18000 | 5.3266 | 20130 | 18000 | 0 | 0.6177 | 0.5775 | 2.31 | 2.66295 | 1070 | 1130 | 270 | 19.05 | 避難階段 | ＜ゾーン番号＞ | 7FL
7FLSD9 | 7FL | 1030 | SD9 | 7FLSD9 | 事務室 | 301 | yes | 7FL | 7 | W4 | 廊下 | ＜ゾーン番号＞ | インテリア | 900.0×2,100.0 | 1,030.0×2,165.0 | 930.0×2,115.0 | 900.0×2,100.0×150.0 | 右 | no | 960 | 6180 | 2.0448 | 150 | 900 | 18000 | 3.7566 | 20130 | 18000 | 0 | 0.30672 | 0.2835 | 1.89 | 2.22995 | 870 | 930 | 170 | 19.05 | 事務室 | 301 | 7FL
7FLSD9 | 7FL | 1030 | SD9 | 7FLSD9 | 事務室 | 302 | yes | 7FL | 7 | W4 | 廊下 | ＜ゾーン番号＞ | インテリア | 900.0×2,100.0 | 1,030.0×2,165.0 | 930.0×2,115.0 | 900.0×2,100.0×150.0 | 左 | no | 960 | 6180 | 2.0448 | 150 | 900 | 18000 | 3.7566 | 20130 | 18000 | 0 | 0.30672 | 0.2835 | 1.89 | 2.22995 | 870 | 930 | 170 | 19.05 | 事務室 | 302 | 7FL
7FLSD5 | 7FL | 1030 | SD5 | 7FLSD5 | 事務室 | 304 | yes | 7FL | 7 | W5 | EVホール | ＜ゾーン番号＞ | インテリア | 900.0×2,100.0 | 1,030.0×2,165.0 | 930.0×2,115.0 | 900.0×2,100.0×150.0 | 右 | no | 960 | 6180 | 2.0448 | 150 | 900 | 18000 | 3.7566 | 20130 | 18000 | 0 | 0.30672 | 0.2835 | 1.89 | 2.22995 | 870 | 930 | 170 | 19.05 | 事務室 | 304 | 7FL
7FLSD6 | 7FL | 1030 | SD6 | 7FLSD6 | 事務室 | 305 | yes | 7FL | 7 | W5 | EVホール | ＜ゾーン番号＞ | インテリア | 900.0×2,100.0 | 1,030.0×2,165.0 | 930.0×2,115.0 | 900.0×2,100.0×150.0 | 右 | no | 960 | 6180 | 2.0448 | 150 | 900 | 18000 | 3.7566 | 20130 | 18000 | 0 | 0.30672 | 0.2835 | 1.89 | 2.22995 | 870 | 930 | 170 | 19.05 | 事務室 | 305 | 7FL
7FLSD6 | 7FL | 1030 | SD6 | 7FLSD6 | 事務室 | 306 | yes | 7FL | 7 | W5 | EVホール | ＜ゾーン番号＞ | インテリア | 900.0×2,100.0 | 1,030.0×2,165.0 | 930.0×2,115.0 | 900.0×2,100.0×150.0 | 右 | no | 960 | 6180 | 2.0448 | 150 | 900 | 18000 | 3.7566 | 20130 | 18000 | 0 | 0.30672 | 0.2835 | 1.89 | 2.22995 | 870 | 930 | 170 | 19.05 | 事務室 | 306 | 7FL
7FLSD7 | 7FL | 1030 | SD7 | 7FLSD7 | 事務室 | 307 | yes | 7FL | 7 | W5 | EVホール | ＜ゾーン番号＞ | インテリア | 900.0×2,100.0 | 1,030.0×2,165.0 | 930.0×2,115.0 | 900.0×2,100.0×150.0 | 左 | no | 960 | 6180 | 2.0448 | 150 | 900 | 18000 | 3.7566 | 20130 | 18000 | 0 | 0.30672 | 0.2835 | 1.89 | 2.22995 | 870 | 930 | 170 | 19.05 | 事務室 | 307 | 7FL
7FLSD3 | 7FL | 830 | SD3 | 7FLSD3 | 女性用トイレ | ＜ゾーン番号＞ | yes | 7FL | 7 | W4 | EVホール | ＜ゾーン番号＞ | インテリア | 700.0×2,100.0 | 830.0×2,165.0 | 730.0×2,115.0 | 700.0×2,100.0×150.0 | 左 | no | 760 | 5780 | 1.6188 | 150 | 700 | 18000 | 3.2646 | 20130 | 18000 | 0 | 0.24282 | 0.2205 | 1.47 | 1.79695 | 670 | 730 | 170 | 19.05 | 女性用トイレ | ＜ゾーン番号＞ | 7FL
7FLSD3 | 7FL | 830 | SD3 | 7FLSD3 | 男性用トイレ | ＜ゾーン番号＞ | yes | 7FL | 7 | W4 | EVホール | ＜ゾーン番号＞ | インテリア | 700.0×2,100.0 | 830.0×2,165.0 | 730.0×2,115.0 | 700.0×2,100.0×150.0 | 左 | no | 760 | 5780 | 1.6188 | 150 | 700 | 18000 | 3.2646 | 20130 | 18000 | 0 | 0.24282 | 0.2205 | 1.47 | 1.79695 | 670 | 730 | 170 | 19.05 | 男性用トイレ | ＜ゾーン番号＞ | 7FL
8FLSD3 | 8FL | 1030 | SD3 | 8FLSD3 | 事務室 | 315 | yes | 8FL | 8 | W9 | EVホール | ＜ゾーン番号＞ | インテリア | 900.0×2,100.0 | 1,030.0×2,165.0 | 930.0×2,115.0 | 900.0×2,100.0×150.0 | 左 | no | 960 | 6180 | 2.0448 | 150 | 900 | 21000 | 3.7566 | 23130 | 21000 | 0 | 0.30672 | 0.2835 | 1.89 | 2.22995 | 870 | 930 | 170 | 22.05 | 事務室 | 315 | 8FL
8FLSD4 | 8FL | 1030 | SD4 | 8FLSD4 | 事務室 | 316 | yes | 8FL | 8 | W9 | EVホール | ＜ゾーン番号＞ | インテリア | 900.0×2,100.0 | 1,030.0×2,165.0 | 930.0×2,115.0 | 900.0×2,100.0×150.0 | 右 | no | 960 | 6180 | 2.0448 | 150 | 900 | 21000 | 3.7566 | 23130 | 21000 | 0 | 0.30672 | 0.2835 | 1.89 | 2.22995 | 870 | 930 | 170 | 22.05 | 事務室 | 316 | 8FL
8FLSD5 | 8FL | 1030 | SD5 | 8FLSD5 | 事務室 | 314 | yes | 8FL | 8 | W9 | EVホール | ＜ゾーン番号＞ | インテリア | 900.0×2,100.0 | 1,030.0×2,165.0 | 930.0×2,115.0 | 900.0×2,100.0×150.0 | 右 | no | 960 | 6180 | 2.0448 | 150 | 900 | 21000 | 3.7566 | 23130 | 21000 | 0 | 0.30672 | 0.2835 | 1.89 | 2.22995 | 870 | 930 | 170 | 22.05 | 事務室 | 314 | 8FL
8FLSD6 | 8FL | 1030 | SD6 | 8FLSD6 | 事務室 | 313 | yes | 8FL | 8 | W9 | EVホール | ＜ゾーン番号＞ | インテリア | 900.0×2,100.0 | 1,030.0×2,165.0 | 930.0×2,115.0 | 900.0×2,100.0×150.0 | 左 | no | 960 | 6180 | 2.0448 | 150 | 900 | 21000 | 3.7566 | 23130 | 21000 | 0 | 0.30672 | 0.2835 | 1.89 | 2.22995 | 870 | 930 | 170 | 22.05 | 事務室 | 313 | 8FL
8FLFSD2 | 8FL | 1230 | FSD2 | 8FLFSD2 | 階段室 | ＜ゾーン番号＞ | yes | 8FL | 8 | W4 | EVホール | ＜ゾーン番号＞ | インテリア | 1,100.0×2,100.0 | 1,230.0×2,165.0 | 1,130.0×2,115.0 | 1,100.0×2,100.0×150.0 | 左 | no | 1160 | 6580 | 2.4708 | 150 | 1100 | 21000 | 4.2486 | 23130 | 21000 | 0 | 0.37062 | 0.3465 | 2.31 | 2.66295 | 1070 | 1130 | 170 | 22.05 | 階段室 | ＜ゾーン番号＞ | 8FL
8FLSD7 | 8FL | 1030 | SD7 | 8FLSD7 | 事務室 | 303 | yes | 8FL | 8 | W4 | EVホール | ＜ゾーン番号＞ | インテリア | 900.0×2,100.0 | 1,030.0×2,165.0 | 930.0×2,115.0 | 900.0×2,100.0×150.0 | 左 | no | 960 | 6180 | 2.0448 | 150 | 900 | 21000 | 3.7566 | 23130 | 21000 | 0 | 0.30672 | 0.2835 | 1.89 | 2.22995 | 870 | 930 | 170 | 22.05 | 事務室 | 303 | 8FL
8FLSD8 | 8FL | 1030 | SD8 | 8FLSD8 | 事務室 | 308 | yes | 8FL | 8 | W7 | EVホール | ＜ゾーン番号＞ | インテリア | 900.0×2,100.0 | 1,030.0×2,165.0 | 930.0×2,115.0 | 900.0×2,100.0×150.0 | 右 | no | 960 | 6180 | 2.0448 | 150 | 900 | 21000 | 3.7566 | 23130 | 21000 | 0 | 0.30672 | 0.2835 | 1.89 | 2.22995 | 870 | 930 | 170 | 22.05 | 事務室 | 308 | 8FL
8FLSD9 | 8FL | 1030 | SD9 | 8FLSD9 | 事務室 | 309 | yes | 8FL | 8 | W7 | EVホール | ＜ゾーン番号＞ | インテリア | 900.0×2,100.0 | 1,030.0×2,165.0 | 930.0×2,115.0 | 900.0×2,100.0×150.0 | 左 | no | 960 | 6180 | 2.0448 | 150 | 900 | 21000 | 3.7566 | 23130 | 21000 | 0 | 0.30672 | 0.2835 | 1.89 | 2.22995 | 870 | 930 | 170 | 22.05 | 事務室 | 309 | 8FL
8FLSD0 | 8FL | 1030 | SD0 | 8FLSD0 | 事務室 | 311 | yes | 8FL | 8 | W3 | 廊下 | ＜ゾーン番号＞ | インテリア | 900.0×2,100.0 | 1,030.0×2,165.0 | 930.0×2,115.0 | 900.0×2,100.0×150.0 | 左 | no | 960 | 6180 | 2.0448 | 150 | 900 | 21000 | 3.7566 | 23130 | 21000 | 0 | 0.30672 | 0.2835 | 1.89 | 2.22995 | 870 | 930 | 170 | 22.05 | 事務室 | 311 | 8FL
8FLSD1 | 8FL | 1030 | SD1 | 8FLSD1 | 事務室 | 310 | yes | 8FL | 8 | W3 | 廊下 | ＜ゾーン番号＞ | インテリア | 900.0×2,100.0 | 1,030.0×2,165.0 | 930.0×2,115.0 | 900.0×2,100.0×150.0 | 右 | no | 960 | 6180 | 2.0448 | 150 | 900 | 21000 | 3.7566 | 23130 | 21000 | 0 | 0.30672 | 0.2835 | 1.89 | 2.22995 | 870 | 930 | 170 | 22.05 | 事務室 | 310 | 8FL
8FLFSD2 | 8FL | 1230 | FSD2 | 8FLFSD2 | 避難階段 | ＜ゾーン番号＞ | yes | 8FL | 8 | W0 | EVホール | ＜ゾーン番号＞ | エクステリア | 1,100.0×2,100.0 | 1,230.0×2,165.0 | 1,130.0×2,115.0 | 1,100.0×2,100.0×250.0 | 右 | yes | 1160 | 6580 | 2.4708 | 250 | 1100 | 21000 | 5.3266 | 23130 | 21000 | 0 | 0.6177 | 0.5775 | 2.31 | 2.66295 | 1070 | 1130 | 270 | 22.05 | 避難階段 | ＜ゾーン番号＞ | 8FL
8FLSD9 | 8FL | 1030 | SD9 | 8FLSD9 | 事務室 | 301 | yes | 8FL | 8 | W4 | 廊下 | ＜ゾーン番号＞ | インテリア | 900.0×2,100.0 | 1,030.0×2,165.0 | 930.0×2,115.0 | 900.0×2,100.0×150.0 | 右 | no | 960 | 6180 | 2.0448 | 150 | 900 | 21000 | 3.7566 | 23130 | 21000 | 0 | 0.30672 | 0.2835 | 1.89 | 2.22995 | 870 | 930 | 170 | 22.05 | 事務室 | 301 | 8FL
8FLSD9 | 8FL | 1030 | SD9 | 8FLSD9 | 事務室 | 302 | yes | 8FL | 8 | W4 | 廊下 | ＜ゾーン番号＞ | インテリア | 900.0×2,100.0 | 1,030.0×2,165.0 | 930.0×2,115.0 | 900.0×2,100.0×150.0 | 左 | no | 960 | 6180 | 2.0448 | 150 | 900 | 21000 | 3.7566 | 23130 | 21000 | 0 | 0.30672 | 0.2835 | 1.89 | 2.22995 | 870 | 930 | 170 | 22.05 | 事務室 | 302 | 8FL
8FLSD5 | 8FL | 1030 | SD5 | 8FLSD5 | 事務室 | 304 | yes | 8FL | 8 | W5 | EVホール | ＜ゾーン番号＞ | インテリア | 900.0×2,100.0 | 1,030.0×2,165.0 | 930.0×2,115.0 | 900.0×2,100.0×150.0 | 右 | no | 960 | 6180 | 2.0448 | 150 | 900 | 21000 | 3.7566 | 23130 | 21000 | 0 | 0.30672 | 0.2835 | 1.89 | 2.22995 | 870 | 930 | 170 | 22.05 | 事務室 | 304 | 8FL
8FLSD6 | 8FL | 1030 | SD6 | 8FLSD6 | 事務室 | 305 | yes | 8FL | 8 | W5 | EVホール | ＜ゾーン番号＞ | インテリア | 900.0×2,100.0 | 1,030.0×2,165.0 | 930.0×2,115.0 | 900.0×2,100.0×150.0 | 右 | no | 960 | 6180 | 2.0448 | 150 | 900 | 21000 | 3.7566 | 23130 | 21000 | 0 | 0.30672 | 0.2835 | 1.89 | 2.22995 | 870 | 930 | 170 | 22.05 | 事務室 | 305 | 8FL
8FLSD6 | 8FL | 1030 | SD6 | 8FLSD6 | 事務室 | 306 | yes | 8FL | 8 | W5 | EVホール | ＜ゾーン番号＞ | インテリア | 900.0×2,100.0 | 1,030.0×2,165.0 | 930.0×2,115.0 | 900.0×2,100.0×150.0 | 右 | no | 960 | 6180 | 2.0448 | 150 | 900 | 21000 | 3.7566 | 23130 | 21000 | 0 | 0.30672 | 0.2835 | 1.89 | 2.22995 | 870 | 930 | 170 | 22.05 | 事務室 | 306 | 8FL
8FLSD7 | 8FL | 1030 | SD7 | 8FLSD7 | 事務室 | 307 | yes | 8FL | 8 | W5 | EVホール | ＜ゾーン番号＞ | インテリア | 900.0×2,100.0 | 1,030.0×2,165.0 | 930.0×2,115.0 | 900.0×2,100.0×150.0 | 左 | no | 960 | 6180 | 2.0448 | 150 | 900 | 21000 | 3.7566 | 23130 | 21000 | 0 | 0.30672 | 0.2835 | 1.89 | 2.22995 | 870 | 930 | 170 | 22.05 | 事務室 | 307 | 8FL
8FLSD3 | 8FL | 830 | SD3 | 8FLSD3 | 女性用トイレ | ＜ゾーン番号＞ | yes | 8FL | 8 | W4 | EVホール | ＜ゾーン番号＞ | インテリア | 700.0×2,100.0 | 830.0×2,165.0 | 730.0×2,115.0 | 700.0×2,100.0×150.0 | 左 | no | 760 | 5780 | 1.6188 | 150 | 700 | 21000 | 3.2646 | 23130 | 21000 | 0 | 0.24282 | 0.2205 | 1.47 | 1.79695 | 670 | 730 | 170 | 22.05 | 女性用トイレ | ＜ゾーン番号＞ | 8FL
8FLSD3 | 8FL | 830 | SD3 | 8FLSD3 | 男性用トイレ | ＜ゾーン番号＞ | yes | 8FL | 8 | W4 | EVホール | ＜ゾーン番号＞ | インテリア | 700.0×2,100.0 | 830.0×2,165.0 | 730.0×2,115.0 | 700.0×2,100.0×150.0 | 左 | no | 760 | 5780 | 1.6188 | 150 | 700 | 21000 | 3.2646 | 23130 | 21000 | 0 | 0.24282 | 0.2205 | 1.47 | 1.79695 | 670 | 730 | 170 | 22.05 | 男性用トイレ | ＜ゾーン番号＞ | 8FL
9FLSD3 | 9FL | 1030 | SD3 | 9FLSD3 | 事務室 | 315 | yes | 9FL | 9 | W9 | EVホール | ＜ゾーン番号＞ | インテリア | 900.0×2,100.0 | 1,030.0×2,165.0 | 930.0×2,115.0 | 900.0×2,100.0×150.0 | 左 | no | 960 | 6180 | 2.0448 | 150 | 900 | 24000 | 3.7566 | 26130 | 24000 | 0 | 0.30672 | 0.2835 | 1.89 | 2.22995 | 870 | 930 | 170 | 25.05 | 事務室 | 315 | 9FL
9FLSD4 | 9FL | 1030 | SD4 | 9FLSD4 | 事務室 | 316 | yes | 9FL | 9 | W9 | EVホール | ＜ゾーン番号＞ | インテリア | 900.0×2,100.0 | 1,030.0×2,165.0 | 930.0×2,115.0 | 900.0×2,100.0×150.0 | 右 | no | 960 | 6180 | 2.0448 | 150 | 900 | 24000 | 3.7566 | 26130 | 24000 | 0 | 0.30672 | 0.2835 | 1.89 | 2.22995 | 870 | 930 | 170 | 25.05 | 事務室 | 316 | 9FL
9FLSD5 | 9FL | 1030 | SD5 | 9FLSD5 | 事務室 | 314 | yes | 9FL | 9 | W9 | EVホール | ＜ゾーン番号＞ | インテリア | 900.0×2,100.0 | 1,030.0×2,165.0 | 930.0×2,115.0 | 900.0×2,100.0×150.0 | 右 | no | 960 | 6180 | 2.0448 | 150 | 900 | 24000 | 3.7566 | 26130 | 24000 | 0 | 0.30672 | 0.2835 | 1.89 | 2.22995 | 870 | 930 | 170 | 25.05 | 事務室 | 314 | 9FL
9FLSD6 | 9FL | 1030 | SD6 | 9FLSD6 | 事務室 | 313 | yes | 9FL | 9 | W9 | EVホール | ＜ゾーン番号＞ | インテリア | 900.0×2,100.0 | 1,030.0×2,165.0 | 930.0×2,115.0 | 900.0×2,100.0×150.0 | 左 | no | 960 | 6180 | 2.0448 | 150 | 900 | 24000 | 3.7566 | 26130 | 24000 | 0 | 0.30672 | 0.2835 | 1.89 | 2.22995 | 870 | 930 | 170 | 25.05 | 事務室 | 313 | 9FL
9FLFSD2 | 9FL | 1230 | FSD2 | 9FLFSD2 | 階段室 | ＜ゾーン番号＞ | yes | 9FL | 9 | W4 | EVホール | ＜ゾーン番号＞ | インテリア | 1,100.0×2,100.0 | 1,230.0×2,165.0 | 1,130.0×2,115.0 | 1,100.0×2,100.0×150.0 | 左 | no | 1160 | 6580 | 2.4708 | 150 | 1100 | 24000 | 4.2486 | 26130 | 24000 | 0 | 0.37062 | 0.3465 | 2.31 | 2.66295 | 1070 | 1130 | 170 | 25.05 | 階段室 | ＜ゾーン番号＞ | 9FL
9FLSD7 | 9FL | 1030 | SD7 | 9FLSD7 | 事務室 | 303 | yes | 9FL | 9 | W4 | EVホール | ＜ゾーン番号＞ | インテリア | 900.0×2,100.0 | 1,030.0×2,165.0 | 930.0×2,115.0 | 900.0×2,100.0×150.0 | 左 | no | 960 | 6180 | 2.0448 | 150 | 900 | 24000 | 3.7566 | 26130 | 24000 | 0 | 0.30672 | 0.2835 | 1.89 | 2.22995 | 870 | 930 | 170 | 25.05 | 事務室 | 303 | 9FL
9FLSD8 | 9FL | 1030 | SD8 | 9FLSD8 | 事務室 | 308 | yes | 9FL | 9 | W7 | EVホール | ＜ゾーン番号＞ | インテリア | 900.0×2,100.0 | 1,030.0×2,165.0 | 930.0×2,115.0 | 900.0×2,100.0×150.0 | 右 | no | 960 | 6180 | 2.0448 | 150 | 900 | 24000 | 3.7566 | 26130 | 24000 | 0 | 0.30672 | 0.2835 | 1.89 | 2.22995 | 870 | 930 | 170 | 25.05 | 事務室 | 308 | 9FL
9FLSD9 | 9FL | 1030 | SD9 | 9FLSD9 | 事務室 | 309 | yes | 9FL | 9 | W7 | EVホール | ＜ゾーン番号＞ | インテリア | 900.0×2,100.0 | 1,030.0×2,165.0 | 930.0×2,115.0 | 900.0×2,100.0×150.0 | 左 | no | 960 | 6180 | 2.0448 | 150 | 900 | 24000 | 3.7566 | 26130 | 24000 | 0 | 0.30672 | 0.2835 | 1.89 | 2.22995 | 870 | 930 | 170 | 25.05 | 事務室 | 309 | 9FL
9FLSD0 | 9FL | 1030 | SD0 | 9FLSD0 | 事務室 | 311 | yes | 9FL | 9 | W3 | 廊下 | ＜ゾーン番号＞ | インテリア | 900.0×2,100.0 | 1,030.0×2,165.0 | 930.0×2,115.0 | 900.0×2,100.0×150.0 | 左 | no | 960 | 6180 | 2.0448 | 150 | 900 | 24000 | 3.7566 | 26130 | 24000 | 0 | 0.30672 | 0.2835 | 1.89 | 2.22995 | 870 | 930 | 170 | 25.05 | 事務室 | 311 | 9FL
9FLSD1 | 9FL | 1030 | SD1 | 9FLSD1 | 事務室 | 310 | yes | 9FL | 9 | W3 | 廊下 | ＜ゾーン番号＞ | インテリア | 900.0×2,100.0 | 1,030.0×2,165.0 | 930.0×2,115.0 | 900.0×2,100.0×150.0 | 右 | no | 960 | 6180 | 2.0448 | 150 | 900 | 24000 | 3.7566 | 26130 | 24000 | 0 | 0.30672 | 0.2835 | 1.89 | 2.22995 | 870 | 930 | 170 | 25.05 | 事務室 | 310 | 9FL
9FLFSD2 | 9FL | 1230 | FSD2 | 9FLFSD2 | 避難階段 | ＜ゾーン番号＞ | yes | 9FL | 9 | W0 | EVホール | ＜ゾーン番号＞ | エクステリア | 1,100.0×2,100.0 | 1,230.0×2,165.0 | 1,130.0×2,115.0 | 1,100.0×2,100.0×250.0 | 右 | yes | 1160 | 6580 | 2.4708 | 250 | 1100 | 24000 | 5.3266 | 26130 | 24000 | 0 | 0.6177 | 0.5775 | 2.31 | 2.66295 | 1070 | 1130 | 270 | 25.05 | 避難階段 | ＜ゾーン番号＞ | 9FL
9FLSD9 | 9FL | 1030 | SD9 | 9FLSD9 | 事務室 | 301 | yes | 9FL | 9 | W4 | 廊下 | ＜ゾーン番号＞ | インテリア | 900.0×2,100.0 | 1,030.0×2,165.0 | 930.0×2,115.0 | 900.0×2,100.0×150.0 | 右 | no | 960 | 6180 | 2.0448 | 150 | 900 | 24000 | 3.7566 | 26130 | 24000 | 0 | 0.30672 | 0.2835 | 1.89 | 2.22995 | 870 | 930 | 170 | 25.05 | 事務室 | 301 | 9FL
9FLSD9 | 9FL | 1030 | SD9 | 9FLSD9 | 事務室 | 302 | yes | 9FL | 9 | W4 | 廊下 | ＜ゾーン番号＞ | インテリア | 900.0×2,100.0 | 1,030.0×2,165.0 | 930.0×2,115.0 | 900.0×2,100.0×150.0 | 左 | no | 960 | 6180 | 2.0448 | 150 | 900 | 24000 | 3.7566 | 26130 | 24000 | 0 | 0.30672 | 0.2835 | 1.89 | 2.22995 | 870 | 930 | 170 | 25.05 | 事務室 | 302 | 9FL
9FLSD5 | 9FL | 1030 | SD5 | 9FLSD5 | 事務室 | 304 | yes | 9FL | 9 | W5 | EVホール | ＜ゾーン番号＞ | インテリア | 900.0×2,100.0 | 1,030.0×2,165.0 | 930.0×2,115.0 | 900.0×2,100.0×150.0 | 右 | no | 960 | 6180 | 2.0448 | 150 | 900 | 24000 | 3.7566 | 26130 | 24000 | 0 | 0.30672 | 0.2835 | 1.89 | 2.22995 | 870 | 930 | 170 | 25.05 | 事務室 | 304 | 9FL
9FLSD6 | 9FL | 1030 | SD6 | 9FLSD6 | 事務室 | 305 | yes | 9FL | 9 | W5 | EVホール | ＜ゾーン番号＞ | インテリア | 900.0×2,100.0 | 1,030.0×2,165.0 | 930.0×2,115.0 | 900.0×2,100.0×150.0 | 右 | no | 960 | 6180 | 2.0448 | 150 | 900 | 24000 | 3.7566 | 26130 | 24000 | 0 | 0.30672 | 0.2835 | 1.89 | 2.22995 | 870 | 930 | 170 | 25.05 | 事務室 | 305 | 9FL
9FLSD6 | 9FL | 1030 | SD6 | 9FLSD6 | 事務室 | 306 | yes | 9FL | 9 | W5 | EVホール | ＜ゾーン番号＞ | インテリア | 900.0×2,100.0 | 1,030.0×2,165.0 | 930.0×2,115.0 | 900.0×2,100.0×150.0 | 右 | no | 960 | 6180 | 2.0448 | 150 | 900 | 24000 | 3.7566 | 26130 | 24000 | 0 | 0.30672 | 0.2835 | 1.89 | 2.22995 | 870 | 930 | 170 | 25.05 | 事務室 | 306 | 9FL
9FLSD7 | 9FL | 1030 | SD7 | 9FLSD7 | 事務室 | 307 | yes | 9FL | 9 | W5 | EVホール | ＜ゾーン番号＞ | インテリア | 900.0×2,100.0 | 1,030.0×2,165.0 | 930.0×2,115.0 | 900.0×2,100.0×150.0 | 左 | no | 960 | 6180 | 2.0448 | 150 | 900 | 24000 | 3.7566 | 26130 | 24000 | 0 | 0.30672 | 0.2835 | 1.89 | 2.22995 | 870 | 930 | 170 | 25.05 | 事務室 | 307 | 9FL
9FLSD3 | 9FL | 830 | SD3 | 9FLSD3 | 女性用トイレ | ＜ゾーン番号＞ | yes | 9FL | 9 | W4 | EVホール | ＜ゾーン番号＞ | インテリア | 700.0×2,100.0 | 830.0×2,165.0 | 730.0×2,115.0 | 700.0×2,100.0×150.0 | 左 | no | 760 | 5780 | 1.6188 | 150 | 700 | 24000 | 3.2646 | 26130 | 24000 | 0 | 0.24282 | 0.2205 | 1.47 | 1.79695 | 670 | 730 | 170 | 25.05 | 女性用トイレ | ＜ゾーン番号＞ | 9FL
9FLSD3 | 9FL | 830 | SD3 | 9FLSD3 | 男性用トイレ | ＜ゾーン番号＞ | yes | 9FL | 9 | W4 | EVホール | ＜ゾーン番号＞ | インテリア | 700.0×2,100.0 | 830.0×2,165.0 | 730.0×2,115.0 | 700.0×2,100.0×150.0 | 左 | no | 760 | 5780 | 1.6188 | 150 | 700 | 24000 | 3.2646 | 26130 | 24000 | 0 | 0.24282 | 0.2205 | 1.47 | 1.79695 | 670 | 730 | 170 | 25.05 | 男性用トイレ | ＜ゾーン番号＞ | 9FL

# IfcDoor: 自由開き戸 (10)
In: 1FL
Type - ParameterTakesPrecedence: no; Sizeable: no
OverallHeight: 2150 mm; Classification: ドア (ARCHICAD 分類)
ArchiCADProperties - レイヤー: 壁-躯体; ライブラリ部品名: 自由開き戸; ビルディングマテリアル/複合構造/断面形状/塗りつぶし: 背景; 塗りつぶし種類: 背景; ロック状態: no; ホームフロア名: 1FL; ホームフロア数: 1; 要素タイプ: ドア; 材質 (全て): ペイント - サンドベージュ; リノベーションフィルタで表示: 全ての関連フィルタ; 構造機能: 非構造耐力要素; 位置: エクステリア; リノベーションステータス: 既存; 壁構造: コンクリート; 開口部 ライブラリ部品名: 自由開き戸; 開口部 側面塗りつぶし索引: 背景; ARCHICAD 分類 - v 2.0: ドア
AC_Pset_自由開き戸 - 壁輪郭(0-なし,1-全て,2-側面,3-長さ): 0; 2Dホットスポットを3Dで表示: yes; 開口部は壁側面の材質: no; 開口の側面を曲線壁に沿う: no; 抱き配置位置: 1; 開口角度2D (gs_open_2D): 90 deg; 開口角度3D: 0 deg; 枠材質 (gs_frame_mat): 木材 - マツ 木目 横; パネル材質: 木材 - マツ 木目 横; 公称サイズ: 2; 有効開口を公称サイズに設定: no; 枠内を公称サイズに設定: no; 壁開口を公称サイズに設定: no; 内寸を公称サイズに設定: yes; 現在の公称サイズを選択に切り替え: no; 詳細レベル: 1; 詳細: 1; 詳細表現スケールn (1/1 - 1/n): 50; 中間表現スケールm （1/n～1/m): 100; 2D 表示 (iViewtype_2D): 1; 断面表示: 1; 2D建具背面の無地塗つぶし: no; 額縁表現: 2; 2D額縁塗りつぶし: 木材1; 曲線壁の開口部でホットスポットを表示: no; ドア沓摺線 2D: no; 開口角度2D (opening_angle_2d): 90 deg; 建具種類: SD; 建具番号: 6; 法規制: 未定; 内外区分: 内; 形式: 自由開き戸; 建具識別コード（0=窓,1=ドア,2=シャッター,3=エレベーター): 1; 接続されたゾーンを値として使用: no; IFC操作 (ifc_optypestr): 未定義; IFC操作 (ifc_optype): 0; キープラン表示: yes; マーカータイプをスケールに連動: yes; マーカータイプ: タイプ1; 枝番(0=なし): 0; 建具サイズ表示: no; 建具符号方向: 任意角度; 建具符号任意角度: 0 deg; 用紙スケール: no; マーカーサイズ (用紙) (k_dia_paper): 4.2; マーカーサイズ (用紙) (k_dia_M): 0.0042; 離れX (用紙) (k_lenb_paper): 0; 離れX (用紙) (k_lenb_M): 0; 離れY (用紙) (k_lena_paper): 10; 離れY (用紙) (k_lena_M): 0.01; 離れオフセット (用紙) (k_lenc_paper): 0; 離れオフセット (用紙) (k_lenc_M): 0; 引き出し線角度: 0 deg; 引き出し線: no; ID表示: no; 線種: 1; 建具記号で塗りつぶしを使用: no; 建具記号塗りつぶし種類: 背景; フォント: Meiryo UI 日本語; 字サイズユーザー設定: no; 字サイズ: 1.4; 追記文字サイズ (mm): 1.43; 建具文字サイズ (mm): 1.43; 建具番号-枝番: 6; 追記位置X1 (用紙) (n_offx1_paper): -11; 追記位置X1 (用紙) (n_offx1_M): -0.011; 追記位置Y1 (用紙) (n_offy1_paper): 2.5; 追記位置Y1 (用紙) (n_offy1_M): 0.0025; 追記位置X2 (用紙) (n_offx2_paper): -11; 追記位置X2 (用紙) (n_offx2_M): -0.011; 追記位置Y2 (用紙) (n_offy2_paper): -2.5; 追記位置Y2 (用紙) (n_offy2_M): -0.0025; 追記位置X3 (用紙) (n_offx3_paper): 11; 追記位置X3 (用紙) (n_offx3_M): 0.011; 追記位置Y3 (用紙) (n_offy3_paper): 2.5; 追記位置Y3 (用紙) (n_offy3_M): 0.0025; 追記位置X4 (用紙) (n_offx4_paper): 11; 追記位置X4 (用紙) (n_offx4_M): 0.011; 追記位置Y4 (用紙) (n_offy4_paper): -2.5; 追記位置Y4 (用紙) (n_offy4_M): -0.0025; サイズ表示位置X (用紙) (size_anno_x_paper): 5; サイズ表示位置X (用紙) (size_anno_x_M): 0.005; サイズ表示位置Y (用紙) (size_anno_y_paper): 0; サイズ表示位置Y (用紙) (size_anno_y_M): 0; 法規制マーカー: yes; マーカーサイズ (用紙) (r_dia_paper): 2; マーカーサイズ (用紙) (r_dia_M): 0.002; マーカー塗りつぶしあり/なし: no; マーカー塗りつぶし背景ペン: 透過; マーカー塗りつぶし: 25 %; 建具下端レベルは壁を基準とする: no; 建具表平面表示: no; 離れX (用紙) (r_lenb_paper): 0; 離れX (用紙) (r_lenb_M): 0; 離れY (用紙) (r_lena_paper): -5; 離れY (用紙) (r_lena_M): -0.005; MO API ドアコード: 15; 抱き形状: 1; 横枠形状 (ui_shape2D): 3; 下枠非表示オプション: 2; 横枠形状 (d_s_s): 3; 上枠形状: 3; 壁断面形状: 1; 傾斜壁角度１: 90 deg; 傾斜壁角度２: 90 deg; 連続個数: 1; 扉スタイル (stPanel_Style): フラッシュ; 扉スタイル (iPanel_Style): 4; サブ扉スタイル: フラッシュ; ハンドル表記: なし; ガラスの水平分割数: 4; ガラスの垂直分割数: 2; 欄間スタイル (stTransom_Style): サイドパネル; 欄間スタイル (iTransom_Style): 2; 無目 種類 (middle_bar_type): 3; 沓摺 形状: 1; 開き角度: 0 deg; 3Dでの開口線: no; 平面図開口線: no; 3Dでのガラス表現: no; 2Dでの開口線の線種: 1; 平面図中心線: no; 枠材質 (matframe): ペイント - サンドベージュ; 沓摺材質: ペイント - サンドベージュ; ドア材質: ペイント - サンドベージュ; ドア内部材質にリンク: yes; 内部ドア材質: ペイント - サンドベージュ; ルーバー材質: 金属 - アルミニウム; ガラス材質: ガラス - シンプル; 取っ手材質: 金属 - ステンレス; 紙材質: プラスチック - 光沢 白; 幕板材質: ペイント - サンドベージュ; 気密: 未定; 遮音: 未定; 枠 材質: 未定; 枠 仕上: 未定; 沓摺 材質: 未定; 沓摺 仕上: 未定; ドアタイプ: 未定; 扉 材質: 未定; 扉 仕上: 未定; 無目 種類 (stTransom_Glasstype): スチールパネル; ガラス 種類: 未定; ガラス 厚: 未定; ガラリ 形状: 未定; ガラリ 機構: 未定; ガラリ 材質: 未定; ガラリ 仕上: 未定; ロックセット: 未定; 握玉: 未定; ヒンジ: 未定; クローザー: 未定; 戸当り: 未定; フランス落し: 未定; 順位調整器: 未定; チェーンロック: 未定; ドアアイ: 未定; ポスト: 未定; 価格: 0; 自動マーカーのドア名: ドア10; 平面図中心線種: 1; 外側層の延長: no; 内側層の延長: no; 延長線種: 1; 延長する内側層の数: 0; 延長する外側層の数: 0; 2Dシンボル表示のMVOを上書き: no; ドア3D投影のMVOを上書き: no; 簡易開いた扉線: no; ドア扉線の表示: no; 3D開口線 側面: 3; 3Dガラスシンボル 側面: 3; 並べ替え用通し番号: 0
採光計算 - 窓から隣地境界線までの距離: 4; 窓の中心高さ: 1.05 mm
排煙・換気計算 - 天井面の高さ: 0; 有効開口幅: 0; 開き角度: 0; 天井面より80cm以内の距離: 0.8; 窓の上端高さから天井面までの距離: -2.05; 排煙有効開口面積(引違い・片引き等): 0; 有効排煙開口率: 0; 排煙有効開口面積(横軸・外倒し・内倒し等): 0
AC_Pset_RenovationAndPhasing - Renovation Status: Existing
Pset_DoorCommon - IsExternal: yes
BaseQuantities - Height: 2130 mm; Volume: 0 m3; NetVolume: 0 m3
ArchiCADQuantities - 高さ: 2100 mm; 正味体積: 0 m3; GLからの高度: 0 mm; 高度 1: 0 mm; 高度 2: 0 mm; 海抜までの高度: 0 mm; リンク/配置フロアまでの高度: 0 mm; 下部オフセット: 0 mm; 上端高度から第1基準レベル: 2130 mm; 上端高度から配置フロア: 2130 mm; 上端高度から基準レベル: 2130 mm; 上端高度から海抜: 2130 mm; 上端高度から第2基準レベル: 2130 mm; 窓/ドア外壁側開口部高さ: 2130 mm; 窓/ドア外壁反対側開口部高さ: 2130 mm; 窓/ドア外壁側公称開口部高さ: 2150 mm; 窓/ドア外壁反対側公称開口部高さ: 2150 mm; 下端/上端値: 0 mm; 窓/ドア公称下端高さ: 0 mm; 窓/ドア外壁側下端高さ: 0 mm; 窓/ドア外壁反対側下端高さ: 0 mm; 窓/ドア公称上端高さ: 2100 mm; 窓/ドア外壁側上端高さ: 2050 mm; 窓/ドア外壁反対側上端高さ: 2050 mm; 枠厚さ: 100 mm
AC_Equantity_自由開き戸 - 下部レベル: 1000 mm; 上部レベル: 0 mm; 壁躯体に抱き: -10 mm; 枠見込 (gs_frame_thk): 100 mm; 枠見付: 50 mm; 扉厚さ (gs_leaf_thk): 40 mm; AC左開口部拡張サイズ: 50 mm; AC右開口部拡張サイズ: 50 mm; AC上開口部拡張サイズ: 50 mm; AC下開口部拡張サイズ: 0 mm; 有効開口高さ: 2100 mm; 枠内高さ: 2100 mm; 下部オフセット: 0 mm; 壁開口高さ: 2150 mm; 抱き高さ: 2100 mm; ユニット高さ: 2100 mm; 開口高さ (ac_egress_height): 2100 mm; 開口高さ (gs_opening_height): 2100 mm; パネル高さ: 2100 mm; マーカーサイズ (k_dia): 420 mm; 離れX (k_lenb): 0 mm; 離れY (k_lena): 1300 mm; 離れオフセット: 0 mm; 追記位置X1: -700 mm; 追記位置Y1: 250 mm; 追記位置X2: -700 mm; 追記位置Y2: -250 mm; 追記位置X3: 700 mm; 追記位置Y3: 250 mm; 追記位置X4: 700 mm; 追記位置Y4: -250 mm; サイズ表示位置X: 500 mm; サイズ表示位置Y: 0 mm; マーカーサイズ (r_dia): 200 mm; 床とFLのレベル差: 0 mm; 壁下端レベル: 0 mm; 離れX (r_lenb): 0 mm; 離れY (r_lena): -500 mm; フロアレベルから建具下端までの高さ: 0 mm; 中間壁までの距離: 0 mm; 外壁までの距離: 0 mm; 開口側面幅1: 100 mm; 開口側面幅2: 100 mm; 開口側面奥行き: 1800 mm; 反対側側面幅1: 100 mm; 反対側側面幅2: 100 mm; 反対側側面奥行き: 1800 mm; 反対側側面幅: 1100 mm; 枠見付（縦）: 25 mm; 上枠見付: 25 mm; 枠見付（中間表示）: 30 mm; 扉厚さ (p2): 45 mm; ちり１: 10 mm; ちり２: 10 mm; 逃げ（横）: 50 mm; 逃げ-上: 50 mm; ハンドル取付位置（端から）: 70 mm; ハンドル取付位置（高さ）: 1000 mm; パネル内開口幅: 150 mm; パネル内開口高さ（上）: 800 mm; パネル内開口高さ（下）: 500 mm; パネル端との距離: 150 mm; パネル下端との距離: 150 mm; パネル上端との距離: 150 mm; スリット窓ガラリ間隔: 200 mm; 無目見付（0＝欄間なし）: 0 mm; 無目見付: 100 mm; 無目見込: 0 mm; 外側仕上げ厚: 0 mm; 内側仕上げ厚: 0 mm; 内部１層目仕上げ厚: 0 mm; 錠位置X: -500 mm; 錠位置Y: 0 mm; 中心からの距離: 100 mm; 抱き奥行き: -10 mm; 扉出幅: 30 mm
Name | OverallWidth (mm) = 窓/ドア外壁側公称開口部幅 (mm) = 窓/ドア外壁反対側公称開口部幅 (mm) = 壁開口幅 (mm) | 要素ID = ホットリンクおよび要素ID | 関連ゾーン名 | 関連ゾーン番号 | 親ID = 壁ID | ゾーンから | ゾーン番号から | 抱き寸法 = ユニット寸法 = 間口寸法 = 扉寸法 = 公称幅x高さ | 壁開口寸法 | 公称幅x高さx厚さ | 方向 | ホットスポット(0-なし,1-2D,2-3D,3-全て) | Width (mm) = 窓/ドア外壁側開口部幅 (mm) = 窓/ドア外壁反対側開口部幅 (mm) | Perimeter (mm) | Area (m2) = 窓/ドア外壁側開口部面積 (m2) | Depth (mm) = 壁厚さ (mm) | 幅 (mm) = 枠内幅 (mm) = 抱き幅 (mm) = ユニット幅 (mm) = 開口幅 (ac_egress_width) (mm) = 開口幅 (gs_opening_width) (mm) = 可動部の幅 (mm) | 表面積 (m2) = 窓/ドア開口 表面積 (m2) | 下端高度から第1基準レベル (mm) = 下端高度から配置フロア (mm) = 下端高度から基準レベル (mm) = 下端高度から海抜 (mm) = 下端高度から第2基準レベル (mm) | 窓/ドア開口 開口部体積 (m3) | 窓/ドア開口部公称体積 (m3) | 窓/ドア開口面積 (m2) | 窓/ドア外壁反対側開口部面積 (m2) | 窓/ドア抱き側開口面積 (m2) = 窓/ドア抱き反対側開口面積 (m2) | 有効開口幅 (mm) | 枠見込 (p3) (mm)
SD4 | 1700 | SD4 | 店舗 | 101 | W2 | 店舗 | 101 | 1,600.0×2,100.0 | 1,700.0×2,150.0 | 1,600.0×2,100.0×250.0 | 左 | 3 | 1660 | 7580 | 3.5358 | 250 | 1600 | 6.6566 | -1.53081e-14 | 0.88395 | 0.84 | 3.36 | 3.5358 | 3.655 | 1540 | 270
SD4 | 1700 | SD4 | 店舗 | 102 | W3 |  |  | 1,600.0×2,100.0 | 1,700.0×2,150.0 | 1,600.0×2,100.0×250.0 | 右 | 3 | 1660 | 7580 | 3.5358 | 250 | 1600 | 6.6566 | -1.53081e-14 | 0.88395 | 0.84 | 3.36 | 3.5358 | 3.655 | 1540 | 270 | ArchiCADProperties - ゾーンへ: 店舗; ゾーン番号へ: 102
SD5 | 1700 | SD5 | 店舗 | 103 | W4 |  |  | 1,600.0×2,100.0 | 1,700.0×2,150.0 | 1,600.0×2,100.0×250.0 | 右 | 3 | 1660 | 7580 | 3.5358 | 250 | 1600 | 6.6566 | -1.53081e-14 | 0.88395 | 0.84 | 3.36 | 3.5358 | 3.655 | 1540 | 270 | ArchiCADProperties - ゾーンへ: 店舗; ゾーン番号へ: 103
SD5 | 1600 | SD5 | 廊下 | ＜ゾーン番号＞ | W2 | 廊下 | ＜ゾーン番号＞ | 1,500.0×2,100.0 | 1,600.0×2,150.0 | 1,500.0×2,100.0×250.0 | 右 | 3 | 1560 | 7380 | 3.3228 | 250 | 1500 | 6.3906 | -1.18768e-13 | 0.8307 | 0.7875 | 3.15 | 3.3228 | 3.44 | 1440 | 270
SD4 | 1700 | SD4 | 店舗 | 105 | W4 | 店舗 | 105 | 1,600.0×2,100.0 | 1,700.0×2,150.0 | 1,600.0×2,100.0×250.0 | 左 | 3 | 1660 | 7580 | 3.5358 | 250 | 1600 | 6.6566 | -1.53081e-14 | 0.88395 | 0.84 | 3.36 | 3.5358 | 3.655 | 1540 | 270
SD5 | 1700 | SD5 | 店舗 | 106 | W5 | 店舗 | 106 | 1,600.0×2,100.0 | 1,700.0×2,150.0 | 1,600.0×2,100.0×250.0 | 左 | 3 | 1660 | 7580 | 3.5358 | 250 | 1600 | 6.6566 | -1.53081e-14 | 0.88395 | 0.84 | 3.36 | 3.5358 | 3.655 | 1540 | 270
SD6 | 1700 | SD6 | 店舗 | 107 | W6 | 店舗 | 107 | 1,600.0×2,100.0 | 1,700.0×2,150.0 | 1,600.0×2,100.0×250.0 | 左 | 3 | 1660 | 7580 | 3.5358 | 250 | 1600 | 6.6566 | -1.53081e-14 | 0.88395 | 0.84 | 3.36 | 3.5358 | 3.655 | 1540 | 270
SD7 | 1700 | SD7 | 店舗 | 108 | W7 | 店舗 | 108 | 1,600.0×2,100.0 | 1,700.0×2,150.0 | 1,600.0×2,100.0×250.0 | 左 | 3 | 1660 | 7580 | 3.5358 | 250 | 1600 | 6.6566 | -1.53081e-14 | 0.88395 | 0.84 | 3.36 | 3.5358 | 3.655 | 1540 | 270
SD6 | 1700 | SD6 | 店舗 | 104 | W8 | 店舗 | 104 | 1,600.0×2,100.0 | 1,700.0×2,150.0 | 1,600.0×2,100.0×250.0 | 左 | 2 | 1660 | 7580 | 3.53964 | 250 | 1600 | 6.6566 | -4.58113e-14 | 0.884931 | 0.84 | 3.36 | 3.5398 | 3.655 | 1540 | 270
SD5 | 1600 | SD5 | 廊下 | ＜ゾーン番号＞ | W9 | 廊下 | ＜ゾーン番号＞ | 1,500.0×2,100.0 | 1,600.0×2,150.0 | 1,500.0×2,100.0×150.0 | 左 | 3 | 1560 | 7380 | 3.3228 | 150 | 1500 | 5.2326 | -1.15707e-13 | 0.49842 | 0.4725 | 3.15 | 3.3228 | 3.44 | 1440 | 170

# IfcDoor: 親子開き戸 (16)
Type - ParameterTakesPrecedence: no; Sizeable: no
OverallHeight: 2165 mm; Classification: ドア (ARCHICAD 分類)
ArchiCADProperties - 要素ID: SD3; レイヤー: 壁-躯体; ライブラリ部品名: 親子開き戸; ビルディングマテリアル/複合構造/断面形状/塗りつぶし: 背景; 塗りつぶし種類: 背景; 関連ゾーン番号: ＜ゾーン番号＞; 要素タイプ: ドア; 材質 (全て): ペイント - サンドベージュ; ゾーン番号へ: ＜ゾーン番号＞; リノベーションフィルタで表示: 全ての関連フィルタ; 構造機能: 非構造耐力要素; 位置: インテリア; リノベーションステータス: 既存; 壁構造: コンクリート; 開口部 ライブラリ部品名: 親子開き戸; 開口部 側面塗りつぶし索引: 背景; ARCHICAD 分類 - v 2.0: ドア
AC_Pset_親子開き戸 - 壁輪郭(0-なし,1-全て,2-側面,3-長さ): 0; ホットスポット(0-なし,1-2D,2-3D,3-全て): 3; 2Dホットスポットを3Dで表示: yes; 開口部は壁側面の材質: no; 開口の側面を曲線壁に沿う: no; 抱き配置位置: 1; 開口角度2D: 90 deg; 開口角度3D: 0 deg; 枠材質 (gs_frame_mat): 木材 - マツ 木目 横; パネル材質: 木材 - マツ 木目 横; 公称サイズ: 2; 有効開口を公称サイズに設定: no; 枠内を公称サイズに設定: no; 壁開口を公称サイズに設定: no; 内寸を公称サイズに設定: yes; 現在の公称サイズを選択に切り替え: no; 詳細レベル: 1; 詳細表現をスケールに連動 (iDetLevel): 1; 詳細表現をスケールに連動 (scale_link): yes; 詳細表現スケールn (1/1 - 1/n): 50; 中間表現スケールm （1/n～1/m): 100; 2D 表示 (iViewtype_2D): 1; 断面表示: 1; 2D建具背面の無地塗つぶし: no; 額縁表現: 2; 2D額縁塗りつぶし: 木材1; 曲線壁の開口部でホットスポットを表示: no; ドア沓摺線 2D: no; 建具種類: SD; 建具番号: 7; 法規制: 未定; 内外区分: 内; 形式: 親子開き戸; 建具識別コード（0=窓,1=ドア,2=シャッター,3=エレベーター): 1; 接続されたゾーンを値として使用: no; IFC操作 (ifc_optypestr): 未定義; IFC操作 (ifc_optype): 0; キープラン表示: yes; マーカータイプをスケールに連動: yes; マーカータイプ: タイプ1; 枝番(0=なし): 0; 建具サイズ表示: no; 建具符号方向: 任意角度; 建具符号任意角度: 0 deg; 用紙スケール: no; マーカーサイズ (用紙) (k_dia_paper): 4.2; マーカーサイズ (用紙) (k_dia_M): 0.0042; 離れX (用紙) (k_lenb_paper): 0; 離れX (用紙) (k_lenb_M): 0; 離れY (用紙) (k_lena_paper): 10; 離れY (用紙) (k_lena_M): 0.01; 離れオフセット (用紙) (k_lenc_paper): 0; 離れオフセット (用紙) (k_lenc_M): 0; 引き出し線角度: 0 deg; 引き出し線: no; ID表示: no; 線種: 1; 建具記号で塗りつぶしを使用: no; 建具記号塗りつぶし種類: 背景; フォント: Meiryo UI 日本語; 字サイズユーザー設定: no; 字サイズ: 1.4; 追記文字サイズ (mm): 1.43; 建具文字サイズ (mm): 1.43; 建具番号-枝番: 7; 追記位置X1 (用紙) (n_offx1_paper): -11; 追記位置X1 (用紙) (n_offx1_M): -0.011; 追記位置Y1 (用紙) (n_offy1_paper): 2.5; 追記位置Y1 (用紙) (n_offy1_M): 0.0025; 追記位置X2 (用紙) (n_offx2_paper): -11; 追記位置X2 (用紙) (n_offx2_M): -0.011; 追記位置Y2 (用紙) (n_offy2_paper): -2.5; 追記位置Y2 (用紙) (n_offy2_M): -0.0025; 追記位置X3 (用紙) (n_offx3_paper): 11; 追記位置X3 (用紙) (n_offx3_M): 0.011; 追記位置Y3 (用紙) (n_offy3_paper): 2.5; 追記位置Y3 (用紙) (n_offy3_M): 0.0025; 追記位置X4 (用紙) (n_offx4_paper): 11; 追記位置X4 (用紙) (n_offx4_M): 0.011; 追記位置Y4 (用紙) (n_offy4_paper): -2.5; 追記位置Y4 (用紙) (n_offy4_M): -0.0025; サイズ表示位置X (用紙) (size_anno_x_paper): 5; サイズ表示位置X (用紙) (size_anno_x_M): 0.005; サイズ表示位置Y (用紙) (size_anno_y_paper): 0; サイズ表示位置Y (用紙) (size_anno_y_M): 0; 法規制マーカー: yes; マーカーサイズ (用紙) (r_dia_paper): 2; マーカーサイズ (用紙) (r_dia_M): 0.002; マーカー塗りつぶしあり/なし: no; マーカー塗りつぶし背景ペン: 透過; マーカー塗りつぶし: 25 %; 建具下端レベルは壁を基準とする: no; 建具表平面表示: no; 離れX (用紙) (r_lenb_paper): 0; 離れX (用紙) (r_lenb_M): 0; 離れY (用紙) (r_lena_paper): -5; 離れY (用紙) (r_lena_M): -0.005; MO API ドアコード: 16; 抱き形状: 1; 横枠形状 (ui_shape2D): 1; 下枠非表示オプション: 2; 横枠形状 (d_s_s): 1; 上枠形状: 1; 枠 材質2: 未定; 壁断面形状: 1; 傾斜壁角度１: 90 deg; 傾斜壁角度２: 90 deg; 飾り袖: yes; ネームプレート (詳細時): yes; 連続個数: 0; 扉スタイル (stPanel_Style): フラッシュ; 扉スタイル (iPanel_Style): 4; 子扉スタイル: フラッシュ; ハンドル表記: なし; ガラスの水平分割数: 4; ガラスの垂直分割数: 2; 欄間スタイル (stTransom_Style): サイドパネル; 欄間スタイル (iTransom_Style): 2; 無目 種類 (middle_bar_type): 1; 沓摺 形状: 1; 水切り有無: no; 開き角度: 0 deg; 3Dでの開口線: no; 平面図開口線: no; 3Dでのガラス表現: no; 2Dでの開口線の線種: 1; 2D開き角度-親: 90 deg; 2D開き角度-子: 90 deg; 平面図中心線: no; 枠材質 (matframe): ペイント - サンドベージュ; 沓摺材質: ペイント - サンドベージュ; ドア材質: ペイント - サンドベージュ; ドア内部材質にリンク: yes; 内部ドア材質: ペイント - サンドベージュ; 枠カバー材質: 木材 - 木01; ルーバー材質: 金属 - アルミニウム; ガラス材質: ガラス - シンプル; 取っ手材質: 金属 - ステンレス; 紙材質: プラスチック - 光沢 白; 幕板材質: ペイント - サンドベージュ; ネームプレートユニット材質: ペイント - サンドベージュ; 新聞ポスト材質: 金属 - ステンレス; ネームプレート材質: 金属 - ステンレス; インターコムパネル材質: ペイント - アントラシート; 気密: 未定; 遮音: 未定; 枠 材質: 未定; 枠 仕上: 未定; 沓摺 材質: 未定; 沓摺 仕上: 未定; 水切り 材質: スチール; ドアタイプ: 未定; 扉 材質: 未定; 扉 仕上: 未定; 無目 種類 (stTransom_Glasstype): スチールパネル; ガラス 種類: 未定; ガラス 厚: 未定; ガラリ 形状: 未定; ガラリ 機構: 未定; ガラリ 材質: 未定; ガラリ 仕上: 未定; ロックセット: 未定; 握玉: 未定; ヒンジ: 未定; クローザー: 未定; 戸当り: 未定; フランス落し: 未定; 順位調整器: 未定; チェーンロック: 未定; ドアアイ: 未定; ポスト: 未定; 価格: 0; 自動マーカーのドア名: ドア11; 平面図中心線種: 1; 壁開口寸法タイプ: 1; 外側層の延長: no; 内側層の延長: no; 延長線種: 1; 延長する内側層の数: 0; 延長する外側層の数: 0; 2Dシンボル表示のMVOを上書き: no; ドア3D投影のMVOを上書き: no; 簡易開いた扉線: no; ドア扉線の表示: no; 3D開口線 側面: 3; 3Dガラスシンボル 側面: 3; 並べ替え用通し番号: 0
採光計算 - 窓から隣地境界線までの距離: 4
排煙・換気計算 - 天井面の高さ: 0; 有効開口幅: 0; 開き角度: 0; 天井面より80cm以内の距離: 0.8; 窓の上端高さから天井面までの距離: -2.035; 排煙有効開口面積(引違い・片引き等): 0; 有効排煙開口率: 0; 排煙有効開口面積(横軸・外倒し・内倒し等): 0
AC_Pset_RenovationAndPhasing - Renovation Status: Existing
Pset_DoorCommon - IsExternal: no
BaseQuantities - Height: 2130 mm; Volume: 0 m3; Depth: 150 mm; NetVolume: 0 m3
ArchiCADQuantities - 高さ: 2100 mm; 正味体積: 0 m3; リンク/配置フロアまでの高度: 0 mm; 下部オフセット: 0 mm; 上端高度から配置フロア: 2130 mm; 窓/ドア外壁側開口部高さ: 2130 mm; 窓/ドア外壁反対側開口部高さ: 2130 mm; 窓/ドア外壁側公称開口部高さ: 2165 mm; 窓/ドア外壁反対側公称開口部高さ: 2165 mm; 下端/上端値: 0 mm; 窓/ドア公称下端高さ: 0 mm; 窓/ドア外壁側下端高さ: 0 mm; 窓/ドア外壁反対側下端高さ: 0 mm; 窓/ドア公称上端高さ: 2100 mm; 窓/ドア外壁側上端高さ: 2035 mm; 窓/ドア外壁反対側上端高さ: 2035 mm; 壁厚さ: 150 mm; 枠厚さ: 100 mm
AC_Equantity_親子開き戸 - 下部レベル: 1000 mm; 上部レベル: 0 mm; 壁躯体に抱き: -10 mm; 枠見込 (gs_frame_thk): 100 mm; 枠見付: 50 mm; 扉厚さ (gs_leaf_thk): 40 mm; AC左開口部拡張サイズ: 65 mm; AC右開口部拡張サイズ: 65 mm; AC上開口部拡張サイズ: 65 mm; AC下開口部拡張サイズ: 0 mm; 有効開口高さ: 2100 mm; 枠内高さ: 2115 mm; 下部オフセット: 0 mm; 壁開口高さ: 2165 mm; 抱き高さ: 2100 mm; ユニット高さ: 2100 mm; 開口高さ (ac_egress_height): 2100 mm; 開口高さ (gs_opening_height): 2100 mm; パネル高さ: 2115 mm; マーカーサイズ (k_dia): 420 mm; 離れX (k_lenb): 0 mm; 離れY (k_lena): 1500 mm; 離れオフセット: 0 mm; 追記位置X1: -700 mm; 追記位置Y1: 250 mm; 追記位置X2: -700 mm; 追記位置Y2: -250 mm; 追記位置X3: 700 mm; 追記位置Y3: 250 mm; 追記位置X4: 700 mm; 追記位置Y4: -250 mm; サイズ表示位置X: 500 mm; サイズ表示位置Y: 0 mm; マーカーサイズ (r_dia): 200 mm; 床とFLのレベル差: 0 mm; 壁下端レベル: 0 mm; 離れX (r_lenb): 0 mm; 離れY (r_lena): -500 mm; フロアレベルから建具下端までの高さ: 0 mm; 中間壁までの距離: 0 mm; 外壁までの距離: 0 mm; 開口側面幅1: 300 mm; 開口側面幅2: 100 mm; 開口側面奥行き: 1200 mm; 反対側側面幅1: 300 mm; 反対側側面幅2: 100 mm; 反対側側面奥行き: 1200 mm; 反対側側面幅: 1100 mm; 枠見付（縦）: 25 mm; 上枠見付: 25 mm; 枠見付（中間表示）: 30 mm; 枠見込 (p3): 170 mm; 扉厚さ (p2): 45 mm; 枠見付２（縦）: 40 mm; 上枠見付２: 40 mm; 戸当たり見付: 15 mm; 戸当たり見込: 50 mm; ちり１: 10 mm; ちり２: 10 mm; 抱き寸法: 65 mm; 逃げ（横）: 65 mm; 逃げ-上: 65 mm; 抱き逃げ: 15 mm; 床レベル差（沓摺）: 100 mm; 飾り袖幅: 300 mm; ハンドル取付位置（端から）: 70 mm; ハンドル取付位置（高さ）: 1000 mm; パネル内開口幅: 150 mm; パネル内開口高さ（上）: 800 mm; パネル内開口高さ（下）: 500 mm; パネル端との距離: 150 mm; パネル下端との距離: 150 mm; パネル上端との距離: 150 mm; スリット窓ガラリ間隔: 200 mm; 子扉内開口幅: 150 mm; 子扉内開口高さ（上）: 800 mm; 子扉内開口高さ（下）: 500 mm; 子扉内開口とパネル横端との距離: 150 mm; 子扉内開口とパネル下端との距離: 150 mm; 子扉内開口とパネル上端との距離: 150 mm; 子扉内開口とスリット窓ガラリ間隔: 200 mm; 無目見付（0＝欄間なし）: 0 mm; 無目見付: 100 mm; 無目見込: 95 mm; 水切りの出: 60 mm; 外側仕上げ厚: 0 mm; 内側仕上げ厚: 0 mm; 内部１層目仕上げ厚: 0 mm; 錠位置X: -500 mm; 錠位置Y: 0 mm; 中心からの距離: 100 mm; 抱き奥行き: -10 mm; 扉出幅: 30 mm; 戸当り 上部: 15 mm; 額縁幅: 10 mm; 抱き仕上厚: 0 mm; 転び: 0 mm; 欠込寸法 （横）: 25 mm; 欠込寸法 （上）: 25 mm
Name | In | OverallWidth (mm) = 窓/ドア外壁側公称開口部幅 (mm) = 窓/ドア外壁反対側公称開口部幅 (mm) = 壁開口幅 (mm) | ホットリンクおよび要素ID | 関連ゾーン名 = ゾーンへ | ロック状態 | ホームフロア名 | ホームフロア数 | 親ID = 壁ID | ゾーンから | ゾーン番号から | 抱き寸法 = ユニット寸法 = 間口寸法 = 公称幅x高さ | 壁開口寸法 | 扉寸法 | 公称幅x高さx厚さ | 方向 | Width (mm) = 窓/ドア外壁側開口部幅 (mm) = 窓/ドア外壁反対側開口部幅 (mm) | Perimeter (mm) | Area (m2) = 窓/ドア外壁側開口部面積 (m2) = 窓/ドア外壁反対側開口部面積 (m2) | 幅 (mm) = 抱き幅 (mm) = ユニット幅 (mm) = 開口幅 (ac_egress_width) (mm) = 開口幅 (gs_opening_width) (mm) | GLからの高度 (mm) = 高度 1 (mm) = 高度 2 (mm) = 海抜までの高度 (mm) | 表面積 (m2) = 窓/ドア開口 表面積 (m2) | 上端高度から第1基準レベル (mm) = 上端高度から基準レベル (mm) = 上端高度から海抜 (mm) = 上端高度から第2基準レベル (mm) | 下端高度から第1基準レベル (mm) = 下端高度から基準レベル (mm) = 下端高度から海抜 (mm) = 下端高度から第2基準レベル (mm) | 下端高度から配置フロア (mm) | 窓/ドア開口 開口部体積 (m3) | 窓/ドア開口部公称体積 (m3) | 窓/ドア開口面積 (m2) | 窓/ドア抱き側開口面積 (m2) = 窓/ドア抱き反対側開口面積 (m2) | 有効開口幅 (mm) | 枠内幅 (mm) = 可動部の幅 (mm) | 親扉の幅 (mm) | 窓の中心高さ (mm) | ホットリンク マスタID
SD3 | 1FL | 2130 | SD3 | 共用スペー | no | 1FL | 1 | W0 | 管理室 | ＜ゾーン番号＞ | 2,000.0×2,100.0 | 2,130.0×2,165.0 | 2,030.0×2,115.0 | 2,000.0×2,100.0×150.0 | 右 | 2060 | 8380 | 4.3878 | 2000 | 0 | 6.4626 | 2130 | -1.71218e-13 | -1.71218e-13 | 0.65817 | 0.63 | 4.2 | 4.61145 | 1940 | 2030 | 1300 | 1.05
SD3 | 2FL | 1630 | SD3 | EVホール | no | 2FL | 2 | W4 | 廊下 | ＜ゾーン番号＞ | 1,500.0×2,100.0 | 1,630.0×2,165.0 | 1,530.0×2,115.0 | 1,500.0×2,100.0×150.0 | 右 | 1560 | 7380 | 3.3228 | 1500 | 3000 | 5.2326 | 5130 | 3000 | 0 | 0.49842 | 0.4725 | 3.15 | 3.52895 | 1440 | 1530 | 900 | 4.05
SD3 | 3FL | 1630 | SD3 | EVホール | no | 3FL | 3 | W9 | 事務室 | 312 | 1,500.0×2,100.0 | 1,630.0×2,165.0 | 1,530.0×2,115.0 | 1,500.0×2,100.0×150.0 | 左 | 1560 | 7380 | 3.3228 | 1500 | 6000 | 5.2326 | 8130 | 6000 | 0 | 0.49842 | 0.4725 | 3.15 | 3.52895 | 1440 | 1530 | 900 | 7.05
SD3 | 3FL | 1630 | SD3 | EVホール | no | 3FL | 3 | W4 | 廊下 | ＜ゾーン番号＞ | 1,500.0×2,100.0 | 1,630.0×2,165.0 | 1,530.0×2,115.0 | 1,500.0×2,100.0×150.0 | 右 | 1560 | 7380 | 3.3228 | 1500 | 6000 | 5.2326 | 8130 | 6000 | 0 | 0.49842 | 0.4725 | 3.15 | 3.52895 | 1440 | 1530 | 900 | 7.05
4FLSD3 | 4FL | 1630 | 4FLSD3 | EVホール | yes | 4FL | 4 | W9 | 事務室 | 312 | 1,500.0×2,100.0 | 1,630.0×2,165.0 | 1,530.0×2,115.0 | 1,500.0×2,100.0×150.0 | 左 | 1560 | 7380 | 3.3228 | 1500 | 9000 | 5.2326 | 11130 | 9000 | 0 | 0.49842 | 0.4725 | 3.15 | 3.52895 | 1440 | 1530 | 900 | 10.05 | 4FL
4FLSD3 | 4FL | 1630 | 4FLSD3 | EVホール | yes | 4FL | 4 | W4 | 廊下 | ＜ゾーン番号＞ | 1,500.0×2,100.0 | 1,630.0×2,165.0 | 1,530.0×2,115.0 | 1,500.0×2,100.0×150.0 | 右 | 1560 | 7380 | 3.3228 | 1500 | 9000 | 5.2326 | 11130 | 9000 | 0 | 0.49842 | 0.4725 | 3.15 | 3.52895 | 1440 | 1530 | 900 | 10.05 | 4FL
5FLSD3 | 5FL | 1630 | 5FLSD3 | EVホール | yes | 5FL | 5 | W9 | 事務室 | 312 | 1,500.0×2,100.0 | 1,630.0×2,165.0 | 1,530.0×2,115.0 | 1,500.0×2,100.0×150.0 | 左 | 1560 | 7380 | 3.3228 | 1500 | 12000 | 5.2326 | 14130 | 12000 | 0 | 0.49842 | 0.4725 | 3.15 | 3.52895 | 1440 | 1530 | 900 | 13.05 | 5FL
5FLSD3 | 5FL | 1630 | 5FLSD3 | EVホール | yes | 5FL | 5 | W4 | 廊下 | ＜ゾーン番号＞ | 1,500.0×2,100.0 | 1,630.0×2,165.0 | 1,530.0×2,115.0 | 1,500.0×2,100.0×150.0 | 右 | 1560 | 7380 | 3.3228 | 1500 | 12000 | 5.2326 | 14130 | 12000 | 0 | 0.49842 | 0.4725 | 3.15 | 3.52895 | 1440 | 1530 | 900 | 13.05 | 5FL
6FLSD3 | 6FL | 1630 | 6FLSD3 | EVホール | yes | 6FL | 6 | W9 | 事務室 | 312 | 1,500.0×2,100.0 | 1,630.0×2,165.0 | 1,530.0×2,115.0 | 1,500.0×2,100.0×150.0 | 左 | 1560 | 7380 | 3.3228 | 1500 | 15000 | 5.2326 | 17130 | 15000 | 0 | 0.49842 | 0.4725 | 3.15 | 3.52895 | 1440 | 1530 | 900 | 16.05 | 6FL
6FLSD3 | 6FL | 1630 | 6FLSD3 | EVホール | yes | 6FL | 6 | W4 | 廊下 | ＜ゾーン番号＞ | 1,500.0×2,100.0 | 1,630.0×2,165.0 | 1,530.0×2,115.0 | 1,500.0×2,100.0×150.0 | 右 | 1560 | 7380 | 3.3228 | 1500 | 15000 | 5.2326 | 17130 | 15000 | 0 | 0.49842 | 0.4725 | 3.15 | 3.52895 | 1440 | 1530 | 900 | 16.05 | 6FL
7FLSD3 | 7FL | 1630 | 7FLSD3 | EVホール | yes | 7FL | 7 | W9 | 事務室 | 312 | 1,500.0×2,100.0 | 1,630.0×2,165.0 | 1,530.0×2,115.0 | 1,500.0×2,100.0×150.0 | 左 | 1560 | 7380 | 3.3228 | 1500 | 18000 | 5.2326 | 20130 | 18000 | 0 | 0.49842 | 0.4725 | 3.15 | 3.52895 | 1440 | 1530 | 900 | 19.05 | 7FL
7FLSD3 | 7FL | 1630 | 7FLSD3 | EVホール | yes | 7FL | 7 | W4 | 廊下 | ＜ゾーン番号＞ | 1,500.0×2,100.0 | 1,630.0×2,165.0 | 1,530.0×2,115.0 | 1,500.0×2,100.0×150.0 | 右 | 1560 | 7380 | 3.3228 | 1500 | 18000 | 5.2326 | 20130 | 18000 | 0 | 0.49842 | 0.4725 | 3.15 | 3.52895 | 1440 | 1530 | 900 | 19.05 | 7FL
8FLSD3 | 8FL | 1630 | 8FLSD3 | EVホール | yes | 8FL | 8 | W9 | 事務室 | 312 | 1,500.0×2,100.0 | 1,630.0×2,165.0 | 1,530.0×2,115.0 | 1,500.0×2,100.0×150.0 | 左 | 1560 | 7380 | 3.3228 | 1500 | 21000 | 5.2326 | 23130 | 21000 | 0 | 0.49842 | 0.4725 | 3.15 | 3.52895 | 1440 | 1530 | 900 | 22.05 | 8FL
8FLSD3 | 8FL | 1630 | 8FLSD3 | EVホール | yes | 8FL | 8 | W4 | 廊下 | ＜ゾーン番号＞ | 1,500.0×2,100.0 | 1,630.0×2,165.0 | 1,530.0×2,115.0 | 1,500.0×2,100.0×150.0 | 右 | 1560 | 7380 | 3.3228 | 1500 | 21000 | 5.2326 | 23130 | 21000 | 0 | 0.49842 | 0.4725 | 3.15 | 3.52895 | 1440 | 1530 | 900 | 22.05 | 8FL
9FLSD3 | 9FL | 1630 | 9FLSD3 | EVホール | yes | 9FL | 9 | W9 | 事務室 | 312 | 1,500.0×2,100.0 | 1,630.0×2,165.0 | 1,530.0×2,115.0 | 1,500.0×2,100.0×150.0 | 左 | 1560 | 7380 | 3.3228 | 1500 | 24000 | 5.2326 | 26130 | 24000 | 0 | 0.49842 | 0.4725 | 3.15 | 3.52895 | 1440 | 1530 | 900 | 25.05 | 9FL
9FLSD3 | 9FL | 1630 | 9FLSD3 | EVホール | yes | 9FL | 9 | W4 | 廊下 | ＜ゾーン番号＞ | 1,500.0×2,100.0 | 1,630.0×2,165.0 | 1,530.0×2,115.0 | 1,500.0×2,100.0×150.0 | 右 | 1560 | 7380 | 3.3228 | 1500 | 24000 | 5.2326 | 26130 | 24000 | 0 | 0.49842 | 0.4725 | 3.15 | 3.52895 | 1440 | 1530 | 900 | 25.05 | 9FL

# IfcDoor: 防火戸2, FSD1
In: 1FL
Type - ParameterTakesPrecedence: no; Sizeable: no
OverallHeight: 2165 mm; OverallWidth: 1330 mm; Classification: ドア (ARCHICAD 分類)
ArchiCADProperties - 要素ID: FSD1; ホットリンクおよび要素ID: FSD1; レイヤー: 壁-躯体; ライブラリ部品名: 防火戸2; ビルディングマテリアル/複合構造/断面形状/塗りつぶし: 背景; 塗りつぶし種類: 背景; 関連ゾーン名: EVホール; 関連ゾーン番号: ＜ゾーン番号＞; ロック状態: no; ホームフロア名: 1FL; ホームフロア数: 1; 要素タイプ: ドア; 親ID: W4; 材質 (全て): ペイント - サンドベージュ; ゾーンから: 階段室; ゾーン番号から: ＜ゾーン番号＞; ゾーンへ: EVホール; ゾーン番号へ: ＜ゾーン番号＞; リノベーションフィルタで表示: 全ての関連フィルタ; 構造機能: 非構造耐力要素; 位置: インテリア; リノベーションステータス: 既存; 抱き寸法: 1,200.0×2,100.0; 壁開口寸法: 1,330.0×2,165.0; ユニット寸法: 1,200.0×2,100.0; 間口寸法: 1,200.0×2,100.0; 扉寸法: 1,230.0×2,110.0; 公称幅x高さ: 1,200.0×2,100.0; 公称幅x高さx厚さ: 1,200.0×2,100.0×150.0; 壁構造: コンクリート; 方向: 左; 開口部 ライブラリ部品名: 防火戸2; 開口部 側面塗りつぶし索引: 背景; ARCHICAD 分類 - v 2.0: ドア
AC_Pset_防火戸2 - 壁輪郭(0-なし,1-全て,2-側面,3-長さ): 0; ホットスポット(0-なし,1-2D,2-3D,3-全て): 3; 2Dホットスポットを3Dで表示: yes; 開口部は壁側面の材質: no; 開口の側面を曲線壁に沿う: no; 抱き配置位置: 1; 開口角度2D (gs_open_2D): 90 deg; 開口角度3D: 0 deg; 枠材質 (gs_frame_mat): 木材 - マツ 木目 横; パネル材質: 木材 - マツ 木目 横; 公称サイズ: 2; 有効開口を公称サイズに設定: no; 枠内を公称サイズに設定: no; 壁開口を公称サイズに設定: no; 内寸を公称サイズに設定: yes; 現在の公称サイズを選択に切り替え: no; 詳細: 1; 詳細表現スケールn (1/1 - 1/n): 50; 中間表現スケールm （1/n～1/m): 100; 2D建具背面の無地塗つぶし: no; 2D額縁塗りつぶし: 屋根板1; 曲線壁の開口部でホットスポットを表示: no; ドア沓摺線 2D: no; 建具種類: SD; 建具番号: 10; 法規制: 未定; 内外区分: 内; 形式: 防火戸; 建具識別コード（0=窓,1=ドア,2=シャッター,3=エレベーター): 1; 壁ID: W4; 接続されたゾーンを値として使用: no; IFC操作 (ifc_optypestr): 未定義; IFC操作 (ifc_optype): 0; キープラン表示: yes; マーカータイプをスケールに連動: yes; マーカータイプ: タイプ1; 枝番(0=なし): 0; 建具サイズ表示: no; 建具符号方向: 任意角度; 建具符号任意角度: 0 deg; 用紙スケール: no; マーカーサイズ (用紙) (k_dia_paper): 4.2; マーカーサイズ (用紙) (k_dia_M): 0.0042; 離れX (用紙) (k_lenb_paper): 0; 離れX (用紙) (k_lenb_M): 0; 離れY (用紙) (k_lena_paper): 10; 離れY (用紙) (k_lena_M): 0.01; 離れオフセット (用紙) (k_lenc_paper): 0; 離れオフセット (用紙) (k_lenc_M): 0; 引き出し線角度: 0 deg; 引き出し線: no; ID表示: no; 線種: 1; 建具記号で塗りつぶしを使用: no; 建具記号塗りつぶし種類: 背景; フォント: Meiryo UI 日本語; 字サイズユーザー設定: no; 字サイズ: 1.4; 追記文字サイズ (mm): 1.43; 建具文字サイズ (mm): 1.43; 建具番号-枝番: 10; 追記位置X1 (用紙) (n_offx1_paper): -11; 追記位置X1 (用紙) (n_offx1_M): -0.011; 追記位置Y1 (用紙) (n_offy1_paper): 2.5; 追記位置Y1 (用紙) (n_offy1_M): 0.0025; 追記位置X2 (用紙) (n_offx2_paper): -11; 追記位置X2 (用紙) (n_offx2_M): -0.011; 追記位置Y2 (用紙) (n_offy2_paper): -2.5; 追記位置Y2 (用紙) (n_offy2_M): -0.0025; 追記位置X3 (用紙) (n_offx3_paper): 11; 追記位置X3 (用紙) (n_offx3_M): 0.011; 追記位置Y3 (用紙) (n_offy3_paper): 2.5; 追記位置Y3 (用紙) (n_offy3_M): 0.0025; 追記位置X4 (用紙) (n_offx4_paper): 11; 追記位置X4 (用紙) (n_offx4_M): 0.011; 追記位置Y4 (用紙) (n_offy4_paper): -2.5; 追記位置Y4 (用紙) (n_offy4_M): -0.0025; サイズ表示位置X (用紙) (size_anno_x_paper): 5; サイズ表示位置X (用紙) (size_anno_x_M): 0.005; サイズ表示位置Y (用紙) (size_anno_y_paper): 0; サイズ表示位置Y (用紙) (size_anno_y_M): 0; 法規制マーカー: yes; マーカーサイズ (用紙) (r_dia_paper): 2; マーカーサイズ (用紙) (r_dia_M): 0.002; マーカー塗りつぶしあり/なし: no; マーカー塗りつぶし背景ペン: 透過; マーカー塗りつぶし: 25 %; 建具下端レベルは壁を基準とする: no; 建具表平面表示: no; 離れX (用紙) (r_lenb_paper): 0; 離れX (用紙) (r_lenb_M): 0; 離れY (用紙) (r_lena_paper): -5; 離れY (用紙) (r_lena_M): -0.005; 抱き形状: 1; 横枠形状 (ui_shape2D): 1; 下枠非表示オプション: 2; 横枠形状 (d_s_s): 1; 上枠形状: 1; 枠 材質2: 未定; 壁断面形状: 1; 傾斜壁角度１: 90 deg; 傾斜壁角度２: 90 deg; 連続個数: 1; 扉スタイル: フラッシュ; くぐり戸開きタイプ: 1; 開き方向変更: no; ホース口: no; ハンドル表記: なし; ガラスの水平分割数: 4; ガラスの垂直分割数: 2; 沓摺 形状: 1; 水切り有無: no; 開き角度: 0 deg; 3Dで閉じる: no; 3Dでの開口線: no; 平面図開口線: no; 3Dでのガラス表現: no; 2Dでの開口線の線種: 1; 2Dでのくぐり戸開口線: 28; 開口角度2D (opening_angle_2d): 90 deg; 平面図中心線: no; 枠材質 (matframe): ペイント - サンドベージュ; 沓摺材質: ペイント - サンドベージュ; ドア材質: ペイント - サンドベージュ; ルーバー材質: 金属 - アルミニウム; ガラス材質: ガラス - シンプル; 取っ手材質: 金属 - ステンレス; 紙材質: 木材 - マツ 木目 横; 気密: 未定; 遮音: 未定; 枠 材質: 未定; 枠 仕上: 未定; 沓摺 材質: 未定; 沓摺 仕上: 未定; 水切り 材質: スチール; ドアタイプ: 未定; 扉 材質: 未定; 扉 仕上: 未定; 無目 種類: 未定; ガラス 種類: 未定; ガラス 厚: 未定; ガラリ 形状: 未定; ガラリ 機構: 未定; ガラリ 材質: 未定; ガラリ 仕上: 未定; ロックセット: 未定; 握玉: 未定; ヒンジ: 未定; クローザー: 未定; 戸当り: 未定; フランス落し: 未定; 順位調整器: 未定; チェーンロック: 未定; ドアアイ: 未定; ポスト: 未定; 価格: 0; 自動マーカーのドア名: ドア14; 平面図中心線種: 1; 外側層の延長: no; 内側層の延長: no; 延長線種: 1; 延長する内側層の数: 0; 延長する外側層の数: 0; 2Dシンボル表示のMVOを上書き: no; ドア3D投影のMVOを上書き: no; ドア扉線の表示: no; 3D開口線 側面: 3; 3Dガラスシンボル 側面: 3; 並べ替え用通し番号: 0
採光計算 - 窓から隣地境界線までの距離: 4; 窓の中心高さ: 1.05 mm
排煙・換気計算 - 天井面の高さ: 0; 有効開口幅: 0; 開き角度: 0; 天井面より80cm以内の距離: 0.8; 窓の上端高さから天井面までの距離: -2.035; 排煙有効開口面積(引違い・片引き等): 0; 有効排煙開口率: 0; 排煙有効開口面積(横軸・外倒し・内倒し等): 0
AC_Pset_RenovationAndPhasing - Renovation Status: Existing
Pset_DoorCommon - IsExternal: no
BaseQuantities - Height: 2135 mm; Width: 2580 mm; Perimeter: 9430 mm; Area: 5.5083 m2; Volume: 0 m3; Depth: 150 mm; NetVolume: 0 m3
ArchiCADQuantities - 高さ: 2100 mm; 正味体積: 0 m3; 幅: 1200 mm; GLからの高度: 0 mm; 高度 1: 0 mm; 高度 2: 0 mm; 海抜までの高度: 0 mm; リンク/配置フロアまでの高度: 0 mm; 下部オフセット: 0 mm; 表面積: 4.61355 m2; 上端高度から第1基準レベル: 2135 mm; 上端高度から配置フロア: 2135 mm; 上端高度から基準レベル: 2135 mm; 上端高度から海抜: 2135 mm; 上端高度から第2基準レベル: 2135 mm; 下端高度から第1基準レベル: -9.79717e-15 mm; 下端高度から配置フロア: -9.79717e-15 mm; 下端高度から基準レベル: -9.79717e-15 mm; 下端高度から海抜: -9.79717e-15 mm; 下端高度から第2基準レベル: -9.79717e-15 mm; 窓/ドア開口 開口部体積: 0.5837 m3; 窓/ドア開口部公称体積: 0.378 m3; 窓/ドア開口 表面積: 4.61355 m2; 窓/ドア開口面積: 2.52 m2; 窓/ドア外壁側開口部幅: 2580 mm; 窓/ドア外壁側開口部高さ: 2135 mm; 窓/ドア外壁反対側開口部幅: 1280 mm; 窓/ドア外壁反対側開口部高さ: 2135 mm; 窓/ドア外壁側開口部面積: 5.5083 m2; 窓/ドア外壁反対側開口部面積: 2.7328 m2; 窓/ドア外壁側公称開口部幅: 1330 mm; 窓/ドア外壁側公称開口部高さ: 2165 mm; 窓/ドア外壁反対側公称開口部幅: 1330 mm; 窓/ドア外壁反対側公称開口部高さ: 2165 mm; 窓/ドア抱き側開口面積: 2.87945 m2; 窓/ドア抱き反対側開口面積: 2.87945 m2; 下端/上端値: 0 mm; 窓/ドア公称下端高さ: 0 mm; 窓/ドア外壁側下端高さ: 0 mm; 窓/ドア外壁反対側下端高さ: 0 mm; 窓/ドア公称上端高さ: 2100 mm; 窓/ドア外壁側上端高さ: 2035 mm; 窓/ドア外壁反対側上端高さ: 2035 mm; 壁厚さ: 150 mm; 枠厚さ: 100 mm
AC_Equantity_防火戸2 - 下部レベル: 1000 mm; 上部レベル: 0 mm; 壁躯体に抱き: -10 mm; 枠見込 (gs_frame_thk): 100 mm; 枠見付: 50 mm; 扉厚さ (gs_leaf_thk): 40 mm; AC左開口部拡張サイズ: 65 mm; AC右開口部拡張サイズ: 65 mm; AC上開口部拡張サイズ: 65 mm; AC下開口部拡張サイズ: 0 mm; 壁開口幅: 1330 mm; 壁開口高さ: 2165 mm; 抱き幅: 1200 mm; 抱き高さ: 2100 mm; ユニット幅: 1200 mm; ユニット高さ: 2100 mm; 開口幅 (ac_egress_width): 1200 mm; 開口高さ: 2100 mm; 可動部の幅: 1230 mm; パネル高さ: 2110 mm; 有効開口幅: 1200 mm; 有効開口高さ: 2100 mm; 開口幅 (gs_opening_width): 1200 mm; 開口部高さ: 2100 mm; 枠内幅: 1230 mm; 枠内高さ: 2110 mm; 下部オフセット: 0 mm; マーカーサイズ (k_dia): 420 mm; 離れX (k_lenb): 0 mm; 離れY (k_lena): 1500 mm; 離れオフセット: 0 mm; 追記位置X1: -700 mm; 追記位置Y1: 250 mm; 追記位置X2: -700 mm; 追記位置Y2: -250 mm; 追記位置X3: 700 mm; 追記位置Y3: 250 mm; 追記位置X4: 700 mm; 追記位置Y4: -250 mm; サイズ表示位置X: 500 mm; サイズ表示位置Y: 0 mm; マーカーサイズ (r_dia): 200 mm; 床とFLのレベル差: 0 mm; 壁下端レベル: 0 mm; 離れX (r_lenb): 0 mm; 離れY (r_lena): -500 mm; フロアレベルから建具下端までの高さ: 0 mm; 開口側面幅1: 300 mm; 開口側面幅2: 1000 mm; 開口側面奥行き: 1800 mm; 反対側側面幅1: 300 mm; 反対側側面幅2: 100 mm; 反対側側面奥行き: 1200 mm; 反対側側面幅: 1100 mm; 枠見付（縦）: 25 mm; 上枠見付: 25 mm; 枠見付（中間表示）: 30 mm; 枠見込 (p3): 170 mm; 扉厚さ (p2): 45 mm; 枠見付２（縦）: 40 mm; 上枠見付２: 40 mm; 戸当たり見付: 15 mm; 戸当たり見込: 50 mm; ちり１: 10 mm; ちり２: 10 mm; 抱き寸法: 65 mm; 逃げ（横）: 65 mm; 逃げ-上: 65 mm; 抱き逃げ: 15 mm; 床レベル差（沓摺）: 100 mm; 戸袋(幅): 1250 mm; 戸袋 (枠とパネルの隙間): 20 mm; 戸袋(奥行): 55 mm; 戸袋端部の逃げ: 45 mm; ハンドル取付位置（端から）: 70 mm; ハンドル取付位置（高さ）: 1000 mm; パネル内開口幅: 600 mm; パネル内開口高さ（上）: 0 mm; パネル内開口高さ: 1800 mm; パネル端との距離: 150 mm; パネル下端との距離: 150 mm; パネル上端との距離: 150 mm; 水切りの出: 60 mm; 外側仕上げ厚: 0 mm; 内側仕上げ厚: 0 mm; 内部１層目仕上げ厚: 0 mm; 錠位置X: -500 mm; 錠位置Y: 0 mm; 中心からの距離: 100 mm; 抱き奥行き: -10 mm; 戸当り 上部: 10 mm

# IfcOpeningElement (252)
Name | In | Depth (mm) | Height (mm) | Width (mm) | Area (m2) | Volume (m3)
SD2 | 1FL | 150 | 2130 | 3660 | 7.7958 | 0
SD1 | 1FL | 150 | 2730 | 3660 | 9.9918 | 0.0000025
3 x SD4 | 1FL | 250 | 2130 | 1660 | 3.5358 | 0
2 x SD5 | 1FL | 250 | 2130 | 1660 | 3.5358 | 0
SD5 | 1FL | 250 | 2130 | 1560 | 3.3228 | 0
SD6 | 1FL | 250 | 2130 | 1660 | 3.5358 | 0
SD7 | 1FL | 250 | 2130 | 1660 | 3.5358 | 0
SD3 | 1FL | 250 | 2130 | 960 | 2.0448 | 0
SD1 | 1FL | 250 | 2130 | 3660 | 7.7958 | 0
11 x SD3 | 1FL | 150 | 2130 | 960 | 2.0448 | 0
SD4 | 1FL | 150 | 2130 | 2060 | 4.3878 | 0
SD2 | 1FL | 150 | 2130 | 2860 | 6.0918 | 0
2 x SD4 | 1FL | 150 | 2130 | 2285 | 4.86705 | 0
3 x SD5 | 1FL | 150 | 2130 | 1060 | 2.2578 | 0.02961
SD3 | 1FL | 150 | 2130 | 2060 | 4.3878 | 0
FSD1 | 1FL | 150 | 2135 | 2580 | 5.5083 | 0
SD6 | 1FL | 250 | 2130 | 1660 | 3.53964 | 0
SD5 | 1FL | 150 | 2130 | 1560 | 3.3228 | 0
2 x SD3 | 1FL | 150 | 2130 | 760 | 1.6188 | 0
FSD2 | 2FL | 150 | 2130 | 1160 | 2.4708 | 0
4 x SD3 | 2FL | 150 | 2130 | 960 | 2.0448 | 0
7 x SD4 | 2FL | 150 | 2130 | 960 | 2.0448 | 0
4 x SD5 | 2FL | 150 | 2130 | 960 | 2.0448 | 0
3 x スラブ開口 | 2FL
エレベーターシャフト | 2FL | 6350 | 5925 | 2097.21 | 12.426 | 13.0473 | Classification: 一般開口 (ARCHICAD 分類); ArchiCADProperties - 要素ID: エレベーターシャフト; ホットリンクおよび要素ID: エレベーターシャフト; レイヤー: スラブ; ロック状態: no; ホームフロア名: 2FL; ホームフロア数: 2; 要素タイプ: 開口; 親ID: S2; 傾斜角度: 90 deg; リノベーションフィルタで表示: 全ての関連フィルタ; 位置: インテリア; リノベーションステータス: 既存; 形状: 長方形; 方向: 整列; 制限: 無限; 切断要素のID: S2; S2; S2; ARCHICAD 分類 - v 2.0: 一般開口; AC_Pset_RenovationAndPhasing - Renovation Status: Existing; ArchiCADQuantities - 面積: 12.426 m2; 高さ: 5925 mm; 正味体積: 13.0473 m3; 幅: 2097.21 mm; GLからの高度: 3000 mm; 高度 1: 3000 mm; 高度 2: 3000 mm; 海抜までの高度: 3000 mm; リンク/配置フロアまでの高度: 0 mm; 下部オフセット: 0 mm; 表面積: 16.8466 m2; 3D外周: 16044.4 mm; 上端高度から第1基準レベル: 6000 mm; 上端高度から配置フロア: 3000 mm; 上端高度から基準レベル: 6000 mm; 上端高度から海抜: 6000 mm; 上端高度から第2基準レベル: 6000 mm; 下端高度から第1基準レベル: -350 mm; 下端高度から配置フロア: -3350 mm; 下端高度から基準レベル: -350 mm; 下端高度から海抜: -350 mm; 下端高度から第2基準レベル: -350 mm; 全厚: 6350 mm; 切断要素の数: 3
SD3 | 2FL | 150 | 2130 | 1460 | 3.1098 | 0
2 x SD3 | 2FL | 150 | 2130 | 760 | 1.6188 | 0
SD4 | 2FL | 150 | 2130 | 1460 | 3.1098 | 0
FSD2 | 2FL | 250 | 2130 | 1160 | 2.4708 | 0
3 x SD5 | 2FL | 150 | 2130 | 1060 | 2.2578 | 0.02961
SD4 | 2FL | 150 | 2130 | 2060 | 4.3878 | 0
AW1 | 2FL | 150 | 2460 | 3600 | 8.856 | 0.08928
SD3 | 2FL | 150 | 2130 | 1560 | 3.3228 | 0
SD4 | 2FL | 150 | 2130 | 860 | 1.8318 | 0
SD3 | 2FL | 150 | 2130 | 860 | 1.8318 | 0
SD4 | 2FL | 150 | 2130 | 2285 | 4.86705 | 0
2 x SD3 | 3FL | 150 | 2130 | 1560 | 3.3228 | 0
FSD2 | 3FL | 150 | 2130 | 1160 | 2.4708 | 0
スラブ開口 | 3FL
2 x SD7 | 3FL | 150 | 2130 | 960 | 2.0448 | 0
SD8 | 3FL | 150 | 2130 | 960 | 2.0448 | 0
3 x SD9 | 3FL | 150 | 2130 | 960 | 2.0448 | 0
SD0 | 3FL | 150 | 2130 | 960 | 2.0448 | 0
SD1 | 3FL | 150 | 2130 | 960 | 2.0448 | 0
FSD2 | 3FL | 250 | 2130 | 1160 | 2.4708 | 0
2 x SD5 | 3FL | 150 | 2130 | 960 | 2.0448 | 0
3 x SD6 | 3FL | 150 | 2130 | 960 | 2.0448 | 0
SD3 | 3FL | 150 | 2130 | 960 | 2.0448 | 0
SD4 | 3FL | 150 | 2130 | 960 | 2.0448 | 0
2 x SD3 | 3FL | 150 | 2130 | 760 | 1.6188 | 0
3 x SD5 | 3FL | 150 | 2130 | 1060 | 2.2578 | 0.02961
SD4 | 3FL | 150 | 2130 | 2285 | 4.86705 | 0
4FLSD3 | 4FL | 150 | 2130 | 960 | 2.0448 | 0
4FLSD4 | 4FL | 150 | 2130 | 960 | 2.0448 | 0
2 x 4FLSD5 | 4FL | 150 | 2130 | 960 | 2.0448 | 0
3 x 4FLSD6 | 4FL | 150 | 2130 | 960 | 2.0448 | 0
4FLFSD2 | 4FL | 150 | 2130 | 1160 | 2.4708 | 0
スラブ開口 | 4FL
2 x 4FLSD7 | 4FL | 150 | 2130 | 960 | 2.0448 | 0
4FLSD8 | 4FL | 150 | 2130 | 960 | 2.0448 | 0
3 x 4FLSD9 | 4FL | 150 | 2130 | 960 | 2.0448 | 0
4FLSD0 | 4FL | 150 | 2130 | 960 | 2.0448 | 0
4FLSD1 | 4FL | 150 | 2130 | 960 | 2.0448 | 0
4FLFSD2 | 4FL | 250 | 2130 | 1160 | 2.4708 | 0
4FLSD4 | 4FL | 150 | 2130 | 2285 | 4.86705 | 0
2 x 4FLSD3 | 4FL | 150 | 2130 | 1560 | 3.3228 | 0
3 x 4FLSD5 | 4FL | 150 | 2130 | 1060 | 2.2578 | 0.02961
2 x 4FLSD3 | 4FL | 150 | 2130 | 760 | 1.6188 | 0
5FLSD3 | 5FL | 150 | 2130 | 960 | 2.0448 | 0
5FLSD4 | 5FL | 150 | 2130 | 960 | 2.0448 | 0
2 x 5FLSD5 | 5FL | 150 | 2130 | 960 | 2.0448 | 0
3 x 5FLSD6 | 5FL | 150 | 2130 | 960 | 2.0448 | 0
5FLFSD2 | 5FL | 150 | 2130 | 1160 | 2.4708 | 0
スラブ開口 | 5FL
2 x 5FLSD7 | 5FL | 150 | 2130 | 960 | 2.0448 | 0
5FLSD8 | 5FL | 150 | 2130 | 960 | 2.0448 | 0
3 x 5FLSD9 | 5FL | 150 | 2130 | 960 | 2.0448 | 0
5FLSD0 | 5FL | 150 | 2130 | 960 | 2.0448 | 0
5FLSD1 | 5FL | 150 | 2130 | 960 | 2.0448 | 0
5FLFSD2 | 5FL | 250 | 2130 | 1160 | 2.4708 | 0
5FLSD4 | 5FL | 150 | 2130 | 2285 | 4.86705 | 0
2 x 5FLSD3 | 5FL | 150 | 2130 | 1560 | 3.3228 | 0
3 x 5FLSD5 | 5FL | 150 | 2130 | 1060 | 2.2578 | 0.02961
2 x 5FLSD3 | 5FL | 150 | 2130 | 760 | 1.6188 | 0
6FLSD3 | 6FL | 150 | 2130 | 960 | 2.0448 | 0
6FLSD4 | 6FL | 150 | 2130 | 960 | 2.0448 | 0
2 x 6FLSD5 | 6FL | 150 | 2130 | 960 | 2.0448 | 0
3 x 6FLSD6 | 6FL | 150 | 2130 | 960 | 2.0448 | 0
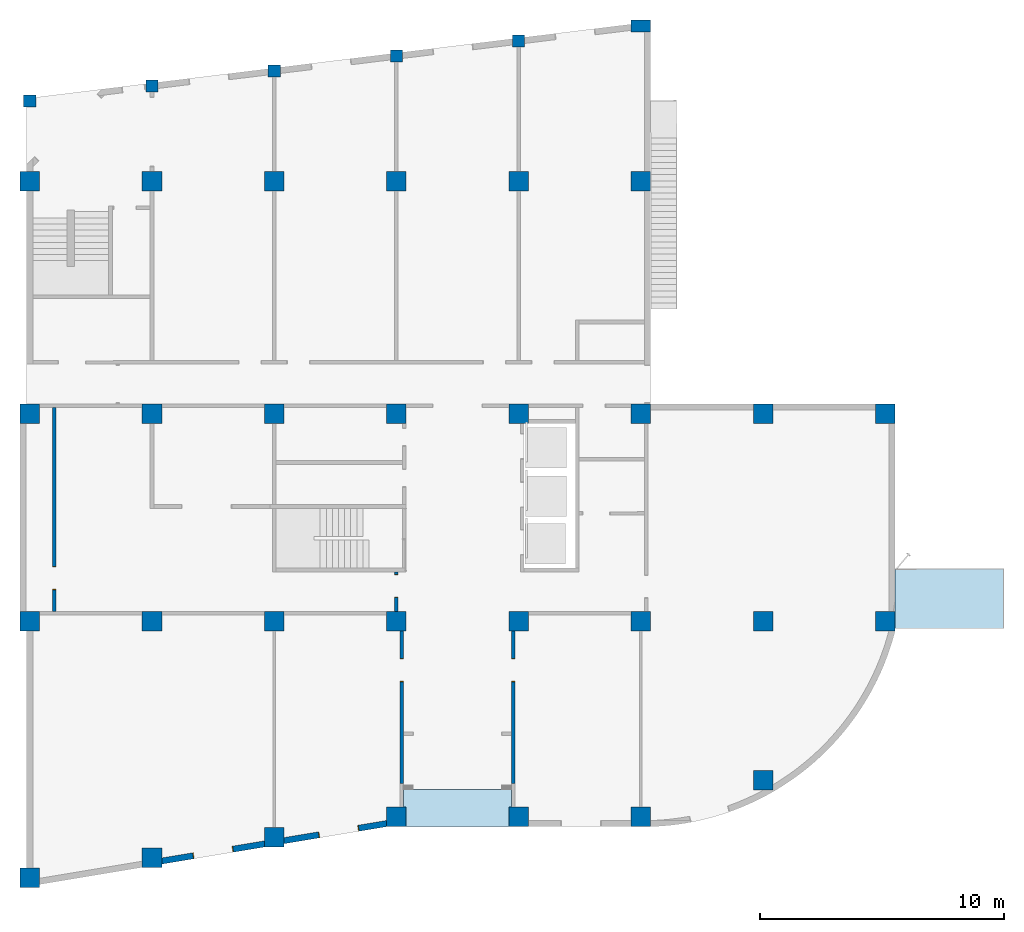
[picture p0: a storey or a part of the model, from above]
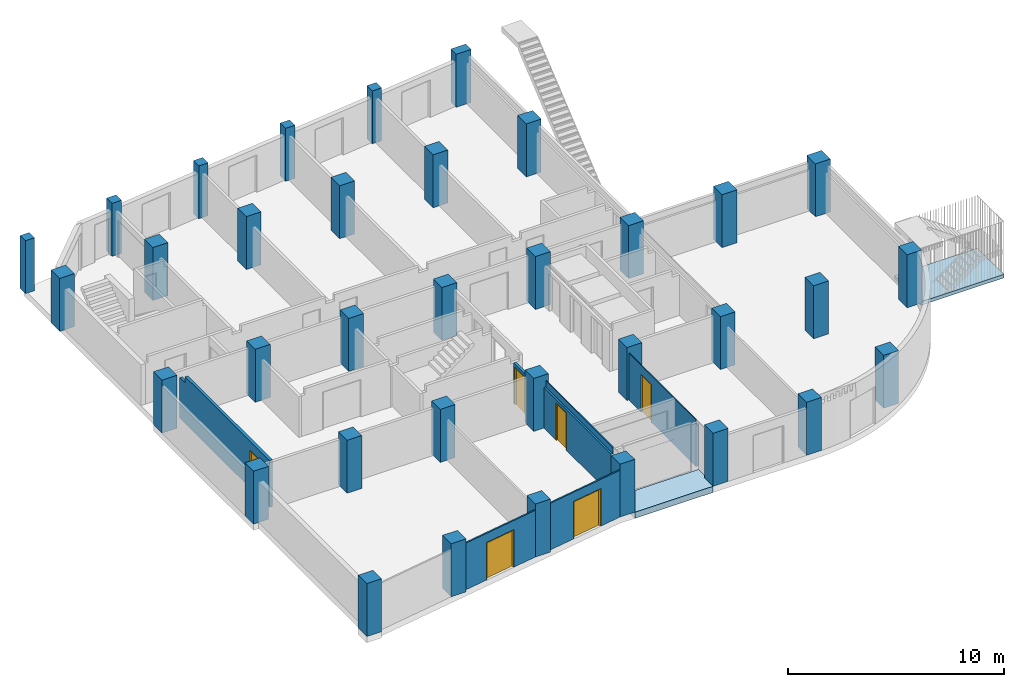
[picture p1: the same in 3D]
Properties of the parts of a building model (IFC2X3), part 7 of 10

# IfcOpeningElement (252)
Name | In | Depth (mm) | Height (mm) | Width (mm) | Area (m2) | Volume (m3)
6FLFSD2 | 6FL | 150 | 2130 | 1160 | 2.4708 | 0
スラブ開口 | 6FL
2 x 6FLSD7 | 6FL | 150 | 2130 | 960 | 2.0448 | 0
6FLSD8 | 6FL | 150 | 2130 | 960 | 2.0448 | 0
3 x 6FLSD9 | 6FL | 150 | 2130 | 960 | 2.0448 | 0
6FLSD0 | 6FL | 150 | 2130 | 960 | 2.0448 | 0
6FLSD1 | 6FL | 150 | 2130 | 960 | 2.0448 | 0
6FLFSD2 | 6FL | 250 | 2130 | 1160 | 2.4708 | 0
6FLSD4 | 6FL | 150 | 2130 | 2285 | 4.86705 | 0
2 x 6FLSD3 | 6FL | 150 | 2130 | 1560 | 3.3228 | 0
3 x 6FLSD5 | 6FL | 150 | 2130 | 1060 | 2.2578 | 0.02961
2 x 6FLSD3 | 6FL | 150 | 2130 | 760 | 1.6188 | 0
7FLSD3 | 7FL | 150 | 2130 | 960 | 2.0448 | 0
7FLSD4 | 7FL | 150 | 2130 | 960 | 2.0448 | 0
2 x 7FLSD5 | 7FL | 150 | 2130 | 960 | 2.0448 | 0
3 x 7FLSD6 | 7FL | 150 | 2130 | 960 | 2.0448 | 0
7FLFSD2 | 7FL | 150 | 2130 | 1160 | 2.4708 | 0
スラブ開口 | 7FL
2 x 7FLSD7 | 7FL | 150 | 2130 | 960 | 2.0448 | 0
7FLSD8 | 7FL | 150 | 2130 | 960 | 2.0448 | 0
3 x 7FLSD9 | 7FL | 150 | 2130 | 960 | 2.0448 | 0
7FLSD0 | 7FL | 150 | 2130 | 960 | 2.0448 | 0
7FLSD1 | 7FL | 150 | 2130 | 960 | 2.0448 | 0
7FLFSD2 | 7FL | 250 | 2130 | 1160 | 2.4708 | 0
7FLSD4 | 7FL | 150 | 2130 | 2285 | 4.86705 | 0
2 x 7FLSD3 | 7FL | 150 | 2130 | 1560 | 3.3228 | 0
3 x 7FLSD5 | 7FL | 150 | 2130 | 1060 | 2.2578 | 0.02961
2 x 7FLSD3 | 7FL | 150 | 2130 | 760 | 1.6188 | 0
8FLSD3 | 8FL | 150 | 2130 | 960 | 2.0448 | 0
8FLSD4 | 8FL | 150 | 2130 | 960 | 2.0448 | 0
2 x 8FLSD5 | 8FL | 150 | 2130 | 960 | 2.0448 | 0
3 x 8FLSD6 | 8FL | 150 | 2130 | 960 | 2.0448 | 0
8FLFSD2 | 8FL | 150 | 2130 | 1160 | 2.4708 | 0
スラブ開口 | 8FL
2 x 8FLSD7 | 8FL | 150 | 2130 | 960 | 2.0448 | 0
8FLSD8 | 8FL | 150 | 2130 | 960 | 2.0448 | 0
3 x 8FLSD9 | 8FL | 150 | 2130 | 960 | 2.0448 | 0
8FLSD0 | 8FL | 150 | 2130 | 960 | 2.0448 | 0
8FLSD1 | 8FL | 150 | 2130 | 960 | 2.0448 | 0
8FLFSD2 | 8FL | 250 | 2130 | 1160 | 2.4708 | 0
8FLSD4 | 8FL | 150 | 2130 | 2285 | 4.86705 | 0
2 x 8FLSD3 | 8FL | 150 | 2130 | 1560 | 3.3228 | 0
3 x 8FLSD5 | 8FL | 150 | 2130 | 1060 | 2.2578 | 0.02961
2 x 8FLSD3 | 8FL | 150 | 2130 | 760 | 1.6188 | 0
9FLSD3 | 9FL | 150 | 2130 | 960 | 2.0448 | 0
9FLSD4 | 9FL | 150 | 2130 | 960 | 2.0448 | 0
2 x 9FLSD5 | 9FL | 150 | 2130 | 960 | 2.0448 | 0
3 x 9FLSD6 | 9FL | 150 | 2130 | 960 | 2.0448 | 0
9FLFSD2 | 9FL | 150 | 2130 | 1160 | 2.4708 | 0
スラブ開口 | 9FL
2 x 9FLSD7 | 9FL | 150 | 2130 | 960 | 2.0448 | 0
9FLSD8 | 9FL | 150 | 2130 | 960 | 2.0448 | 0
3 x 9FLSD9 | 9FL | 150 | 2130 | 960 | 2.0448 | 0
9FLSD0 | 9FL | 150 | 2130 | 960 | 2.0448 | 0
9FLSD1 | 9FL | 150 | 2130 | 960 | 2.0448 | 0
9FLFSD2 | 9FL | 250 | 2130 | 1160 | 2.4708 | 0
9FLSD4 | 9FL | 150 | 2130 | 2285 | 4.86705 | 0
2 x 9FLSD3 | 9FL | 150 | 2130 | 1560 | 3.3228 | 0
3 x 9FLSD5 | 9FL | 150 | 2130 | 1060 | 2.2578 | 0.02961
2 x 9FLSD3 | 9FL | 150 | 2130 | 760 | 1.6188 | 0

# IfcSlab: コンクリート 200, S3
In: 1FL
Type - PredefinedType: FLOOR
Classification: スラブ (ARCHICAD 分類); Material: コンクリート
ArchiCADProperties - 要素ID: S3; ホットリンクおよび要素ID: S3; レイヤー: スラブ; ビルディングマテリアル/複合構造/断面形状/塗りつぶし: コンクリート; ビルディングマテリアル: コンクリート; ロック状態: no; ホームフロア名: 1FL; ホームフロア数: 1; 要素タイプ: スラブ; 構造タイプ: 基本; 親ID: S3; ビルディングマテリアル (全て): コンクリート; 材質 (全て): コンクリート - 04; 表面塗りつぶし: 25 %; 開口部の数: 0; リノベーションフィルタで表示: 全ての関連フィルタ; 構造機能: 非構造耐力要素; 位置: エクステリア; リノベーションステータス: 既存; 下面材質: コンクリート - 04; 辺材質: コンクリート - 04; 基準面の位置: 上端; 上面材質: コンクリート - 04; ARCHICAD 分類 - v 2.0: スラブ
仕上情報 - WEBサイト: www.graphisoft.co.jp
AC_Pset_RenovationAndPhasing - Renovation Status: Existing
Pset_SlabCommon - LoadBearing: no; IsExternal: yes
BaseQuantities - Width: 200 mm; Perimeter: 13807.3 mm; GrossArea: 10.9188 m2; NetArea: 10.9188 m2; GrossVolume: 2.18377 m3; NetVolume: 2.18377 m3
ArchiCADQuantities - 面積: 10.9188 m2; 高さ: 200 mm; 正味体積: 2.18377 m3; GLからの高度: 0 mm; 高度 1: 0 mm; 高度 2: 0 mm; 海抜までの高度: 0 mm; リンク/配置フロアまでの高度: 0 mm; 下部オフセット: 0 mm; 表面積: 10.9188 m2; 厚さ: 200 mm; 条件付き体積: 2.18377 m3; 総体積: 2.18377 m3; 平面図外周: 13807.3 mm; 平面図穴外周: 0 mm; 上端高度から第1基準レベル: 0 mm; 上端高度から配置フロア: 0 mm; 上端高度から基準レベル: 0 mm; 上端高度から海抜: 0 mm; 上端高度から第2基準レベル: 0 mm; 下端高度から第1基準レベル: -200 mm; 下端高度から配置フロア: -200 mm; 下端高度から基準レベル: -200 mm; 下端高度から海抜: -200 mm; 下端高度から第2基準レベル: -200 mm; 下部高度: -200 mm; 下部表面積: 10.9188 m2; 下部の条件付き表面積: 10.9188 m2; 上部の条件付き表面積: 10.9188 m2; 辺の表面積: 2.76147 m2; スラブ下部総表面積: 10.9188 m2; 穴を含むスラブ下部総表面積: 10.9188 m2; スラブ辺総表面積: 2.76147 m2; 穴を含むスラブ辺総表面積: 2.76147 m2; スラブ上部総表面積: 10.9188 m2; 穴を含むスラブ上部総表面積: 10.9188 m2; 穴表面積: 0 m2; 上部高度: 0 mm; 上部表面積: 10.9188 m2

# IfcSlab: コンクリート 350 (11)
Type - PredefinedType: FLOOR
Classification: スラブ (ARCHICAD 分類); Material: コンクリート
ArchiCADProperties - レイヤー: スラブ; ビルディングマテリアル/複合構造/断面形状/塗りつぶし: コンクリート; ビルディングマテリアル: コンクリート; 要素タイプ: スラブ; 構造タイプ: 基本; ビルディングマテリアル (全て): コンクリート; 材質 (全て): コンクリート - 04; 表面塗りつぶし: 25 %; リノベーションフィルタで表示: 全ての関連フィルタ; 構造機能: 非構造耐力要素; リノベーションステータス: 既存; 下面材質: コンクリート - 04; 辺材質: コンクリート - 04; 基準面の位置: 上端; 上面材質: コンクリート - 04; ARCHICAD 分類 - v 2.0: スラブ
仕上情報 - WEBサイト: www.graphisoft.co.jp
AC_Pset_RenovationAndPhasing - Renovation Status: Existing
Pset_SlabCommon - LoadBearing: no
BaseQuantities - Width: 350 mm
ArchiCADQuantities - 高さ: 350 mm; リンク/配置フロアまでの高度: 0 mm; 下部オフセット: 0 mm; 厚さ: 350 mm; 下端高度から配置フロア: -350 mm
Name | In | 要素ID = 親ID | ホットリンクおよび要素ID | ロック状態 | ホームフロア名 | ホームフロア数 | 開口部の数 | 位置 | IsExternal | Perimeter (mm) | GrossArea (m2) | NetArea (m2) = 下部表面積 (m2) = 下部の条件付き表面積 (m2) | GrossVolume (m3) | NetVolume (m3) = 正味体積 (m3) = 条件付き体積 (m3) | 面積 (m2) = 表面積 (m2) = 上部の条件付き表面積 (m2) = 上部表面積 (m2) | GLからの高度 (mm) = 高度 1 (mm) = 高度 2 (mm) = 海抜までの高度 (mm) = 上端高度から第1基準レベル (mm) = 上端高度から基準レベル (mm) = 上端高度から海抜 (mm) = 上端高度から第2基準レベル (mm) = 上部高度 (mm) | 総体積 (m3) | 平面図外周 (mm) | 平面図穴外周 (mm) | 上端高度から配置フロア (mm) | 下端高度から第1基準レベル (mm) = 下端高度から基準レベル (mm) = 下端高度から海抜 (mm) = 下端高度から第2基準レベル (mm) = 下部高度 (mm) | 辺の表面積 (m2) | スラブ下部総表面積 (m2) = スラブ上部総表面積 (m2) | 穴を含むスラブ下部総表面積 (m2) = 穴を含むスラブ上部総表面積 (m2) | スラブ辺総表面積 (m2) | 穴を含むスラブ辺総表面積 (m2) | 穴表面積 (m2) | ホットリンク マスタID
S2 | 1FL | S2 | S2 | no | 1FL | 1 | 1 | インテリア | no | 137079 | 954.041 | 954.041 | 333.914 | 333.914 | 954.041 | 0 | 338.263 | 137079 | 0 | 0 | -350 | 47.978 | 966.467 | 954.041 | 47.978 | 47.978 | 0 | ArchiCADProperties - 接続した開口のID: エレベーターシャフト
S3 | 1FL | S3 | S3 | no | 1FL | 1 | 0 | エクステリア | yes | 11850 | 6.55 | 6.55 | 2.2925 | 2.2925 | 6.55 | 0 | 2.2925 | 11850 | 0 | 0 | -350 | 4.1475 | 6.55 | 6.55 | 4.1475 | 4.1475 | 0
S2 | 2FL | S2 | S2 | no | 2FL | 2 | 1 | インテリア | no | 137079 | 785.326 | 751.007 | 274.797 | 262.786 | 750.758 | 3000 | 338.263 | 178441 | 41362.4 | 8.88178e-12 | 2650 | 38.0894 | 966.467 | 919.722 | 47.978 | 62.4548 | 34.319 | ArchiCADProperties - 接続した開口のID: エレベーターシャフト
S2 | 3FL | S2 | S2 | no | 3FL | 3 | 1 | インテリア | no | 131996 | 789.613 | 781.15 | 276.298 | 273.336 | 780.901 | 6000 | 334.721 | 144509 | 12512.4 | 8.88178e-12 | 5650 | 46.3233 | 956.345 | 935.456 | 46.1991 | 50.5784 | 8.4627 | ArchiCADProperties - 接続した開口のID: エレベーターシャフト
S2 | 3FL | S2 | S2 | no | 3FL | 3 | 0 | インテリア | no | 59039.8 | 80.1954 | 80.1954 | 28.0684 | 28.0684 | 80.1954 | 6000 | 34.0462 | 59039.8 | 0 | 0 | 5650 | 9.81843 | 97.2749 | 97.2749 | 20.6639 | 20.6639 | 0
4FLS2 | 4FL | S2 | 4FLS2 | yes | 4FL | 4 | 0 | インテリア | no | 131996 | 801.684 | 793.221 | 280.589 | 277.628 | 793.221 | 9000 | 334.721 | 144509 | 12512.4 | 0 | 8650 | 47.6997 | 956.345 | 947.882 | 46.1991 | 50.5784 | 8.4627 | 4FL
5FLS2 | 5FL | S2 | 5FLS2 | yes | 5FL | 5 | 0 | インテリア | no | 131996 | 801.684 | 793.221 | 280.589 | 277.628 | 793.221 | 12000 | 334.721 | 144509 | 12512.4 | 0 | 11650 | 47.6997 | 956.345 | 947.882 | 46.1991 | 50.5784 | 8.4627 | 5FL
6FLS2 | 6FL | S2 | 6FLS2 | yes | 6FL | 6 | 0 | インテリア | no | 131996 | 801.684 | 793.221 | 280.589 | 277.628 | 793.221 | 15000 | 334.721 | 144509 | 12512.4 | 0 | 14650 | 47.6997 | 956.345 | 947.882 | 46.1991 | 50.5784 | 8.4627 | 6FL
7FLS2 | 7FL | S2 | 7FLS2 | yes | 7FL | 7 | 0 | インテリア | no | 131996 | 801.684 | 793.221 | 280.589 | 277.628 | 793.221 | 18000 | 334.721 | 144509 | 12512.4 | 0 | 17650 | 47.6997 | 956.345 | 947.882 | 46.1991 | 50.5784 | 8.4627 | 7FL
8FLS2 | 8FL | S2 | 8FLS2 | yes | 8FL | 8 | 0 | インテリア | no | 131996 | 801.684 | 793.221 | 280.589 | 277.628 | 793.221 | 21000 | 334.721 | 144509 | 12512.4 | 0 | 20650 | 47.6997 | 956.345 | 947.882 | 46.1991 | 50.5784 | 8.4627 | 8FL
9FLS2 | 9FL | S2 | 9FLS2 | yes | 9FL | 9 | 0 | インテリア | no | 131996 | 801.684 | 793.221 | 280.589 | 277.628 | 793.221 | 24000 | 334.721 | 144509 | 12512.4 | 0 | 23650 | 47.6997 | 956.345 | 947.882 | 46.1991 | 50.5784 | 8.4627 | 9FL

# IfcSlab: コンクリート 450, S2
In: RFL
Type - PredefinedType: FLOOR
Classification: スラブ (ARCHICAD 分類); Material: コンクリート
ArchiCADProperties - 要素ID: S2; ホットリンクおよび要素ID: S2; レイヤー: スラブ; ビルディングマテリアル/複合構造/断面形状/塗りつぶし: コンクリート; ビルディングマテリアル: コンクリート; ロック状態: no; ホームフロア名: RFL; ホームフロア数: 10; 要素タイプ: スラブ; 構造タイプ: 基本; 親ID: S2; ビルディングマテリアル (全て): コンクリート; 材質 (全て): コンクリート - 04; 表面塗りつぶし: 25 %; 開口部の数: 0; リノベーションフィルタで表示: 全ての関連フィルタ; 構造機能: 非構造耐力要素; 位置: インテリア; リノベーションステータス: 既存; 下面材質: コンクリート - 04; 辺材質: コンクリート - 04; 基準面の位置: 上端; 上面材質: コンクリート - 04; ARCHICAD 分類 - v 2.0: スラブ
仕上情報 - WEBサイト: www.graphisoft.co.jp
AC_Pset_RenovationAndPhasing - Renovation Status: Existing
Pset_SlabCommon - LoadBearing: no; IsExternal: no
BaseQuantities - Width: 450 mm; Perimeter: 131996 mm; GrossArea: 801.255 m2; NetArea: 801.255 m2; GrossVolume: 376.074 m3; NetVolume: 376.074 m3
ArchiCADQuantities - 面積: 956.345 m2; 高さ: 450 mm; 正味体積: 376.074 m3; GLからの高度: 27100 mm; 高度 1: 27100 mm; 高度 2: 27100 mm; 海抜までの高度: 27100 mm; リンク/配置フロアまでの高度: 100 mm; 下部オフセット: 100 mm; 表面積: 956.345 m2; 厚さ: 450 mm; 条件付き体積: 376.074 m3; 総体積: 430.355 m3; 平面図外周: 131996 mm; 平面図穴外周: 0 mm; 上端高度から第1基準レベル: 27100 mm; 上端高度から配置フロア: 100 mm; 上端高度から基準レベル: 27100 mm; 上端高度から海抜: 27100 mm; 上端高度から第2基準レベル: 27100 mm; 下端高度から第1基準レベル: 26650 mm; 下端高度から配置フロア: -350 mm; 下端高度から基準レベル: 26650 mm; 下端高度から海抜: 26650 mm; 下端高度から第2基準レベル: 26650 mm; 下部高度: 26650 mm; 下部表面積: 801.255 m2; 下部の条件付き表面積: 801.255 m2; 上部の条件付き表面積: 956.345 m2; 辺の表面積: 57.5 m2; スラブ下部総表面積: 956.345 m2; 穴を含むスラブ下部総表面積: 956.345 m2; スラブ辺総表面積: 59.3988 m2; 穴を含むスラブ辺総表面積: 59.3988 m2; スラブ上部総表面積: 956.345 m2; 穴を含むスラブ上部総表面積: 956.345 m2; 穴表面積: 0 m2; 上部高度: 27100 mm; 上部表面積: 956.345 m2

# IfcStair (20)
Classification: 階段 (ARCHICAD 分類)
Pset_StairCommon - RequiredHeadroom: 2200 mm
ArchiCADProperties - レイヤー: 階段; 要素タイプ: 階段; リノベーションフィルタで表示: 全ての関連フィルタ; 構造機能: 非構造耐力要素; リノベーションステータス: 既存; デフォルトの蹴上傾斜角度: 90 deg; ARCHICAD 分類 - v 2.0: 階段
仕上情報 - WEBサイト: www.graphisoft.co.jp
AC_Pset_RenovationAndPhasing - Renovation Status: Existing
ArchiCADQuantities - デフォルトの踏面: 250 mm; 必要な天井高さ: 2200 mm; 最小踏面(規定): 150 mm; 最大蹴上高さ(規定): 230 mm
Name | In | Material | NumberOfRiser = 蹴上数(総数) | NumberOfTreads = 踏面数(総数) | RiserHeight (mm) = デフォルトの蹴上高さ (mm) | IsExternal | 要素ID = 親ID | ホットリンクおよび要素ID | ロック状態 | ホームフロア名 | ホームフロア数 | 絶対上部リンクフロア | 相対上部リンクフロア | 上部リンクフロア | ビルディングマテリアル (全て) | 材質 (全て) | 位置 | 階段の勾配 (deg) | Length (mm) = 移動線の長さ (mm) | Height (mm) = 高さ (mm) = 上端高度から配置フロア (mm) | GrossVolume (m3) = NetVolume (m3) = 正味体積 (m3) | 面積 (m2) | GLからの高度 (mm) = 高度 1 (mm) = 高度 2 (mm) = 海抜までの高度 (mm) | リンク/配置フロアまでの高度 (mm) = 下部オフセット (mm) | 上部オフセット (mm) | 上端高度から第1基準レベル (mm) = 上端高度から基準レベル (mm) = 上端高度から海抜 (mm) = 上端高度から第2基準レベル (mm) | 下端高度から第1基準レベル (mm) = 下端高度から基準レベル (mm) = 下端高度から海抜 (mm) = 下端高度から第2基準レベル (mm) | 下端高度から配置フロア (mm) | デフォルトの階段幅 (mm) | 階段 前面表面積 (m2) | フライト別の踏面数 | フライト別の蹴上数 | 関連ゾーン名 | 関連ゾーン番号 | ホットリンク マスタID
K2 | 1FL | コンクリート (3) | 16 | 16 | 187.5 | no | K2 | K2 | no | 1FL | 1 | 2FL | 配置フロア + 1 | 配置フロア + 1 (2FL) | コンクリート | コンクリート - 04 | インテリア | 36.8699 | 7350 | 3000 | 2.32519 | 9.515 | 8.88178e-12 | 8.88178e-12 | 8.88178e-12 | 3000 | 8.88178e-12 | 8.88178e-12 | 1400 | 4.76 | 8 | 8
K1 | 1FL | コンクリート (3) | 16 | 16 | 187.5 | no | K1 | K1 | no | 1FL | 1 | 2FL | 配置フロア + 1 | 配置フロア + 1 (2FL) | コンクリート | コンクリート - 04 | インテリア | 36.8699 | 6700 | 3000 | 2.08684 | 8.7002 | 8.88178e-12 | 8.88178e-12 | 8.88178e-12 | 3000 | 8.88178e-12 | 8.88178e-12 | 1150 | 3.91 | 8 | 8 | 階段室 | ＜ゾーン番号＞
K4 | 1FL | 金属-スチール (10), 成形セメント板 (16), モルタル (2) | 17 | 18 | 176.471 | yes | K4 | K4 | no | 1FL | 1 | 2FL | 配置フロア + 1 | 配置フロア + 1 (2FL) | モルタル; 成形セメント板; 金属-スチール | コンクリート - 03; 金属 - 亜鉛 | エクステリア | 35.2176 | 9300 | 3000 | 0.696831 | 9.765 | 0 | 0 | 0 | 3000 | -50 | -50 | 1050 | 3.17625 | 8 | 7 | 避難階段 | ＜ゾーン番号＞
K6 | 1FL | 金属-スチール (5), 成形セメント板 (28), モルタル | 29 | 29 | 206.897 | yes | K6 | K6 | no | 1FL | 1 | 3FL | 配置フロア + 2 | 配置フロア + 2 (3FL) | モルタル; 成形セメント板; 金属-スチール | コンクリート - 03; 金属 - 亜鉛 | エクステリア | 39.6107 | 8513.3 | 6000 | 0.732717 | 8.93897 | 0 | 0 | 0 | 6000 | -182.514 | -182.514 | 1050 | 6.3 | 28 | 28
K4 | 2FL | 金属-スチール (10), 成形セメント板 (16), モルタル (2) | 17 | 18 | 176.471 | yes | K4 | K4 | no | 2FL | 2 | 3FL | 配置フロア + 1 | 配置フロア + 1 (3FL) | モルタル; 成形セメント板; 金属-スチール | コンクリート - 03; 金属 - 亜鉛 | エクステリア | 35.2176 | 9300 | 3000 | 0.69855 | 9.765 | 3000 | 0 | 0 | 6000 | 2632.79 | -367.212 | 1050 | 3.17625 | 8 | 7 | 避難階段 | ＜ゾーン番号＞
K1 | 2FL | コンクリート (3) | 16 | 16 | 187.5 | no | K1 | K1 | no | 2FL | 2 | リンクなし | リンクなし | リンクなし | コンクリート | コンクリート - 04 | インテリア | 36.8699 | 6700 | 3000 | 2.08684 | 8.7002 | 3000 | 8.88178e-12 | 8.88178e-12 | 6000 | 3000 | 8.88178e-12 | 1150 | 3.91 | 8 | 8 | 階段室 | ＜ゾーン番号＞
K4 | 3FL | 金属-スチール (10), 成形セメント板 (16), モルタル (2) | 17 | 18 | 176.471 | yes | K4 | K4 | no | 3FL | 3 | リンクなし | リンクなし | リンクなし | モルタル; 成形セメント板; 金属-スチール | コンクリート - 03; 金属 - 亜鉛 | エクステリア | 35.2176 | 9300 | 3000 | 0.69855 | 9.765 | 6000 | 0 | 0 | 9000 | 5632.79 | -367.212 | 1050 | 3.17625 | 8 | 7 | 避難階段 | ＜ゾーン番号＞
K1 | 3FL | コンクリート (3) | 16 | 16 | 187.5 | no | K1 | K1 | no | 3FL | 3 | リンクなし | リンクなし | リンクなし | コンクリート | コンクリート - 04 | インテリア | 36.8699 | 6700 | 3000 | 2.08684 | 8.7002 | 6000 | 8.88178e-12 | 8.88178e-12 | 9000 | 6000 | 8.88178e-12 | 1150 | 3.91 | 8 | 8 | 階段室 | ＜ゾーン番号＞
4FLK4 | 4FL | 金属-スチール (10), 成形セメント板 (16), モルタル (2) | 17 | 18 | 176.471 | yes | K4 | 4FLK4 | yes | 4FL | 4 | リンクなし | リンクなし | リンクなし | モルタル; 成形セメント板; 金属-スチール | コンクリート - 03; 金属 - 亜鉛 | エクステリア | 35.2176 | 9300 | 3000 | 0.69855 | 9.765 | 9000 | 0 | 0 | 12000 | 8632.79 | -367.212 | 1050 | 3.17625 | 8 | 7 | 避難階段 | ＜ゾーン番号＞ | 4FL
4FLK1 | 4FL | コンクリート (3) | 16 | 16 | 187.5 | no | K1 | 4FLK1 | yes | 4FL | 4 | リンクなし | リンクなし | リンクなし | コンクリート | コンクリート - 04 | インテリア | 36.8699 | 6700 | 3000 | 2.08684 | 8.7002 | 9000 | 8.88178e-12 | 8.88178e-12 | 12000 | 9000 | 8.88178e-12 | 1150 | 3.91 | 8 | 8 | 階段室 | ＜ゾーン番号＞ | 4FL
5FLK4 | 5FL | 金属-スチール (10), 成形セメント板 (16), モルタル (2) | 17 | 18 | 176.471 | yes | K4 | 5FLK4 | yes | 5FL | 5 | リンクなし | リンクなし | リンクなし | モルタル; 成形セメント板; 金属-スチール | コンクリート - 03; 金属 - 亜鉛 | エクステリア | 35.2176 | 9300 | 3000 | 0.69855 | 9.765 | 12000 | 0 | 0 | 15000 | 11632.8 | -367.212 | 1050 | 3.17625 | 8 | 7 | 避難階段 | ＜ゾーン番号＞ | 5FL
5FLK1 | 5FL | コンクリート (3) | 16 | 16 | 187.5 | no | K1 | 5FLK1 | yes | 5FL | 5 | リンクなし | リンクなし | リンクなし | コンクリート | コンクリート - 04 | インテリア | 36.8699 | 6700 | 3000 | 2.08684 | 8.7002 | 12000 | 8.88178e-12 | 8.88178e-12 | 15000 | 12000 | 8.88178e-12 | 1150 | 3.91 | 8 | 8 | 階段室 | ＜ゾーン番号＞ | 5FL
6FLK4 | 6FL | 金属-スチール (10), 成形セメント板 (16), モルタル (2) | 17 | 18 | 176.471 | yes | K4 | 6FLK4 | yes | 6FL | 6 | リンクなし | リンクなし | リンクなし | モルタル; 成形セメント板; 金属-スチール | コンクリート - 03; 金属 - 亜鉛 | エクステリア | 35.2176 | 9300 | 3000 | 0.69855 | 9.765 | 15000 | 0 | 0 | 18000 | 14632.8 | -367.212 | 1050 | 3.17625 | 8 | 7 | 避難階段 | ＜ゾーン番号＞ | 6FL
6FLK1 | 6FL | コンクリート (3) | 16 | 16 | 187.5 | no | K1 | 6FLK1 | yes | 6FL | 6 | リンクなし | リンクなし | リンクなし | コンクリート | コンクリート - 04 | インテリア | 36.8699 | 6700 | 3000 | 2.08684 | 8.7002 | 15000 | 8.88178e-12 | 8.88178e-12 | 18000 | 15000 | 8.88178e-12 | 1150 | 3.91 | 8 | 8 | 階段室 | ＜ゾーン番号＞ | 6FL
7FLK4 | 7FL | 金属-スチール (10), 成形セメント板 (16), モルタル (2) | 17 | 18 | 176.471 | yes | K4 | 7FLK4 | yes | 7FL | 7 | リンクなし | リンクなし | リンクなし | モルタル; 成形セメント板; 金属-スチール | コンクリート - 03; 金属 - 亜鉛 | エクステリア | 35.2176 | 9300 | 3000 | 0.69855 | 9.765 | 18000 | 0 | 0 | 21000 | 17632.8 | -367.212 | 1050 | 3.17625 | 8 | 7 | 避難階段 | ＜ゾーン番号＞ | 7FL
7FLK1 | 7FL | コンクリート (3) | 16 | 16 | 187.5 | no | K1 | 7FLK1 | yes | 7FL | 7 | リンクなし | リンクなし | リンクなし | コンクリート | コンクリート - 04 | インテリア | 36.8699 | 6700 | 3000 | 2.08684 | 8.7002 | 18000 | 7.10543e-12 | 8.88178e-12 | 21000 | 18000 | 7.10543e-12 | 1150 | 3.91 | 8 | 8 | 階段室 | ＜ゾーン番号＞ | 7FL
8FLK4 | 8FL | 金属-スチール (10), 成形セメント板 (16), モルタル (2) | 17 | 18 | 176.471 | yes | K4 | 8FLK4 | yes | 8FL | 8 | リンクなし | リンクなし | リンクなし | モルタル; 成形セメント板; 金属-スチール | コンクリート - 03; 金属 - 亜鉛 | エクステリア | 35.2176 | 9300 | 3000 | 0.69855 | 9.765 | 21000 | 0 | 0 | 24000 | 20632.8 | -367.212 | 1050 | 3.17625 | 8 | 7 | 避難階段 | ＜ゾーン番号＞ | 8FL
8FLK1 | 8FL | コンクリート (3) | 16 | 16 | 187.5 | no | K1 | 8FLK1 | yes | 8FL | 8 | リンクなし | リンクなし | リンクなし | コンクリート | コンクリート - 04 | インテリア | 36.8699 | 6700 | 3000 | 2.08684 | 8.7002 | 21000 | 7.10543e-12 | 8.88178e-12 | 24000 | 21000 | 7.10543e-12 | 1150 | 3.91 | 8 | 8 | 階段室 | ＜ゾーン番号＞ | 8FL
9FLK4 | 9FL | 金属-スチール (10), 成形セメント板 (16), モルタル (2) | 17 | 18 | 176.471 | yes | K4 | 9FLK4 | yes | 9FL | 9 | リンクなし | リンクなし | リンクなし | モルタル; 成形セメント板; 金属-スチール | コンクリート - 03; 金属 - 亜鉛 | エクステリア | 35.2176 | 9300 | 3000 | 0.69855 | 9.765 | 24000 | 0 | 0 | 27000 | 23632.8 | -367.212 | 1050 | 3.17625 | 8 | 7 | 避難階段 | ＜ゾーン番号＞ | 9FL
9FLK1 | 9FL | コンクリート (3) | 16 | 16 | 187.5 | no | K1 | 9FLK1 | yes | 9FL | 9 | リンクなし | リンクなし | リンクなし | コンクリート | コンクリート - 04 | インテリア | 36.8699 | 6700 | 3000 | 2.08684 | 8.7002 | 24000 | 7.10543e-12 | 8.88178e-12 | 27000 | 24000 | 7.10543e-12 | 1150 | 3.91 | 8 | 8 | 階段室 | ＜ゾーン番号＞ | 9FL

# IfcTransportElement: エレベーター (3)
In: 1FL
Classification: 昇降機等 (ARCHICAD 分類)
ArchiCADProperties - 要素ID: O1; ホットリンクおよび要素ID: O1; レイヤー: オブジェクト; ライブラリ部品名: エレベーター; ビルディングマテリアル/複合構造/断面形状/塗りつぶし: 背景; 塗りつぶし種類: 背景; 関連ゾーン名: EVシャフト; 関連ゾーン番号: ＜ゾーン番号＞; ロック状態: no; ホームフロア名: 1FL; ホームフロア数: 1; 要素タイプ: オブジェクト; 親ID: O1; 材質 (全て): 金属 - ステンレス; 金属 - クロム 01; プラスチック - ラミネート; 金属 - 鉄; 金属 - 亜鉛; ペイント - カドミウムイエロー; リノベーションフィルタで表示: 全ての関連フィルタ; 構造機能: 非構造耐力要素; 位置: インテリア; リノベーションステータス: 既存; 回転角: 270 deg; 材質: 木材 - マツ 木目 縦; ARCHICAD 分類 - v 2.0: 昇降機等
AC_Pset_エレベーター - 2Dホットスポットを3Dで表示: no; 3D詳細レベル: 1; 形状: 1; セグメント数: 7; エレベータータイプ: 1; 第2開口の方向: 1; カウンターウェイト位置: 1; 配置フロア以上のフロア数: 0; 配置フロア以下のフロア数: 0; 分割レベルフロア: no; 配置フロア以上の分割レベル数: 0; 配置フロア以下の分割レベル数: 0; オーバーラン: yes; ピット: yes; エレベーターシャフトドアスタイル: 1; エレベーターカードアスタイル: 2; シャフト開口部の外側枠: yes; 編集するフロア (edited_story): 0. 1FL; 編集するフロア (edited_story_m): 0; 編集されたフロアのドア位置 (edited_story_door_pos): 前方; 編集されたフロアのドア位置 (edited_story_door_pos_m): 1; 操作パネル: yes; 操作パネル位置: 1; ドアパネル材質: 金属 - クロム 01; ドアガラス材質: ガラス - シンプル; 開口枠材質: 金属 - クロム 01; 操作パネル材質: 金属 - ステンレス; ボタン材質: 金属 - 鉄; エレベータボックス位置(フロア) (car_pos_story): 0. 1FL; エレベータボックス位置(フロア) (car_pos_story_m): 0; 展望用エレベータボックス材質: プラスチック - ラミネート; 内部エレベータボックス側面材質: プラスチック - ラミネート; エレベータボックス床材質: 金属 - 亜鉛; エレベータボックス天井材質: ペイント - カドミウムイエロー; エレベータボックス前面材質: ガラス - シンプル; エレベータボックス背面材質: プラスチック - ラミネート; 格子材質: 金属 - ステンレス; 3Dのシャフト内部輪郭: no; エレベータシャフトを表示: no; ビルディングマテリアル: レンガ-耐火; 材質上書き: no; 外部エレベータシャフト側面材質: ペイント - タイタニウムホワイト; 内部エレベータシャフト側面材質: ペイント - タイタニウムホワイト; エレベータシャフト辺材質: ペイント - タイタニウムホワイト; ドアシャフトパネル材質: 金属 - クロム 01; エレベータ壁を表示: no; 外部エレベータ壁側面材質: ペイント - タイタニウムホワイト; 内部エレベータ壁側面材質: ペイント - タイタニウムホワイト; エレベータ壁エッジ材質: ペイント - タイタニウムホワイト; 上部スラブ: yes; 外部最上部スラブ側面材質: ペイント - タイタニウムホワイト; 内部最上部スラブ側面材質: ペイント - タイタニウムホワイト; 上部スラブ辺材質: ペイント - タイタニウムホワイト; ピットスラブ: yes; 外部最下部スラブ側面材質: ペイント - タイタニウムホワイト; 内部最下部スラブ側面材質: ペイント - タイタニウムホワイト; ピットスラブエッジ材質: ペイント - タイタニウムホワイト; 3Dでの扉の開口率(%): 30; 影: yes; 解像度: 6; 3Dおよび断面/立面図のエレベータボックス: 1; 柱表示: yes; 2D詳細レベル: 1; ドア表示: 1; エレベーターとシャフト線種: 1; 機械を表示2D: yes; 機械線種: 1; シンボル線種1: 1; シンボル線種2: 1; シンボルドア芯線種: 1; エレベータボックス切断塗りつぶし種類: 背景; エレベータボックス投影塗りつぶし種類: 背景; 壁塗りつぶし種類: 背景; 切断塗りつぶしペン上書き: 0; 開口枠塗りつぶし種類: 背景; ギャップ塗りつぶし種類: 背景; エレベータボックスドア切断塗りつぶし種類: 背景; エレベータボックスドア投影塗りつぶし種類: 背景; エレベータボックスドア2D開口角度: 90 deg; エレベータボックスドア3D開口角度: 0 deg; 2Dシンボル表示のMVOを上書き (bOverrideCarMVO2D): no; 開口線線種 (lineOpTypeCar): 1; 開口線形状 (iSwingTypeCar): 1; 開口線形状 (iSlidingTypeCar): 1; ドア3D投影のMVOを上書き (bOverrideCarMVO3D): no; 開口線を表示 (bOpLineCar3D): yes; 開口側の線種 (iOpLineTypeCar3DIn): 1; 反対側の線種 (iOpLineTypeCar3DOut): 1; 開口線方向 (iOpLineStyleCar): 2; 開口線ペン2D/3D (peniOpLineCar): 3; シャフトドア切断塗りつぶし種類: 背景; シャフトドア2D開口角度: 90 deg; シャフトドア3D開口角度: 0 deg; 2Dシンボル表示のMVOを上書き (bOverrideShaftMVO2D): no; 開口線線種 (lineOpTypeShaft): 1; 開口線形状 (iSwingTypeShaft): 1; 開口線形状 (iSlidingTypeShaft): 1; ドア3D投影のMVOを上書き (bOverrideShaftMVO3D): no; 開口線を表示 (bOpLineShaft3D): yes; 開口側の線種 (iOpLineTypeShaft3DIn): 1; 反対側の線種 (iOpLineTypeShaft3DOut): 1; 開口線方向 (iOpLineStyleShaft): 2; 開口線ペン2D/3D (peniOpLineShaft): 3; 価格: 0; グループタイプ (FM_Type): エレベータ; グループタイプ (iFMType): 4; オブジェクト重量: 0; 重量単位: kg; 積載能力 (FM_LiftCapacity): 0; 積載能力 (FM_LiftCapacityNumber): 0; 定員人数: 0; 追記オブジェクト重量: 0
AC_Pset_RenovationAndPhasing - Renovation Status: Existing
ArchiCADQuantities - 面積: 4 m2; 高さ: 5600 mm; 正味体積: 1.41243 m3; 幅: 2000 mm; GLからの高度: 0 mm; 高度 1: 0 mm; 高度 2: 0 mm; 海抜までの高度: 0 mm; リンク/配置フロアまでの高度: 0 mm; 下部オフセット: 0 mm; 表面積: 43.6869 m2; 上端高度から第1基準レベル: 2450 mm; 上端高度から配置フロア: 2450 mm; 上端高度から基準レベル: 2450 mm; 上端高度から海抜: 2450 mm; 上端高度から第2基準レベル: 2450 mm; 下端高度から第1基準レベル: -50 mm; 下端高度から配置フロア: -50 mm; 下端高度から基準レベル: -50 mm; 下端高度から海抜: -50 mm; 下端高度から第2基準レベル: -50 mm; 長さ(A): 2000 mm
AC_Equantity_エレベーター - エレベーターシャフト幅: 2000 mm; エレベータシャフト奥行き: 2000 mm; 高さ: 5600 mm; 下部レベル: -1300 mm; 上部レベル: 4300 mm; カウンターウェイト幅: 900 mm; カウンターウェイト奥行: 150 mm; エレベータシャフト内部幅: 2000 mm; エレベータシャフト内部奥行き: 2000 mm; 構造フロアの最大高さ: 1800 mm; 通常フロアへの分割レベルフロア距離: 1550 mm; オーバーラン高さ: 1000 mm; ピット奥行き: 1000 mm; 開口幅: 730 mm; 開口高さ: 2100 mm; 中心からのドア軸: 0 mm; 中心からの第2ドア軸: 0 mm; エレベータボックスのオフセット: 0 mm; 編集されたフロアの高さ: 3000 mm; 編集されたフロアの高度: 0 mm; 内部幅: 2260 mm; 内部奥行き: 1740 mm; エレベータボックス内部幅: 1500 mm; エレベータボックス内部奥行き: 1500 mm; エレベータボックス高さ: 2400 mm; エレベータシャフト厚さ: 150 mm; エレベータ壁厚さ: 150 mm; 壁張り出し: 120 mm; 上部スラブ厚さ: 300 mm; ピットスラブ厚さ: 300 mm; エレベータボックスドア2D開口長さ: 100 mm; エレベータボックスドア3D開口長さ: 0 mm; シャフトドア2D開口長さ: 100 mm; シャフトドア3D開口長さ: 0 mm

# IfcWall: コンクリート 150 (271)
Classification: 壁 (ARCHICAD 分類); Material: コンクリート
ArchiCADProperties - レイヤー: 壁-躯体; ビルディングマテリアル/複合構造/断面形状/塗りつぶし: コンクリート; ビルディングマテリアル: コンクリート; 要素タイプ: 壁; 構造タイプ: 基本; ビルディングマテリアル (全て): コンクリート; 材質 (全て): コンクリート - 04; 傾斜角度: 90 deg; 開口部の数: 0; リノベーションフィルタで表示: 全ての関連フィルタ; 構造機能: 非構造耐力要素; リノベーションステータス: 既存; 壁形状: 直線; 図形作成法: 均一; 基準線位置: 中央; 辺材質: コンクリート - 04; 内面材質: コンクリート - 04; 外面材質: コンクリート - 04; 壁内側傾斜角度: 90 deg; 壁外側傾斜角度: 90 deg; ARCHICAD 分類 - v 2.0: 壁
仕上情報 - WEBサイト: www.graphisoft.co.jp
AC_Pset_RenovationAndPhasing - Renovation Status: Existing
Pset_WallCommon - LoadBearing: no
BaseQuantities - Width: 150 mm
ArchiCADQuantities - 高さ: 3000 mm; 幅: 150 mm; リンク/配置フロアまでの高度: 0 mm; 下部オフセット: 0 mm; 上部オフセット: 0 mm; 厚さ: 150 mm; 壁断熱材厚: 0 mm; 下端高度から配置フロア: 0 mm; 穴数(単純開口数): 0; 柱体積: 0 m3; 最大内面層の高さ: 0 mm; 最小内面層の高さ: 0 mm; 最大外面層の高さ: 0 mm; 最小外面層の高さ: 0 mm; 空気層厚さ: 0 mm; 内面壁層の厚さ: 0 mm; 外面壁層の厚さ: 0 mm; 壁終点厚さ: 150 mm; 壁内開口面積: 0 m2
Name | In | 要素ID = 親ID | ホットリンクおよび要素ID | 関連ゾーン名 | 関連ゾーン番号 | ロック状態 | ホームフロア名 | ホームフロア数 | 絶対上部リンクフロア | 相対上部リンクフロア | 上部リンクフロア | 位置 | IsExternal | Length (mm) = 壁平均長 (mm) = 壁中心長さ (mm) | Height (mm) = 上端高度から配置フロア (mm) = 壁最大高さ (mm) | GrossFootprintArea (m2) = NetFootprintArea (m2) = 面積 (m2) | GrossSideArea (m2) | NetSideArea (m2) | GrossVolume (m3) = 条件付き体積 (m3) | NetVolume (m3) = 正味体積 (m3) | GLからの高度 (mm) = 高度 1 (mm) = 高度 2 (mm) = 海抜までの高度 (mm) = 下端高度から第1基準レベル (mm) = 下端高度から基準レベル (mm) = 下端高度から海抜 (mm) = 下端高度から第2基準レベル (mm) | 表面積 (m2) = 外面正味表面積 (m2) | 3D長さ (mm) | 総体積 (m3) | 平面図外周 (mm) | 上端高度から第1基準レベル (mm) = 上端高度から基準レベル (mm) = 上端高度から海抜 (mm) = 上端高度から第2基準レベル (mm) | ドア数 | 窓数 | 柱数 | 壁最小高さ (mm) | ドア面積 (m2) | ドア総幅 (mm) | 窓面積 (m2) | 窓総幅 (mm) | 内面分析的開口面積 (m2) | 外面分析的開口面積 (m2) | 辺の正味表面積 (m2) | 内面正味表面積 (m2) | 開口部分解法体積 (m3) | 基準線長さ (mm) | 条件付き内面長さ (mm) | 条件付き内面表面積 (m2) | 条件付き外面長さ (mm) | 条件付き外面表面積 (m2) | 内面総壁表面積 (m2) | 外面総壁表面積 (m2) | 内面壁長さ (mm) | 外面壁長さ (mm) | ホットリンク マスタID
W6 | 1FL | W6 | W6 | 玄関ホール | ＜ゾーン番号＞ | no | 1FL | 1 | 2FL | 配置フロア + 1 | 配置フロア + 1 (2FL) | インテリア | no | 4400 | 2650 | 0.111 | 11.66 | 3.8642 | 1.749 | 0.57963 | 0 | 3.8642 | 4400 | 2.115 | 9100 | 2650 | 1 | 0 | 0 | 0 | 7.955 | 3600 | 0 | 0 | 7.7958 | 7.7958 | 0.111 | 3.8642 | 1.16937 | 4550 | 740 | 3.8642 | 740 | 3.8642 | 14.1 | 14.1 | 4400 | 4400
W9 | 1FL | W9 | W9 | 共用スペー | ＜ゾーン番号＞ | no | 1FL | 1 | 2FL | 配置フロア + 1 | 配置フロア + 1 (2FL) | インテリア | no | 4050 | 2300 | 0.52125 | 7.9925 | 7.9925 | 1.19887 | 1.19887 | 0 | 7.9925 | 3475 | 1.92375 | 8462.13 | 2300 | 0 | 0 | 1 | 0 | 0 | 0 | 0 | 0 | 0 | 0 | 0.52125 | 7.9925 | 0 | 4125 | 3975 | 7.9925 | 4125 | 7.9925 | 12.825 | 12.825 | 3975 | 4125
W6 | 1FL | W6 | W6 | 風除室 | ＜ゾーン番号＞ | no | 1FL | 1 | 2FL | 配置フロア + 1 | 配置フロア + 1 (2FL) | エクステリア | yes | 4550 | 2650 | 0.111 | 11.66 | 1.961 | 1.749 | 0.29415 | 0 | 1.961 | 740 | 2.115 | 9524.26 | 2650 | 1 | 0 | 0 | 0 | 10.175 | 3600 | 0 | 0 | 9.699 | 9.699 | 0.111 | 1.961 | 1.45485 | 4550 | 1040 | 1.961 | 740 | 1.961 | 14.1 | 14.1 | 4700 | 4400
W8 | 1FL | W8 | W8 | PS | ＜ゾーン番号＞ | no | 1FL | 1 | 2FL | 配置フロア + 1 | 配置フロア + 1 (2FL) | インテリア | no | 2675 | 2650 | 0.40125 | 6.94875 | 6.94875 | 1.04231 | 1.04231 | 0 | 6.94875 | 2675 | 1.33875 | 5650 | 2650 | 0 | 0 | 0 | 0 | 0 | 0 | 0 | 0 | 0 | 0 | 0.40125 | 6.94875 | 0 | 2825 | 2675 | 6.94875 | 2675 | 6.94875 | 8.925 | 8.925 | 2675 | 2675
W5 | 1FL | W5 | W5 | 店舗 | 103 | no | 1FL | 1 | 2FL | 配置フロア + 1 | 配置フロア + 1 (2FL) | インテリア | no | 5450 | 2650 | 0.63 | 11.13 | 11.13 | 1.6695 | 1.6695 | 0 | 11.13 | 4200 | 2.52 | 11324.3 | 2650 | 0 | 0 | 2 | 0 | 0 | 0 | 0 | 0 | 0 | 0 | 0.63 | 11.13 | -5.90841e-08 | 5450 | 5450 | 11.13 | 5450 | 11.13 | 16.8 | 16.8 | 5450 | 5450
W6 | 1FL | W6 | W6 | PS | ＜ゾーン番号＞ | no | 1FL | 1 | 2FL | 配置フロア + 1 | 配置フロア + 1 (2FL) | インテリア | no | 5275 | 2650 | 0.486 | 11.13 | 9.0852 | 1.6695 | 1.36278 | 0 | 9.0852 | 4200 | 2.43 | 10991.5 | 2650 | 1 | 0 | 2 | 0 | 2.22995 | 900 | 0 | 0 | 2.0448 | 2.0448 | 0.486 | 9.0852 | 0.30672 | 5275 | 4190 | 9.0852 | 4440 | 9.0852 | 16.2 | 16.2 | 5150 | 5400
W7 | 1FL | W7 | W7 | EVホール | ＜ゾーン番号＞ | no | 1FL | 1 | 2FL | 配置フロア + 1 | 配置フロア + 1 (2FL) | インテリア | no | 5000 | 2650 | 0.321 | 11.13 | 6.7422 | 1.6695 | 1.01133 | 0 | 6.7422 | 4200 | 2.25 | 10300 | 2650 | 1 | 0 | 2 | 0 | 4.61145 | 2000 | 0 | 0 | 4.3878 | 4.3878 | 0.321 | 6.7422 | 0.65817 | 5000 | 2940 | 6.7422 | 2940 | 6.7422 | 15 | 15 | 5000 | 5000
W8 | 1FL | W8 | W8 | 男性用トイレ | ＜ゾーン番号＞ | no | 1FL | 1 | 2FL | 配置フロア + 1 | 配置フロア + 1 (2FL) | インテリア | no | 5000 | 2650 | 0.63 | 11.13 | 11.13 | 1.6695 | 1.6695 | 0 | 11.13 | 4200 | 2.25 | 10300 | 2650 | 0 | 0 | 2 | 0 | 0 | 0 | 0 | 0 | 0 | 0 | 0.63 | 11.13 | 0 | 5000 | 5000 | 11.13 | 5000 | 11.13 | 15 | 15 | 5000 | 5000
W9 | 1FL | W9 | W9 | 管理室 | ＜ゾーン番号＞ | no | 1FL | 1 | 2FL | 配置フロア + 1 | 配置フロア + 1 (2FL) | インテリア | no | 5000 | 2650 | 0.63 | 11.13 | 11.13 | 1.6695 | 1.6695 | 0 | 11.13 | 4200 | 2.25 | 10300 | 2650 | 0 | 0 | 2 | 0 | 0 | 0 | 0 | 0 | 0 | 0 | 0.63 | 11.13 | 0 | 5000 | 5000 | 11.13 | 5000 | 11.13 | 15 | 15 | 5000 | 5000
W0 | 1FL | W0 | W0 | 共用スペー | ＜ゾーン番号＞ | no | 1FL | 1 | 2FL | 配置フロア + 1 | 配置フロア + 1 (2FL) | インテリア | no | 5275 | 2650 | 0.63 | 11.13 | 11.13 | 1.6695 | 1.6695 | 0 | 11.13 | 4200 | 2.43 | 10991.5 | 2650 | 0 | 0 | 2 | 0 | 0 | 0 | 0 | 0 | 0 | 0 | 0.63 | 11.13 | 0 | 5275 | 5150 | 11.13 | 5400 | 11.13 | 16.2 | 16.2 | 5150 | 5400
W1 | 1FL | W1 | W1 | 店舗 | 108 | no | 1FL | 1 | 2FL | 配置フロア + 1 | 配置フロア + 1 (2FL) | インテリア | no | 3771.01 | 2500 | 0.0580429 | 8.11738 | 2.02558 | 1.21761 | 0.303837 | 0 | 2.02558 | 3246.95 | 1.8103 | 7843.15 | 2500 | 1 | 0 | 2 | 0 | 6.235 | 2800 | 0 | 0 | 6.0918 | 6.0918 | 0.0580429 | 2.02558 | 0.91377 | 3896.95 | 920.223 | 2.02558 | 901.805 | 2.02558 | 12.0963 | 12.041 | 3780.22 | 3761.8
W2 | 1FL | W2 | W2 | 店舗 | 108 | no | 1FL | 1 | 2FL | 配置フロア + 1 | 配置フロア + 1 (2FL) | インテリア | no | 7325 | 2300 | 1.03875 | 15.9275 | 15.9275 | 2.38912 | 2.38912 | 0 | 15.9275 | 6925 | 3.36375 | 14950 | 2300 | 0 | 0 | 1 | 0 | 0 | 0 | 0 | 0 | 0 | 0 | 1.03875 | 15.9275 | 0 | 7400 | 7325 | 15.9275 | 7325 | 15.9275 | 22.425 | 22.425 | 7325 | 7325
W3 | 1FL | W3 | W3 | 店舗 | 107 | no | 1FL | 1 | 2FL | 配置フロア + 1 | 配置フロア + 1 (2FL) | インテリア | no | 7325 | 2300 | 1.03875 | 15.9275 | 15.9275 | 2.38912 | 2.38912 | 0 | 15.9275 | 6925 | 3.36375 | 14950 | 2300 | 0 | 0 | 1 | 0 | 0 | 0 | 0 | 0 | 0 | 0 | 1.03875 | 15.9275 | 0 | 7400 | 7325 | 15.9275 | 7325 | 15.9275 | 22.425 | 22.425 | 7325 | 7325
W4 | 1FL | W4 | W4 | 店舗 | 106 | no | 1FL | 1 | 2FL | 配置フロア + 1 | 配置フロア + 1 (2FL) | インテリア | no | 7325 | 2300 | 1.03875 | 15.9275 | 15.9275 | 2.38912 | 2.38912 | 0 | 15.9275 | 6925 | 3.36375 | 14950 | 2300 | 0 | 0 | 1 | 0 | 0 | 0 | 0 | 0 | 0 | 0 | 1.03875 | 15.9275 | 0 | 7400 | 7325 | 15.9275 | 7325 | 15.9275 | 22.425 | 22.425 | 7325 | 7325
W5 | 1FL | W5 | W5 | 店舗 | 106 | no | 1FL | 1 | 2FL | 配置フロア + 1 | 配置フロア + 1 (2FL) | インテリア | no | 4998.86 | 2500 | 0.67122 | 11.187 | 11.187 | 1.67805 | 1.67805 | 0 | 11.187 | 4474.8 | 2.36283 | 10298.8 | 2500 | 0 | 0 | 2 | 0 | 0 | 0 | 0 | 0 | 0 | 0 | 0.67122 | 11.187 | 0 | 5124.8 | 4989.65 | 11.187 | 5008.07 | 11.187 | 15.7246 | 15.7798 | 4989.65 | 5008.07
W6 | 1FL | W6 | W6 | 店舗 | 107 | no | 1FL | 1 | 2FL | 配置フロア + 1 | 配置フロア + 1 (2FL) | インテリア | no | 4384.94 | 2500 | 0.579131 | 9.65219 | 9.65219 | 1.44783 | 1.44783 | 0 | 9.65219 | 3860.88 | 2.08657 | 9071 | 2500 | 0 | 0 | 2 | 0 | 0 | 0 | 0 | 0 | 0 | 0 | 0.579131 | 9.65219 | -2.22045e-16 | 4510.88 | 4375.73 | 9.65219 | 4394.15 | 9.65219 | 13.8828 | 13.9381 | 4375.73 | 4394.15
W7 | 1FL | W7 | W7 | 店舗 | 105 | no | 1FL | 1 | 2FL | 配置フロア + 1 | 配置フロア + 1 (2FL) | インテリア | no | 5612.78 | 2500 | 0.763308 | 12.7218 | 12.7218 | 1.90827 | 1.90827 | 0 | 12.7218 | 5088.72 | 2.6391 | 11526.7 | 2500 | 0 | 0 | 2 | 0 | 0 | 0 | 0 | 0 | 0 | 0 | 0.763308 | 12.7218 | 0 | 5738.72 | 5621.99 | 12.7218 | 5603.57 | 12.7218 | 17.6216 | 17.5664 | 5621.99 | 5603.57
W8 | 1FL | W8 | W8 | 店舗 | 105 | no | 1FL | 1 | 2FL | 配置フロア + 1 | 配置フロア + 1 (2FL) | インテリア | no | 7325 | 2300 | 1.03875 | 15.9275 | 15.9275 | 2.38912 | 2.38912 | 0 | 15.9275 | 6925 | 3.36375 | 14950 | 2300 | 0 | 0 | 1 | 0 | 0 | 0 | 0 | 0 | 0 | 0 | 1.03875 | 15.9275 | 0 | 7400 | 7325 | 15.9275 | 7325 | 15.9275 | 22.425 | 22.425 | 7325 | 7325
W9 | 1FL | W9 | W9 | 廊下 | ＜ゾーン番号＞ | no | 1FL | 1 | 2FL | 配置フロア + 1 | 配置フロア + 1 (2FL) | インテリア | no | 25150 | 2650 | 2.98125 | 65.4325 | 53.5844 | 9.81488 | 8.16945 | 0 | 52.3863 | 25025 | 11.4863 | 50741.5 | 2650 | 5 | 0 | 0 | 0 | 11.4998 | 4700 | 0 | 0 | 10.65 | 13.0463 | 2.98125 | 54.7825 | 1.64542 | 25275 | 20275 | 54.7825 | 18900 | 52.3863 | 76.575 | 76.575 | 25275 | 25025
W4 | 1FL | W4 | W4 | 店舗 | 102 | no | 1FL | 1 | 2FL | 配置フロア + 1 | 配置フロア + 1 (2FL) | インテリア | no | 7125 | 2650 | 0.78975 | 15.4069 | 13.3621 | 2.25656 | 1.94984 | 0 | 12.2727 | 6225 | 3.27375 | 14674.3 | 2650 | 1 | 0 | 1 | 0 | 2.22995 | 900 | 0 | 0 | 2.0448 | 2.0448 | 0.78975 | 14.4514 | 0.30672 | 7125 | 6165 | 14.4514 | 6165 | 12.2727 | 21.825 | 21.825 | 7125 | 7125
W5 | 1FL | W5 | W5 | 店舗 | 103 | no | 1FL | 1 | 2FL | 配置フロア + 1 | 配置フロア + 1 (2FL) | インテリア | no | 7125 | 2650 | 0.78975 | 15.4069 | 13.3621 | 2.25656 | 1.94984 | 0 | 14.4514 | 6225 | 3.27375 | 14674.3 | 2650 | 1 | 0 | 1 | 0 | 2.22995 | 900 | 0 | 0 | 2.0448 | 2.0448 | 0.78975 | 12.2727 | 0.30672 | 7125 | 6165 | 12.2727 | 6165 | 14.4514 | 21.825 | 21.825 | 7125 | 7125
W4 | 1FL | W4 | W4 | 共用スペー | ＜ゾーン番号＞ | no | 1FL | 1 | 2FL | 配置フロア + 1 | 配置フロア + 1 (2FL) | インテリア | no | 1625 | 2300 | 0.09975 | 3.7375 | 1.6927 | 0.560625 | 0.253905 | 0 | 1.6927 | 1625 | 0.86625 | 3550 | 2300 | 1 | 0 | 1 | 0 | 2.22995 | 900 | 0 | 0 | 2.0448 | 2.0448 | 0.09975 | 1.6927 | 0.30672 | 1775 | 665 | 1.6927 | 665 | 1.6927 | 5.775 | 5.775 | 1625 | 1625
W5 | 1FL | W5 | W5 | PS | ＜ゾーン番号＞ | no | 1FL | 1 | 2FL | 配置フロア + 1 | 配置フロア + 1 (2FL) | インテリア | no | 8425 | 2650 | 1.011 | 19.0575 | 17.0127 | 2.79125 | 2.48453 | 0 | 18.3602 | 7700 | 3.8925 | 17212.1 | 2650 | 1 | 0 | 2 | 0 | 2.22995 | 900 | 0 | 0 | 2.0448 | 2.0448 | 1.011 | 15.6652 | 0.30672 | 8500 | 7390 | 15.6652 | 7540 | 18.3602 | 25.95 | 25.95 | 8350 | 8500
W6 | 1FL | W6 | W6 | DS | ＜ゾーン番号＞ | no | 1FL | 1 | 2FL | 配置フロア + 1 | 配置フロア + 1 (2FL) | インテリア | no | 6650 | 2300 | 0.43425 | 13.9725 | 7.1991 | 2.09587 | 1.07987 | 0 | 7.1991 | 6075 | 3.09375 | 13662.1 | 2300 | 3 | 0 | 1 | 0 | 8.9445 | 3000 | 0 | 0 | 6.7734 | 6.7734 | 0.43425 | 7.1991 | 1.01601 | 6725 | 3545 | 7.1991 | 3395 | 7.1991 | 20.625 | 20.625 | 6725 | 6575
W7 | 1FL | W7 | W7 | EVシャフト | ＜ゾーン番号＞ | no | 1FL | 1 | 2FL | 配置フロア + 1 | 配置フロア + 1 (2FL) | インテリア | no | 2250 | 2650 | 0.3375 | 5.95375 | 5.95375 | 0.893062 | 0.893062 | 0 | 5.95375 | 2250 | 1.08 | 4924.26 | 2650 | 0 | 0 | 0 | 0 | 0 | 0 | 0 | 0 | -2.45405e-08 | 0 | 0.3375 | 5.95375 | 2.47282e-09 | 2250 | 2100 | 5.95375 | 2400 | 5.95375 | 7.2 | 7.2 | 2100 | 2400
W8 | 1FL | W8 | W8 | PS | ＜ゾーン番号＞ | no | 1FL | 1 | 2FL | 配置フロア + 1 | 配置フロア + 1 (2FL) | インテリア | no | 6650 | 2650 | 0.98625 | 17.2488 | 17.2488 | 2.58731 | 2.58731 | 0 | 17.2488 | 6575 | 3.09375 | 13662.1 | 2650 | 0 | 0 | 0 | 0 | 0 | 0 | 0 | 0 | -3.55271e-15 | -3.55271e-15 | 0.98625 | 17.2488 | -4.44089e-16 | 6725 | 6575 | 17.2488 | 6725 | 17.2488 | 20.625 | 20.625 | 6575 | 6725
W0 | 1FL | W0 | W0 | 共用スペー | ＜ゾーン番号＞ | no | 1FL | 1 | 2FL | 配置フロア + 1 | 配置フロア + 1 (2FL) | インテリア | no | 5000 | 2650 | 0.4035 | 12.5 | 8.1122 | 1.875 | 1.21683 | 0 | 8.1122 | 4750 | 2.3175 | 10424.3 | 2650 | 1 | 0 | 0 | 0 | 4.61145 | 2000 | 0 | 0 | 4.3878 | 4.3878 | 0.4035 | 8.1122 | 0.65817 | 5000 | 2790 | 8.1122 | 3090 | 8.1122 | 15.45 | 15.45 | 4850 | 5150
W1 | 1FL | W1 | W1 | 管理室 | ＜ゾーン番号＞ | no | 1FL | 1 | 2FL | 配置フロア + 1 | 配置フロア + 1 (2FL) | インテリア | no | 4050 | 2300 | 0.49875 | 7.6475 | 7.6475 | 1.14712 | 1.14712 | 0 | 7.6475 | 3325 | 1.92375 | 8462.13 | 2300 | 0 | 0 | 1 | 0 | 0 | 0 | 0 | 0 | 0 | 0 | 0.49875 | 7.6475 | 0 | 4125 | 3975 | 7.6475 | 4125 | 7.6475 | 12.825 | 12.825 | 3975 | 4125
W2 | 1FL | W2 | W2 | 共用スペー | ＜ゾーン番号＞ | no | 1FL | 1 | 2FL | 配置フロア + 1 | 配置フロア + 1 (2FL) | インテリア | no | 2525 | 2300 | 0.39 | 5.98 | 5.98 | 0.897 | 0.897 | 0 | 5.98 | 2600 | 1.2825 | 5412.13 | 2300 | 0 | 0 | 0 | 0 | 0 | 0 | 0 | 0 | 0 | 0 | 0.39 | 5.98 | 0 | 2600 | 2450 | 5.98 | 2600 | 5.98 | 8.55 | 8.55 | 2450 | 2600 | 一般性能 - 耐火性能: 3時間耐火構造
W3 | 1FL | W3 | W3 | 共用スペー | ＜ゾーン番号＞ | no | 1FL | 1 | 2FL | 配置フロア + 1 | 配置フロア + 1 (2FL) | インテリア | no | 5325 | 2650 | 0.79875 | 13.875 | 13.875 | 2.08125 | 2.08125 | 0 | 13.875 | 5325 | 2.46375 | 11074.3 | 2650 | 0 | 0 | 0 | 0 | 0 | 0 | 0 | 0 | 0 | 0 | 0.79875 | 13.875 | 0 | 5325 | 5175 | 13.875 | 5475 | 13.875 | 16.425 | 16.425 | 5175 | 5475 | 一般性能 - 耐火性能: 3時間耐火構造
W4 | 1FL | W4 | W4 | 階段室 | ＜ゾーン番号＞ | no | 1FL | 1 | 2FL | 配置フロア + 1 | 配置フロア + 1 (2FL) | インテリア | no | 5250 | 2650 | 0.83625 | 14.45 | 14.45 | 2.1675 | 2.1675 | 0 | 14.45 | 5575 | 2.50875 | 10862.1 | 2650 | 0 | 0 | 0 | 0 | 0 | 0 | 0 | 0 | 0 | 0 | 1.18125 | 14.45 | 5.32907e-15 | 5325 | 5325 | 14.45 | 5175 | 14.45 | 16.725 | 16.725 | 5325 | 5175 | 一般性能 - 耐火性能: 3時間耐火構造
W5 | 1FL | W5 | W5 | 男性用トイレ | ＜ゾーン番号＞ | no | 1FL | 1 | 2FL | 配置フロア + 1 | 配置フロア + 1 (2FL) | インテリア | no | 5175 | 2650 | 0.77625 | 13.4775 | 13.4775 | 2.02162 | 2.02162 | 0 | 13.4775 | 5175 | 2.46375 | 10650 | 2650 | 0 | 0 | 0 | 0 | 0 | 0 | 0 | 0 | 0 | 0 | 0.77625 | 13.4775 | -4.44089e-16 | 5325 | 5175 | 13.4775 | 5175 | 13.4775 | 16.425 | 16.425 | 5175 | 5175
W9 | 1FL | W9 | W9 | DS | ＜ゾーン番号＞ | no | 1FL | 1 | 2FL | 配置フロア + 1 | 配置フロア + 1 (2FL) | インテリア | no | 1575 | 2650 | 0.2475 | 4.3725 | 4.3725 | 0.655875 | 0.655875 | 0 | 4.3725 | 1650 | 0.81 | 3512.13 | 2650 | 0 | 0 | 0 | 0 | 0 | 0 | 0 | 0 | 0 | 0 | 0.2475 | 4.3725 | 0 | 1650 | 1650 | 4.3725 | 1500 | 4.3725 | 5.4 | 5.4 | 1650 | 1500
W4 | 1FL | W4 | W4 | 階段室 | ＜ゾーン番号＞ | no | 1FL | 1 | 2FL | 配置フロア + 1 | 配置フロア + 1 (2FL) | インテリア | no | 2600 | 2650 | 0.10975 | 6.4925 | 2.5214 | 0.973875 | 0.417829 | 0 | 1.26175 | 2450 | 1.2375 | 5624.26 | 2650 | 1 | 0 | 0 | 0 | 2.87945 | 1200 | 0 | 0 | 2.71145 | 5.23075 | 0.10975 | 3.78105 | 0.556046 | 2600 | 1180 | 3.78105 | 300 | 1.26175 | 8.25 | 8.25 | 2450 | 2750 | 一般性能 - 耐火性能: 3時間耐火構造
W8 | 1FL | W8 | W8 | DS | ＜ゾーン番号＞ | no | 1FL | 1 | 2FL | 配置フロア + 1 | 配置フロア + 1 (2FL) | インテリア | no | 2100 | 2650 | 0.28875 | 5.10125 | 5.10125 | 0.765188 | 0.765188 | 0 | 5.10125 | 1925 | 1.08 | 4500 | 2650 | 0 | 0 | 1 | 0 | 0 | 0 | 0 | 0 | 0 | 0 | 0.28875 | 5.10125 | 0 | 2250 | 2100 | 5.10125 | 2100 | 5.10125 | 7.2 | 7.2 | 2100 | 2100
W5 | 1FL | W5 | W5 | 店舗 | 103 | no | 1FL | 1 | 2FL | 配置フロア + 1 | 配置フロア + 1 (2FL) | エクステリア | yes | 1400 | 2650 | 0.14625 | 2.41312 | 2.41312 | 0.353437 | 0.353437 | 0 | 2.58375 | 975 | 0.79875 | 3241.55 | 2650 | 0 | 0 | 1 | 0 | 0 | 0 | 0 | 0 | 0 | 0 | 0.50875 | 2.2425 | 0 | 1475 | 1275 | 2.2425 | 1525 | 2.58375 | 5.325 | 5.325 | 1275 | 1525
W4 | 1FL | W4 | W4 | 店舗 | 102 | no | 1FL | 1 | 2FL | 配置フロア + 1 | 配置フロア + 1 (2FL) | エクステリア | yes | 1294.11 | 2650 | 0.14625 | 2.41312 | 2.41312 | 0.353437 | 0.353437 | 0 | 2.2425 | 975 | 0.751875 | 3011.51 | 2650 | 0 | 0 | 1 | 0 | 0 | 0 | 0 | 0 | 0 | 0 | 0.50875 | 2.58375 | 0 | 1369.11 | 1408.33 | 2.58375 | 1179.88 | 2.2425 | 4.975 | 5.05 | 1408.33 | 1179.88
W0 | 1FL | W0 | W0 | 共用スペー | ＜ゾーン番号＞ | no | 1FL | 1 | 2FL | 配置フロア + 1 | 配置フロア + 1 (2FL) | インテリア | no | 8350 | 2650 | 1.1085 | 21.9525 | 19.9077 | 3.29288 | 2.98616 | 0 | 19.9077 | 8350 | 3.8925 | 17000 | 2650 | 1 | 0 | 0 | 0 | 2.22995 | 900 | 0 | 0 | 2.0448 | 2.0448 | 1.1085 | 19.9077 | 0.30672 | 8500 | 7390 | 19.9077 | 7390 | 19.9077 | 25.95 | 25.95 | 8350 | 8350
W8 | 1FL | W8 | W8 | 多目的トイレ | ＜ゾーン番号＞ | no | 1FL | 1 | 2FL | 配置フロア + 1 | 配置フロア + 1 (2FL) | インテリア | no | 2675 | 2650 | 0.20475 | 6.94875 | 3.27982 | 1.04231 | 0.623767 | 0 | 4.47795 | 2675 | 1.33875 | 5650 | 2650 | 1 | 0 | 0 | 0 | 2.58 | 1100 | 0 | 0 | 4.86705 | 2.4708 | 0.20475 | 2.0817 | 0.418545 | 2825 | 390 | 2.0817 | 1515 | 4.47795 | 8.925 | 8.925 | 2675 | 2675
W9 | 1FL | W9 | W9 | 収納 | ＜ゾーン番号＞ | no | 1FL | 1 | 2FL | 配置フロア + 1 | 配置フロア + 1 (2FL) | インテリア | no | 3567.48 | 2650 | 0.546371 | 9.65256 | 9.65256 | 1.44788 | 1.44788 | 0 | 9.65256 | 3642.48 | 1.70661 | 7497.08 | 2650 | 0 | 0 | 0 | 0 | 0 | 0 | 0 | 0 | 0 | 0 | 0.546371 | 9.65256 | 0 | 3642.48 | 3642.48 | 9.65256 | 3492.48 | 9.65256 | 11.3774 | 11.3774 | 3642.48 | 3492.48
W9 | 1FL | W9 | W9 | 収納 | ＜ゾーン番号＞ | no | 1FL | 1 | 2FL | 配置フロア + 1 | 配置フロア + 1 (2FL) | インテリア | no | 4800 | 2650 | 0.72 | 12.615 | 12.615 | 1.89225 | 1.89225 | 0 | 12.615 | 4800 | 2.34 | 9900 | 2650 | 0 | 0 | 0 | 0 | 0 | 0 | 0 | 0 | 0 | 0 | 0.72 | 12.615 | 0 | 5000 | 4800 | 12.615 | 4800 | 12.615 | 15.6 | 15.6 | 4800 | 4800
W4 | 1FL | W4 | W4 | 店舗 | 102 | no | 1FL | 1 | 2FL | 配置フロア + 1 | 配置フロア + 1 (2FL) | インテリア | no | 15500 | 2650 | 1.89 | 33.39 | 33.39 | 5.0085 | 5.0085 | 0 | 33.39 | 12600 | 7.065 | 31503.7 | 2650 | 0 | 0 | 4 | 0 | 0 | 0 | 0 | 0 | 0 | 0 | 1.89 | 33.39 | 0 | 15500 | 15450 | 33.39 | 15550 | 33.39 | 47.1 | 47.1 | 15450 | 15550
W0 | 1FL | W0 | W0 | DS | ＜ゾーン番号＞ | no | 1FL | 1 | 2FL | 配置フロア + 1 | 配置フロア + 1 (2FL) | インテリア | no | 2750 | 2650 | 0.40125 | 6.94875 | 6.94875 | 1.04231 | 1.04231 | 0 | 6.94875 | 2675 | 1.38375 | 5862.13 | 2650 | 0 | 0 | 0 | 0 | 0 | 0 | 0 | 0 | 0 | 0 | 0.40125 | 6.94875 | 0 | 2875 | 2825 | 6.94875 | 2675 | 6.94875 | 9.225 | 9.225 | 2825 | 2675
W9 | 1FL | W9 | W9 | 廊下 | ＜ゾーン番号＞ | no | 1FL | 1 | 2FL | 配置フロア + 1 | 配置フロア + 1 (2FL) | インテリア | no | 1625 | 2650 | 0.00974999 | 4.30625 | 0.98345 | 0.645937 | 0.147517 | 0 | 0.98345 | 1625 | 0.86625 | 3550 | 2650 | 1 | 0 | 0 | 0 | 3.44 | 1500 | 0 | 0 | 3.3228 | 3.3228 | 0.00974999 | 0.98345 | 0.49842 | 1775 | 65 | 0.98345 | 65 | 0.98345 | 5.775 | 5.775 | 1625 | 1625
W4 | 1FL | W4 | W4 | 男性用トイレ | ＜ゾーン番号＞ | no | 1FL | 1 | 2FL | 配置フロア + 1 | 配置フロア + 1 (2FL) | インテリア | no | 3975 | 2650 | 0.27075 | 8.81125 | 5.57365 | 1.32169 | 0.836048 | 0 | 5.57365 | 3325 | 1.96875 | 8250 | 2650 | 2 | 0 | 1 | 0 | 3.5939 | 1400 | 0 | 0 | 3.2376 | 3.2376 | 0.27075 | 5.57365 | 0.48564 | 4125 | 2455 | 8.81125 | 2455 | 8.81125 | 13.125 | 13.125 | 3975 | 3975
W9 | 1FL | W9 | W9 | 収納 | ＜ゾーン番号＞ | no | 1FL | 1 | 2FL | 配置フロア + 1 | 配置フロア + 1 (2FL) | インテリア | no | 1625 | 2650 | 0.0885 | 4.04625 | 2.00145 | 0.606938 | 0.300218 | 0 | 2.00145 | 1550 | 0.8325 | 3612.13 | 2650 | 1 | 0 | 0 | 0 | 2.22995 | 900 | 0 | 0 | 2.0448 | 2.0448 | 0.0885 | 2.00145 | 0.30672 | 1700 | 740 | 2.00145 | 590 | 2.00145 | 5.55 | 5.55 | 1700 | 1550
W4 | 2FL | W4 | W4 | EVホール | ＜ゾーン番号＞ | no | 2FL | 2 | 3FL | 配置フロア + 1 | 配置フロア + 1 (3FL) | インテリア | no | 7125 | 2650 | 0.96 | 15.84 | 15.84 | 2.32 | 2.32 | 3000 | 14.72 | 6400 | 3.24 | 14612.1 | 5650 | 0 | 0 | 1 | 0 | 0 | 0 | 0 | 0 | 0 | -7.10543e-15 | 1.3225 | 16.96 | 0 | 7125 | 7200 | 16.96 | 7050 | 14.72 | 21.6 | 21.6 | 7200 | 7050
W8 | 2FL | W8 | W8 | DS | ＜ゾーン番号＞ | no | 2FL | 2 | 3FL | 配置フロア + 1 | 配置フロア + 1 (3FL) | インテリア | no | 2100 | 2650 | 0.28875 | 5.10125 | 5.10125 | 0.765188 | 0.765188 | 3000 | 5.10125 | 1925 | 1.08 | 4500 | 5650 | 0 | 0 | 1 | 0 | 0 | 0 | 0 | 0 | 0 | 0 | 0.28875 | 5.10125 | 0 | 2250 | 2100 | 5.10125 | 2100 | 5.10125 | 7.2 | 7.2 | 2100 | 2100
W4 | 2FL | W4 | W4 | EVホール | ＜ゾーン番号＞ | no | 2FL | 2 | 3FL | 配置フロア + 1 | 配置フロア + 1 (3FL) | インテリア | no | 2600 | 2650 | 0.216 | 6.89 | 4.4192 | 1.0335 | 0.66288 | 3000 | 4.4192 | 2600 | 1.2375 | 5624.26 | 5650 | 1 | 0 | 0 | 0 | 2.66295 | 1100 | 0 | 0 | 2.4708 | 2.4708 | 0.216 | 4.4192 | 0.37062 | 2600 | 1290 | 4.4192 | 1590 | 4.4192 | 8.25 | 8.25 | 2450 | 2750 | 一般性能 - 耐火性能: 3時間耐火構造
W9 | 2FL | W9 | W9 | 廊下 | ＜ゾーン番号＞ | no | 2FL | 2 | 3FL | 配置フロア + 1 | 配置フロア + 1 (3FL) | インテリア | no | 20150 | 2650 | 2.43525 | 52.4725 | 44.2933 | 7.87088 | 6.644 | 3000 | 44.2933 | 20075 | 9.21375 | 40662.1 | 5650 | 4 | 0 | 0 | 0 | 8.9198 | 3600 | 0 | 0 | 8.1792 | 8.1792 | 2.43525 | 44.2933 | 1.22688 | 20275 | 16385 | 44.2933 | 16235 | 44.2933 | 61.425 | 61.425 | 20225 | 20075
W5 | 2FL | W5 | W5 | 店舗 | 206 | no | 2FL | 2 | 3FL | 配置フロア + 1 | 配置フロア + 1 (3FL) | エクステリア | yes | 1475 | 2650 | 0.12 | 1.98 | 1.98 | 0.29 | 0.29 | 3000 | 2.12 | 800 | 0.72 | 3391.55 | 5650 | 0 | 0 | 1 | 0 | 0 | 0 | 0 | 0 | 0 | 0 | 0.4825 | 1.84 | 0 | 1475 | 1350 | 1.84 | 1600 | 2.12 | 4.8 | 4.8 | 1350 | 1600
W4 | 2FL | W4 | W4 | 廊下 | ＜ゾーン番号＞ | no | 2FL | 2 | 3FL | 配置フロア + 1 | 配置フロア + 1 (3FL) | インテリア | no | 10275 | 2650 | 0.972 | 22.26 | 18.1704 | 3.339 | 2.72556 | 3000 | 18.1704 | 8400 | 4.71375 | 21053.7 | 5650 | 2 | 0 | 3 | 0 | 4.4599 | 1800 | 0 | 0 | 4.0896 | 4.0896 | 0.972 | 18.1704 | 0.61344 | 10275 | 8555 | 18.1704 | 8155 | 18.1704 | 31.425 | 31.425 | 10475 | 10075
W5 | 2FL | W5 | W5 | 男性用トイレ | ＜ゾーン番号＞ | no | 2FL | 2 | 3FL | 配置フロア + 1 | 配置フロア + 1 (3FL) | インテリア | no | 5175 | 2650 | 0.77625 | 13.4775 | 13.4775 | 2.02162 | 2.02162 | 3000 | 13.4775 | 5175 | 2.46375 | 10650 | 5650 | 0 | 0 | 0 | 0 | 0 | 0 | 0 | 0 | 0 | 0 | 0.77625 | 13.4775 | -4.44089e-16 | 5325 | 5175 | 13.4775 | 5175 | 13.4775 | 16.425 | 16.425 | 5175 | 5175
W9 | 2FL | W9 | W9 | ホール | ＜ゾーン番号＞ | no | 2FL | 2 | 3FL | 配置フロア + 1 | 配置フロア + 1 (3FL) | インテリア | no | 1550 | 2650 | 0.0135 | 4.04625 | 0.93645 | 0.606938 | 0.140467 | 3000 | 0.93645 | 1550 | 0.8325 | 3400 | 5650 | 1 | 0 | 0 | 0 | 3.31245 | 1400 | 0 | 0 | 3.1098 | 3.1098 | 0.0135 | 0.93645 | 0.46647 | 1700 | 90 | 0.93645 | 90 | 0.93645 | 5.55 | 5.55 | 1550 | 1550
W4 | 2FL | W4 | W4 | EVホール | ＜ゾーン番号＞ | no | 2FL | 2 | 3FL | 配置フロア + 1 | 配置フロア + 1 (3FL) | インテリア | no | 3975 | 2650 | 0.27075 | 8.81125 | 5.57365 | 1.32169 | 0.836048 | 3000 | 5.57365 | 3325 | 1.96875 | 8250 | 5650 | 2 | 0 | 1 | 0 | 3.5939 | 1400 | 0 | 0 | 3.2376 | 3.2376 | 0.27075 | 5.57365 | 0.48564 | 4125 | 2455 | 8.81125 | 2455 | 8.81125 | 13.125 | 13.125 | 3975 | 3975
W9 | 2FL | W9 | W9 | ホール | ＜ゾーン番号＞ | no | 2FL | 2 | 3FL | 配置フロア + 1 | 配置フロア + 1 (3FL) | インテリア | no | 1625 | 2650 | 0.21 | 3.71 | 3.71 | 0.5565 | 0.5565 | 3000 | 3.71 | 1400 | 0.8325 | 3797.54 | 5650 | 0 | 0 | 0 | 0 | 0 | 0 | 0 | 0 | 0 | 0 | 0.21 | 3.71 | 0 | 1625 | 1400 | 3.71 | 1850 | 3.71 | 5.55 | 5.55 | 1400 | 1850
W9 | 2FL | W9 | W9 | 機械室 | ＜ゾーン番号＞ | no | 2FL | 2 | 3FL | 配置フロア + 1 | 配置フロア + 1 (3FL) | インテリア | no | 3100 | 2650 | 0.465 | 8.17125 | 8.17125 | 1.22569 | 1.22569 | 3000 | 8.17125 | 3100 | 1.575 | 6500 | 5650 | 0 | 0 | 0 | 0 | 0 | 0 | 0 | 0 | 1.77636e-15 | 1.77636e-15 | 0.465 | 8.17125 | 2.22045e-16 | 3300 | 3100 | 8.17125 | 3100 | 8.17125 | 10.5 | 10.5 | 3100 | 3100
W1 | 2FL | W1 | W1 | 男性用トイレ | ＜ゾーン番号＞ | no | 2FL | 2 | 3FL | 配置フロア + 1 | 配置フロア + 1 (3FL) | インテリア | no | 4050 | 2300 | 0.51 | 7.82 | 7.82 | 1.173 | 1.173 | 3000 | 7.82 | 3400 | 1.89 | 8400 | 5300 | 0 | 0 | 1 | 0 | 0 | 0 | 0 | 0 | 0 | 0 | 0.855 | 7.82 | 0 | 4125 | 4050 | 7.82 | 4050 | 7.82 | 12.6 | 12.6 | 4050 | 4050
W2 | 2FL | W2 | W2 | 階段室 | ＜ゾーン番号＞ | no | 2FL | 2 | 3FL | 配置フロア + 1 | 配置フロア + 1 (3FL) | インテリア | no | 2600 | 2300 | 0.39 | 5.98 | 5.98 | 0.897 | 0.897 | 3000 | 5.98 | 2600 | 1.17 | 5500 | 5300 | 0 | 0 | 0 | 2300 | 0 | 0 | 0 | 0 | 0 | 0 | 1.08 | 5.98 | 0 | 2600 | 2600 | 5.98 | 2600 | 5.98 | 7.8 | 7.8 | 2600 | 2600 | 一般性能 - 耐火性能: 3時間耐火構造
W1 | 2FL | W1 | W1 | ホール | ＜ゾーン番号＞ | no | 2FL | 2 | 3FL | 配置フロア + 1 | 配置フロア + 1 (3FL) | インテリア | no | 2975 | 2300 | 0.41625 | 6.3825 | 6.3825 | 0.957375 | 0.957375 | 3000 | 6.3825 | 2775 | 1.485 | 6312.13 | 5300 | 0 | 0 | 1 | 0 | 0 | 0 | 0 | 0 | 0 | 0 | 0.41625 | 6.3825 | 0 | 3100 | 2900 | 6.3825 | 3050 | 6.3825 | 9.9 | 9.9 | 2900 | 3050
W8 | 2FL | W8 | W8 | 廊下 | ＜ゾーン番号＞ | no | 2FL | 2 | 3FL | 配置フロア + 1 | 配置フロア + 1 (3FL) | インテリア | no | 8425 | 2650 | 1.2525 | 21.9525 | 21.9525 | 3.29287 | 3.29287 | 3000 | 21.9525 | 8350 | 3.8925 | 17212.1 | 5650 | 0 | 0 | 0 | 0 | 0 | 0 | 0 | 0 | 3.55271e-15 | 3.55271e-15 | 1.2525 | 21.9525 | 4.44089e-16 | 8500 | 8350 | 21.9525 | 8500 | 21.9525 | 25.95 | 25.95 | 8350 | 8500
W7 | 2FL | W7 | W7 | EVホール | ＜ゾーン番号＞ | no | 2FL | 2 | 3FL | 配置フロア + 1 | 配置フロア + 1 (3FL) | インテリア | no | 2250 | 2650 | 0.36 | 6.29875 | 6.29875 | 0.944813 | 0.944812 | 3000 | 6.29875 | 2400 | 1.08 | 4924.26 | 5650 | 0 | 0 | 0 | 0 | 0 | 0 | 0 | 0 | 0 | 0 | 0.36 | 6.29875 | 1.0659e-09 | 2250 | 2100 | 6.29875 | 2400 | 6.29875 | 7.2 | 7.2 | 2100 | 2400
W5 | 2FL | W5 | W5 | EVホール | ＜ゾーン番号＞ | no | 2FL | 2 | 3FL | 配置フロア + 1 | 配置フロア + 1 (3FL) | インテリア | no | 6650 | 2650 | 0.88875 | 14.6644 | 14.6644 | 2.14781 | 2.14781 | 3000 | 15.7012 | 5925 | 3.09375 | 13662.1 | 5650 | 0 | 0 | 1 | 0 | 0 | 0 | 0 | 0 | 0 | 0 | 0.88875 | 13.6275 | 0 | 6725 | 6725 | 13.6275 | 6575 | 15.7012 | 20.625 | 20.625 | 6725 | 6575
W7 | 2FL | W7 | W7 | EVホール | ＜ゾーン番号＞ | no | 2FL | 2 | 3FL | 配置フロア + 1 | 配置フロア + 1 (3FL) | インテリア | no | 9925 | 2650 | 1.212 | 26.15 | 22.0604 | 3.9225 | 3.30906 | 3000 | 22.0604 | 10000 | 4.6125 | 20212.1 | 5650 | 2 | 0 | 0 | 0 | 4.4599 | 1800 | 0 | 0 | 4.0896 | 4.0896 | 1.212 | 22.0604 | 0.61344 | 10050 | 7930 | 22.0604 | 8080 | 22.0604 | 30.75 | 30.75 | 9850 | 10000
W5 | 2FL | W5 | W5 | EVホール | ＜ゾーン番号＞ | no | 2FL | 2 | 3FL | 配置フロア + 1 | 配置フロア + 1 (3FL) | インテリア | no | 7125 | 2650 | 0.96 | 15.84 | 15.84 | 2.32 | 2.32 | 3000 | 16.96 | 6400 | 3.24 | 14612.1 | 5650 | 0 | 0 | 1 | 0 | 0 | 0 | 0 | 0 | 0 | 0 | 1.3225 | 14.72 | 0 | 7125 | 7050 | 14.72 | 7200 | 16.96 | 21.6 | 21.6 | 7050 | 7200
W9 | 2FL | W9 | W9 | 機械室 | ＜ゾーン番号＞ | no | 2FL | 2 | 3FL | 配置フロア + 1 | 配置フロア + 1 (3FL) | インテリア | no | 7932.52 | 2650 | 0.982129 | 21.2199 | 18.1101 | 3.18299 | 2.71652 | 3000 | 18.1101 | 8007.52 | 3.67089 | 16227.2 | 5650 | 1 | 0 | 0 | 0 | 3.31245 | 1400 | 0 | 0 | 3.1098 | 3.1098 | 0.982129 | 18.1101 | 0.46647 | 8007.52 | 6397.52 | 18.1101 | 6547.52 | 18.1101 | 24.4726 | 24.4726 | 7857.52 | 8007.52
W3 | 2FL | W3 | W3 | 廊下 | ＜ゾーン番号＞ | no | 2FL | 2 | 3FL | 配置フロア + 1 | 配置フロア + 1 (3FL) | インテリア | no | 10075 | 2650 | 1.22325 | 26.3225 | 22.2329 | 3.94838 | 3.33494 | 3000 | 22.2329 | 10075 | 4.75875 | 20450 | 5650 | 2 | 0 | 0 | 0 | 4.4599 | 1800 | 0 | 0 | 4.0896 | 4.0896 | 1.22325 | 22.2329 | 0.61344 | 10275 | 8155 | 22.2329 | 8155 | 22.2329 | 31.725 | 31.725 | 10075 | 10075 | 一般性能 - 耐火性能: 3時間耐火構造
W4 | 2FL | W4 | W4 | 女性用トイレ | ＜ゾーン番号＞ | no | 2FL | 2 | 3FL | 配置フロア + 1 | 配置フロア + 1 (3FL) | インテリア | no | 5250 | 2650 | 0.79875 | 13.875 | 13.875 | 2.08125 | 2.08125 | 3000 | 13.875 | 5325 | 2.46375 | 10862.1 | 5650 | 0 | 0 | 0 | 0 | 0 | 0 | 0 | 0 | 0 | 0 | 0.79875 | 13.875 | 0 | 5325 | 5325 | 13.875 | 5175 | 13.875 | 16.425 | 16.425 | 5325 | 5175 | 一般性能 - 耐火性能: 3時間耐火構造
W8 | 2FL | W8 | W8 | PS | ＜ゾーン番号＞ | no | 2FL | 2 | 3FL | 配置フロア + 1 | 配置フロア + 1 (3FL) | インテリア | no | 2675 | 2650 | 0.40125 | 6.94875 | 6.94875 | 1.04231 | 1.04231 | 3000 | 6.94875 | 2675 | 1.33875 | 5650 | 5650 | 0 | 0 | 0 | 0 | 0 | 0 | 0 | 0 | 0 | 0 | 0.40125 | 6.94875 | 0 | 2825 | 2675 | 6.94875 | 2675 | 6.94875 | 8.925 | 8.925 | 2675 | 2675
W4 | 2FL | W4 | W4 | 店舗 | 203 | no | 2FL | 2 | 3FL | 配置フロア + 1 | 配置フロア + 1 (3FL) | エクステリア | yes | 1369.11 | 2650 | 0.12 | 1.98 | 1.98 | 0.29 | 0.29 | 3000 | 1.84 | 800 | 0.673125 | 3161.51 | 5650 | 0 | 0 | 1 | 0 | 0 | 0 | 0 | 0 | 0 | 0 | 0.4825 | 2.12 | 0 | 1369.11 | 1483.33 | 2.12 | 1254.88 | 1.84 | 4.45 | 4.525 | 1483.33 | 1254.88
W4 | 2FL | W4 | W4 | EVホール | ＜ゾーン番号＞ | no | 2FL | 2 | 3FL | 配置フロア + 1 | 配置フロア + 1 (3FL) | インテリア | no | 5150 | 2650 | 0.486 | 11.13 | 9.0852 | 1.6695 | 1.36278 | 3000 | 9.0852 | 4200 | 2.46375 | 10662.1 | 5650 | 1 | 0 | 2 | 0 | 2.22995 | 900 | 0 | 0 | 2.0448 | 2.0448 | 0.486 | 9.0852 | 0.30672 | 5225 | 4265 | 9.0852 | 4115 | 9.0852 | 16.425 | 16.425 | 5225 | 5075
W5 | 2FL | W5 | W5 | EVホール | ＜ゾーン番号＞ | no | 2FL | 2 | 3FL | 配置フロア + 1 | 配置フロア + 1 (3FL) | インテリア | no | 15375 | 2650 | 1.458 | 33.39 | 27.2556 | 5.0085 | 4.08834 | 3000 | 27.2556 | 12600 | 7.065 | 31112.1 | 5650 | 3 | 0 | 4 | 0 | 6.68985 | 2700 | 0 | 0 | 6.1344 | 6.1344 | 1.458 | 27.2556 | 0.92016 | 15500 | 12570 | 27.2556 | 12420 | 27.2556 | 47.1 | 47.1 | 15450 | 15300
W6 | 2FL | W6 | W6 | 廊下 | ＜ゾーン番号＞ | no | 2FL | 2 | 3FL | 配置フロア + 1 | 配置フロア + 1 (3FL) | インテリア | no | 5150 | 2650 | 0.6075 | 10.7325 | 10.7325 | 1.60987 | 1.60987 | 3000 | 10.7325 | 4050 | 2.43 | 10600 | 5650 | 0 | 0 | 2 | 0 | 0 | 0 | 0 | 0 | 0 | 0 | 0.6075 | 10.7325 | 0 | 5275 | 5150 | 10.7325 | 5150 | 10.7325 | 16.2 | 16.2 | 5150 | 5150
W8 | 2FL | W8 | W8 | 廊下 | ＜ゾーン番号＞ | no | 2FL | 2 | 3FL | 配置フロア + 1 | 配置フロア + 1 (3FL) | インテリア | no | 5000 | 2650 | 0.63 | 11.13 | 11.13 | 1.6695 | 1.6695 | 3000 | 11.13 | 4200 | 2.25 | 10300 | 5650 | 0 | 0 | 2 | 0 | 0 | 0 | 0 | 0 | 0 | 0 | 0.63 | 11.13 | 0 | 5000 | 5000 | 11.13 | 5000 | 11.13 | 15 | 15 | 5000 | 5000
W9 | 2FL | W9 | W9 | 廊下 | ＜ゾーン番号＞ | no | 2FL | 2 | 3FL | 配置フロア + 1 | 配置フロア + 1 (3FL) | インテリア | no | 5000 | 2650 | 0.63 | 11.13 | 11.13 | 1.6695 | 1.6695 | 3000 | 11.13 | 4200 | 2.25 | 10300 | 5650 | 0 | 0 | 2 | 0 | 0 | 0 | 0 | 0 | 0 | 0 | 0.63 | 11.13 | 0 | 5000 | 5000 | 11.13 | 5000 | 11.13 | 15 | 15 | 5000 | 5000
W0 | 2FL | W0 | W0 | 機械室 | ＜ゾーン番号＞ | no | 2FL | 2 | 3FL | 配置フロア + 1 | 配置フロア + 1 (3FL) | インテリア | no | 5275 | 2650 | 0.63 | 11.13 | 11.13 | 1.6695 | 1.6695 | 3000 | 11.13 | 4200 | 2.43 | 10991.5 | 5650 | 0 | 0 | 2 | 0 | 0 | 0 | 0 | 0 | 0 | 0 | 0.63 | 11.13 | 0 | 5275 | 5150 | 11.13 | 5400 | 11.13 | 16.2 | 16.2 | 5150 | 5400
W1 | 2FL | W1 | W1 | ホール | ＜ゾーン番号＞ | no | 2FL | 2 | 3FL | 配置フロア + 1 | 配置フロア + 1 (3FL) | インテリア | no | 3771.01 | 2500 | 0.487043 | 8.11738 | 8.11738 | 1.21761 | 1.21761 | 3000 | 8.11738 | 3246.95 | 1.8103 | 7843.15 | 5500 | 0 | 0 | 2 | 0 | 0 | 0 | 0 | 0 | 0 | 0 | 0.487043 | 8.11738 | 0 | 3896.95 | 3780.22 | 8.11738 | 3761.8 | 8.11738 | 12.0963 | 12.041 | 3780.22 | 3761.8
W2 | 2FL | W2 | W2 | ホール | ＜ゾーン番号＞ | no | 2FL | 2 | 3FL | 配置フロア + 1 | 配置フロア + 1 (3FL) | インテリア | no | 7400 | 2300 | 0.91725 | 16.2725 | 14.2277 | 2.44088 | 2.13415 | 3000 | 14.2277 | 7075 | 3.36375 | 15162.1 | 5300 | 1 | 0 | 1 | 0 | 2.22995 | 900 | 0 | 0 | 2.0448 | 2.0448 | 0.91725 | 14.2277 | 0.30672 | 7400 | 6365 | 14.2277 | 6515 | 14.2277 | 22.425 | 22.425 | 7325 | 7475
W6 | 2FL | W6 | W6 | EVホール | ＜ゾーン番号＞ | no | 2FL | 2 | 3FL | 配置フロア + 1 | 配置フロア + 1 (3FL) | インテリア | no | 6650 | 2300 | 0.41175 | 13.6275 | 6.8541 | 2.04413 | 1.02811 | 3000 | 6.8541 | 5925 | 3.09375 | 13662.1 | 5300 | 3 | 0 | 1 | 0 | 8.9445 | 3000 | 0 | 0 | 6.7734 | 6.7734 | 0.41175 | 6.8541 | 1.01601 | 6725 | 3545 | 6.8541 | 3395 | 6.8541 | 20.625 | 20.625 | 6725 | 6575
W7 | 2FL | W7 | W7 | 廊下 | ＜ゾーン番号＞ | no | 2FL | 2 | 3FL | 配置フロア + 1 | 配置フロア + 1 (3FL) | インテリア | no | 5000 | 2650 | 0.321 | 11.13 | 6.7422 | 1.6695 | 1.01133 | 3000 | 6.7422 | 4200 | 2.25 | 10300 | 5650 | 1 | 0 | 2 | 0 | 4.61145 | 2000 | 0 | 0 | 4.3878 | 4.3878 | 0.321 | 6.7422 | 0.65817 | 5000 | 2940 | 6.7422 | 2940 | 6.7422 | 15 | 15 | 5000 | 5000
W6 | 2FL | W6 | W6 | 吹き抜け | ＜ゾーン番号＞ | no | 2FL | 2 | 3FL | 配置フロア + 1 | 配置フロア + 1 (3FL) | エクステリア | yes | 4400 | 2650 | 0.66 | 11.66 | 2.804 | 1.749 | 0.4206 | 3000 | 2.804 | 4400 | 2.115 | 9100 | 5650 | 0 | 1 | 0 | 0 | 0 | 0 | 8.496 | 3540 | 8.856 | 8.856 | 0.66 | 2.804 | 1.3284 | 4550 | 4400 | 2.804 | 4400 | 2.804 | 14.1 | 14.1 | 4400 | 4400
W4 | 2FL | W4 | W4 | EVホール | ＜ゾーン番号＞ | no | 2FL | 2 | 3FL | 配置フロア + 1 | 配置フロア + 1 (3FL) | インテリア | no | 1775 | 2300 | 0.021 | 3.91 | 0.5872 | 0.5865 | 0.08808 | 3000 | 0.5872 | 1700 | 0.8325 | 3912.13 | 5300 | 1 | 0 | 1 | 0 | 3.52895 | 1500 | 0 | 0 | 3.3228 | 3.3228 | 0.366 | 0.5872 | 0.49842 | 1775 | 140 | 0.5872 | 290 | 0.5872 | 5.55 | 5.55 | 1700 | 1850
W1 | 2FL | W1 | W1 | ホール | ＜ゾーン番号＞ | no | 2FL | 2 | 3FL | 配置フロア + 1 | 配置フロア + 1 (3FL) | インテリア | no | 1300 | 2650 | 0.066 | 3.445 | 1.6132 | 0.51675 | 0.24198 | 3000 | 1.6132 | 1300 | 0.6525 | 3024.26 | 5650 | 1 | 0 | 0 | 0 | 2.01345 | 800 | 0 | 0 | 1.8318 | 1.8318 | 0.066 | 1.6132 | 0.27477 | 1300 | 440 | 3.445 | 440 | 3.445 | 4.35 | 4.35 | 1300 | 1300
W2 | 2FL | W2 | W2 | ホール | ＜ゾーン番号＞ | no | 2FL | 2 | 3FL | 配置フロア + 1 | 配置フロア + 1 (3FL) | インテリア | no | 1825 | 2650 | 0.1335 | 4.61875 | 2.78695 | 0.692813 | 0.418042 | 3000 | 2.78695 | 1750 | 0.9225 | 4012.13 | 5650 | 1 | 0 | 0 | 0 | 2.01345 | 800 | 0 | 0 | 1.8318 | 1.8318 | 0.1335 | 2.78695 | 0.27477 | 1900 | 1040 | 4.61875 | 890 | 4.61875 | 6.15 | 6.15 | 1900 | 1750
W3 | 2FL | W3 | W3 | 男性用トイレ | ＜ゾーン番号＞ | no | 2FL | 2 | 3FL | 配置フロア + 1 | 配置フロア + 1 (3FL) | インテリア | no | 1025 | 2650 | 0.165 | 2.915 | 2.915 | 0.43725 | 0.43725 | 3000 | 2.915 | 1100 | 0.5625 | 2412.13 | 5650 | 0 | 0 | 0 | 0 | 0 | 0 | 0 | 0 | 0 | 0 | 0.165 | 2.915 | 0 | 1100 | 950 | 2.915 | 1100 | 2.915 | 3.75 | 3.75 | 950 | 1100
W4 | 2FL | W4 | W4 | 男性用トイレ | ＜ゾーン番号＞ | no | 2FL | 2 | 3FL | 配置フロア + 1 | 配置フロア + 1 (3FL) | インテリア | no | 1100 | 2650 | 0.165 | 2.915 | 2.915 | 0.43725 | 0.43725 | 3000 | 2.915 | 1100 | 0.5625 | 2624.26 | 5650 | 0 | 0 | 0 | 0 | 0 | 0 | 0 | 0 | 0 | 0 | 0.165 | 2.915 | 0 | 1100 | 1100 | 2.915 | 1100 | 2.915 | 3.75 | 3.75 | 1100 | 1100
W5 | 2FL | W5 | W5 | 男性用トイレ | ＜ゾーン番号＞ | no | 2FL | 2 | 3FL | 配置フロア + 1 | 配置フロア + 1 (3FL) | インテリア | no | 889.052 | 2650 | 0.122108 | 2.1459 | 2.1459 | 0.321886 | 0.321886 | 3000 | 2.17031 | 823.261 | 0.547168 | 2141.36 | 5650 | 0 | 0 | 0 | 0 | 0 | 0 | 0 | 0 | 0 | 0 | 0.122108 | 2.1215 | 0 | 1014.99 | 954.844 | 2.1215 | 823.261 | 2.17031 | 3.62016 | 3.67542 | 954.844 | 823.261
W8 | 2FL | W8 | W8 | EVホール | ＜ゾーン番号＞ | no | 2FL | 2 | 3FL | 配置フロア + 1 | 配置フロア + 1 (3FL) | インテリア | no | 2675 | 2650 | 0.20475 | 6.94875 | 3.27982 | 1.04231 | 0.623767 | 3000 | 4.47795 | 2675 | 1.33875 | 5650 | 5650 | 1 | 0 | 0 | 0 | 2.58 | 1100 | 0 | 0 | 4.86705 | 2.4708 | 0.20475 | 2.0817 | 0.418545 | 2825 | 390 | 2.0817 | 1515 | 4.47795 | 8.925 | 8.925 | 2675 | 2675
W3 | 2FL | W3 | W3 | EVホール | ＜ゾーン番号＞ | no | 2FL | 2 | 3FL | 配置フロア + 1 | 配置フロア + 1 (3FL) | インテリア | no | 5250 | 2650 | 0.77625 | 13.4775 | 13.4775 | 2.02162 | 2.02162 | 3000 | 13.4775 | 5175 | 2.46375 | 10862.1 | 5650 | 0 | 0 | 0 | 0 | 0 | 0 | 0 | 0 | 0 | 0 | 0.77625 | 13.4775 | 1.77636e-15 | 5325 | 5175 | 13.4775 | 5325 | 13.4775 | 16.425 | 16.425 | 5175 | 5325 | 一般性能 - 耐火性能: 3時間耐火構造
W3 | 3FL | W3 | W3 | EVホール | ＜ゾーン番号＞ | no | 3FL | 3 | 4FL | 配置フロア + 1 | 配置フロア + 1 (4FL) | インテリア | no | 5250 | 2650 | 0.77625 | 13.4775 | 13.4775 | 2.02162 | 2.02162 | 6000 | 13.4775 | 5175 | 2.50875 | 10862.1 | 8650 | 0 | 0 | 0 | 0 | 0 | 0 | 0 | 0 | 0 | 0 | 0.77625 | 13.4775 | 8.88178e-16 | 5325 | 5175 | 13.4775 | 5325 | 13.4775 | 16.725 | 16.725 | 5175 | 5325 | 一般性能 - 耐火性能: 3時間耐火構造
W9 | 3FL | W9 | W9 | EVホール | ＜ゾーン番号＞ | no | 3FL | 3 | 4FL | 配置フロア + 1 | 配置フロア + 1 (4FL) | インテリア | no | 1700 | 2300 | 0.00974999 | 3.7375 | 0.4147 | 0.560625 | 0.062205 | 6000 | 0.4147 | 1625 | 0.86625 | 3762.13 | 8300 | 1 | 0 | 1 | 0 | 3.52895 | 1500 | 0 | 0 | 3.3228 | 3.3228 | 0.00974999 | 0.4147 | 0.49842 | 1775 | 65 | 0.4147 | 215 | 0.4147 | 5.775 | 5.775 | 1625 | 1775
W8 | 3FL | W8 | W8 | DS | ＜ゾーン番号＞ | no | 3FL | 3 | 4FL | 配置フロア + 1 | 配置フロア + 1 (4FL) | インテリア | no | 2100 | 2650 | 0.28875 | 5.10125 | 5.10125 | 0.765188 | 0.765188 | 6000 | 5.10125 | 1925 | 1.08 | 4500 | 8650 | 0 | 0 | 1 | 0 | 0 | 0 | 0 | 0 | 0 | 0 | 0.28875 | 5.10125 | 0 | 2250 | 2100 | 5.10125 | 2100 | 5.10125 | 7.2 | 7.2 | 2100 | 2100
W4 | 3FL | W4 | W4 | EVホール | ＜ゾーン番号＞ | no | 3FL | 3 | 4FL | 配置フロア + 1 | 配置フロア + 1 (4FL) | インテリア | no | 2600 | 2650 | 0.216 | 6.89 | 4.4192 | 1.0335 | 0.66288 | 6000 | 4.4192 | 2600 | 1.2375 | 5624.26 | 8650 | 1 | 0 | 0 | 0 | 2.66295 | 1100 | 0 | 0 | 2.4708 | 2.4708 | 0.216 | 4.4192 | 0.37062 | 2600 | 1290 | 4.4192 | 1590 | 4.4192 | 8.25 | 8.25 | 2450 | 2750 | 一般性能 - 耐火性能: 3時間耐火構造
W5 | 3FL | W5 | W5 | 男性用トイレ | ＜ゾーン番号＞ | no | 3FL | 3 | 4FL | 配置フロア + 1 | 配置フロア + 1 (4FL) | インテリア | no | 5175 | 2650 | 0.77625 | 13.4775 | 13.4775 | 2.02162 | 2.02162 | 6000 | 13.4775 | 5175 | 2.46375 | 10650 | 8650 | 0 | 0 | 0 | 0 | 0 | 0 | 0 | 0 | 0 | 0 | 0.77625 | 13.4775 | -4.44089e-16 | 5325 | 5175 | 13.4775 | 5175 | 13.4775 | 16.425 | 16.425 | 5175 | 5175
W4 | 3FL | W4 | W4 | 事務室 | 303 | no | 3FL | 3 | 4FL | 配置フロア + 1 | 配置フロア + 1 (4FL) | インテリア | no | 5000 | 2650 | 0.486 | 11.13 | 9.0852 | 1.6695 | 1.36278 | 6000 | 9.0852 | 4200 | 2.25 | 10300 | 8650 | 1 | 0 | 2 | 0 | 2.22995 | 900 | 0 | 0 | 2.0448 | 2.0448 | 0.486 | 9.0852 | 0.30672 | 5000 | 4040 | 9.0852 | 4040 | 9.0852 | 15 | 15 | 5000 | 5000
W1 | 3FL | W1 | W1 | 事務室 | 310 | no | 3FL | 3 | 4FL | 配置フロア + 1 | 配置フロア + 1 (4FL) | インテリア | no | 4050 | 2300 | 0.51 | 7.82 | 7.82 | 1.173 | 1.173 | 6000 | 7.82 | 3400 | 1.89 | 8400 | 8300 | 0 | 0 | 1 | 0 | 0 | 0 | 0 | 0 | 0 | 0 | 0.855 | 7.82 | 0 | 4125 | 4050 | 7.82 | 4050 | 7.82 | 12.6 | 12.6 | 4050 | 4050
W2 | 3FL | W2 | W2 | 事務室 | 310 | no | 3FL | 3 | 4FL | 配置フロア + 1 | 配置フロア + 1 (4FL) | インテリア | no | 2600 | 2300 | 0.36375 | 5.5775 | 5.5775 | 0.836625 | 0.836625 | 6000 | 5.5775 | 2425 | 1.20375 | 5562.13 | 8300 | 0 | 0 | 0 | 0 | 0 | 0 | 0 | 0 | 0 | 0 | 0.70875 | 5.5775 | 0 | 2600 | 2675 | 5.5775 | 2525 | 5.5775 | 8.025 | 8.025 | 2675 | 2525 | 一般性能 - 耐火性能: 3時間耐火構造
W8 | 3FL | W8 | W8 | DS | ＜ゾーン番号＞ | no | 3FL | 3 | 4FL | 配置フロア + 1 | 配置フロア + 1 (4FL) | インテリア | no | 8425 | 2650 | 1.2525 | 21.9525 | 21.9525 | 3.29287 | 3.29287 | 6000 | 21.9525 | 8350 | 3.8925 | 17212.1 | 8650 | 0 | 0 | 0 | 0 | 0 | 0 | 0 | 0 | 3.55271e-15 | 3.55271e-15 | 1.2525 | 21.9525 | 4.44089e-16 | 8500 | 8350 | 21.9525 | 8500 | 21.9525 | 25.95 | 25.95 | 8350 | 8500
W7 | 3FL | W7 | W7 | EVシャフト | ＜ゾーン番号＞ | no | 3FL | 3 | 4FL | 配置フロア + 1 | 配置フロア + 1 (4FL) | インテリア | no | 2250 | 2650 | 0.36 | 6.29875 | 6.29875 | 0.944813 | 0.944813 | 6000 | 6.29875 | 2400 | 1.08 | 4924.26 | 8650 | 0 | 0 | 0 | 0 | 0 | 0 | 0 | 0 | 0 | 0 | 0.36 | 6.29875 | 0 | 2250 | 2100 | 6.29875 | 2400 | 6.29875 | 7.2 | 7.2 | 2100 | 2400
W5 | 3FL | W5 | W5 | 事務室 | 309 | no | 3FL | 3 | 4FL | 配置フロア + 1 | 配置フロア + 1 (4FL) | インテリア | no | 6650 | 2650 | 0.88875 | 14.6644 | 14.6644 | 2.14781 | 2.14781 | 6000 | 15.7012 | 5925 | 3.09375 | 13662.1 | 8650 | 0 | 0 | 1 | 0 | 0 | 0 | 0 | 0 | 0 | 0 | 0.88875 | 13.6275 | 0 | 6725 | 6725 | 13.6275 | 6575 | 15.7012 | 20.625 | 20.625 | 6725 | 6575
W7 | 3FL | W7 | W7 | 事務室 | 308 | no | 3FL | 3 | 4FL | 配置フロア + 1 | 配置フロア + 1 (4FL) | インテリア | no | 9925 | 2650 | 1.212 | 26.15 | 22.0604 | 3.9225 | 3.30906 | 6000 | 22.0604 | 10000 | 4.6125 | 20212.1 | 8650 | 2 | 0 | 0 | 0 | 4.4599 | 1800 | 0 | 0 | 4.0896 | 4.0896 | 1.212 | 22.0604 | 0.61344 | 10050 | 7930 | 22.0604 | 8080 | 22.0604 | 30.75 | 30.75 | 9850 | 10000
W3 | 3FL | W3 | W3 | 事務室 | 310 | no | 3FL | 3 | 4FL | 配置フロア + 1 | 配置フロア + 1 (4FL) | インテリア | no | 10150 | 2650 | 1.22325 | 26.3225 | 22.2329 | 3.94838 | 3.33494 | 6000 | 22.2329 | 10075 | 4.71375 | 20662.1 | 8650 | 2 | 0 | 0 | 0 | 4.4599 | 1800 | 0 | 0 | 4.0896 | 4.0896 | 1.22325 | 22.2329 | 0.61344 | 10275 | 8155 | 22.2329 | 8305 | 22.2329 | 31.425 | 31.425 | 10075 | 10225
W4 | 3FL | W4 | W4 | 女性用トイレ | ＜ゾーン番号＞ | no | 3FL | 3 | 4FL | 配置フロア + 1 | 配置フロア + 1 (4FL) | インテリア | no | 5250 | 2650 | 0.79875 | 13.875 | 13.875 | 2.08125 | 2.08125 | 6000 | 13.875 | 5325 | 2.46375 | 10862.1 | 8650 | 0 | 0 | 0 | 0 | 0 | 0 | 0 | 0 | 0 | 0 | 0.79875 | 13.875 | 0 | 5325 | 5325 | 13.875 | 5175 | 13.875 | 16.425 | 16.425 | 5325 | 5175 | 一般性能 - 耐火性能: 3時間耐火構造
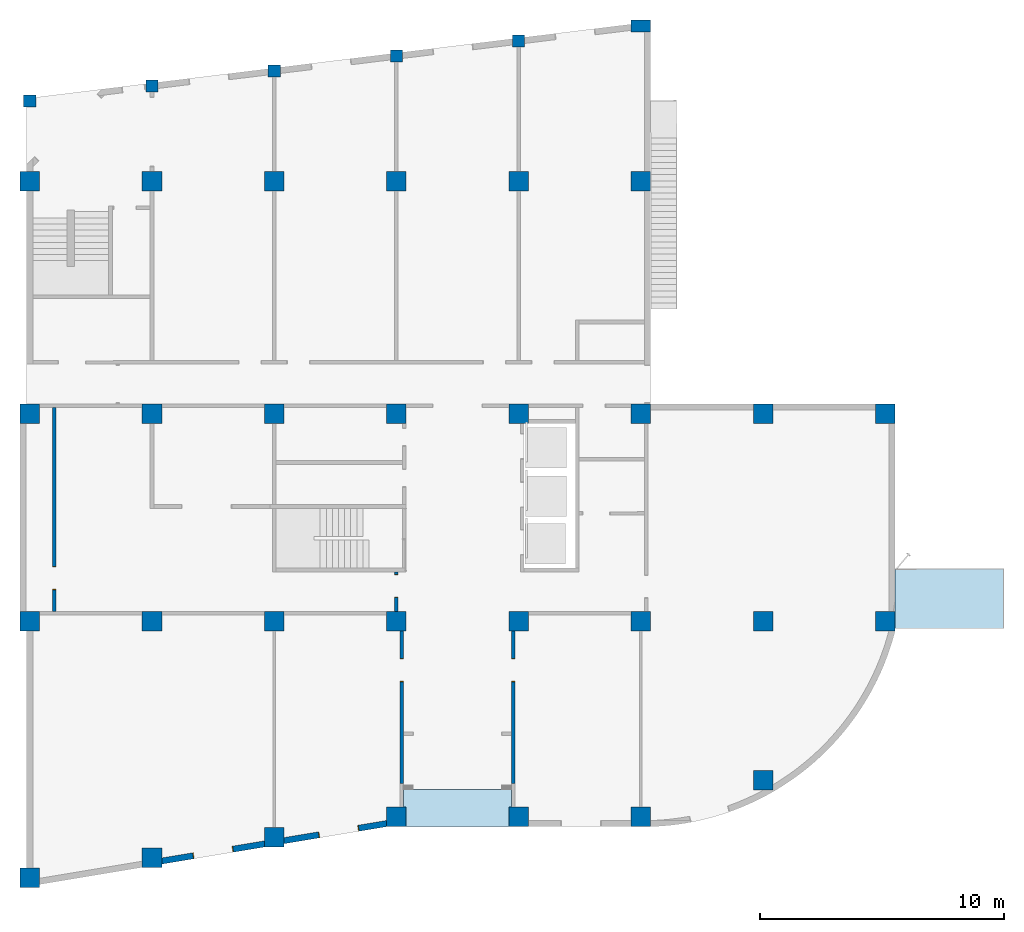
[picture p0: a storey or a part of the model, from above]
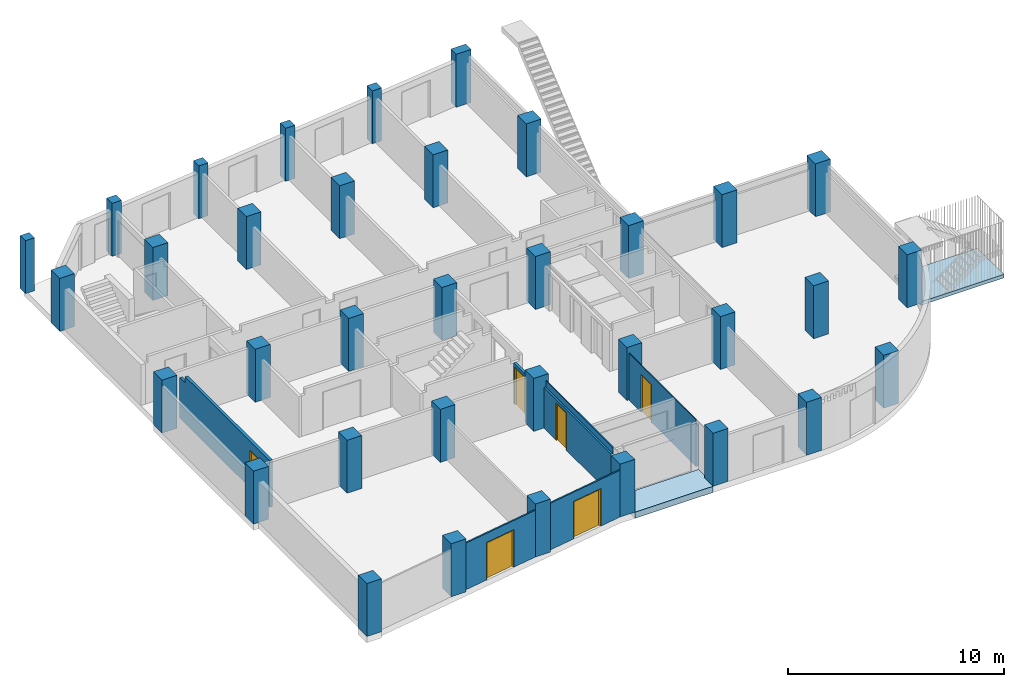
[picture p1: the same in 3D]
Properties of the parts of a building model (IFC2X3), part 8 of 10

# IfcWall: コンクリート 150 (271)
Name | In | 要素ID = 親ID | ホットリンクおよび要素ID | 関連ゾーン名 | 関連ゾーン番号 | ロック状態 | ホームフロア名 | ホームフロア数 | 絶対上部リンクフロア | 相対上部リンクフロア | 上部リンクフロア | 位置 | IsExternal | Length (mm) = 壁平均長 (mm) = 壁中心長さ (mm) | Height (mm) = 上端高度から配置フロア (mm) = 壁最大高さ (mm) | GrossFootprintArea (m2) = NetFootprintArea (m2) = 面積 (m2) | GrossSideArea (m2) | NetSideArea (m2) | GrossVolume (m3) = 条件付き体積 (m3) | NetVolume (m3) = 正味体積 (m3) | GLからの高度 (mm) = 高度 1 (mm) = 高度 2 (mm) = 海抜までの高度 (mm) = 下端高度から第1基準レベル (mm) = 下端高度から基準レベル (mm) = 下端高度から海抜 (mm) = 下端高度から第2基準レベル (mm) | 表面積 (m2) = 外面正味表面積 (m2) | 3D長さ (mm) | 総体積 (m3) | 平面図外周 (mm) | 上端高度から第1基準レベル (mm) = 上端高度から基準レベル (mm) = 上端高度から海抜 (mm) = 上端高度から第2基準レベル (mm) | ドア数 | 窓数 | 柱数 | 壁最小高さ (mm) | ドア面積 (m2) | ドア総幅 (mm) | 窓面積 (m2) | 窓総幅 (mm) | 内面分析的開口面積 (m2) | 外面分析的開口面積 (m2) | 辺の正味表面積 (m2) | 内面正味表面積 (m2) | 開口部分解法体積 (m3) | 基準線長さ (mm) | 条件付き内面長さ (mm) | 条件付き内面表面積 (m2) | 条件付き外面長さ (mm) | 条件付き外面表面積 (m2) | 内面総壁表面積 (m2) | 外面総壁表面積 (m2) | 内面壁長さ (mm) | 外面壁長さ (mm) | ホットリンク マスタID
W8 | 3FL | W8 | W8 | PS | ＜ゾーン番号＞ | no | 3FL | 3 | 4FL | 配置フロア + 1 | 配置フロア + 1 (4FL) | インテリア | no | 2675 | 2650 | 0.40125 | 6.94875 | 6.94875 | 1.04231 | 1.04231 | 6000 | 6.94875 | 2675 | 1.33875 | 5650 | 8650 | 0 | 0 | 0 | 0 | 0 | 0 | 0 | 0 | 0 | 0 | 0.40125 | 6.94875 | 2.22045e-16 | 2825 | 2675 | 6.94875 | 2675 | 6.94875 | 8.925 | 8.925 | 2675 | 2675
W4 | 3FL | W4 | W4 | 事務室 | 301 | no | 3FL | 3 | 4FL | 配置フロア + 1 | 配置フロア + 1 (4FL) | インテリア | no | 10150 | 2650 | 0.972 | 22.26 | 18.1704 | 3.339 | 2.72556 | 6000 | 18.1704 | 8400 | 4.68 | 20600 | 8650 | 2 | 0 | 3 | 0 | 4.4599 | 1800 | 0 | 0 | 4.0896 | 4.0896 | 0.972 | 18.1704 | 0.61344 | 10275 | 8230 | 18.1704 | 8230 | 18.1704 | 31.2 | 31.2 | 10150 | 10150
W5 | 3FL | W5 | W5 | 事務室 | 304 | no | 3FL | 3 | 4FL | 配置フロア + 1 | 配置フロア + 1 (4FL) | インテリア | no | 20150 | 2650 | 1.944 | 44.52 | 36.3408 | 6.678 | 5.45112 | 6000 | 36.3408 | 16800 | 9.18 | 40600 | 8650 | 4 | 0 | 5 | 0 | 8.9198 | 3600 | 0 | 0 | 8.1792 | 8.1792 | 1.944 | 36.3408 | 1.22688 | 20275 | 16310 | 36.3408 | 16310 | 36.3408 | 61.2 | 61.2 | 20150 | 20150
W6 | 3FL | W6 | W6 | DS | ＜ゾーン番号＞ | no | 3FL | 3 | 4FL | 配置フロア + 1 | 配置フロア + 1 (4FL) | インテリア | no | 5000 | 2650 | 0.6075 | 10.7325 | 10.7325 | 1.60987 | 1.60987 | 6000 | 10.7325 | 4050 | 2.39625 | 10362.1 | 8650 | 0 | 0 | 2 | 0 | 0 | 0 | 0 | 0 | 0 | 0 | 0.6075 | 10.7325 | 0 | 5125 | 5075 | 10.7325 | 4925 | 10.7325 | 15.975 | 15.975 | 5075 | 4925
W8 | 3FL | W8 | W8 | EVホール | ＜ゾーン番号＞ | no | 3FL | 3 | 4FL | 配置フロア + 1 | 配置フロア + 1 (4FL) | インテリア | no | 5325 | 2650 | 0.63 | 11.13 | 11.13 | 1.6695 | 1.6695 | 6000 | 11.13 | 4200 | 2.43 | 11012.1 | 8650 | 0 | 0 | 2 | 0 | 0 | 0 | 0 | 0 | 0 | 0 | 0.63 | 11.13 | 0 | 5325 | 5250 | 11.13 | 5400 | 11.13 | 16.2 | 16.2 | 5250 | 5400
W9 | 3FL | W9 | W9 | 事務室 | 310 | no | 3FL | 3 | 4FL | 配置フロア + 1 | 配置フロア + 1 (4FL) | インテリア | no | 5000 | 2650 | 0.63 | 11.13 | 11.13 | 1.6695 | 1.6695 | 6000 | 11.13 | 4200 | 2.25 | 10300 | 8650 | 0 | 0 | 2 | 0 | 0 | 0 | 0 | 0 | 0 | 0 | 0.63 | 11.13 | 0 | 5000 | 5000 | 11.13 | 5000 | 11.13 | 15 | 15 | 5000 | 5000
W0 | 3FL | W0 | W0 | 事務室 | 311 | no | 3FL | 3 | 4FL | 配置フロア + 1 | 配置フロア + 1 (4FL) | インテリア | no | 5400 | 2650 | 0.63 | 11.13 | 11.13 | 1.6695 | 1.6695 | 6000 | 11.13 | 4200 | 2.43 | 11100 | 8650 | 0 | 0 | 2 | 0 | 0 | 0 | 0 | 0 | 0 | 0 | 0.63 | 11.13 | 0 | 5400 | 5400 | 11.13 | 5400 | 11.13 | 16.2 | 16.2 | 5400 | 5400
W9 | 3FL | W9 | W9 | 事務室 | 313 | no | 3FL | 3 | 4FL | 配置フロア + 1 | 配置フロア + 1 (4FL) | インテリア | no | 20150 | 2650 | 2.45775 | 52.8175 | 44.6383 | 7.92263 | 6.69575 | 6000 | 44.6383 | 20225 | 9.21375 | 40662.1 | 8650 | 4 | 0 | 0 | 0 | 8.9198 | 3600 | 0 | 0 | 8.1792 | 8.1792 | 2.45775 | 44.6383 | 1.22688 | 20275 | 16235 | 44.6383 | 16385 | 44.6383 | 61.425 | 61.425 | 20075 | 20225
W4 | 3FL | W4 | W4 | EVホール | ＜ゾーン番号＞ | no | 3FL | 3 | 4FL | 配置フロア + 1 | 配置フロア + 1 (4FL) | インテリア | no | 4050 | 2650 | 0.27075 | 8.81125 | 5.57365 | 1.32169 | 0.836048 | 6000 | 5.57365 | 3325 | 1.96875 | 8462.13 | 8650 | 2 | 0 | 1 | 0 | 3.5939 | 1400 | 0 | 0 | 3.2376 | 3.2376 | 0.27075 | 5.57365 | 0.48564 | 4125 | 2455 | 8.81125 | 2605 | 8.81125 | 13.125 | 13.125 | 3975 | 4125
W6 | 3FL | W6 | W6 | EVシャフト | ＜ゾーン番号＞ | no | 3FL | 3 | 4FL | 配置フロア + 1 | 配置フロア + 1 (4FL) | インテリア | no | 6725 | 2300 | 0.41175 | 13.6275 | 6.8541 | 2.04413 | 1.02811 | 6000 | 6.8541 | 5925 | 3.09375 | 13874.3 | 8300 | 3 | 0 | 1 | 0 | 8.9445 | 3000 | 0 | 0 | 6.7734 | 6.7734 | 0.41175 | 6.8541 | 1.01601 | 6725 | 3695 | 6.8541 | 3395 | 6.8541 | 20.625 | 20.625 | 6875 | 6575
W4 | 3FL | W4 | W4 | EVホール | ＜ゾーン番号＞ | no | 3FL | 3 | 4FL | 配置フロア + 1 | 配置フロア + 1 (4FL) | インテリア | no | 1625 | 2300 | 0.04725 | 4.3125 | 0.9897 | 0.646875 | 0.148455 | 6000 | 0.9897 | 1875 | 0.91125 | 3550 | 8300 | 1 | 0 | 1 | 0 | 3.52895 | 1500 | 0 | 0 | 3.3228 | 3.3228 | 0.39225 | 0.9897 | 0.49842 | 1775 | 65 | 0.9897 | 65 | 0.9897 | 6.075 | 6.075 | 1625 | 1625
W8 | 3FL | W8 | W8 | EVホール | ＜ゾーン番号＞ | no | 3FL | 3 | 4FL | 配置フロア + 1 | 配置フロア + 1 (4FL) | インテリア | no | 2675 | 2650 | 0.20475 | 6.94875 | 3.27982 | 1.04231 | 0.623767 | 6000 | 4.47795 | 2675 | 1.33875 | 5650 | 8650 | 1 | 0 | 0 | 0 | 2.58 | 1100 | 0 | 0 | 4.86705 | 2.4708 | 0.20475 | 2.0817 | 0.418545 | 2825 | 390 | 2.0817 | 1515 | 4.47795 | 8.925 | 8.925 | 2675 | 2675
4FLW9 | 4FL | W9 | 4FLW9 | 事務室 | 313 | yes | 4FL | 4 | リンクなし | リンクなし | リンクなし | インテリア | no | 20150 | 2650 | 2.45775 | 52.8175 | 44.6383 | 7.92263 | 6.69575 | 9000 | 44.6383 | 20225 | 9.21375 | 40662.1 | 11650 | 4 | 0 | 0 | 0 | 8.9198 | 3600 | 0 | 0 | 8.1792 | 8.1792 | 2.45775 | 44.6383 | 1.22688 | 20275 | 16235 | 44.6383 | 16385 | 44.6383 | 61.425 | 61.425 | 20075 | 20225 | 4FL
4FLW8 | 4FL | W8 | 4FLW8 | DS | ＜ゾーン番号＞ | yes | 4FL | 4 | リンクなし | リンクなし | リンクなし | インテリア | no | 2100 | 2650 | 0.28875 | 5.10125 | 5.10125 | 0.765188 | 0.765188 | 9000 | 5.10125 | 1925 | 1.08 | 4500 | 11650 | 0 | 0 | 1 | 0 | 0 | 0 | 0 | 0 | 0 | 0 | 0.28875 | 5.10125 | 0 | 2250 | 2100 | 5.10125 | 2100 | 5.10125 | 7.2 | 7.2 | 2100 | 2100 | 4FL
4FLW4 | 4FL | W4 | 4FLW4 | EVホール | ＜ゾーン番号＞ | yes | 4FL | 4 | リンクなし | リンクなし | リンクなし | インテリア | no | 2600 | 2650 | 0.216 | 6.89 | 4.4192 | 1.0335 | 0.66288 | 9000 | 4.4192 | 2600 | 1.2375 | 5624.26 | 11650 | 1 | 0 | 0 | 0 | 2.66295 | 1100 | 0 | 0 | 2.4708 | 2.4708 | 0.216 | 4.4192 | 0.37062 | 2600 | 1290 | 4.4192 | 1590 | 4.4192 | 8.25 | 8.25 | 2450 | 2750 | 4FL | 一般性能 - 耐火性能: 3時間耐火構造
4FLW5 | 4FL | W5 | 4FLW5 | 男性用トイレ | ＜ゾーン番号＞ | yes | 4FL | 4 | リンクなし | リンクなし | リンクなし | インテリア | no | 5175 | 2650 | 0.77625 | 13.4775 | 13.4775 | 2.02162 | 2.02162 | 9000 | 13.4775 | 5175 | 2.46375 | 10650 | 11650 | 0 | 0 | 0 | 0 | 0 | 0 | 0 | 0 | 0 | 0 | 0.77625 | 13.4775 | 0 | 5325 | 5175 | 13.4775 | 5175 | 13.4775 | 16.425 | 16.425 | 5175 | 5175 | 4FL
4FLW4 | 4FL | W4 | 4FLW4 | 事務室 | 303 | yes | 4FL | 4 | リンクなし | リンクなし | リンクなし | インテリア | no | 5000 | 2650 | 0.486 | 11.13 | 9.0852 | 1.6695 | 1.36278 | 9000 | 9.0852 | 4200 | 2.25 | 10300 | 11650 | 1 | 0 | 2 | 0 | 2.22995 | 900 | 0 | 0 | 2.0448 | 2.0448 | 0.486 | 9.0852 | 0.30672 | 5000 | 4040 | 9.0852 | 4040 | 9.0852 | 15 | 15 | 5000 | 5000 | 4FL
4FLW1 | 4FL | W1 | 4FLW1 | 事務室 | 310 | yes | 4FL | 4 | リンクなし | リンクなし | リンクなし | インテリア | no | 4050 | 2300 | 0.51 | 7.82 | 7.82 | 1.173 | 1.173 | 9000 | 7.82 | 3400 | 1.89 | 8400 | 11300 | 0 | 0 | 1 | 0 | 0 | 0 | 0 | 0 | 0 | 0 | 0.855 | 7.82 | 0 | 4125 | 4050 | 7.82 | 4050 | 7.82 | 12.6 | 12.6 | 4050 | 4050 | 4FL
4FLW2 | 4FL | W2 | 4FLW2 | 事務室 | 310 | yes | 4FL | 4 | リンクなし | リンクなし | リンクなし | インテリア | no | 2600 | 2300 | 0.36375 | 5.5775 | 5.5775 | 0.836625 | 0.836625 | 9000 | 5.5775 | 2425 | 1.20375 | 5562.13 | 11300 | 0 | 0 | 0 | 0 | 0 | 0 | 0 | 0 | 0 | 0 | 0.70875 | 5.5775 | 0 | 2600 | 2675 | 5.5775 | 2525 | 5.5775 | 8.025 | 8.025 | 2675 | 2525 | 4FL | 一般性能 - 耐火性能: 3時間耐火構造
4FLW8 | 4FL | W8 | 4FLW8 | DS | ＜ゾーン番号＞ | yes | 4FL | 4 | リンクなし | リンクなし | リンクなし | インテリア | no | 8425 | 2650 | 1.2525 | 21.9525 | 21.9525 | 3.29287 | 3.29287 | 9000 | 21.9525 | 8350 | 3.8925 | 17212.1 | 11650 | 0 | 0 | 0 | 0 | 0 | 0 | 0 | 0 | 3.55271e-15 | 7.10543e-15 | 1.2525 | 21.9525 | 4.44089e-16 | 8500 | 8350 | 21.9525 | 8500 | 21.9525 | 25.95 | 25.95 | 8350 | 8500 | 4FL
4FLW7 | 4FL | W7 | 4FLW7 | EVシャフト | ＜ゾーン番号＞ | yes | 4FL | 4 | リンクなし | リンクなし | リンクなし | インテリア | no | 2250 | 2650 | 0.36 | 6.29875 | 6.29875 | 0.944813 | 0.944813 | 9000 | 6.29875 | 2400 | 1.08 | 4924.26 | 11650 | 0 | 0 | 0 | 0 | 0 | 0 | 0 | 0 | 0 | 0 | 0.36 | 6.29875 | 0 | 2250 | 2100 | 6.29875 | 2400 | 6.29875 | 7.2 | 7.2 | 2100 | 2400 | 4FL
4FLW5 | 4FL | W5 | 4FLW5 | 事務室 | 309 | yes | 4FL | 4 | リンクなし | リンクなし | リンクなし | インテリア | no | 6650 | 2650 | 0.88875 | 14.6644 | 14.6644 | 2.14781 | 2.14781 | 9000 | 15.7012 | 5925 | 3.09375 | 13662.1 | 11650 | 0 | 0 | 1 | 0 | 0 | 0 | 0 | 0 | 0 | 0 | 0.88875 | 13.6275 | 0 | 6725 | 6725 | 13.6275 | 6575 | 15.7012 | 20.625 | 20.625 | 6725 | 6575 | 4FL
4FLW7 | 4FL | W7 | 4FLW7 | 事務室 | 308 | yes | 4FL | 4 | リンクなし | リンクなし | リンクなし | インテリア | no | 9925 | 2650 | 1.212 | 26.15 | 22.0604 | 3.9225 | 3.30906 | 9000 | 22.0604 | 10000 | 4.6125 | 20212.1 | 11650 | 2 | 0 | 0 | 0 | 4.4599 | 1800 | 0 | 0 | 4.0896 | 4.0896 | 1.212 | 22.0604 | 0.61344 | 10050 | 7930 | 22.0604 | 8080 | 22.0604 | 30.75 | 30.75 | 9850 | 10000 | 4FL
4FLW3 | 4FL | W3 | 4FLW3 | 事務室 | 310 | yes | 4FL | 4 | リンクなし | リンクなし | リンクなし | インテリア | no | 10150 | 2650 | 1.22325 | 26.3225 | 22.2329 | 3.94838 | 3.33494 | 9000 | 22.2329 | 10075 | 4.71375 | 20662.1 | 11650 | 2 | 0 | 0 | 0 | 4.4599 | 1800 | 0 | 0 | 4.0896 | 4.0896 | 1.22325 | 22.2329 | 0.61344 | 10275 | 8155 | 22.2329 | 8305 | 22.2329 | 31.425 | 31.425 | 10075 | 10225 | 4FL
4FLW4 | 4FL | W4 | 4FLW4 | 女性用トイレ | ＜ゾーン番号＞ | yes | 4FL | 4 | リンクなし | リンクなし | リンクなし | インテリア | no | 5250 | 2650 | 0.79875 | 13.875 | 13.875 | 2.08125 | 2.08125 | 9000 | 13.875 | 5325 | 2.46375 | 10862.1 | 11650 | 0 | 0 | 0 | 0 | 0 | 0 | 0 | 0 | 0 | 0 | 0.79875 | 13.875 | 0 | 5325 | 5325 | 13.875 | 5175 | 13.875 | 16.425 | 16.425 | 5325 | 5175 | 4FL | 一般性能 - 耐火性能: 3時間耐火構造
4FLW8 | 4FL | W8 | 4FLW8 | PS | ＜ゾーン番号＞ | yes | 4FL | 4 | リンクなし | リンクなし | リンクなし | インテリア | no | 2675 | 2650 | 0.40125 | 6.94875 | 6.94875 | 1.04231 | 1.04231 | 9000 | 6.94875 | 2675 | 1.33875 | 5650 | 11650 | 0 | 0 | 0 | 0 | 0 | 0 | 0 | 0 | 0 | 0 | 0.40125 | 6.94875 | 0 | 2825 | 2675 | 6.94875 | 2675 | 6.94875 | 8.925 | 8.925 | 2675 | 2675 | 4FL
4FLW4 | 4FL | W4 | 4FLW4 | 事務室 | 301 | yes | 4FL | 4 | リンクなし | リンクなし | リンクなし | インテリア | no | 10150 | 2650 | 0.972 | 22.26 | 18.1704 | 3.339 | 2.72556 | 9000 | 18.1704 | 8400 | 4.68 | 20600 | 11650 | 2 | 0 | 3 | 0 | 4.4599 | 1800 | 0 | 0 | 4.0896 | 4.0896 | 0.972 | 18.1704 | 0.61344 | 10275 | 8230 | 18.1704 | 8230 | 18.1704 | 31.2 | 31.2 | 10150 | 10150 | 4FL
4FLW5 | 4FL | W5 | 4FLW5 | 事務室 | 304 | yes | 4FL | 4 | リンクなし | リンクなし | リンクなし | インテリア | no | 20150 | 2650 | 1.944 | 44.52 | 36.3408 | 6.678 | 5.45112 | 9000 | 36.3408 | 16800 | 9.18 | 40600 | 11650 | 4 | 0 | 5 | 0 | 8.9198 | 3600 | 0 | 0 | 8.1792 | 8.1792 | 1.944 | 36.3408 | 1.22688 | 20275 | 16310 | 36.3408 | 16310 | 36.3408 | 61.2 | 61.2 | 20150 | 20150 | 4FL
4FLW6 | 4FL | W6 | 4FLW6 | DS | ＜ゾーン番号＞ | yes | 4FL | 4 | リンクなし | リンクなし | リンクなし | インテリア | no | 5000 | 2650 | 0.6075 | 10.7325 | 10.7325 | 1.60987 | 1.60987 | 9000 | 10.7325 | 4050 | 2.39625 | 10362.1 | 11650 | 0 | 0 | 2 | 0 | 0 | 0 | 0 | 0 | 0 | 0 | 0.6075 | 10.7325 | 0 | 5125 | 5075 | 10.7325 | 4925 | 10.7325 | 15.975 | 15.975 | 5075 | 4925 | 4FL
4FLW8 | 4FL | W8 | 4FLW8 | EVホール | ＜ゾーン番号＞ | yes | 4FL | 4 | リンクなし | リンクなし | リンクなし | インテリア | no | 5325 | 2650 | 0.63 | 11.13 | 11.13 | 1.6695 | 1.6695 | 9000 | 11.13 | 4200 | 2.43 | 11012.1 | 11650 | 0 | 0 | 2 | 0 | 0 | 0 | 0 | 0 | 0 | 0 | 0.63 | 11.13 | 0 | 5325 | 5250 | 11.13 | 5400 | 11.13 | 16.2 | 16.2 | 5250 | 5400 | 4FL
4FLW9 | 4FL | W9 | 4FLW9 | 事務室 | 310 | yes | 4FL | 4 | リンクなし | リンクなし | リンクなし | インテリア | no | 5000 | 2650 | 0.63 | 11.13 | 11.13 | 1.6695 | 1.6695 | 9000 | 11.13 | 4200 | 2.25 | 10300 | 11650 | 0 | 0 | 2 | 0 | 0 | 0 | 0 | 0 | 0 | 0 | 0.63 | 11.13 | 0 | 5000 | 5000 | 11.13 | 5000 | 11.13 | 15 | 15 | 5000 | 5000 | 4FL
4FLW0 | 4FL | W0 | 4FLW0 | 事務室 | 311 | yes | 4FL | 4 | リンクなし | リンクなし | リンクなし | インテリア | no | 5400 | 2650 | 0.63 | 11.13 | 11.13 | 1.6695 | 1.6695 | 9000 | 11.13 | 4200 | 2.43 | 11100 | 11650 | 0 | 0 | 2 | 0 | 0 | 0 | 0 | 0 | 0 | 0 | 0.63 | 11.13 | 0 | 5400 | 5400 | 11.13 | 5400 | 11.13 | 16.2 | 16.2 | 5400 | 5400 | 4FL
4FLW8 | 4FL | W8 | 4FLW8 | EVホール | ＜ゾーン番号＞ | yes | 4FL | 4 | リンクなし | リンクなし | リンクなし | インテリア | no | 2675 | 2650 | 0.20475 | 6.94875 | 3.27982 | 1.04231 | 0.623767 | 9000 | 4.47795 | 2675 | 1.33875 | 5650 | 11650 | 1 | 0 | 0 | 0 | 2.58 | 1100 | 0 | 0 | 4.86705 | 2.4708 | 0.20475 | 2.0817 | 0.418545 | 2825 | 390 | 2.0817 | 1515 | 4.47795 | 8.925 | 8.925 | 2675 | 2675 | 4FL
4FLW3 | 4FL | W3 | 4FLW3 | EVホール | ＜ゾーン番号＞ | yes | 4FL | 4 | リンクなし | リンクなし | リンクなし | インテリア | no | 5250 | 2650 | 0.77625 | 13.4775 | 13.4775 | 2.02162 | 2.02162 | 9000 | 13.4775 | 5175 | 2.50875 | 10862.1 | 11650 | 0 | 0 | 0 | 0 | 0 | 0 | 0 | 0 | 0 | 0 | 0.77625 | 13.4775 | 8.88178e-16 | 5325 | 5175 | 13.4775 | 5325 | 13.4775 | 16.725 | 16.725 | 5175 | 5325 | 4FL | 一般性能 - 耐火性能: 3時間耐火構造
4FLW9 | 4FL | W9 | 4FLW9 | EVホール | ＜ゾーン番号＞ | yes | 4FL | 4 | リンクなし | リンクなし | リンクなし | インテリア | no | 1700 | 2300 | 0.00974999 | 3.7375 | 0.4147 | 0.560625 | 0.062205 | 9000 | 0.4147 | 1625 | 0.86625 | 3762.13 | 11300 | 1 | 0 | 1 | 0 | 3.52895 | 1500 | 0 | 0 | 3.3228 | 3.3228 | 0.00974999 | 0.4147 | 0.49842 | 1775 | 65 | 0.4147 | 215 | 0.4147 | 5.775 | 5.775 | 1625 | 1775 | 4FL
4FLW6 | 4FL | W6 | 4FLW6 | EVシャフト | ＜ゾーン番号＞ | yes | 4FL | 4 | リンクなし | リンクなし | リンクなし | インテリア | no | 6725 | 2300 | 0.41175 | 13.6275 | 6.8541 | 2.04413 | 1.02811 | 9000 | 6.8541 | 5925 | 3.09375 | 13874.3 | 11300 | 3 | 0 | 1 | 0 | 8.9445 | 3000 | 0 | 0 | 6.7734 | 6.7734 | 0.41175 | 6.8541 | 1.01601 | 6725 | 3695 | 6.8541 | 3395 | 6.8541 | 20.625 | 20.625 | 6875 | 6575 | 4FL
4FLW4 | 4FL | W4 | 4FLW4 | EVホール | ＜ゾーン番号＞ | yes | 4FL | 4 | リンクなし | リンクなし | リンクなし | インテリア | no | 1625 | 2300 | 0.04725 | 4.3125 | 0.9897 | 0.646875 | 0.148455 | 9000 | 0.9897 | 1875 | 0.91125 | 3550 | 11300 | 1 | 0 | 1 | 0 | 3.52895 | 1500 | 0 | 0 | 3.3228 | 3.3228 | 0.39225 | 0.9897 | 0.49842 | 1775 | 65 | 0.9897 | 65 | 0.9897 | 6.075 | 6.075 | 1625 | 1625 | 4FL
4FLW4 | 4FL | W4 | 4FLW4 | EVホール | ＜ゾーン番号＞ | yes | 4FL | 4 | リンクなし | リンクなし | リンクなし | インテリア | no | 4050 | 2650 | 0.27075 | 8.81125 | 5.57365 | 1.32169 | 0.836048 | 9000 | 5.57365 | 3325 | 1.96875 | 8462.13 | 11650 | 2 | 0 | 1 | 0 | 3.5939 | 1400 | 0 | 0 | 3.2376 | 3.2376 | 0.27075 | 5.57365 | 0.48564 | 4125 | 2455 | 8.81125 | 2605 | 8.81125 | 13.125 | 13.125 | 3975 | 4125 | 4FL
5FLW9 | 5FL | W9 | 5FLW9 | 事務室 | 313 | yes | 5FL | 5 | リンクなし | リンクなし | リンクなし | インテリア | no | 20150 | 2650 | 2.45775 | 52.8175 | 44.6383 | 7.92263 | 6.69575 | 12000 | 44.6383 | 20225 | 9.21375 | 40662.1 | 14650 | 4 | 0 | 0 | 0 | 8.9198 | 3600 | 0 | 0 | 8.1792 | 8.1792 | 2.45775 | 44.6383 | 1.22688 | 20275 | 16235 | 44.6383 | 16385 | 44.6383 | 61.425 | 61.425 | 20075 | 20225 | 5FL
5FLW8 | 5FL | W8 | 5FLW8 | DS | ＜ゾーン番号＞ | yes | 5FL | 5 | リンクなし | リンクなし | リンクなし | インテリア | no | 2100 | 2650 | 0.28875 | 5.10125 | 5.10125 | 0.765188 | 0.765188 | 12000 | 5.10125 | 1925 | 1.08 | 4500 | 14650 | 0 | 0 | 1 | 0 | 0 | 0 | 0 | 0 | 0 | 0 | 0.28875 | 5.10125 | 0 | 2250 | 2100 | 5.10125 | 2100 | 5.10125 | 7.2 | 7.2 | 2100 | 2100 | 5FL
5FLW4 | 5FL | W4 | 5FLW4 | EVホール | ＜ゾーン番号＞ | yes | 5FL | 5 | リンクなし | リンクなし | リンクなし | インテリア | no | 2600 | 2650 | 0.216 | 6.89 | 4.4192 | 1.0335 | 0.66288 | 12000 | 4.4192 | 2600 | 1.2375 | 5624.26 | 14650 | 1 | 0 | 0 | 0 | 2.66295 | 1100 | 0 | 0 | 2.4708 | 2.4708 | 0.216 | 4.4192 | 0.37062 | 2600 | 1290 | 4.4192 | 1590 | 4.4192 | 8.25 | 8.25 | 2450 | 2750 | 5FL | 一般性能 - 耐火性能: 3時間耐火構造
5FLW5 | 5FL | W5 | 5FLW5 | 男性用トイレ | ＜ゾーン番号＞ | yes | 5FL | 5 | リンクなし | リンクなし | リンクなし | インテリア | no | 5175 | 2650 | 0.77625 | 13.4775 | 13.4775 | 2.02162 | 2.02162 | 12000 | 13.4775 | 5175 | 2.46375 | 10650 | 14650 | 0 | 0 | 0 | 0 | 0 | 0 | 0 | 0 | 0 | 0 | 0.77625 | 13.4775 | 0 | 5325 | 5175 | 13.4775 | 5175 | 13.4775 | 16.425 | 16.425 | 5175 | 5175 | 5FL
5FLW4 | 5FL | W4 | 5FLW4 | 事務室 | 303 | yes | 5FL | 5 | リンクなし | リンクなし | リンクなし | インテリア | no | 5000 | 2650 | 0.486 | 11.13 | 9.0852 | 1.6695 | 1.36278 | 12000 | 9.0852 | 4200 | 2.25 | 10300 | 14650 | 1 | 0 | 2 | 0 | 2.22995 | 900 | 0 | 0 | 2.0448 | 2.0448 | 0.486 | 9.0852 | 0.30672 | 5000 | 4040 | 9.0852 | 4040 | 9.0852 | 15 | 15 | 5000 | 5000 | 5FL
5FLW1 | 5FL | W1 | 5FLW1 | 事務室 | 310 | yes | 5FL | 5 | リンクなし | リンクなし | リンクなし | インテリア | no | 4050 | 2300 | 0.51 | 7.82 | 7.82 | 1.173 | 1.173 | 12000 | 7.82 | 3400 | 1.89 | 8400 | 14300 | 0 | 0 | 1 | 0 | 0 | 0 | 0 | 0 | 0 | 0 | 0.855 | 7.82 | 0 | 4125 | 4050 | 7.82 | 4050 | 7.82 | 12.6 | 12.6 | 4050 | 4050 | 5FL
5FLW2 | 5FL | W2 | 5FLW2 | 事務室 | 310 | yes | 5FL | 5 | リンクなし | リンクなし | リンクなし | インテリア | no | 2600 | 2300 | 0.36375 | 5.5775 | 5.5775 | 0.836625 | 0.836625 | 12000 | 5.5775 | 2425 | 1.20375 | 5562.13 | 14300 | 0 | 0 | 0 | 0 | 0 | 0 | 0 | 0 | 0 | 0 | 0.70875 | 5.5775 | 0 | 2600 | 2675 | 5.5775 | 2525 | 5.5775 | 8.025 | 8.025 | 2675 | 2525 | 5FL | 一般性能 - 耐火性能: 3時間耐火構造
5FLW8 | 5FL | W8 | 5FLW8 | DS | ＜ゾーン番号＞ | yes | 5FL | 5 | リンクなし | リンクなし | リンクなし | インテリア | no | 8425 | 2650 | 1.2525 | 21.9525 | 21.9525 | 3.29287 | 3.29287 | 12000 | 21.9525 | 8350 | 3.8925 | 17212.1 | 14650 | 0 | 0 | 0 | 0 | 0 | 0 | 0 | 0 | 3.55271e-15 | 7.10543e-15 | 1.2525 | 21.9525 | 4.44089e-16 | 8500 | 8350 | 21.9525 | 8500 | 21.9525 | 25.95 | 25.95 | 8350 | 8500 | 5FL
5FLW7 | 5FL | W7 | 5FLW7 | EVシャフト | ＜ゾーン番号＞ | yes | 5FL | 5 | リンクなし | リンクなし | リンクなし | インテリア | no | 2250 | 2650 | 0.36 | 6.29875 | 6.29875 | 0.944813 | 0.944813 | 12000 | 6.29875 | 2400 | 1.08 | 4924.26 | 14650 | 0 | 0 | 0 | 0 | 0 | 0 | 0 | 0 | 0 | 0 | 0.36 | 6.29875 | 0 | 2250 | 2100 | 6.29875 | 2400 | 6.29875 | 7.2 | 7.2 | 2100 | 2400 | 5FL
5FLW5 | 5FL | W5 | 5FLW5 | 事務室 | 309 | yes | 5FL | 5 | リンクなし | リンクなし | リンクなし | インテリア | no | 6650 | 2650 | 0.88875 | 14.6644 | 14.6644 | 2.14781 | 2.14781 | 12000 | 15.7012 | 5925 | 3.09375 | 13662.1 | 14650 | 0 | 0 | 1 | 0 | 0 | 0 | 0 | 0 | 0 | 0 | 0.88875 | 13.6275 | 0 | 6725 | 6725 | 13.6275 | 6575 | 15.7012 | 20.625 | 20.625 | 6725 | 6575 | 5FL
5FLW7 | 5FL | W7 | 5FLW7 | 事務室 | 308 | yes | 5FL | 5 | リンクなし | リンクなし | リンクなし | インテリア | no | 9925 | 2650 | 1.212 | 26.15 | 22.0604 | 3.9225 | 3.30906 | 12000 | 22.0604 | 10000 | 4.6125 | 20212.1 | 14650 | 2 | 0 | 0 | 0 | 4.4599 | 1800 | 0 | 0 | 4.0896 | 4.0896 | 1.212 | 22.0604 | 0.61344 | 10050 | 7930 | 22.0604 | 8080 | 22.0604 | 30.75 | 30.75 | 9850 | 10000 | 5FL
5FLW3 | 5FL | W3 | 5FLW3 | 事務室 | 310 | yes | 5FL | 5 | リンクなし | リンクなし | リンクなし | インテリア | no | 10150 | 2650 | 1.22325 | 26.3225 | 22.2329 | 3.94838 | 3.33494 | 12000 | 22.2329 | 10075 | 4.71375 | 20662.1 | 14650 | 2 | 0 | 0 | 0 | 4.4599 | 1800 | 0 | 0 | 4.0896 | 4.0896 | 1.22325 | 22.2329 | 0.61344 | 10275 | 8155 | 22.2329 | 8305 | 22.2329 | 31.425 | 31.425 | 10075 | 10225 | 5FL
5FLW4 | 5FL | W4 | 5FLW4 | 女性用トイレ | ＜ゾーン番号＞ | yes | 5FL | 5 | リンクなし | リンクなし | リンクなし | インテリア | no | 5250 | 2650 | 0.79875 | 13.875 | 13.875 | 2.08125 | 2.08125 | 12000 | 13.875 | 5325 | 2.46375 | 10862.1 | 14650 | 0 | 0 | 0 | 0 | 0 | 0 | 0 | 0 | 0 | 0 | 0.79875 | 13.875 | 0 | 5325 | 5325 | 13.875 | 5175 | 13.875 | 16.425 | 16.425 | 5325 | 5175 | 5FL | 一般性能 - 耐火性能: 3時間耐火構造
5FLW8 | 5FL | W8 | 5FLW8 | PS | ＜ゾーン番号＞ | yes | 5FL | 5 | リンクなし | リンクなし | リンクなし | インテリア | no | 2675 | 2650 | 0.40125 | 6.94875 | 6.94875 | 1.04231 | 1.04231 | 12000 | 6.94875 | 2675 | 1.33875 | 5650 | 14650 | 0 | 0 | 0 | 0 | 0 | 0 | 0 | 0 | 0 | 0 | 0.40125 | 6.94875 | 0 | 2825 | 2675 | 6.94875 | 2675 | 6.94875 | 8.925 | 8.925 | 2675 | 2675 | 5FL
5FLW4 | 5FL | W4 | 5FLW4 | 事務室 | 301 | yes | 5FL | 5 | リンクなし | リンクなし | リンクなし | インテリア | no | 10150 | 2650 | 0.972 | 22.26 | 18.1704 | 3.339 | 2.72556 | 12000 | 18.1704 | 8400 | 4.68 | 20600 | 14650 | 2 | 0 | 3 | 0 | 4.4599 | 1800 | 0 | 0 | 4.0896 | 4.0896 | 0.972 | 18.1704 | 0.61344 | 10275 | 8230 | 18.1704 | 8230 | 18.1704 | 31.2 | 31.2 | 10150 | 10150 | 5FL
5FLW5 | 5FL | W5 | 5FLW5 | 事務室 | 304 | yes | 5FL | 5 | リンクなし | リンクなし | リンクなし | インテリア | no | 20150 | 2650 | 1.944 | 44.52 | 36.3408 | 6.678 | 5.45112 | 12000 | 36.3408 | 16800 | 9.18 | 40600 | 14650 | 4 | 0 | 5 | 0 | 8.9198 | 3600 | 0 | 0 | 8.1792 | 8.1792 | 1.944 | 36.3408 | 1.22688 | 20275 | 16310 | 36.3408 | 16310 | 36.3408 | 61.2 | 61.2 | 20150 | 20150 | 5FL
5FLW6 | 5FL | W6 | 5FLW6 | DS | ＜ゾーン番号＞ | yes | 5FL | 5 | リンクなし | リンクなし | リンクなし | インテリア | no | 5000 | 2650 | 0.6075 | 10.7325 | 10.7325 | 1.60987 | 1.60987 | 12000 | 10.7325 | 4050 | 2.39625 | 10362.1 | 14650 | 0 | 0 | 2 | 0 | 0 | 0 | 0 | 0 | 0 | 0 | 0.6075 | 10.7325 | 0 | 5125 | 5075 | 10.7325 | 4925 | 10.7325 | 15.975 | 15.975 | 5075 | 4925 | 5FL
5FLW8 | 5FL | W8 | 5FLW8 | EVホール | ＜ゾーン番号＞ | yes | 5FL | 5 | リンクなし | リンクなし | リンクなし | インテリア | no | 5325 | 2650 | 0.63 | 11.13 | 11.13 | 1.6695 | 1.6695 | 12000 | 11.13 | 4200 | 2.43 | 11012.1 | 14650 | 0 | 0 | 2 | 0 | 0 | 0 | 0 | 0 | 0 | 0 | 0.63 | 11.13 | 0 | 5325 | 5250 | 11.13 | 5400 | 11.13 | 16.2 | 16.2 | 5250 | 5400 | 5FL
5FLW9 | 5FL | W9 | 5FLW9 | 事務室 | 310 | yes | 5FL | 5 | リンクなし | リンクなし | リンクなし | インテリア | no | 5000 | 2650 | 0.63 | 11.13 | 11.13 | 1.6695 | 1.6695 | 12000 | 11.13 | 4200 | 2.25 | 10300 | 14650 | 0 | 0 | 2 | 0 | 0 | 0 | 0 | 0 | 0 | 0 | 0.63 | 11.13 | 0 | 5000 | 5000 | 11.13 | 5000 | 11.13 | 15 | 15 | 5000 | 5000 | 5FL
5FLW0 | 5FL | W0 | 5FLW0 | 事務室 | 311 | yes | 5FL | 5 | リンクなし | リンクなし | リンクなし | インテリア | no | 5400 | 2650 | 0.63 | 11.13 | 11.13 | 1.6695 | 1.6695 | 12000 | 11.13 | 4200 | 2.43 | 11100 | 14650 | 0 | 0 | 2 | 0 | 0 | 0 | 0 | 0 | 0 | 0 | 0.63 | 11.13 | 0 | 5400 | 5400 | 11.13 | 5400 | 11.13 | 16.2 | 16.2 | 5400 | 5400 | 5FL
5FLW8 | 5FL | W8 | 5FLW8 | EVホール | ＜ゾーン番号＞ | yes | 5FL | 5 | リンクなし | リンクなし | リンクなし | インテリア | no | 2675 | 2650 | 0.20475 | 6.94875 | 3.27982 | 1.04231 | 0.623767 | 12000 | 4.47795 | 2675 | 1.33875 | 5650 | 14650 | 1 | 0 | 0 | 0 | 2.58 | 1100 | 0 | 0 | 4.86705 | 2.4708 | 0.20475 | 2.0817 | 0.418545 | 2825 | 390 | 2.0817 | 1515 | 4.47795 | 8.925 | 8.925 | 2675 | 2675 | 5FL
5FLW3 | 5FL | W3 | 5FLW3 | EVホール | ＜ゾーン番号＞ | yes | 5FL | 5 | リンクなし | リンクなし | リンクなし | インテリア | no | 5250 | 2650 | 0.77625 | 13.4775 | 13.4775 | 2.02162 | 2.02162 | 12000 | 13.4775 | 5175 | 2.50875 | 10862.1 | 14650 | 0 | 0 | 0 | 0 | 0 | 0 | 0 | 0 | 0 | 0 | 0.77625 | 13.4775 | 8.88178e-16 | 5325 | 5175 | 13.4775 | 5325 | 13.4775 | 16.725 | 16.725 | 5175 | 5325 | 5FL | 一般性能 - 耐火性能: 3時間耐火構造
5FLW9 | 5FL | W9 | 5FLW9 | EVホール | ＜ゾーン番号＞ | yes | 5FL | 5 | リンクなし | リンクなし | リンクなし | インテリア | no | 1700 | 2300 | 0.00974999 | 3.7375 | 0.4147 | 0.560625 | 0.062205 | 12000 | 0.4147 | 1625 | 0.86625 | 3762.13 | 14300 | 1 | 0 | 1 | 0 | 3.52895 | 1500 | 0 | 0 | 3.3228 | 3.3228 | 0.00974999 | 0.4147 | 0.49842 | 1775 | 65 | 0.4147 | 215 | 0.4147 | 5.775 | 5.775 | 1625 | 1775 | 5FL
5FLW6 | 5FL | W6 | 5FLW6 | EVシャフト | ＜ゾーン番号＞ | yes | 5FL | 5 | リンクなし | リンクなし | リンクなし | インテリア | no | 6725 | 2300 | 0.41175 | 13.6275 | 6.8541 | 2.04413 | 1.02811 | 12000 | 6.8541 | 5925 | 3.09375 | 13874.3 | 14300 | 3 | 0 | 1 | 0 | 8.9445 | 3000 | 0 | 0 | 6.7734 | 6.7734 | 0.41175 | 6.8541 | 1.01601 | 6725 | 3695 | 6.8541 | 3395 | 6.8541 | 20.625 | 20.625 | 6875 | 6575 | 5FL
5FLW4 | 5FL | W4 | 5FLW4 | EVホール | ＜ゾーン番号＞ | yes | 5FL | 5 | リンクなし | リンクなし | リンクなし | インテリア | no | 1625 | 2300 | 0.04725 | 4.3125 | 0.9897 | 0.646875 | 0.148455 | 12000 | 0.9897 | 1875 | 0.91125 | 3550 | 14300 | 1 | 0 | 1 | 0 | 3.52895 | 1500 | 0 | 0 | 3.3228 | 3.3228 | 0.39225 | 0.9897 | 0.49842 | 1775 | 65 | 0.9897 | 65 | 0.9897 | 6.075 | 6.075 | 1625 | 1625 | 5FL
5FLW4 | 5FL | W4 | 5FLW4 | EVホール | ＜ゾーン番号＞ | yes | 5FL | 5 | リンクなし | リンクなし | リンクなし | インテリア | no | 4050 | 2650 | 0.27075 | 8.81125 | 5.57365 | 1.32169 | 0.836048 | 12000 | 5.57365 | 3325 | 1.96875 | 8462.13 | 14650 | 2 | 0 | 1 | 0 | 3.5939 | 1400 | 0 | 0 | 3.2376 | 3.2376 | 0.27075 | 5.57365 | 0.48564 | 4125 | 2455 | 8.81125 | 2605 | 8.81125 | 13.125 | 13.125 | 3975 | 4125 | 5FL
6FLW9 | 6FL | W9 | 6FLW9 | 事務室 | 313 | yes | 6FL | 6 | リンクなし | リンクなし | リンクなし | インテリア | no | 20150 | 2650 | 2.45775 | 52.8175 | 44.6383 | 7.92263 | 6.69575 | 15000 | 44.6383 | 20225 | 9.21375 | 40662.1 | 17650 | 4 | 0 | 0 | 0 | 8.9198 | 3600 | 0 | 0 | 8.1792 | 8.1792 | 2.45775 | 44.6383 | 1.22688 | 20275 | 16235 | 44.6383 | 16385 | 44.6383 | 61.425 | 61.425 | 20075 | 20225 | 6FL
6FLW8 | 6FL | W8 | 6FLW8 | DS | ＜ゾーン番号＞ | yes | 6FL | 6 | リンクなし | リンクなし | リンクなし | インテリア | no | 2100 | 2650 | 0.28875 | 5.10125 | 5.10125 | 0.765188 | 0.765188 | 15000 | 5.10125 | 1925 | 1.08 | 4500 | 17650 | 0 | 0 | 1 | 0 | 0 | 0 | 0 | 0 | 0 | 0 | 0.28875 | 5.10125 | 0 | 2250 | 2100 | 5.10125 | 2100 | 5.10125 | 7.2 | 7.2 | 2100 | 2100 | 6FL
6FLW4 | 6FL | W4 | 6FLW4 | EVホール | ＜ゾーン番号＞ | yes | 6FL | 6 | リンクなし | リンクなし | リンクなし | インテリア | no | 2600 | 2650 | 0.216 | 6.89 | 4.4192 | 1.0335 | 0.66288 | 15000 | 4.4192 | 2600 | 1.2375 | 5624.26 | 17650 | 1 | 0 | 0 | 0 | 2.66295 | 1100 | 0 | 0 | 2.4708 | 2.4708 | 0.216 | 4.4192 | 0.37062 | 2600 | 1290 | 4.4192 | 1590 | 4.4192 | 8.25 | 8.25 | 2450 | 2750 | 6FL | 一般性能 - 耐火性能: 3時間耐火構造
6FLW5 | 6FL | W5 | 6FLW5 | 男性用トイレ | ＜ゾーン番号＞ | yes | 6FL | 6 | リンクなし | リンクなし | リンクなし | インテリア | no | 5175 | 2650 | 0.77625 | 13.4775 | 13.4775 | 2.02162 | 2.02162 | 15000 | 13.4775 | 5175 | 2.46375 | 10650 | 17650 | 0 | 0 | 0 | 0 | 0 | 0 | 0 | 0 | 0 | 0 | 0.77625 | 13.4775 | 0 | 5325 | 5175 | 13.4775 | 5175 | 13.4775 | 16.425 | 16.425 | 5175 | 5175 | 6FL
6FLW4 | 6FL | W4 | 6FLW4 | 事務室 | 303 | yes | 6FL | 6 | リンクなし | リンクなし | リンクなし | インテリア | no | 5000 | 2650 | 0.486 | 11.13 | 9.0852 | 1.6695 | 1.36278 | 15000 | 9.0852 | 4200 | 2.25 | 10300 | 17650 | 1 | 0 | 2 | 0 | 2.22995 | 900 | 0 | 0 | 2.0448 | 2.0448 | 0.486 | 9.0852 | 0.30672 | 5000 | 4040 | 9.0852 | 4040 | 9.0852 | 15 | 15 | 5000 | 5000 | 6FL
6FLW1 | 6FL | W1 | 6FLW1 | 事務室 | 310 | yes | 6FL | 6 | リンクなし | リンクなし | リンクなし | インテリア | no | 4050 | 2300 | 0.51 | 7.82 | 7.82 | 1.173 | 1.173 | 15000 | 7.82 | 3400 | 1.89 | 8400 | 17300 | 0 | 0 | 1 | 0 | 0 | 0 | 0 | 0 | 0 | 0 | 0.855 | 7.82 | 0 | 4125 | 4050 | 7.82 | 4050 | 7.82 | 12.6 | 12.6 | 4050 | 4050 | 6FL
6FLW2 | 6FL | W2 | 6FLW2 | 事務室 | 310 | yes | 6FL | 6 | リンクなし | リンクなし | リンクなし | インテリア | no | 2600 | 2300 | 0.36375 | 5.5775 | 5.5775 | 0.836625 | 0.836625 | 15000 | 5.5775 | 2425 | 1.20375 | 5562.13 | 17300 | 0 | 0 | 0 | 0 | 0 | 0 | 0 | 0 | 0 | 0 | 0.70875 | 5.5775 | 0 | 2600 | 2675 | 5.5775 | 2525 | 5.5775 | 8.025 | 8.025 | 2675 | 2525 | 6FL | 一般性能 - 耐火性能: 3時間耐火構造
6FLW8 | 6FL | W8 | 6FLW8 | DS | ＜ゾーン番号＞ | yes | 6FL | 6 | リンクなし | リンクなし | リンクなし | インテリア | no | 8425 | 2650 | 1.2525 | 21.9525 | 21.9525 | 3.29287 | 3.29287 | 15000 | 21.9525 | 8350 | 3.8925 | 17212.1 | 17650 | 0 | 0 | 0 | 0 | 0 | 0 | 0 | 0 | 3.55271e-15 | 3.55271e-15 | 1.2525 | 21.9525 | 0 | 8500 | 8350 | 21.9525 | 8500 | 21.9525 | 25.95 | 25.95 | 8350 | 8500 | 6FL
6FLW7 | 6FL | W7 | 6FLW7 | EVシャフト | ＜ゾーン番号＞ | yes | 6FL | 6 | リンクなし | リンクなし | リンクなし | インテリア | no | 2250 | 2650 | 0.36 | 6.29875 | 6.29875 | 0.944813 | 0.944813 | 15000 | 6.29875 | 2400 | 1.08 | 4924.26 | 17650 | 0 | 0 | 0 | 0 | 0 | 0 | 0 | 0 | 0 | 0 | 0.36 | 6.29875 | 0 | 2250 | 2100 | 6.29875 | 2400 | 6.29875 | 7.2 | 7.2 | 2100 | 2400 | 6FL
6FLW5 | 6FL | W5 | 6FLW5 | 事務室 | 309 | yes | 6FL | 6 | リンクなし | リンクなし | リンクなし | インテリア | no | 6650 | 2650 | 0.88875 | 14.6644 | 14.6644 | 2.14781 | 2.14781 | 15000 | 15.7012 | 5925 | 3.09375 | 13662.1 | 17650 | 0 | 0 | 1 | 0 | 0 | 0 | 0 | 0 | 0 | 0 | 0.88875 | 13.6275 | 0 | 6725 | 6725 | 13.6275 | 6575 | 15.7012 | 20.625 | 20.625 | 6725 | 6575 | 6FL
6FLW7 | 6FL | W7 | 6FLW7 | 事務室 | 308 | yes | 6FL | 6 | リンクなし | リンクなし | リンクなし | インテリア | no | 9925 | 2650 | 1.212 | 26.15 | 22.0604 | 3.9225 | 3.30906 | 15000 | 22.0604 | 10000 | 4.6125 | 20212.1 | 17650 | 2 | 0 | 0 | 0 | 4.4599 | 1800 | 0 | 0 | 4.0896 | 4.0896 | 1.212 | 22.0604 | 0.61344 | 10050 | 7930 | 22.0604 | 8080 | 22.0604 | 30.75 | 30.75 | 9850 | 10000 | 6FL
6FLW3 | 6FL | W3 | 6FLW3 | 事務室 | 310 | yes | 6FL | 6 | リンクなし | リンクなし | リンクなし | インテリア | no | 10150 | 2650 | 1.22325 | 26.3225 | 22.2329 | 3.94838 | 3.33494 | 15000 | 22.2329 | 10075 | 4.71375 | 20662.1 | 17650 | 2 | 0 | 0 | 0 | 4.4599 | 1800 | 0 | 0 | 4.0896 | 4.0896 | 1.22325 | 22.2329 | 0.61344 | 10275 | 8155 | 22.2329 | 8305 | 22.2329 | 31.425 | 31.425 | 10075 | 10225 | 6FL
6FLW4 | 6FL | W4 | 6FLW4 | 女性用トイレ | ＜ゾーン番号＞ | yes | 6FL | 6 | リンクなし | リンクなし | リンクなし | インテリア | no | 5250 | 2650 | 0.79875 | 13.875 | 13.875 | 2.08125 | 2.08125 | 15000 | 13.875 | 5325 | 2.46375 | 10862.1 | 17650 | 0 | 0 | 0 | 0 | 0 | 0 | 0 | 0 | 0 | 0 | 0.79875 | 13.875 | 4.44089e-16 | 5325 | 5325 | 13.875 | 5175 | 13.875 | 16.425 | 16.425 | 5325 | 5175 | 6FL | 一般性能 - 耐火性能: 3時間耐火構造
6FLW8 | 6FL | W8 | 6FLW8 | PS | ＜ゾーン番号＞ | yes | 6FL | 6 | リンクなし | リンクなし | リンクなし | インテリア | no | 2675 | 2650 | 0.40125 | 6.94875 | 6.94875 | 1.04231 | 1.04231 | 15000 | 6.94875 | 2675 | 1.33875 | 5650 | 17650 | 0 | 0 | 0 | 0 | 0 | 0 | 0 | 0 | 0 | 0 | 0.40125 | 6.94875 | 2.22045e-16 | 2825 | 2675 | 6.94875 | 2675 | 6.94875 | 8.925 | 8.925 | 2675 | 2675 | 6FL
6FLW4 | 6FL | W4 | 6FLW4 | 事務室 | 301 | yes | 6FL | 6 | リンクなし | リンクなし | リンクなし | インテリア | no | 10150 | 2650 | 0.972 | 22.26 | 18.1704 | 3.339 | 2.72556 | 15000 | 18.1704 | 8400 | 4.68 | 20600 | 17650 | 2 | 0 | 3 | 0 | 4.4599 | 1800 | 0 | 0 | 4.0896 | 4.0896 | 0.972 | 18.1704 | 0.61344 | 10275 | 8230 | 18.1704 | 8230 | 18.1704 | 31.2 | 31.2 | 10150 | 10150 | 6FL
6FLW5 | 6FL | W5 | 6FLW5 | 事務室 | 304 | yes | 6FL | 6 | リンクなし | リンクなし | リンクなし | インテリア | no | 20150 | 2650 | 1.944 | 44.52 | 36.3408 | 6.678 | 5.45112 | 15000 | 36.3408 | 16800 | 9.18 | 40600 | 17650 | 4 | 0 | 5 | 0 | 8.9198 | 3600 | 0 | 0 | 8.1792 | 8.1792 | 1.944 | 36.3408 | 1.22688 | 20275 | 16310 | 36.3408 | 16310 | 36.3408 | 61.2 | 61.2 | 20150 | 20150 | 6FL
6FLW6 | 6FL | W6 | 6FLW6 | DS | ＜ゾーン番号＞ | yes | 6FL | 6 | リンクなし | リンクなし | リンクなし | インテリア | no | 5000 | 2650 | 0.6075 | 10.7325 | 10.7325 | 1.60987 | 1.60987 | 15000 | 10.7325 | 4050 | 2.39625 | 10362.1 | 17650 | 0 | 0 | 2 | 0 | 0 | 0 | 0 | 0 | 0 | 0 | 0.6075 | 10.7325 | 0 | 5125 | 5075 | 10.7325 | 4925 | 10.7325 | 15.975 | 15.975 | 5075 | 4925 | 6FL
6FLW8 | 6FL | W8 | 6FLW8 | EVホール | ＜ゾーン番号＞ | yes | 6FL | 6 | リンクなし | リンクなし | リンクなし | インテリア | no | 5325 | 2650 | 0.63 | 11.13 | 11.13 | 1.6695 | 1.6695 | 15000 | 11.13 | 4200 | 2.43 | 11012.1 | 17650 | 0 | 0 | 2 | 0 | 0 | 0 | 0 | 0 | 0 | 0 | 0.63 | 11.13 | 0 | 5325 | 5250 | 11.13 | 5400 | 11.13 | 16.2 | 16.2 | 5250 | 5400 | 6FL
6FLW9 | 6FL | W9 | 6FLW9 | 事務室 | 310 | yes | 6FL | 6 | リンクなし | リンクなし | リンクなし | インテリア | no | 5000 | 2650 | 0.63 | 11.13 | 11.13 | 1.6695 | 1.6695 | 15000 | 11.13 | 4200 | 2.25 | 10300 | 17650 | 0 | 0 | 2 | 0 | 0 | 0 | 0 | 0 | 0 | 0 | 0.63 | 11.13 | 0 | 5000 | 5000 | 11.13 | 5000 | 11.13 | 15 | 15 | 5000 | 5000 | 6FL
6FLW0 | 6FL | W0 | 6FLW0 | 事務室 | 311 | yes | 6FL | 6 | リンクなし | リンクなし | リンクなし | インテリア | no | 5400 | 2650 | 0.63 | 11.13 | 11.13 | 1.6695 | 1.6695 | 15000 | 11.13 | 4200 | 2.43 | 11100 | 17650 | 0 | 0 | 2 | 0 | 0 | 0 | 0 | 0 | 0 | 0 | 0.63 | 11.13 | 0 | 5400 | 5400 | 11.13 | 5400 | 11.13 | 16.2 | 16.2 | 5400 | 5400 | 6FL
6FLW8 | 6FL | W8 | 6FLW8 | EVホール | ＜ゾーン番号＞ | yes | 6FL | 6 | リンクなし | リンクなし | リンクなし | インテリア | no | 2675 | 2650 | 0.20475 | 6.94875 | 3.27982 | 1.04231 | 0.623767 | 15000 | 4.47795 | 2675 | 1.33875 | 5650 | 17650 | 1 | 0 | 0 | 0 | 2.58 | 1100 | 0 | 0 | 4.86705 | 2.4708 | 0.20475 | 2.0817 | 0.418545 | 2825 | 390 | 2.0817 | 1515 | 4.47795 | 8.925 | 8.925 | 2675 | 2675 | 6FL
6FLW3 | 6FL | W3 | 6FLW3 | EVホール | ＜ゾーン番号＞ | yes | 6FL | 6 | リンクなし | リンクなし | リンクなし | インテリア | no | 5250 | 2650 | 0.77625 | 13.4775 | 13.4775 | 2.02162 | 2.02162 | 15000 | 13.4775 | 5175 | 2.50875 | 10862.1 | 17650 | 0 | 0 | 0 | 0 | 0 | 0 | 0 | 0 | 0 | 0 | 0.77625 | 13.4775 | 3.9968e-15 | 5325 | 5175 | 13.4775 | 5325 | 13.4775 | 16.725 | 16.725 | 5175 | 5325 | 6FL | 一般性能 - 耐火性能: 3時間耐火構造
6FLW9 | 6FL | W9 | 6FLW9 | EVホール | ＜ゾーン番号＞ | yes | 6FL | 6 | リンクなし | リンクなし | リンクなし | インテリア | no | 1700 | 2300 | 0.00974999 | 3.7375 | 0.4147 | 0.560625 | 0.062205 | 15000 | 0.4147 | 1625 | 0.86625 | 3762.13 | 17300 | 1 | 0 | 1 | 0 | 3.52895 | 1500 | 0 | 0 | 3.3228 | 3.3228 | 0.00974999 | 0.4147 | 0.49842 | 1775 | 65 | 0.4147 | 215 | 0.4147 | 5.775 | 5.775 | 1625 | 1775 | 6FL
6FLW6 | 6FL | W6 | 6FLW6 | EVシャフト | ＜ゾーン番号＞ | yes | 6FL | 6 | リンクなし | リンクなし | リンクなし | インテリア | no | 6725 | 2300 | 0.41175 | 13.6275 | 6.8541 | 2.04413 | 1.02811 | 15000 | 6.8541 | 5925 | 3.09375 | 13874.3 | 17300 | 3 | 0 | 1 | 0 | 8.9445 | 3000 | 0 | 0 | 6.7734 | 6.7734 | 0.41175 | 6.8541 | 1.01601 | 6725 | 3695 | 6.8541 | 3395 | 6.8541 | 20.625 | 20.625 | 6875 | 6575 | 6FL
6FLW4 | 6FL | W4 | 6FLW4 | EVホール | ＜ゾーン番号＞ | yes | 6FL | 6 | リンクなし | リンクなし | リンクなし | インテリア | no | 1625 | 2300 | 0.04725 | 4.3125 | 0.9897 | 0.646875 | 0.148455 | 15000 | 0.9897 | 1875 | 0.91125 | 3550 | 17300 | 1 | 0 | 1 | 0 | 3.52895 | 1500 | 0 | 0 | 3.3228 | 3.3228 | 0.39225 | 0.9897 | 0.49842 | 1775 | 65 | 0.9897 | 65 | 0.9897 | 6.075 | 6.075 | 1625 | 1625 | 6FL
6FLW4 | 6FL | W4 | 6FLW4 | EVホール | ＜ゾーン番号＞ | yes | 6FL | 6 | リンクなし | リンクなし | リンクなし | インテリア | no | 4050 | 2650 | 0.27075 | 8.81125 | 5.57365 | 1.32169 | 0.836048 | 15000 | 5.57365 | 3325 | 1.96875 | 8462.13 | 17650 | 2 | 0 | 1 | 0 | 3.5939 | 1400 | 0 | 0 | 3.2376 | 3.2376 | 0.27075 | 5.57365 | 0.48564 | 4125 | 2455 | 8.81125 | 2605 | 8.81125 | 13.125 | 13.125 | 3975 | 4125 | 6FL
7FLW9 | 7FL | W9 | 7FLW9 | 事務室 | 313 | yes | 7FL | 7 | リンクなし | リンクなし | リンクなし | インテリア | no | 20150 | 2650 | 2.45775 | 52.8175 | 44.6383 | 7.92263 | 6.69575 | 18000 | 44.6383 | 20225 | 9.21375 | 40662.1 | 20650 | 4 | 0 | 0 | 0 | 8.9198 | 3600 | 0 | 0 | 8.1792 | 8.1792 | 2.45775 | 44.6383 | 1.22688 | 20275 | 16235 | 44.6383 | 16385 | 44.6383 | 61.425 | 61.425 | 20075 | 20225 | 7FL
7FLW8 | 7FL | W8 | 7FLW8 | DS | ＜ゾーン番号＞ | yes | 7FL | 7 | リンクなし | リンクなし | リンクなし | インテリア | no | 2100 | 2650 | 0.28875 | 5.10125 | 5.10125 | 0.765188 | 0.765188 | 18000 | 5.10125 | 1925 | 1.08 | 4500 | 20650 | 0 | 0 | 1 | 0 | 0 | 0 | 0 | 0 | 0 | 0 | 0.28875 | 5.10125 | 0 | 2250 | 2100 | 5.10125 | 2100 | 5.10125 | 7.2 | 7.2 | 2100 | 2100 | 7FL
7FLW4 | 7FL | W4 | 7FLW4 | EVホール | ＜ゾーン番号＞ | yes | 7FL | 7 | リンクなし | リンクなし | リンクなし | インテリア | no | 2600 | 2650 | 0.216 | 6.89 | 4.4192 | 1.0335 | 0.66288 | 18000 | 4.4192 | 2600 | 1.2375 | 5624.26 | 20650 | 1 | 0 | 0 | 0 | 2.66295 | 1100 | 0 | 0 | 2.4708 | 2.4708 | 0.216 | 4.4192 | 0.37062 | 2600 | 1290 | 4.4192 | 1590 | 4.4192 | 8.25 | 8.25 | 2450 | 2750 | 7FL | 一般性能 - 耐火性能: 3時間耐火構造
7FLW5 | 7FL | W5 | 7FLW5 | 男性用トイレ | ＜ゾーン番号＞ | yes | 7FL | 7 | リンクなし | リンクなし | リンクなし | インテリア | no | 5175 | 2650 | 0.77625 | 13.4775 | 13.4775 | 2.02162 | 2.02162 | 18000 | 13.4775 | 5175 | 2.46375 | 10650 | 20650 | 0 | 0 | 0 | 0 | 0 | 0 | 0 | 0 | 0 | 0 | 0.77625 | 13.4775 | 0 | 5325 | 5175 | 13.4775 | 5175 | 13.4775 | 16.425 | 16.425 | 5175 | 5175 | 7FL
7FLW4 | 7FL | W4 | 7FLW4 | 事務室 | 303 | yes | 7FL | 7 | リンクなし | リンクなし | リンクなし | インテリア | no | 5000 | 2650 | 0.486 | 11.13 | 9.0852 | 1.6695 | 1.36278 | 18000 | 9.0852 | 4200 | 2.25 | 10300 | 20650 | 1 | 0 | 2 | 0 | 2.22995 | 900 | 0 | 0 | 2.0448 | 2.0448 | 0.486 | 9.0852 | 0.30672 | 5000 | 4040 | 9.0852 | 4040 | 9.0852 | 15 | 15 | 5000 | 5000 | 7FL
7FLW1 | 7FL | W1 | 7FLW1 | 事務室 | 310 | yes | 7FL | 7 | リンクなし | リンクなし | リンクなし | インテリア | no | 4050 | 2300 | 0.51 | 7.82 | 7.82 | 1.173 | 1.173 | 18000 | 7.82 | 3400 | 1.89 | 8400 | 20300 | 0 | 0 | 1 | 0 | 0 | 0 | 0 | 0 | 0 | 0 | 0.855 | 7.82 | 0 | 4125 | 4050 | 7.82 | 4050 | 7.82 | 12.6 | 12.6 | 4050 | 4050 | 7FL
7FLW2 | 7FL | W2 | 7FLW2 | 事務室 | 310 | yes | 7FL | 7 | リンクなし | リンクなし | リンクなし | インテリア | no | 2600 | 2300 | 0.36375 | 5.5775 | 5.5775 | 0.836625 | 0.836625 | 18000 | 5.5775 | 2425 | 1.20375 | 5562.13 | 20300 | 0 | 0 | 0 | 0 | 0 | 0 | 0 | 0 | 0 | 0 | 0.70875 | 5.5775 | 0 | 2600 | 2675 | 5.5775 | 2525 | 5.5775 | 8.025 | 8.025 | 2675 | 2525 | 7FL | 一般性能 - 耐火性能: 3時間耐火構造
7FLW8 | 7FL | W8 | 7FLW8 | DS | ＜ゾーン番号＞ | yes | 7FL | 7 | リンクなし | リンクなし | リンクなし | インテリア | no | 8425 | 2650 | 1.2525 | 21.9525 | 21.9525 | 3.29287 | 3.29287 | 18000 | 21.9525 | 8350 | 3.8925 | 17212.1 | 20650 | 0 | 0 | 0 | 0 | 0 | 0 | 0 | 0 | 3.55271e-15 | 3.55271e-15 | 1.2525 | 21.9525 | 0 | 8500 | 8350 | 21.9525 | 8500 | 21.9525 | 25.95 | 25.95 | 8350 | 8500 | 7FL
7FLW7 | 7FL | W7 | 7FLW7 | EVシャフト | ＜ゾーン番号＞ | yes | 7FL | 7 | リンクなし | リンクなし | リンクなし | インテリア | no | 2250 | 2650 | 0.36 | 6.29875 | 6.29875 | 0.944813 | 0.944813 | 18000 | 6.29875 | 2400 | 1.08 | 4924.26 | 20650 | 0 | 0 | 0 | 0 | 0 | 0 | 0 | 0 | 0 | 0 | 0.36 | 6.29875 | 0 | 2250 | 2100 | 6.29875 | 2400 | 6.29875 | 7.2 | 7.2 | 2100 | 2400 | 7FL
7FLW5 | 7FL | W5 | 7FLW5 | 事務室 | 309 | yes | 7FL | 7 | リンクなし | リンクなし | リンクなし | インテリア | no | 6650 | 2650 | 0.88875 | 14.6644 | 14.6644 | 2.14781 | 2.14781 | 18000 | 15.7012 | 5925 | 3.09375 | 13662.1 | 20650 | 0 | 0 | 1 | 0 | 0 | 0 | 0 | 0 | 0 | 0 | 0.88875 | 13.6275 | 0 | 6725 | 6725 | 13.6275 | 6575 | 15.7012 | 20.625 | 20.625 | 6725 | 6575 | 7FL
7FLW7 | 7FL | W7 | 7FLW7 | 事務室 | 308 | yes | 7FL | 7 | リンクなし | リンクなし | リンクなし | インテリア | no | 9925 | 2650 | 1.212 | 26.15 | 22.0604 | 3.9225 | 3.30906 | 18000 | 22.0604 | 10000 | 4.6125 | 20212.1 | 20650 | 2 | 0 | 0 | 0 | 4.4599 | 1800 | 0 | 0 | 4.0896 | 4.0896 | 1.212 | 22.0604 | 0.61344 | 10050 | 7930 | 22.0604 | 8080 | 22.0604 | 30.75 | 30.75 | 9850 | 10000 | 7FL
7FLW3 | 7FL | W3 | 7FLW3 | 事務室 | 310 | yes | 7FL | 7 | リンクなし | リンクなし | リンクなし | インテリア | no | 10150 | 2650 | 1.22325 | 26.3225 | 22.2329 | 3.94838 | 3.33494 | 18000 | 22.2329 | 10075 | 4.71375 | 20662.1 | 20650 | 2 | 0 | 0 | 0 | 4.4599 | 1800 | 0 | 0 | 4.0896 | 4.0896 | 1.22325 | 22.2329 | 0.61344 | 10275 | 8155 | 22.2329 | 8305 | 22.2329 | 31.425 | 31.425 | 10075 | 10225 | 7FL
7FLW4 | 7FL | W4 | 7FLW4 | 女性用トイレ | ＜ゾーン番号＞ | yes | 7FL | 7 | リンクなし | リンクなし | リンクなし | インテリア | no | 5250 | 2650 | 0.79875 | 13.875 | 13.875 | 2.08125 | 2.08125 | 18000 | 13.875 | 5325 | 2.46375 | 10862.1 | 20650 | 0 | 0 | 0 | 0 | 0 | 0 | 0 | 0 | 0 | 0 | 0.79875 | 13.875 | 4.44089e-16 | 5325 | 5325 | 13.875 | 5175 | 13.875 | 16.425 | 16.425 | 5325 | 5175 | 7FL | 一般性能 - 耐火性能: 3時間耐火構造
7FLW8 | 7FL | W8 | 7FLW8 | PS | ＜ゾーン番号＞ | yes | 7FL | 7 | リンクなし | リンクなし | リンクなし | インテリア | no | 2675 | 2650 | 0.40125 | 6.94875 | 6.94875 | 1.04231 | 1.04231 | 18000 | 6.94875 | 2675 | 1.33875 | 5650 | 20650 | 0 | 0 | 0 | 0 | 0 | 0 | 0 | 0 | 0 | 0 | 0.40125 | 6.94875 | 2.22045e-16 | 2825 | 2675 | 6.94875 | 2675 | 6.94875 | 8.925 | 8.925 | 2675 | 2675 | 7FL
7FLW4 | 7FL | W4 | 7FLW4 | 事務室 | 301 | yes | 7FL | 7 | リンクなし | リンクなし | リンクなし | インテリア | no | 10150 | 2650 | 0.972 | 22.26 | 18.1704 | 3.339 | 2.72556 | 18000 | 18.1704 | 8400 | 4.68 | 20600 | 20650 | 2 | 0 | 3 | 0 | 4.4599 | 1800 | 0 | 0 | 4.0896 | 4.0896 | 0.972 | 18.1704 | 0.61344 | 10275 | 8230 | 18.1704 | 8230 | 18.1704 | 31.2 | 31.2 | 10150 | 10150 | 7FL
7FLW5 | 7FL | W5 | 7FLW5 | 事務室 | 304 | yes | 7FL | 7 | リンクなし | リンクなし | リンクなし | インテリア | no | 20150 | 2650 | 1.944 | 44.52 | 36.3408 | 6.678 | 5.45112 | 18000 | 36.3408 | 16800 | 9.18 | 40600 | 20650 | 4 | 0 | 5 | 0 | 8.9198 | 3600 | 0 | 0 | 8.1792 | 8.1792 | 1.944 | 36.3408 | 1.22688 | 20275 | 16310 | 36.3408 | 16310 | 36.3408 | 61.2 | 61.2 | 20150 | 20150 | 7FL
7FLW6 | 7FL | W6 | 7FLW6 | DS | ＜ゾーン番号＞ | yes | 7FL | 7 | リンクなし | リンクなし | リンクなし | インテリア | no | 5000 | 2650 | 0.6075 | 10.7325 | 10.7325 | 1.60987 | 1.60987 | 18000 | 10.7325 | 4050 | 2.39625 | 10362.1 | 20650 | 0 | 0 | 2 | 0 | 0 | 0 | 0 | 0 | 0 | 0 | 0.6075 | 10.7325 | 0 | 5125 | 5075 | 10.7325 | 4925 | 10.7325 | 15.975 | 15.975 | 5075 | 4925 | 7FL
7FLW8 | 7FL | W8 | 7FLW8 | EVホール | ＜ゾーン番号＞ | yes | 7FL | 7 | リンクなし | リンクなし | リンクなし | インテリア | no | 5325 | 2650 | 0.63 | 11.13 | 11.13 | 1.6695 | 1.6695 | 18000 | 11.13 | 4200 | 2.43 | 11012.1 | 20650 | 0 | 0 | 2 | 0 | 0 | 0 | 0 | 0 | 0 | 0 | 0.63 | 11.13 | 0 | 5325 | 5250 | 11.13 | 5400 | 11.13 | 16.2 | 16.2 | 5250 | 5400 | 7FL
7FLW9 | 7FL | W9 | 7FLW9 | 事務室 | 310 | yes | 7FL | 7 | リンクなし | リンクなし | リンクなし | インテリア | no | 5000 | 2650 | 0.63 | 11.13 | 11.13 | 1.6695 | 1.6695 | 18000 | 11.13 | 4200 | 2.25 | 10300 | 20650 | 0 | 0 | 2 | 0 | 0 | 0 | 0 | 0 | 0 | 0 | 0.63 | 11.13 | 0 | 5000 | 5000 | 11.13 | 5000 | 11.13 | 15 | 15 | 5000 | 5000 | 7FL
7FLW0 | 7FL | W0 | 7FLW0 | 事務室 | 311 | yes | 7FL | 7 | リンクなし | リンクなし | リンクなし | インテリア | no | 5400 | 2650 | 0.63 | 11.13 | 11.13 | 1.6695 | 1.6695 | 18000 | 11.13 | 4200 | 2.43 | 11100 | 20650 | 0 | 0 | 2 | 0 | 0 | 0 | 0 | 0 | 0 | 0 | 0.63 | 11.13 | 0 | 5400 | 5400 | 11.13 | 5400 | 11.13 | 16.2 | 16.2 | 5400 | 5400 | 7FL
7FLW8 | 7FL | W8 | 7FLW8 | EVホール | ＜ゾーン番号＞ | yes | 7FL | 7 | リンクなし | リンクなし | リンクなし | インテリア | no | 2675 | 2650 | 0.20475 | 6.94875 | 3.27982 | 1.04231 | 0.623767 | 18000 | 4.47795 | 2675 | 1.33875 | 5650 | 20650 | 1 | 0 | 0 | 0 | 2.58 | 1100 | 0 | 0 | 4.86705 | 2.4708 | 0.20475 | 2.0817 | 0.418545 | 2825 | 390 | 2.0817 | 1515 | 4.47795 | 8.925 | 8.925 | 2675 | 2675 | 7FL
7FLW3 | 7FL | W3 | 7FLW3 | EVホール | ＜ゾーン番号＞ | yes | 7FL | 7 | リンクなし | リンクなし | リンクなし | インテリア | no | 5250 | 2650 | 0.77625 | 13.4775 | 13.4775 | 2.02162 | 2.02162 | 18000 | 13.4775 | 5175 | 2.50875 | 10862.1 | 20650 | 0 | 0 | 0 | 0 | 0 | 0 | 0 | 0 | 0 | 0 | 0.77625 | 13.4775 | 3.9968e-15 | 5325 | 5175 | 13.4775 | 5325 | 13.4775 | 16.725 | 16.725 | 5175 | 5325 | 7FL | 一般性能 - 耐火性能: 3時間耐火構造
7FLW9 | 7FL | W9 | 7FLW9 | EVホール | ＜ゾーン番号＞ | yes | 7FL | 7 | リンクなし | リンクなし | リンクなし | インテリア | no | 1700 | 2300 | 0.00974999 | 3.7375 | 0.4147 | 0.560625 | 0.062205 | 18000 | 0.4147 | 1625 | 0.86625 | 3762.13 | 20300 | 1 | 0 | 1 | 0 | 3.52895 | 1500 | 0 | 0 | 3.3228 | 3.3228 | 0.00974999 | 0.4147 | 0.49842 | 1775 | 65 | 0.4147 | 215 | 0.4147 | 5.775 | 5.775 | 1625 | 1775 | 7FL
7FLW6 | 7FL | W6 | 7FLW6 | EVシャフト | ＜ゾーン番号＞ | yes | 7FL | 7 | リンクなし | リンクなし | リンクなし | インテリア | no | 6725 | 2300 | 0.41175 | 13.6275 | 6.8541 | 2.04413 | 1.02811 | 18000 | 6.8541 | 5925 | 3.09375 | 13874.3 | 20300 | 3 | 0 | 1 | 0 | 8.9445 | 3000 | 0 | 0 | 6.7734 | 6.7734 | 0.41175 | 6.8541 | 1.01601 | 6725 | 3695 | 6.8541 | 3395 | 6.8541 | 20.625 | 20.625 | 6875 | 6575 | 7FL
7FLW4 | 7FL | W4 | 7FLW4 | EVホール | ＜ゾーン番号＞ | yes | 7FL | 7 | リンクなし | リンクなし | リンクなし | インテリア | no | 1625 | 2300 | 0.04725 | 4.3125 | 0.9897 | 0.646875 | 0.148455 | 18000 | 0.9897 | 1875 | 0.91125 | 3550 | 20300 | 1 | 0 | 1 | 0 | 3.52895 | 1500 | 0 | 0 | 3.3228 | 3.3228 | 0.39225 | 0.9897 | 0.49842 | 1775 | 65 | 0.9897 | 65 | 0.9897 | 6.075 | 6.075 | 1625 | 1625 | 7FL
7FLW4 | 7FL | W4 | 7FLW4 | EVホール | ＜ゾーン番号＞ | yes | 7FL | 7 | リンクなし | リンクなし | リンクなし | インテリア | no | 4050 | 2650 | 0.27075 | 8.81125 | 5.57365 | 1.32169 | 0.836048 | 18000 | 5.57365 | 3325 | 1.96875 | 8462.13 | 20650 | 2 | 0 | 1 | 0 | 3.5939 | 1400 | 0 | 0 | 3.2376 | 3.2376 | 0.27075 | 5.57365 | 0.48564 | 4125 | 2455 | 8.81125 | 2605 | 8.81125 | 13.125 | 13.125 | 3975 | 4125 | 7FL
8FLW9 | 8FL | W9 | 8FLW9 | 事務室 | 313 | yes | 8FL | 8 | リンクなし | リンクなし | リンクなし | インテリア | no | 20150 | 2650 | 2.45775 | 52.8175 | 44.6383 | 7.92263 | 6.69575 | 21000 | 44.6383 | 20225 | 9.21375 | 40662.1 | 23650 | 4 | 0 | 0 | 0 | 8.9198 | 3600 | 0 | 0 | 8.1792 | 8.1792 | 2.45775 | 44.6383 | 1.22688 | 20275 | 16235 | 44.6383 | 16385 | 44.6383 | 61.425 | 61.425 | 20075 | 20225 | 8FL
8FLW8 | 8FL | W8 | 8FLW8 | DS | ＜ゾーン番号＞ | yes | 8FL | 8 | リンクなし | リンクなし | リンクなし | インテリア | no | 2100 | 2650 | 0.28875 | 5.10125 | 5.10125 | 0.765188 | 0.765188 | 21000 | 5.10125 | 1925 | 1.08 | 4500 | 23650 | 0 | 0 | 1 | 0 | 0 | 0 | 0 | 0 | 0 | 0 | 0.28875 | 5.10125 | 0 | 2250 | 2100 | 5.10125 | 2100 | 5.10125 | 7.2 | 7.2 | 2100 | 2100 | 8FL
8FLW4 | 8FL | W4 | 8FLW4 | EVホール | ＜ゾーン番号＞ | yes | 8FL | 8 | リンクなし | リンクなし | リンクなし | インテリア | no | 2600 | 2650 | 0.216 | 6.89 | 4.4192 | 1.0335 | 0.66288 | 21000 | 4.4192 | 2600 | 1.2375 | 5624.26 | 23650 | 1 | 0 | 0 | 0 | 2.66295 | 1100 | 0 | 0 | 2.4708 | 2.4708 | 0.216 | 4.4192 | 0.37062 | 2600 | 1290 | 4.4192 | 1590 | 4.4192 | 8.25 | 8.25 | 2450 | 2750 | 8FL | 一般性能 - 耐火性能: 3時間耐火構造
8FLW5 | 8FL | W5 | 8FLW5 | 男性用トイレ | ＜ゾーン番号＞ | yes | 8FL | 8 | リンクなし | リンクなし | リンクなし | インテリア | no | 5175 | 2650 | 0.77625 | 13.4775 | 13.4775 | 2.02162 | 2.02162 | 21000 | 13.4775 | 5175 | 2.46375 | 10650 | 23650 | 0 | 0 | 0 | 0 | 0 | 0 | 0 | 0 | 0 | 0 | 0.77625 | 13.4775 | 0 | 5325 | 5175 | 13.4775 | 5175 | 13.4775 | 16.425 | 16.425 | 5175 | 5175 | 8FL
8FLW4 | 8FL | W4 | 8FLW4 | 事務室 | 303 | yes | 8FL | 8 | リンクなし | リンクなし | リンクなし | インテリア | no | 5000 | 2650 | 0.486 | 11.13 | 9.0852 | 1.6695 | 1.36278 | 21000 | 9.0852 | 4200 | 2.25 | 10300 | 23650 | 1 | 0 | 2 | 0 | 2.22995 | 900 | 0 | 0 | 2.0448 | 2.0448 | 0.486 | 9.0852 | 0.30672 | 5000 | 4040 | 9.0852 | 4040 | 9.0852 | 15 | 15 | 5000 | 5000 | 8FL
8FLW1 | 8FL | W1 | 8FLW1 | 事務室 | 310 | yes | 8FL | 8 | リンクなし | リンクなし | リンクなし | インテリア | no | 4050 | 2300 | 0.51 | 7.82 | 7.82 | 1.173 | 1.173 | 21000 | 7.82 | 3400 | 1.89 | 8400 | 23300 | 0 | 0 | 1 | 0 | 0 | 0 | 0 | 0 | 0 | 0 | 0.855 | 7.82 | 0 | 4125 | 4050 | 7.82 | 4050 | 7.82 | 12.6 | 12.6 | 4050 | 4050 | 8FL
8FLW2 | 8FL | W2 | 8FLW2 | 事務室 | 310 | yes | 8FL | 8 | リンクなし | リンクなし | リンクなし | インテリア | no | 2600 | 2300 | 0.36375 | 5.5775 | 5.5775 | 0.836625 | 0.836625 | 21000 | 5.5775 | 2425 | 1.20375 | 5562.13 | 23300 | 0 | 0 | 0 | 0 | 0 | 0 | 0 | 0 | 0 | 0 | 0.70875 | 5.5775 | 0 | 2600 | 2675 | 5.5775 | 2525 | 5.5775 | 8.025 | 8.025 | 2675 | 2525 | 8FL | 一般性能 - 耐火性能: 3時間耐火構造
8FLW8 | 8FL | W8 | 8FLW8 | DS | ＜ゾーン番号＞ | yes | 8FL | 8 | リンクなし | リンクなし | リンクなし | インテリア | no | 8425 | 2650 | 1.2525 | 21.9525 | 21.9525 | 3.29287 | 3.29287 | 21000 | 21.9525 | 8350 | 3.8925 | 17212.1 | 23650 | 0 | 0 | 0 | 0 | 0 | 0 | 0 | 0 | 3.55271e-15 | 3.55271e-15 | 1.2525 | 21.9525 | 0 | 8500 | 8350 | 21.9525 | 8500 | 21.9525 | 25.95 | 25.95 | 8350 | 8500 | 8FL
8FLW7 | 8FL | W7 | 8FLW7 | EVシャフト | ＜ゾーン番号＞ | yes | 8FL | 8 | リンクなし | リンクなし | リンクなし | インテリア | no | 2250 | 2650 | 0.36 | 6.29875 | 6.29875 | 0.944813 | 0.944813 | 21000 | 6.29875 | 2400 | 1.08 | 4924.26 | 23650 | 0 | 0 | 0 | 0 | 0 | 0 | 0 | 0 | 0 | 0 | 0.36 | 6.29875 | 0 | 2250 | 2100 | 6.29875 | 2400 | 6.29875 | 7.2 | 7.2 | 2100 | 2400 | 8FL
8FLW5 | 8FL | W5 | 8FLW5 | 事務室 | 309 | yes | 8FL | 8 | リンクなし | リンクなし | リンクなし | インテリア | no | 6650 | 2650 | 0.88875 | 14.6644 | 14.6644 | 2.14781 | 2.14781 | 21000 | 15.7012 | 5925 | 3.09375 | 13662.1 | 23650 | 0 | 0 | 1 | 0 | 0 | 0 | 0 | 0 | 0 | 0 | 0.88875 | 13.6275 | 0 | 6725 | 6725 | 13.6275 | 6575 | 15.7012 | 20.625 | 20.625 | 6725 | 6575 | 8FL
8FLW7 | 8FL | W7 | 8FLW7 | 事務室 | 308 | yes | 8FL | 8 | リンクなし | リンクなし | リンクなし | インテリア | no | 9925 | 2650 | 1.212 | 26.15 | 22.0604 | 3.9225 | 3.30906 | 21000 | 22.0604 | 10000 | 4.6125 | 20212.1 | 23650 | 2 | 0 | 0 | 0 | 4.4599 | 1800 | 0 | 0 | 4.0896 | 4.0896 | 1.212 | 22.0604 | 0.61344 | 10050 | 7930 | 22.0604 | 8080 | 22.0604 | 30.75 | 30.75 | 9850 | 10000 | 8FL
8FLW3 | 8FL | W3 | 8FLW3 | 事務室 | 310 | yes | 8FL | 8 | リンクなし | リンクなし | リンクなし | インテリア | no | 10150 | 2650 | 1.22325 | 26.3225 | 22.2329 | 3.94838 | 3.33494 | 21000 | 22.2329 | 10075 | 4.71375 | 20662.1 | 23650 | 2 | 0 | 0 | 0 | 4.4599 | 1800 | 0 | 0 | 4.0896 | 4.0896 | 1.22325 | 22.2329 | 0.61344 | 10275 | 8155 | 22.2329 | 8305 | 22.2329 | 31.425 | 31.425 | 10075 | 10225 | 8FL
8FLW4 | 8FL | W4 | 8FLW4 | 女性用トイレ | ＜ゾーン番号＞ | yes | 8FL | 8 | リンクなし | リンクなし | リンクなし | インテリア | no | 5250 | 2650 | 0.79875 | 13.875 | 13.875 | 2.08125 | 2.08125 | 21000 | 13.875 | 5325 | 2.46375 | 10862.1 | 23650 | 0 | 0 | 0 | 0 | 0 | 0 | 0 | 0 | 0 | 0 | 0.79875 | 13.875 | 0 | 5325 | 5325 | 13.875 | 5175 | 13.875 | 16.425 | 16.425 | 5325 | 5175 | 8FL | 一般性能 - 耐火性能: 3時間耐火構造
8FLW8 | 8FL | W8 | 8FLW8 | PS | ＜ゾーン番号＞ | yes | 8FL | 8 | リンクなし | リンクなし | リンクなし | インテリア | no | 2675 | 2650 | 0.40125 | 6.94875 | 6.94875 | 1.04231 | 1.04231 | 21000 | 6.94875 | 2675 | 1.33875 | 5650 | 23650 | 0 | 0 | 0 | 0 | 0 | 0 | 0 | 0 | 0 | 0 | 0.40125 | 6.94875 | 2.22045e-16 | 2825 | 2675 | 6.94875 | 2675 | 6.94875 | 8.925 | 8.925 | 2675 | 2675 | 8FL
8FLW4 | 8FL | W4 | 8FLW4 | 事務室 | 301 | yes | 8FL | 8 | リンクなし | リンクなし | リンクなし | インテリア | no | 10150 | 2650 | 0.972 | 22.26 | 18.1704 | 3.339 | 2.72556 | 21000 | 18.1704 | 8400 | 4.68 | 20600 | 23650 | 2 | 0 | 3 | 0 | 4.4599 | 1800 | 0 | 0 | 4.0896 | 4.0896 | 0.972 | 18.1704 | 0.61344 | 10275 | 8230 | 18.1704 | 8230 | 18.1704 | 31.2 | 31.2 | 10150 | 10150 | 8FL
8FLW5 | 8FL | W5 | 8FLW5 | 事務室 | 304 | yes | 8FL | 8 | リンクなし | リンクなし | リンクなし | インテリア | no | 20150 | 2650 | 1.944 | 44.52 | 36.3408 | 6.678 | 5.45112 | 21000 | 36.3408 | 16800 | 9.18 | 40600 | 23650 | 4 | 0 | 5 | 0 | 8.9198 | 3600 | 0 | 0 | 8.1792 | 8.1792 | 1.944 | 36.3408 | 1.22688 | 20275 | 16310 | 36.3408 | 16310 | 36.3408 | 61.2 | 61.2 | 20150 | 20150 | 8FL
8FLW6 | 8FL | W6 | 8FLW6 | DS | ＜ゾーン番号＞ | yes | 8FL | 8 | リンクなし | リンクなし | リンクなし | インテリア | no | 5000 | 2650 | 0.6075 | 10.7325 | 10.7325 | 1.60987 | 1.60987 | 21000 | 10.7325 | 4050 | 2.39625 | 10362.1 | 23650 | 0 | 0 | 2 | 0 | 0 | 0 | 0 | 0 | 0 | 0 | 0.6075 | 10.7325 | 0 | 5125 | 5075 | 10.7325 | 4925 | 10.7325 | 15.975 | 15.975 | 5075 | 4925 | 8FL
8FLW8 | 8FL | W8 | 8FLW8 | EVホール | ＜ゾーン番号＞ | yes | 8FL | 8 | リンクなし | リンクなし | リンクなし | インテリア | no | 5325 | 2650 | 0.63 | 11.13 | 11.13 | 1.6695 | 1.6695 | 21000 | 11.13 | 4200 | 2.43 | 11012.1 | 23650 | 0 | 0 | 2 | 0 | 0 | 0 | 0 | 0 | 0 | 0 | 0.63 | 11.13 | 0 | 5325 | 5250 | 11.13 | 5400 | 11.13 | 16.2 | 16.2 | 5250 | 5400 | 8FL
8FLW9 | 8FL | W9 | 8FLW9 | 事務室 | 310 | yes | 8FL | 8 | リンクなし | リンクなし | リンクなし | インテリア | no | 5000 | 2650 | 0.63 | 11.13 | 11.13 | 1.6695 | 1.6695 | 21000 | 11.13 | 4200 | 2.25 | 10300 | 23650 | 0 | 0 | 2 | 0 | 0 | 0 | 0 | 0 | 0 | 0 | 0.63 | 11.13 | 0 | 5000 | 5000 | 11.13 | 5000 | 11.13 | 15 | 15 | 5000 | 5000 | 8FL
8FLW0 | 8FL | W0 | 8FLW0 | 事務室 | 311 | yes | 8FL | 8 | リンクなし | リンクなし | リンクなし | インテリア | no | 5400 | 2650 | 0.63 | 11.13 | 11.13 | 1.6695 | 1.6695 | 21000 | 11.13 | 4200 | 2.43 | 11100 | 23650 | 0 | 0 | 2 | 0 | 0 | 0 | 0 | 0 | 0 | 0 | 0.63 | 11.13 | 0 | 5400 | 5400 | 11.13 | 5400 | 11.13 | 16.2 | 16.2 | 5400 | 5400 | 8FL
8FLW8 | 8FL | W8 | 8FLW8 | EVホール | ＜ゾーン番号＞ | yes | 8FL | 8 | リンクなし | リンクなし | リンクなし | インテリア | no | 2675 | 2650 | 0.20475 | 6.94875 | 3.27982 | 1.04231 | 0.623767 | 21000 | 4.47795 | 2675 | 1.33875 | 5650 | 23650 | 1 | 0 | 0 | 0 | 2.58 | 1100 | 0 | 0 | 4.86705 | 2.4708 | 0.20475 | 2.0817 | 0.418545 | 2825 | 390 | 2.0817 | 1515 | 4.47795 | 8.925 | 8.925 | 2675 | 2675 | 8FL
8FLW3 | 8FL | W3 | 8FLW3 | EVホール | ＜ゾーン番号＞ | yes | 8FL | 8 | リンクなし | リンクなし | リンクなし | インテリア | no | 5250 | 2650 | 0.77625 | 13.4775 | 13.4775 | 2.02162 | 2.02162 | 21000 | 13.4775 | 5175 | 2.50875 | 10862.1 | 23650 | 0 | 0 | 0 | 0 | 0 | 0 | 0 | 0 | 0 | 0 | 0.77625 | 13.4775 | 3.9968e-15 | 5325 | 5175 | 13.4775 | 5325 | 13.4775 | 16.725 | 16.725 | 5175 | 5325 | 8FL | 一般性能 - 耐火性能: 3時間耐火構造
8FLW9 | 8FL | W9 | 8FLW9 | EVホール | ＜ゾーン番号＞ | yes | 8FL | 8 | リンクなし | リンクなし | リンクなし | インテリア | no | 1700 | 2300 | 0.00974999 | 3.7375 | 0.4147 | 0.560625 | 0.062205 | 21000 | 0.4147 | 1625 | 0.86625 | 3762.13 | 23300 | 1 | 0 | 1 | 0 | 3.52895 | 1500 | 0 | 0 | 3.3228 | 3.3228 | 0.00974999 | 0.4147 | 0.49842 | 1775 | 65 | 0.4147 | 215 | 0.4147 | 5.775 | 5.775 | 1625 | 1775 | 8FL
8FLW6 | 8FL | W6 | 8FLW6 | EVシャフト | ＜ゾーン番号＞ | yes | 8FL | 8 | リンクなし | リンクなし | リンクなし | インテリア | no | 6725 | 2300 | 0.41175 | 13.6275 | 6.8541 | 2.04413 | 1.02811 | 21000 | 6.8541 | 5925 | 3.09375 | 13874.3 | 23300 | 3 | 0 | 1 | 0 | 8.9445 | 3000 | 0 | 0 | 6.7734 | 6.7734 | 0.41175 | 6.8541 | 1.01601 | 6725 | 3695 | 6.8541 | 3395 | 6.8541 | 20.625 | 20.625 | 6875 | 6575 | 8FL
8FLW4 | 8FL | W4 | 8FLW4 | EVホール | ＜ゾーン番号＞ | yes | 8FL | 8 | リンクなし | リンクなし | リンクなし | インテリア | no | 1625 | 2300 | 0.04725 | 4.3125 | 0.9897 | 0.646875 | 0.148455 | 21000 | 0.9897 | 1875 | 0.91125 | 3550 | 23300 | 1 | 0 | 1 | 0 | 3.52895 | 1500 | 0 | 0 | 3.3228 | 3.3228 | 0.39225 | 0.9897 | 0.49842 | 1775 | 65 | 0.9897 | 65 | 0.9897 | 6.075 | 6.075 | 1625 | 1625 | 8FL
8FLW4 | 8FL | W4 | 8FLW4 | EVホール | ＜ゾーン番号＞ | yes | 8FL | 8 | リンクなし | リンクなし | リンクなし | インテリア | no | 4050 | 2650 | 0.27075 | 8.81125 | 5.57365 | 1.32169 | 0.836048 | 21000 | 5.57365 | 3325 | 1.96875 | 8462.13 | 23650 | 2 | 0 | 1 | 0 | 3.5939 | 1400 | 0 | 0 | 3.2376 | 3.2376 | 0.27075 | 5.57365 | 0.48564 | 4125 | 2455 | 8.81125 | 2605 | 8.81125 | 13.125 | 13.125 | 3975 | 4125 | 8FL
9FLW9 | 9FL | W9 | 9FLW9 | 事務室 | 313 | yes | 9FL | 9 | リンクなし | リンクなし | リンクなし | インテリア | no | 20150 | 2650 | 2.45775 | 52.8175 | 44.6383 | 7.92263 | 6.69575 | 24000 | 44.6383 | 20225 | 9.21375 | 40662.1 | 26650 | 4 | 0 | 0 | 0 | 8.9198 | 3600 | 0 | 0 | 8.1792 | 8.1792 | 2.45775 | 44.6383 | 1.22688 | 20275 | 16235 | 44.6383 | 16385 | 44.6383 | 61.425 | 61.425 | 20075 | 20225 | 9FL
9FLW8 | 9FL | W8 | 9FLW8 | DS | ＜ゾーン番号＞ | yes | 9FL | 9 | リンクなし | リンクなし | リンクなし | インテリア | no | 2100 | 2650 | 0.28875 | 5.10125 | 5.10125 | 0.765188 | 0.765188 | 24000 | 5.10125 | 1925 | 1.08 | 4500 | 26650 | 0 | 0 | 1 | 0 | 0 | 0 | 0 | 0 | 0 | 0 | 0.28875 | 5.10125 | 0 | 2250 | 2100 | 5.10125 | 2100 | 5.10125 | 7.2 | 7.2 | 2100 | 2100 | 9FL
9FLW4 | 9FL | W4 | 9FLW4 | EVホール | ＜ゾーン番号＞ | yes | 9FL | 9 | リンクなし | リンクなし | リンクなし | インテリア | no | 2600 | 2650 | 0.216 | 6.89 | 4.4192 | 1.0335 | 0.66288 | 24000 | 4.4192 | 2600 | 1.2375 | 5624.26 | 26650 | 1 | 0 | 0 | 0 | 2.66295 | 1100 | 0 | 0 | 2.4708 | 2.4708 | 0.216 | 4.4192 | 0.37062 | 2600 | 1290 | 4.4192 | 1590 | 4.4192 | 8.25 | 8.25 | 2450 | 2750 | 9FL | 一般性能 - 耐火性能: 3時間耐火構造
9FLW5 | 9FL | W5 | 9FLW5 | 男性用トイレ | ＜ゾーン番号＞ | yes | 9FL | 9 | リンクなし | リンクなし | リンクなし | インテリア | no | 5175 | 2650 | 0.77625 | 13.4775 | 13.4775 | 2.02162 | 2.02162 | 24000 | 13.4775 | 5175 | 2.46375 | 10650 | 26650 | 0 | 0 | 0 | 0 | 0 | 0 | 0 | 0 | 0 | 0 | 0.77625 | 13.4775 | 0 | 5325 | 5175 | 13.4775 | 5175 | 13.4775 | 16.425 | 16.425 | 5175 | 5175 | 9FL
9FLW4 | 9FL | W4 | 9FLW4 | 事務室 | 303 | yes | 9FL | 9 | リンクなし | リンクなし | リンクなし | インテリア | no | 5000 | 2650 | 0.486 | 11.13 | 9.0852 | 1.6695 | 1.36278 | 24000 | 9.0852 | 4200 | 2.25 | 10300 | 26650 | 1 | 0 | 2 | 0 | 2.22995 | 900 | 0 | 0 | 2.0448 | 2.0448 | 0.486 | 9.0852 | 0.30672 | 5000 | 4040 | 9.0852 | 4040 | 9.0852 | 15 | 15 | 5000 | 5000 | 9FL
9FLW1 | 9FL | W1 | 9FLW1 | 事務室 | 310 | yes | 9FL | 9 | リンクなし | リンクなし | リンクなし | インテリア | no | 4050 | 2300 | 0.51 | 7.82 | 7.82 | 1.173 | 1.173 | 24000 | 7.82 | 3400 | 1.89 | 8400 | 26300 | 0 | 0 | 1 | 0 | 0 | 0 | 0 | 0 | 0 | 0 | 0.855 | 7.82 | 0 | 4125 | 4050 | 7.82 | 4050 | 7.82 | 12.6 | 12.6 | 4050 | 4050 | 9FL
9FLW2 | 9FL | W2 | 9FLW2 | 事務室 | 310 | yes | 9FL | 9 | リンクなし | リンクなし | リンクなし | インテリア | no | 2600 | 2300 | 0.36375 | 5.5775 | 5.5775 | 0.836625 | 0.836625 | 24000 | 5.5775 | 2425 | 1.20375 | 5562.13 | 26300 | 0 | 0 | 0 | 0 | 0 | 0 | 0 | 0 | 0 | 0 | 0.70875 | 5.5775 | 0 | 2600 | 2675 | 5.5775 | 2525 | 5.5775 | 8.025 | 8.025 | 2675 | 2525 | 9FL | 一般性能 - 耐火性能: 3時間耐火構造
9FLW8 | 9FL | W8 | 9FLW8 | DS | ＜ゾーン番号＞ | yes | 9FL | 9 | リンクなし | リンクなし | リンクなし | インテリア | no | 8425 | 2650 | 1.2525 | 21.9525 | 21.9525 | 3.29287 | 3.29287 | 24000 | 21.9525 | 8350 | 3.8925 | 17212.1 | 26650 | 0 | 0 | 0 | 0 | 0 | 0 | 0 | 0 | 0 | 3.55271e-15 | 1.2525 | 21.9525 | 4.44089e-16 | 8500 | 8350 | 21.9525 | 8500 | 21.9525 | 25.95 | 25.95 | 8350 | 8500 | 9FL
9FLW7 | 9FL | W7 | 9FLW7 | EVシャフト | ＜ゾーン番号＞ | yes | 9FL | 9 | リンクなし | リンクなし | リンクなし | インテリア | no | 2250 | 2650 | 0.36 | 6.29875 | 6.29875 | 0.944813 | 0.944813 | 24000 | 6.29875 | 2400 | 1.08 | 4924.26 | 26650 | 0 | 0 | 0 | 0 | 0 | 0 | 0 | 0 | 0 | 0 | 0.36 | 6.29875 | 0 | 2250 | 2100 | 6.29875 | 2400 | 6.29875 | 7.2 | 7.2 | 2100 | 2400 | 9FL
9FLW5 | 9FL | W5 | 9FLW5 | 事務室 | 309 | yes | 9FL | 9 | リンクなし | リンクなし | リンクなし | インテリア | no | 6650 | 2650 | 0.88875 | 14.6644 | 14.6644 | 2.14781 | 2.14781 | 24000 | 15.7012 | 5925 | 3.09375 | 13662.1 | 26650 | 0 | 0 | 1 | 0 | 0 | 0 | 0 | 0 | 0 | 0 | 0.88875 | 13.6275 | 0 | 6725 | 6725 | 13.6275 | 6575 | 15.7012 | 20.625 | 20.625 | 6725 | 6575 | 9FL
9FLW7 | 9FL | W7 | 9FLW7 | 事務室 | 308 | yes | 9FL | 9 | リンクなし | リンクなし | リンクなし | インテリア | no | 9925 | 2650 | 1.212 | 26.15 | 22.0604 | 3.9225 | 3.30906 | 24000 | 22.0604 | 10000 | 4.6125 | 20212.1 | 26650 | 2 | 0 | 0 | 0 | 4.4599 | 1800 | 0 | 0 | 4.0896 | 4.0896 | 1.212 | 22.0604 | 0.61344 | 10050 | 7930 | 22.0604 | 8080 | 22.0604 | 30.75 | 30.75 | 9850 | 10000 | 9FL
9FLW3 | 9FL | W3 | 9FLW3 | 事務室 | 310 | yes | 9FL | 9 | リンクなし | リンクなし | リンクなし | インテリア | no | 10150 | 2650 | 1.22325 | 26.3225 | 22.2329 | 3.94838 | 3.33494 | 24000 | 22.2329 | 10075 | 4.71375 | 20662.1 | 26650 | 2 | 0 | 0 | 0 | 4.4599 | 1800 | 0 | 0 | 4.0896 | 4.0896 | 1.22325 | 22.2329 | 0.61344 | 10275 | 8155 | 22.2329 | 8305 | 22.2329 | 31.425 | 31.425 | 10075 | 10225 | 9FL
9FLW4 | 9FL | W4 | 9FLW4 | 女性用トイレ | ＜ゾーン番号＞ | yes | 9FL | 9 | リンクなし | リンクなし | リンクなし | インテリア | no | 5250 | 2650 | 0.79875 | 13.875 | 13.875 | 2.08125 | 2.08125 | 24000 | 13.875 | 5325 | 2.46375 | 10862.1 | 26650 | 0 | 0 | 0 | 0 | 0 | 0 | 0 | 0 | 0 | 0 | 0.79875 | 13.875 | 0 | 5325 | 5325 | 13.875 | 5175 | 13.875 | 16.425 | 16.425 | 5325 | 5175 | 9FL | 一般性能 - 耐火性能: 3時間耐火構造
9FLW8 | 9FL | W8 | 9FLW8 | PS | ＜ゾーン番号＞ | yes | 9FL | 9 | リンクなし | リンクなし | リンクなし | インテリア | no | 2675 | 2650 | 0.40125 | 6.94875 | 6.94875 | 1.04231 | 1.04231 | 24000 | 6.94875 | 2675 | 1.33875 | 5650 | 26650 | 0 | 0 | 0 | 0 | 0 | 0 | 0 | 0 | 0 | 0 | 0.40125 | 6.94875 | 2.22045e-16 | 2825 | 2675 | 6.94875 | 2675 | 6.94875 | 8.925 | 8.925 | 2675 | 2675 | 9FL
9FLW4 | 9FL | W4 | 9FLW4 | 事務室 | 301 | yes | 9FL | 9 | リンクなし | リンクなし | リンクなし | インテリア | no | 10150 | 2650 | 0.972 | 22.26 | 18.1704 | 3.339 | 2.72556 | 24000 | 18.1704 | 8400 | 4.68 | 20600 | 26650 | 2 | 0 | 3 | 0 | 4.4599 | 1800 | 0 | 0 | 4.0896 | 4.0896 | 0.972 | 18.1704 | 0.61344 | 10275 | 8230 | 18.1704 | 8230 | 18.1704 | 31.2 | 31.2 | 10150 | 10150 | 9FL
9FLW5 | 9FL | W5 | 9FLW5 | 事務室 | 304 | yes | 9FL | 9 | リンクなし | リンクなし | リンクなし | インテリア | no | 20150 | 2650 | 1.944 | 44.52 | 36.3408 | 6.678 | 5.45112 | 24000 | 36.3408 | 16800 | 9.18 | 40600 | 26650 | 4 | 0 | 5 | 0 | 8.9198 | 3600 | 0 | 0 | 8.1792 | 8.1792 | 1.944 | 36.3408 | 1.22688 | 20275 | 16310 | 36.3408 | 16310 | 36.3408 | 61.2 | 61.2 | 20150 | 20150 | 9FL
9FLW6 | 9FL | W6 | 9FLW6 | DS | ＜ゾーン番号＞ | yes | 9FL | 9 | リンクなし | リンクなし | リンクなし | インテリア | no | 5000 | 2650 | 0.6075 | 10.7325 | 10.7325 | 1.60987 | 1.60987 | 24000 | 10.7325 | 4050 | 2.39625 | 10362.1 | 26650 | 0 | 0 | 2 | 0 | 0 | 0 | 0 | 0 | 0 | 0 | 0.6075 | 10.7325 | 0 | 5125 | 5075 | 10.7325 | 4925 | 10.7325 | 15.975 | 15.975 | 5075 | 4925 | 9FL
9FLW8 | 9FL | W8 | 9FLW8 | EVホール | ＜ゾーン番号＞ | yes | 9FL | 9 | リンクなし | リンクなし | リンクなし | インテリア | no | 5325 | 2650 | 0.63 | 11.13 | 11.13 | 1.6695 | 1.6695 | 24000 | 11.13 | 4200 | 2.43 | 11012.1 | 26650 | 0 | 0 | 2 | 0 | 0 | 0 | 0 | 0 | 0 | 0 | 0.63 | 11.13 | 0 | 5325 | 5250 | 11.13 | 5400 | 11.13 | 16.2 | 16.2 | 5250 | 5400 | 9FL
9FLW9 | 9FL | W9 | 9FLW9 | 事務室 | 310 | yes | 9FL | 9 | リンクなし | リンクなし | リンクなし | インテリア | no | 5000 | 2650 | 0.63 | 11.13 | 11.13 | 1.6695 | 1.6695 | 24000 | 11.13 | 4200 | 2.25 | 10300 | 26650 | 0 | 0 | 2 | 0 | 0 | 0 | 0 | 0 | 0 | 0 | 0.63 | 11.13 | 0 | 5000 | 5000 | 11.13 | 5000 | 11.13 | 15 | 15 | 5000 | 5000 | 9FL
9FLW0 | 9FL | W0 | 9FLW0 | 事務室 | 311 | yes | 9FL | 9 | リンクなし | リンクなし | リンクなし | インテリア | no | 5400 | 2650 | 0.63 | 11.13 | 11.13 | 1.6695 | 1.6695 | 24000 | 11.13 | 4200 | 2.43 | 11100 | 26650 | 0 | 0 | 2 | 0 | 0 | 0 | 0 | 0 | 0 | 0 | 0.63 | 11.13 | 0 | 5400 | 5400 | 11.13 | 5400 | 11.13 | 16.2 | 16.2 | 5400 | 5400 | 9FL
9FLW8 | 9FL | W8 | 9FLW8 | EVホール | ＜ゾーン番号＞ | yes | 9FL | 9 | リンクなし | リンクなし | リンクなし | インテリア | no | 2675 | 2650 | 0.20475 | 6.94875 | 3.27982 | 1.04231 | 0.623767 | 24000 | 4.47795 | 2675 | 1.33875 | 5650 | 26650 | 1 | 0 | 0 | 0 | 2.58 | 1100 | 0 | 0 | 4.86705 | 2.4708 | 0.20475 | 2.0817 | 0.418545 | 2825 | 390 | 2.0817 | 1515 | 4.47795 | 8.925 | 8.925 | 2675 | 2675 | 9FL
9FLW3 | 9FL | W3 | 9FLW3 | EVホール | ＜ゾーン番号＞ | yes | 9FL | 9 | リンクなし | リンクなし | リンクなし | インテリア | no | 5250 | 2650 | 0.77625 | 13.4775 | 13.4775 | 2.02162 | 2.02162 | 24000 | 13.4775 | 5175 | 2.50875 | 10862.1 | 26650 | 0 | 0 | 0 | 0 | 0 | 0 | 0 | 0 | 0 | 0 | 0.77625 | 13.4775 | 8.88178e-16 | 5325 | 5175 | 13.4775 | 5325 | 13.4775 | 16.725 | 16.725 | 5175 | 5325 | 9FL | 一般性能 - 耐火性能: 3時間耐火構造
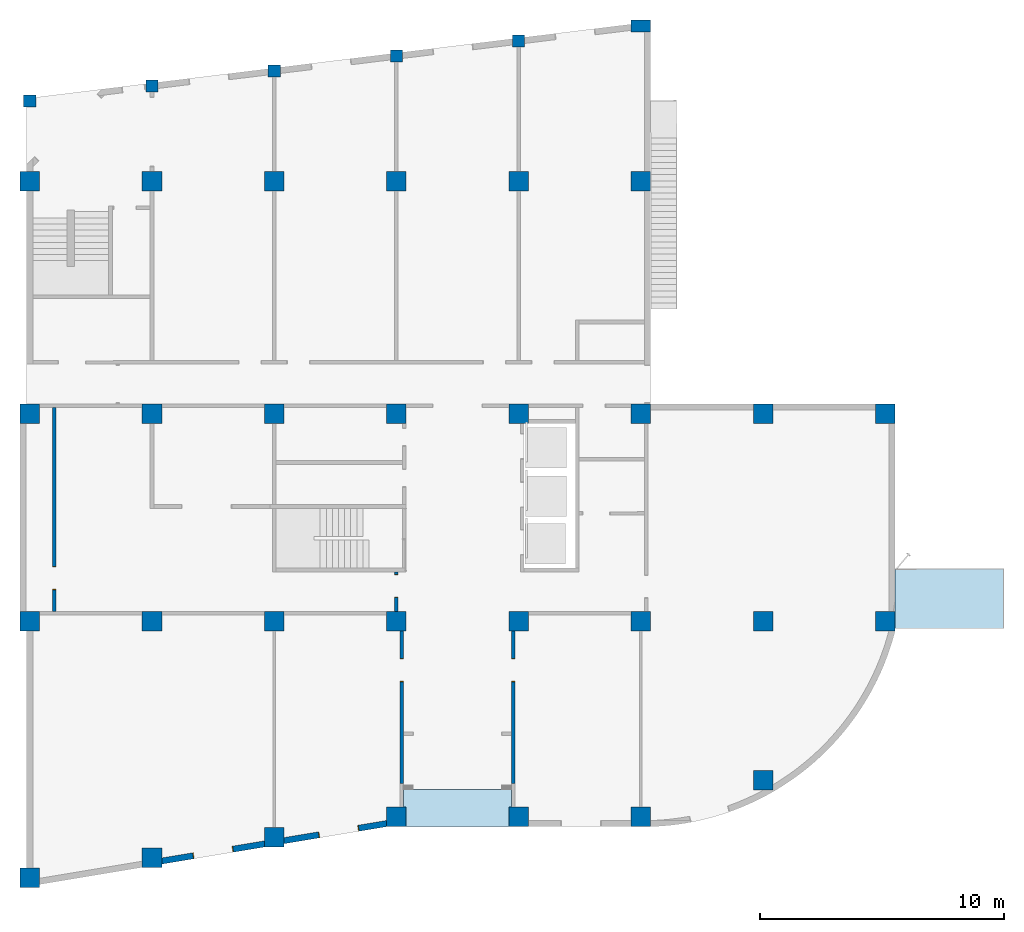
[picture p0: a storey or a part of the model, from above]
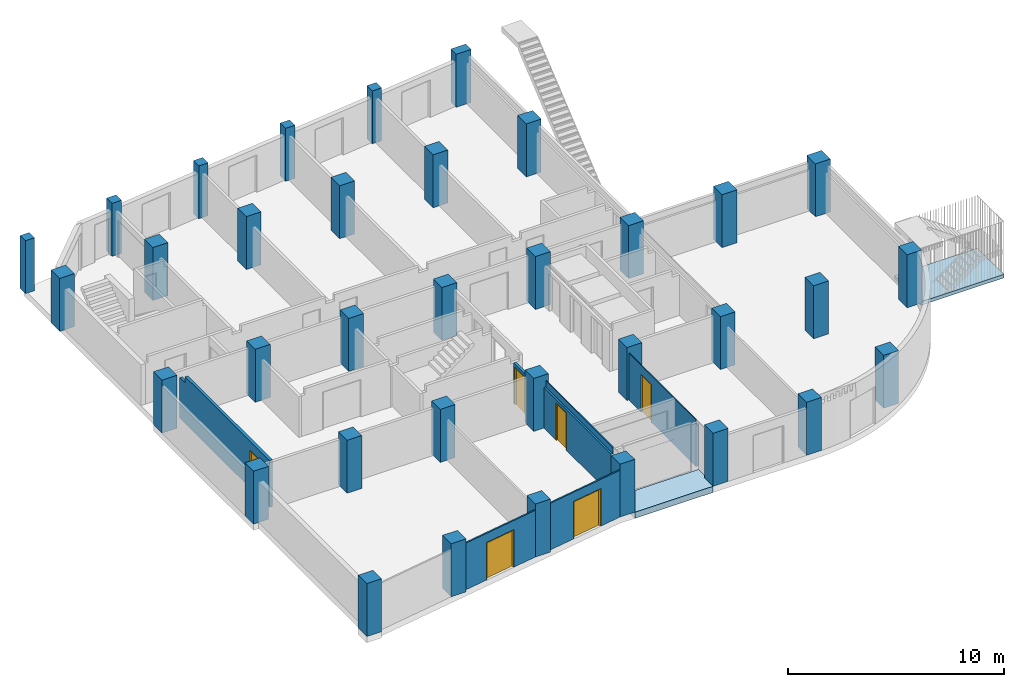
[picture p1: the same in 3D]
Properties of the parts of a building model (IFC2X3), part 9 of 10

# IfcWall: コンクリート 150 (271)
Name | In | 要素ID = 親ID | ホットリンクおよび要素ID | 関連ゾーン名 | 関連ゾーン番号 | ロック状態 | ホームフロア名 | ホームフロア数 | 絶対上部リンクフロア | 相対上部リンクフロア | 上部リンクフロア | 位置 | IsExternal | Length (mm) = 壁平均長 (mm) = 壁中心長さ (mm) | Height (mm) = 上端高度から配置フロア (mm) = 壁最大高さ (mm) | GrossFootprintArea (m2) = NetFootprintArea (m2) = 面積 (m2) | GrossSideArea (m2) | NetSideArea (m2) | GrossVolume (m3) = 条件付き体積 (m3) | NetVolume (m3) = 正味体積 (m3) | GLからの高度 (mm) = 高度 1 (mm) = 高度 2 (mm) = 海抜までの高度 (mm) = 下端高度から第1基準レベル (mm) = 下端高度から基準レベル (mm) = 下端高度から海抜 (mm) = 下端高度から第2基準レベル (mm) | 表面積 (m2) = 外面正味表面積 (m2) | 3D長さ (mm) | 総体積 (m3) | 平面図外周 (mm) | 上端高度から第1基準レベル (mm) = 上端高度から基準レベル (mm) = 上端高度から海抜 (mm) = 上端高度から第2基準レベル (mm) | ドア数 | 窓数 | 柱数 | 壁最小高さ (mm) | ドア面積 (m2) | ドア総幅 (mm) | 窓面積 (m2) | 窓総幅 (mm) | 内面分析的開口面積 (m2) | 外面分析的開口面積 (m2) | 辺の正味表面積 (m2) | 内面正味表面積 (m2) | 開口部分解法体積 (m3) | 基準線長さ (mm) | 条件付き内面長さ (mm) | 条件付き内面表面積 (m2) | 条件付き外面長さ (mm) | 条件付き外面表面積 (m2) | 内面総壁表面積 (m2) | 外面総壁表面積 (m2) | 内面壁長さ (mm) | 外面壁長さ (mm) | ホットリンク マスタID
9FLW9 | 9FL | W9 | 9FLW9 | EVホール | ＜ゾーン番号＞ | yes | 9FL | 9 | リンクなし | リンクなし | リンクなし | インテリア | no | 1700 | 2300 | 0.00974999 | 3.7375 | 0.4147 | 0.560625 | 0.062205 | 24000 | 0.4147 | 1625 | 0.86625 | 3762.13 | 26300 | 1 | 0 | 1 | 0 | 3.52895 | 1500 | 0 | 0 | 3.3228 | 3.3228 | 0.00974999 | 0.4147 | 0.49842 | 1775 | 65 | 0.4147 | 215 | 0.4147 | 5.775 | 5.775 | 1625 | 1775 | 9FL
9FLW6 | 9FL | W6 | 9FLW6 | EVシャフト | ＜ゾーン番号＞ | yes | 9FL | 9 | リンクなし | リンクなし | リンクなし | インテリア | no | 6725 | 2300 | 0.41175 | 13.6275 | 6.8541 | 2.04413 | 1.02811 | 24000 | 6.8541 | 5925 | 3.09375 | 13874.3 | 26300 | 3 | 0 | 1 | 0 | 8.9445 | 3000 | 0 | 0 | 6.7734 | 6.7734 | 0.41175 | 6.8541 | 1.01601 | 6725 | 3695 | 6.8541 | 3395 | 6.8541 | 20.625 | 20.625 | 6875 | 6575 | 9FL
9FLW4 | 9FL | W4 | 9FLW4 | EVホール | ＜ゾーン番号＞ | yes | 9FL | 9 | リンクなし | リンクなし | リンクなし | インテリア | no | 1625 | 2300 | 0.04725 | 4.3125 | 0.9897 | 0.646875 | 0.148455 | 24000 | 0.9897 | 1875 | 0.91125 | 3550 | 26300 | 1 | 0 | 1 | 0 | 3.52895 | 1500 | 0 | 0 | 3.3228 | 3.3228 | 0.39225 | 0.9897 | 0.49842 | 1775 | 65 | 0.9897 | 65 | 0.9897 | 6.075 | 6.075 | 1625 | 1625 | 9FL
9FLW4 | 9FL | W4 | 9FLW4 | EVホール | ＜ゾーン番号＞ | yes | 9FL | 9 | リンクなし | リンクなし | リンクなし | インテリア | no | 4050 | 2650 | 0.27075 | 8.81125 | 5.57365 | 1.32169 | 0.836048 | 24000 | 5.57365 | 3325 | 1.96875 | 8462.13 | 26650 | 2 | 0 | 1 | 0 | 3.5939 | 1400 | 0 | 0 | 3.2376 | 3.2376 | 0.27075 | 5.57365 | 0.48564 | 4125 | 2455 | 8.81125 | 2605 | 8.81125 | 13.125 | 13.125 | 3975 | 4125 | 9FL

# IfcWall: コンクリート 250 (73)
Classification: 壁 (ARCHICAD 分類); Material: コンクリート
ArchiCADProperties - レイヤー: 壁-躯体; ビルディングマテリアル/複合構造/断面形状/塗りつぶし: コンクリート; ビルディングマテリアル: コンクリート; 要素タイプ: 壁; 構造タイプ: 基本; ビルディングマテリアル (全て): コンクリート; 材質 (全て): コンクリート - 04; 傾斜角度: 90 deg; 開口部の数: 0; リノベーションフィルタで表示: 全ての関連フィルタ; 構造機能: 非構造耐力要素; 位置: エクステリア; リノベーションステータス: 既存; 壁形状: 直線; 図形作成法: 均一; 基準線位置: 中央; 辺材質: コンクリート - 04; 内面材質: コンクリート - 04; 外面材質: コンクリート - 04; 壁内側傾斜角度: 90 deg; 壁外側傾斜角度: 90 deg; ARCHICAD 分類 - v 2.0: 壁
仕上情報 - WEBサイト: www.graphisoft.co.jp
AC_Pset_RenovationAndPhasing - Renovation Status: Existing
Pset_WallCommon - LoadBearing: no; IsExternal: yes
BaseQuantities - Width: 250 mm
ArchiCADQuantities - 高さ: 3000 mm; 幅: 250 mm; リンク/配置フロアまでの高度: 0 mm; 下部オフセット: 0 mm; 上部オフセット: 0 mm; 厚さ: 250 mm; 壁断熱材厚: 0 mm; 穴数(単純開口数): 0; 窓数: 0; 柱体積: 0 m3; 最大内面層の高さ: 0 mm; 最小内面層の高さ: 0 mm; 壁最小高さ: 0 mm; 最大外面層の高さ: 0 mm; 最小外面層の高さ: 0 mm; 空気層厚さ: 0 mm; 内面壁層の厚さ: 0 mm; 外面壁層の厚さ: 0 mm; 窓面積: 0 m2; 窓総幅: 0 mm; 壁終点厚さ: 250 mm; 壁内開口面積: 0 m2
Name | In | 要素ID = 親ID | ホットリンクおよび要素ID | 関連ゾーン名 | 関連ゾーン番号 | ロック状態 | ホームフロア名 | ホームフロア数 | 絶対上部リンクフロア | 相対上部リンクフロア | 上部リンクフロア | Length (mm) = 壁平均長 (mm) = 壁中心長さ (mm) | Height (mm) = 上端高度から配置フロア (mm) = 壁最大高さ (mm) | GrossFootprintArea (m2) = NetFootprintArea (m2) = 面積 (m2) | GrossSideArea (m2) | NetSideArea (m2) | GrossVolume (m3) = 条件付き体積 (m3) | NetVolume (m3) = 正味体積 (m3) | GLからの高度 (mm) = 高度 1 (mm) = 高度 2 (mm) = 海抜までの高度 (mm) | 表面積 (m2) = 外面正味表面積 (m2) = 条件付き外面表面積 (m2) | 3D長さ (mm) | 総体積 (m3) | 平面図外周 (mm) | 上端高度から第1基準レベル (mm) = 上端高度から基準レベル (mm) = 上端高度から海抜 (mm) = 上端高度から第2基準レベル (mm) | 下端高度から第1基準レベル (mm) = 下端高度から基準レベル (mm) = 下端高度から海抜 (mm) = 下端高度から第2基準レベル (mm) | 下端高度から配置フロア (mm) | ドア数 | 柱数 | ドア面積 (m2) | ドア総幅 (mm) | 内面分析的開口面積 (m2) | 外面分析的開口面積 (m2) | 辺の正味表面積 (m2) | 内面正味表面積 (m2) | 開口部分解法体積 (m3) | 基準線長さ (mm) | 条件付き内面長さ (mm) | 条件付き内面表面積 (m2) | 条件付き外面長さ (mm) | 内面総壁表面積 (m2) | 外面総壁表面積 (m2) | 内面壁長さ (mm) | 外面壁長さ (mm)
W1 | 1FL | W1 | W1 | 店舗 | 101 | no | 1FL | 1 | 2FL | 配置フロア + 1 | 配置フロア + 1 (2FL) | 10956.6 | 2300 | 2.425 | 22.31 | 22.31 | 5.5775 | 5.5775 | 0 | 22.31 | 9700 | 8.425 | 22550 | 2300 | 0 | 0 | 0 | 2 | 0 | 0 | 0 | 0 | 2.425 | 22.31 | 0 | 11031.6 | 11104.2 | 22.31 | 10809.1 | 33.7625 | 33.6375 | 11104.2 | 10809.1
W1 | 1FL | W1 | W1 | 店舗 | 101 | no | 1FL | 1 | 2FL | 配置フロア + 1 | 配置フロア + 1 (2FL) | 5068.97 | 2650 | 1.06448 | 10.5384 | 10.5384 | 2.56574 | 2.56574 | 0 | 11.2835 | 4299.6 | 3.89677 | 10774.7 | 2650 | 0 | 0 | 0 | 2 | 0 | 0 | 0 | 0 | 1.06448 | 9.79325 | 0 | 5068.97 | 4921.41 | 9.79325 | 5216.53 | 15.5246 | 15.6496 | 4921.41 | 5216.53
W2 | 1FL | W2 | W2 | 店舗 | 101 | no | 1FL | 1 | 2FL | 配置フロア + 1 | 配置フロア + 1 (2FL) | 5068.97 | 2650 | 0.649483 | 10.5384 | 7.00259 | 2.56574 | 1.68179 | 0 | 7.74772 | 4299.6 | 3.80173 | 10637.9 | 2650 | 0 | 0 | 1 | 2 | 3.655 | 1600 | 3.5358 | 3.5358 | 0.649483 | 6.25745 | 0.88395 | 5068.97 | 3408.97 | 6.25745 | 3408.97 | 15.2069 | 15.2069 | 5068.97 | 5068.97
W3 | 1FL | W3 | W3 | 店舗 | 102 | no | 1FL | 1 | 2FL | 配置フロア + 1 | 配置フロア + 1 (2FL) | 5297.07 | 2650 | 0.649483 | 10.5384 | 7.00259 | 2.56574 | 1.68179 | 0 | 7.74772 | 4299.6 | 4.02983 | 11117.4 | 2650 | 0 | 0 | 1 | 2 | 3.655 | 1600 | 3.5358 | 3.5358 | 0.649483 | 6.25745 | 0.88395 | 5297.07 | 3581.87 | 6.25745 | 3692.27 | 16.1818 | 16.0568 | 5241.87 | 5352.27
W4 | 1FL | W4 | W4 | 店舗 | 103 | no | 1FL | 1 | 2FL | 配置フロア + 1 | 配置フロア + 1 (2FL) | 5624.99 | 3000 | 0.933113 | 13.0297 | 9.09908 | 3.4622 | 2.54877 | 0 | 7.59945 | 6186.44 | 5.21086 | 11791.6 | 3000 | -4.44089e-13 | -4.44089e-13 | 1 | 2 | 3.655 | 1600 | 4.32536 | 3.5358 | 0.93317 | 10.5987 | 0.913432 | 5625 | 3888.01 | 11.3883 | 4041.98 | 23.0593 | 17.106 | 5548.01 | 5701.98
W0 | 1FL | W0 | W0 | 店舗 | 104 | no | 1FL | 1 | 2FL | 配置フロア + 1 | 配置フロア + 1 (2FL) | 9174.95 | 2650 | 1.90823 | 18.4377 | 18.4377 | 4.78732 | 4.78732 | 0 | 19.1653 | 7700 | 7.31169 | 18955.5 | 2650 | -6.66134e-13 | -6.66134e-13 | 0 | 2 | 0 | 0 | 0 | 0 | 1.90823 | 17.71 | 0 | 9175 | 9033.85 | 17.71 | 9316.05 | 30.4174 | 27.9466 | 9033.85 | 9316.05
W0 | 1FL | W0 | W0 | 店舗 | 104 | no | 1FL | 1 | 2FL | 配置フロア + 1 | 配置フロア + 1 (2FL) | 5275 | 2650 | 1.05 | 10.395 | 10.395 | 2.6355 | 2.6355 | 0 | 11.13 | 4200 | 4.05 | 11153.6 | 2650 | 0 | 0 | 0 | 2 | 0 | 0 | 0 | 0 | 1.05 | 9.66 | 0 | 5275 | 5150 | 9.66 | 5400 | 16.2 | 16.2 | 5150 | 5400
W1 | 1FL | W1 | W1 | 店舗 | 104 | no | 1FL | 1 | 2FL | 配置フロア + 1 | 配置フロア + 1 (2FL) | 4700 | 2650 | 1.05 | 10.395 | 10.395 | 2.6355 | 2.6355 | 0 | 11.13 | 4200 | 3.6375 | 9900 | 2650 | 0 | 0 | 0 | 2 | 0 | 0 | 0 | 0 | 1.05 | 9.66 | 0 | 4775 | 4700 | 9.66 | 4700 | 14.55 | 14.55 | 4700 | 4700
W2 | 1FL | W2 | W2 | 廊下 | ＜ゾーン番号＞ | no | 1FL | 1 | 2FL | 配置フロア + 1 | 配置フロア + 1 (2FL) | 9175 | 2650 | 1.785 | 21.5325 | 18.2097 | 5.45925 | 4.62855 | 0 | 19.7322 | 8700 | 6.9375 | 18891.5 | 2650 | 0 | 0 | 1 | 2 | 3.44 | 1500 | 3.3228 | 3.3228 | 1.785 | 16.6872 | 0.8307 | 9175 | 7540 | 16.6872 | 7690 | 27.75 | 27.75 | 9100 | 9250
W3 | 1FL | W3 | W3 | 店舗 | 105 | no | 1FL | 1 | 2FL | 配置フロア + 1 | 配置フロア + 1 (2FL) | 6386.41 | 2650 | 1.42566 | 14.114 | 14.114 | 3.57841 | 3.57841 | 0 | 15.112 | 5702.64 | 4.88426 | 13400.1 | 2650 | 0 | 0 | 0 | 2 | 0 | 0 | 0 | 0 | 1.42566 | 13.1161 | 0 | 6386.41 | 6245.12 | 13.1161 | 6527.7 | 19.491 | 19.5831 | 6245.12 | 6527.7
W4 | 1FL | W4 | W4 | 店舗 | 105 | no | 1FL | 1 | 2FL | 配置フロア + 1 | 配置フロア + 1 (2FL) | 5314.61 | 2500 | 0.680667 | 10.9567 | 7.42087 | 2.73917 | 1.85522 | 0 | 7.42087 | 4413.36 | 4.08041 | 11256.5 | 2500 | 0 | 0 | 1 | 2 | 3.655 | 1600 | 3.5358 | 3.5358 | 0.680667 | 7.42087 | 0.88395 | 5314.61 | 3513.33 | 7.42087 | 3795.9 | 16.2756 | 16.3677 | 5173.33 | 5455.9
W5 | 1FL | W5 | W5 | 店舗 | 106 | no | 1FL | 1 | 2FL | 配置フロア + 1 | 配置フロア + 1 (2FL) | 5037.55 | 2500 | 0.718449 | 11.3345 | 7.79869 | 2.83362 | 1.94967 | 0 | 7.79869 | 4564.49 | 3.77816 | 10575.1 | 2500 | 0 | 0 | 1 | 2 | 3.655 | 1600 | 3.5358 | 3.5358 | 0.718449 | 7.79869 | 0.88395 | 5037.55 | 3377.55 | 7.79869 | 3377.55 | 15.1126 | 15.1126 | 5037.55 | 5037.55
W6 | 1FL | W6 | W6 | 店舗 | 107 | no | 1FL | 1 | 2FL | 配置フロア + 1 | 配置フロア + 1 (2FL) | 5037.55 | 2500 | 0.718449 | 11.3345 | 7.79869 | 2.83362 | 1.94967 | 0 | 7.79869 | 4564.49 | 3.77816 | 10575.1 | 2500 | 0 | 0 | 1 | 2 | 3.655 | 1600 | 3.5358 | 3.5358 | 0.718449 | 7.79869 | 0.88395 | 5037.55 | 3377.55 | 7.79869 | 3377.55 | 15.1126 | 15.1126 | 5037.55 | 5037.55
W7 | 1FL | W7 | W7 | 店舗 | 108 | no | 1FL | 1 | 2FL | 配置フロア + 1 | 配置フロア + 1 (2FL) | 5037.55 | 2500 | 0.718449 | 11.3345 | 7.79869 | 2.83362 | 1.94967 | 0 | 7.79869 | 4564.49 | 3.77816 | 10575.1 | 2500 | 0 | 0 | 1 | 2 | 3.655 | 1600 | 3.5358 | 3.5358 | 0.718449 | 7.79869 | 0.88395 | 5037.55 | 3377.55 | 7.79869 | 3377.55 | 15.1126 | 15.1126 | 5037.55 | 5037.55
W8 | 1FL | W8 | W8 | ホール | ＜ゾーン番号＞ | no | 1FL | 1 | 2FL | 配置フロア + 1 | 配置フロア + 1 (2FL) | 2000 | 2500 | 0.239373 | 4.87789 | 2.63472 | 1.21947 | 0.690347 | 0 | 2.47148 | 2126.5 | 1.65228 | 4514.41 | 2500 | 0 | 0 | 1 | 1 | 2.22995 | 900 | 2.44154 | 2.0448 | 0.239373 | 2.79796 | 0.529126 | 2000 | 996.959 | 3.1947 | 1083.04 | 7.08908 | 6.12912 | 1956.96 | 2043.04
W8 | 1FL | W8 | W8 | ホール | ＜ゾーン番号＞ | no | 1FL | 1 | 2FL | 配置フロア + 1 | 配置フロア + 1 (2FL) | 4263.72 | 2650 | 0.0643941 | 10.2582 | 2.6187 | 2.56455 | 0.633522 | 0 | 2.01979 | 4168.91 | 3.48265 | 9062.45 | 2650 | 0 | 0 | 1 | 0 | 7.955 | 3600 | 7.7958 | 7.48316 | 0.0643941 | 3.21762 | 1.93102 | 4263.72 | 508.906 | 3.21762 | 845.318 | 14.7856 | 13.0756 | 4168.91 | 4358.54
W0 | 1FL | W0 | W0 | ゴミ置き場 | ＜ゾーン番号＞ | no | 1FL | 1 | 2FL | 配置フロア + 1 | 配置フロア + 1 (2FL) | 8038.31 | 2500 | 1.87252 | 17.3102 | 17.3102 | 4.32755 | 4.32755 | 0 | 16.9977 | 7615.08 | 6.21756 | 16638.8 | 2500 | 0 | 0 | 0 | 1 | 0 | 0 | 0 | 0 | 1.87252 | 17.6227 | 0 | 8038.31 | 7911.53 | 17.6227 | 8165.08 | 25.2452 | 24.4952 | 7911.53 | 8165.08
W1 | 1FL | W1 | W1 | PS | ＜ゾーン番号＞ | no | 1FL | 1 | 2FL | 配置フロア + 1 | 配置フロア + 1 (2FL) | 8500 | 2650 | 1.925 | 19.0575 | 19.0575 | 4.83175 | 4.83175 | 0 | 20.405 | 7700 | 6.4875 | 17583.1 | 2650 | 0 | 0 | 0 | 2 | 0 | 0 | 0 | 0 | 1.925 | 17.71 | 0 | 8500 | 8350 | 17.71 | 8650 | 25.95 | 25.95 | 8350 | 8650
W8 | 1FL | W8 | W8 | 店舗 | 104 | no | 1FL | 1 | 2FL | 配置フロア + 1 | 配置フロア + 1 (2FL) | 13540.3 | 3000 | 2.64954 | 37.6581 | 34.5003 | 9.15346 | 8.29801 | 0 | 32.3754 | 14047 | 10.8352 | 27582.6 | 3000 | -4.44089e-13 | -4.44089e-13 | 1 | 3 | 3.655 | 1600 | 3.5398 | 2.77579 | 5.70069 | 36.6253 | 0.855449 | 13540.2 | 8653.01 | 36.6253 | 10097.3 | 44.9193 | 41.1609 | 13361.8 | 13718.7
W8 | 2FL | W8 | W8 | 店舗 | 207 | no | 2FL | 2 | 3FL | 配置フロア + 1 | 配置フロア + 1 (3FL) | 13540.3 | 2650 | 3.05113 | 33.2647 | 33.2445 | 8.08556 | 8.08551 | 3000 | 31.0502 | 14047 | 10.8352 | 27582.6 | 5650 | 3000 | -4.44089e-13 | 0 | 3 | 0 | 0 | 0.0404493 | 0 | 3.05113 | 35.4387 | 0.00004649 | 13540.2 | 13361.8 | 35.4792 | 13718.7 | 44.9193 | 41.1609 | 13361.8 | 13718.7
W1 | 2FL | W1 | W1 | 店舗 | 209 | no | 2FL | 2 | 3FL | 配置フロア + 1 | 配置フロア + 1 (3FL) | 4725 | 2650 | 1.05 | 10.395 | 10.395 | 2.6355 | 2.6355 | 3000 | 11.13 | 4200 | 3.6375 | 10053.6 | 5650 | 3000 | 0 | 0 | 2 | 0 | 0 | 0 | 0 | 1.05 | 9.66 | 2.66454e-15 | 4725 | 4850 | 9.66 | 4600 | 14.55 | 14.55 | 4850 | 4600
W1 | 2FL | W1 | W1 | 店舗 | 201 | no | 2FL | 2 | 3FL | 配置フロア + 1 | 配置フロア + 1 (3FL) | 10956.6 | 2300 | 2.425 | 22.31 | 22.31 | 5.5775 | 5.5775 | 3000 | 22.31 | 9700 | 8.425 | 22550 | 5300 | 3000 | 0 | 0 | 2 | 0 | 0 | 0 | 0 | 2.425 | 22.31 | 0 | 11031.6 | 11104.2 | 22.31 | 10809.1 | 33.7625 | 33.6375 | 11104.2 | 10809.1
W1 | 2FL | W1 | W1 | 店舗 | 201 | no | 2FL | 2 | 3FL | 配置フロア + 1 | 配置フロア + 1 (3FL) | 5068.97 | 2650 | 1.06448 | 10.5384 | 10.5384 | 2.56574 | 2.56574 | 3000 | 11.2835 | 4299.6 | 3.89677 | 10774.7 | 5650 | 3000 | 0 | 0 | 2 | 0 | 0 | 0 | 0 | 1.06448 | 9.79325 | 0 | 5068.97 | 4921.41 | 9.79325 | 5216.53 | 15.5246 | 15.6496 | 4921.41 | 5216.53
W2 | 2FL | W2 | W2 | 店舗 | 202 | no | 2FL | 2 | 3FL | 配置フロア + 1 | 配置フロア + 1 (3FL) | 5068.97 | 2650 | 1.06448 | 10.5384 | 10.5384 | 2.56574 | 2.56574 | 3000 | 11.2835 | 4299.6 | 3.80173 | 10637.9 | 5650 | 3000 | 0 | 0 | 2 | 0 | 0 | 0 | 0 | 1.06448 | 9.79325 | 0 | 5068.97 | 5068.97 | 9.79325 | 5068.97 | 15.2069 | 15.2069 | 5068.97 | 5068.97
W3 | 2FL | W3 | W3 | 店舗 | 203 | no | 2FL | 2 | 3FL | 配置フロア + 1 | 配置フロア + 1 (3FL) | 5297.07 | 2650 | 1.06448 | 10.5384 | 10.5384 | 2.56574 | 2.56574 | 3000 | 11.2835 | 4299.6 | 4.02983 | 11117.4 | 5650 | 3000 | 0 | 0 | 2 | 0 | 0 | 0 | 0 | 1.06448 | 9.79325 | 0 | 5297.07 | 5241.87 | 9.79325 | 5352.27 | 16.1818 | 16.0568 | 5241.87 | 5352.27
W4 | 2FL | W4 | W4 | 店舗 | 206 | no | 2FL | 2 | 3FL | 配置フロア + 1 | 配置フロア + 1 (3FL) | 5624.99 | 2650 | 1.36195 | 13.0297 | 13.0297 | 3.46218 | 3.46218 | 3000 | 11.1353 | 6186.44 | 5.21086 | 11791.6 | 5650 | 3000 | -4.44089e-13 | 0 | 2 | 0 | 0 | 0 | 0 | 1.36195 | 14.9241 | 0 | 5625 | 5548.01 | 14.9241 | 5701.98 | 23.0593 | 17.106 | 5548.01 | 5701.98
W0 | 2FL | W0 | W0 | EVホール | ＜ゾーン番号＞ | no | 2FL | 2 | 3FL | 配置フロア + 1 | 配置フロア + 1 (3FL) | 9174.95 | 2650 | 1.61825 | 18.4377 | 15.9869 | 4.78732 | 4.16966 | 3000 | 16.7347 | 7700 | 7.31169 | 18955.5 | 5650 | 3000 | -4.44089e-13 | 1 | 2 | 2.66295 | 1100 | 2.4708 | 2.43065 | 1.61825 | 15.2392 | 0.617654 | 9175 | 7873.85 | 15.2392 | 8174.9 | 30.4174 | 27.9466 | 9033.85 | 9316.05
W0 | 2FL | W0 | W0 | 店舗 | 210 | no | 2FL | 2 | 3FL | 配置フロア + 1 | 配置フロア + 1 (3FL) | 5275 | 2650 | 1.05 | 10.395 | 10.395 | 2.6355 | 2.6355 | 3000 | 11.13 | 4200 | 4.05 | 11153.6 | 5650 | 3000 | 0 | 0 | 2 | 0 | 0 | 0 | 0 | 1.05 | 9.66 | 0 | 5275 | 5150 | 9.66 | 5400 | 16.2 | 16.2 | 5150 | 5400
W2 | 2FL | W2 | W2 | DS | ＜ゾーン番号＞ | no | 2FL | 2 | 3FL | 配置フロア + 1 | 配置フロア + 1 (3FL) | 9225 | 2650 | 2.175 | 21.5325 | 21.5325 | 5.45925 | 5.45925 | 3000 | 23.055 | 8700 | 7.0125 | 19053.6 | 5650 | 3000 | 0 | 0 | 2 | 0 | 0 | 0 | 0 | 2.175 | 20.01 | 3.25347e-09 | 9225 | 9350 | 20.01 | 9100 | 28.05 | 28.05 | 9350 | 9100
W3 | 2FL | W3 | W3 | 店舗 | 214 | no | 2FL | 2 | 3FL | 配置フロア + 1 | 配置フロア + 1 (3FL) | 6386.41 | 2650 | 1.42566 | 14.114 | 14.114 | 3.57841 | 3.57841 | 3000 | 15.112 | 5702.64 | 4.88426 | 13400.1 | 5650 | 3000 | 0 | 0 | 2 | 0 | 0 | 0 | 0 | 1.42566 | 13.1161 | 0 | 6386.41 | 6245.12 | 13.1161 | 6527.7 | 19.491 | 19.5831 | 6245.12 | 6527.7
W4 | 2FL | W4 | W4 | 店舗 | 214 | no | 2FL | 2 | 3FL | 配置フロア + 1 | 配置フロア + 1 (3FL) | 5314.61 | 2500 | 1.09567 | 10.9567 | 10.9567 | 2.73917 | 2.73917 | 3000 | 10.9567 | 4413.36 | 4.08041 | 11256.5 | 5500 | 3000 | 0 | 0 | 2 | 0 | 0 | 0 | 0 | 1.09567 | 10.9567 | 0 | 5314.61 | 5173.33 | 10.9567 | 5455.9 | 16.2756 | 16.3677 | 5173.33 | 5455.9
W5 | 2FL | W5 | W5 | 店舗 | 214 | no | 2FL | 2 | 3FL | 配置フロア + 1 | 配置フロア + 1 (3FL) | 5037.55 | 2500 | 1.13345 | 11.3345 | 11.3345 | 2.83362 | 2.83362 | 3000 | 11.3345 | 4564.49 | 3.77816 | 10575.1 | 5500 | 3000 | 0 | 0 | 2 | 0 | 0 | 0 | 0 | 1.13345 | 11.3345 | 0 | 5037.55 | 5037.55 | 11.3345 | 5037.55 | 15.1126 | 15.1126 | 5037.55 | 5037.55
W6 | 2FL | W6 | W6 | 店舗 | 212 | no | 2FL | 2 | 3FL | 配置フロア + 1 | 配置フロア + 1 (3FL) | 5037.55 | 2500 | 1.13345 | 11.3345 | 11.3345 | 2.83362 | 2.83362 | 3000 | 11.3345 | 4564.49 | 3.77816 | 10575.1 | 5500 | 3000 | 0 | 0 | 2 | 0 | 0 | 0 | 0 | 1.13345 | 11.3345 | 8.88178e-16 | 5037.55 | 5037.55 | 11.3345 | 5037.55 | 15.1126 | 15.1126 | 5037.55 | 5037.55
W7 | 2FL | W7 | W7 | 店舗 | 211 | no | 2FL | 2 | 3FL | 配置フロア + 1 | 配置フロア + 1 (3FL) | 5037.55 | 2500 | 1.13345 | 11.3345 | 11.3345 | 2.83362 | 2.83362 | 3000 | 11.3345 | 4564.49 | 3.77816 | 10575.1 | 5500 | 3000 | 0 | 0 | 2 | 0 | 0 | 0 | 0 | 1.13345 | 11.3345 | 0 | 5037.55 | 5037.55 | 11.3345 | 5037.55 | 15.1126 | 15.1126 | 5037.55 | 5037.55
W8 | 2FL | W8 | W8 | 男性用トイレ | ＜ゾーン番号＞ | no | 2FL | 2 | 3FL | 配置フロア + 1 | 配置フロア + 1 (3FL) | 5037.55 | 2500 | 1.13345 | 11.3345 | 11.3345 | 2.83362 | 2.83362 | 3000 | 11.3345 | 4564.49 | 3.87262 | 10658.9 | 5500 | 3000 | 0 | 0 | 2 | 0 | 0 | 0 | 0 | 1.13345 | 11.3345 | 0 | 5037.55 | 4926.96 | 11.3345 | 5148.14 | 15.5365 | 15.4444 | 4926.96 | 5148.14
W9 | 2FL | W9 | W9 | 女性用トイレ | ＜ゾーン番号＞ | no | 2FL | 2 | 3FL | 配置フロア + 1 | 配置フロア + 1 (3FL) | 3283.03 | 2500 | 0.658257 | 6.58257 | 6.58257 | 1.64564 | 1.64564 | 3000 | 6.58257 | 2633.03 | 2.55673 | 7149.86 | 5500 | 3000 | 0 | 0 | 2 | 0 | 0 | 0 | 0 | 0.658257 | 6.58257 | 0 | 3283.03 | 3172.44 | 6.58257 | 3393.62 | 10.2729 | 10.1809 | 3172.44 | 3393.62
W0 | 2FL | W0 | W0 | 機械室 | ＜ゾーン番号＞ | no | 2FL | 2 | 3FL | 配置フロア + 1 | 配置フロア + 1 (3FL) | 9100 | 2300 | 2.175 | 20.01 | 20.01 | 5.0025 | 5.0025 | 3000 | 20.01 | 8700 | 6.9375 | 18700 | 5300 | 3000 | 0 | 0 | 2 | 0 | 0 | 0 | 0 | 2.175 | 20.01 | 0 | 9175 | 9100 | 20.01 | 9100 | 27.75 | 27.75 | 9100 | 9100
W1 | 2FL | W1 | W1 | 廊下 | ＜ゾーン番号＞ | no | 2FL | 2 | 3FL | 配置フロア + 1 | 配置フロア + 1 (3FL) | 8500 | 2650 | 1.925 | 19.0575 | 19.0575 | 4.83175 | 4.83175 | 3000 | 20.405 | 7700 | 6.4875 | 17583.1 | 5650 | 3000 | 0 | 0 | 2 | 0 | 0 | 0 | 0 | 1.925 | 17.71 | 2.78557e-09 | 8500 | 8350 | 17.71 | 8650 | 25.95 | 25.95 | 8350 | 8650
W1 | 3FL | W1 | W1 | 事務室 | 309 | no | 3FL | 3 | 4FL | 配置フロア + 1 | 配置フロア + 1 (4FL) | 4725 | 2650 | 1.05 | 10.395 | 10.395 | 2.6355 | 2.6355 | 6000 | 11.13 | 4200 | 3.6375 | 10053.6 | 8650 | 6000 | 0 | 0 | 2 | 0 | 0 | 0 | 0 | 1.05 | 9.66 | 0 | 4725 | 4850 | 9.66 | 4600 | 14.55 | 14.55 | 4850 | 4600
W0 | 3FL | W0 | W0 | 事務室 | 307 | no | 3FL | 3 | 4FL | 配置フロア + 1 | 配置フロア + 1 (4FL) | 9175 | 2650 | 1.635 | 19.0575 | 16.5867 | 4.83175 | 4.21405 | 6000 | 17.9342 | 7700 | 6.975 | 18953.6 | 8650 | 6000 | 0 | 1 | 2 | 2.66295 | 1100 | 2.4708 | 2.4708 | 1.635 | 15.2392 | 0.6177 | 9175 | 7890 | 15.2392 | 8140 | 27.9 | 27.9 | 9050 | 9300
W0 | 3FL | W0 | W0 | 事務室 | 308 | no | 3FL | 3 | 4FL | 配置フロア + 1 | 配置フロア + 1 (4FL) | 5275 | 2650 | 1.05 | 10.395 | 10.395 | 2.6355 | 2.6355 | 6000 | 11.13 | 4200 | 4.05 | 11153.6 | 8650 | 6000 | 0 | 0 | 2 | 0 | 0 | 0 | 0 | 1.05 | 9.66 | 0 | 5275 | 5150 | 9.66 | 5400 | 16.2 | 16.2 | 5150 | 5400
W2 | 3FL | W2 | W2 | 事務室 | 316 | no | 3FL | 3 | 4FL | 配置フロア + 1 | 配置フロア + 1 (4FL) | 9625 | 2650 | 2.175 | 21.5325 | 21.5325 | 5.45925 | 5.45925 | 6000 | 23.055 | 8700 | 7.3125 | 19853.6 | 8650 | 6000 | 0 | 0 | 2 | 0 | 0 | 0 | 0 | 2.175 | 20.01 | 0 | 9625 | 9750 | 20.01 | 9500 | 29.25 | 29.25 | 9750 | 9500
W1 | 3FL | W1 | W1 | 事務室 | 301 | no | 3FL | 3 | 4FL | 配置フロア + 1 | 配置フロア + 1 (4FL) | 9150 | 2650 | 1.925 | 19.0575 | 19.0575 | 4.83175 | 4.83175 | 6000 | 20.405 | 7700 | 6.975 | 18800 | 8650 | 6000 | 0 | 0 | 2 | 0 | 0 | 0 | 0 | 1.925 | 17.71 | 0 | 9225 | 9150 | 17.71 | 9150 | 27.9 | 27.9 | 9150 | 9150
4FLW1 | 4FL | W1 | 4FLW1 | 事務室 | 309 | yes | 4FL | 4 | リンクなし | リンクなし | リンクなし | 4725 | 2650 | 1.05 | 10.395 | 10.395 | 2.6355 | 2.6355 | 9000 | 11.13 | 4200 | 3.6375 | 10053.6 | 11650 | 9000 | 0 | 0 | 2 | 0 | 0 | 0 | 0 | 1.05 | 9.66 | 0 | 4725 | 4850 | 9.66 | 4600 | 14.55 | 14.55 | 4850 | 4600 | ArchiCADProperties - ホットリンク マスタID: 4FL
4FLW0 | 4FL | W0 | 4FLW0 | 事務室 | 307 | yes | 4FL | 4 | リンクなし | リンクなし | リンクなし | 9175 | 2650 | 1.635 | 19.0575 | 16.5867 | 4.83175 | 4.21405 | 9000 | 17.9342 | 7700 | 6.975 | 18953.6 | 11650 | 9000 | 0 | 1 | 2 | 2.66295 | 1100 | 2.4708 | 2.4708 | 1.635 | 15.2392 | 0.6177 | 9175 | 7890 | 15.2392 | 8140 | 27.9 | 27.9 | 9050 | 9300 | ArchiCADProperties - ホットリンク マスタID: 4FL
4FLW0 | 4FL | W0 | 4FLW0 | 事務室 | 308 | yes | 4FL | 4 | リンクなし | リンクなし | リンクなし | 5275 | 2650 | 1.05 | 10.395 | 10.395 | 2.6355 | 2.6355 | 9000 | 11.13 | 4200 | 4.05 | 11153.6 | 11650 | 9000 | 0 | 0 | 2 | 0 | 0 | 0 | 0 | 1.05 | 9.66 | 0 | 5275 | 5150 | 9.66 | 5400 | 16.2 | 16.2 | 5150 | 5400 | ArchiCADProperties - ホットリンク マスタID: 4FL
4FLW2 | 4FL | W2 | 4FLW2 | 事務室 | 316 | yes | 4FL | 4 | リンクなし | リンクなし | リンクなし | 9625 | 2650 | 2.175 | 21.5325 | 21.5325 | 5.45925 | 5.45925 | 9000 | 23.055 | 8700 | 7.3125 | 19853.6 | 11650 | 9000 | 0 | 0 | 2 | 0 | 0 | 0 | 0 | 2.175 | 20.01 | 0 | 9625 | 9750 | 20.01 | 9500 | 29.25 | 29.25 | 9750 | 9500 | ArchiCADProperties - ホットリンク マスタID: 4FL
4FLW1 | 4FL | W1 | 4FLW1 | 事務室 | 301 | yes | 4FL | 4 | リンクなし | リンクなし | リンクなし | 9150 | 2650 | 1.925 | 19.0575 | 19.0575 | 4.83175 | 4.83175 | 9000 | 20.405 | 7700 | 6.975 | 18800 | 11650 | 9000 | 0 | 0 | 2 | 0 | 0 | 0 | 0 | 1.925 | 17.71 | 0 | 9225 | 9150 | 17.71 | 9150 | 27.9 | 27.9 | 9150 | 9150 | ArchiCADProperties - ホットリンク マスタID: 4FL
5FLW1 | 5FL | W1 | 5FLW1 | 事務室 | 309 | yes | 5FL | 5 | リンクなし | リンクなし | リンクなし | 4725 | 2650 | 1.05 | 10.395 | 10.395 | 2.6355 | 2.6355 | 12000 | 11.13 | 4200 | 3.6375 | 10053.6 | 14650 | 12000 | 0 | 0 | 2 | 0 | 0 | 0 | 0 | 1.05 | 9.66 | 0 | 4725 | 4850 | 9.66 | 4600 | 14.55 | 14.55 | 4850 | 4600 | ArchiCADProperties - ホットリンク マスタID: 5FL
5FLW0 | 5FL | W0 | 5FLW0 | 事務室 | 307 | yes | 5FL | 5 | リンクなし | リンクなし | リンクなし | 9175 | 2650 | 1.635 | 19.0575 | 16.5867 | 4.83175 | 4.21405 | 12000 | 17.9342 | 7700 | 6.975 | 18953.6 | 14650 | 12000 | 0 | 1 | 2 | 2.66295 | 1100 | 2.4708 | 2.4708 | 1.635 | 15.2392 | 0.6177 | 9175 | 7890 | 15.2392 | 8140 | 27.9 | 27.9 | 9050 | 9300 | ArchiCADProperties - ホットリンク マスタID: 5FL
5FLW0 | 5FL | W0 | 5FLW0 | 事務室 | 308 | yes | 5FL | 5 | リンクなし | リンクなし | リンクなし | 5275 | 2650 | 1.05 | 10.395 | 10.395 | 2.6355 | 2.6355 | 12000 | 11.13 | 4200 | 4.05 | 11153.6 | 14650 | 12000 | 0 | 0 | 2 | 0 | 0 | 0 | 0 | 1.05 | 9.66 | 0 | 5275 | 5150 | 9.66 | 5400 | 16.2 | 16.2 | 5150 | 5400 | ArchiCADProperties - ホットリンク マスタID: 5FL
5FLW2 | 5FL | W2 | 5FLW2 | 事務室 | 316 | yes | 5FL | 5 | リンクなし | リンクなし | リンクなし | 9625 | 2650 | 2.175 | 21.5325 | 21.5325 | 5.45925 | 5.45925 | 12000 | 23.055 | 8700 | 7.3125 | 19853.6 | 14650 | 12000 | 0 | 0 | 2 | 0 | 0 | 0 | 0 | 2.175 | 20.01 | 0 | 9625 | 9750 | 20.01 | 9500 | 29.25 | 29.25 | 9750 | 9500 | ArchiCADProperties - ホットリンク マスタID: 5FL
5FLW1 | 5FL | W1 | 5FLW1 | 事務室 | 301 | yes | 5FL | 5 | リンクなし | リンクなし | リンクなし | 9150 | 2650 | 1.925 | 19.0575 | 19.0575 | 4.83175 | 4.83175 | 12000 | 20.405 | 7700 | 6.975 | 18800 | 14650 | 12000 | 0 | 0 | 2 | 0 | 0 | 0 | 0 | 1.925 | 17.71 | 0 | 9225 | 9150 | 17.71 | 9150 | 27.9 | 27.9 | 9150 | 9150 | ArchiCADProperties - ホットリンク マスタID: 5FL
6FLW1 | 6FL | W1 | 6FLW1 | 事務室 | 309 | yes | 6FL | 6 | リンクなし | リンクなし | リンクなし | 4725 | 2650 | 1.05 | 10.395 | 10.395 | 2.6355 | 2.6355 | 15000 | 11.13 | 4200 | 3.6375 | 10053.6 | 17650 | 15000 | 0 | 0 | 2 | 0 | 0 | 0 | 0 | 1.05 | 9.66 | 0 | 4725 | 4850 | 9.66 | 4600 | 14.55 | 14.55 | 4850 | 4600 | ArchiCADProperties - ホットリンク マスタID: 6FL
6FLW0 | 6FL | W0 | 6FLW0 | 事務室 | 307 | yes | 6FL | 6 | リンクなし | リンクなし | リンクなし | 9175 | 2650 | 1.635 | 19.0575 | 16.5867 | 4.83175 | 4.21405 | 15000 | 17.9342 | 7700 | 6.975 | 18953.6 | 17650 | 15000 | 0 | 1 | 2 | 2.66295 | 1100 | 2.4708 | 2.4708 | 1.635 | 15.2392 | 0.6177 | 9175 | 7890 | 15.2392 | 8140 | 27.9 | 27.9 | 9050 | 9300 | ArchiCADProperties - ホットリンク マスタID: 6FL
6FLW0 | 6FL | W0 | 6FLW0 | 事務室 | 308 | yes | 6FL | 6 | リンクなし | リンクなし | リンクなし | 5275 | 2650 | 1.05 | 10.395 | 10.395 | 2.6355 | 2.6355 | 15000 | 11.13 | 4200 | 4.05 | 11153.6 | 17650 | 15000 | 0 | 0 | 2 | 0 | 0 | 0 | 0 | 1.05 | 9.66 | 0 | 5275 | 5150 | 9.66 | 5400 | 16.2 | 16.2 | 5150 | 5400 | ArchiCADProperties - ホットリンク マスタID: 6FL
6FLW2 | 6FL | W2 | 6FLW2 | 事務室 | 316 | yes | 6FL | 6 | リンクなし | リンクなし | リンクなし | 9625 | 2650 | 2.175 | 21.5325 | 21.5325 | 5.45925 | 5.45925 | 15000 | 23.055 | 8700 | 7.3125 | 19853.6 | 17650 | 15000 | 0 | 0 | 2 | 0 | 0 | 0 | 0 | 2.175 | 20.01 | 0 | 9625 | 9750 | 20.01 | 9500 | 29.25 | 29.25 | 9750 | 9500 | ArchiCADProperties - ホットリンク マスタID: 6FL
6FLW1 | 6FL | W1 | 6FLW1 | 事務室 | 301 | yes | 6FL | 6 | リンクなし | リンクなし | リンクなし | 9150 | 2650 | 1.925 | 19.0575 | 19.0575 | 4.83175 | 4.83175 | 15000 | 20.405 | 7700 | 6.975 | 18800 | 17650 | 15000 | 0 | 0 | 2 | 0 | 0 | 0 | 0 | 1.925 | 17.71 | 0 | 9225 | 9150 | 17.71 | 9150 | 27.9 | 27.9 | 9150 | 9150 | ArchiCADProperties - ホットリンク マスタID: 6FL
7FLW1 | 7FL | W1 | 7FLW1 | 事務室 | 309 | yes | 7FL | 7 | リンクなし | リンクなし | リンクなし | 4725 | 2650 | 1.05 | 10.395 | 10.395 | 2.6355 | 2.6355 | 18000 | 11.13 | 4200 | 3.6375 | 10053.6 | 20650 | 18000 | 0 | 0 | 2 | 0 | 0 | 0 | 0 | 1.05 | 9.66 | 0 | 4725 | 4850 | 9.66 | 4600 | 14.55 | 14.55 | 4850 | 4600 | ArchiCADProperties - ホットリンク マスタID: 7FL
7FLW0 | 7FL | W0 | 7FLW0 | 事務室 | 307 | yes | 7FL | 7 | リンクなし | リンクなし | リンクなし | 9175 | 2650 | 1.635 | 19.0575 | 16.5867 | 4.83175 | 4.21405 | 18000 | 17.9342 | 7700 | 6.975 | 18953.6 | 20650 | 18000 | 0 | 1 | 2 | 2.66295 | 1100 | 2.4708 | 2.4708 | 1.635 | 15.2392 | 0.6177 | 9175 | 7890 | 15.2392 | 8140 | 27.9 | 27.9 | 9050 | 9300 | ArchiCADProperties - ホットリンク マスタID: 7FL
7FLW0 | 7FL | W0 | 7FLW0 | 事務室 | 308 | yes | 7FL | 7 | リンクなし | リンクなし | リンクなし | 5275 | 2650 | 1.05 | 10.395 | 10.395 | 2.6355 | 2.6355 | 18000 | 11.13 | 4200 | 4.05 | 11153.6 | 20650 | 18000 | 0 | 0 | 2 | 0 | 0 | 0 | 0 | 1.05 | 9.66 | 0 | 5275 | 5150 | 9.66 | 5400 | 16.2 | 16.2 | 5150 | 5400 | ArchiCADProperties - ホットリンク マスタID: 7FL
7FLW2 | 7FL | W2 | 7FLW2 | 事務室 | 316 | yes | 7FL | 7 | リンクなし | リンクなし | リンクなし | 9625 | 2650 | 2.175 | 21.5325 | 21.5325 | 5.45925 | 5.45925 | 18000 | 23.055 | 8700 | 7.3125 | 19853.6 | 20650 | 18000 | 0 | 0 | 2 | 0 | 0 | 0 | 0 | 2.175 | 20.01 | 0 | 9625 | 9750 | 20.01 | 9500 | 29.25 | 29.25 | 9750 | 9500 | ArchiCADProperties - ホットリンク マスタID: 7FL
7FLW1 | 7FL | W1 | 7FLW1 | 事務室 | 301 | yes | 7FL | 7 | リンクなし | リンクなし | リンクなし | 9150 | 2650 | 1.925 | 19.0575 | 19.0575 | 4.83175 | 4.83175 | 18000 | 20.405 | 7700 | 6.975 | 18800 | 20650 | 18000 | 0 | 0 | 2 | 0 | 0 | 0 | 0 | 1.925 | 17.71 | 0 | 9225 | 9150 | 17.71 | 9150 | 27.9 | 27.9 | 9150 | 9150 | ArchiCADProperties - ホットリンク マスタID: 7FL
8FLW1 | 8FL | W1 | 8FLW1 | 事務室 | 309 | yes | 8FL | 8 | リンクなし | リンクなし | リンクなし | 4725 | 2650 | 1.05 | 10.395 | 10.395 | 2.6355 | 2.6355 | 21000 | 11.13 | 4200 | 3.6375 | 10053.6 | 23650 | 21000 | 0 | 0 | 2 | 0 | 0 | 0 | 0 | 1.05 | 9.66 | 0 | 4725 | 4850 | 9.66 | 4600 | 14.55 | 14.55 | 4850 | 4600 | ArchiCADProperties - ホットリンク マスタID: 8FL
8FLW0 | 8FL | W0 | 8FLW0 | 事務室 | 307 | yes | 8FL | 8 | リンクなし | リンクなし | リンクなし | 9175 | 2650 | 1.635 | 19.0575 | 16.5867 | 4.83175 | 4.21405 | 21000 | 17.9342 | 7700 | 6.975 | 18953.6 | 23650 | 21000 | 0 | 1 | 2 | 2.66295 | 1100 | 2.4708 | 2.4708 | 1.635 | 15.2392 | 0.6177 | 9175 | 7890 | 15.2392 | 8140 | 27.9 | 27.9 | 9050 | 9300 | ArchiCADProperties - ホットリンク マスタID: 8FL
8FLW0 | 8FL | W0 | 8FLW0 | 事務室 | 308 | yes | 8FL | 8 | リンクなし | リンクなし | リンクなし | 5275 | 2650 | 1.05 | 10.395 | 10.395 | 2.6355 | 2.6355 | 21000 | 11.13 | 4200 | 4.05 | 11153.6 | 23650 | 21000 | 0 | 0 | 2 | 0 | 0 | 0 | 0 | 1.05 | 9.66 | 0 | 5275 | 5150 | 9.66 | 5400 | 16.2 | 16.2 | 5150 | 5400 | ArchiCADProperties - ホットリンク マスタID: 8FL
8FLW2 | 8FL | W2 | 8FLW2 | 事務室 | 316 | yes | 8FL | 8 | リンクなし | リンクなし | リンクなし | 9625 | 2650 | 2.175 | 21.5325 | 21.5325 | 5.45925 | 5.45925 | 21000 | 23.055 | 8700 | 7.3125 | 19853.6 | 23650 | 21000 | 0 | 0 | 2 | 0 | 0 | 0 | 0 | 2.175 | 20.01 | 0 | 9625 | 9750 | 20.01 | 9500 | 29.25 | 29.25 | 9750 | 9500 | ArchiCADProperties - ホットリンク マスタID: 8FL
8FLW1 | 8FL | W1 | 8FLW1 | 事務室 | 301 | yes | 8FL | 8 | リンクなし | リンクなし | リンクなし | 9150 | 2650 | 1.925 | 19.0575 | 19.0575 | 4.83175 | 4.83175 | 21000 | 20.405 | 7700 | 6.975 | 18800 | 23650 | 21000 | 0 | 0 | 2 | 0 | 0 | 0 | 0 | 1.925 | 17.71 | 0 | 9225 | 9150 | 17.71 | 9150 | 27.9 | 27.9 | 9150 | 9150 | ArchiCADProperties - ホットリンク マスタID: 8FL
9FLW1 | 9FL | W1 | 9FLW1 | 事務室 | 309 | yes | 9FL | 9 | リンクなし | リンクなし | リンクなし | 4725 | 2650 | 1.05 | 10.395 | 10.395 | 2.6355 | 2.6355 | 24000 | 11.13 | 4200 | 3.6375 | 10053.6 | 26650 | 24000 | 0 | 0 | 2 | 0 | 0 | 0 | 0 | 1.05 | 9.66 | 0 | 4725 | 4850 | 9.66 | 4600 | 14.55 | 14.55 | 4850 | 4600 | ArchiCADProperties - ホットリンク マスタID: 9FL
9FLW0 | 9FL | W0 | 9FLW0 | 事務室 | 307 | yes | 9FL | 9 | リンクなし | リンクなし | リンクなし | 9175 | 2650 | 1.635 | 19.0575 | 16.5867 | 4.83175 | 4.21405 | 24000 | 17.9342 | 7700 | 6.975 | 18953.6 | 26650 | 24000 | 0 | 1 | 2 | 2.66295 | 1100 | 2.4708 | 2.4708 | 1.635 | 15.2392 | 0.6177 | 9175 | 7890 | 15.2392 | 8140 | 27.9 | 27.9 | 9050 | 9300 | ArchiCADProperties - ホットリンク マスタID: 9FL
9FLW0 | 9FL | W0 | 9FLW0 | 事務室 | 308 | yes | 9FL | 9 | リンクなし | リンクなし | リンクなし | 5275 | 2650 | 1.05 | 10.395 | 10.395 | 2.6355 | 2.6355 | 24000 | 11.13 | 4200 | 4.05 | 11153.6 | 26650 | 24000 | 0 | 0 | 2 | 0 | 0 | 0 | 0 | 1.05 | 9.66 | 0 | 5275 | 5150 | 9.66 | 5400 | 16.2 | 16.2 | 5150 | 5400 | ArchiCADProperties - ホットリンク マスタID: 9FL
9FLW2 | 9FL | W2 | 9FLW2 | 事務室 | 316 | yes | 9FL | 9 | リンクなし | リンクなし | リンクなし | 9625 | 2650 | 2.175 | 21.5325 | 21.5325 | 5.45925 | 5.45925 | 24000 | 23.055 | 8700 | 7.3125 | 19853.6 | 26650 | 24000 | 0 | 0 | 2 | 0 | 0 | 0 | 0 | 2.175 | 20.01 | 0 | 9625 | 9750 | 20.01 | 9500 | 29.25 | 29.25 | 9750 | 9500 | ArchiCADProperties - ホットリンク マスタID: 9FL
9FLW1 | 9FL | W1 | 9FLW1 | 事務室 | 301 | yes | 9FL | 9 | リンクなし | リンクなし | リンクなし | 9150 | 2650 | 1.925 | 19.0575 | 19.0575 | 4.83175 | 4.83175 | 24000 | 20.405 | 7700 | 6.975 | 18800 | 26650 | 24000 | 0 | 0 | 2 | 0 | 0 | 0 | 0 | 1.925 | 17.71 | 0 | 9225 | 9150 | 17.71 | 9150 | 27.9 | 27.9 | 9150 | 9150 | ArchiCADProperties - ホットリンク マスタID: 9FL

# IfcWall: コンクリート 300 (2)
Classification: 壁 (ARCHICAD 分類); Material: コンクリート
ArchiCADProperties - 要素ID: W9; ホットリンクおよび要素ID: W9; レイヤー: 壁-躯体; ビルディングマテリアル/複合構造/断面形状/塗りつぶし: コンクリート; ビルディングマテリアル: コンクリート; 関連ゾーン名: ホール; 関連ゾーン番号: ＜ゾーン番号＞; ロック状態: no; 要素タイプ: 壁; 相対上部リンクフロア: 配置フロア + 1; 構造タイプ: 基本; 親ID: W9; ビルディングマテリアル (全て): コンクリート; 材質 (全て): コンクリート - 04; 傾斜角度: 90 deg; 開口部の数: 0; リノベーションフィルタで表示: 全ての関連フィルタ; 構造機能: 非構造耐力要素; 位置: インテリア; リノベーションステータス: 既存; 壁形状: 直線; 図形作成法: 均一; 基準線位置: 中央; 辺材質: コンクリート - 04; 内面材質: コンクリート - 04; 外面材質: コンクリート - 04; 壁内側傾斜角度: 90 deg; 壁外側傾斜角度: 90 deg; ARCHICAD 分類 - v 2.0: 壁
仕上情報 - WEBサイト: www.graphisoft.co.jp
AC_Pset_RenovationAndPhasing - Renovation Status: Existing
Pset_WallCommon - LoadBearing: no; IsExternal: no
BaseQuantities - Length: 2325 mm; Width: 300 mm
ArchiCADQuantities - 高さ: 3000 mm; 幅: 300 mm; リンク/配置フロアまでの高度: 0 mm; 下部オフセット: 0 mm; 上部オフセット: 0 mm; 厚さ: 300 mm; 壁断熱材厚: 0 mm; 下端高度から配置フロア: 0 mm; ドア数: 0; 穴数(単純開口数): 0; 窓数: 0; 柱数: 0; 柱体積: 0 m3; 最大内面層の高さ: 0 mm; 最小内面層の高さ: 0 mm; 最大外面層の高さ: 0 mm; 最小外面層の高さ: 0 mm; 空気層厚さ: 0 mm; ドア面積: 0 m2; ドア総幅: 0 mm; 内面壁層の厚さ: 0 mm; 外面壁層の厚さ: 0 mm; 窓面積: 0 m2; 窓総幅: 0 mm; 内面分析的開口面積: 0 m2; 外面分析的開口面積: 0 m2; 壁平均長: 2325 mm; 開口部分解法体積: 0 m3; 基準線長さ: 2325 mm; 壁終点厚さ: 300 mm; 壁中心長さ: 2325 mm; 壁内開口面積: 0 m2
Name | In | ホームフロア名 | ホームフロア数 | 絶対上部リンクフロア | 上部リンクフロア | Height (mm) = 上端高度から配置フロア (mm) = 壁最大高さ (mm) | GrossFootprintArea (m2) = NetFootprintArea (m2) = 面積 (m2) | GrossSideArea (m2) = NetSideArea (m2) = 表面積 (m2) = 内面正味表面積 (m2) = 外面正味表面積 (m2) = 条件付き内面表面積 (m2) = 条件付き外面表面積 (m2) | GrossVolume (m3) = NetVolume (m3) = 正味体積 (m3) = 条件付き体積 (m3) | GLからの高度 (mm) = 高度 1 (mm) = 高度 2 (mm) = 海抜までの高度 (mm) = 下端高度から第1基準レベル (mm) = 下端高度から基準レベル (mm) = 下端高度から海抜 (mm) = 下端高度から第2基準レベル (mm) | 3D長さ (mm) = 条件付き外面長さ (mm) = 外面壁長さ (mm) | 総体積 (m3) | 平面図外周 (mm) | 上端高度から第1基準レベル (mm) = 上端高度から基準レベル (mm) = 上端高度から海抜 (mm) = 上端高度から第2基準レベル (mm) | 壁最小高さ (mm) | 辺の正味表面積 (m2) | 条件付き内面長さ (mm) = 内面壁長さ (mm) | 内面総壁表面積 (m2) = 外面総壁表面積 (m2)
W9 | 1FL | 1FL | 1 | 2FL | 配置フロア + 1 (2FL) | 3000 | 0.6975 | 6.94875 | 2.08462 | 0 | 2325 | 2.0925 | 5250 | 3000 | 2650 | 3.0675 | 2325 | 6.975
W9 | 2FL | 2FL | 2 | 3FL | 配置フロア + 1 (3FL) | 2650 | 0.72 | 6.36 | 1.908 | 3000 | 2400 | 2.16 | 5285.41 | 5650 | 0 | 1.515 | 2250 | 7.2

# IfcWall: 石膏ボード 100 (98)
Classification: 壁 (ARCHICAD 分類); Material: 石膏ボード
ArchiCADProperties - レイヤー: 壁-間仕切り; ビルディングマテリアル/複合構造/断面形状/塗りつぶし: 石膏ボード; ビルディングマテリアル: 石膏ボード; 要素タイプ: 壁; 構造タイプ: 基本; ビルディングマテリアル (全て): 石膏ボード; 材質 (全て): 漆喰 - 白 ファイン; 傾斜角度: 90 deg; 開口部の数: 0; リノベーションフィルタで表示: 全ての関連フィルタ; 構造機能: 非構造耐力要素; 位置: インテリア; リノベーションステータス: 既存; 壁形状: 直線; 図形作成法: 均一; 基準線位置: 中央; 辺材質: 漆喰 - 白 ファイン; 内面材質: 漆喰 - 白 ファイン; 外面材質: 漆喰 - 白 ファイン; 壁内側傾斜角度: 90 deg; 壁外側傾斜角度: 90 deg; ARCHICAD 分類 - v 2.0: 壁
仕上情報 - WEBサイト: www.graphisoft.co.jp
AC_Pset_RenovationAndPhasing - Renovation Status: Existing
Pset_WallCommon - LoadBearing: no; IsExternal: no
BaseQuantities - Width: 100 mm
ArchiCADQuantities - 高さ: 3000 mm; 幅: 100 mm; リンク/配置フロアまでの高度: 0 mm; 下部オフセット: 0 mm; 上部オフセット: 0 mm; 厚さ: 100 mm; 壁断熱材厚: 0 mm; ドア数: 0; 穴数(単純開口数): 0; 窓数: 0; 柱体積: 0 m3; 最大内面層の高さ: 0 mm; 最小内面層の高さ: 0 mm; 壁最小高さ: 0 mm; 最大外面層の高さ: 0 mm; 最小外面層の高さ: 0 mm; 空気層厚さ: 0 mm; ドア面積: 0 m2; ドア総幅: 0 mm; 内面壁層の厚さ: 0 mm; 外面壁層の厚さ: 0 mm; 窓面積: 0 m2; 窓総幅: 0 mm; 内面分析的開口面積: 0 m2; 外面分析的開口面積: 0 m2; 開口部分解法体積: 0 m3; 壁終点厚さ: 100 mm; 壁内開口面積: 0 m2
Name | In | 要素ID = 親ID | ホットリンクおよび要素ID | 関連ゾーン名 | 関連ゾーン番号 | ロック状態 | ホームフロア名 | ホームフロア数 | 絶対上部リンクフロア | 相対上部リンクフロア | 上部リンクフロア | Length (mm) = 壁平均長 (mm) = 壁中心長さ (mm) | Height (mm) = 上端高度から配置フロア (mm) = 壁最大高さ (mm) | GrossFootprintArea (m2) = NetFootprintArea (m2) = 面積 (m2) | GrossSideArea (m2) = NetSideArea (m2) | GrossVolume (m3) = NetVolume (m3) = 正味体積 (m3) = 条件付き体積 (m3) | GLからの高度 (mm) = 高度 1 (mm) = 高度 2 (mm) = 海抜までの高度 (mm) = 下端高度から第1基準レベル (mm) = 下端高度から基準レベル (mm) = 下端高度から海抜 (mm) = 下端高度から第2基準レベル (mm) | 表面積 (m2) = 外面正味表面積 (m2) = 条件付き外面表面積 (m2) | 3D長さ (mm) | 総体積 (m3) | 平面図外周 (mm) | 上端高度から第1基準レベル (mm) = 上端高度から基準レベル (mm) = 上端高度から海抜 (mm) = 上端高度から第2基準レベル (mm) | 下端高度から配置フロア (mm) | 柱数 | 辺の正味表面積 (m2) | 内面正味表面積 (m2) = 条件付き内面表面積 (m2) | 基準線長さ (mm) | 条件付き内面長さ (mm) = 内面壁長さ (mm) | 条件付き外面長さ (mm) = 外面壁長さ (mm) | 内面総壁表面積 (m2) | 外面総壁表面積 (m2) | ホットリンク マスタID
W14 | 1FL | W14 | W14 | 店舗 | 102 | no | 1FL | 1 | 2FL | 配置フロア + 1 | 配置フロア + 1 (2FL) | 9163.22 | 2300 | 0.803333 | 18.4767 | 1.84767 | 0 | 18.4767 | 8033.33 | 2.87 | 18527.8 | 2300 | 0 | 2 | 0.803333 | 18.4767 | 9364.94 | 9154.88 | 9171.55 | 28.675 | 28.725
W15 | 1FL | W15 | W15 | 店舗 | 104 | no | 1FL | 1 | 2FL | 配置フロア + 1 | 配置フロア + 1 (2FL) | 8400 | 2300 | 0.72 | 16.56 | 1.656 | 0 | 16.56 | 7200 | 2.64 | 17000 | 2300 | 0 | 2 | 0.72 | 16.56 | 8600 | 8400 | 8400 | 26.4 | 26.4
W15 | 2FL | W15 | W15 | 店舗 | 214 | no | 2FL | 2 | 3FL | 配置フロア + 1 | 配置フロア + 1 (3FL) | 5612.78 | 2500 | 0.508872 | 12.7218 | 1.27218 | 3000 | 12.7218 | 5088.72 | 1.7594 | 11426.3 | 5500 | 0 | 2 | 0.508872 | 12.7218 | 5738.72 | 5618.92 | 5606.64 | 17.6124 | 17.5756
W15 | 2FL | W15 | W15 | 店舗 | 204 | no | 2FL | 2 | 3FL | 配置フロア + 1 | 配置フロア + 1 (3FL) | 6575 | 2300 | 0.5925 | 13.6275 | 1.36275 | 3000 | 13.6275 | 5925 | 2.0625 | 13350 | 5300 | 0 | 1 | 0.5925 | 13.6275 | 6725 | 6575 | 6575 | 20.625 | 20.625
W13 | 2FL | W13 | W13 | 店舗 | 201 | no | 2FL | 2 | 3FL | 配置フロア + 1 | 配置フロア + 1 (3FL) | 9996.55 | 2300 | 0.886667 | 20.3933 | 2.03933 | 3000 | 20.3933 | 8866.67 | 3.12 | 20194.5 | 5300 | 0 | 2 | 0.886667 | 20.3933 | 10198.3 | 9988.22 | 10004.9 | 31.175 | 31.225
W14 | 2FL | W14 | W14 | 店舗 | 202 | no | 2FL | 2 | 3FL | 配置フロア + 1 | 配置フロア + 1 (3FL) | 9163.22 | 2300 | 0.803333 | 18.4767 | 1.84767 | 3000 | 18.4767 | 8033.33 | 2.9 | 18527.8 | 5300 | 0 | 2 | 0.803333 | 18.4767 | 9364.94 | 9154.88 | 9171.55 | 28.975 | 29.025
W15 | 2FL | W15 | W15 | 店舗 | 212 | no | 2FL | 2 | 3FL | 配置フロア + 1 | 配置フロア + 1 (3FL) | 4998.86 | 2500 | 0.44748 | 11.187 | 1.1187 | 3000 | 11.187 | 4474.8 | 1.57522 | 10198.5 | 5500 | 0 | 2 | 0.44748 | 11.187 | 5124.8 | 4992.72 | 5005 | 15.7338 | 15.7706
W15 | 2FL | W15 | W15 | 店舗 | 211 | no | 2FL | 2 | 3FL | 配置フロア + 1 | 配置フロア + 1 (3FL) | 4384.94 | 2500 | 0.386088 | 9.65219 | 0.965219 | 3000 | 9.65219 | 3860.88 | 1.39104 | 8970.62 | 5500 | 0 | 2 | 0.386088 | 9.65219 | 4510.88 | 4378.8 | 4391.08 | 13.892 | 13.9289
W15 | 2FL | W15 | W15 | 店舗 | 211 | no | 2FL | 2 | 3FL | 配置フロア + 1 | 配置フロア + 1 (3FL) | 7325 | 2300 | 0.6925 | 15.9275 | 1.59275 | 3000 | 15.9275 | 6925 | 2.2425 | 14850 | 5300 | 0 | 1 | 0.6925 | 15.9275 | 7400 | 7325 | 7325 | 22.425 | 22.425
W15 | 2FL | W15 | W15 | 店舗 | 212 | no | 2FL | 2 | 3FL | 配置フロア + 1 | 配置フロア + 1 (3FL) | 7325 | 2300 | 0.6925 | 15.9275 | 1.59275 | 3000 | 15.9275 | 6925 | 2.2425 | 14850 | 5300 | 0 | 1 | 0.6925 | 15.9275 | 7400 | 7325 | 7325 | 22.425 | 22.425
W15 | 2FL | W15 | W15 | 店舗 | 214 | no | 2FL | 2 | 3FL | 配置フロア + 1 | 配置フロア + 1 (3FL) | 7325 | 2300 | 0.6925 | 15.9275 | 1.59275 | 3000 | 15.9275 | 6925 | 2.2425 | 14850 | 5300 | 0 | 1 | 0.6925 | 15.9275 | 7400 | 7325 | 7325 | 22.425 | 22.425
W15 | 2FL | W15 | W15 | 店舗 | 209 | no | 2FL | 2 | 3FL | 配置フロア + 1 | 配置フロア + 1 (3FL) | 6475 | 2300 | 0.5925 | 13.6275 | 1.36275 | 3000 | 13.6275 | 5925 | 2.0625 | 13150 | 5300 | 0 | 1 | 0.5925 | 13.6275 | 6675 | 6475 | 6475 | 20.625 | 20.625
W16 | 2FL | W16 | W16 | 店舗 | 207 | no | 2FL | 2 | 3FL | 配置フロア + 1 | 配置フロア + 1 (3FL) | 7163.7 | 2650 | 0.571545 | 13.164 | 1.3151 | 3000 | 13.2181 | 5740.79 | 2.27928 | 14540.9 | 5650 | -4.44089e-13 | 2 | 0.571545 | 13.11 | 7380.52 | 7136.84 | 7190.55 | 22.7126 | 22.8704
W17 | 2FL | W17 | W17 | 店舗 | 206 | no | 2FL | 2 | 3FL | 配置フロア + 1 | 配置フロア + 1 (3FL) | 8400 | 2300 | 0.72 | 16.56 | 1.656 | 3000 | 16.56 | 7200 | 2.64 | 17000 | 5300 | 0 | 2 | 0.72 | 16.56 | 8600 | 8400 | 8400 | 26.4 | 26.4
W13 | 3FL | W13 | W13 | 事務室 | 302 | no | 3FL | 3 | 4FL | 配置フロア + 1 | 配置フロア + 1 (4FL) | 10974.7 | 3000 | 0.952466 | 22.4303 | 2.24295 | 6000 | 22.4287 | 9524.66 | 3.3674 | 22149.3 | 9000 | 0 | 2 | 1.2352 | 22.4319 | 11049.7 | 10974.7 | 10974.7 | 33.674 | 33.674
W12 | 3FL | W12 | W12 | 事務室 | 305 | no | 3FL | 3 | 4FL | 配置フロア + 1 | 配置フロア + 1 (4FL) | 10050 | 2650 | 0.86 | 20.27 | 2.027 | 6000 | 20.27 | 8600 | 3.06 | 20300 | 8650 | 0 | 2 | 1.125 | 20.27 | 10125 | 10050 | 10050 | 30.6 | 30.6
W11 | 3FL | W11 | W11 | 事務室 | 304 | no | 3FL | 3 | 4FL | 配置フロア + 1 | 配置フロア + 1 (4FL) | 10050 | 2650 | 0.86 | 20.27 | 2.027 | 6000 | 20.27 | 8600 | 3.06 | 20300 | 8650 | 0 | 2 | 1.125 | 20.27 | 10125 | 10050 | 10050 | 30.6 | 30.6
W14 | 3FL | W14 | W14 | 事務室 | 301 | no | 3FL | 3 | 4FL | 配置フロア + 1 | 配置フロア + 1 (4FL) | 11899.3 | 3000 | 1.04493 | 24.589 | 2.45882 | 6000 | 24.5874 | 10449.3 | 3.61479 | 23998.6 | 9000 | 0 | 2 | 1.32766 | 24.5906 | 11974.3 | 11899.3 | 11899.3 | 36.1479 | 36.1479
W13 | 3FL | W13 | W13 | 事務室 | 310 | no | 3FL | 3 | 4FL | 配置フロア + 1 | 配置フロア + 1 (4FL) | 6575 | 2300 | 0.5925 | 13.6275 | 1.36275 | 6000 | 13.6275 | 5925 | 2.0925 | 13350 | 8300 | 0 | 1 | 0.5925 | 13.6275 | 6725 | 6575 | 6575 | 20.925 | 20.925
W10 | 3FL | W10 | W10 | 事務室 | 303 | no | 3FL | 3 | 4FL | 配置フロア + 1 | 配置フロア + 1 (4FL) | 10050 | 2650 | 0.86 | 20.27 | 2.027 | 6000 | 20.27 | 8600 | 3.06 | 20300 | 8650 | 0 | 2 | 1.125 | 20.27 | 10125 | 10050 | 10050 | 30.6 | 30.6
W13 | 3FL | W13 | W13 | 事務室 | 313 | no | 3FL | 3 | 4FL | 配置フロア + 1 | 配置フロア + 1 (4FL) | 8475 | 2650 | 0.7675 | 17.915 | 1.7915 | 6000 | 17.915 | 7675 | 2.6175 | 17150 | 8650 | 0 | 1 | 1.0325 | 17.915 | 8550 | 8475 | 8475 | 26.175 | 26.175
W14 | 3FL | W14 | W14 | 事務室 | 313 | no | 3FL | 3 | 4FL | 配置フロア + 1 | 配置フロア + 1 (4FL) | 8475 | 2650 | 0.7675 | 17.915 | 1.7915 | 6000 | 17.915 | 7675 | 2.5875 | 17150 | 8650 | 0 | 1 | 1.0325 | 17.915 | 8550 | 8475 | 8475 | 25.875 | 25.875
W15 | 3FL | W15 | W15 | 事務室 | 314 | no | 3FL | 3 | 4FL | 配置フロア + 1 | 配置フロア + 1 (4FL) | 8475 | 2650 | 0.7675 | 17.915 | 1.7915 | 6000 | 17.915 | 7675 | 2.5875 | 17150 | 8650 | 0 | 1 | 1.0325 | 17.915 | 8550 | 8475 | 8475 | 25.875 | 25.875
W14 | 3FL | W14 | W14 | 事務室 | 315 | no | 3FL | 3 | 4FL | 配置フロア + 1 | 配置フロア + 1 (4FL) | 8475 | 2650 | 0.7675 | 17.915 | 1.7915 | 6000 | 17.915 | 7675 | 2.5875 | 17150 | 8650 | 0 | 1 | 1.0325 | 17.915 | 8550 | 8475 | 8475 | 25.875 | 25.875
W12 | 3FL | W12 | W12 | 事務室 | 308 | no | 3FL | 3 | 4FL | 配置フロア + 1 | 配置フロア + 1 (4FL) | 6475 | 2300 | 0.5925 | 13.6275 | 1.36275 | 6000 | 13.6275 | 5925 | 2.0625 | 13150 | 8300 | 0 | 1 | 0.5925 | 13.6275 | 6675 | 6475 | 6475 | 20.625 | 20.625
W12 | 3FL | W12 | W12 | 事務室 | 306 | no | 3FL | 3 | 4FL | 配置フロア + 1 | 配置フロア + 1 (4FL) | 8983.01 | 3000 | 0.753301 | 17.9723 | 1.79703 | 6000 | 17.9675 | 7533.01 | 2.7399 | 18166 | 9000 | 0 | 2 | 1.03982 | 17.977 | 9058.01 | 8983.01 | 8983.01 | 27.399 | 27.399
4FLW12 | 4FL | W12 | 4FLW12 | 事務室 | 308 | yes | 4FL | 4 | リンクなし | リンクなし | リンクなし | 6475 | 2300 | 0.5925 | 13.6275 | 1.36275 | 9000 | 13.6275 | 5925 | 2.0625 | 13150 | 11300 | 0 | 1 | 0.5925 | 13.6275 | 6675 | 6475 | 6475 | 20.625 | 20.625 | 4FL
4FLW14 | 4FL | W14 | 4FLW14 | 事務室 | 315 | yes | 4FL | 4 | リンクなし | リンクなし | リンクなし | 8475 | 2650 | 0.7675 | 17.915 | 1.7915 | 9000 | 17.915 | 7675 | 2.5875 | 17150 | 11650 | 0 | 1 | 1.0325 | 17.915 | 8550 | 8475 | 8475 | 25.875 | 25.875 | 4FL
4FLW15 | 4FL | W15 | 4FLW15 | 事務室 | 314 | yes | 4FL | 4 | リンクなし | リンクなし | リンクなし | 8475 | 2650 | 0.7675 | 17.915 | 1.7915 | 9000 | 17.915 | 7675 | 2.5875 | 17150 | 11650 | 0 | 1 | 1.0325 | 17.915 | 8550 | 8475 | 8475 | 25.875 | 25.875 | 4FL
4FLW14 | 4FL | W14 | 4FLW14 | 事務室 | 313 | yes | 4FL | 4 | リンクなし | リンクなし | リンクなし | 8475 | 2650 | 0.7675 | 17.915 | 1.7915 | 9000 | 17.915 | 7675 | 2.5875 | 17150 | 11650 | 0 | 1 | 1.0325 | 17.915 | 8550 | 8475 | 8475 | 25.875 | 25.875 | 4FL
4FLW13 | 4FL | W13 | 4FLW13 | 事務室 | 313 | yes | 4FL | 4 | リンクなし | リンクなし | リンクなし | 8475 | 2650 | 0.7675 | 17.915 | 1.7915 | 9000 | 17.915 | 7675 | 2.6175 | 17150 | 11650 | 0 | 1 | 1.0325 | 17.915 | 8550 | 8475 | 8475 | 26.175 | 26.175 | 4FL
4FLW13 | 4FL | W13 | 4FLW13 | 事務室 | 302 | yes | 4FL | 4 | リンクなし | リンクなし | リンクなし | 10974.7 | 3000 | 0.952466 | 22.4303 | 2.24295 | 9000 | 22.4287 | 9524.66 | 3.3674 | 22149.3 | 12000 | 0 | 2 | 1.2352 | 22.4319 | 11049.7 | 10974.7 | 10974.7 | 33.674 | 33.674 | 4FL
4FLW12 | 4FL | W12 | 4FLW12 | 事務室 | 305 | yes | 4FL | 4 | リンクなし | リンクなし | リンクなし | 10050 | 2650 | 0.86 | 20.27 | 2.027 | 9000 | 20.27 | 8600 | 3.06 | 20300 | 11650 | 0 | 2 | 1.125 | 20.27 | 10125 | 10050 | 10050 | 30.6 | 30.6 | 4FL
4FLW11 | 4FL | W11 | 4FLW11 | 事務室 | 304 | yes | 4FL | 4 | リンクなし | リンクなし | リンクなし | 10050 | 2650 | 0.86 | 20.27 | 2.027 | 9000 | 20.27 | 8600 | 3.06 | 20300 | 11650 | 0 | 2 | 1.125 | 20.27 | 10125 | 10050 | 10050 | 30.6 | 30.6 | 4FL
4FLW14 | 4FL | W14 | 4FLW14 | 事務室 | 301 | yes | 4FL | 4 | リンクなし | リンクなし | リンクなし | 11899.3 | 3000 | 1.04493 | 24.589 | 2.45882 | 9000 | 24.5874 | 10449.3 | 3.61479 | 23998.6 | 12000 | 0 | 2 | 1.32766 | 24.5906 | 11974.3 | 11899.3 | 11899.3 | 36.1479 | 36.1479 | 4FL
4FLW13 | 4FL | W13 | 4FLW13 | 事務室 | 310 | yes | 4FL | 4 | リンクなし | リンクなし | リンクなし | 6575 | 2300 | 0.5925 | 13.6275 | 1.36275 | 9000 | 13.6275 | 5925 | 2.0925 | 13350 | 11300 | 0 | 1 | 0.5925 | 13.6275 | 6725 | 6575 | 6575 | 20.925 | 20.925 | 4FL
4FLW10 | 4FL | W10 | 4FLW10 | 事務室 | 303 | yes | 4FL | 4 | リンクなし | リンクなし | リンクなし | 10050 | 2650 | 0.86 | 20.27 | 2.027 | 9000 | 20.27 | 8600 | 3.06 | 20300 | 11650 | 0 | 2 | 1.125 | 20.27 | 10125 | 10050 | 10050 | 30.6 | 30.6 | 4FL
4FLW12 | 4FL | W12 | 4FLW12 | 事務室 | 306 | yes | 4FL | 4 | リンクなし | リンクなし | リンクなし | 8983.01 | 3000 | 0.753301 | 17.9723 | 1.79703 | 9000 | 17.9675 | 7533.01 | 2.7399 | 18166 | 12000 | 0 | 2 | 1.03982 | 17.977 | 9058.01 | 8983.01 | 8983.01 | 27.399 | 27.399 | 4FL
5FLW12 | 5FL | W12 | 5FLW12 | 事務室 | 308 | yes | 5FL | 5 | リンクなし | リンクなし | リンクなし | 6475 | 2300 | 0.5925 | 13.6275 | 1.36275 | 12000 | 13.6275 | 5925 | 2.0625 | 13150 | 14300 | 0 | 1 | 0.5925 | 13.6275 | 6675 | 6475 | 6475 | 20.625 | 20.625 | 5FL
5FLW14 | 5FL | W14 | 5FLW14 | 事務室 | 315 | yes | 5FL | 5 | リンクなし | リンクなし | リンクなし | 8475 | 2650 | 0.7675 | 17.915 | 1.7915 | 12000 | 17.915 | 7675 | 2.5875 | 17150 | 14650 | 0 | 1 | 1.0325 | 17.915 | 8550 | 8475 | 8475 | 25.875 | 25.875 | 5FL
5FLW15 | 5FL | W15 | 5FLW15 | 事務室 | 314 | yes | 5FL | 5 | リンクなし | リンクなし | リンクなし | 8475 | 2650 | 0.7675 | 17.915 | 1.7915 | 12000 | 17.915 | 7675 | 2.5875 | 17150 | 14650 | 0 | 1 | 1.0325 | 17.915 | 8550 | 8475 | 8475 | 25.875 | 25.875 | 5FL
5FLW14 | 5FL | W14 | 5FLW14 | 事務室 | 313 | yes | 5FL | 5 | リンクなし | リンクなし | リンクなし | 8475 | 2650 | 0.7675 | 17.915 | 1.7915 | 12000 | 17.915 | 7675 | 2.5875 | 17150 | 14650 | 0 | 1 | 1.0325 | 17.915 | 8550 | 8475 | 8475 | 25.875 | 25.875 | 5FL
5FLW13 | 5FL | W13 | 5FLW13 | 事務室 | 313 | yes | 5FL | 5 | リンクなし | リンクなし | リンクなし | 8475 | 2650 | 0.7675 | 17.915 | 1.7915 | 12000 | 17.915 | 7675 | 2.6175 | 17150 | 14650 | 0 | 1 | 1.0325 | 17.915 | 8550 | 8475 | 8475 | 26.175 | 26.175 | 5FL
5FLW13 | 5FL | W13 | 5FLW13 | 事務室 | 302 | yes | 5FL | 5 | リンクなし | リンクなし | リンクなし | 10974.7 | 3000 | 0.952466 | 22.4303 | 2.24295 | 12000 | 22.4287 | 9524.66 | 3.3674 | 22149.3 | 15000 | 0 | 2 | 1.2352 | 22.4319 | 11049.7 | 10974.7 | 10974.7 | 33.674 | 33.674 | 5FL
5FLW12 | 5FL | W12 | 5FLW12 | 事務室 | 305 | yes | 5FL | 5 | リンクなし | リンクなし | リンクなし | 10050 | 2650 | 0.86 | 20.27 | 2.027 | 12000 | 20.27 | 8600 | 3.06 | 20300 | 14650 | 0 | 2 | 1.125 | 20.27 | 10125 | 10050 | 10050 | 30.6 | 30.6 | 5FL
5FLW11 | 5FL | W11 | 5FLW11 | 事務室 | 304 | yes | 5FL | 5 | リンクなし | リンクなし | リンクなし | 10050 | 2650 | 0.86 | 20.27 | 2.027 | 12000 | 20.27 | 8600 | 3.06 | 20300 | 14650 | 0 | 2 | 1.125 | 20.27 | 10125 | 10050 | 10050 | 30.6 | 30.6 | 5FL
5FLW14 | 5FL | W14 | 5FLW14 | 事務室 | 301 | yes | 5FL | 5 | リンクなし | リンクなし | リンクなし | 11899.3 | 3000 | 1.04493 | 24.589 | 2.45882 | 12000 | 24.5874 | 10449.3 | 3.61479 | 23998.6 | 15000 | 0 | 2 | 1.32766 | 24.5906 | 11974.3 | 11899.3 | 11899.3 | 36.1479 | 36.1479 | 5FL
5FLW13 | 5FL | W13 | 5FLW13 | 事務室 | 310 | yes | 5FL | 5 | リンクなし | リンクなし | リンクなし | 6575 | 2300 | 0.5925 | 13.6275 | 1.36275 | 12000 | 13.6275 | 5925 | 2.0925 | 13350 | 14300 | 0 | 1 | 0.5925 | 13.6275 | 6725 | 6575 | 6575 | 20.925 | 20.925 | 5FL
5FLW10 | 5FL | W10 | 5FLW10 | 事務室 | 303 | yes | 5FL | 5 | リンクなし | リンクなし | リンクなし | 10050 | 2650 | 0.86 | 20.27 | 2.027 | 12000 | 20.27 | 8600 | 3.06 | 20300 | 14650 | 0 | 2 | 1.125 | 20.27 | 10125 | 10050 | 10050 | 30.6 | 30.6 | 5FL
5FLW12 | 5FL | W12 | 5FLW12 | 事務室 | 306 | yes | 5FL | 5 | リンクなし | リンクなし | リンクなし | 8983.01 | 3000 | 0.753301 | 17.9723 | 1.79703 | 12000 | 17.9675 | 7533.01 | 2.7399 | 18166 | 15000 | 0 | 2 | 1.03982 | 17.977 | 9058.01 | 8983.01 | 8983.01 | 27.399 | 27.399 | 5FL
6FLW12 | 6FL | W12 | 6FLW12 | 事務室 | 308 | yes | 6FL | 6 | リンクなし | リンクなし | リンクなし | 6475 | 2300 | 0.5925 | 13.6275 | 1.36275 | 15000 | 13.6275 | 5925 | 2.0625 | 13150 | 17300 | 0 | 1 | 0.5925 | 13.6275 | 6675 | 6475 | 6475 | 20.625 | 20.625 | 6FL
6FLW14 | 6FL | W14 | 6FLW14 | 事務室 | 315 | yes | 6FL | 6 | リンクなし | リンクなし | リンクなし | 8475 | 2650 | 0.7675 | 17.915 | 1.7915 | 15000 | 17.915 | 7675 | 2.5875 | 17150 | 17650 | 0 | 1 | 1.0325 | 17.915 | 8550 | 8475 | 8475 | 25.875 | 25.875 | 6FL
6FLW15 | 6FL | W15 | 6FLW15 | 事務室 | 314 | yes | 6FL | 6 | リンクなし | リンクなし | リンクなし | 8475 | 2650 | 0.7675 | 17.915 | 1.7915 | 15000 | 17.915 | 7675 | 2.5875 | 17150 | 17650 | 0 | 1 | 1.0325 | 17.915 | 8550 | 8475 | 8475 | 25.875 | 25.875 | 6FL
6FLW14 | 6FL | W14 | 6FLW14 | 事務室 | 313 | yes | 6FL | 6 | リンクなし | リンクなし | リンクなし | 8475 | 2650 | 0.7675 | 17.915 | 1.7915 | 15000 | 17.915 | 7675 | 2.5875 | 17150 | 17650 | 0 | 1 | 1.0325 | 17.915 | 8550 | 8475 | 8475 | 25.875 | 25.875 | 6FL
6FLW13 | 6FL | W13 | 6FLW13 | 事務室 | 313 | yes | 6FL | 6 | リンクなし | リンクなし | リンクなし | 8475 | 2650 | 0.7675 | 17.915 | 1.7915 | 15000 | 17.915 | 7675 | 2.6175 | 17150 | 17650 | 0 | 1 | 1.0325 | 17.915 | 8550 | 8475 | 8475 | 26.175 | 26.175 | 6FL
6FLW13 | 6FL | W13 | 6FLW13 | 事務室 | 302 | yes | 6FL | 6 | リンクなし | リンクなし | リンクなし | 10974.7 | 3000 | 0.952466 | 22.4303 | 2.24295 | 15000 | 22.4287 | 9524.66 | 3.3674 | 22149.3 | 18000 | 0 | 2 | 1.2352 | 22.4319 | 11049.7 | 10974.7 | 10974.7 | 33.674 | 33.674 | 6FL
6FLW12 | 6FL | W12 | 6FLW12 | 事務室 | 305 | yes | 6FL | 6 | リンクなし | リンクなし | リンクなし | 10050 | 2650 | 0.86 | 20.27 | 2.027 | 15000 | 20.27 | 8600 | 3.06 | 20300 | 17650 | 0 | 2 | 1.125 | 20.27 | 10125 | 10050 | 10050 | 30.6 | 30.6 | 6FL
6FLW11 | 6FL | W11 | 6FLW11 | 事務室 | 304 | yes | 6FL | 6 | リンクなし | リンクなし | リンクなし | 10050 | 2650 | 0.86 | 20.27 | 2.027 | 15000 | 20.27 | 8600 | 3.06 | 20300 | 17650 | 0 | 2 | 1.125 | 20.27 | 10125 | 10050 | 10050 | 30.6 | 30.6 | 6FL
6FLW14 | 6FL | W14 | 6FLW14 | 事務室 | 301 | yes | 6FL | 6 | リンクなし | リンクなし | リンクなし | 11899.3 | 3000 | 1.04493 | 24.589 | 2.45882 | 15000 | 24.5874 | 10449.3 | 3.61479 | 23998.6 | 18000 | 0 | 2 | 1.32766 | 24.5906 | 11974.3 | 11899.3 | 11899.3 | 36.1479 | 36.1479 | 6FL
6FLW13 | 6FL | W13 | 6FLW13 | 事務室 | 310 | yes | 6FL | 6 | リンクなし | リンクなし | リンクなし | 6575 | 2300 | 0.5925 | 13.6275 | 1.36275 | 15000 | 13.6275 | 5925 | 2.0925 | 13350 | 17300 | 0 | 1 | 0.5925 | 13.6275 | 6725 | 6575 | 6575 | 20.925 | 20.925 | 6FL
6FLW10 | 6FL | W10 | 6FLW10 | 事務室 | 303 | yes | 6FL | 6 | リンクなし | リンクなし | リンクなし | 10050 | 2650 | 0.86 | 20.27 | 2.027 | 15000 | 20.27 | 8600 | 3.06 | 20300 | 17650 | 0 | 2 | 1.125 | 20.27 | 10125 | 10050 | 10050 | 30.6 | 30.6 | 6FL
6FLW12 | 6FL | W12 | 6FLW12 | 事務室 | 306 | yes | 6FL | 6 | リンクなし | リンクなし | リンクなし | 8983.01 | 3000 | 0.753301 | 17.9723 | 1.79703 | 15000 | 17.9675 | 7533.01 | 2.7399 | 18166 | 18000 | 0 | 2 | 1.03982 | 17.977 | 9058.01 | 8983.01 | 8983.01 | 27.399 | 27.399 | 6FL
7FLW12 | 7FL | W12 | 7FLW12 | 事務室 | 308 | yes | 7FL | 7 | リンクなし | リンクなし | リンクなし | 6475 | 2300 | 0.5925 | 13.6275 | 1.36275 | 18000 | 13.6275 | 5925 | 2.0625 | 13150 | 20300 | 0 | 1 | 0.5925 | 13.6275 | 6675 | 6475 | 6475 | 20.625 | 20.625 | 7FL
7FLW14 | 7FL | W14 | 7FLW14 | 事務室 | 315 | yes | 7FL | 7 | リンクなし | リンクなし | リンクなし | 8475 | 2650 | 0.7675 | 17.915 | 1.7915 | 18000 | 17.915 | 7675 | 2.5875 | 17150 | 20650 | 0 | 1 | 1.0325 | 17.915 | 8550 | 8475 | 8475 | 25.875 | 25.875 | 7FL
7FLW15 | 7FL | W15 | 7FLW15 | 事務室 | 314 | yes | 7FL | 7 | リンクなし | リンクなし | リンクなし | 8475 | 2650 | 0.7675 | 17.915 | 1.7915 | 18000 | 17.915 | 7675 | 2.5875 | 17150 | 20650 | 0 | 1 | 1.0325 | 17.915 | 8550 | 8475 | 8475 | 25.875 | 25.875 | 7FL
7FLW14 | 7FL | W14 | 7FLW14 | 事務室 | 313 | yes | 7FL | 7 | リンクなし | リンクなし | リンクなし | 8475 | 2650 | 0.7675 | 17.915 | 1.7915 | 18000 | 17.915 | 7675 | 2.5875 | 17150 | 20650 | 0 | 1 | 1.0325 | 17.915 | 8550 | 8475 | 8475 | 25.875 | 25.875 | 7FL
7FLW13 | 7FL | W13 | 7FLW13 | 事務室 | 313 | yes | 7FL | 7 | リンクなし | リンクなし | リンクなし | 8475 | 2650 | 0.7675 | 17.915 | 1.7915 | 18000 | 17.915 | 7675 | 2.6175 | 17150 | 20650 | 0 | 1 | 1.0325 | 17.915 | 8550 | 8475 | 8475 | 26.175 | 26.175 | 7FL
7FLW13 | 7FL | W13 | 7FLW13 | 事務室 | 302 | yes | 7FL | 7 | リンクなし | リンクなし | リンクなし | 10974.7 | 3000 | 0.952466 | 22.4303 | 2.24295 | 18000 | 22.4287 | 9524.66 | 3.3674 | 22149.3 | 21000 | 0 | 2 | 1.2352 | 22.4319 | 11049.7 | 10974.7 | 10974.7 | 33.674 | 33.674 | 7FL
7FLW12 | 7FL | W12 | 7FLW12 | 事務室 | 305 | yes | 7FL | 7 | リンクなし | リンクなし | リンクなし | 10050 | 2650 | 0.86 | 20.27 | 2.027 | 18000 | 20.27 | 8600 | 3.06 | 20300 | 20650 | 0 | 2 | 1.125 | 20.27 | 10125 | 10050 | 10050 | 30.6 | 30.6 | 7FL
7FLW11 | 7FL | W11 | 7FLW11 | 事務室 | 304 | yes | 7FL | 7 | リンクなし | リンクなし | リンクなし | 10050 | 2650 | 0.86 | 20.27 | 2.027 | 18000 | 20.27 | 8600 | 3.06 | 20300 | 20650 | 0 | 2 | 1.125 | 20.27 | 10125 | 10050 | 10050 | 30.6 | 30.6 | 7FL
7FLW14 | 7FL | W14 | 7FLW14 | 事務室 | 301 | yes | 7FL | 7 | リンクなし | リンクなし | リンクなし | 11899.3 | 3000 | 1.04493 | 24.589 | 2.45882 | 18000 | 24.5874 | 10449.3 | 3.61479 | 23998.6 | 21000 | 0 | 2 | 1.32766 | 24.5906 | 11974.3 | 11899.3 | 11899.3 | 36.1479 | 36.1479 | 7FL
7FLW13 | 7FL | W13 | 7FLW13 | 事務室 | 310 | yes | 7FL | 7 | リンクなし | リンクなし | リンクなし | 6575 | 2300 | 0.5925 | 13.6275 | 1.36275 | 18000 | 13.6275 | 5925 | 2.0925 | 13350 | 20300 | 0 | 1 | 0.5925 | 13.6275 | 6725 | 6575 | 6575 | 20.925 | 20.925 | 7FL
7FLW10 | 7FL | W10 | 7FLW10 | 事務室 | 303 | yes | 7FL | 7 | リンクなし | リンクなし | リンクなし | 10050 | 2650 | 0.86 | 20.27 | 2.027 | 18000 | 20.27 | 8600 | 3.06 | 20300 | 20650 | 0 | 2 | 1.125 | 20.27 | 10125 | 10050 | 10050 | 30.6 | 30.6 | 7FL
7FLW12 | 7FL | W12 | 7FLW12 | 事務室 | 306 | yes | 7FL | 7 | リンクなし | リンクなし | リンクなし | 8983.01 | 3000 | 0.753301 | 17.9723 | 1.79703 | 18000 | 17.9675 | 7533.01 | 2.7399 | 18166 | 21000 | 0 | 2 | 1.03982 | 17.977 | 9058.01 | 8983.01 | 8983.01 | 27.399 | 27.399 | 7FL
8FLW12 | 8FL | W12 | 8FLW12 | 事務室 | 308 | yes | 8FL | 8 | リンクなし | リンクなし | リンクなし | 6475 | 2300 | 0.5925 | 13.6275 | 1.36275 | 21000 | 13.6275 | 5925 | 2.0625 | 13150 | 23300 | 0 | 1 | 0.5925 | 13.6275 | 6675 | 6475 | 6475 | 20.625 | 20.625 | 8FL
8FLW14 | 8FL | W14 | 8FLW14 | 事務室 | 315 | yes | 8FL | 8 | リンクなし | リンクなし | リンクなし | 8475 | 2650 | 0.7675 | 17.915 | 1.7915 | 21000 | 17.915 | 7675 | 2.5875 | 17150 | 23650 | 0 | 1 | 1.0325 | 17.915 | 8550 | 8475 | 8475 | 25.875 | 25.875 | 8FL
8FLW15 | 8FL | W15 | 8FLW15 | 事務室 | 314 | yes | 8FL | 8 | リンクなし | リンクなし | リンクなし | 8475 | 2650 | 0.7675 | 17.915 | 1.7915 | 21000 | 17.915 | 7675 | 2.5875 | 17150 | 23650 | 0 | 1 | 1.0325 | 17.915 | 8550 | 8475 | 8475 | 25.875 | 25.875 | 8FL
8FLW14 | 8FL | W14 | 8FLW14 | 事務室 | 313 | yes | 8FL | 8 | リンクなし | リンクなし | リンクなし | 8475 | 2650 | 0.7675 | 17.915 | 1.7915 | 21000 | 17.915 | 7675 | 2.5875 | 17150 | 23650 | 0 | 1 | 1.0325 | 17.915 | 8550 | 8475 | 8475 | 25.875 | 25.875 | 8FL
8FLW13 | 8FL | W13 | 8FLW13 | 事務室 | 313 | yes | 8FL | 8 | リンクなし | リンクなし | リンクなし | 8475 | 2650 | 0.7675 | 17.915 | 1.7915 | 21000 | 17.915 | 7675 | 2.6175 | 17150 | 23650 | 0 | 1 | 1.0325 | 17.915 | 8550 | 8475 | 8475 | 26.175 | 26.175 | 8FL
8FLW13 | 8FL | W13 | 8FLW13 | 事務室 | 302 | yes | 8FL | 8 | リンクなし | リンクなし | リンクなし | 10974.7 | 3000 | 0.952466 | 22.4303 | 2.24295 | 21000 | 22.4287 | 9524.66 | 3.3674 | 22149.3 | 24000 | 0 | 2 | 1.2352 | 22.4319 | 11049.7 | 10974.7 | 10974.7 | 33.674 | 33.674 | 8FL
8FLW12 | 8FL | W12 | 8FLW12 | 事務室 | 305 | yes | 8FL | 8 | リンクなし | リンクなし | リンクなし | 10050 | 2650 | 0.86 | 20.27 | 2.027 | 21000 | 20.27 | 8600 | 3.06 | 20300 | 23650 | 0 | 2 | 1.125 | 20.27 | 10125 | 10050 | 10050 | 30.6 | 30.6 | 8FL
8FLW11 | 8FL | W11 | 8FLW11 | 事務室 | 304 | yes | 8FL | 8 | リンクなし | リンクなし | リンクなし | 10050 | 2650 | 0.86 | 20.27 | 2.027 | 21000 | 20.27 | 8600 | 3.06 | 20300 | 23650 | 0 | 2 | 1.125 | 20.27 | 10125 | 10050 | 10050 | 30.6 | 30.6 | 8FL
8FLW14 | 8FL | W14 | 8FLW14 | 事務室 | 301 | yes | 8FL | 8 | リンクなし | リンクなし | リンクなし | 11899.3 | 3000 | 1.04493 | 24.589 | 2.45882 | 21000 | 24.5874 | 10449.3 | 3.61479 | 23998.6 | 24000 | 0 | 2 | 1.32766 | 24.5906 | 11974.3 | 11899.3 | 11899.3 | 36.1479 | 36.1479 | 8FL
8FLW13 | 8FL | W13 | 8FLW13 | 事務室 | 310 | yes | 8FL | 8 | リンクなし | リンクなし | リンクなし | 6575 | 2300 | 0.5925 | 13.6275 | 1.36275 | 21000 | 13.6275 | 5925 | 2.0925 | 13350 | 23300 | 0 | 1 | 0.5925 | 13.6275 | 6725 | 6575 | 6575 | 20.925 | 20.925 | 8FL
8FLW10 | 8FL | W10 | 8FLW10 | 事務室 | 303 | yes | 8FL | 8 | リンクなし | リンクなし | リンクなし | 10050 | 2650 | 0.86 | 20.27 | 2.027 | 21000 | 20.27 | 8600 | 3.06 | 20300 | 23650 | 0 | 2 | 1.125 | 20.27 | 10125 | 10050 | 10050 | 30.6 | 30.6 | 8FL
8FLW12 | 8FL | W12 | 8FLW12 | 事務室 | 306 | yes | 8FL | 8 | リンクなし | リンクなし | リンクなし | 8983.01 | 3000 | 0.753301 | 17.9723 | 1.79703 | 21000 | 17.9675 | 7533.01 | 2.7399 | 18166 | 24000 | 0 | 2 | 1.03982 | 17.977 | 9058.01 | 8983.01 | 8983.01 | 27.399 | 27.399 | 8FL
9FLW12 | 9FL | W12 | 9FLW12 | 事務室 | 308 | yes | 9FL | 9 | リンクなし | リンクなし | リンクなし | 6475 | 2300 | 0.5925 | 13.6275 | 1.36275 | 24000 | 13.6275 | 5925 | 2.0625 | 13150 | 26300 | 0 | 1 | 0.5925 | 13.6275 | 6675 | 6475 | 6475 | 20.625 | 20.625 | 9FL
9FLW14 | 9FL | W14 | 9FLW14 | 事務室 | 315 | yes | 9FL | 9 | リンクなし | リンクなし | リンクなし | 8475 | 2650 | 0.7675 | 17.915 | 1.7915 | 24000 | 17.915 | 7675 | 2.5875 | 17150 | 26650 | 0 | 1 | 1.0325 | 17.915 | 8550 | 8475 | 8475 | 25.875 | 25.875 | 9FL
9FLW15 | 9FL | W15 | 9FLW15 | 事務室 | 314 | yes | 9FL | 9 | リンクなし | リンクなし | リンクなし | 8475 | 2650 | 0.7675 | 17.915 | 1.7915 | 24000 | 17.915 | 7675 | 2.5875 | 17150 | 26650 | 0 | 1 | 1.0325 | 17.915 | 8550 | 8475 | 8475 | 25.875 | 25.875 | 9FL
9FLW14 | 9FL | W14 | 9FLW14 | 事務室 | 313 | yes | 9FL | 9 | リンクなし | リンクなし | リンクなし | 8475 | 2650 | 0.7675 | 17.915 | 1.7915 | 24000 | 17.915 | 7675 | 2.5875 | 17150 | 26650 | 0 | 1 | 1.0325 | 17.915 | 8550 | 8475 | 8475 | 25.875 | 25.875 | 9FL
9FLW13 | 9FL | W13 | 9FLW13 | 事務室 | 313 | yes | 9FL | 9 | リンクなし | リンクなし | リンクなし | 8475 | 2650 | 0.7675 | 17.915 | 1.7915 | 24000 | 17.915 | 7675 | 2.6175 | 17150 | 26650 | 0 | 1 | 1.0325 | 17.915 | 8550 | 8475 | 8475 | 26.175 | 26.175 | 9FL
9FLW13 | 9FL | W13 | 9FLW13 | 事務室 | 302 | yes | 9FL | 9 | リンクなし | リンクなし | リンクなし | 10974.7 | 3000 | 0.952466 | 22.4303 | 2.24295 | 24000 | 22.4287 | 9524.66 | 3.3674 | 22149.3 | 27000 | 0 | 2 | 1.2352 | 22.4319 | 11049.7 | 10974.7 | 10974.7 | 33.674 | 33.674 | 9FL
9FLW12 | 9FL | W12 | 9FLW12 | 事務室 | 305 | yes | 9FL | 9 | リンクなし | リンクなし | リンクなし | 10050 | 2650 | 0.86 | 20.27 | 2.027 | 24000 | 20.27 | 8600 | 3.06 | 20300 | 26650 | 0 | 2 | 1.125 | 20.27 | 10125 | 10050 | 10050 | 30.6 | 30.6 | 9FL
9FLW11 | 9FL | W11 | 9FLW11 | 事務室 | 304 | yes | 9FL | 9 | リンクなし | リンクなし | リンクなし | 10050 | 2650 | 0.86 | 20.27 | 2.027 | 24000 | 20.27 | 8600 | 3.06 | 20300 | 26650 | 0 | 2 | 1.125 | 20.27 | 10125 | 10050 | 10050 | 30.6 | 30.6 | 9FL
9FLW14 | 9FL | W14 | 9FLW14 | 事務室 | 301 | yes | 9FL | 9 | リンクなし | リンクなし | リンクなし | 11899.3 | 3000 | 1.04493 | 24.589 | 2.45882 | 24000 | 24.5874 | 10449.3 | 3.61479 | 23998.6 | 27000 | 0 | 2 | 1.32766 | 24.5906 | 11974.3 | 11899.3 | 11899.3 | 36.1479 | 36.1479 | 9FL
9FLW13 | 9FL | W13 | 9FLW13 | 事務室 | 310 | yes | 9FL | 9 | リンクなし | リンクなし | リンクなし | 6575 | 2300 | 0.5925 | 13.6275 | 1.36275 | 24000 | 13.6275 | 5925 | 2.0925 | 13350 | 26300 | 0 | 1 | 0.5925 | 13.6275 | 6725 | 6575 | 6575 | 20.925 | 20.925 | 9FL
9FLW10 | 9FL | W10 | 9FLW10 | 事務室 | 303 | yes | 9FL | 9 | リンクなし | リンクなし | リンクなし | 10050 | 2650 | 0.86 | 20.27 | 2.027 | 24000 | 20.27 | 8600 | 3.06 | 20300 | 26650 | 0 | 2 | 1.125 | 20.27 | 10125 | 10050 | 10050 | 30.6 | 30.6 | 9FL
9FLW12 | 9FL | W12 | 9FLW12 | 事務室 | 306 | yes | 9FL | 9 | リンクなし | リンクなし | リンクなし | 8983.01 | 3000 | 0.753301 | 17.9723 | 1.79703 | 24000 | 17.9675 | 7533.01 | 2.7399 | 18166 | 27000 | 0 | 2 | 1.03982 | 17.977 | 9058.01 | 8983.01 | 8983.01 | 27.399 | 27.399 | 9FL

# IfcWindow: 連装窓1, AW1
In: 2FL
Type - ParameterTakesPrecedence: no; Sizeable: no
OverallHeight: 2550 mm; OverallWidth: 3660 mm; Classification: 窓 (ARCHICAD 分類)
ArchiCADProperties - 要素ID: AW1; ホットリンクおよび要素ID: AW1; レイヤー: 壁-躯体; ライブラリ部品名: 連装窓1; ビルディングマテリアル/複合構造/断面形状/塗りつぶし: 背景; 塗りつぶし種類: 背景; 関連ゾーン名: 吹き抜け; 関連ゾーン番号: ＜ゾーン番号＞; ロック状態: no; ホームフロア名: 2FL; ホームフロア数: 2; 要素タイプ: 窓; 親ID: W6; 材質 (全て): ガラス - シンプル; 金属 - アルミニウム; ゾーンから: 吹き抜け; ゾーン番号から: ＜ゾーン番号＞; リノベーションフィルタで表示: 全ての関連フィルタ; 構造機能: 非構造耐力要素; 位置: エクステリア; リノベーションステータス: 既存; 抱き寸法: 3,540.0×2,400.0; 壁開口寸法: 3,660.0×2,550.0; ユニット寸法: 3,540.0×2,400.0; 間口寸法: 3,540.0×2,400.0; 扉寸法: 3,540.0×2,400.0; 公称幅x高さ: 3,540.0×2,400.0; 公称幅x高さx厚さ: 3,540.0×2,400.0×150.0; 壁構造: コンクリート; 方向: 右; 開口部 ライブラリ部品名: 連装窓1; 開口部 側面塗りつぶし索引: 背景; ARCHICAD 分類 - v 2.0: 窓
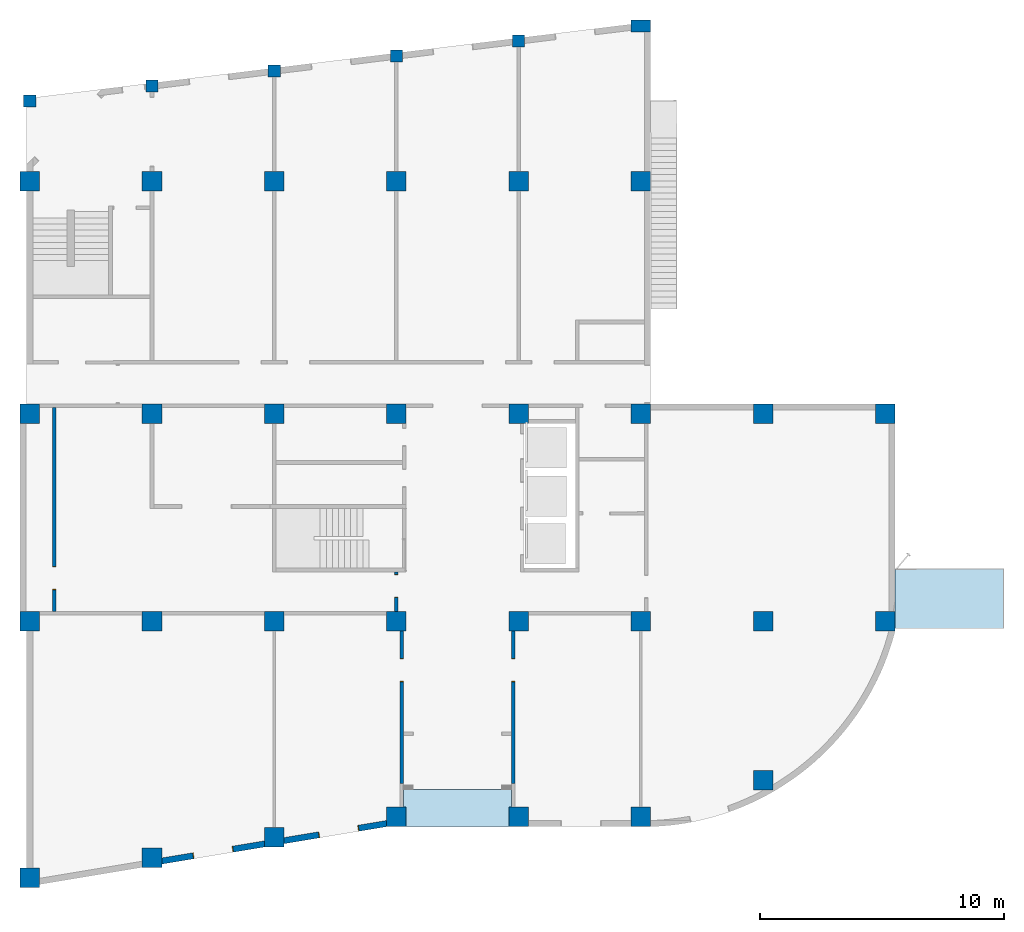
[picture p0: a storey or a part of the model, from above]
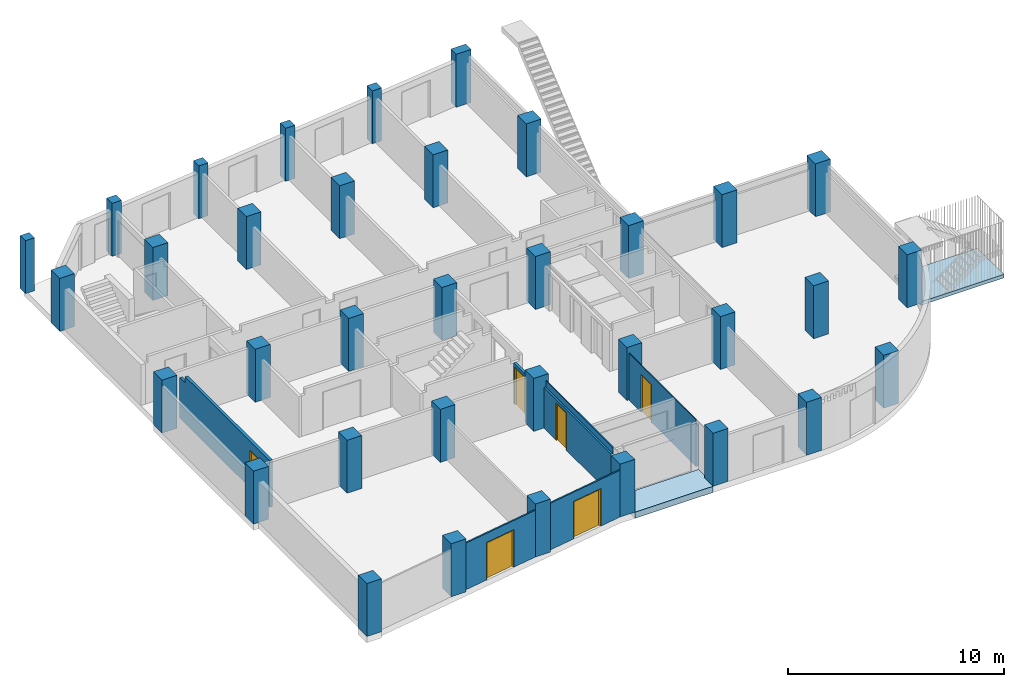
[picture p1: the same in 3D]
Properties of the parts of a building model (IFC2X3), part 10 of 10

# IfcWindow: 連装窓1, AW1
AC_Pset_連装窓1 - 壁輪郭(0-なし,1-全て,2-側面,3-長さ): 0; ホットスポット(0-なし,1-2D,2-3D,3-全て): 3; 2Dホットスポットを3Dで表示: yes; 開口部は壁側面の材質: no; 開口の側面を曲線壁に沿う: no; 抱き配置位置: 1; 枠材質 (gs_frame_mat): 木材 - マツ 木目 縦; サッシ材質: 木材 - マツ 木目 横; ガラス材質 (gs_glass_mat): ガラス - シンプル; 内寸を公称サイズに設定: yes; 壁開口を公称サイズに設定: no; 現在の公称サイズを選択に切り替え: no; IFC操作 (ifc_optypestr): 未定義; IFC操作 (ifc_optype): 0; 詳細レベル: 1; 詳細: 1; 詳細表現スケールn (1/1 - 1/n): 50; 中間表現スケールm （1/n～1/m): 100; 2D 表示 (iViewtype_2D): 1; 断面表示: 1; 2D建具背面の無地塗つぶし: no; 額縁表現: 2; 2D額縁塗りつぶし: 木材1; 建具種類: AW; 建具番号: 28; 法規制: 未定; 内外区分: 外; 形式: 連装コーナー窓; 建具識別コード（0=窓,1=ドア,2=シャッター,3=エレベーター): 0; 壁ID: W6; 接続されたゾーンを値として使用: no; キープラン表示: yes; マーカータイプをスケールに連動: yes; マーカータイプ: タイプ1; 枝番(0=なし): 0; 建具サイズ表示: no; 建具符号方向: 任意角度; 建具符号任意角度: 0 deg; 用紙スケール: no; マーカーサイズ (用紙) (k_dia_paper): 4.2; マーカーサイズ (用紙) (k_dia_M): 0.0042; 引出し線: no; ID表示: no; 離れX (用紙) (k_lenb_paper): 0; 離れX (用紙) (k_lenb_M): 0; 離れY (用紙) (k_lena_paper): 10; 離れY (用紙) (k_lena_M): 0.01; 離れオフセット (用紙) (k_lenc_paper): 0; 離れオフセット (用紙) (k_lenc_M): 0; 引き出し線角度: 0 deg; 線種: 1; 建具記号で塗りつぶしを使用: no; 建具記号塗りつぶし種類: 背景; フォント: Meiryo UI 日本語; 字サイズユーザー設定: no; 字サイズ: 1.4; 追記文字サイズ (mm): 1.43; 建具文字サイズ (mm): 1.43; 建具番号-枝番: 28; 追記位置X1 (用紙) (n_offx1_paper): -5.5; 追記位置X1 (用紙) (n_offx1_M): -0.0055; 追記位置Y1 (用紙) (n_offy1_paper): 2.5; 追記位置Y1 (用紙) (n_offy1_M): 0.0025; 追記位置X2 (用紙) (n_offx2_paper): -5.5; 追記位置X2 (用紙) (n_offx2_M): -0.0055; 追記位置Y2 (用紙) (n_offy2_paper): -2.5; 追記位置Y2 (用紙) (n_offy2_M): -0.0025; 追記位置X3 (用紙) (n_offx3_paper): 5.5; 追記位置X3 (用紙) (n_offx3_M): 0.0055; 追記位置Y3 (用紙) (n_offy3_paper): 2.5; 追記位置Y3 (用紙) (n_offy3_M): 0.0025; 追記位置X4 (用紙) (n_offx4_paper): 5.5; 追記位置X4 (用紙) (n_offx4_M): 0.0055; 追記位置Y4 (用紙) (n_offy4_paper): -2.5; 追記位置Y4 (用紙) (n_offy4_M): -0.0025; サイズ表示位置X (用紙) (size_anno_x_paper): 5; サイズ表示位置X (用紙) (size_anno_x_M): 0.005; サイズ表示位置Y (用紙) (size_anno_y_paper): 0; サイズ表示位置Y (用紙) (size_anno_y_M): 0; 法規制マーカー: yes; マーカーサイズ (用紙) (r_dia_paper): 2; マーカーサイズ (用紙) (r_dia_M): 0.002; マーカー塗りつぶしあり/なし: no; マーカー塗りつぶし背景ペン: 透過; マーカー塗りつぶし: 25 %; 建具下端レベルは壁を基準とする: no; 建具表平面表示: no; 離れX (用紙) (r_lenb_paper): 0; 離れX (用紙) (r_lenb_M): 0; 離れY (用紙) (r_lena_paper): -5; 離れY (用紙) (r_lena_M): -0.005; 抱き形状: 1; 建具断面形状 (ui_shape2D): 1; 建具断面形状 (ui_shapeSE): 1; 下枠非表示オプション: 2; 水切り有無: no; 連続個数: 1; 横分割数: 0; 縦分割数: 0; 壁断面形状: 1; 傾斜壁角度１: 90 deg; 傾斜壁角度２: 90 deg; 壁上部抱きを使用: no; MO API 窓コード: 40; 連装数: 4; 方立共通設定を使用: yes; 方立位置: 中段; 左: 16; 横分割 左: 0; 縦分割 左: 0; 中左: 16; 横分割 中-左: 0; 縦分割 中-左: 0; 中左 連続数: 0; 中段: 16; 横分割 中-中: 0; 縦分割 中-中: 0; 中 連続数: 0; 中右: 16; 横分割 中-右: 0; 縦分割 中-右: 0; 中右 連続数: 0; 右: 16; 横分割 右: 0; 縦分割 右: 0; 3D開口線: no; 3D開口テキスト: no; 平面図開口線: no; 平面図開口線種: 28; 平面図中心線: no; 曲線壁の開口部でホットスポットを表示: no; 枠材質 (matframe): 金属 - アルミニウム; 下枠材質: 金属 - アルミニウム; 天板材質: ペイント - サンドベージュ; ガラス材質 (matglass): ガラス - シンプル; ルーバー材質: 金属 - アルミニウム; 出力対象: 2; 強さ: 未定; 気密: 未定; 水密: 未定; 遮音: 未定; 枠 材質: 未定; 枠 仕上: 未定; 水切り 材質: 未定; 水切り 仕上: 未定; 膳板・額縁 材質: 未定; 膳板・額縁 仕上: 未定; ガラス 種類: 未定; ガラス 厚: 未定; ガラス 押え: 未定; 網戸 形式: 未定; 網種類: 未定; ガラリ 機構: 未定; ガラリ 材質: 未定; ガラリ 仕上: 未定; 付属金物: 未定; 手動開放装置: 未定; 価格: 0; 2Dシンボル表示のMVOを上書き: no; ドア3D投影のMVOを上書き: no; 平面図中心線種: 1; 3Dガラスシンボル 側面: 3; 3D開口線 側面: 3; 延長する内側層の数: 0; 延長する外側層の数: 0; 外側層の延長: no; 内側層の延長: no; 延長線種: 1; ガラスタイプ 左 (w_l_glass_type): 未定; ガラス左幅: 未定; ガラスタイプ 中-左: 未定; ガラス 中-左幅: 未定; ガラスタイプ 中-右: 未定; ガラス 中-右幅: 未定; ガラス 右幅: 未定; ガラスタイプ 左 (w_r_glass_type): 未定; 抱き形状変化確認用: 1; 並べ替え用通し番号: 0
採光計算 - 窓から隣地境界線までの距離: 4; 窓の中心高さ: 4.25 mm
排煙・換気計算 - 天井面の高さ: 0; 有効開口幅: 0; 開き角度: 0; 天井面より80cm以内の距離: 0.8; 窓の上端高さから天井面までの距離: -2.45; 排煙有効開口面積(引違い・片引き等): 0; 有効排煙開口率: 0; 排煙有効開口面積(横軸・外倒し・内倒し等): 0
AC_Pset_RenovationAndPhasing - Renovation Status: Existing
Pset_WindowCommon - IsExternal: yes
BaseQuantities - GrossArea: 8.856 m2; Height: 2460 mm; Width: 3600 mm; Perimeter: 12120 mm; Area: 8.856 m2; Volume: 0.08928 m3; Depth: 150 mm; NetVolume: 0.08928 m3
ArchiCADQuantities - 高さ: 2400 mm; 正味体積: 0.08928 m3; 幅: 3540 mm; GLからの高度: 3050 mm; 高度 1: 3050 mm; 高度 2: 3050 mm; 海抜までの高度: 3050 mm; リンク/配置フロアまでの高度: 50 mm; 下部オフセット: 50 mm; 表面積: 14.3574 m2; 上端高度から第1基準レベル: 5480 mm; 上端高度から配置フロア: 2480 mm; 上端高度から基準レベル: 5480 mm; 上端高度から海抜: 5480 mm; 上端高度から第2基準レベル: 5480 mm; 下端高度から第1基準レベル: 3020 mm; 下端高度から配置フロア: 20 mm; 下端高度から基準レベル: 3020 mm; 下端高度から海抜: 3020 mm; 下端高度から第2基準レベル: 3020 mm; 窓/ドア開口 開口部体積: 1.3284 m3; 窓/ドア開口部公称体積: 1.2744 m3; 窓/ドア開口 表面積: 14.3574 m2; 窓/ドア開口面積: 8.496 m2; 窓/ドア外壁側開口部幅: 3600 mm; 窓/ドア外壁側開口部高さ: 2460 mm; 窓/ドア外壁反対側開口部幅: 3600 mm; 窓/ドア外壁反対側開口部高さ: 2460 mm; 窓/ドア外壁側開口部面積: 8.856 m2; 窓/ドア外壁反対側開口部面積: 8.856 m2; 窓/ドア外壁側公称開口部幅: 3540 mm; 窓/ドア外壁側公称開口部高さ: 2400 mm; 窓/ドア外壁反対側公称開口部幅: 3540 mm; 窓/ドア外壁反対側公称開口部高さ: 2400 mm; 窓/ドア抱き側開口面積: 8.496 m2; 窓/ドア抱き反対側開口面積: 8.496 m2; 下端/上端値: 50 mm; 窓/ドア公称下端高さ: 50 mm; 窓/ドア外壁側下端高さ: 50 mm; 窓/ドア外壁反対側下端高さ: 50 mm; 窓/ドア公称上端高さ: 2450 mm; 窓/ドア外壁側上端高さ: 2450 mm; 窓/ドア外壁反対側上端高さ: 2450 mm; 壁厚さ: 150 mm; 枠厚さ: 50 mm
AC_Equantity_連装窓1 - 下部レベル: 1000 mm; 上部レベル: 0 mm; 壁躯体に抱き: 45 mm; 枠見込 (gs_frame_thk): 50 mm; 枠見付 (gs_frame_width): 70 mm; サッシ フレームの厚さ: 50 mm; サッシ枠見付 (gs_sash_width): 50 mm; ガラス 厚: 20 mm; AC左開口部拡張サイズ: 0 mm; AC右開口部拡張サイズ: 0 mm; AC上開口部拡張サイズ: 0 mm; AC下開口部拡張サイズ: 0 mm; 壁開口幅: 3660 mm; 壁開口高さ: 2550 mm; 抱き幅: 3540 mm; 抱き高さ: 2400 mm; ユニット幅: 3540 mm; ユニット高さ: 2400 mm; 開口幅 (gs_opening_width): 3540 mm; 開口高さ (gs_opening_height): 2400 mm; 開口幅 (ac_egress_width): 3540 mm; 開口高さ (ac_egress_height): 2400 mm; パネル幅: 3540 mm; パネル高さ: 2400 mm; マーカーサイズ (k_dia): 420 mm; 離れX (k_lenb): 0 mm; 離れY (k_lena): 1000 mm; 離れオフセット: 0 mm; 追記位置X1: -550 mm; 追記位置Y1: 250 mm; 追記位置X2: -550 mm; 追記位置Y2: -250 mm; 追記位置X3: 550 mm; 追記位置Y3: 250 mm; 追記位置X4: 550 mm; 追記位置Y4: -250 mm; サイズ表示位置X: 500 mm; サイズ表示位置Y: 0 mm; マーカーサイズ (r_dia): 200 mm; 床とFLのレベル差: 0 mm; 壁下端レベル: 0 mm; 離れX (r_lenb): 0 mm; 離れY (r_lena): -500 mm; フロアレベルから建具下端までの高さ: 50 mm; 抱き見込: 45 mm; 欠込寸法: 45 mm; 横シール幅: 20 mm; 欠込寸法（上）: 45 mm; 上端シール幅: 20 mm; 下枠逃げ寸法: 90 mm; 欠込寸法 F: 95 mm; 下端シール幅: 30 mm; 下部躯体勾配高さ: 20 mm; サッシ枠見付 (p1): 15 mm; 枠見付（中間表示）: 30 mm; 枠見込 (p2_w): 70 mm; サッシ枠見付 (shw): 40 mm; 枠見込 (p3): -120 mm; 枠見付 (p4): 25 mm; 膳板 見付(0=なし): 25 mm; 枠と額縁のレベル差: 15 mm; 枠と額縁のレベル差 下: 0 mm; 水切り働き幅: 75 mm; 外壁側額縁見付: 30 mm; ちり１: 15 mm; ちり２: 10 mm; 転び: 5 mm; 抱き仕上厚: 30 mm; 膳板出幅（横）: 0 mm; 膳板出幅（前）: 0 mm; 内壁までの距離: 0 mm; 外壁までの距離: 0 mm; 左幅: 832.5 mm; 中-左幅: 832.5 mm; 中幅: 832.5 mm; 中-右幅: 0 mm; 右幅: 832.5 mm; 方立見付-共通: 70 mm; 方立見込-共通: 70 mm; 左-中左 方立見付: 70 mm; 左-中左 方立見込: 70 mm; 中 左-中 方立見付: 70 mm; 中左-中 方立見込: 70 mm; 中 中-右 方立見付: 0 mm; 中-中右 方立見込: 0 mm; 中右-右 方立見付: 70 mm; 中右-右 方立見込: 70 mm; 左 (turn_width_l): 250 mm; 中左 (turn_width_cl): 250 mm; 中段 (turn_width_cc): 250 mm; 中右 (turn_width_cr): 250 mm; 右 (turn_width_r): 250 mm; 左 (open_width_l): 250 mm; 中左 (open_width_cl): 250 mm; 中段 (open_width_cc): 250 mm; 中右 (open_width_cr): 250 mm; 右 (open_width_r): 250 mm; 外側仕上げ厚: 0 mm; 内側仕上げ厚: 0 mm; 内部１層目仕上げ厚: 0 mm; 中心からの距離: 100 mm
